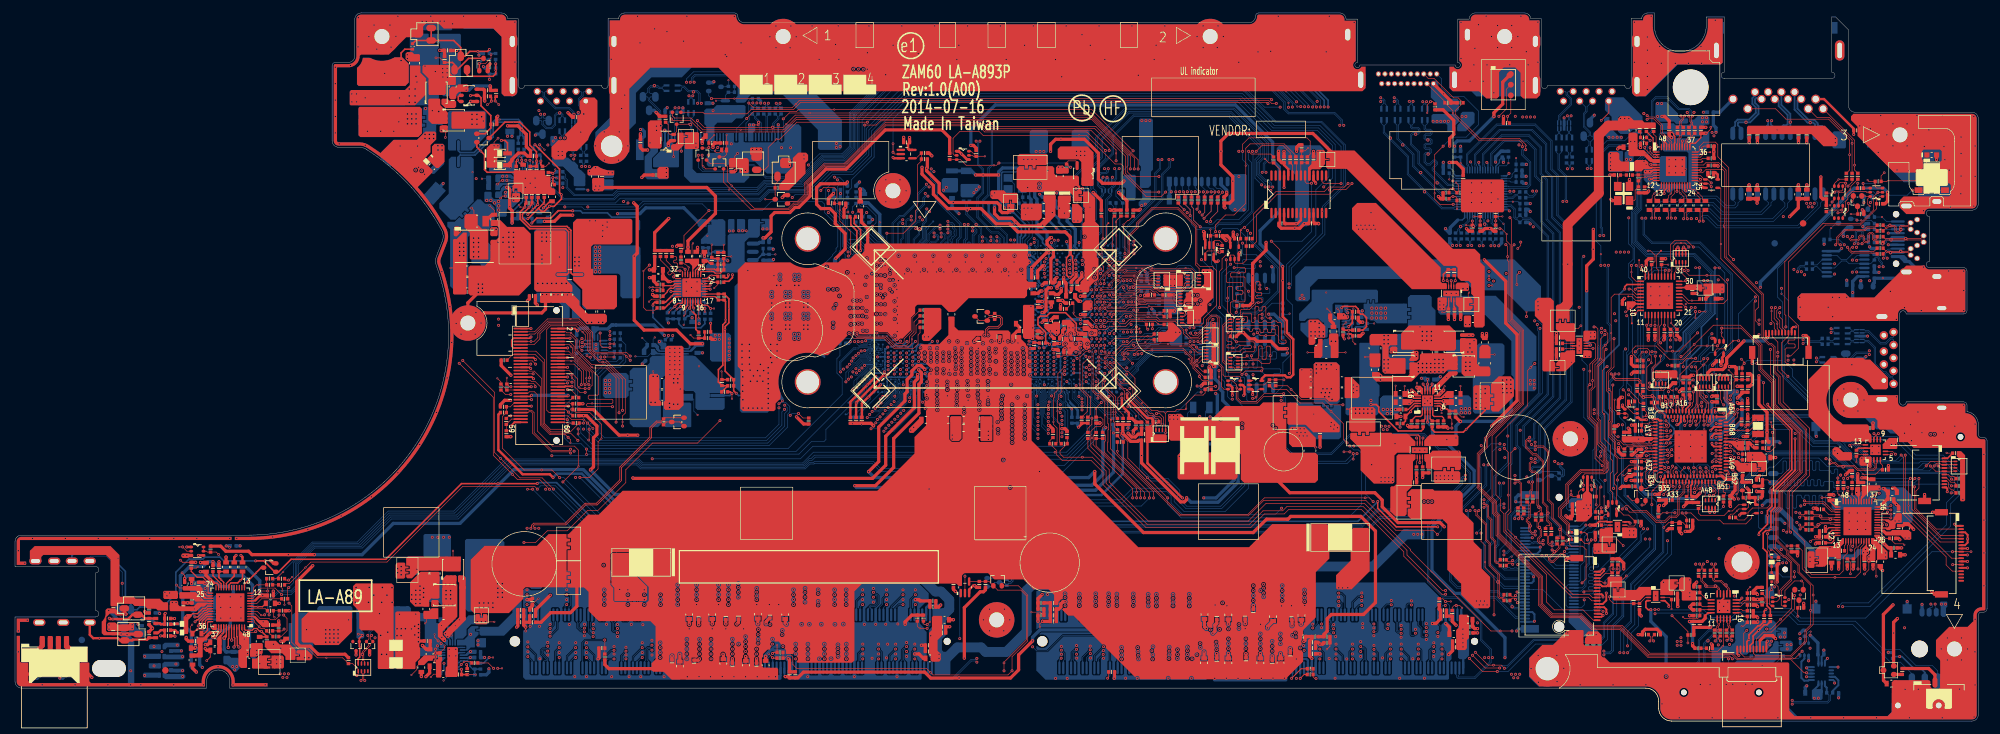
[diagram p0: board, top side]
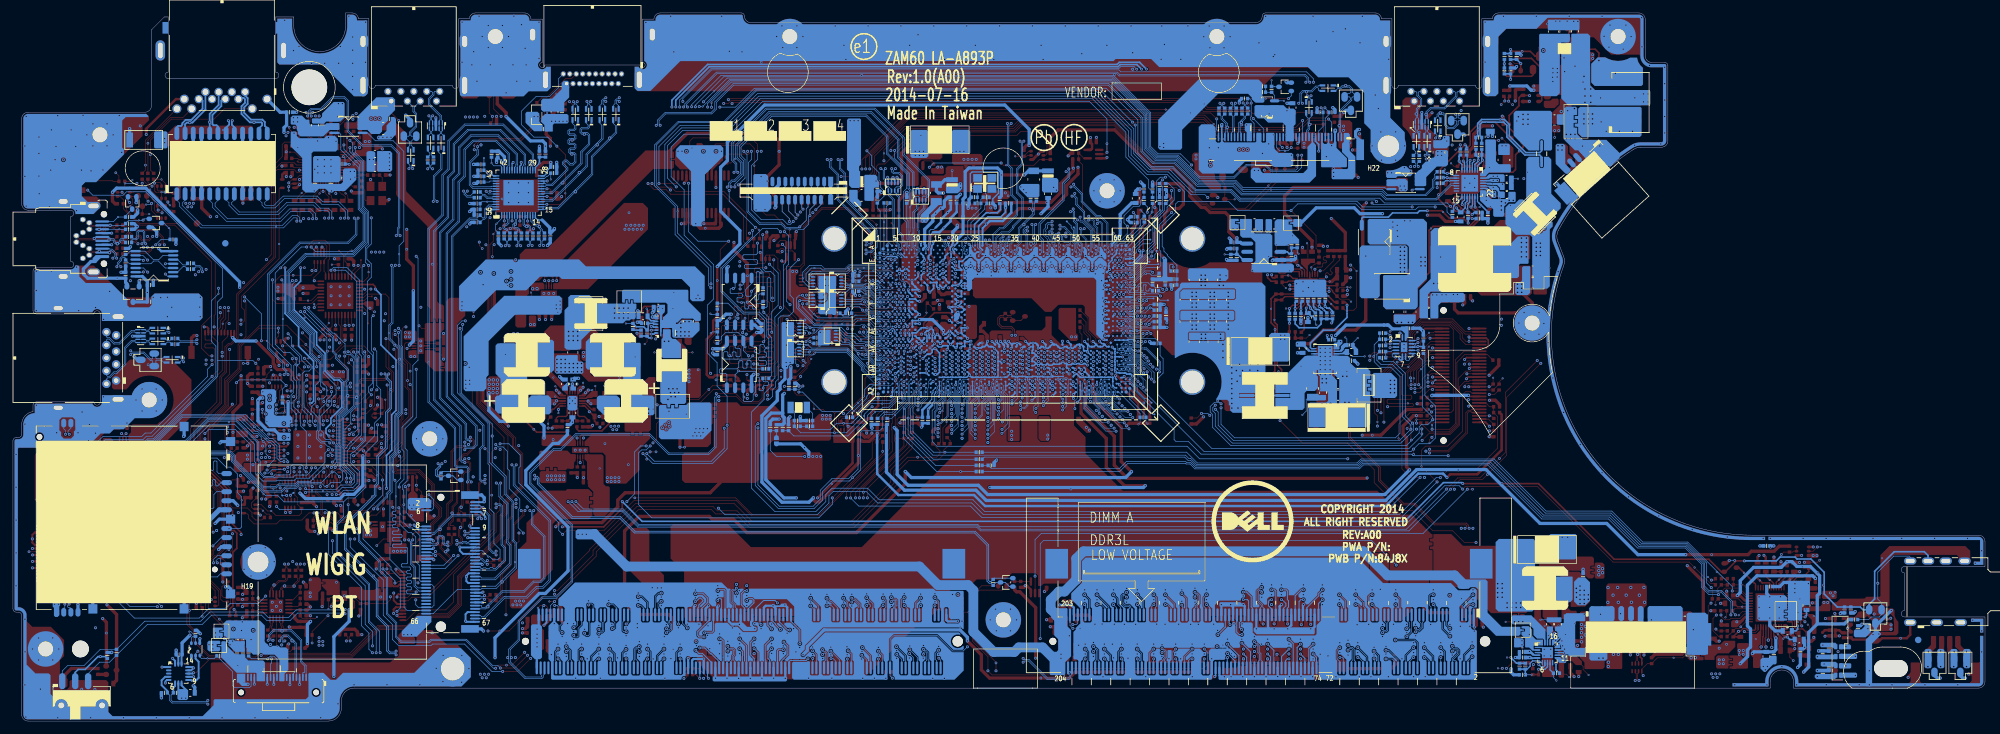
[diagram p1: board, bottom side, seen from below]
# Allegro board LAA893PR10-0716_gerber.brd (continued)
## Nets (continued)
CHARGER_SMBDAT: PT1.1(TP-1) PU700.11 RPE6.2 UE2.A47
CHG_BTS: PR712.1 PU700.25
CHG_BTS_C: PC712.1 PR712.2
CHG_LGATE: PQ705.6 PU700.23
CHG_SNUB: PC721.1 PR726.1
CHG_SW: PC712.2 PL701.2 PQ705.7 PR726.2 PU700.27
CHG_UGATE: PQ705.1 PU700.26
CLK_BIASREF: RC69.1 UC1.C26
CLK_PCI_LPDEBUG: CC13.2 JLPDE1.10 RC67.2
CLK_PCI_MEC: CC12.2 RC74.2 RE66.1 UE2.A29
CLK_PCIE_LAN: UC1.B42 UL1.44
CLK_PCIE_LAN#: UC1.C41 UL1.45
CLK_PCIE_MMI: UC1.C42 UR1.3
CLK_PCIE_MMI#: UC1.C43 UR1.2
CLK_PCIE_WIGIG: JNGFF1.63 UC1.B39
CLK_PCIE_WIGIG#: JNGFF1.65 UC1.A39
CLK_PCIE_WLAN: JNGFF1.39 UC1.C37
CLK_PCIE_WLAN#: JNGFF1.41 UC1.B38
CLK_TP_SIO: CZ31.1 JKBTP1.3 RZ19.2 UE2.A37
CLKRUN#: RPC15.3 UC1.V5 UE2.A32
CONTACTLESS_DET#: RPC6.5 UC1.U6
CORE_BOOT: PC504.2 PU501.7
CORE_BOOT_C: PC504.1 PR517.1
CORE_BOOT_R: PR517.2 PU501.6
CORE_SNUB: PC508.1 PR522.2
CORE_SW: PL500.4 PR522.1 PU501.4
CORE_SW_CSP: PL500.3 PR512.1
CPPE#: RC160.2 UC1.J1
CPU_DPB_AUX: CV512.2 RPC20.2 UC1.B5
CPU_DPB_AUX#: CV513.2 RPC20.1 UC1.C5
CPU_DPB_CTRLCLK: RPC2.2 UC1.B9 UV502.12
CPU_DPB_CTRLDAT: RPC2.1 UC1.C9 UV502.9
CPU_DPC_AUX: CV79.1 RPC20.3 UC1.A6
CPU_DPC_AUX#: CV80.1 RPC20.4 UC1.B6
CPU_DPC_AUX#_C: CV80.2 UV7.51
CPU_DPC_AUX_C: CV79.2 UV7.52
CPU_DPC_CTRLCLK: RPC2.3 UC1.D9 UV7.50
CPU_DPC_CTRLDAT: RPC2.4 UC1.D11 UV7.49
CPU_PWR_DEBUG#: JXDP1.45 RC197.2 RC198.1 UC1.H59
CPU_SEL: RC163.2 RC306.1 UC1.E4
CPU_XDP_PRDY#: JXDP1.5 UC1.J62
CPU_XDP_PREQ#: JXDP1.3 RC126.2 UC1.K62
CPU_XDP_TCLK: JXDP1.57 RC112.1 RC119.1 RC128.2 UC1.E60
CPU_XDP_TDI: RC125.2 UC1.F63 UC7.6
CPU_XDP_TDO: RC127.2 UC1.F62 UC7.3
CPU_XDP_TMS: RC124.2 UC1.E61 UC7.8
CPU_XDP_TRST#: RC109.1 RC129.2 UC1.E59 UC7.11
CPUSB#: RPC4.6 UC1.K3
CS_1.35V: PR201.2 PU200.13
CSN1: PC502.2 PC513.2 PL500.2 PR514.2 PR515.2 PU500.18
CSP1: PC502.1 PC513.1 PH501.1 PR512.2 PR514.1 PU500.17
CSSN_1: PR701.2 PR703.2 PR705.2
CSSP_1: PR701.3 PR703.1 PR704.2
DAT_TP_SIO: CZ30.1 JKBTP1.4 RZ18.2 UE2.B40
DC_TEST_A3_B3: UC1.A3 UC1.B3
DC_TEST_A4: RC192.1 UC1.A4
DC_TEST_A60: RC193.1 UC1.A60
DC_TEST_A61_B61: UC1.A61 UC1.B61
DC_TEST_A62: RC193.2 UC1.A62
DC_TEST_AV1: RC194.1 UC1.AV1
DC_TEST_AW1: RC194.2 UC1.AW1
DC_TEST_AW63: RC195.1 UC1.AW63
DC_TEST_AY2_AW2: UC1.AW2 UC1.AY2
DC_TEST_AY3_AW3: UC1.AW3 UC1.AY3
DC_TEST_AY60: RC195.2 UC1.AY60
DC_TEST_AY61_AW61: UC1.AW61 UC1.AY61
DC_TEST_AY62_AW62: UC1.AW62 UC1.AY62
DC_TEST_B62_B63: UC1.B62 UC1.B63
DC_TEST_C1_C2: UC1.C1 UC1.C2
DDI1_LANE_N0: CV508.2 UC1.C54
DDI1_LANE_N1: CV506.2 UC1.B58
DDI1_LANE_N2: CV504.2 UC1.B55
DDI1_LANE_N3: CV502.2 UC1.A57
DDI1_LANE_P0: CV507.2 UC1.C55
DDI1_LANE_P1: CV505.2 UC1.C58
DDI1_LANE_P2: CV503.2 UC1.A55
DDI1_LANE_P3: CV501.2 UC1.B57
DDI2_LANE_N0: CV72.1 UC1.C51
DDI2_LANE_N0_C: CV72.2 UV7.4
DDI2_LANE_N1: CV74.1 UC1.C53
DDI2_LANE_N1_C: CV74.2 UV7.7
DDI2_LANE_N2: CV76.1 UC1.C49
DDI2_LANE_N2_C: CV76.2 UV7.10
DDI2_LANE_N3: CV78.1 UC1.A53
DDI2_LANE_N3_C: CV78.2 UV7.13
DDI2_LANE_P0: CV71.1 UC1.C50
DDI2_LANE_P0_C: CV71.2 UV7.3
DDI2_LANE_P1: CV73.1 UC1.B54
DDI2_LANE_P1_C: CV73.2 UV7.6
DDI2_LANE_P2: CV75.1 UC1.B50
DDI2_LANE_P2_C: CV75.2 UV7.9
DDI2_LANE_P3: CV77.1 UC1.B53
DDI2_LANE_P3_C: CV77.2 UV7.12
DDR3_DRAMRST#: CD6.1 CD35.1 JDIMM1.30 JDIMM2.30 RD2.2 UC1.AV15
DDR_A_BS0: JDIMM1.109 UC1.AU35
DDR_A_BS1: JDIMM1.108 UC1.AV35
DDR_A_BS2: JDIMM1.79 UC1.AY41
DDR_A_CAS#: JDIMM1.115 UC1.AU34
DDR_A_D0: JDIMM1.129 UC1.AH63
DDR_A_D1: JDIMM1.131 UC1.AH62
DDR_A_D2: JDIMM1.141 UC1.AK63
DDR_A_D3: JDIMM1.140 UC1.AK62
DDR_A_D4: JDIMM1.132 UC1.AH61
DDR_A_D5: JDIMM1.130 UC1.AH60
DDR_A_D6: JDIMM1.143 UC1.AK61
DDR_A_D7: JDIMM1.142 UC1.AK60
DDR_A_D8: JDIMM1.7 UC1.AM63
DDR_A_D9: JDIMM1.4 UC1.AM62
DDR_A_D10: JDIMM1.17 UC1.AP63
DDR_A_D11: JDIMM1.18 UC1.AP62
DDR_A_D12: JDIMM1.6 UC1.AM61
DDR_A_D13: JDIMM1.5 UC1.AM60
DDR_A_D14: JDIMM1.15 UC1.AP61
DDR_A_D15: JDIMM1.16 UC1.AP60
DDR_A_D16: JDIMM1.159 UC1.AP58
DDR_A_D17: JDIMM1.157 UC1.AR58
DDR_A_D18: JDIMM1.146 UC1.AM57
DDR_A_D19: JDIMM1.148 UC1.AK57
DDR_A_D20: JDIMM1.149 UC1.AL58
DDR_A_D21: JDIMM1.147 UC1.AK58
DDR_A_D22: JDIMM1.158 UC1.AR57
DDR_A_D23: JDIMM1.160 UC1.AN57
DDR_A_D24: JDIMM1.24 UC1.AP55
DDR_A_D25: JDIMM1.22 UC1.AR55
DDR_A_D26: JDIMM1.36 UC1.AM54
DDR_A_D27: JDIMM1.34 UC1.AK54
DDR_A_D28: JDIMM1.23 UC1.AL55
DDR_A_D29: JDIMM1.21 UC1.AK55
DDR_A_D30: JDIMM1.33 UC1.AR54
DDR_A_D31: JDIMM1.35 UC1.AN54
DDR_A_D32: JDIMM1.166 UC1.AY58
DDR_A_D33: JDIMM1.165 UC1.AW58
DDR_A_D34: JDIMM1.175 UC1.AY56
DDR_A_D35: JDIMM1.174 UC1.AW56
DDR_A_D36: JDIMM1.163 UC1.AV58
DDR_A_D37: JDIMM1.164 UC1.AU58
DDR_A_D38: JDIMM1.177 UC1.AV56
DDR_A_D39: JDIMM1.176 UC1.AU56
DDR_A_D40: JDIMM1.42 UC1.AY54
DDR_A_D41: JDIMM1.41 UC1.AW54
DDR_A_D42: JDIMM1.50 UC1.AY52
DDR_A_D43: JDIMM1.51 UC1.AW52
DDR_A_D44: JDIMM1.39 UC1.AV54
DDR_A_D45: JDIMM1.40 UC1.AU54
DDR_A_D46: JDIMM1.52 UC1.AV52
DDR_A_D47: JDIMM1.53 UC1.AU52
DDR_A_D48: JDIMM1.69 UC1.AK40
DDR_A_D49: JDIMM1.67 UC1.AK42
DDR_A_D50: JDIMM1.59 UC1.AM43
DDR_A_D51: JDIMM1.57 UC1.AM45
DDR_A_D52: JDIMM1.56 UC1.AK45
DDR_A_D53: JDIMM1.58 UC1.AK43
DDR_A_D54: JDIMM1.68 UC1.AM40
DDR_A_D55: JDIMM1.70 UC1.AM42
DDR_A_D56: JDIMM1.192 UC1.AM46
DDR_A_D57: JDIMM1.194 UC1.AK46
DDR_A_D58: JDIMM1.183 UC1.AM49
DDR_A_D59: JDIMM1.182 UC1.AK49
DDR_A_D60: JDIMM1.191 UC1.AM48
DDR_A_D61: JDIMM1.193 UC1.AK48
DDR_A_D62: JDIMM1.181 UC1.AM51
DDR_A_D63: JDIMM1.180 UC1.AK51
DDR_A_DQS0: JDIMM1.137 UC1.AJ62
DDR_A_DQS1: JDIMM1.12 UC1.AN61
DDR_A_DQS2: JDIMM1.154 UC1.AN58
DDR_A_DQS3: JDIMM1.29 UC1.AN55
DDR_A_DQS4: JDIMM1.171 UC1.AW57
DDR_A_DQS5: JDIMM1.47 UC1.AW53
DDR_A_DQS6: JDIMM1.64 UC1.AL42
DDR_A_DQS7: JDIMM1.188 UC1.AL49
DDR_A_DQS#0: JDIMM1.135 UC1.AJ61
DDR_A_DQS#1: JDIMM1.10 UC1.AN62
DDR_A_DQS#2: JDIMM1.152 UC1.AM58
DDR_A_DQS#3: JDIMM1.27 UC1.AM55
DDR_A_DQS#4: JDIMM1.169 UC1.AV57
DDR_A_DQS#5: JDIMM1.45 UC1.AV53
DDR_A_DQS#6: JDIMM1.62 UC1.AL43
DDR_A_DQS#7: JDIMM1.186 UC1.AL48
DDR_A_MA0: JDIMM1.98 UC1.AU36
DDR_A_MA1: JDIMM1.97 UC1.AY37
DDR_A_MA2: JDIMM1.96 UC1.AR38
DDR_A_MA3: JDIMM1.95 UC1.AP36
DDR_A_MA4: JDIMM1.92 UC1.AU39
DDR_A_MA5: JDIMM1.91 UC1.AR36
DDR_A_MA6: JDIMM1.90 UC1.AV40
DDR_A_MA7: JDIMM1.86 UC1.AW39
DDR_A_MA8: JDIMM1.89 UC1.AY39
DDR_A_MA9: JDIMM1.85 UC1.AU40
DDR_A_MA10: JDIMM1.107 UC1.AP35
DDR_A_MA11: JDIMM1.84 UC1.AW41
DDR_A_MA12: JDIMM1.83 UC1.AU41
DDR_A_MA13: JDIMM1.119 UC1.AR35
DDR_A_MA14: JDIMM1.80 UC1.AV42
DDR_A_MA15: JDIMM1.78 UC1.AU42
DDR_A_RAS#: JDIMM1.110 UC1.AY34
DDR_A_WE#: JDIMM1.113 UC1.AW34
DDR_B_BS0: JDIMM2.109 UC1.AL35
DDR_B_BS1: JDIMM2.108 UC1.AM36
DDR_B_BS2: JDIMM2.79 UC1.AU49
DDR_B_CAS#: JDIMM2.115 UC1.AM33
DDR_B_D0: JDIMM2.132 UC1.AY31
DDR_B_D1: JDIMM2.131 UC1.AW31
DDR_B_D2: JDIMM2.140 UC1.AY29
DDR_B_D3: JDIMM2.141 UC1.AW29
DDR_B_D4: JDIMM2.129 UC1.AV31
DDR_B_D5: JDIMM2.130 UC1.AU31
DDR_B_D6: JDIMM2.142 UC1.AV29
DDR_B_D7: JDIMM2.143 UC1.AU29
DDR_B_D8: JDIMM2.5 UC1.AY27
DDR_B_D9: JDIMM2.6 UC1.AW27
DDR_B_D10: JDIMM2.15 UC1.AY25
DDR_B_D11: JDIMM2.17 UC1.AW25
DDR_B_D12: JDIMM2.4 UC1.AV27
DDR_B_D13: JDIMM2.16 UC1.AU27
DDR_B_D14: JDIMM2.7 UC1.AV25
DDR_B_D15: JDIMM2.18 UC1.AU25
DDR_B_D16: JDIMM2.146 UC1.AM29
DDR_B_D17: JDIMM2.148 UC1.AK29
DDR_B_D18: JDIMM2.160 UC1.AL28
DDR_B_D19: JDIMM2.158 UC1.AK28
DDR_B_D20: JDIMM2.149 UC1.AR29
DDR_B_D21: JDIMM2.147 UC1.AN29
DDR_B_D22: JDIMM2.157 UC1.AR28
DDR_B_D23: JDIMM2.159 UC1.AP28
DDR_B_D24: JDIMM2.24 UC1.AN26
DDR_B_D25: JDIMM2.22 UC1.AR26
DDR_B_D26: JDIMM2.33 UC1.AR25
DDR_B_D27: JDIMM2.35 UC1.AP25
DDR_B_D28: JDIMM2.21 UC1.AK26
DDR_B_D29: JDIMM2.23 UC1.AM26
DDR_B_D30: JDIMM2.34 UC1.AK25
DDR_B_D31: JDIMM2.36 UC1.AL25
DDR_B_D32: JDIMM2.166 UC1.AY23
DDR_B_D33: JDIMM2.165 UC1.AW23
DDR_B_D34: JDIMM2.174 UC1.AY21
DDR_B_D35: JDIMM2.175 UC1.AW21
DDR_B_D36: JDIMM2.163 UC1.AV23
DDR_B_D37: JDIMM2.164 UC1.AU23
DDR_B_D38: JDIMM2.176 UC1.AV21
DDR_B_D39: JDIMM2.177 UC1.AU21
DDR_B_D40: JDIMM2.39 UC1.AY19
DDR_B_D41: JDIMM2.41 UC1.AW19
DDR_B_D42: JDIMM2.53 UC1.AY17
DDR_B_D43: JDIMM2.52 UC1.AW17
DDR_B_D44: JDIMM2.42 UC1.AV19
DDR_B_D45: JDIMM2.40 UC1.AU19
DDR_B_D46: JDIMM2.51 UC1.AV17
DDR_B_D47: JDIMM2.50 UC1.AU17
DDR_B_D48: JDIMM2.191 UC1.AR21
DDR_B_D49: JDIMM2.183 UC1.AR22
DDR_B_D50: JDIMM2.194 UC1.AL21
DDR_B_D51: JDIMM2.180 UC1.AM22
DDR_B_D52: JDIMM2.181 UC1.AN22
DDR_B_D53: JDIMM2.193 UC1.AP21
DDR_B_D54: JDIMM2.192 UC1.AK21
DDR_B_D55: JDIMM2.182 UC1.AK22
DDR_B_D56: JDIMM2.57 UC1.AN20
DDR_B_D57: JDIMM2.59 UC1.AR20
DDR_B_D58: JDIMM2.69 UC1.AK18
DDR_B_D59: JDIMM2.67 UC1.AL18
DDR_B_D60: JDIMM2.58 UC1.AK20
DDR_B_D61: JDIMM2.56 UC1.AM20
DDR_B_D62: JDIMM2.70 UC1.AR18
DDR_B_D63: JDIMM2.68 UC1.AP18
DDR_B_DQS0: JDIMM2.137 UC1.AV30
DDR_B_DQS1: JDIMM2.12 UC1.AW26
DDR_B_DQS2: JDIMM2.154 UC1.AM28
DDR_B_DQS3: JDIMM2.29 UC1.AM25
DDR_B_DQS4: JDIMM2.171 UC1.AV22
DDR_B_DQS5: JDIMM2.47 UC1.AW18
DDR_B_DQS6: JDIMM2.188 UC1.AM21
DDR_B_DQS7: JDIMM2.64 UC1.AM18
DDR_B_DQS#0: JDIMM2.135 UC1.AW30
DDR_B_DQS#1: JDIMM2.10 UC1.AV26
DDR_B_DQS#2: JDIMM2.152 UC1.AN28
DDR_B_DQS#3: JDIMM2.27 UC1.AN25
DDR_B_DQS#4: JDIMM2.169 UC1.AW22
DDR_B_DQS#5: JDIMM2.45 UC1.AV18
DDR_B_DQS#6: JDIMM2.186 UC1.AN21
DDR_B_DQS#7: JDIMM2.62 UC1.AN18
DDR_B_MA0: JDIMM2.98 UC1.AP40
DDR_B_MA1: JDIMM2.97 UC1.AR40
DDR_B_MA2: JDIMM2.96 UC1.AP42
DDR_B_MA3: JDIMM2.95 UC1.AR42
DDR_B_MA4: JDIMM2.92 UC1.AR45
DDR_B_MA5: JDIMM2.91 UC1.AP45
DDR_B_MA6: JDIMM2.90 UC1.AW46
DDR_B_MA7: JDIMM2.86 UC1.AY46
DDR_B_MA8: JDIMM2.89 UC1.AY47
DDR_B_MA9: JDIMM2.85 UC1.AU46
DDR_B_MA10: JDIMM2.107 UC1.AK36
DDR_B_MA11: JDIMM2.84 UC1.AV47
DDR_B_MA12: JDIMM2.83 UC1.AU47
DDR_B_MA13: JDIMM2.119 UC1.AK33
DDR_B_MA14: JDIMM2.80 UC1.AR46
DDR_B_MA15: JDIMM2.78 UC1.AP46
DDR_B_RAS#: JDIMM2.110 UC1.AM35
DDR_B_WE#: JDIMM2.113 UC1.AK35
DDR_CKE0_DIMMA: JDIMM1.73 UC1.AU43
DDR_CKE1_DIMMA: JDIMM1.74 UC1.AW43
DDR_CKE2_DIMMB: JDIMM2.73 UC1.AY49
DDR_CKE3_DIMMB: JDIMM2.74 UC1.AU50
DDR_CS0_DIMMA#: JDIMM1.114 UC1.AP33
DDR_CS1_DIMMA#: JDIMM1.121 UC1.AR32
DDR_CS2_DIMMB#: JDIMM2.114 UC1.AM32
DDR_CS3_DIMMB#: JDIMM2.121 UC1.AK32
DDR_PG_CTRL: UC1.AV61 UD1.2
DDR_XDP_WAN_SMBCLK: JDIMM1.202 JDIMM2.202 JXDP1.53 QC1.1 RN4.2 UN1.4
DDR_XDP_WAN_SMBDAT: JDIMM1.200 JDIMM2.200 JXDP1.51 QC1.4 RN3.2 UN1.6
DEW1: RN20.2 RN21.2 UN2.16
DEW2: RN18.2 RN19.2 UN2.6
DGPU_PWROK: RPC18.8 UC1.P4
DH_1.35V: PQ200.4 PU200.17
DIMM_DET: RC302.2 RC303.1 UC1.U4
DISP_ON: DV2.1 JEDP1.22 RV2.1
DL_1.35V: PQ201.4 PU200.15
DMIC0: CA6.1 JEDP1.7 UA1.47
DMIC1: MIC1.5 UA1.4
DMIC_CLK0: CA5.1 CA54.1 JEDP1.9 RA14.2
DMIC_CLK1: CA30.1 MIC1.4 RA40.2
DMIC_CLK_L: RA14.1 RA40.1 UA1.2
DOCK_PWR_SW#: RPE5.3 UE2.A63
DPB_HPD: QV501.3 UC1.C8
DPB_MB_P14: JMDP1.6 RV503.2
DPC_HPD: RC142.2 UC1.A8 UV7.5
DSWODVREN: RC78.1 UC1.AW7
EC_32KHZ_MEC5085: UE2.B2 UZ11.2
EDP_BIA_PWM: DV1.3 UC1.B8
EDP_COMP: RC133.2 UC1.D20
EDP_CPU_AUX: CV2.1 UC1.B45
EDP_CPU_AUX#: CV1.1 UC1.A45
EDP_CPU_AUX#_C: CV1.2 JEDP1.33
EDP_CPU_AUX_C: CV2.2 JEDP1.34
EDP_CPU_HPD: JEDP1.26 RC141.2 UC1.D6
EDP_CPU_LANE_N0: CV4.1 UC1.C45
EDP_CPU_LANE_N0_C: CV4.2 JEDP1.36
EDP_CPU_LANE_N1: CV6.1 UC1.A47
EDP_CPU_LANE_N1_C: CV6.2 JEDP1.38
EDP_CPU_LANE_P0: CV3.1 UC1.B46
EDP_CPU_LANE_P0_C: CV3.2 JEDP1.35
EDP_CPU_LANE_P1: CV5.1 UC1.B47
EDP_CPU_LANE_P1_C: CV5.2 JEDP1.37
EN: PC119.1 PR113.2 PU100.6 PU100.20
EN_+V1.05SP: PR303.1 PU300.1 RZ41.2 RZ42.2
EN_INVPWR: QV2.2 RE55.2 UE2.A25
EN_LCDPWR: DV3.1 RV3.2 UV24.3
ENVDD_PCH: DV3.3 RC139.2 UC1.C6 UE2.A7
EXPRESS_DET#: T97.1(TP-1) UE3.40
EXPRESS_SMBCLK: RPE3.2 UE2.B4
EXPRESS_SMBDATA: RPE3.1 UE2.A3
F-IMAX: PR503.2 PR508.1 PU500.10
FAN1_PWM: JFAN1.2 RE48.2 UE2.A24
FAN1_TACH: JFAN1.3 RE51.2 UE2.B22
FB_+V1.05SP: PR307.2 PR309.2 PR310.1 PU300.4
FFS_INT2: QN1.2 RC158.2 UC1.G2 UN1.9
FFS_INT2_Q: JSATA1.19 QN1.3 RN1.2
FWP#: RE81.2 RE82.2 UE2.B65
GC6_EVENT#_Q: RPC16.8 UC1.R6
GFB: PR532.2 PU500.23
GPU_GC6_FB_EN: RPC3.8 UC1.L6
GPU_SMBCLK: RPE3.4 UE2.B49
GPU_SMBDAT: RPE3.3 UE2.B48
H_CATERR#: RC114.2 UC1.K61
H_CPU_SVIDALRT#: RC207.1 UC1.L62
H_CPUPWRGD: CC83.1 RC103.1 RC123.1 UC1.C61
H_PROCHOT#: CC20.1 PC514.1 PR534.2 PR717.1 RC116.2 RC121.1 UE2.A46
H_PROCHOT#_R: RC121.2 UC1.K63
H_THERMTRIP#: QE4.3 RC25.2 RC161.1
H_THERMTRIP#_R: RC161.2 UC1.D60
H_VCCST_PWRGD: CC24.1 RC102.1 RC202.1 UC1.B59 UC8.4
H_VCCST_PWRGD_XDP: JXDP1.39 RC102.2 RC103.2
H_VR_EN: PR536.2 RC201.2 UC1.F60
H_VR_READY: PR539.2 RC199.2 RC201.1 UC1.C59
HDD_A_EQ: RN12.1 RN13.2 UN2.17
HDD_A_EQ2: RN24.2 RN25.2 UN2.18
HDD_A_PRE: RN8.1 RN9.2 UN2.9
HDD_B_EQ: RN14.2 RN16.2 UN2.19
HDD_B_EQ2: RN22.2 RN23.2 UN2.13
HDD_B_PRE: RN10.1 RN11.2 UN2.8
HDD_DET#: JSATA1.13 RPC18.6 UC1.U1
HDD_DEVSLP: JSATA1.11 RN5.2 UC1.L2
HDD_FALL_INT: RPC9.5 UC1.N4 UN1.11
HDMI_CEC: JHDMI1.13 RV8.2
HDMI_CLK_AUX: JHDMI1.15 RV7.1 UV7.48
HDMI_DAT_AUX#: JHDMI1.16 RV9.1 UV7.47
HDMI_HPD: JHDMI1.19 UV7.17
HDMI_LANE_N0: LV12.1 UV7.18
HDMI_LANE_N1: LV10.1 UV7.21
HDMI_LANE_N2: LV6.1 UV7.24
HDMI_LANE_N3: LV3.1 UV7.15
HDMI_LANE_P0: LV12.4 UV7.19
HDMI_LANE_P1: LV10.4 UV7.22
HDMI_LANE_P2: LV6.4 UV7.25
HDMI_LANE_P3: LV3.4 UV7.16
HOST_ALERT1_R_N: RC179.2 UC1.AD6
HOST_DEBUG_TX: JDEG1.8 RE73.2 UE2.B44
I_ADP: PR716.1 UE2.A12
I_BATT: PR718.1 RE64.2
I_SYS: PR720.1 UE2.A57
ILIM_SEL: RI13.1 UI3.4
ILMT_1.05V: PR306.2 PR308.1 PU300.3
IMON: PC500.1 PR501.1 PU500.13
INT_SPK_L+: CA22.1 LA6.1 UA1.42
INT_SPK_L-: CA23.1 LA7.1 UA1.43
INT_SPK_R+: CA19.1 LA8.1 UA1.45
INT_SPK_R-: CA24.1 LA9.1 UA1.44
INT_SPKR_L+: DA6.2 JSPK1.1 LA6.2
INT_SPKR_L-: DA6.3 JSPK1.2 LA7.2
INT_SPKR_R+: DA7.2 JSPK1.3 LA8.2
INT_SPKR_R-: DA7.3 JSPK1.4 LA9.2
INTRUDER#: RC9.2 UC1.AU6
IO_LDOSEL: RR6.2 RR8.1 UR1.18
IRQ_SERIRQ: RPC15.2 UC1.T4 UE2.A28
JTAG_CLK: JDEG1.4 RPE7.3 UE2.B56
JTAG_RST#: CE30.1 JTAG1.1 RE63.2 RE65.1 UE2.B47
JTAG_TDI: JDEG1.2 RPE7.1 UE2.A51
JTAG_TDO: JDEG1.5 RPE7.4 UE2.B55
JTAG_TMS: JDEG1.3 RPE7.2 UE2.A53
KB_DET#: JKBTP1.16 RPC19.1 UC1.AT3
LAN_ACTLED_YEL#: QL1.6 RL14.1
LAN_ACTLED_YEL_R#: JLOM1.10 RL14.2
LAN_DISABLE#_R: RL5.2 RL7.2 RL9.1 UE3.1 UL1.3
LAN_TEST_EN: RL12.1 UL1.30
LAN_TX0+: RL21.1 UL1.13
LAN_TX0+L: RL21.2 TL1.12
LAN_TX0-: RL22.1 UL1.14
LAN_TX0-L: RL22.2 TL1.11
LAN_TX1+: RL23.1 UL1.17
LAN_TX1+L: RL23.2 TL1.8
LAN_TX1-: RL24.1 UL1.18
LAN_TX1-L: RL24.2 TL1.7
LAN_TX2+: RL25.1 UL1.20
LAN_TX2+L: RL25.2 TL1.6
LAN_TX2-: RL26.1 UL1.21
LAN_TX2-L: RL26.2 TL1.5
LAN_TX3+: RL27.1 UL1.23
LAN_TX3+L: RL27.2 TL1.2
LAN_TX3-: RL28.1 UL1.24
LAN_TX3-L: RL28.2 TL1.1
LAN_WAKE#: RC153.1 UC1.AN5 UE2.B27 UL1.2
LANCLK_REQ#: RL4.1 RPC6.6 UC1.AD1 UL1.48
LCD_CBL_DET#: JEDP1.40 RPC4.5 UC1.J3
LCD_TST: JEDP1.29 RE20.2 UE2.A38
LCD_VCC_TEST_EN: DV3.2 UE2.A39
LED_10_GRN#: QL2.6 RL19.1
LED_10_GRN_R#: JLOM1.11 RL19.2
LED_100_ORG#: QL1.3 RL20.1
LED_100_ORG_R#: JLOM1.13 RL20.2
LED_SATA_DIAG_OUT#: DZ4.1 UE3.15
LG_3V: PQ102.4 PU100.11
LG_5V: PQ103.4 PU100.15
LID_CL#: JLED1.7 RE26.1 UZ10.2
LID_CL_SIO#: CE8.1 RE25.2 RE26.2 UE2.A21
LOM_ACTLED_YEL#: QL1.1 UL1.26
LOM_SPD10LED_GRN#: QL2.1 RL30.2 UL1.25 UL2.2
LOM_SPD100LED_ORG#: QL1.4 RL29.2 UL1.27 UL2.1
LPC_LAD0: JLPDE1.3 UC1.AU14 UE2.A30
LPC_LAD1: JLPDE1.4 UC1.AW12 UE2.B32
LPC_LAD2: JLPDE1.5 UC1.AY12 UE2.A31
LPC_LAD3: JLPDE1.6 UC1.AW11 UE2.B33
LPC_LFRAME#: JLPDE1.7 UC1.AV12 UE2.B31
M_CLK_DDR0: JDIMM1.101 UC1.AV37
M_CLK_DDR1: JDIMM1.102 UC1.AY36
M_CLK_DDR2: JDIMM2.101 UC1.AN38
M_CLK_DDR3: JDIMM2.102 UC1.AL38
M_CLK_DDR#0: JDIMM1.103 UC1.AU37
M_CLK_DDR#1: JDIMM1.104 UC1.AW36
M_CLK_DDR#2: JDIMM2.103 UC1.AM38
M_CLK_DDR#3: JDIMM2.104 UC1.AK38
M_ODT0: JDIMM1.116 RD10.2
M_ODT1: JDIMM1.120 RD11.2
M_ODT2: JDIMM2.116 RD12.2
M_ODT3: JDIMM2.120 RD13.2
MASK_BASE_LEDS#: QZ7.5 UZ10.4
MASK_SATA_LED#: QZ3.5 UE3.23
MCARD_PCIE#_SATA: RE91.1 UE2.B8
MCARD_PCIE#_SATA_R: RE91.2 RPC6.7 UC1.AC1
MCP_TESTLOW1: RC240.1 UC1.C35
MCP_TESTLOW2: RC241.1 UC1.C34
MCP_TESTLOW3: RC242.1 UC1.AK8
MCP_TESTLOW4: RC243.1 UC1.AL8
MDP_AUX#_C: JMDP1.18 RV501.2 UV502.6 UV502.8
MDP_AUX_C: JMDP1.16 RV502.2 UV502.3 UV502.11
MDP_CA_DET: JMDP1.4 QV502.2 RV504.1 UV502.1 UV502.4
MDP_CA_DET#: QV502.1 RV507.2 UV502.10 UV502.13
MDP_HPD: JMDP1.2 QV501.1 RV505.2
MDP_LANE_N0_C: CV508.1 JMDP1.5
MDP_LANE_N1_C: CV506.1 JMDP1.11
MDP_LANE_N2_C: CV504.1 JMDP1.17
MDP_LANE_N3_C: CV502.1 JMDP1.12
MDP_LANE_P0_C: CV507.1 JMDP1.3
MDP_LANE_P1_C: CV505.1 JMDP1.9
MDP_LANE_P2_C: CV503.1 JMDP1.15
MDP_LANE_P3_C: CV501.1 JMDP1.10
ME_FWP: RC11.1 RC301.1 SW1.3
ME_FWP_EC: RC301.2 SW1.1 UE2.B46
ME_RESET#: RC80.1 RC95.2 UC4.2
ME_SUS_PWR_ACK: RC79.2 UC1.AV4 UE2.A8
MEC_XTAL1: CE28.1 UE2.A61 YE1.1
MEC_XTAL2: CE29.1 RE61.2 YE1.2
MEC_XTAL2_R: RE61.1 UE2.A62
MEDIACARD_IRQ#: RPC5.6 UC1.AB6 UR1.16
MEDIACARD_PWREN: RR15.2 UR1.14
MEDIACARD_RST#: RPC5.7 UC1.AG6
MEM_SMBCLK: QC1.6 RPC14.1 UC1.AP2
MEM_SMBDATA: QC1.3 RPC14.2 UC1.AH1
MIC1_L: CA43.1 UA1.19
MIC1_R: CA44.1 UA1.20
MMICLK_REQ#: RPC18.7 UC1.U2 UR1.17
MPCIE_RST#: RPC18.5 UC1.V1
MPHYP_PWR_EN: QZ10.2 RC155.1 RC171.1 UC1.Y2
MPHYP_PWR_EN#: QZ10.5 QZ10.6 RZ16.2
MSCLK: JDEG1.6 RE72.2 UE2.B43
MSDATA: JDEG1.7 RE75.2 RE86.2 UE2.A40
NB_LAN_TX0+: JLOM1.1 TL1.13
NB_LAN_TX0-: JLOM1.2 TL1.14
NB_LAN_TX1+: JLOM1.3 TL1.17
NB_LAN_TX1-: JLOM1.6 TL1.18
NB_LAN_TX2+: JLOM1.4 TL1.19
NB_LAN_TX2-: JLOM1.5 TL1.20
NB_LAN_TX3+: JLOM1.7 TL1.23
NB_LAN_TX3-: JLOM1.8 TL1.24
NB_PSID: PJPDC1.5 PL3.2
NFC_IRQ: RC175.1 UC1.AN3
O-USR: PR504.2 PR509.1 PU500.9
OCP-I: PR501.2 PR506.1 PR524.2 PU500.12
PANEL_BKEN_EC: DV2.2 UE3.5
PANEL_BKLEN: DV2.3 UC1.A9
PBAT_PRES#: PR2.2 PR728.1 PRP2.1 UE2.A49
PBAT_PRES#_C: PBATT1.6 PD2.2 PRP2.8
PBAT_SMBCLK: PRP2.3 RE43.2 UE2.A56
PBAT_SMBCLK_C: PBATT1.4 PD1.2 PRP2.6
PBAT_SMBDAT: PRP2.2 RE37.2 UE2.B59
PBAT_SMBDAT_C: PBATT1.5 PD1.3 PRP2.7
PBATT+_C: PBATT1.1 PBATT1.2 PBATT1.3 PC3.1 PL1.1 PL2.1
PCH_ALW_ON: RPE10.4 UE2.A34 UZ2.3
PCH_AZ_BITCLK: RC23.2 UC1.AW8
PCH_AZ_CODEC_BITCLK: CC5.1 RA17.1 RC23.1 UA1.6
PCH_AZ_CODEC_RST#: RC22.1 UA1.11
PCH_AZ_CODEC_SDIN0: RA9.1 UC1.AY10
PCH_AZ_CODEC_SDOUT: RC19.1 UA1.5
PCH_AZ_CODEC_SYNC: RC20.1 UA1.10
PCH_AZ_RST#: RC22.2 UC1.AU8
PCH_AZ_SDIN0_R: RA9.2 UA1.8
PCH_AZ_SDOUT: RC11.2 RC19.2 UC1.AU11
PCH_AZ_SYNC: RC20.2 UC1.AV11
PCH_BATLOW#: RPC1.8 UC1.AN4
PCH_CL_CLK1: JNGFF1.34 UC1.AF2
PCH_CL_DATA1: JNGFF1.32 UC1.AD2
PCH_CL_RST1#: JNGFF1.30 UC1.AF4
PCH_DPWROK: UC1.AV5 UE2.A36
PCH_GPIO4: RPC8.8 UC1.F2
PCH_GPIO5: RPC8.7 UC1.F3
PCH_GPIO6: RPC8.5 UC1.G4
PCH_GPIO7: RPC8.6 UC1.F1
PCH_GPIO9: RPC10.7 UC1.AM3
PCH_GPIO10: T27.1(TP-1) UC1.AM2
PCH_GPIO14: T21.1(TP-1) UC1.AH4
PCH_GPIO16: RPC6.8 UC1.Y1
PCH_GPIO19: RC66.2 UC1.Y5
PCH_GPIO23: RC68.2 UC1.T2
PCH_GPIO44: RPC19.4 UC1.AK4
PCH_GPIO46: RPC10.5 UC1.AG3
PCH_GPIO49: T22.1(TP-1) UC1.Y3
PCH_GPIO52: RPC3.6 UC1.L1
PCH_GPIO53: RC140.1 UC1.L4
PCH_GPIO57: RPC10.8 UC1.AP1
PCH_GPIO59: RC245.1 UC1.AT5
PCH_GPIO66: RC176.2 UC1.D3
PCH_GPIO68: RC164.2 UC1.C3
PCH_GPIO69: RPC16.6 UC1.E2
PCH_GPIO73: RPC7.8 UC1.AU4
PCH_GPIO76: RPC17.5 UC1.P1
PCH_GPIO80: RPC17.7 UC1.N2
PCH_GPIO85: RPC4.8 UC1.N6
PCH_GPIO87: RPC16.7 UC1.R7
PCH_INTVRMEN: RC1.2 UC1.AV7
PCH_JTAG_JTAGX: RC18.1 RC112.2 RC115.2 UC1.AE63
PCH_JTAG_TCK: JXDP1.55 RC21.1 RC119.2 UC1.AE62
PCH_JTAG_TDI: JXDP1.56 RC14.1 RC99.1 UC1.AD61
PCH_JTAG_TDO: RC15.1 RC98.1 RC118.2 UC1.AE61
PCH_JTAG_TMS: JXDP1.58 RC16.1 UC1.AD62 UC7.9
PCH_JTAG_TRST#: RC109.2 UC1.AU62
PCH_OPI_COMP: RC178.1 UC1.AW15
PCH_PCIE_RCOMP: RC149.2 UC1.A27
PCH_PCIE_WAKE#: RE274.2 RPC1.5 UC1.AJ5 UE2.A44
PCH_PLTRST#: RC88.2 RC89.2 UC1.AG7 UC5.1 UC5.2
PCH_PLTRST#_EC: JLPDE1.8 JNGFF1.44 JNGFF1.58 RC106.1 RC304.1 UC5.4 UE2.B30 UZ1.16
PCH_RSMRST#: RE88.1 UE2.A45 UZ6.1
PCH_RSMRST#_Q: RC91.2 UC1.AW6 UZ6.4
PCH_RTCRST#: CC4.2 CMOS1.2 JAPS1.9 RC8.2 UC1.AU7
PCH_RTCX1: RC4.2 RC7.1 UC1.AW5
PCH_RTCX1_R: CC1.2 RC4.1 YC1.1
PCH_RTCX2: CC2.2 RC7.2 UC1.AY5 YC1.2
PCH_SMB_ALERT#: RPC19.2 UC1.AN2
PCH_SPI_CLK: JSPI1.8 RC227.2 RZ26.1 UC1.AA3
PCH_SPI_CS0#: JSPI1.10 RC228.2 UC1.Y7
PCH_SPI_CS1#: JSPI1.2 RC224.2 UC1.Y4
PCH_SPI_CS2#: RZ17.1 UC1.AC2
PCH_SPI_CS2#_R: RZ17.2 UZ1.22
PCH_SPI_DIN: JSPI1.6 RC226.2 RZ30.1 UC1.AA4
PCH_SPI_DO: JSPI1.4 RC225.2 RZ29.1 UC1.AA2
PCH_SPI_DO2: JSPI1.12 RC229.2 UC1.Y6
PCH_SPI_DO3: JSPI1.14 RC230.2 UC1.AF1
PCI_CLK_LPC_0: RC74.1 UC1.AN15
PCI_CLK_LPC_1: RC67.1 UC1.AP15
PCIE_PRX_GLANTX_N3: CL2.2 UC1.G11
PCIE_PRX_GLANTX_N3_C: CL2.1 UL1.39
PCIE_PRX_GLANTX_P3: CL1.2 UC1.F11
PCIE_PRX_GLANTX_P3_C: CL1.1 UL1.38
PCIE_PRX_MMITX_N1: CR27.1 UC1.G17
PCIE_PRX_MMITX_N1_C: CR27.2 UR1.8
PCIE_PRX_MMITX_P1: CR26.1 UC1.F17
PCIE_PRX_MMITX_P1_C: CR26.2 UR1.7
PCIE_PRX_WIGIGTX_N5: JNGFF1.59 UC1.F10
PCIE_PRX_WIGIGTX_P5: JNGFF1.57 UC1.E10
PCIE_PRX_WLANTX_N4: JNGFF1.35 UC1.F13
PCIE_PRX_WLANTX_P4: JNGFF1.33 UC1.G13
PCIE_PTX_GLANRX_N3: CL6.1 UC1.C29
PCIE_PTX_GLANRX_N3_C: CL6.2 UL1.42
PCIE_PTX_GLANRX_P3: CL5.1 UC1.B30
PCIE_PTX_GLANRX_P3_C: CL5.2 UL1.41
PCIE_PTX_MMIRX_N1: CR25.1 UC1.C30
PCIE_PTX_MMIRX_N1_C: CR25.2 UR1.5
PCIE_PTX_MMIRX_P1: CR24.1 UC1.C31
PCIE_PTX_MMIRX_P1_C: CR24.2 UR1.6
PCIE_PTX_WIGIGRX_N5: CZ22.1 UC1.C23
PCIE_PTX_WIGIGRX_N5_C: CZ22.2 JNGFF1.53
PCIE_PTX_WIGIGRX_P5: CZ21.1 UC1.C22
PCIE_PTX_WIGIGRX_P5_C: CZ21.2 JNGFF1.51
PCIE_PTX_WLANRX_N4: CZ14.1 UC1.B29
PCIE_PTX_WLANRX_N4_C: CZ14.2 JNGFF1.29
PCIE_PTX_WLANRX_P4: CZ13.1 UC1.A29
PCIE_PTX_WLANRX_P4_C: CZ13.2 JNGFF1.27
PCIE_WAKE#: JNGFF1.47 JNGFF1.62 RE274.1 RE275.1
PCIE_WAKE#_R: RE35.2 RE275.2 UE3.18
PE_REXT: RR2.2 UR1.4
PECI_EC: RE60.2 UC1.N62
PECI_EC_R: RE60.1 UE2.A48
PGOOD_3V_5V: PR107.2 PR108.2 PU100.7
PLTRST_LAN#: RC89.1 UL1.36
PLTRST_MMI#: RC88.1 UR1.15
PM_APWROK: RC26.1 UE2.A9
PM_APWROK_L: RC26.2 RC27.2 UC6.2
PM_APWROK_R: UC1.AB5 UC6.4
PM_LANPHY_ENABLE: RC92.2 RL7.1 UC1.AM7
PM_TEST_RST: CC100.2 RC300.2 UC1.AC4
POA_WAKE#: RPE5.2 UE2.B68
POWER_SW#_MB: CE10.1 JAPS1.11 RE33.2 SW3.2 SW3.4
POWER_SW_IN#: CE12.1 RE31.2 RE33.1 UE2.B67
PROC_OPI_RCOMP: RC187.1 UC1.AY15
PROCHOT_GATE: RE83.2 UE3.26
PS8339B_DP_CFG0: RV51.2 RV52.1 UV7.44
PS8339B_DP_CFG1: RV54.2 RV61.1 UV7.29
PS8339B_IN_CA_DET: RV68.2 UV7.11
PS8339B_INPUT_EQ: RV58.2 RV65.1 UV7.8
PS8339B_MODE: RV57.2 RV63.1 UV7.53
PS8339B_MODE_SW: RV510.1 RV511.2 UV7.45
PS8339B_OUT_CA_DET: RV67.2 UV7.42
PS8339B_TMDS_DDCBUF: RV60.2 RV66.1 UV7.2
PS8339B_TMDS_PRE: RV56.2 RV64.1 UV7.20
PS8339B_TMDS_RT: RV55.2 RV62.1 UV7.23
PS_ID: PR8.1 PR9.2 UE2.B24
PS_USBP1_D+: LI7.1 UI3.10
PS_USBP1_D-: LI7.4 UI3.11
PWM1: PU500.6 PU501.8
PWR_SRC_ON: CV11.2 QV1.3 RV4.2 RV5.1
REGCTL_PNP10: LL1.1 UL1.7
REM_DIODE1_N: CE24.1 CE35.1 QE3.3 UE2.B13
REM_DIODE1_P: CE24.2 CE35.2 QE3.1 QE3.2 UE2.A13
REM_DIODE2_N: CE26.1 CE37.2 CE46.2 QE5.3 QE7.1 QE7.2 UE2.B14
REM_DIODE2_P: CE26.2 CE37.1 CE46.1 QE5.1 QE5.2 QE7.3 UE2.A14
REM_DIODE4_N: CE39.1 QE6.3 RE100.2
REM_DIODE4_N_R: CE27.1 RE100.1 UE2.A16
REM_DIODE4_P: CE39.2 QE6.1 QE6.2 RE101.2
REM_DIODE4_P_R: CE27.2 RE101.1 UE2.B17
RES_BIAS: RL13.1 UL1.12
RESET_OUT#: RE56.2 UC1.AY7 UC8.2 UE2.B39
RING2: LA10.1 RA5.1 UA1.28
RING2_R: CA4.1 CA13.1 DA3.2 JHP1.3 LA10.2
RSMRST#: RZ22.2 RZ51.2 UZ5.3 UZ6.2
RUN_ON: QE2.2 RE279.2 RE280.2 RPE10.1 RZ41.1 UZ8.5 UZ9.3 UZ9.5
RUN_ON#: QE2.5 QE2.6 RE68.2
RUN_ON_EC: RE279.1 UE2.B9
RUNPWROK: QE2.3 RE67.2 UC7.1 UC7.4 UC7.10 UC7.13 UE2.B26
S5_1.35V: PC215.1 PR207.2 PU200.8
SATA2_PCIE6_L1: RPC9.8 UC1.V6
SATA_ACT#: QZ3.4 UC1.U3
SATA_COMP: RC17.1 UC1.C12
SATA_LED: JLED1.3 QZ4.3
SATA_LED#: QZ3.6 QZ4.2
SATA_PRX_DTX_N1: CN25.1 UC1.J8
SATA_PRX_DTX_N1_C: CN25.2 UN2.4
SATA_PRX_DTX_N1_RP: CN18.2 UN2.12
SATA_PRX_DTX_N1_RP_C: CN18.1 JSATA1.5
SATA_PRX_DTX_P1: CN26.1 UC1.H8
SATA_PRX_DTX_P1_C: CN26.2 UN2.5
SATA_PRX_DTX_P1_RP: CN17.2 UN2.11
SATA_PRX_DTX_P1_RP_C: CN17.1 JSATA1.6
SATA_PTX_DRX_N1: CN30.1 UC1.A17
SATA_PTX_DRX_N1_C: CN30.2 UN2.2
SATA_PTX_DRX_N1_RP: CN20.2 UN2.14
SATA_PTX_DRX_N1_RP_C: CN20.1 JSATA1.3
SATA_PTX_DRX_P1: CN23.1 UC1.B17
SATA_PTX_DRX_P1_C: CN23.2 UN2.1
SATA_PTX_DRX_P1_RP: CN19.2 UN2.15
SATA_PTX_DRX_P1_RP_C: CN19.1 JSATA1.2
SD/MMCCD#: CR35.1 JSD1.18 RR11.1 UR1.21
SD/MMCCLK: CR23.1 JSD1.5 RR1.2
SD/MMCCLK_R: RR1.1 UR1.43
SD/MMCCMD: JSD1.2 UR1.45
SD/MMCDAT0: JSD1.7 UR1.30 UR1.38
SD/MMCDAT1: JSD1.8 UR1.29 UR1.37
SD/MMCDAT2: RR4.1 UR1.48
SD/MMCDAT2_R: JSD1.9 RR4.2
SD/MMCDAT3: RR3.1 UR1.47
SD/MMCDAT3_R: JSD1.1 RR3.2
SD_REXT: RR5.1 UR1.26
SD_UHS2_D0N: JSD1.12 UR1.34
SD_UHS2_D0P: JSD1.11 UR1.35
SD_UHS2_D1N: JSD1.15 UR1.33
SD_UHS2_D1P: JSD1.16 UR1.32
SDWP: JSD1.19 UR1.20
SIO_EXT_SCI#: RC156.1 UC1.N5 UE2.A33
SIO_EXT_SMI#: RPC5.5 UC1.AG5 UE2.A6
SIO_EXT_WAKE#: RPC7.6 UC1.AU2 UE2.B5
SIO_PWRBTN#: JXDP1.41 UC1.AL7 UE2.B58
SIO_RCIN#: RPC15.1 UC1.V4 UE2.A27
SIO_SLP_A#: JAPS1.6 UC1.AL5 UC6.1 UE2.B28
SIO_SLP_LAN#: UC1.AJ7 UE2.B37 UZ2.5
SIO_SLP_S0#: JAPS1.15 UC1.AF3
SIO_SLP_S3#: JAPS1.2 RE280.1 UC1.AT4 UE2.A35
SIO_SLP_S4#: JAPS1.5 RE282.1 T9.1(TP-1) UC1.AJ6 UE2.B36
SIO_SLP_S5#: JAPS1.4 T8.1(TP-1) UC1.AP5 UE2.A18
SIO_SLP_SUS#: UC1.AP4 UE2.B52
SIO_SLP_WLAN#: UC1.AM5 UE3.39
SKIP#: PR520.2 PU500.7
SKIP#1: PR520.1 PU501.1
SLATE_MODE: RPC10.6 UC1.AL4
SLEEVE: LA11.1 QA2.3 RA6.1 UA1.29
SLEEVE_R: CA1.1 CA12.1 DA1.3 JHP1.4 LA11.2
SLEWA: PR500.2 PR510.1 PU500.15
SM_RCOMP0: RC130.1 UC1.AU60
SM_RCOMP1: RC131.1 UC1.AV60
SM_RCOMP2: RC132.1 UC1.AU61
SMART_DET#: T32.1(TP-1) UE3.9
SMB_ADDR: RE87.2 UE3.35
SML0_SMBCLK: RC33.2 UC1.AN1 UL1.28
SML0_SMBDATA: RC34.2 UC1.AK1 UL1.31
SML1_SMBCLK: RPC14.3 UC1.AU3 UE2.B6
SML1_SMBDATA: RPC14.4 UC1.AH3 UE2.A5
SNB_1.05V: PC301.1 PR305.2
SNUB_1.35V: PC208.1 PR203.2
SNUB_3V: PC111.1 PR111.2
SNUB_5V: PC114.1 PR112.2
SPI_CLK32: RC61.2 RPC12.7 UC3.6
SPI_CLK64: RC62.2 RPC11.6 UC2.6
SPI_CLKTPM: RZ26.2 RZ35.2 UZ1.21
SPI_DIN32: RPC12.5 UC3.2
SPI_DIN64: RPC11.8 UC2.2
SPI_DINTPM: RZ30.2 UZ1.26
SPI_DO32: RPC12.6 UC3.5
SPI_DO64: RPC11.7 UC2.5
SPI_DOTPM: RZ29.2 UZ1.23
SPI_PCH_CLK: JSPI1.7 RC227.1 RPC11.3 RPC12.2
SPI_PCH_CS0#: JSPI1.9 RC35.1 RC228.1
SPI_PCH_CS0#_R: RC35.2 UC2.1
SPI_PCH_CS1#: JSPI1.1 RC50.1 RC224.1
SPI_PCH_CS1#_R: RC50.2 UC3.1
SPI_PCH_DIN: JSPI1.5 RC226.1 RPC11.1 RPC12.4
SPI_PCH_DO: JSPI1.3 RC225.1 RPC11.2 RPC12.3
SPI_PCH_DO2: JSPI1.11 RC29.2 RC38.1 RC55.1 RC229.1
SPI_PCH_DO2_32: RC55.2 UC3.3
SPI_PCH_DO2_64: RC38.2 UC2.3
SPI_PCH_DO3: JSPI1.13 RC31.2 RC230.1 RPC11.4 RPC12.1
SPI_PCH_DO3_32: RPC12.8 UC3.7
SPI_PCH_DO3_64: RPC11.5 UC2.7
SPKR: RA12.2 RC180.2 UC1.V2
SRTCRST#: CC3.2 RC10.2 UC1.AV6
SUS_ON: PR207.1 RE281.2 RE282.2 RPE10.2
SUS_ON_EC: RE281.1 UE2.B23
SUS_STAT#/LPCPD#: RC82.2 UC1.AG4
SUSACK#: RC81.2 UC1.AK2 UE2.A23
SUSCLK: RC136.2 RZ56.1
SUSCLK_R: RC136.1 UC1.AE6
SW1: PC110.2 PL102.1 PQ101.1 PQ101.2 PQ101.3 PQ103.5 PR112.1 PU100.18
SW2: PC109.1 PL101.2 PQ100.1 PQ100.2 PQ100.3 PQ102.5 PR111.1 PU100.8
SW_1.35V: PC204.2 PL200.2 PQ200.1 PQ200.2 PQ200.3 PQ201.5 PR203.1 PU200.16
SW_+V1.05SP: PL301.1 PR305.1 PR312.2 PU300.10
SW_MDP_AUX#_C: CV513.1 UV502.5
SW_MDP_AUX_C: CV512.1 UV502.2
SYS_LED_MASK#: QL1.2 QL1.5 QL2.2 QZ3.2 QZ7.2 RE21.2 UE3.14 UZ10.1
SYS_PWROK: CC22.1 JXDP1.47 RC120.1 UC1.AG2 UE2.B7
SYS_RESET#: JAPS1.13 RC77.2 UC1.AC3 UC4.4
TDI_IREF: RC186.2 UC1.B12
TDI_XDP_R: RC99.2 RC118.1 UC7.5
TDO_XDP: JXDP1.52 RC98.2 RC115.1 RC117.2 UC7.2
THERMATRIP2#: CE36.1 QE4.1 RE69.2 UE2.B34
THERMATRIP3#: RPE6.1 UE2.A2
THSEL_STRAP: RE78.1 UE2.B29
TMDS_CON_CLK: JHDMI1.10 LV3.3
TMDS_CON_CLK#: JHDMI1.12 LV3.2
TMDS_CON_N0: JHDMI1.9 LV12.2
TMDS_CON_N1: JHDMI1.6 LV10.2
TMDS_CON_N2: JHDMI1.3 LV6.2
TMDS_CON_P0: JHDMI1.7 LV12.3
TMDS_CON_P1: JHDMI1.4 LV10.3
TMDS_CON_P2: JHDMI1.1 LV6.3
TOUCH_PANEL_INTR#: JEDP1.5 RPC3.5 UC1.P3
TOUCH_SCREEN_PD#: T96.1(TP-1) UE3.36
TOUCHPAD_INTR#: RPC9.6 UC1.U7
TP_DC_TEST_B2: RC192.2 UC1.B2
TP_LAN_JTAG_TCK: RL2.2 UL1.35
TP_LAN_JTAG_TDI: T88.1(TP-1) UL1.32
TP_LAN_JTAG_TDO: T89.1(TP-1) UL1.34
TP_LAN_JTAG_TMS: RL1.2 UL1.33
TPM_PIRQ#: RC247.1 UC1.T3 UZ1.20
TRST#_XDP: JXDP1.54 UC7.12
UG_3V: PQ100.4 PU100.10
UG_5V: PQ101.4 PU100.16
USB3RN1: LI1.1 UC1.G20
USB3RN1_D-: DI1.1 DI1.9 JUSB1.5 LI1.2
USB3RN2: LI6.1 UC1.E18
USB3RN2_D-: DI4.1 DI4.9 JUSB3.5 LI6.2
USB3RN4: LI9.1 UC1.F15
USB3RN4_D-: DI6.1 DI6.9 JUSB2.5 LI9.2
USB3RP1: LI1.4 UC1.H20
USB3RP1_D+: DI1.2 DI1.8 JUSB1.6 LI1.3
USB3RP2: LI6.4 UC1.F18
USB3RP2_D+: DI4.2 DI4.8 JUSB3.6 LI6.3
USB3RP4: LI9.4 UC1.G15
USB3RP4_D+: DI6.2 DI6.8 JUSB2.6 LI9.3
USB3TN1: CI4.2 UC1.C33
USB3TN1_C: CI4.1 LI2.1
USB3TN1_D-: DI1.4 DI1.7 JUSB1.8 LI2.2
USB3TN2: CI16.2 UC1.B33
USB3TN2_C: CI16.1 LI5.1
USB3TN2_D-: DI4.4 DI4.7 JUSB3.8 LI5.2
USB3TN4: CI28.2 UC1.B31
USB3TN4_C: CI28.1 LI8.1
USB3TN4_D-: DI6.4 DI6.7 JUSB2.8 LI8.2
USB3TP1: CI5.2 UC1.B34
USB3TP1_C: CI5.1 LI2.4
USB3TP1_D+: DI1.5 DI1.6 JUSB1.9 LI2.3
USB3TP2: CI13.2 UC1.A33
USB3TP2_C: CI13.1 LI5.4
USB3TP2_D+: DI4.5 DI4.6 JUSB3.9 LI5.3
USB3TP4: CI27.2 UC1.A31
USB3TP4_C: CI27.1 LI8.4
USB3TP4_D+: DI6.5 DI6.6 JUSB2.9 LI8.3
USB_DB_DET#: T98.1(TP-1) UE3.7
USB_OC0#: RPC19.3 UC1.AL3 UI1.5
USB_OC1#: RPC7.7 UC1.AT1 UI3.13
USB_OC2#: RPC5.8 UC1.AH2 UI2.5
USB_OC3#: RPC7.5 UC1.AV3
USB_PWR_EN1#: RPE9.2 UE3.30 UI1.4
USB_PWR_EN2#: RPE9.1 UE3.31 UI2.4
USB_PWR_SHR_EN#: RPE9.4 UE2.B38 UI3.6
USB_PWR_SHR_VBUS_EN: RPE9.3 UE3.25 UI3.5
USBP0+: LI3.1 UC1.AM8
USBP0-: LI3.4 UC1.AN8
USBP0_D+: DI2.2 JUSB1.3 LI3.2
USBP0_D-: DI2.3 JUSB1.2 LI3.3
USBP1+: UC1.AT7 UI3.3
USBP1-: UC1.AR7 UI3.2
USBP1_R_D+: DI5.3 JUSB3.3 LI7.2
USBP1_R_D-: DI5.2 JUSB3.2 LI7.3
USBP2+: JNGFF1.3 UC1.AP8
USBP2-: JNGFF1.5 UC1.AR8
USBP3+: LI4.1 UC1.AT10
USBP3-: LI4.4 UC1.AR10
USBP3_D+: DI3.3 JUSB2.3 LI4.2
USBP3_D-: DI3.2 JUSB2.2 LI4.3
USBP4+: LV27.3 UC1.AL15
USBP4-: LV27.2 UC1.AM15
USBP4_D+: DV4.3 JEDP1.3 LV27.4
USBP4_D-: DV4.2 JEDP1.2 LV27.1
USBP5+: LZ1.1 UC1.AN13
USBP5-: LZ1.4 UC1.AM13
USBP5_D+: JEDP1.13 LZ1.2
USBP5_D-: JEDP1.12 LZ1.3
USBRBIAS: RC152.1 UC1.AJ10 UC1.AJ11
USH_DET#: RPC15.4 UC1.E3
USH_PWR_STATE#: RZ10.2 UE3.10
USH_SMBCLK: RZ8.2 UE2.A50
USH_SMBDAT: RZ9.2 UE2.B53
VCI_IN2#: RPE5.4 UE2.B63
VCT_LAN_R1: RL3.2 UL1.6
VFB: PR531.2 PU500.24
VGA_ID: RE84.1 UE3.19
VIDALERT_N: PR528.2 PU500.32 RC204.2 RC207.2
VIDSCLK: PR527.2 PU500.31 UC1.N63
VIDSOUT: PR529.2 PU500.1 RC208.2 UC1.L63
VR_HOT#: PR534.1 PU500.30
VREF: PC507.1 PH500.1 PR500.1 PR502.1 PR503.1 PR504.1 PR521.2 PU500.27
VSET_5085: CE38.1 RE77.1 UE2.A17
WIGIG_32KHZ: JNGFF1.42 RZ56.2 RZ57.2
WIGIG_32KHZ_R: RZ57.1 UZ11.4
WIGIG_AUX: CV149.1 RV514.2 UV7.55
WIGIG_AUX#: CV150.1 RV515.2 UV7.54
WIGIG_AUX#_C: CV150.2 JNGFF1.12
WIGIG_AUX_C: CV149.2 JNGFF1.14
WIGIG_HPD: JNGFF1.23 UV7.32
WIGIG_LANE_N0: CV156.1 UV7.39
WIGIG_LANE_N0_C: CV156.2 JNGFF1.24
WIGIG_LANE_N1: CV152.1 UV7.36
WIGIG_LANE_N1_C: CV152.2 JNGFF1.18
WIGIG_LANE_N2: CV147.1 UV7.33
WIGIG_LANE_N2_C: CV147.2 JNGFF1.17
WIGIG_LANE_N3: CV145.1 UV7.30
WIGIG_LANE_N3_C: CV145.2 JNGFF1.11
WIGIG_LANE_P0: CV157.1 UV7.40
WIGIG_LANE_P0_C: CV157.2 JNGFF1.26
WIGIG_LANE_P1: CV153.1 UV7.37
WIGIG_LANE_P1_C: CV153.2 JNGFF1.20
WIGIG_LANE_P2: CV148.1 UV7.34
WIGIG_LANE_P2_C: CV148.2 JNGFF1.19
WIGIG_LANE_P3: CV146.1 UV7.31
WIGIG_LANE_P3_C: CV146.2 JNGFF1.13
WIGIGCLK_REQ#: JNGFF1.60 RPC9.7 UC1.U5
WIRELESS_LED#: QZ2.3 QZ2.6 QZ7.1 RZ31.2 UE3.16
WLAN_DISBL#: UE3.13 UL2.4
WLAN_LED: JLED1.6 QZ9.3
WLAN_LED#: JNGFF1.6 QZ2.1 RZ14.1
WLAN_LED_Q#: QZ7.6 QZ9.2
WLAN_WIGIG60GHZ_DIS#: DZ1.1 RE8.2 UE3.17
WLAN_WIGIG60GHZ_DIS#_R: DZ1.2 JNGFF1.48
WLANCLK_REQ#: JNGFF1.45 RPC17.6 UC1.N1
XDP_DBRESET#: CC21.1 JXDP1.48 RC77.1 RC122.2 UC4.1
XDP_OBS0_R: JXDP1.21 UC1.J60
XDP_OBS1_R: JXDP1.23 UC1.H60
XDP_OBS2_R: T10.1(TP-1) UC1.H61
XDP_OBS3_R: T11.1(TP-1) UC1.H62
XDP_OBS4_R: T12.1(TP-1) UC1.K59
XDP_OBS5_R: T13.1(TP-1) UC1.H63
XDP_OBS6_R: T14.1(TP-1) UC1.K60
XDP_OBS7_R: T15.1(TP-1) UC1.J61
XDP_RST#_R: JXDP1.46 RC106.2
XTAL24_IN: CC8.2 RC63.2 UC1.A25 YC2.3
XTAL24_OUT: RC63.1 RC65.1 UC1.B25
XTAL24_OUT_R: CC11.2 RC65.2 YC2.1
XTALI: CL14.2 RL11.2 UL1.10 YL1.1
XTALO: RL10.2 RL11.1 UL1.9
XTALO_R: CL13.2 RL10.1 YL1.3
Z2805: RL18.1 TL1.22
Z2806: RL16.1 TL1.16
Z2807: RL17.1 TL1.21
Z2808: RL15.1 TL1.15
N15115: T16.1(TP-1) UC1.AD4
N19253: T28.1(TP-1) UC1.AV63
N19255: T29.1(TP-1) UC1.AU63
N19263: T30.1(TP-1) UC1.C63
N19267: T31.1(TP-1) UC1.C62
N19275: T33.1(TP-1) UC1.A51
N19277: T34.1(TP-1) UC1.B51
N19281: T35.1(TP-1) UC1.L60
N21871: T74.1(TP-1) UC1.P60
N21873: T75.1(TP-1) UC1.P61
N21875: T76.1(TP-1) UC1.N59
N21877: T77.1(TP-1) UC1.N61
N33048: CD36.2 RD21.1
N33050: CD54.2 RD25.1
N40459: QV2.1 RV5.2
N43975: QN1.5 QN1.6 RN2.2
N70745: RE64.1 UE2.B61
N70747: CE34.1 RE66.2
N70757: RE57.1 RE58.1 UE2.A59
N73962: CZ45.1 UZ9.12
N73964: CZ46.1 UZ9.10
N75571: DZ3.2 DZ4.2 QZ3.1 RZ24.2
N75595: DZ3.1 QZ3.3
N5261056: QD1.3 RD10.1 RD11.1 RD12.1 RD13.1
N10757881: CD21.2 RD7.1
N18279753: PD5.2 PD5.3 PL3.1 PQ2.1 PR7.1 PR10.2
N18279759: PQ2.3 PR7.2 PR9.1
N18279771: PQ3.2 PR10.1 PR12.2
N18279775: PQ2.2 PQ3.1 PR11.2
N18281287: PR101.1 PR104.1 PU100.2
N18281336: PR100.2 PR102.2 PU100.4
N18281357: PR114.1 PU100.19
N18281599: PR105.2 PU100.5
N18281901: PR106.2 PU100.1
N18284921: PR210.2 PU200.7
N18284982: PC209.2 PR204.1 PU200.12
N18285023: PR206.2 PU200.9
N18287240: PC309.1 PU300.5
N18287762: PC402.1 PR400.2 PR401.1 PU400.8
N18287796: PC403.2 PR402.2 PR403.1 PU400.2
N18289928: PR513.1 PU500.4
N18289956: PR516.1 PR539.1 PU500.3
N18289962: PC506.1 PR523.1 PR535.1 PU500.25
N18289987: PC506.2 PC512.2 PR521.1 PR523.2 PU500.26
N18290013: PC510.1 PR526.2 PU500.28
N18290066: PH501.2 PR515.1
N18290144: PC501.1 PH500.2 PR505.1 PU500.14
N18290240: PR511.2 PU500.16
N18290306: PC505.1 PR519.1 PU500.2
N18290543: PC512.1 PR535.2
N18290557: PR536.1 PU500.8
N18292461: PR731.2 PU700.4
N18292467: PC730.2 PC731.2 PQ708.3 PQ710.4 PR731.1 PR737.2
N18292492: PR730.2 PU700.3
N18292494: PQ708.1 PQ708.2
N18293474: PD704.1 PD705.1 PR708.1
N18293502: PC711.1 PQ711.1 PR710.1 PR711.1 PU700.6
N18293543: PR714.2 PU700.5
N18293549: PC719.2 PR718.2 PU700.8
N18293551: PC718.2 PR716.2 PU700.7
N18293561: PR720.2 PR788.2 PU700.9
N18293616: PR717.2 PU700.10
N18293640: PC702.2 PC703.1 PR705.1 PU700.1
N18293642: PR725.2 PR729.1 PU700.16
N18293644: PC701.2 PC702.1 PR704.1 PU700.2
N18293674: PC726.2 PC727.1 PR721.3 PU700.20
N18293684: PC727.2 PC728.1 PR721.2 PU700.19
N18293714: PR728.2 PU700.15
N18293785: PR722.1 PU700.18
N18293918: PC729.2 PR723.1 PU700.17
N18325201: CL16.1 TL1.3
N18325205: CL17.1 TL1.4
N18325209: CL20.1 TL1.9
N18325213: CL21.1 TL1.10
N18490882: RI14.2 UI3.16
N18609334: QV7.1 QV8.2 RV6.2
N18749305: JEDP1.21 LV1.1
N19516037: CZ9.1 RZ35.1
N19544058: CC10.2 RC62.1
N19544059: CC9.2 RC61.1
N19684722: RE24.1 UE3.38
N20106358: RV50.1 UV7.27
N20106372: CV60.1 UV7.1
N20173859: QZ4.1 RZ27.1
N20174013: QZ9.1 RZ33.1
N20249193: CA29.1 UA1.35
N20249194: CA29.2 UA1.36
N20249196: CA25.1 UA1.31
N20249200: CA27.1 RA12.1
N20249201: CA28.1 RA13.1
N20249202: QA2.5 QA2.6 RA21.2
N20249232: DA5.1 RA25.2
N20249233: DA4.1 RA24.2
N20249251: DA2.2 JHP1.5 RA1.2
N20360585: CA49.2 UA1.34
N20364102: CA35.2 UA1.25
N20364110: CA51.1 RA44.1 UA1.21
N20364112: CA52.1 UA1.39
N20364114: CA53.1 UA1.7
N20645594: PC304.2 PR309.1
N20818937: PR518.2 PR524.1 PR525.1
N20870052: PQ709.4 PR737.1
N20880528: CZ23.1 UZ2.10
N20923205: PR799.1 PU700.21
N20970248: JDIMM1.197 RD15.2
N20970250: JDIMM1.201 RD16.2
N21259653: JDIMM2.197 RD28.1
N21259657: JDIMM2.201 RD27.1
N21562439: CZ42.1 UZ2.12
N21786800: CN4.1 UN3.6
N21822883: RC2.2 SW1.2
N21866204: CA33.1 RA17.2
N22016638: CZ41.1 UZ8.12
N22016651: CZ64.1 UZ8.10
N22018128: CZ37.1 UZ3.6
N22050202: RA45.1 UA1.22
N23163402: QE4.2 RE70.2

Pads without a net: FD1 1; FD2 1; FD3 1; FD4 1; JAPS1 16 17 18; JDEG1 9; JDIMM1 77 122 125 198 205 206; JDIMM2 77 122 125 198 205 206; JEDP1 16 20 32; JHDMI1 14; JKBTP1 6 13; JLED1 9; JLOM1 14 15; JNGFF1 9 36 38 40 50 52 54 56; JSATA1 8 20; JSPI1 17; JXDP1 40 42; PBATT1 11 12; PD2 3; PRP2 4 5; PU200 10; PU400 7; PU500 5; PU700 13 14; QL2 3 4 5; RPC1 7; RPC17 8; RPE6 4 5; UA1 1 14 15 16 17 18 24; UC1 A5 A15 A21 A23 A35 A37 A41 A43 A49 AA23 AA59 AB8 AB21 AB23 AC20 AC58 AC59 AD5 AD7 AD8 AD10 AD23 AD59 AD60 AE59 AE60 AF20 AG58 AH13 AL1 AL2 AL11 AL32 AM10 AM11 AN10 AN11 AP7 AP11 AP13 AP32 AR13 AT2 AU10 AU12 AU15 AU44 AV2 AV10 AV44 AV50 AV62 AW10 AW14 AW49 AY8 AY14 AY42 AY43 B14 B15 B21 B22 B23 B35 B37 B41 B43 B49 C4 C15 C17 C21 C46 C47 D1 D15 D17 D58 D61 E1 E5 E6 E8 E13 E15 F5 F6 F8 F22 G1 G10 H5 H6 H10 H18 H22 J2 J4 J5 J6 J13 J20 J21 J58 K4 K10 K18 K21 L3 L11 L59 M20 M21 N23 N58 N60 P2 P20 R5 R20 R23 T23 T59 U10 U59 V21 V59 W23 Y20 Y22; UC8 1; UD1 1; UE2 A15 B15 B16 B41 B42 B62; UE3 4 11 20 21 22 24 27 29 37; UI3 9 15; UN1 2 3; UN2 7; UR1 19 39 40 44 46; UV7 46; UZ1 1 2 5 6 7 9 12 13 14 15 17 27 28; YC2 2 4

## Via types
v1: diameter 0.305, hole 0.152, TOP to BOTTOM, 421 vias
v2: diameter 0.457, hole 0.203, TOP to BOTTOM, 3839 vias
v3: diameter 0.508, hole 0.254, TOP to BOTTOM, 570 vias
v4: diameter 0.406, hole 0.203, TOP to BOTTOM, 249 vias

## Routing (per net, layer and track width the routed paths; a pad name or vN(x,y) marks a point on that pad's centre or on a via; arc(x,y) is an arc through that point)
0.675V_DDR_VTT_ON: length 105
  TOP w0.102: UD1.4 149.01,21.58 RD14.2 RD9.2 150.52,21.58 QD1.2 151.86,20.24 155.44,20.24 156.3,19.39 156.3,12.56 152.83,9.1 v4(152.83,8.99) v2(152.83,7.77) ; v2(73.96,8.15) 73.12,8.99 PR210.1
  IN2 w0.102: v2(152.83,7.77) 152.37,7.3 74.81,7.3 73.96,8.15 v2(73.96,8.15)
1.05V_M_PWRGD: length 22.8
  TOP w0.102: RC27.1 196.63,51.85 v4(197.2,51.28) 198.79,49.69 202.46,49.69 203.25,48.91 v2(205.2,48.91)
  TOP w0.254: PR313.1 205.23,59.31 v2(205.45,59.09)
  IN2 w0.102: v2(205.45,59.09) 205.74,58.8 205.74,49.44 v2(205.2,48.91)
1.05V_MODPHY_EN: length 22.9
  TOP w0.102: QZ6.3 164.13,86.44 163.94,86.63 162.76,86.63 162.51,86.37 CZ25.1 162.99,85.64 v2(163.13,85.64) ; RZ5.2 144.95,86.85 144.98,86.82 QZ10.3 146.11,86.82 146.99,85.94 v1(151.27,85.94) 151.69,85.94 v2(152.04,86.3)
  BOTTOM w0.102: v2(152.04,86.3) 162.47,86.3 v2(163.13,85.64)
1.05V_MP_PWROK: length 3.6
  TOP w0.102: PR313.2 205.23,61.21 v1(205.66,61.65)
  TOP w0.254: PR313.2 205.41,60.44 v2(206.09,60.44) 206.11,60.45 PR315.2
  BOTTOM w0.102: v2(206.09,60.44) 206.07,60.46 PU300.2
1.5VSP:
  vias: v1(106.99,75.04)
1.35V_B+: length 24.4
  TOP w0.102: PQ200.5 v1(67.69,26.34)
  IN1 w0.254: v2(62.1,23.47) 60.73,22.1 60.73,16.03 61.21,15.54 61.21,9.94 62.42,8.74 66.1,8.74 v2(66.29,8.93)
  BOTTOM w0.254: v2(66.29,8.93) 66.29,7.92 PR206.1
  BOTTOM w0.508: PC203.1 v2(62.1,23.47)
1.35V_FB: length 6.3
  BOTTOM w0.102: PR209.1 v1(70.05,7.16)
  BOTTOM w0.203: PC213.1 70.74,8.03 70.29,8.48 70.29,8.93 69.91,9.31 68.88,9.31 68.61,9.04 PU200.6
  BOTTOM w0.254: PR205.1 PC213.1 71.04,7.17 PR209.1
3.3V_CAM_EN#: length 166.1
  TOP w0.102: QZ1.2 115.82,85.25 116.39,85.83 116.39,88.7 v1(117.67,89.97) 118.18,89.97 120.81,92.61 v2(131.72,92.61) ; RC174.1 183.53,54.08 v2(182.65,54.95) 182.55,54.95 182.01,55.49 182.01,56.15 180.49,57.67 173.42,57.67 173.04,57.28 171.9,57.28 v2(171.39,56.77)
  IN1 w0.102: v2(196.89,67) 196.19,67 193.58,64.39 192.48,64.39 191.81,63.72 191.81,61.71 190.71,60.62 190.71,59.72 190.26,59.27 188.15,59.27 187.98,59.11 187.32,59.11 185.54,57.33 184.44,57.33 183.14,56.03 183.14,55.45 v2(182.65,54.95)
  BOTTOM w0.076: v2(171.39,56.77) 171.39,56.75 170.89,56.25 170.59,56.25 170.43,56.09 169.64,56.09 169.6,56.13 169.13,56.13 UC1.AM4
  BOTTOM w0.102: v2(131.72,92.61) 136.76,97.65 189.94,97.65 194.85,92.73 201.95,92.73 205.59,89.1 205.59,82.77 202.42,79.6 202.42,75.23 197.29,70.1 197.29,67.39 v2(196.89,67)
3.3V_HDD_EN: length 168.6
  TOP w0.102: UN3.3 251.98,19.12 RN7.1 RN6.2 247.01,18.17 246.43,18.76 v2(246.43,19.21) ; v2(242.16,21.36) 242.78,21.99 242.78,26.52 242.26,27.04 240.54,27.04 240.19,27.38 240.19,28.41 239.83,28.78 239.83,30.32 238.49,31.65 238.49,32.93 239.65,34.09 239.65,36.62 241.94,38.91 245.27,38.91 245.69,39.33 245.69,39.71 244.37,41.03 244.37,45.92 243.3,46.99 243.3,51.17 243.77,51.64 v4(243.77,52.65) 243.77,55.23 244.6,56.06 244.6,60.65 244.31,60.95 v2(244.02,60.95)
  IN1 w0.102: v2(170.47,68.15) 170.66,68.34 170.66,70.66 170.11,71.21 170.11,76.23 171.07,77.19 171.07,80.83 175.86,85.62 188.35,85.62 189.6,84.38 189.6,83.8 191.13,82.26 191.13,81.9 192.42,80.62 192.42,80.61 192.77,80.26 192.77,79.54 193.97,78.34 197.71,74.6 215.06,74.6 218.21,77.75 229.29,77.75 230.81,76.24 232.46,76.24 234.77,73.93 234.77,67.58 241.4,60.95 v2(244.02,60.95)
  IN2 w0.102: v2(242.16,21.36) 245.1,21.36 246.43,20.04 v2(246.43,19.21)
  BOTTOM w0.076: UC1.K2 170.13,67.81 v2(170.47,68.15)
3.3V_TP_EN: length 16
  TOP w0.076: 175.7,69.25 175.39,69.25 174.98,68.83 173.64,68.83 173.15,69.32 171.61,69.32 171.28,69.65 169.29,69.65 168.51,68.87 168.51,68.39 v1(168.32,68.2) 168.32,68.19 v2(168.32,67.65)
  TOP w0.102: RPC3.7 180.88,68.43 180.67,68.64 180.67,69.05 180.47,69.25 175.7,69.25
  BOTTOM w0.076: UC1.L5 168.15,67.48 v2(168.32,67.65)
3.3V_TS_EN: length 93.5
  TOP w0.076: v2(167.13,66.69) 167.49,67.06 169.29,67.06 169.54,67.31 169.54,67.82 170.25,68.53 170.91,68.53 171.08,68.7 172.83,68.7 173.36,68.17
  TOP w0.102: 173.36,68.17 173.4,68.12 176.26,68.12 176.46,67.92 RPC4.7 ; v2(170.15,86.64) v1(170.15,87.78) 170.15,88.32 166.81,91.66 150.1,91.66 149.18,92.57 134.49,92.57 128.08,86.17 124.98,86.17 122.04,83.23 122.04,81.51 120.86,80.33 119.67,80.33 QV7.2
  IN1 w0.102: v2(167.13,66.69) 167.38,66.95 167.38,70.8 166.99,71.2 166.99,74.87 168.25,76.13 168.25,76.67 168.53,76.95 168.53,79.3 169.19,79.96 169.19,84.94 169.42,85.17 169.42,85.91 v2(170.15,86.64)
  BOTTOM w0.076: v2(167.13,66.69) 166.85,66.41 UC1.N7
+0.9V_LAN: length 15
  TOP w0.127: v4(262.06,91.82) 262.06,91.54 261.42,90.9 v2(261.3,90.9)
  TOP w0.203: v2(252.59,83.8) 253.01,83.8 253.2,83.99 UL1.11 ; CL9.1 260.52,90.21 259.67,89.36 259,89.36 258.83,89.18 UL1.37 ; UL1.40 257.63,89.67 v2(257.67,89.71) ; CL8.1 255.78,91.05 256.08,91.05 256.32,90.8 256.32,90.61 256.5,90.44 256.5,89.41 256.43,89.33 UL1.43 ; UL1.16 255.63,82.08 v2(255.52,81.97) ; UL1.46 255.23,89.29 254.87,89.64 v2(254.83,89.64) UL1.47 ; v2(258.19,81.99) 258.03,82.15 UL1.22
  TOP w0.508: CL9.1 v2(261.3,90.9) ; CL8.1 255.63,90.57 255.99,90.21 v2(255.99,90.22)
  vias: v2(246.57,87.73) v2(246.57,87.1) v2(246.57,86.46) v2(246.54,85.88) v2(246.57,85.29) v2(251.99,85) v2(252.61,84.99)
+0.675V_DDR_VTT: length 174.3
  IN1 w1.524: 224.04,16.14 224.04,21.02 217.66,27.39
  BOTTOM w0.356: JDIMM2.204 223.8,9.9 ; JDIMM2.203 223.5,14.46 v2(223.75,14.22)
  BOTTOM w1.524: 80.62,21.18 81.96,22.53 92.34,22.53 96.06,26.25 139.3,26.25 140.43,25.12 140.43,21.84 142.25,20.03 143.1,20.03 144.37,18.76 144.37,17.3 143.76,16.69 ; 144,9.77 145.63,11.39 149.3,11.39 150,10.69 153.2,10.69 156.33,13.83 156.33,20.21 157.16,21.03 161.8,21.03 164.67,23.9 209.9,23.9 214.91,28.9 214.93,28.88
  vias: v2(142.8,10.33) v2(142.8,9.7) v2(216.14,28.88) v2(216.77,28.88) v2(217.41,28.88) v2(223.75,13.42) v2(223.76,12.8) v2(223.76,12.11) v2(223.76,11.48) v4(141.5,13.18)
+0.675V_P:
  vias: v2(70.41,13.41)
+1.2V_LDO: length 11.3
  TOP w0.127: v4(279.23,34.54) 279.93,34.54 CR21.2
  TOP w0.203: 288.76,33.76 288.11,33.11 UR1.36 ; CR13.2 280.79,29.51 UR1.10 ; CR21.2 280.38,34.05 281.32,33.11 UR1.1
  TOP w0.508: v2(288.71,35.95) 288.85,35.95 CR18.2 289.42,35.39 CR19.2 289.34,34.34 288.76,33.76 ; CR13.2 280.15,28.49 v2(280.53,28.11) ; v2(281.21,34.18) 280.46,34.18 CR21.2
  vias: v2(288.08,35.9) v2(290.55,30.94) v2(291.14,30.95)
+1.05V_M: length 10.5
  TOP w0.508: RC300.1 v2(161.57,64.4)
  BOTTOM w0.229: UC1.AG13 163.51,59.6 v2(163.78,59.88) ; UC1.AE9 UC1.AF9 165.75,59.04 UC1.AG8 166.4,58.8 v2(166.4,59.11) ; UC1.AG14 162.69,59.65 v2(162.51,59.83)
  BOTTOM w0.254: v2(162.51,59.83) 162.51,60.42 v2(162.9,60.81) 162.9,60.72 163.29,60.32 163.52,60.32 163.78,60.07 v2(163.78,59.88) ; v2(163.48,60.81) 164.37,60.81 165.16,60.03 UC1.AE9
  vias: v2(140.52,59.41) v2(141.16,59.41) v2(164.04,88.1) v2(164.04,87.46) v2(164.68,88.1) v2(164.68,87.46) v2(165.31,88.1) v2(165.31,87.46) v2(197.43,45.21) v2(198.02,45.21) v2(198.12,44.63) v2(198.47,44.09) v2(198.6,45.21) v2(198.73,44.63) v2(199.07,44.09) v2(199.21,45.21) v2(199.36,44.61) v2(199.67,44.09) v2(207.35,76.67) v2(207.63,76.06) v2(208,76.67) v2(208.28,76.05) v2(208.63,76.67) v2(208.91,76.05) v2(209.27,76.67) v2(209.55,76.05) v2(209.97,76.67) v2(210.18,76.05) v4(209.55,78.61)
+1.05V_MODPHY:
  vias: v4(156.49,82.5)
+1.05V_MODPHY_PCH: length 3.2
  BOTTOM w0.254: UC1.M9 164.85,66.69 v2(164.7,66.55) 164.7,66.57 UC1.L10 165.75,67.61 UC1.K9 165.81,67.7 v2(165.81,68.16)
  vias: v1(166.11,79.45)
+1.05V_MP: length 13.1
  IN1 w0.254: v2(206.11,59.24) 205.97,59.11 205.97,50.75 204.95,49.73 v3(203.53,49.73)
  BOTTOM w0.254: PC304.1 PR307.1 206.46,59.24 v2(206.11,59.24)
  vias: v1(204.2,54.36) v3(201.1,55.09) v3(201.1,54.46) v3(201.1,53.82) v3(201.86,55.09) v3(201.86,54.46) v3(201.86,50.78) v3(202.12,51.38) v3(202.4,50.15) v3(202.5,50.78) v3(202.63,55.09) v3(202.69,54.46) v3(202.75,51.38) v3(203.05,50.15) v3(203.15,50.78) v3(203.39,55.09) v3(203.4,51.38)
+1.5V_RUN: length 222.5
  TOP w0.254: 163.43,71.88 163.43,70.98 163.5,70.91 163.5,69 163.12,68.63 v2(162.99,68.63) 162.83,68.63 162.53,68.92 162.53,69.67 162.49,69.71 162.49,71.63 162.91,72.05 162.91,72.08 163.07,72.24 163.43,71.88
  TOP w0.508: v2(29.4,11.81) 29.77,11.81 30.15,12.19 RA3.1 ; 163.07,72.24 163.07,74.85 162.27,75.65 154.95,75.65 153.71,76.9 151.62,76.9 149.27,79.25 v4(147.66,79.25) 144.13,79.25 141.92,81.46 141.92,82.82 140.16,84.58 v2(140.16,85.64)
  IN1 w0.508: v2(140.16,85.64) 139.25,86.55 132.64,86.55 131,84.91 125.22,84.91 124.83,85.31 120.53,85.31 119.83,84.61 115.86,84.61 113.89,82.64 101.53,82.64 97.35,78.46 v2(93.1,78.46) 92.25,78.46 92.01,78.22 88.07,78.22 85.81,80.48 78.9,80.48 78.18,79.76 78.18,77.57 79.33,76.42 79.33,67.22 75.38,63.27 75.38,61.85 v2(74.72,61.19)
  IN2 w0.508: v2(29.4,11.81) 29.73,12.14 30.58,12.14 31.3,12.86 31.3,15.11 30.73,15.68 30.73,20.27 35.93,25.46 43.42,25.46 45.55,23.33 47.28,23.33 68.91,44.96 68.91,53.17 74.72,58.99 v2(74.72,61.19)
  BOTTOM w0.254: v2(162.99,68.63) 162.65,68.29 UC1.J15
  BOTTOM w0.508: 105.86,76.85 103.35,79.36 97.47,79.36 96.57,78.46 v2(93.1,78.46)
+1.05V_RUN: length 245.5
  TOP w0.254: JXDP1.44 85.36,50.2 v2(85.48,50.32) ; v2(79.82,50.37) 79.65,50.2 JXDP1.43
  TOP w0.279: UE2.B51 263.83,37.86
  TOP w0.508: RC197.1 125.69,80.81 v2(126.48,81.59) ; v2(248.04,35.97) 248.37,36.3 RE70.1 ; v2(265.69,34.33) 265.23,34.79 CE25.1 265.47,35.23 265.47,35.34 265.81,35.69 265.81,37.11 265.54,37.38 264.32,37.38 263.83,37.86 ; CC84.1 158.1,66.14 158.46,66.5 v2(158.7,66.5) ; CC60.1 162.43,67.68 CC59.1 162.05,68.05 v2(162.05,68.64) ; 194.56,37.74 197,35.31 210.14,35.31 211.27,34.18 211.27,33.14 213.73,30.68 220.23,30.68 v2(220.86,30.05) ; v2(130.58,82.27) 130.62,82.23 CC79.1 ; CC71.1 163.26,68.02 163.96,68.73 v2(163.96,69.35) ; v2(88.92,38.84) 89.39,39.31 89.39,43.8 89.93,44.34 89.93,45.62 88.32,47.23 v2(87.87,47.23) RC117.1 ; CC70.1 158.7,64.89 v2(158.73,64.86) ; v2(158.69,59.25) 158.14,59.25 CC58.1 ; CC72.1 160.68,58.37 v2(161.44,58.37)
  IN1 w0.508: v2(248.04,35.97) 248.04,35.55 247.36,34.86 241.32,34.86 239.29,32.83 232.41,32.83 230.67,31.1 223.23,31.1 222.18,30.05 v2(220.86,30.05) ; v2(87.87,47.23) 87.87,47.93 v2(85.48,50.32)
  IN1 w1.016: 132.31,81.86 132.31,83.73 133.56,84.99 138.41,84.99 139.41,84 142.16,84 143.15,83.01 ; 145.35,82.47 147.27,80.56 152.22,80.56
  IN2 w0.508: v2(265.69,34.33) 263.52,34.33 262.7,33.5 258.72,33.5 256.59,35.64 254.65,35.64 254.32,35.97 v2(248.04,35.97)
  BOTTOM w0.127: UC1.H15 162.4,68.94 v2(162.07,69.26)
  BOTTOM w0.229: UC1.J11 UC1.H11 164.22,69.09 164.22,69.1 v2(163.96,69.35)
  BOTTOM w0.254: UC1.AG16 161.79,58.72 v2(161.44,58.37) 161.09,58.72 UC1.AG17 ; UC1.P9 165.75,65.75 166.2,66.2 UC1.N8 166.37,66.39 v2(166.37,66.69) ; v2(158.73,64.86) 159.1,64.5 UC1.T21 ; v2(166.37,60.03) 166.2,59.85 UC1.AE8 ; UC1.J17 161.7,68.29 v2(162.05,68.64) ; v2(158.69,59.25) 158.68,59.24 158.24,59.24 UC1.AF22
  BOTTOM w0.33: UC1.R21 159.1,65.23 v2(158.73,64.86)
  BOTTOM w0.457: RC127.1 126.48,81.08 v2(126.48,81.59) 126.48,82.07 RC126.1 ; RC125.1 v2(127.56,81.58) RC124.1
  BOTTOM w0.508: RC196.2 131.24,81.97 130.93,82.27 v2(130.58,82.27) ; v2(79.82,50.37) 85.43,50.37 v2(85.48,50.32) ; v2(168.56,45.38) 168.11,44.92 168.11,38.14 166.43,36.46 155.56,36.46 154.13,35.03 92.73,35.03 v2(88.92,38.84)
  vias: v2(143.49,82.09) v2(143.93,82.52) v2(151.38,81.67) v2(155.89,86.85) v2(156.52,86.85) v2(157.16,86.85) v2(157.79,86.85) v2(158.33,83.07) v2(158.33,82.47) v2(174.14,92.85) v2(174.76,92.85) v2(175.37,92.85) v2(178.46,47.27) v2(178.48,46.68) v2(179.04,47.27) v2(179.06,46.68) v2(179.64,47.27) v2(179.66,46.68) v4(150.96,81.22)
+1.5V_RUN_AUDIO:
  vias: v1(31.98,13.41)
+1.05V_RUN_UZ8:
  vias: v1(200.7,47.46) v2(203.32,45.58) v2(203.4,46.16) v2(203.79,45.15) v2(203.9,45.78) v2(204.37,45.35) v2(211.16,45.6) v2(211.45,45.06) v2(211.76,45.6) v2(212.05,45.06) v2(212.34,45.57) v2(220.19,64.92) v2(220.19,64.34) v2(220.19,63.74) v2(220.79,64.35) v2(220.77,63.77) v2(234.17,52.69) v2(234.17,52.11) v2(234.77,52.69) v2(234.77,52.08) v2(234.77,51.47)
+1.05V_VCCST: length 113
  TOP w0.508: RC202.2 140.98,85.59 v2(140.88,85.49) 140.88,85.09 142.82,83.15 142.82,81.76 144.4,80.19 v4(144.99,80.19) 151.75,80.19 152.22,79.72 152.22,78.96 152.55,78.63 153.39,78.63 153.55,78.79 ; v2(128.63,83.35) 128.37,83.08 124.46,83.08 123.87,82.5 123.87,79.91 124.54,79.25 125.94,79.25 126.76,78.43 126.76,76.92 128.28,75.4 128.28,73 v2(126.85,71.56) ; PR527.1 PR528.1 PR529.1 PC511.1 98.85,75.54 v2(101.03,77.71)
  IN1 w0.508: v2(156.99,64.12) 155.8,65.32 155.8,68.37 156.28,68.84 156.28,69.82 155.67,70.42 155.67,71.12 155.06,71.73 155.06,75.84 153.65,77.25 v2(153.65,79.36) ; v2(140.88,85.49) 140.42,85.03 139.74,85.03 138.82,85.94 133.09,85.94 v2(130.5,83.35) v2(128.63,83.35) 128.37,83.08 126.07,83.08 124.46,84.7 120.9,84.7 120.15,83.95 116.23,83.95 114.13,81.85 105.17,81.85 v2(101.03,77.71)
  BOTTOM w0.254: v2(157.27,60.8) UC1.AC22 UC1.AE22 157.77,59.58 UC1.AE23 157.63,59.58 v2(157.24,59.18)
  BOTTOM w0.508: v2(128.63,83.35) RC25.1 ; v2(130.5,83.35) 129.97,82.82 RC199.1
+1.5V_VIN:
  vias: v1(107.49,69.62)
+1.8V_RUN_CARD: length 17.3
  TOP w0.102: CR34.1 287.59,24.71 287.59,22.44 v4(287.63,22.4)
  IN2 w0.762: 289.49,24.68 289.49,22.69 293.3,18.88 293.3,17.45 294.02,16.74 297.3,16.74 297.99,17.42
  vias: v2(289.06,26) v2(289.07,25.37) v2(297.7,18.08) v2(298.33,18.08)
+1.35V_MEM: length 95.8
  TOP w0.508: RD22.1 160.91,22.65 ; 99.76,8.1 91.78,8.1 91.15,8.74 RD2.1 ; RD4.1 81.3,15.29 82.78,16.76 85.84,16.76 86.83,17.75 86.83,21.17
  BOTTOM w0.178: UC1.AY40 146.78,50.08 147.26,49.6 v2(147.28,49.6) ; v2(150.62,55.03) 150.88,55.29 UC1.AN33
  BOTTOM w0.203: UC1.AR48 141.86,53.99 v2(141.54,53.66)
  BOTTOM w0.254: v2(144.08,50.29) 143.64,50.74 UC1.AY44 ; v2(150.37,50.22) 149.93,50.65 UC1.AY35 ; v2(144.39,54.31) 144.72,54.64 UC1.AP43 ; UC1.AY50 140.49,50.88 v2(140.88,50.49)
  BOTTOM w0.279: v2(151.47,58.75) 151.47,58.65 151.01,58.19 UC1.AJ33 ; v2(152.76,58.75) 152.76,58.64 152.31,58.19 UC1.AJ31 ; v2(154.99,58.47) 155.32,58.47 UC1.AH26 ; UC1.AJ37 148.6,57.89 v2(148.86,57.63)
  BOTTOM w0.356: JDIMM1.123 118,17.99 v2(118.02,18.01) ; JDIMM2.88 189,8.23 v2(189,6.6) ; JDIMM1.93 109,17.73 v2(108.72,18.01) ; JDIMM2.111 195.9,17.62 v2(195.72,17.8) ; 118.09,6.84 118.3,7.05 JDIMM1.124 ; v2(107.75,14.26) 107.75,14.26 107.2,14.82 JDIMM1.87 ; v2(114.7,6.86) 114.7,6.86 JDIMM1.112 ; JDIMM1.81 105.4,17.94 v2(105.33,18.01) ; JDIMM1.118 v2(116.5,6.86) ; JDIMM2.75 185.1,17.59 v2(185.46,17.95) ; JDIMM2.118 v2(198,9.6) 199.58,9.6 199.8,9.38 JDIMM2.124 ; v2(116.57,18.01) 116.2,17.64 JDIMM1.117 ; v2(112.9,6.86) 112.9,6.86 JDIMM1.106 ; JDIMM1.111 114.4,17.79 v2(114.62,18.01) ; v2(190.11,14.3) 190.66,14.85 190.66,15.34 190.5,15.5 JDIMM2.93 ; JDIMM2.117 197.7,17.39 v2(197.26,17.83) ; JDIMM2.100 192.6,6.61 v2(192.6,6.6) ; v2(190.8,6.6) 190.8,6.61 JDIMM2.94 ; JDIMM1.88 107.5,6.88 v2(107.48,6.86) ; JDIMM2.87 188.7,16.43 188.7,17.56 188.43,17.83 v2(187.28,17.83) 186.9,17.45 JDIMM2.81 ; JDIMM1.94 v2(109.3,6.88) ; v2(199.31,17.88) 199.5,17.69 JDIMM2.123 ; v2(194.4,6.63) 194.4,6.63 JDIMM2.106 ; v2(112.6,14.26) JDIMM1.105 ; v2(103.9,6.86) 103.9,6.86 JDIMM1.76 ; JDIMM1.82 105.7,6.88 v2(105.7,6.88) ; 193.39,14.96 193.65,14.96 194.1,15.41 JDIMM2.105 ; JDIMM1.75 103.6,14.57 103.91,14.26 v2(104.2,14.26) ; JDIMM1.100 111.1,6.86 v2(111.1,6.86) ; 110.5,14.2 110.8,14.5 JDIMM1.99 ; v2(187.2,6.63) 187.2,6.63 JDIMM2.82 ; v2(196.17,6.63) 196.2,6.65 JDIMM2.112 ; JDIMM2.99 192.3,15.14 v2(192.49,14.96) ; JDIMM2.76 185.4,6.61 v2(185.4,6.6)
  vias: v2(109.84,14.26) v2(117.53,6.86) v4(141.26,35.88)
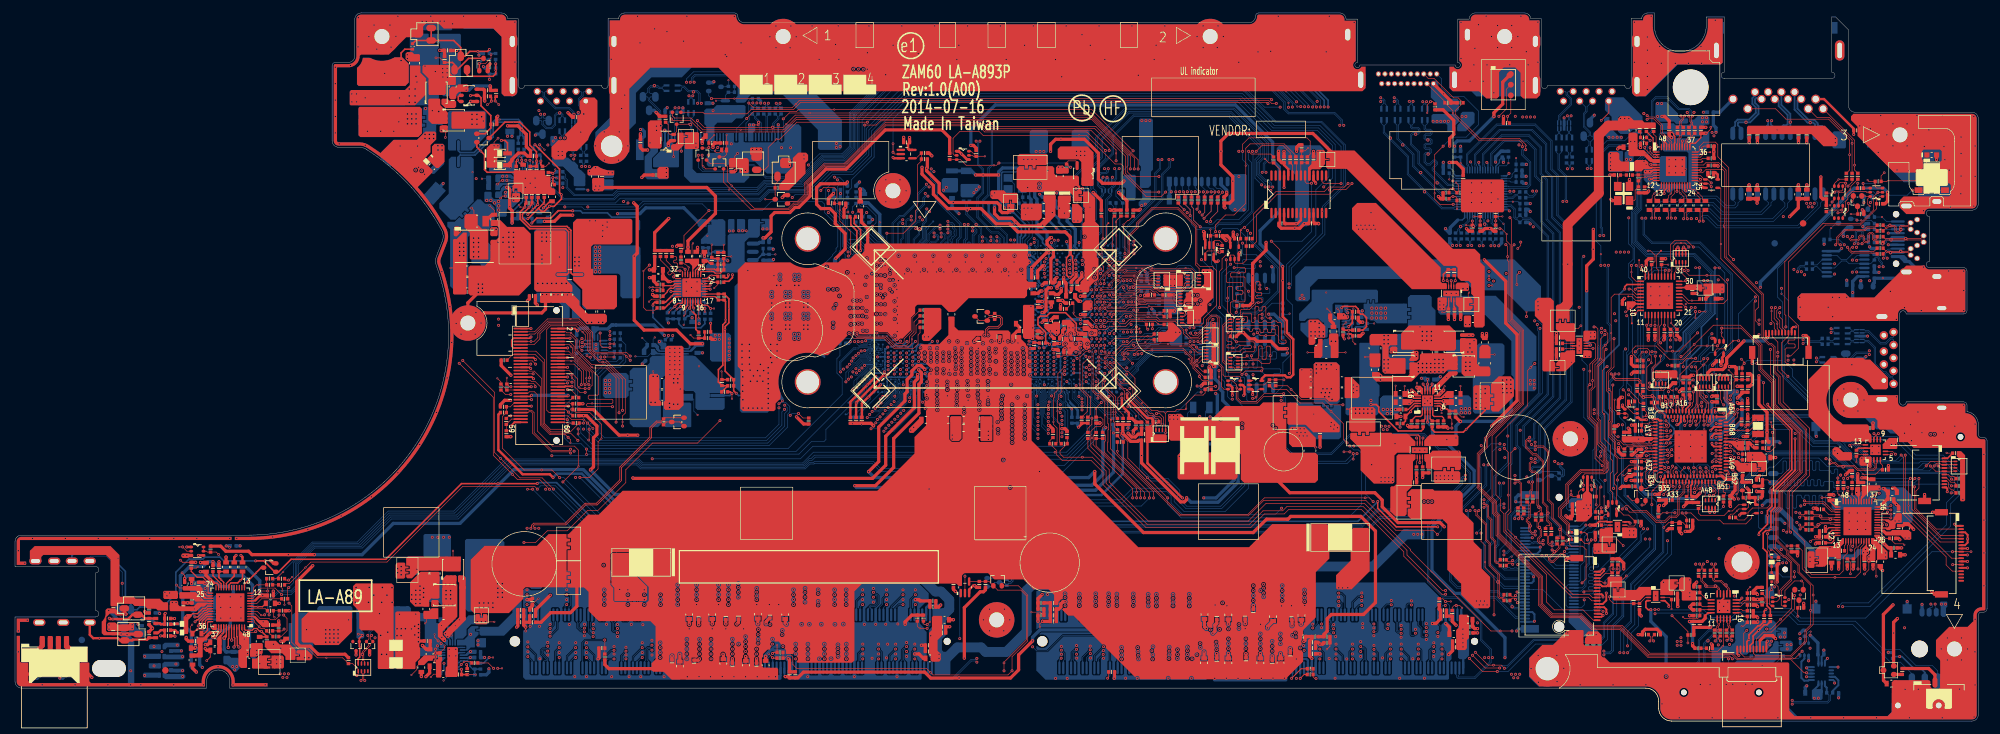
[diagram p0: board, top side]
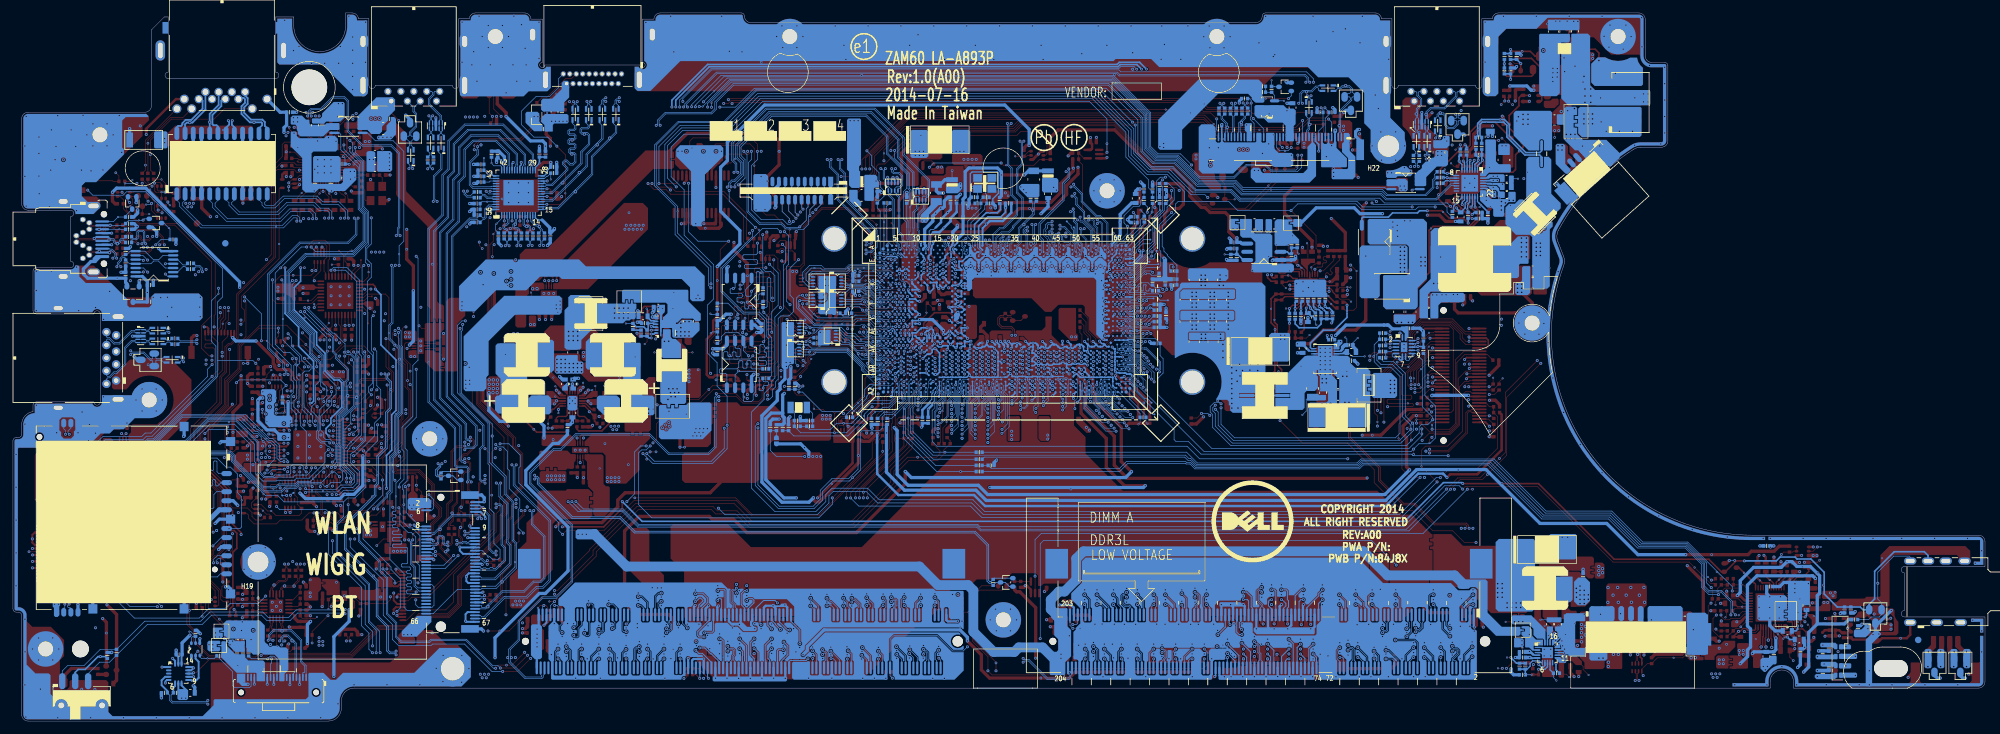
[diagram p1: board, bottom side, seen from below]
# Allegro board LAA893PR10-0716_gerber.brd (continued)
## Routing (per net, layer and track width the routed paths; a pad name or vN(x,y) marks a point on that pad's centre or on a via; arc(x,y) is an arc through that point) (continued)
+1.35V_MEN_P: length 22.8
  TOP w0.102: v1(73.86,9.83) v2(73.28,9.83)
  IN1 w0.508: v2(70.36,9.82) 71.24,9.82 72.81,11.38 72.81,14.35 73.85,15.39 v3(73.85,17.56)
  IN2 w0.254: v3(74.61,19.15) 74.61,15.39 73.28,14.06 v2(73.28,9.83)
  BOTTOM w0.254: PC213.2 PR205.2 72.4,8.95 v2(73.28,9.83)
  vias: v3(71.75,18.26) v3(71.75,17.56) v3(72.45,18.26) v3(72.45,17.56) v3(73.15,18.26) v3(73.15,17.56) v3(73.85,18.26) v3(74.61,21.25) v3(74.61,20.55) v3(74.61,19.85) v3(75.31,21.25) v3(75.31,20.55) v3(75.31,19.85) v3(75.31,19.15)
+3.3V_ALW: length 516.7
  TOP w0.254: v2(263.47,53.56) 263.47,53.4 263.27,53.2 RPE5.8 ; RPE9.6 257.68,73.11 v2(257.87,73.3) 258.18,73 RPE9.5 ; RPE3.7 260.85,53.23 v2(260.54,53.54) 260.35,53.35 RPE3.8 ; RPE6.8 262.73,32.37 v2(262.62,32.25) ; RPE6.7 262.23,32.57 v2(261.92,32.25) 261.73,32.44 RPE6.6 ; RPE9.8 256.68,73 v2(256.98,73.3) 257.18,73.11 RPE9.7 ; v2(205.03,63.93) 205.22,64.12 207.16,64.12 207.58,63.7 PR306.1 207.94,62.93 208.3,62.93 208.85,62.38 208.85,61.01 208.29,60.45 PR315.1
  TOP w0.305: 269.66,12.46 269.65,12.45 JLED1.8 ; v2(245.91,19.8) 245.91,18.66 245.35,18.1 JKBTP1.11
  TOP w0.381: UC8.5 138.18,88.32 138,88.51 138,89.23 CC35.1 ; v2(247.5,32.8) UZ11.5 ; CZ48.1 263.84,56.24 264.03,56.44 UZ10.5 ; UZ6.5 268.91,33.66 CZ34.1
  TOP w0.508: RC213.1 174.09,44.37 RC217.1 173.56,44.37 173.12,43.93 172.57,43.93 172.02,44.47 v2(172.02,44.51) ; CC35.1 v2(138.24,90.23) ; RE68.1 247.79,49.67 248.18,50.06 v2(248.41,50.06) ; RE36.1 RE79.1 259.01,53.47 v2(259.38,53.47) ; v2(249.78,56.36) 249.78,55.22 250.14,54.86 RE25.1 ; v2(272.31,21.51) 272.31,24.13 RZ24.1 ; RE8.1 254.89,59.05 v2(254.77,58.94) ; v2(249.74,37.21) 250.4,37.21 RE69.1 ; RE83.1 261.27,65.39 262.07,66.19 ; v2(257.29,58.94) 257.29,59.21 RE84.2 ; PR2.1 50.99,10.34 46.84,10.34 45.6,11.57 44.04,11.57 43.53,12.08 43.53,21.55 v2(46.01,24.03) ; RE35.1 253.97,33.2 v2(254.12,33.35) ; RE11.1 v2(252.41,58.9) ; v2(266.16,49.25) 266.31,49.11 RE81.1 ; v2(223.38,46.34) 223.3,46.34 PR107.1 ; CZ34.1 RZ22.1 267.98,35.69 v2(267.64,36.03) ; 269.66,12.46 270.42,13.22 271.59,13.22 v2(272.06,12.75) ; v2(289.37,81.77) 289.37,80.4 288.96,79.99 RZ31.1 ; CZ48.1 263.64,55.47 v2(263.64,54.99) ; v2(255.29,29.45) 255.62,29.77 RE63.1
  IN1 w0.508: v2(99.12,91.99) 99.56,92.43 103.16,92.43 104.44,93.71 108.94,93.71 111.47,96.24 132.23,96.24 v2(138.24,90.23) ; v2(245.91,19.8) 246.42,20.31 246.42,22.44 246.25,22.61 246.25,24.47 249.5,27.72 v2(249.5,28.76) ; v2(72.39,101.19) 71.88,100.69 71.88,97.7 73.07,96.51 74.62,96.51 75.35,95.78 76.15,95.78 80.32,91.6 81.09,91.6 82.26,90.44 82.26,89.17 v2(82.34,89.08) ; 222.32,66.93 219.86,66.93 219.42,66.48 206.03,66.48 205.03,65.48 v2(205.03,63.93) ; v2(301.01,34.28) 300.94,34.2 300.94,15.65 299.72,14.43 v2(292,14.43) ; v2(99.13,91.34) 99.51,90.96 99.51,81.58 97,79.07 92,79.07 91.76,78.83 88.32,78.83 86.06,81.09 78.56,81.09 77.53,80.06 77.53,77.28 78.72,76.09 78.72,67.51 74.71,63.5 v2(74.71,62.15) ; v2(272.06,12.75) 272.06,15.46 272.84,16.24 272.84,20.98 v2(272.31,21.51) 271.09,22.73 271.09,27.62 270.19,28.52 270.19,31.98 v2(269.92,32.24)
  IN1 w1.016: 225.64,66.16 229.54,62.27 229.54,54.04 229.91,53.67
  IN1 w2.032: 233.84,91.77 235.66,89.95 235.66,86.45 241.72,80.39 241.72,75.54 244.74,72.52 245.96,72.52 245.97,72.5
  IN2 w0.508: v2(74.71,62.15) 73.92,61.37 73.92,59.14 68.23,53.45 68.23,45.48 46.78,24.03 v2(46.01,24.03) ; v2(272.06,12.75) 272.06,13.19 273.25,14.39 291.96,14.39 v2(292,14.43) ; v2(245.91,19.8) 245.03,20.68 241.98,20.68 240.96,21.7 234.43,21.7 233.2,22.93 195.64,22.93 184.59,33.98 184.59,34.59 181.54,37.64 179.16,37.64 173.14,43.66 172.87,43.66 v2(172.02,44.51) ; v2(269.72,67.08) v2(263.8,67.08)
  BOTTOM w0.508: v2(72.39,101.19) 72.59,100.99 PR8.2 ; v3(231.2,50.77) 231.2,48.02 229.52,46.34 v2(223.38,46.34) 222.68,45.64 v2(222.68,43.77) ; v2(269.72,67.08) 269.72,67.91 284.22,82.41 288.73,82.41 v2(289.37,81.77)
  vias: v2(232.99,93.41) v2(233.59,93.41) v2(234.19,93.41) v2(234.82,93.41) v2(242.68,56.36) v2(243.26,56.36) v2(243.51,60.02) v2(243.49,59.41) v2(244.08,59.41) v2(247.44,72.52) v2(248.08,72.52) v2(248.71,72.52) v2(249.35,72.52) v2(249.51,29.42) v2(250.14,29.42) v2(250.12,28.78) v2(263.8,66.5) v2(268.51,41.13) v2(268.51,40.49) v3(223.76,66.86) v3(224.43,66.84) v3(229.88,52.73) v3(229.88,52.08) v3(229.88,51.41) v3(229.93,50.77) v3(230.52,52.76) v3(230.52,52.08) v3(230.52,51.41) v3(230.57,50.77) v3(231.15,52.76) v3(231.15,52.08) v3(231.15,51.41) v4(98.13,89.41) v4(221.27,43.54) v4(244.1,60.1)
+3.3V_ALW2: length 233.6
  TOP w0.203: PU100.3 v2(218.28,46.22)
  TOP w0.381: UC6.5 192.68,52.96 193.18,53.45 196.25,53.45 196.54,53.16 197.11,53.16 197.53,53.58 197.53,59.04 196.54,60.03 196.54,61.9 195.91,62.53 v4(195.91,68.12) v2(195.91,70.28)
  TOP w0.508: RZ16.1 148.54,88.59 148.12,89.01 v2(147.71,89.01) ; v2(269.49,53.4) 269.49,49 270.75,47.74 v2(270.75,44.65) 270.75,43.47 271.01,43.2 RE57.2 ; v2(227.06,71.32) 230.38,68.01 230.38,61.53 232.12,59.79 232.12,49.54 v2(228.19,45.62)
  IN1 w0.508: v2(227.06,71.32) 218.21,71.32 217.17,70.28 v2(195.91,70.28)
  IN2 w0.508: v2(218.28,46.22) 222.32,46.22 222.92,45.62 v2(228.19,45.62) 228.23,45.58 231.61,45.58 237.03,51 240.9,51 245.55,55.65 248.05,55.65 248.5,55.21 252.65,55.21 253.27,55.83 254.84,55.83 255.98,56.97 259.76,56.97 260.35,56.39 260.35,55.68 261.82,54.2 268.69,54.2 v2(269.49,53.4)
  BOTTOM w0.508: PR103.2 218.67,45.84 v2(218.28,46.22) 218.3,46.24 PC100.2 ; v2(147.71,89.01) 147.71,91.5 151.47,95.26 188.59,95.26 194.35,89.51 194.35,86.68 195.39,85.64 195.39,78.82 192.42,75.84 192.42,73.77 v2(195.91,70.28)
+3.3V_ALW_DEG: length 2.6
  TOP w0.102: v1(298.5,41.48) 298.55,41.43 RE71.2
  TOP w0.254: JDEG1.1 298.65,40.63 RE71.2
+3.3V_ALW_PCH: length 290
  TOP w0.305: JAPS1.1 300,30.19 v2(299.74,30.44)
  TOP w0.381: v2(83.14,37.67) 82.65,38.16 78.45,38.16 74.7,41.91 74.7,47.39 RC120.2
  TOP w0.508: RC79.1 171.19,45.83 v2(171.19,44.51) 171.21,44.5 171.21,44.45 172.4,43.26 173.5,43.26 173.66,43.42 RC216.1 v4(174.09,41.06) 174.09,39.93 180.12,33.9 180.71,33.9 181.05,34.24 v2(181.05,34.52) ; RC79.1 171.25,45.87 RC212.1 ; RC79.1 RC245.2
  IN1 w0.508: v2(289.48,10.63) 289.48,13.36 291.34,15.21 299.41,15.21 300.19,15.99 300.19,29.99 v2(299.74,30.44) 295.73,34.46 295.73,37.2 294.07,38.86 294.07,40.2 290.59,43.67 284.53,43.67 280.95,47.26 280.95,50.89 272.53,59.31 272.53,60.29 v2(271.35,61.47)
  IN2 w0.076: 167.32,64.03 167.32,63.61 ; 168.18,60.59 168.62,60.59 168.73,60.71 ; 168.03,64.02 168.03,63.6
  IN2 w0.508: v2(271.35,61.47) 270.18,62.64 251.69,62.64 249.87,64.45 246.71,64.45 246.33,64.83 v2(235.34,64.83)
  BOTTOM w0.229: v2(162.34,58.35) 162.66,58.03 UC1.AH14
  BOTTOM w0.254: v2(160.96,60.4) v2(160.96,59.81) 160.59,59.81 160.08,60.33 v2(160.02,60.33) 159.95,60.33 UC1.AE20 159.2,59.58 UC1.AE21 ; UC1.AC9 UC1.AA9 164.79,61.93 v2(164.64,62.08)
  BOTTOM w0.381: v2(171.19,44.51) 171.19,38.24 167.9,34.95 156.22,34.95 154.52,33.25 92.61,33.25 87.59,38.26 83.74,38.26 v2(83.14,37.67)
  BOTTOM w0.508: RC2.1 289.51,10.6 v2(289.48,10.63) ; v2(185.23,54.84) 185.44,54.62 185.44,52.91 186.2,52.15 186.2,51.32 186.64,50.89 186.64,49.58 189.01,47.21 189.01,36.94 185.91,33.84 181.72,33.84 v2(181.05,34.52) ; v2(160.96,60.4) 162.65,62.08 v2(164.64,62.08)
  vias: v2(179.38,60.11) v2(179.99,60.11) v2(184.64,55.45) v2(185.16,61.45) v2(185.15,60.86) v2(185.2,58.14) v2(185.27,55.45) v2(198.6,65.34) v2(198.89,65.85) v2(199.18,65.33) v2(235.37,64.21) v2(235.38,63.6)
+3.3V_ALW_PCH_UZ2:
  vias: v1(240.55,55.49)
+3.3V_ALW_UE2: length 64.7
  TOP w0.254: UE2.A11 257.69,48.56 v2(257.74,48.61) 257.99,48.86 257.99,50.26 CE13.1 ; CE16.1 251.95,41.71 UE2.A26 ; CE19.1 258.99,34.93 258.99,36.45 259.19,36.65 UE2.A41
  TOP w0.279: UE2.B3 261.94,46.48 v2(261.86,46.41)
  TOP w0.305: 254.7,37.38 254.94,37.62 UE2.B35
  TOP w0.381: 254.7,37.38 254.7,35.81 254.05,35.16 CE22.1
  TOP w0.508: v2(262.23,49.4) 262.28,49.35 CE17.1 ; CE16.1 251.24,41.01 v2(250.68,41.01) ; CE22.1 254.03,35.06 v2(253.41,35.06) ; v2(260.39,35.24) 259.83,34.68 259.24,34.68 CE19.1
  IN1 w0.508: v2(266.14,50.91) 266.51,50.91 266.91,50.51 266.91,46.52 266.38,45.99 266.38,43.46 266.18,43.25 v2(266.18,42.54) 266.89,42.54 267.66,41.77 v2(267.66,39.63)
  IN1 w0.762: v2(250.91,43.6) 251.34,43.17 251.34,41.4 250.95,41.01 v2(250.68,41.01)
  IN2 w0.508: v2(260.39,35.24) 260.78,35.24 263.15,37.62 265.97,37.62 267.66,39.3 v2(267.66,39.63) ; v2(257.74,48.61) 258.39,47.95 260.78,47.95 v2(262.23,49.4)
  BOTTOM w0.508: v2(260.39,35.24) 259.55,34.4 254.21,34.4 253.56,35.06 v2(253.41,35.06) 252.03,35.06 250.68,36.41 v2(250.68,41.01) ; v2(262.23,49.4) 262.23,46.77 v2(261.86,46.41)
  vias: v4(265.67,40.03)
+3.3V_ALW_UE3: length 14.9
  TOP w0.102: v2(249.58,63.84) 249.02,63.28 v4(248.88,63.28)
  IN1 w0.508: v2(249.58,63.84) 250.73,63.84 251.58,62.99 256.37,62.99 257.16,63.78 257.16,66.53 257.63,67 v2(259.92,67)
+3.3V_ALWP: length 10.5
  TOP w0.254: v3(227.19,48.36) 227.19,48.05 v4(224.26,45.12) 223.81,44.68 219.38,44.68 219,45.07 PR100.1
  vias: v3(225.79,50.59) v3(225.79,49.89) v3(225.79,49.19) v3(225.79,48.5) v3(226.45,49.17) v3(226.49,51.29) v3(226.49,50.59) v3(226.49,49.89) v3(226.49,48.5) v3(227.19,51.38) v3(227.19,50.67)
+3.3V_CAM: length 1.3
  TOP w0.102: v4(111.66,87.78) 111.22,87.35 111.22,86.64
  vias: v2(112.29,85.15) v2(112.89,85.15)
+3.3V_HDD: length 14.4
  TOP w0.254: v2(266.86,19.02) 266.58,18.74 UN2.20 ; 261.19,16.28 261.65,16.74 UN2.10
  TOP w0.508: v2(269.29,17.7) 269.05,17.94 RN12.2 ; RN8.2 258.8,16.31 v2(258.79,16.29) ; v2(269.26,19.58) 269.06,19.79 RN14.1 268.62,20.09 269.19,20.66 RN24.1 ; RN22.1 259.24,11.65 v2(259.24,11.98) ; v2(258.76,15.4) CN29.1 CN24.1 260.7,15.4 261.19,15.89 261.19,16.28 ; RN20.1 269.24,15.28 v2(269.3,15.34)
  BOTTOM w0.508: v2(259.24,11.98) 259.24,14.92 v2(258.76,15.4)
  vias: v2(258.81,19.82) v2(258.81,19.24) v4(258.8,21.83)
+3.3V_LAN: length 97.2
  TOP w0.381: JLOM1.12 279.56,96.18 284.15,91.59 CL19.1 v2(284.15,90.72) ; CL15.1 262.82,84.81 263.13,84.51 UL2.5
  TOP w0.508: RL2.1 262.52,88.86 v2(262.52,88.02) 262.52,87.07 RL1.1 ; CL15.1 262.51,84.8 v2(262.51,84.19) ; RL30.1 RL29.1 279.36,80.73 279.07,81.03 v2(279.07,84.14)
  TOP w1.524: 239.19,63.79 239.19,63.79 239.94,64.54 v4(239.94,70.65) 239.94,76.81 244.75,81.62 244.75,90.63 246.21,92.09 248.6,92.09
  IN1 w1.524: 249.86,92.14 250.42,91.58 257.69,91.58 259.57,89.7 261.41,89.7
  IN2 w0.381: v2(284.15,90.72) 284.15,85.47 282.81,84.14 v2(279.07,84.14) 263.87,84.14
  BOTTOM w0.508: JLOM1.9 263.45,94.14 CL18.1 262.46,92.16 262.86,91.76 v2(262.86,91.03)
  vias: v2(248.12,93.17) v2(248.75,93.17) v2(249.39,93.17) v2(262.25,91.02) v2(262.54,90.5)
+3.3V_LAN_OUT: length 3.2
  TOP w0.203: UL1.15 255.23,82.37 254.86,82 v2(254.86,81.58) ; UL1.19 v2(256.83,81.91) ; UL1.29 v2(260.49,85.19)
  vias: v1(252.07,87.71) v2(249.69,89.61) v2(250.3,89.61)
+3.3V_LAN_UZ2: length 1.4
  TOP w0.102: 240.73,60.69 241.55,60.69 v4(241.98,61.12)
+3.3V_M: length 78.2
  TOP w0.508: v2(186.99,79.37) 186.86,79.49 RC231.1 187.71,80.11 188.19,80.58 v4(188.19,83.49) 188.19,84.18 186.35,86.01 v2(186.35,88.11) 186.35,89.69 187.53,90.87 200.56,90.87 203.69,87.73
  IN1 w0.508: v2(166.44,62.9) 166.31,62.9 165.68,63.52 165.68,67.49 165.24,67.93 165.24,68.39 166.23,69.38 166.23,70.15 166.52,70.43 166.52,75.06 167.84,76.38 167.84,76.84 168.12,77.12 168.12,79.47 168.76,80.1 168.76,82.61 167.53,83.84 167.53,85.45 169.35,87.27 174.03,87.27 174.62,87.87 186.12,87.87 v2(186.35,88.11)
  BOTTOM w0.254: UC1.Y8 166.2,62.65 v2(166.44,62.9)
  BOTTOM w0.508: v2(186.99,79.37) 186.88,79.48 JSPI1.16
+3.3V_M_TPM: length 13.3
  TOP w0.381: CZ6.1 196.1,86 196.76,85.34 UZ1.24 ; UZ1.10 200.01,77.06 CZ5.1 ; CZ4.1 195.46,77.09 UZ1.3
  TOP w0.508: CZ6.1 195.77,86.34 195.26,86.84 v2(195.26,88.11) ; CZ4.1 195.33,76.56 195.68,76.21 v4(197.76,76.21) 198.54,76.21 v2(199.24,76.91) 199.24,76.91 199.86,76.91 CZ5.1
  vias: v2(201.36,88.1) v2(201.97,88.1)
+3.3V_M_UZ8: length 1
  TOP w0.102: v1(224.7,66.27) 224.57,66.14 224.57,65.32
+3.3V_MMI: length 6.8
  TOP w0.102: v2(286.48,24.82) 286.48,23.42 v4(285.8,22.73)
  TOP w0.203: UR1.11 281.04,29.11 v2(280.81,28.87) ; CR2.1 280.3,29.91 UR1.9
  TOP w0.508: CR2.1 v2(279.78,30.07) ; RR6.1 v2(283.16,23.52)
  vias: v2(280.48,26.83) v2(281.11,26.83) v2(281.68,27.09) v2(284.59,35.35) v2(286.5,25.4) v2(292.1,28.31) v2(292.69,28.31)
+3.3V_RTC_LDO: length 119.7
  TOP w0.508: v2(290.89,15.85) 290.31,15.26 v4(290.31,13.61) 290.31,8.55 PD3.3
  IN2 w0.508: v2(230.25,9.8) 232,11.56 238.67,11.56 242,8.23 265.63,8.23 270.38,12.98 270.97,12.98 273,15.01 290.05,15.01 v2(290.89,15.85)
  BOTTOM w0.508: v2(230.25,9.8) 230.25,12.89 223.4,19.74 222.46,19.74 218.97,23.22 218.97,30.02 225.49,36.53 225.49,38.74 221.29,42.94 220.43,42.94 219.06,44.31 PR103.1
+3.3V_RUN: length 289.9
  TOP w0.203: v2(107.43,66.78) 107.37,66.83 PU500.20 ; PU500.21 107.25,67.23 v2(107.43,67.41)
  TOP w0.254: RPE3.6 261.35,53.33 261.58,53.57 261.85,53.3 RPE3.5
  TOP w0.305: JLPDE1.1 270.56,59.54 v2(270.81,59.28) 271.06,59.53 JLPDE1.2
  TOP w0.381: UC5.5 187.81,73.97 187.75,74.03 187.75,74.6 ; UC4.5 185.23,71.3 185.52,71.01 185.79,71.01 v2(185.94,71.16) ; v2(189.88,50.37) 189.99,50.48 189.99,51.68 189.7,51.97 QC1.5 ; QC1.2 187.74,51.97 188.12,51.59 v2(188.12,50.38)
  TOP w0.508: MIC1.6 229.91,98.81 229.91,95.43 228.55,94.07 v2(228.55,93.48) ; v2(179.16,63.39) 179.11,63.44 RC180.1 RC66.1 ; v2(174.55,65.84) 175.12,65.84 RC156.2 ; RZ9.1 254.26,13.69 253.76,14.2 251.93,14.2 251.51,13.78 RZ8.1 v2(250.84,13.37) ; CD63.1 CD64.1 222.04,16.24 RD27.2 222.1,15.42 v2(222.69,14.82) ; RE51.1 247.58,45.62 v2(247.77,45.81) ; RV68.1 224.67,75.77 v2(224.3,76.14) ; v2(219.96,81.11) 220.3,80.76 RV56.1 220.69,80.76 RV55.1 ; RV58.1 226.77,75.77 227.16,76.16 v2(227.89,76.16) 228.1,76.16 228.5,75.77 RV60.1 ; RC164.1 173.73,79 v2(173.88,79.15) ; v2(249.5,48.78) 249.36,48.92 RE67.1 ; RV8.1 220.69,94.52 222.34,92.87 222.34,90.73 221.7,90.09 v2(221.7,88.91) ; CD31.1 CD32.1 142.73,17.63 v2(143.05,17.95) ; RC122.1 89.37,48.18 93.34,44.21 v4(94.68,44.21) v2(96.24,44.21) ; PR516.2 98.73,68.01 PR519.2 v2(98.03,68.56) ; CC64.1 160.56,66.15 160.75,65.96 CC66.1 161.22,65.96 161.67,66.41 v2(161.67,66.87) ; RE48.1 248.35,41.16 247.8,41.71 v2(247.8,42.29) ; 187.75,74.6 187.31,75.04 RC95.1 186.56,74.89 v2(187.14,74.31) ; 261.58,53.57 261.58,53.83 262.1,54.36 263.9,54.36 264.3,54.75 264.3,55.04 264.51,55.26 264.51,56.11 v2(267.18,58.78) ; v2(169.19,79.1) 169.28,79 RC176.1 169.9,79.01 RC163.1 ; CC96.2 96.64,88.66 97,88.3 v2(97.76,88.3) ; v2(183.3,51.82) 183.7,52.22 RC247.2 ; v2(221.64,86.38) 222.76,86.38 223.8,85.34 CV61.1
  IN1 w0.508: v2(96.24,44.21) 99.51,40.93 99.51,39.69 115.76,23.44 115.76,17.06 115.44,16.74 115.44,14.74 115.94,14.25 116.8,14.25 117.8,13.25 117.8,12.38 v2(118.67,11.52) ; v2(286.59,73.33) v2(286.59,68.1) ; v2(247.93,19.18) 249.97,17.13 249.97,16 250.84,15.14 v2(250.84,13.37) 249.82,12.36 247.11,12.36 246.82,12.06 242.49,12.06 241.82,12.74 241.82,14.31 239.2,16.93 231.3,16.93 229.56,15.19 v2(226.01,15.19)
  IN2 w0.508: v2(281.72,8.35) 281.72,11.05 280.93,11.84 277.98,11.84 v2(277.4,11.26) ; v2(222.69,14.82) 223.06,15.19 v2(226.01,15.19) ; v2(143.05,17.95) 143.05,15.47 140.43,12.85 137.59,12.85 137.34,12.6 119.74,12.6 v2(118.67,11.52)
  BOTTOM w0.203: 222.97,77.48 223.67,77.48 224.02,77.83 UV7.14 ; CV62.1 222.34,84.98 222.34,84.63 222.66,84.31 UV7.28 ; CV66.1 229.4,86.76 229.4,86.36 228.82,85.78 UV7.41
  BOTTOM w0.254: UC1.K14 UC1.K16 161.99,67.18 v2(161.67,66.87) ; RPC2.6 164.2,82.12 v2(163.95,82.37) 163.7,82.12 RPC2.5 ; v2(169.59,84.09) 169.48,83.97 RPC20.8 ; UV7.56 230.71,79.11 v2(230.92,78.89) ; UC1.T9 v2(166.27,64.79) 166.27,64.39 UC1.U8 ; RPC2.8 165.2,82.13 v2(164.96,82.37) 164.7,82.1 RPC2.7 ; v2(166.3,63.84) 166.3,63.46 UC1.V8 165.75,62.91 UC1.W9 ; JDIMM2.199 222.3,15.21 v2(222.69,14.82) ; v2(168.13,84.1) 167.98,83.94 RPC20.5 ; v2(102.97,88.12) 102.97,89.18 103.46,89.67 JEDP1.10
  BOTTOM w0.305: UN1.8 278.69,5.51 278.05,4.87 CN1.1 ; CN2.1 278.69,10.18 278.69,8.83 UN1.14 ; UN1.7 279.19,5.87 279.19,4.5 RN3.1 ; UN1.1 v2(281.72,8.35)
  BOTTOM w0.356: v2(143.05,17.95) 141.21,17.95 140.8,17.54 JDIMM1.199
  BOTTOM w0.381: UV502.14 284.75,68.76
  BOTTOM w0.457: v2(174.55,65.84) 174.98,66.28 RC68.1
  BOTTOM w0.508: v2(286.59,73.33) 286.85,73.08 RV501.1 ; v2(277.4,13.28) 278.61,12.08 CN2.1 ; RN2.1 276.32,14.03 v2(275.8,13.51) ; v2(270.81,59.28) 270.3,58.78 v2(267.18,58.78) ; PR400.1 117.06,73.07 v2(117.17,72.96) ; 222.97,77.48 221.79,76.3 221.79,75.56 CV69.1 221.66,75.48 221.07,76.07 v2(221.07,76.15) ; v2(228.55,93.48) 224.77,89.71 222.88,89.71 222.46,89.29 v2(222.46,88.9) 222.46,88.14 RV54.1 ; RV515.1 RV57.1 233.83,79.12 v2(234.16,78.79) ; CV62.1 v2(221.64,86.38) ; RV51.1 RV511.1 v2(233.53,84.24) ; CC85.2 144.79,79.55 v2(145.88,78.46) ; 284.75,68.76 283.98,68 CV514.1 v2(283.98,66.27) CV510.1 284.04,64.81 UV501.1 ; v2(230.01,86.4) 230.01,86.91 229.84,87.08 CV66.1 ; RC160.1 RC158.1 174.94,69.23 v2(174.64,69.53) ; 89.96,60.64 91.59,60.64 92.18,61.24 92.36,61.24 92.36,61.24 92.87,61.24 92.87,61.24 98.74,61.24 v2(100.34,59.64) ; RC302.1 183.72,52.23 v2(183.3,51.82) ; RN4.1 v2(281.81,3.59) ; RV507.1 v2(279.56,73.72)
  vias: v2(113.97,88.37) v2(114.6,88.37) v2(115.24,88.37) v2(115.57,76.11) v2(116.2,76.11) v2(121.92,87.52) v2(121.93,86.93) v2(178.6,68.33) v2(178.61,67.36) v2(179.18,68.33) v2(179.19,67.36) v2(182.38,62.01) v2(182.98,62.01) v2(183.66,69.53) v2(184.25,69.53) v2(219.64,37.92) v2(219.64,37.32) v2(220.25,37.92) v2(220.25,37.32) v2(220.89,37.92) v2(220.89,37.32) v2(221.54,37.92) v2(221.54,37.32) v2(222.13,37.92) v2(222.13,37.32) v2(224.19,61.32) v2(224.77,61.32) v2(272.82,13) v2(273.45,13.63) v2(273.45,13) v2(277.39,25.34) v2(277.39,24.68) v2(278.05,3.54) v2(278.69,3.54) v3(44.75,9.8) v3(45.41,9.79)
+3.3V_RUN_AUDIO: length 50.1
  TOP w0.508: RA4.1 27.43,8.18 v2(28.03,7.58) ; RA45.2 v2(30.59,24.65)
  IN1 w0.508: v2(41.07,11.26) 40.29,12.04 40.29,13.4 v2(38.35,15.35) 37.84,15.86 37.84,18.99 v2(38.27,19.43)
  BOTTOM w0.508: v2(28.03,7.58) 27.24,8.37 27.24,13.7 25.92,15.02 ; RA1.1 21.05,15.7 21.73,15.02 25.92,15.02 ; 25.92,15.02 25.92,19.39 25.55,19.76 25.55,22.47 27,23.91 29.08,23.91 29.82,24.65 v2(30.59,24.65) 31.48,23.76 35.77,23.76 37.82,21.72 37.82,19.88 v2(38.27,19.43)
  vias: v4(39.94,11.87)
+3.3V_RUN_CARD: length 17.2
  BOTTOM w0.762: JSD1.4 272.85,32.67 274.46,31.06 274.46,30.18 275.17,29.47 275.17,28.97 278.72,25.41 284.2,25.41 284.86,26.07
  vias: v2(285.67,26.03) v2(286.26,26.03) v4(285.96,26.52)
+3.3V_RUN_UN3:
  vias: v4(254.76,21.46)
+3.3V_RUN_UZ9:
  vias: v1(223.06,41.63)
+3.3V_SPI: length 46.2
  TOP w0.508: RC29.1 190.72,64.24 v2(191.26,64.79) v4(191.26,68.86) 191.26,70.75 193.33,72.82 v2(193.33,74.03) ; RC31.1 189.32,60.08 v2(189.8,60.08) 190.78,59.11 191.55,59.11 191.93,58.72 194.08,58.72 195.23,57.57 v2(196.61,57.57) ; v2(187.25,81.78) 187.25,81.41 186.87,81.03 RC231.2
  IN1 w0.508: v2(191.26,64.79) 190.56,64.09 190.56,61.94 189.8,61.18 v2(189.8,60.08) ; v2(187.25,81.78) 187.25,80.58 187.89,79.93 187.89,78.87 189.25,77.51 190.37,77.51 191.55,76.33 191.55,75.8 v2(193.33,74.03)
  BOTTOM w0.508: v2(196.61,57.57) CC7.1 194.99,57.57 194.42,58.14 UC3.8 ; v2(187.25,81.78) 187.25,82.08 186.38,82.94 JSPI1.15 ; UC2.8 190.11,61.25 189.63,60.78 189.32,60.78 CC6.1 189.04,60.26 189.21,60.08 v2(189.8,60.08)
+3.3V_TP: length 2.9
  TOP w0.102: v4(249.01,22.45) 248.5,21.95 248.21,21.95
  TOP w0.305: 246.21,21.1 245.95,20.84 245.27,20.84 245.01,21.1 JKBTP1.5
+3.3V_TSP:
  vias: v2(100.66,84.84) v2(100.66,84.2) v2(119.69,86.52) v2(119.69,85.93) v4(100.66,85.45)
+3.3V_WLAN: length 7
  IN1 w2.032: 243.9,17.45 243.9,24.42
  vias: v2(242.44,32.85) v2(242.82,33.4) v2(243.1,32.85) v2(243.16,13.36) v2(243.47,33.4) v2(243.75,13.36) v2(244.17,26.26) v2(244.33,13.36) v2(244.75,26.26) v2(245.34,26.26) v2(245.92,26.26) v4(243.18,31.8)
+3.3V_WLAN_UZ3: length 2.2
  TOP w0.102: 246.78,28.16 247.51,28.16 v4(248.52,27.14)
+3V5V_PWR_SRC: length 12.2
  TOP w0.203: v2(219,52.12) 219,51.92 218.68,51.61 PU100.12
  IN2 w0.508: v2(219,52.12) 220.54,52.12 221.35,52.92 221.35,57.04 219.53,58.85 v3(218.87,58.85)
  BOTTOM w0.508: v2(219,52.12) 219.44,51.67 PC117.1
  vias: v3(217.48,60.24) v3(217.47,59.54) v3(217.47,58.85) v3(218.17,59.54) v3(218.17,58.85) v3(218.18,60.24) v3(218.87,59.54) v3(218.88,60.24) v4(217.12,60.96)
+5V_ALW: length 268.3
  TOP w0.203: UZ9.4 217.09,43.99 216.84,44.24 215.22,44.24 215.21,44.25 ; UZ2.4 243.35,58.02 v2(243.48,58.15) ; UZ8.4 v2(221.94,68.1)
  TOP w0.254: v2(252.79,17.22) 252.38,17.22 252.03,17.58 252.03,18.47 252.18,18.62 UN3.4 ; v2(249.59,30.61) 249.4,30.8 UZ3.4
  TOP w0.305: v2(266.39,10.15) 266.15,10.39 JLED1.1
  TOP w0.508: PR526.1 v2(104,73.29) 104,74.26 108.24,78.5 108.24,81.18 106.91,82.51 90.89,82.51 ; RI13.2 v2(289.51,39.5) ; v2(79.18,64.97) 79.5,65.29 CC95.2 ; v2(243.9,76.03) v4(243.9,72.96) 243.9,71.42 242.87,70.4 v2(242.87,66.53) ; LED3.2 v2(296.95,86.79) ; RZ21.1 269.12,37.5 v2(269.58,37.96) ; v2(63.5,6.87) 64.07,7.44 PR202.1 ; RZ5.1 144.44,90.21 143.23,91.41 134.48,91.41 128.42,85.35 125.31,85.35 122.86,82.89 122.86,81.17 121.11,79.43 120.54,79.43 119.75,78.64 117.4,78.64 116.84,78.08 116.84,75.65 115.91,74.72 v2(115.6,74.72) ; RD9.1 149.97,20.3 149.65,19.98 149.15,19.98 146.7,17.54 v2(146.7,9.73) ; v3(65.64,103.71) 66.35,103.71 PC20.1 66.38,103.68 PR11.1 ; PR204.2 v2(62.79,6.88)
  IN1 w0.508: v2(243.9,76.03) 246.09,76.03 247.8,74.32 263.75,74.32 264.42,74.99 270.24,74.99 v2(273.26,78.02) ; v2(252.79,17.22) 251.7,17.22 250.9,18.02 250.9,27.11 v2(251.94,28.16) ; v2(269.58,37.96) 269.9,37.64 269.9,35.33 268.51,33.95 268.51,31.72 265,28.21 v2(263.34,28.21) ; v2(104,73.29) 104,73.35 105.36,74.72 v2(115.6,74.72) ; v3(65.64,103.71) 63.76,103.71 62.7,102.64 62.7,87.52 66.33,83.88 v2(71.27,83.88)
  IN2 w0.508: v2(249.59,30.61) 249.91,30.61 250.86,29.65 250.86,28.49 251.19,28.16 v2(251.94,28.16) 251.94,28.38 252.36,28.8 256.73,28.8 257.32,28.21 v2(263.34,28.21) ; v2(242.87,66.53) 242.35,66.01 227.01,66.01 224.29,68.73 222.34,68.73 221.94,68.34 v2(221.94,68.1)
  BOTTOM w0.508: PU400.6 114.86,73.83 115.05,74.02 PC400.1 v2(115.6,74.72) ; v2(243.48,58.15) 242.87,58.76 v2(242.87,66.53) ; v2(255.15,6.88) 255.15,13.06 252.79,15.42 v2(252.79,17.22)
  vias: v2(40.98,7.3) v2(41.39,6.74) v2(41.62,7.3) v2(42.02,6.74) v2(42.25,7.3) v2(89.58,82.15) v2(89.73,82.72) v2(90.22,82.15) v2(90.37,82.72) v2(211.11,37.63) v2(211.11,37.04) v2(211.71,37.63) v2(211.71,37.04) v2(212.3,37.63) v2(212.3,37.04) v2(212.9,37.64) v2(212.9,37.05) v2(231.25,7.24) v2(231.59,6.69) v2(231.89,7.24) v2(232.23,6.69) v2(232.52,7.24) v2(260.77,93.29) v2(260.77,92.65) v2(261.4,93.29) v2(261.4,92.65) v2(285.39,40.65) v2(285.8,40.22) v2(286.23,39.83) v2(286.66,39.43) v2(289.99,42.78) v2(290.62,42.78) v4(209.65,39.65) v4(213.27,42.9)
+5V_ALW2: length 2.6
  TOP w0.127: v2(218.28,52.12) 218.28,52.86 v4(218.29,52.86)
  TOP w0.203: PU100.13 v2(218.28,52.12)
  BOTTOM w0.508: v2(218.28,52.12) 218.28,51.53 PC118.1
+5V_ALW_UZ5: length 3.5
  TOP w0.102: v1(271.22,36.94) 270.86,37.3 RZ21.2
  TOP w0.508: UZ5.1 269.96,36.32 CZ35.1 RZ21.2
+5V_ALWP: length 27.4
  TOP w0.127: v3(206.52,48.24) v1(205.83,48.24)
  TOP w0.203: PU100.14 217.88,51.7 217.6,51.99 v2(217.6,52.12)
  TOP w0.254: v3(209.53,48.94) 210.37,48.94 210.75,48.55 210.75,47.85 213.75,44.86 217.31,44.86 217.6,45.15 PR101.2
  IN2 w0.508: v3(209.53,49.58) 210.12,49.58 210.49,49.21 210.49,47.99 211.57,46.91 213.43,46.91 213.85,46.49 215.59,46.49 217.04,47.94 217.04,50.08 217.97,51 217.97,51.51 217.6,51.88 v2(217.6,52.12)
  vias: v3(206.52,47.61) v3(207.16,48.24) v3(207.16,47.61) v3(207.79,48.24) v3(207.79,47.61) v3(208.43,48.24) v3(208.43,47.61) v3(209.06,48.24) v3(209.06,47.61) v3(209.7,48.24) v3(209.7,47.61)
+5V_HDD:
  vias: v1(270,8.6)
+5V_RUN: length 285.5
  TOP w0.305: v2(245.92,16.65) 245.92,17.26 245.58,17.6 JKBTP1.12
  TOP w0.508: v2(106.25,58.34) 104.37,58.34 102.24,60.46 97.2,60.46 95.69,61.98 v4(95.69,71.89) 96.15,72.35 96.15,79.59 v2(95.6,80.14)
  IN1 w2.032: 241.3,88.85 237.2,92.95 237.2,94 236.04,95.16 225.05,95.16
  IN1 w3.048: 274.77,80.06 272.09,80.06 270.24,78.21 267.27,78.21 265.81,79.67 252.58,79.67 ; 96.92,95.5 102.31,100.89 110.03,100.89 112.56,98.36 152.07,98.36 152.84,99.14 202.84,99.14 208.61,93.37 217.03,93.37 217.05,93.4
  IN2 w2.032: 76.39,85.95 67.8,85.95
  IN2 w2.286: 80.69,62.52 78.61,62.52 76.54,60.45 76.54,58.48 70.55,52.49 70.55,44.16 48.13,21.74 44.83,21.74 43.24,23.33 38.92,23.33 36.61,21.02 36.61,15.63
  BOTTOM w0.508: v2(285.71,80.16) 285.67,80.2 QV501.2
  vias: v2(40.42,9.47) v2(40.43,8.86) v2(41.07,9.46) v2(41.07,8.87) v2(223.62,93.48) v2(224.2,93.48) v2(225.85,18.57) v2(226.29,17.97) v2(226.46,18.57) v2(226.87,17.97) v2(227.07,18.55) v2(227.49,17.96) v2(256.87,12.31) v2(256.87,11.72) v2(257.44,12.89) v2(257.45,12.31) v2(257.45,11.72) v2(273.86,11.81) v2(273.86,11.16) v2(274.46,11.82) v2(276.87,80.06) v2(277.14,79.51) v2(277.45,80.06) v2(277.72,79.51) v2(278.04,80.06) v3(65.35,88.96) v3(65.36,88.3) v3(65.99,88.96) v3(66,88.3)
+5V_RUN_AUDIO: length 25.9
  TOP w0.127: v4(25.82,22.92) 26.2,22.54 26.2,22.07 v2(26.21,22.06)
  TOP w0.508: LA5.2 v2(26.21,22.06)
  BOTTOM w0.508: v2(37.82,8.87) 36.71,9.98 36.71,10.97 36.23,11.45 36.23,14.24 36.71,14.72 36.71,21.01 35.25,22.47 26.61,22.47 v2(26.21,22.06)
+5V_RUN_PVDD: length 5.7
  BOTTOM w0.508: v2(35.94,10.45) 35.68,10.71 CA46.1 32.65,10.71 CA47.1 32.32,11.04 v3(32.32,12.84)
  vias: v1(35.43,12.67)
+5V_RUN_UZ9:
  vias: v1(214.08,39.06)
+5V_USB_CHG_PWR:
  vias: v4(283.86,55.1)
+GND_CHASSIS:
  vias: v1(272.3,91.4) v2(281.3,90.07) v2(281.3,89.43)
+V1.05S_APLLOPI: length 45.3
  TOP w0.508: v2(158.73,63.18) 159,63.18 159.33,63.51 159.33,66.65 159.67,66.99 v2(160.16,66.99) ; v2(160.03,88.1) 160.03,89.19 160.8,89.97 v1(161.62,89.97) 165.28,89.97 167.42,87.82 167.42,83.79 168.06,83.16 171.02,83.16 v2(171.37,83.51)
  IN1 w0.508: v2(160.03,88.1) 159.13,87.2 159.13,77.38 159.48,77.02 159.48,73.77 160.35,72.91 160.35,72.19 159.93,71.77 159.93,71.26 159.73,71.06 159.73,67.42 v2(160.16,66.99)
+V1.05SP_B+:
  vias: v1(202.61,66.27)
+VCC_CORE: length 69.7
  TOP w0.508: 132.1,73.37 131.77,73.7 131.77,76.17 130.81,77.14 RC209.1 130.81,78.74 CC79.2
  BOTTOM w0.102: UC1.G25 156.07,69.43 v2(155.71,69.07)
  BOTTOM w0.127: UC1.F56 137.01,70.07 ; UC1.F56 136.39,70.69 ; UC1.F56 137.01,70.69 ; UC1.F56 136.39,70.07 ; UC1.G55 137.37,70.06 137.1,69.79 ; UC1.G55 137.54,69.9 137.54,69.6 ; UC1.G55 137.39,70.07 137.1,70.36 ; UC1.G55 137.48,70.15 137.48,70.49 ; 151.43,70.69 UC1.F32 ; UC1.F32 152.06,70.07 ; UC1.F32 151.43,70.07 ; UC1.F32 152.06,70.69 ; UC1.F52 139.52,70.07 ; UC1.F52 138.9,70.69 ; UC1.F52 139.52,70.69 ; UC1.F52 138.9,70.07 ; UC1.F48 142.03,70.07 ; UC1.F48 141.4,70.69 ; UC1.F48 142.03,70.69 ; UC1.F48 141.4,70.07 ; 148.93,70.07 UC1.F36 ; UC1.F36 149.55,70.69 ; UC1.F36 149.55,70.07 ; UC1.F36 148.93,70.69 ; UC1.G27 154.72,69.83 154.61,69.83 ; UC1.G27 155.06,70.18 155.06,70.5 ; UC1.G27 154.61,70.39 ; UC1.G27 155.04,69.96 155.04,69.61 v2(154.86,69.43) ; 157.08,69.83 157.23,69.83 UC1.G23 ; 148.85,69.79 148.58,70.06 UC1.G37 ; UC1.G49 140.91,70.17 140.91,70.55 ; UC1.G49 140.91,69.94 140.91,69.56 v2(141.03,69.45) ; UC1.G49 141.33,70.37 ; UC1.G49 141.25,69.83 141.53,69.83 ; 153.94,70.69 UC1.F28 ; UC1.F28 154.56,70.07 ; UC1.F28 154.56,70.69 ; UC1.F28 153.94,70.07 ; 153.84,70.34 UC1.G29 ; UC1.G29 153.44,69.94 153.44,69.56 v2(153.56,69.45) ; UC1.G29 153.79,69.83 153.97,69.83 ; UC1.G29 153.44,70.17 153.44,70.52 ; UC1.M23 157.17,66.89 157.16,66.9 ; UC1.M23 157.67,66.9 157.67,67.31 ; UC1.M23 157.96,66.89 158.18,67.11 UC1.L22 158.18,67.46 157.93,67.71 UC1.K23 ; 144.45,69.83 144.69,69.83 UC1.G43 ; UC1.G47 142.41,70.07 142.12,70.36 ; UC1.G47 142.5,69.97 142.5,69.54 v2(142.41,69.45) ; UC1.G47 142.53,70.18 142.53,70.5 ; UC1.G47 142.38,70.06 142.05,69.72 ; v2(152.44,69.45) UC1.G31 ; UC1.G31 152.53,70.15 152.53,70.5 ; UC1.G31 152.42,70.06 152.1,69.74 ; UC1.G31 152.44,70.06 152.17,70.32 ; UC1.J23 157.79,68.64 157.79,69.21 UC1.H23 ; UC1.J23 157.41,68.26 ; UC1.J23 157.35,68.84 ; 156.45,70.69 UC1.F24 ; UC1.F24 156.45,70.07 ; UC1.F24 157.07,70.69 ; UC1.F24 157.07,70.07 ; 135.83,70.42 135.83,70.24 UC1.G57 ; 144.64,70.33 UC1.G43 ; UC1.G43 145.04,69.93 145.04,69.57 v2(144.91,69.45) ; UC1.G43 145.02,70.16 145.02,70.53 ; 147.42,70.41 UC1.G39 ; UC1.G39 147.42,70.05 147.13,69.76 ; UC1.G39 147.02,70.06 ; UC1.G23 157.65,70.26 157.65,70.4 ; UC1.G23 157.71,69.8 157.71,69.37 UC1.H23 ; UC1.G23 157.15,70.36 ; UC1.G33 151.01,70.01 151.01,69.5 v2(151.06,69.45) ; UC1.G33 151.01,70.11 151.01,70.49 ; UC1.G33 151.37,70.37 ; UC1.G33 151.34,69.77 ; UC1.K23 157.18,67.71 157.16,67.69 ; UC1.K23 157.67,67.31 157.67,67.31 ; 149.64,69.77 UC1.G35 ; UC1.G35 149.59,70.39 ; UC1.G35 150.1,69.89 150.1,69.62 v2(149.93,69.45) ; UC1.G35 150.1,70.23 150.1,70.47 ; 140.02,70.49 140.02,70.18 UC1.G51 ; UC1.G25 156.25,70.23 156.4,70.23 ; UC1.G25 156.4,69.72 ; UC1.G25 155.98,70.14 155.98,70.47 ; UC1.G45 143.44,69.96 143.44,69.54 v2(143.53,69.45) ; UC1.G45 143.81,70.33 ; UC1.G45 143.41,70.18 143.41,70.52 ; UC1.G45 143.76,69.83 144,69.83 ; 146.42,70.07 UC1.F40 ; UC1.F40 146.42,70.69 ; UC1.F40 147.04,70.69 ; UC1.F40 147.04,70.07 ; UC1.G53 138.43,70.14 138.43,70.49 ; UC1.G53 138.81,70.35 ; UC1.G53 138.55,70.06 138.81,69.79 ; UC1.G53 v2(138.52,69.45) ; UC1.H23 157.66,69.33 157.41,69.58 ; UC1.H23 157.67,69.31 157.43,69.08 ; UC1.F44 144.53,70.07 ; UC1.F44 143.91,70.69 ; UC1.F44 143.91,70.07 ; UC1.F44 144.53,70.69 ; UC1.G51 139.9,70.05 139.64,69.79 ; UC1.G51 140.02,69.93 140.02,69.57 v2(139.9,69.45) ; UC1.G51 139.89,70.06 139.65,70.3 ; 136.01,70.05 UC1.G57 ; 136.01,70.05 136.27,69.79 ; 136.01,70.05 136.01,69.67 136.08,69.6 136.1,69.6 ; UC1.G57 136.03,70.06 136.27,70.3 ; 146.35,70.37 UC1.G41 ; UC1.G41 146.2,69.9 146.48,69.9 ; UC1.G41 146.04,70.05 145.93,69.94 145.93,69.56 v2(146.04,69.45) ; UC1.G41 145.93,70.17 145.93,70.45 146,70.52 ; 157.67,67.31 157.68,67.3 ; UC1.G37 148.55,70.06 148.85,70.36 ; UC1.G37 v2(148.55,69.45) ; UC1.G37 148.47,70.14 148.47,70.49
  BOTTOM w0.229: v2(134.46,70.45) 134.76,70.15 UC1.F59
  BOTTOM w0.254: UC1.M57 136.26,66.73 v2(136.27,66.74) ; v2(136.36,62.83) UC1.W57 ; v2(136.27,59.06) 136.14,58.93 UC1.AG57 ; v2(136.33,65.43) UC1.P57 ; v2(136.33,64.13) UC1.U57 ; UC1.AD57 v2(136.33,60.23) ; v2(136.36,61.53) UC1.AB57 ; v2(136.52,68.11) 136.45,68.03 UC1.K57
  vias: v2(136.27,69.22) v2(137.48,69.15) v2(139.34,70.98) v2(141.85,70.98) v2(144.36,70.98) v2(146.87,70.98) v2(147.42,69.45) v2(149.37,70.98) v2(151.88,70.98) v2(153.56,68.85) v2(154.39,70.98) v2(156.75,70.96) v3(112.34,58.24) v3(112.34,57.23) v3(112.34,56.21) v3(112.35,55.19) v3(112.39,54.2) v3(112.47,53.23) v3(112.46,51.92) v3(112.46,51) v3(112.48,49.68) v3(112.52,48.41) v3(113.34,48.39) v3(113.48,58.24) v3(113.48,57.23) v3(113.48,56.21) v3(113.5,55.19) v3(113.6,54.26) v3(113.66,52.55) v3(114.04,48.39) v3(114.11,53.37) v3(114.74,54.2) v3(114.68,52.55) v3(114.74,48.39) v3(115.12,53.37) v3(115.19,55.16) v3(115.44,48.39) v3(115.57,52.55) v3(115.69,54.2) v3(116.39,54.64) v3(116.39,53.82) v3(116.39,52.93) v3(116.39,52.17) v3(116.39,51.4) v3(116.39,50.64) v3(116.39,49.88) v3(116.39,49.12) v3(116.39,48.39) v3(116.77,58.24) v3(116.77,57.23) v3(116.77,56.21) v3(116.94,64.64) v3(116.94,64.01) v3(116.94,61.24) v3(116.94,60.6) v3(116.94,55.43) v3(117.7,67.37) v3(117.76,58.24) v3(117.76,57.23) v3(117.76,56.21) v3(118.34,67.37) v3(119.1,64.64) v3(119.1,64.01) v3(119.1,61.24) v3(119.1,60.6) v3(119.73,64.64) v3(119.73,64.01) v3(119.73,61.24) v3(119.73,60.6) v3(120.5,67.37) v3(121.13,67.37) v3(121.89,64.64) v3(121.89,64.01) v3(121.89,61.23) v3(121.89,60.59) v3(122.53,64.64) v3(122.53,64.01) v3(122.53,61.23) v3(122.53,60.59) v4(113.24,69.67)
+VCC_PWR_SRC: length 16.9
  TOP w0.102: v3(98.61,53.31) v1(98.61,54.08)
  TOP w0.254: v2(107.49,61.51) 107.5,61.5 PR518.1
  IN2 w0.254: v3(99.25,53.31) 99.4,53.47 99.4,57.8 100.64,59.04 105.02,59.04 v2(107.49,61.51)
  BOTTOM w0.254: v2(107.49,61.51) PR511.1
  vias: v3(98.28,49.28) v3(98.92,49.28)
+VCCIO_OUT: length 8.5
  BOTTOM w0.305: UC1.A59 134.88,73.74 134.1,74.52 134.1,74.71
  BOTTOM w0.508: 134.1,74.71 133.64,75.17 v1(133.64,77.13) 133.64,78.35 131.87,80.12 RC196.1
+VCCIOA_OUT: length 3.2
  TOP w0.508: v2(159.07,70.39) 158.82,70.39 158.02,69.6 RC133.1
  BOTTOM w0.203: v2(159.07,70.39) 159.17,70.39 159.61,70.83 UC1.E20
+VDDA_AVDD1: length 1.4
  TOP w0.102: LA5.1 25.41,20.58 v4(24.95,21.03)
+VDDA_PVDD:
  vias: v1(30.03,13.44)
GND: length 1587.9
  TOP w0.102: v4(113,75.82) v2(112.43,75.82)
  TOP w0.203: v2(103.74,67.93) 104.35,68.53 PU500.29 ; v2(105.39,66.47) 105.43,66.43 PU500.19 ; PU500.22 105.69,67.63 v2(105.39,67.93) ; UZ2.11 v2(241.73,58.02) ; UZ9.11 v2(217.09,39.98) ; UZ8.11 v2(221.94,66.13)
  TOP w0.254: UN2.3 264.04,19.01 v2(263.41,18.38) ; v2(287,42.46) 286.75,42.21 UI3.14 284.89,42.21 RI14.1 ; JXDP1.13 77.03,57.7 76.76,57.97 76.76,58.9 77.05,59.2 JXDP1.7 79.54,59.2 v2(79.74,59.4) ; JKBTP1.2 244.98,22.6 245.56,23.19 v2(245.56,23.49) 245.32,23.49 244.93,23.1 JKBTP1.1 ; JXDP1.8 v2(85.76,59.2) ; JKBTP1.15 245.17,16.1 v2(245.41,16.34) 245.27,16.48 245.17,16.48 245.06,16.6 JKBTP1.14 ; v2(255.56,17.73) 255.56,18.01 254.95,18.62 UN3.5 ; RPC9.1 181.98,64.57 v2(182.05,64.5) ; JXDP1.1 v2(79.74,60.7)
  TOP w0.279: JXDP1.19 80.12,56.2 v2(80.41,55.9) ; JXDP1.38 84.97,51.7 85.04,51.76 v2(86.07,51.76) ; JXDP1.31 79.87,53.2 v2(80.13,52.93) ; JXDP1.20 v2(85.37,56.2) ; v2(76.58,45.59) 77.18,46.2 JXDP1.59 ; UZ3.5 246.05,30.8 245.98,30.86 244.78,30.86 CZ37.2 ; JXDP1.32 v2(85.37,53.2) ; JXDP1.37 v2(79.78,51.7) ; JXDP1.49 v2(79.79,48.7) ; JXDP1.14 v2(85.38,57.7) ; JXDP1.25 79.51,54.7 v2(79.69,54.52) ; v2(85.38,54.7) JXDP1.26 ; v2(86.91,60.34) 86.55,60.7 JXDP1.2 ; JXDP1.50 v2(85.51,48.7)
  TOP w0.305: v2(262.24,42.95) 262.24,42.75 262.53,42.46 263.53,42.46 UE2.B60 ; JLED1.10 270.65,12.2 v2(270.81,12.36) ; JAPS1.10 v2(301.71,25.69) ; v2(298.6,35.47) 298.6,35.94 298.41,36.13 JDEG1.10 ; v2(253.11,46.69) 253.9,46.69 254.13,46.46 UE2.B18 ; UE2.B66 263.22,45.46 263.19,45.49 262.57,45.49 v2(262.05,44.97) ; JAPS1.12 v2(301.73,24.69) ; JLPDE1.9 274.56,60.72 274.79,60.95 v2(275.19,60.95) ; v2(245.4,19.19) 245.4,19.39 245.19,19.6 JKBTP1.8 ; UE2.B11 257.94,46.5 v2(258.03,46.4) ; JAPS1.8 v2(301.74,26.69) ; v2(262.28,39.22) 262.52,39.46 UE2.B54 ; JAPS1.14 v2(301.73,23.69)
  TOP w0.381: v2(252.1,46.6) 251.21,46.6 250.89,46.92 QE2.1 ; v2(246.05,33.06) 246.2,33.21 UZ11.3 ; UL2.3 260.94,82.45 v2(260.45,82.94) ; CZ5.2 200.66,77.1 UZ1.11 ; UD1.3 147.45,20.33 148.05,20.93 v2(148.32,20.93) ; v2(197.98,76.9) 198.16,76.9 198.71,77.46 UZ1.8 ; v2(135.68,87.16) 135.82,87.02 UC8.3 ; UC4.3 183.93,74.4 183.8,74.52 RC80.2 ; RC243.2 RC242.2 164.83,45.92 v2(164.35,45.44) ; v2(196.11,82.5) UZ1.25 ; UZ1.18 200.66,83.62 201.01,83.27 v2(201.01,83.16) ; CZ4.2 196.11,77.08 UZ1.4 ; v2(163.05,66.32) 163.26,66.52 CC71.2 ; v2(191.26,50.48) 191.26,51.18 191.11,51.33 UC6.3
  TOP w0.406: v2(266.52,31.85) 266.82,32.15 UZ6.3 ; v2(189.28,72.48) 189.11,72.31 UC5.3 ; QE2.4 248.42,48.58 v2(248.42,48.87) ; UZ10.3 262.73,59.03 262.56,59.21 v2(262.23,59.21)
  TOP w0.432: QZ10.4 147.15,86.82 v2(146.29,87.68) 145.85,88.12 QZ10.1
  TOP w0.457: v2(156.84,57.57) 156.9,57.62 CC65.2 ; CD35.2 169.92,6.69 169.86,6.62 v2(169.86,6.62) ; v2(163.15,59.88) 163.15,59.24 CC80.2 ; v2(52.7,10.21) PD2.1
  TOP w0.508: v2(257.83,33.15) 258.32,33.63 RE86.1 258.32,33.81 CE19.2 259.21,33.79 RE88.2 ; CZ7.2 v2(200.67,88.1) ; CR35.2 RR11.2 v2(275.46,25.55) ; v2(172.82,44.53) 172.82,44.91 CC73.2 ; CD12.2 119.02,15.16 v2(119.2,14.98) ; v2(70.42,95.83) 70.45,95.81 PQ708.6 ; v2(256.97,17.7) 256.93,17.74 256.93,18.77 CN4.2 CN3.1 ; CD39.2 185.72,15.15 185.43,14.86 185.43,13.9 v2(185.11,13.58) ; v2(197.34,14.73) 197.34,15.59 CD37.2 ; RC191.2 121.86,45.94 v2(120.76,47.04) ; v2(160.39,57.48) 161.07,57.48 RC152.2 ; v2(251.31,16.26) 251.04,16.52 RN7.2 ; v2(194.28,10.05) 194.29,10.03 CD42.2 ; PQ3.3 73.05,101.28 v2(73.39,101.62) ; v2(114.79,15.04) 114.79,15.04 CD13.2 ; v2(40.85,18.21) CA53.2 ; v2(114.6,9.61) 114.6,9.61 CD8.2 ; CD49.2 v2(195.56,10.41) ; CD44.2 185.72,10.4 v2(185.69,10.43) ; v2(198.05,88.11) 198.05,88.72 198.42,89.09 CZ9.2 ; CD15.2 104.19,14.98 v2(104.2,14.96) ; v2(76.63,53.48) 75.13,54.98 RC305.2 ; CE3.2 248.4,65.02 v2(248.74,65.37) ; v2(226.01,14.29) 225.59,14.29 CD60.2 225.23,14.65 CD62.2 ; v2(107.86,88.7) 107.86,89.11 RV2.2 RV1.2 ; CD6.2 90.23,9.76 v2(90.1,9.63) ; v2(158.72,67.38) 159.13,67.79 CC78.2 ; QV7.3 118.93,81.33 v2(118.56,80.96) ; v2(274.23,77.99) 275.57,79.34 CL17.2 CL16.2 ; v2(17.12,16.55) 16.89,16.78 DA1.1 ; v2(264.93,54.81) 265.77,54.81 265.97,54.61 CE10.2 266,54.57 CE12.2 ; CZ4.2 196.29,76.9 v2(197.98,76.9) ; v2(284.77,38.25) CR4.2 284.77,36.89 CR10.1 ; v2(107.75,15.03) 107.74,15.04 CD14.2 ; CD58.2 CD57.2 222.16,10.89 v2(221.55,10.28) ; v2(164.63,65.68) 164.67,65.71 CC40.2 ; PC507.2 v2(106.54,71.86) ; v2(40.75,15.48) CA54.2 40.74,14.85 CA11.2 ; CD28.2 140.38,9.7 139.7,10.38 v2(139.05,10.38) ; CR3.2 291.74,30.21 291.98,30.45 CR1.2 292.61,30.45 v2(293.41,29.65) ; CZ5.2 201.4,76.95 v2(201.46,76.9) ; CE18.2 266.93,37.95 UZ5.2 266.96,36.94 v2(268.37,36.94) ; RC91.1 167.61,46.08 v2(167.66,46.13) ; v2(11.87,6.76) 11.35,7.28 JSPK1.5 ; v2(101.53,10.08) 101.52,10.06 CD11.2 ; CD19.2 v2(102.74,10.33) ; v2(288.6,23.28) 288.24,23.65 CR34.2 ; CZ16.2 CZ15.2 240.66,31.7 CZ19.2 239.94,31.47 v2(239.67,31.74) ; RZ33.2 285.7,78.83 v2(285.48,79.04) ; CD32.2 CD31.2 139.87,18.59 139.69,18.77 v2(139.14,18.77) ; v2(112.9,10) 112.95,9.95 CD17.2 ; v2(41.08,12.36) 41.51,12.36 CA10.2 ; RC140.2 v2(179.12,65.89) ; CC21.2 v2(87.75,49.07) ; RE82.1 v2(267.75,49.87) ; RN11.1 259.23,18.08 v2(258.8,17.65) 259.26,17.2 RN9.1 ; PC706.2 81.98,63.69 81.4,63.12 72.54,63.12 70.97,61.55 H7.1 69.98,64.67 v3(71.6,66.29) ; RD21.2 202.07,11.9 v2(201.64,11.9) 201.37,12.17 RD20.2 CD55.2 ; v2(257.2,50.93) 257.64,51.37 CE13.2 ; RR8.2 284.1,23.57 v2(284.05,23.52) ; CI3.2 86.13,93.39 v2(85.45,94.06) ; v2(238.21,59.94) CZ50.2 CZ23.2 ; CE17.2 262.3,50.27 v2(262.2,50.16) ; CD29.2 v2(145.02,15.67) ; v2(215.19,45.73) 215.41,45.5 PR106.1 PR104.2 ; RE78.2 v2(249.78,40.11) ; CC27.2 148.72,59.18 v2(148.25,58.71) ; CD40.2 191.37,17.87 v2(191.36,17.88) ; v2(254.76,33.32) 255.18,33.74 RE56.1 254.09,34.18 CE22.2 ; v2(116.06,15.04) 116.06,15.36 CD2.2 ; v2(98.54,65.96) 98.54,65.96 98.79,65.7 PR513.2 ; CL15.2 261.6,84.39 v2(261.82,84.18) ; CC22.2 75.02,48.94 75.68,49.61 v2(76.58,49.61) ; v2(269.3,15.98) 269.11,16.17 RN21.1 RN13.1 ; CD22.2 CD23.2 119.68,9.45 v2(119.5,9.63) ; v2(248.6,23.53) 248.6,24.41 247.93,25.08 CZ30.2 CZ31.2 ; v2(77.52,14.53) 77.7,14.71 CD1.2 CD5.2 RD6.2 ; CR2.2 CR13.1 v2(278.24,28.49) ; CR7.1 v2(280.72,23.52) ; v2(249.79,45.77) CE38.2 RE77.2 ; UV24.2 101.33,89.76 100.96,89.39 v2(100.96,88.99) ; RN19.1 259.45,21.06 v2(259.88,21.49) ; v2(208.32,59.97) 207.91,59.56 PR303.2 ; CE21.2 v2(272.08,40.75) ; v2(160.03,61.96) 160.52,62.45 CC63.2 ; v2(152.15,58.71) 152.15,59.36 CC26.2 ; CL14.1 RL13.2 252.19,81.69 v2(252.46,81.96) ; YL1.2 v2(249.49,83.74) ; CE25.2 265.03,33.26 v2(265.1,33.2) ; v2(276.32,59.61) 276.77,59.61 277.16,59.22 JLPDE1.11 ; CC59.2 161.4,67.59 161.03,67.22 v2(161.03,66.9) ; CC13.1 162.56,44.93 162.28,45.21 v2(161.78,45.21) ; DA3.1 17.38,13.44 v2(17.31,13.37) ; CD33.2 CD34.2 RD24.2 161.3,17.32 161.63,17.65 161.63,18.14 161.94,18.45 v2(162.28,18.45) ; CC57.2 159.03,61.96 v2(158.73,61.66) ; CA50.2 39.91,19.4 v2(39.91,20.09) ; CE23.2 CE14.2 249.5,45.08 v2(249.3,45.29) ; PD1.1 v2(54.8,10.24) ; CC69.2 165.38,62.86 v2(164.64,62.86) ; v2(190.21,10.43) 190.23,10.41 CD43.2 ; RD7.2 79.74,18.77 v2(79.12,18.77) ; PC511.2 98.85,69.9 PC505.2 v2(98.03,69.77) ; v2(290.13,36) 290.48,36 290.81,35.67 CR18.1 ; v2(285.85,23.51) 285.81,23.54 CR31.2 ; CZ2.2 97.24,84.44 v2(96.86,84.06) ; CE30.2 RE65.2 259.26,29.74 258.85,29.34 v2(258.1,29.34) ; QA1.3 39.97,24.38 v2(39.52,24.83) ; v2(267.76,47.47) CE29.2 ; v2(197.06,11.2) 197.06,11.17 197.09,11.15 CD41.2 ; CC44.2 164.14,67.98 164.86,68.7 v2(164.86,69.32) ; CZ34.2 270.04,34.77 CZ35.2 269.19,35.48 v2(269.11,35.56) ; v2(148.32,20.93) 148.58,20.67 RD14.1 ; v2(62.95,11.7) 63.56,11.09 PC209.1 64.16,11.18 PC3.2 ; v2(226.76,59.92) 226.76,59.42 226.96,59.22 PC111.2 227.39,59.47 v2(227.39,59.92) ; CL21.2 CL20.2 v2(269.21,80.09) ; CD52.2 v2(183.75,10.69) ; CD61.2 221.66,14.51 v2(221.1,15.07) ; CC72.2 160.56,59.18 v2(160.04,59.69) ; CZ40.1 v2(223.4,62.09) ; CC66.2 v2(161.85,65.05) 162.27,64.63 CC100.1 ; v2(105.66,14.9) 105.65,14.91 CD7.2 ; JLPDE1.12 268.46,57 v2(268.46,55.31) ; v2(277.9,32.92) 278.38,32.92 RR2.1 ; CC49.2 161.45,59.36 v2(161.91,59.82) 161.91,60.41 CC61.2 ; v2(198.74,14.99) 198.8,15.05 CD45.2 ; CC12.1 160.4,45.15 159.83,45.72 v2(159.71,45.72) ; CC36.2 155.2,60.92 CC37.2 154.86,60.28 154.21,59.64 CC28.2 154.21,58.83 v2(154.12,58.74) ; PR709.2 74.44,93.38 v2(74.6,93.53) ; v2(99.07,94.12) 99.59,93.6 CV10.2 99.6,93.52 RV3.1 ; CZ44.2 CZ45.2 v2(217.53,37.65) ; CL7.2 247.92,88.73 v2(247.66,88.48) ; CD3.2 111.81,15.28 v2(111.54,15.01) ; RZ27.2 v2(276.41,18.21) ; YL1.4 246.82,80.48 v2(246.63,80.67) ; v2(166.61,81.74) 167.88,80.47 RC139.1 ; JSPK1.6 v2(2.52,7.28) ; CD47.2 187.5,15.02 v2(187.51,15) ; v2(238.21,55.97) CZ43.2 CZ42.2 ; CR9.1 286.39,37.38 286.15,37.62 v2(285.4,37.62) ; v2(145.35,20.03) 145.02,20.36 CD30.2 ; v2(110.86,9.61) 110.85,9.61 CD9.2 ; CC58.2 158.34,60.31 v2(158.7,59.96) ; RC306.2 171.83,80.44 v2(170.53,81.74) ; CE36.2 250.09,38.15 249.79,37.85 CE34.2 249.27,37.85 248.93,37.5 v2(248.93,37.22) ; CE8.2 250.1,53.97 v2(249.78,53.66) ; v2(257.55,28.97) 257.22,29.3 JTAG1.2 ; CE16.2 250.82,42.02 v2(250.58,41.78) 249.96,41.16 RE55.1 ; v2(158.09,15.44) RD25.2 ; CZ46.2 v2(216.58,37.64) 216.59,37.62 CZ47.2 ; RD15.1 RD16.1 138.59,16.38 137.55,15.34 v2(137.55,14.97) ; v2(287.13,46.09) 287.12,46.08 CI17.2 ; v2(109.85,15.03) 109.84,15.04 CD4.2 ; PR114.2 v3(213.34,48.18) ; CD26.2 CD27.2 v2(144.45,14.59) ; CD59.2 v2(226.02,13.63) ; v2(141.68,87.4) 141.25,87.83 CC24.2 ; v2(254.52,93.5) 254.94,93.5 255.63,92.8 CL8.2 ; v2(160.13,64.01) 160.14,64.02 CC64.2 ; CC50.2 162.09,57.44 v2(162.25,57.6) ; JAPS1.20 296.66,19.59 v2(296.21,20.04) ; PR525.2 107.69,59.03 v2(108.2,59.03) ; v2(111.36,85.18) 111.14,84.95 CZ1.2 ; RC175.2 RC174.2 184.85,54.23 184.54,54.53 v2(184.54,54.79) ; JKBTP1.17 239.97,25.2 239.97,25.2 v2(239.71,24.94) ; RD28.2 220.09,17.32 CD63.2 220.29,16.24 CD64.2 220.29,15.8 219.58,15.09 v2(219.04,15.09) ; PR102.1 PR105.1 221.23,45.5 v2(221.43,45.3) ; RC198.2 128.37,79.48 v2(128.29,79.4) 128.11,79.22 RC218.2 ; CC70.2 158.6,63.98 v2(158.73,64.1) ; v2(266.14,51.78) 266.15,51.76 CE11.2 ; v2(259.92,66.13) CE2.2 ; CZ6.2 v2(196.1,88.1) ; PC119.2 v2(214.17,47.1) ; v2(105.47,73.25) 105.47,72.77 PC510.2 ; RR5.2 291.06,28.26 v2(291.27,28.04) ; v2(244.22,28.02) 244.21,28.03 CZ36.2 ; v2(76.62,43.98) 76.61,43.97 RC128.1 ; v2(192.45,10.43) 192.45,10.43 CD50.2 ; v2(102.24,73.41) 102.39,73.56 PC514.2 ; CR19.1 290.33,33.93 v2(290.76,33.5) 291.08,33.18 CR22.1 ; v2(201.64,10.38) 201.62,10.4 CD56.2 ; CZ64.2 v2(221.5,62.1) ; CE1.2 v2(263.79,65.32) ; RE21.1 v2(253.43,58.9) ; RN23.1 262.3,11.76 v2(262.14,11.92) ; RC132.2 RC130.2 RC131.2 132.27,46.05 132.66,45.66 v2(132.68,45.66) ; v2(278.23,27.39) 278.39,27.55 CR17.1 ; CD18.2 109.46,10.28 v2(109.41,10.33) ; CC52.2 165.71,61.75 v2(166.48,60.97) ; v2(184.11,14.3) 183.82,14.59 CD48.2 ; CZ39.1 v2(201.67,42.35) ; v2(116.01,10.01) 116,10 CD16.2 ; v2(190.11,15.06) 190.1,15.06 CD38.2 ; v2(105.78,9.61) 105.58,9.42 CD10.2 ; CR23.2 283.53,38.73 v2(282.88,38.07) ; PR308.2 207.58,61.99 207.88,61.68 v2(208.26,61.68) ; CD51.2 v2(187.5,10.46) ; v2(262.33,55.03) 262.92,55.62 CZ48.2 ; v2(281.07,34.92) 280.98,35.01 CR21.1 ; CR8.1 v2(281.81,23.51) ; CL13.1 v2(246.47,84.44) ; RL12.2 263.08,85.91 v2(263.18,85.81) ; CC35.2 v2(137.32,90.26) ; RE87.1 v2(255.08,71.49) ; CE15.2 CE20.2 268.02,43.03 v2(268.5,42.55) 268.79,42.26 RE58.2 ; v2(252.08,70.47) 252.08,71.13 252.44,71.49 RE24.2 ; RC80.2 183.8,75.56 183.69,75.68 v2(183.69,75.69) ; v2(106.19,89.33) 106.19,89.94 CV9.2 ; CR14.1 v2(292.1,25.71) ; RC304.2 188.47,74.74 188.26,74.94 v2(188.26,75.62) ; CL9.2 v2(261.29,91.82) ; RN16.1 268.69,18.82 v2(269.28,18.82) 269.94,18.82 RN25.1 ; CZ41.2 v2(222.45,62.09) ; PC20.2 v2(68.25,103.69) ; RZ10.1 CN29.2 CN24.2 261.99,14.49 v2(262.05,14.55) ; v2(193.56,14.4) 193.56,14.61 CD46.2 ; CZ37.2 v2(243.37,30.3) ; CE40.2 258.84,50.36 v2(258.84,49.8) ; CR15.1 v2(291.55,26.78) ; RL9.2 v2(251.2,88.69) ; JAPS1.19 v2(296.33,32.29) ; v2(140.06,11.73) CD25.2 CD24.2 ; CR6.2 v2(287.13,23.53) ; CC96.1 v2(96.64,90.8) ; CA30.2 v2(230.02,93.51) ; JDEG1.11 v2(295.09,35.03) ; RZ38.1 251.29,30.25 v2(251.22,30.17) ; CA33.2 v2(42.36,17.06) ; CC60.2 163.83,65.48 164.39,64.92 v2(164.65,64.92) ; v2(267.05,44.03) CE28.2
  VCC w0.203: JUSB2.13 251.6,105.1 ; JUSB2.13 251.6,103.69 ; JUSB2.13 251.6,106.51 ; JUSB2.4 240.04,95.87 ; JUSB2.4 239.87,96.44 ; JUSB2.4 239.3,96.61 ; JUSB2.4 239.3,95.13 ; JUSB2.4 238.73,95.3 ; JUSB2.4 239.87,95.3 ; JUSB2.4 238.56,95.87 ; JUSB2.4 238.73,96.44 ; JUSB2.10 251.6,100.15 ; JUSB2.10 251.6,96.44 ; JUSB2.10 251.6,98.3 ; JUSB2.10 250.65,96.44 ; JUSB2.10 249.7,96.44 ; 262.01,103.7 JLOM1.16 ; JLOM1.16 262.93,101.95 ; JLOM1.16 262.01,105.45 ; JLOM1.16 262.93,105.45 ; JLOM1.16 262.01,101.95 ; JUSB1.13 93.5,106.51 ; JUSB1.13 93.5,105.1 ; JUSB1.13 93.5,103.69 ; 75.9,98.3 JUSB1.11 ; JUSB1.11 76.85,96.44 ; JUSB1.11 77.8,96.44 ; JUSB1.11 75.9,96.44 ; JUSB1.11 75.9,100.15 ; 68.81,62.72 H7.1 ; H7.1 68.81,60.38 ; H7.1 69.98,63.14 ; H7.1 71.15,60.38 ; H7.1 69.98,59.96 ; H7.1 68.39,61.55 ; H7.1 71.15,62.72 ; H7.1 71.57,61.55 ; 80.46,95.87 JUSB1.4 ; JUSB1.4 81.2,95.13 ; JUSB1.4 80.63,95.3 ; JUSB1.4 81.2,96.61 ; JUSB1.4 81.77,95.3 ; JUSB1.4 80.63,96.44 ; JUSB1.4 81.94,95.87 ; JUSB1.4 81.77,96.44 ; JUSB1.10 93.5,96.44 ; JUSB1.10 93.5,100.15 ; JUSB1.10 92.55,96.44 ; JUSB1.10 93.5,98.3 ; JUSB1.10 91.6,96.44 ; H1.1 57.87,107.02 ; H1.1 55.53,107.02 ; H1.1 58.29,105.85 ; H1.1 55.11,105.85 ; H1.1 56.7,107.44 ; H1.1 55.53,104.68 ; H1.1 56.7,104.26 ; H1.1 57.87,104.68 ; 84.13,96.8 JUSB1.7 ; JUSB1.7 84.7,96.63 ; JUSB1.7 85.27,96.8 ; H13.1 151.7,17.24 ; H13.1 152.87,16.82 ; H13.1 152.87,14.48 ; H13.1 150.53,16.82 ; H13.1 151.7,14.06 ; H13.1 150.11,15.65 ; H13.1 150.53,14.48 ; H13.1 153.29,15.65 ; 120.9,54.03 H16.1 ; H16.1 120.9,50.84 ; H16.1 124.68,52.43 ; H16.1 122.5,54.62 ; H16.1 124.09,54.03 ; H16.1 124.09,50.84 ; H16.1 120.31,52.43 ; H16.1 122.5,50.25 ; 75.9,106.51 JUSB1.12 ; JUSB1.12 75.9,103.69 ; JUSB1.12 75.9,105.1 ; JUSB2.7 243.37,96.8 ; JUSB2.7 242.23,96.8 ; JUSB2.7 242.8,96.63
  IN1 w0.508: v2(17.12,16.55) 15.05,16.55 v2(14.49,17.11)
  IN2 w0.508: v2(22.71,10.74) 22.71,11.98 21.71,12.97 21.71,13.37
  GND w0.203: JUSB2.10 251.6,96.44 ; JUSB2.10 251.6,100.15 ; JUSB2.10 249.7,96.44 ; JUSB2.10 250.65,96.44 ; JUSB2.10 250.65,100.15 ; JUSB2.10 251.6,98.3 ; H17.1 177.82,54.62 ; H17.1 176.23,54.03 ; H17.1 175.64,52.43 ; H17.1 179.42,54.03 ; H17.1 180.01,52.43 ; H17.1 177.82,50.25 ; H17.1 176.23,50.84 ; H17.1 179.42,50.84 ; 117.53,107.02 H2.1 ; H2.1 117.11,105.85 ; H2.1 118.7,107.44 ; H2.1 118.7,104.26 ; H2.1 119.87,107.02 ; H2.1 117.53,104.68 ; H2.1 120.29,105.85 ; H2.1 119.87,104.68 ; 262.01,103.7 JLOM1.16 ; JLOM1.16 262.01,101.95 ; JLOM1.16 262.01,105.45 ; JLOM1.16 262.93,101.95 ; JLOM1.16 262.93,105.45 ; H10.1 241.52,44.82 ; H10.1 241.52,42.48 ; H10.1 240.35,42.06 ; H10.1 239.18,42.48 ; H10.1 239.18,44.82 ; H10.1 238.76,43.65 ; H10.1 241.94,43.65 ; H10.1 240.35,45.24 ; 213.74,99.03 JHDMI1.8 ; JHDMI1.8 214.2,99.15 ; JHDMI1.8 214.2,97.99 ; JHDMI1.8 213.74,98.11 ; JHDMI1.8 214.66,98.11 ; JHDMI1.8 214.66,99.03 ; 293.95,70.97 JMDP1.19 ; JMDP1.19 293.95,72.13 ; JMDP1.19 294.58,70.97 ; JMDP1.19 294.58,72.13 ; JMDP1.19 294.58,71.55 ; JMDP1.19 293.31,70.97 ; JMDP1.24 298.07,68.03 ; JMDP1.24 296.99,69.47 ; JMDP1.24 298.07,69.47 ; JMDP1.24 295.91,68.03 ; JMDP1.24 298.07,68.75 ; JMDP1.24 295.91,68.75 ; JMDP1.24 295.91,69.47 ; JMDP1.24 296.99,68.03 ; 236.8,5.86 H12.1 ; H12.1 234.56,8.1 ; H12.1 236.8,10.34 ; H12.1 239.04,8.1 ; H12.1 235.17,9.73 ; H12.1 235.17,6.47 ; H12.1 238.43,6.47 ; H12.1 238.43,9.73 ; H22.1 94.28,88.9 ; H22.1 90.12,88.9 ; H22.1 93.72,87.38 ; H22.1 90.68,90.42 ; H22.1 93.72,90.42 ; H22.1 92.2,86.82 ; H22.1 90.68,87.38 ; H22.1 92.2,90.98 ; JUSB3.10 289.83,63.38 ; JUSB3.10 288.5,61.72 ; JUSB3.10 287.17,62.55 ; JUSB3.10 287.17,63.38 ; JUSB3.10 289.83,61.72 ; JUSB3.10 289.83,62.55 ; JUSB3.10 287.17,61.72 ; JUSB3.10 288.5,63.38 ; H1.1 56.7,107.44 ; H1.1 55.53,104.68 ; H1.1 57.87,107.02 ; H1.1 55.53,107.02 ; H1.1 56.7,104.26 ; H1.1 55.11,105.85 ; H1.1 58.29,105.85 ; H1.1 57.87,104.68 ; JUSB1.13 93.5,106.51 ; JUSB1.13 92.55,103.69 ; JUSB1.13 93.5,105.1 ; JUSB1.13 92.55,106.51 ; JUSB1.13 93.5,103.69 ; 296.57,48.45 297.75,48.45 ; 297.75,48.45 297.75,47.68 ; 297.75,48.45 296.57,47.68 ; 297.75,48.45 298.93,48.45 ; 297.75,48.45 298.93,47.68 ; JMDP1.1 293.95,78.13 ; JMDP1.1 293.31,78.13 ; JMDP1.1 293.95,76.97 ; JMDP1.1 294.58,76.97 ; JMDP1.1 294.58,78.13 ; JMDP1.1 294.58,77.55 ; 289.66,55.52 JUSB3.7 ; JUSB3.7 290.3,56.98 ; JUSB3.7 289.66,56.79 ; JUSB3.7 289.47,56.15 ; JUSB3.7 290.3,55.32 ; 287.17,49.75 JUSB3.11 ; JUSB3.11 289.83,49.75 ; JUSB3.11 287.17,50.58 ; JUSB3.11 287.17,48.92 ; JUSB3.11 289.83,48.92 ; JUSB3.11 288.5,48.92 ; JUSB3.11 288.5,50.58 ; JUSB3.11 289.83,50.58 ; H19.1 268.9,24.6 ; H19.1 268.36,23.11 ; H19.1 266.87,22.57 ; H19.1 265.38,23.11 ; H19.1 265.38,26.09 ; H19.1 264.84,24.6 ; H19.1 268.36,26.09 ; H19.1 266.87,26.63 ; 234,103.69 JUSB2.12 ; JUSB2.12 234.95,106.51 ; JUSB2.12 234,105.1 ; JUSB2.12 234,106.51 ; JUSB2.12 234.95,103.69 ; JMDP1.21 292.29,80.37 ; JMDP1.21 292.29,78.93 ; JMDP1.21 293.47,78.93 ; JMDP1.21 291.11,79.65 ; JMDP1.21 291.11,80.37 ; JMDP1.21 293.47,79.65 ; JMDP1.21 293.47,80.37 ; 299.7,9.56 H11.1 ; H11.1 300.87,12.32 ; H11.1 298.11,11.15 ; H11.1 298.53,12.32 ; H11.1 300.87,9.98 ; H11.1 299.7,12.74 ; H11.1 298.53,9.98 ; H11.1 301.29,11.15 ; H16.1 124.09,50.84 ; H16.1 120.31,52.43 ; H16.1 124.09,54.03 ; H16.1 122.5,50.25 ; H16.1 120.9,54.03 ; H16.1 120.9,50.84 ; H16.1 124.68,52.43 ; H16.1 122.5,54.62 ; H15.1 179.42,76.17 ; H15.1 176.23,72.98 ; H15.1 180.01,74.58 ; H15.1 176.23,76.17 ; H15.1 177.82,76.76 ; H15.1 179.42,72.98 ; H15.1 177.82,72.39 ; H15.1 175.64,74.58 ; JHDMI1.20 208.83,97.42 ; JHDMI1.20 207.07,99.17 ; JHDMI1.20 208.83,100.92 ; JHDMI1.20 208.83,99.17 ; JHDMI1.20 207.95,97.42 ; JHDMI1.20 207.07,97.42 ; 288.16,60.29 JUSB3.4 ; JUSB3.4 288.8,58.82 ; JUSB3.4 287.97,59.65 ; JUSB3.4 288.8,60.48 ; JUSB3.4 288.16,59.02 ; JUSB3.4 289.43,59.02 ; 215.24,100.53 JHDMI1.11 ; JHDMI1.11 216.16,99.61 ; JHDMI1.11 215.7,100.65 ; JHDMI1.11 216.16,100.53 ; JHDMI1.11 215.24,99.61 ; JHDMI1.11 215.7,99.49 ; 221.57,99.17 JHDMI1.21 ; JHDMI1.21 223.33,97.42 ; JHDMI1.21 222.45,97.42 ; JHDMI1.21 221.57,100.92 ; JHDMI1.21 223.33,99.17 ; JHDMI1.21 221.57,97.42 ; 282.11,49.65 H9.1 ; H9.1 282.53,48.48 ; H9.1 284.87,48.48 ; H9.1 284.87,50.82 ; H9.1 282.53,50.82 ; H9.1 285.29,49.65 ; H9.1 283.7,51.24 ; H9.1 283.7,48.06 ; JMDP1.22 298.07,81.07 ; JMDP1.22 296.99,79.63 ; JMDP1.22 298.07,80.35 ; JMDP1.22 295.91,80.35 ; JMDP1.22 295.91,81.07 ; JMDP1.22 295.91,79.63 ; JMDP1.22 298.07,79.63 ; JMDP1.22 296.99,81.07 ; 292.29,68.73 JMDP1.23 ; JMDP1.23 293.47,69.45 ; JMDP1.23 293.47,70.17 ; JMDP1.23 292.29,70.17 ; JMDP1.23 291.11,69.45 ; JMDP1.23 291.11,68.73 ; JMDP1.23 293.47,68.73 ; 234.95,96.44 JUSB2.11 ; JUSB2.11 234.95,100.15 ; JUSB2.11 234,100.15 ; JUSB2.11 234,98.3 ; JUSB2.11 235.9,96.44 ; JUSB2.11 234,96.44 ; SW1.4 298.28,2.42 ; SW1.4 296.52,1.66 ; SW1.4 296.28,2.42 ; SW1.4 296.52,3.18 ; SW1.4 298.04,1.66 ; SW1.4 297.28,3.42 ; SW1.4 297.28,1.41 ; SW1.4 298.04,3.18 ; 218.24,99.61 JHDMI1.17 ; JHDMI1.17 219.16,100.53 ; JHDMI1.17 218.24,100.53 ; JHDMI1.17 218.7,99.49 ; JHDMI1.17 219.16,99.61 ; JHDMI1.17 218.7,100.65 ; 80.46,95.87 JUSB1.4 ; JUSB1.4 81.94,95.87 ; JUSB1.4 81.2,95.13 ; JUSB1.4 81.77,95.3 ; JUSB1.4 81.77,96.44 ; JUSB1.4 80.63,95.3 ; JUSB1.4 81.2,96.61 ; JUSB1.4 80.63,96.44 ; 84.13,97.94 JUSB1.7 ; JUSB1.7 85.27,96.8 ; JUSB1.7 85.44,97.37 ; JUSB1.7 84.13,96.8 ; JUSB1.7 83.96,97.37 ; JUSB1.7 84.7,96.63 ; JUSB1.7 85.27,97.94 ; 68.81,60.38 H7.1 ; H7.1 71.15,60.38 ; H7.1 71.15,62.72 ; H7.1 71.57,61.55 ; H7.1 69.98,59.96 ; H7.1 68.81,62.72 ; H7.1 68.39,61.55 ; H7.1 69.98,63.14 ; 134.5,80.83 H21.1 ; H21.1 134.5,83.17 ; H21.1 135.67,80.41 ; H21.1 136.84,83.17 ; H21.1 135.67,83.59 ; H21.1 134.08,82 ; H21.1 137.26,82 ; H21.1 136.84,80.83 ; JUSB3.12 297.75,64.63 ; JUSB3.12 298.93,63.85 ; JUSB3.12 298.93,64.63 ; JUSB3.12 296.57,64.63 ; JUSB3.12 296.57,63.85 ; H13.1 153.29,15.65 ; H13.1 151.7,17.24 ; H13.1 151.7,14.06 ; H13.1 152.87,14.48 ; H13.1 152.87,16.82 ; H13.1 150.11,15.65 ; H13.1 150.53,14.48 ; H13.1 150.53,16.82 ; JUSB2.4 239.3,96.61 ; JUSB2.4 239.3,95.13 ; JUSB2.4 239.87,95.3 ; JUSB2.4 239.87,96.44 ; JUSB2.4 238.73,95.3 ; JUSB2.4 240.04,95.87 ; JUSB2.4 238.56,95.87 ; JUSB2.4 238.73,96.44 ; JUSB2.13 251.6,105.1 ; JUSB2.13 250.65,103.69 ; JUSB2.13 251.6,106.51 ; JUSB2.13 251.6,103.69 ; JUSB2.13 250.65,106.51 ; 120.9,72.98 H14.1 ; H14.1 124.09,72.98 ; H14.1 124.09,76.17 ; H14.1 122.5,72.39 ; H14.1 124.68,74.58 ; H14.1 120.9,76.17 ; H14.1 122.5,76.76 ; H14.1 120.31,74.58 ; 212.24,100.53 JHDMI1.5 ; JHDMI1.5 213.16,100.53 ; JHDMI1.5 212.24,99.61 ; JHDMI1.5 212.7,99.49 ; JHDMI1.5 212.7,100.65 ; JHDMI1.5 213.16,99.61 ; JUSB1.10 93.5,96.44 ; JUSB1.10 93.5,100.15 ; JUSB1.10 93.5,98.3 ; JUSB1.10 92.55,100.15 ; JUSB1.10 91.6,96.44 ; JUSB1.10 92.55,96.44 ; 290.98,1.41 SW1.5 ; SW1.5 290.22,1.66 ; SW1.5 290.98,3.42 ; SW1.5 290.22,3.18 ; SW1.5 289.98,2.42 ; SW1.5 291.98,2.42 ; SW1.5 291.74,1.66 ; SW1.5 291.74,3.18 ; 223.37,106.15 JHDMI1.23 ; JHDMI1.23 224.45,104.57 ; JHDMI1.23 225.53,106.15 ; JHDMI1.23 223.37,104.57 ; JHDMI1.23 223.37,107.73 ; JHDMI1.23 224.45,107.73 ; JHDMI1.23 225.53,107.73 ; JHDMI1.23 225.53,104.57 ; JMDP1.7 294.58,76.13 ; JMDP1.7 293.95,74.97 ; JMDP1.7 293.31,74.97 ; JMDP1.7 293.95,76.13 ; 76.85,96.44 JUSB1.11 ; JUSB1.11 75.9,96.44 ; JUSB1.11 75.9,98.3 ; JUSB1.11 75.9,100.15 ; JUSB1.11 77.8,96.44 ; JUSB1.11 76.85,100.15 ; 183.11,105.85 H3.1 ; H3.1 186.29,105.85 ; H3.1 185.87,104.68 ; H3.1 185.87,107.02 ; H3.1 183.53,104.68 ; H3.1 183.53,107.02 ; H3.1 184.7,104.26 ; H3.1 184.7,107.44 ; JUSB1.12 76.85,106.51 ; JUSB1.12 75.9,105.1 ; JUSB1.12 76.85,103.69 ; JUSB1.12 75.9,103.69 ; JUSB1.12 75.9,106.51 ; 204.87,107.73 JHDMI1.22 ; JHDMI1.22 204.87,104.57 ; JHDMI1.22 204.87,106.15 ; JHDMI1.22 205.95,104.57 ; JHDMI1.22 205.95,107.73 ; JHDMI1.22 207.03,104.57 ; JHDMI1.22 207.03,106.15 ; JHDMI1.22 207.03,107.73 ; 242.8,96.63 JUSB2.7 ; JUSB2.7 243.37,96.8 ; JUSB2.7 243.37,97.94 ; JUSB2.7 242.23,97.94 ; JUSB2.7 242.06,97.37 ; JUSB2.7 242.23,96.8 ; JUSB2.7 243.54,97.37 ; H6.1 292.47,91.82 ; H6.1 292.89,90.65 ; H6.1 291.3,92.24 ; H6.1 290.13,91.82 ; H6.1 290.13,89.48 ; H6.1 292.47,89.48 ; H6.1 291.3,89.06 ; H6.1 289.71,90.65 ; JHDMI1.2 211.66,99.03 ; JHDMI1.2 211.2,99.15 ; JHDMI1.2 211.66,98.11 ; JHDMI1.2 211.2,97.99 ; JHDMI1.2 210.74,98.11 ; JHDMI1.2 210.62,98.57 ; JHDMI1.2 210.74,99.03 ; H4.1 231.37,104.68 ; H4.1 229.03,104.68 ; H4.1 231.79,105.85 ; H4.1 231.37,107.02 ; H4.1 230.2,104.26 ; H4.1 229.03,107.02 ; H4.1 230.2,107.44 ; H4.1 228.61,105.85 ; JMDP1.13 293.95,74.13 ; JMDP1.13 293.31,74.13 ; JMDP1.13 293.95,72.97 ; JMDP1.13 294.58,72.97
  BOTTOM w0.102: v4(200.96,42.35) v2(201.67,42.35) ; v2(37.97,10.91) v4(37.97,10.26) ; v4(79.74,58.7) v2(79.74,59.4) ; v4(38.68,24.83) v2(39.52,24.83) ; v4(269.15,55.31) v2(268.46,55.31) ; 109.71,59.7 v4(109.71,60.55)
  BOTTOM w0.127: UC1.AY22 157.84,51.18 157.84,50.29 v2(157.88,50.26) ; 143.24,53.29 143.24,52.98 143.25,52.96 143.25,52.7 142.89,52.33 UC1.AV46 ; UC1.AV36 149.19,52.33 149.55,52.7 149.55,53.15 149.48,53.22 ; UC1.AV39 147.61,52.33 147.98,52.7 147.98,53.2 147.96,53.22 ; 146.45,53.22 146.4,53.18 146.4,52.7 146.04,52.33 UC1.AV41 ; UC1.AV43 144.46,52.33 144.83,52.7 144.83,53.17 144.78,53.21
  BOTTOM w0.152: v2(168.41,60.02) 168.48,60.08 168.48,60.46 168.68,60.67 168.97,60.67 169.31,60.33 UC1.AD3 ; v2(154.92,50.04) 154.92,50.1 155.11,50.29 UC1.AY26
  BOTTOM w0.178: UC1.AV59 UC1.AW59 ; UC1.AP52 139,54.44 139,54.19 UC1.AR52 ; v2(150.62,53.73) 150.35,53.46 UC1.AT35 ; UC1.P59 134.46,65.84 v2(134.46,65.95) ; v2(169.05,71.94) 169.17,71.82 169.67,71.82 170.06,71.43 UC1.D2 ; UC1.AV51 UC1.AW51 UC1.AY51 139.8,49.77 v2(140.27,49.3) ; v2(134.66,50.27) 134.7,50.3 UC1.AY59 ; UC1.AY57 136.02,50.3 v2(135.95,50.23) ; UC1.AV33 151.33,52.45 UC1.AW33 ; UC1.AT43 UC1.AT46 ; UC1.AU33 152.15,53.18 152.17,53.15 UC1.AU30 ; UC1.Y63 131.68,62.58 v2(131.56,62.46) ; UC1.AW33 151.09,51.85 UC1.AV34 ; UC1.AW33 UC1.AY33 ; v2(161.65,50.2) 161.6,50.25 UC1.AY16 161.56,51.24 UC1.AW16 UC1.AV16 ; v2(131.28,54.99) 131.41,55.12 UC1.AN63 ; UC1.AY30 152.68,50.36 v2(152.61,50.28) ; v2(160.18,50.28) 160.25,50.35 UC1.AY18 ; 148.21,53.22 147.96,53.22 ; v2(167.55,72.22) 167.43,72.22 166.93,71.72 UC1.D8 ; UC1.AJ63 132.48,57.54 131.86,57.54 131.63,57.31 131.33,57.31 v2(131.3,57.28) ; v2(138.26,50) 138.41,50.16 138.41,50.52 138.45,50.55 UC1.AY53 ; UC1.AD63 132.14,60.34 v2(131.64,60.34) ; v2(156.39,50.27) 156.47,50.35 UC1.AY24 UC1.AW24 UC1.AV24
  BOTTOM w0.203: UC1.B56 UC1.A56 ; UC1.V3 169.21,63.05 v2(169.21,62.92) ; UC1.U20 158.78,64.05 v2(158.73,64.1) ; UC1.AE5 168.15,59.75 v2(168.41,60.02) ; UC1.F58 135.41,70.77 134.88,71.29 UC1.D59 ; v2(68.12,11.09) 68.13,11.09 68.42,11.39 PU200.1 ; UC1.AV8 165.84,52.18 v2(165.53,52.48) ; UC1.K1 170.78,67.8 171.06,68.07 v2(171.31,68.07) ; UC1.T1 v2(171.32,64.79) ; UC1.F61 133.46,70.15 v2(133.16,70.45) ; v2(68.12,10.08) 68.63,10.59 PU200.3 ; UC1.AW59 134.46,51.53 UC1.AW60 ; UC1.AN49 140.88,55.29 140.77,55.18 140.4,55.18 140.29,55.29 UC1.AN51 139.95,55.29 139.82,55.16 139.44,55.16 139.31,55.29 UC1.AN52 ; v2(227.45,86.38) 227.62,86.22 UV7.38 ; v2(226.2,86.4) 226.2,86.01 226.42,85.8 UV7.35 ; CC8.1 153.32,80.75 152.46,81.61 152.46,84.73 152.64,84.91 156.52,84.91 156.8,84.63 156.8,81.16 CC11.1 ; UV7.26 222.19,83.51 v2(222.18,83.51) ; UC1.AN7 167.29,55.67 v2(167.48,55.67) ; v2(131.58,68.7) 131.7,68.57 UC1.J63 ; v2(169.09,56.93) 169.48,57.33 UC1.AK3 ; UV7.43 230.49,84.31 v2(230.87,84.68) ; UC1.AY6 167.41,50.44 167.34,50.37 v2(167.34,49.94) ; v2(169.78,65.91) 169.48,66.21 UC1.N3 ; UC1.B44 UC1.A44 ; UC1.U61 133.46,64.15 v2(133.16,64.45) ; UC1.AM1 171.19,55.8 v2(171.4,56) ; PU501.3 102.94,56.79 v2(102.73,57) ; v2(169.06,50.18) 168.86,50.38 UC1.AY4 168.81,50.93 UC1.AW4 ; v2(133.16,61.46) 133.16,61.35 133.46,61.05 UC1.AC61
  BOTTOM w0.229: UC1.L61 133.46,67.15 v2(133.17,67.44) ; UC1.AN42 145.94,55.29 v2(146.26,54.96) 146.59,55.29 UC1.AN40 ; UC1.AH53 138.66,57.1 v2(138.68,57.08) ; UC1.AR33 150.88,53.99 v2(150.62,53.73) 151.17,53.18 UC1.AU33 ; v2(145.28,57.66) 145.51,57.89 UC1.AJ41 ; v2(145.28,57.66) 144.75,57.66 UC1.AJ43 ; v2(145.28,57.66) 145.16,57.77 UC1.AH42 ; UC1.AP54 138.11,54.64 v2(137.78,54.31) ; UC1.AH57 136.38,57.89 UC1.AJ56 ; UC1.AH57 136.2,58.36 136.45,58.36 v2(136.84,58.75) ; UC1.AH57 135.73,57.89 UC1.AJ58 ; UC1.AH28 154.26,58.59 v2(154.12,58.74) ; v2(149.58,58.4) 149.58,58.02 UC1.AJ35 ; v2(149.58,58.4) 150.18,58.4 UC1.AH34 ; v2(149.58,58.4) 149.24,58.4 UC1.AH36 ; UC1.AH49 141.26,57.77 v2(141.37,57.66) ; UC1.AW35 150.29,51.88 v2(150.35,51.88) 150.35,51.89 150.64,52.18 UC1.AV34 ; UC1.AN40 146.98,55.62 UC1.AN39 ; UC1.AN40 146.98,54.96 UC1.AP39 ; UC1.AH24 156.86,57.59 v2(156.84,57.57) 157.17,57.24 ; 157.17,57.24 v2(156.84,56.92) 157.17,56.59 ; 157.17,57.24 UC1.AK23 ; UC1.AJ13 163.84,57.05 v2(163.96,57.05) ; 157.17,56.59 UC1.AL23 ; 157.17,56.59 v2(156.84,56.27) 157.17,55.94 UC1.AM23 ; UC1.V23 158.08,63.24 UC1.W22 ; 145.38,55.02 145.16,55.02 UC1.AN43 144.63,55.03 144.17,55.03 UC1.AN45 143.8,55.18 143.09,55.18 UC1.AN46 142.76,55.29 v2(142.49,55.56) 142.22,55.29 UC1.AN48 ; v2(164.64,62.86) 164.85,62.86 UC1.Y10 ; v2(156.91,53.47) 157.04,53.47 157.35,53.15 UC1.AU22 158.19,53.15 158.23,53.2 158.54,53.2 158.58,53.15 UC1.AU20 159.48,53.15 159.53,53.2 159.83,53.2 159.87,53.15 UC1.AU18 160.73,53.15 160.77,53.2 161.08,53.2 161.12,53.15 UC1.AU16 ; UC1.F42 145.48,69.8 v2(145.47,69.8) ; v2(138.68,57.08) 138.19,56.59 UC1.AL54 ; v2(138.68,57.08) 138.84,57.24 UC1.AK52 139.31,57.35 UC1.AJ52 ; UC1.AH34 150.39,58.22 v2(150.9,58.73) ; UC1.AH34 150.36,57.79 v2(150.51,57.63) ; UC1.AH38 147.53,58.45 v2(147.11,58.45) ; UC1.U22 158.23,64.1 v2(158.73,64.1) 158.18,64.65 UC1.R22 ; UC1.AT35 149.92,53.29 149.85,53.22 149.48,53.22 149.41,53.29 UC1.AT37 148.28,53.29 148.2,53.21 147.27,53.21 UC1.AT40 146.51,53.29 146.45,53.22 146.08,53.22 146.01,53.29 UC1.AT42 145.55,53.21 144.12,53.21 UC1.AT43 144.05,53.32 v2(144.39,53.66) 144.72,53.99 UC1.AR43 ; UC1.AL52 139.01,56.59 138.68,56.27 v2(138.75,56.27) 138.81,56.27 139.14,55.94 ; UC1.F30 153,69.8 v2(152.99,69.8) ; UC1.AL39 147.24,57.28 147.11,57.42 UC1.AJ39 ; UC1.AV39 147.49,52.18 v2(147.2,51.88) 146.84,51.53 UC1.AW40 ; UC1.AV46 142.83,52.18 v2(142.47,51.83) 142.18,51.53 UC1.AW47 ; 162.25,57.61 162.44,57.61 162.67,57.38 UC1.AJ14 162.69,57.04 163,56.73 UC1.AL13 ; 162.25,57.61 161.56,56.93 UC1.AL17 ; 162.25,57.61 v2(162.25,57.6) ; UC1.F50 140.46,69.8 v2(140.46,69.8) ; UC1.AN31 UC1.AM31 UC1.AL31 152.52,57.06 v2(153.03,57.57) 153.36,57.89 UC1.AJ29 ; UC1.AN31 152.19,55.62 151.96,55.39 UC1.AN32 ; UC1.AN31 UC1.AP31 UC1.AR31 152.52,53.31 UC1.AU30 153.06,53.15 153.1,53.2 153.41,53.2 153.45,53.15 UC1.AU28 154.35,53.15 154.39,53.2 154.7,53.2 154.74,53.15 UC1.AU26 155.59,53.15 155.64,53.2 155.94,53.2 155.99,53.15 UC1.AU24 ; UC1.J10 164.86,68.75 v2(164.86,69.32) ; UC1.AL20 159.92,56.59 v2(159.59,56.27) ; UC1.AU51 139.32,53.15 139.28,53.2 138.98,53.2 138.93,53.15 UC1.AU53 138.08,53.15 138.04,53.2 137.73,53.2 137.69,53.15 UC1.AU55 136.79,53.15 136.74,53.2 136.44,53.2 136.39,53.15 UC1.AU57 135.54,53.15 135.5,53.2 135.19,53.2 135.15,53.15 UC1.AU59 ; v2(135.91,64.9) 135.79,64.78 UC1.T58 ; v2(135.88,54.31) 136.2,54.64 UC1.AP57 ; UC1.F38 147.98,69.8 v2(147.98,69.8) ; UC1.AP26 155.26,54.64 v2(154.94,54.31) ; UC1.AV49 141.01,51.88 v2(140.9,51.88) 140.55,51.53 UC1.AW50 ; UC1.AN48 141.76,55.12 141.2,55.12 UC1.AN49 ; UC1.AN48 UC1.AP48 141.82,54.64 v2(141.49,54.31) ; v2(141.37,57.66) 140.91,57.66 140.68,57.89 UC1.AJ50 ; v2(141.37,57.66) 141.67,57.66 141.9,57.89 UC1.AJ47 142.26,57.89 v2(142.49,57.66) 142.98,57.66 UC1.AJ45 ; v2(166.48,60.97) 166.48,61.09 UC1.AB7 ; UC1.AG1 171.16,58.79 v2(171.31,58.65) ; v2(138.7,55.64) 138.84,55.64 139.14,55.94 ; v2(166.95,63.84) 166.85,63.73 UC1.V7 ; v2(159.59,54.31) 159.92,54.64 UC1.AP20 ; v2(147.11,58.45) UC1.AJ39 ; v2(147.11,58.45) 146.69,58.45 UC1.AH40 ; UC1.AJ39 147.47,57.89 147.76,57.6 v2(147.76,57.57) ; v2(163.15,59.88) 163.15,59.28 UC1.AF14 ; UC1.AR39 v2(147.76,54.31) 148.08,54.64 UC1.AP38 ; v2(137.27,52) 137.24,52.03 UC1.AV55 ; v2(134.34,54) 134.47,54.13 134.47,54.6 134.43,54.64 UC1.AN60 134.43,55.49 134.48,55.54 134.48,55.92 134.43,55.97 UC1.AL60 ; 139.14,55.94 UC1.AM52 ; v2(149.66,54.96) 149.99,55.29 UC1.AN35 ; UC1.L15 162.47,66.9 v2(163.05,66.32) 163.42,66.69 UC1.L13 163.86,67.81 UC1.K12 ; UC1.AL57 136.2,56.59 v2(135.88,56.27) ; v2(138.71,55.04) 138.8,55.04 139.05,55.29 UC1.AN52 ; UC1.AP22 158.01,54.64 v2(157.69,54.31) ; UC1.AB20 159.95,61.96 v2(160.03,61.96) ; UC1.D5 168.22,71.78 168.23,71.78 168.28,71.82 168.93,71.82 v2(169.05,71.94) ; UC1.AL60 134.43,56.79 134.47,56.83 134.47,57.14 134.43,57.18 UC1.AJ60 ; UC1.AL60 UC1.AL61 133.31,56.34 v2(133.27,56.3) ; UC1.AP29 153.36,54.64 v2(153.03,54.31) ; UC1.AL51 139.96,56.59 v2(139.63,56.27) ; v2(135.96,63.48) UC1.V58 ; UC1.F46 142.97,69.8 v2(142.96,69.8) ; UC1.AW44 143.71,51.53 v2(144.06,51.87) 144.2,51.87 144.46,52.13 UC1.AV43 ; UC1.AL45 143.9,56.59 143.64,56.32 v2(143.44,56.32) 143.25,56.32 UC1.AL46 ; v2(158.73,61.66) 158.68,61.61 UC1.AB22 ; UC1.P22 158.19,65.66 v2(158.69,65.66) ; v2(148.71,56.42) 148.88,56.59 UC1.AL36 ; UC1.A18 v2(160.18,73.98) ; UC1.F34 150.49,69.8 v2(150.49,69.8) ; UC1.AV20 159.03,52.03 v2(159.07,52) ; v2(155.5,69.8) 155.51,69.8 UC1.F26 ; v2(157.69,56.27) 158.01,56.59 UC1.AL22 ; UC1.F54 137.95,69.8 v2(137.95,69.8) ; v2(154.94,56.27) 155.26,56.59 UC1.AL26 ; UC1.W20 159.6,63.48 v2(160.13,64.01) 160.09,64.05 UC1.U20 ; v2(153.03,56.27) 153.36,56.59 UC1.AL29 ; UC1.AW42 145.29,51.53 v2(145.63,51.87) 145.94,52.18 UC1.AV41 ; UC1.AH32 151.55,58.1 v2(151.55,57.57) ; UC1.AN23 157.17,55.29 v2(156.84,54.96) 157.17,54.64 UC1.AP23 ; v2(131.45,58.81) 131.63,58.99 132.39,58.99 UC1.AG63 UC1.AG62 UC1.AG61 UC1.AG60 ; v2(148.78,51.83) 148.47,51.53 UC1.AW37 ; UC1.AH17 161.25,57.85 161.7,57.85 UC1.AH16 ; v2(164.41,50.18) UC1.AY11 ; UC1.AV28 153.9,52.03 v2(153.93,52) ; v2(148.71,55.12) 148.88,55.29 UC1.AN36 ; UC1.AL33 150.88,56.59 v2(150.62,56.33) ; UC1.AA58 v2(135.96,62.18) ; UC1.H13 v2(163.02,69.33) ; v2(160.04,59.69) 160.51,59.22 UC1.AF18 ; UC1.AE58 v2(135.96,59.58)
  BOTTOM w0.254: UC1.AF17 161.47,59.39 v2(161.91,59.82) 162.29,59.44 UC1.AF15 ; RPC6.2 179.42,64.88 179.12,65.19 v2(179.12,65.89) ; UC1.G8 166.6,69.91 v2(166.8,69.91) 166.9,69.91 UC1.G6 167.45,69.59 v2(167.76,69.9) 168.07,69.59 UC1.G5 ; v2(140.65,53.71) 140.65,53.57 140.87,53.34 UC1.AT49 ; v2(140.65,53.71) 140.92,53.99 UC1.AR49 ; v2(140.65,53.71) 140.39,53.71 139.83,53.15 UC1.AU51 ; v2(168.4,53.77) 168.25,53.77 UC1.AR5 ; v2(134.88,57.83) 134.6,57.55 UC1.AJ60 ; v2(167.01,67.63) 167.01,67.33 UC1.L7 ; UC1.AU24 156.6,53.15 v2(156.91,53.47) 156.91,53.66 157.24,53.99 UC1.AR23 ; UC1.AU59 UC1.AV59 ; UC1.AV14 162.87,52.18 v2(162.54,52.5) ; UC1.P22 UC1.M22 ; UC1.C20 159.27,72.57 159.42,72.72 v2(159.42,73.01) 159.07,73.01 UC1.B20 ; v2(164.44,73.99) 164.44,73.53 UC1.A11 ; UC1.AL10 165.16,56.73 v2(165.49,56.4) ; v2(165.57,54.67) 165.57,54.67 165.57,54.67 165.58,54.67 165.58,54.66 165.25,54.66 UC1.AP10 ; UC1.L18 161.02,66.9 v2(161.03,66.9) 161.06,66.9 UC1.L17 ; v2(169.15,53.95) 169.15,54 UC1.AP3 ; v2(164.64,62.86) 165.14,63.36 UC1.V10 165.31,63.39 UC1.U9 ; JEDP1.15 105.96,89.56 v2(106.19,89.33) ; v2(148.25,58.71) UC1.AH38 ; UC1.AH40 146.32,58.08 v2(146.32,57.67) 146.04,57.67 UC1.AJ41 ; UC1.AJ43 144.18,58.22 UC1.AH44 ; UC7.7 90.03,55.94 90.17,55.8 90.37,55.8 90.52,55.95 v2(90.52,56.3) ; UC1.C25 155.74,72.53 UC1.B26 ; v2(156.7,58.75) 156.91,58.75 156.99,58.66 157.56,58.66 UC1.AG23 UC1.AJ23 158.04,57.95 v2(158.29,57.7) ; UC1.AA1 171.18,61.79 v2(171.3,61.91) ; UC1.F20 159.59,70.24 159.15,69.8 v2(159.07,69.8) 159.01,69.74 UC1.G22 158.18,69.83 158.55,70.2 UC1.D21 158.04,71.08 UC1.D23 ; v2(144.35,58.71) UC1.AH44 ; UC1.AH44 143.53,58.22 UC1.AJ45 ; UC1.AT13 163.56,53.84 163.62,53.84 ; RPC20.7 168.98,83.86 v2(168.75,84.08) 168.59,83.92 168.59,83.73 168.48,83.62 RPC20.6 ; v2(171.38,52.72) 171.25,52.85 UC1.AU1 ; v2(164.63,65.68) 164.77,65.68 UC1.N10 ; UC1.AL17 UC1.AM17 UC1.AN17 UC1.AP17 UC1.AR17 161.56,53.96 161.93,53.59 v2(162.19,53.59) 162.43,53.59 UC1.AR15 ; UC1.AF12 163.91,59.12 UC1.AG11 ; UC1.F46 UC1.D46 ; v2(145.39,55.02) 145.38,55.02 145.45,55.09 145.64,55.09 UC1.AN42 ; v2(151.95,71.97) 151.75,72.18 UC1.B32 151.55,72.73 151.55,72.94 151.75,73.13 UC1.A32 ; UC1.H17 161.19,69.26 v2(161.02,69.26) 160.89,69.26 UC1.G18 ; UC1.AL40 146.98,56.92 UC1.AL39 ; UC1.AL40 147.24,56 UC1.AN39 ; UC1.AL40 146.26,56.2 146.26,56.2 v2(146.24,56.21) ; UC1.F54 UC1.D54 ; UC1.AH17 UC1.AH19 160.25,57.62 v2(160.39,57.48) ; UC1.D59 134.88,71.63 134.22,72.29 134.22,72.74 UC1.B60 ; UC1.AJ29 153.94,57.89 UC1.AH28 154.59,57.89 UC1.AJ27 155.11,57.7 155.64,57.7 v2(155.75,57.58) 155.9,57.58 UC1.AJ25 ; v2(154.45,71.97) 154.69,72.21 UC1.C27 ; UC1.E11 164.01,71.25 v2(163.89,71.25) 163.89,71.56 UC1.D12 164.05,71.93 UC1.C11 ; UC1.AR52 139.02,53.99 138.45,53.42 UC1.AU53 ; v2(163.62,53.84) 163.62,53.84 ; 163.62,53.84 164.53,53.84 UC1.AR11 ; UC1.U22 157.77,63.64 UC1.V23 ; JSATA1.12 264.44,5.68 v2(264.44,5.68) ; UC1.F38 UC1.D38 ; UC1.AL13 163.47,56.73 v2(164.13,56.07) ; v2(158.69,65.66) 159.1,66.06 UC1.N21 ; UC1.F30 UC1.D30 ; UC1.AH51 139.63,58.22 UC1.AJ52 ; UC1.AH51 139.88,58.14 v2(139.88,57.71) ; UC1.AH51 140.28,58.22 UC1.AJ50 ; UC1.B4 168.39,72.86 v2(168.36,72.9) ; JSATA1.4 v2(260.44,5.66) ; UC1.AH22 158.2,58.39 UC1.AG21 158.83,57.89 v2(159.01,57.71) 159.12,57.71 UC1.AH20 ; JSATA1.18 v2(267.44,5.7) ; UC1.AH55 137.68,57.89 UC1.AJ54 138.33,57.89 UC1.AH53 v2(139.14,58.71) ; UC1.AH55 v2(137.84,58.71) ; UC1.AH55 137.03,57.89 UC1.AJ56 ; v2(163.93,58.36) 164.29,58.72 UC1.AG11 ; JSATA1.14 265.44,5.7 v2(265.45,5.69) ; UC1.AE10 164.98,59.22 UC1.AF11 164.72,59.12 UC1.AG11 ; v2(131.63,65.58) UC1.P63 UC1.P62 ; UC1.J59 134.99,68.77 134.99,68.96 v2(135.21,69.19) ; v2(164.64,61.45) 164.64,61.45 UC1.AB10 ; v2(134.47,62.93) 134.47,62.89 134.76,62.61 UC1.Y59 ; v2(164.65,64.92) 164.97,64.92 UC1.R10 UC1.R8 ; UC1.G3 169.48,69.27 v2(169.83,68.92) ; UC1.AH49 v2(141.75,58.71) ; v2(281.19,5.88) 281.19,6.15 280.99,6.35 UN1.5 ; v2(162.51,74.14) 162.51,73.75 UC1.A14 162.75,73.15 162.87,73.04 162.87,72.33 UC1.C14 163.26,71.9 UC1.D14 163.26,71.5 v2(162.99,71.23) ; UC1.F50 UC1.D50 ; UC1.A28 UC1.B28 ; v2(131.63,71.53) UC1.D63 132.21,71.47 UC1.D62 ; UC1.C18 160.68,71.9 UC1.D18 160.68,71.6 v2(161.02,71.27) 161.14,71.27 UC1.E17 ; JSATA1.7 261.94,5.63 v2(261.95,5.63) ; UC1.F58 135.41,69.96 v2(135.27,69.83) 135.7,69.41 UC1.H57 ; UC1.B24 UC1.A24 156.76,73.5 v2(156.99,73.74) ; UC1.F34 UC1.D34 ; v2(131.72,53.35) 132.03,53.66 UC1.AT63 132.64,53.66 132.79,53.82 UC1.AT62 133.73,53.82 UC1.AT61 134.22,53.87 v2(134.34,54) ; UC1.AD21 158.7,59.99 v2(158.7,59.96) ; UC1.F42 UC1.D42 ; v2(145.65,58.71) UC1.AH42 ; UC1.F26 UC1.D26 ; v2(142.56,58.74) UC1.AH46 ; UC1.AH30 v2(153.45,58.71) ; UC1.AH32 v2(152.15,58.71)
  BOTTOM w0.279: UC1.L58 v2(135.93,67.38) ; UC1.J22 158.18,67.92 v2(158.72,67.38) 158.72,67.38 159.53,67.38 UC1.L20
  BOTTOM w0.305: JNGFF1.7 232.5,32.35 231.76,31.61 v2(231.76,31.3) ; UN1.16 279.69,9.31 v2(280.08,9.7) ; v2(232.18,18.31) 232.22,18.35 233.34,18.35 JNGFF1.55 ; UN1.12 277.21,7.85 v2(276.83,8.22) 276.96,8.35 UN1.13 ; v2(239.71,24.94) 239.87,25.1 JNGFF1.28 ; JNGFF1.15 v2(234.48,28.35) ; JNGFF1.43 233.6,21.35 233.6,21.35 234.39,21.35 234.68,21.64 v2(234.68,22.31) 234.68,22.48 234.31,22.85 JNGFF1.37 ; UN1.15 279.19,8.83 279.19,9.94 CN2.2 ; JNGFF1.49 233.34,19.85 232.22,19.85 v2(232.11,19.95) ; JNGFF1.61 233.58,16.85 234.48,16.85 234.81,16.52 v2(234.81,15.44) 234.72,15.35 233.59,15.35 JNGFF1.67 ; JNGFF1.22 239.91,26.6 v2(239.74,26.77) ; v2(231.92,33.92) 231.99,33.85 JNGFF1.1 ; v2(242.76,30.3) 242.06,29.6 240.9,29.6 JNGFF1.10 ; UN1.10 v2(276.84,6.85) ; JNGFF1.21 233.6,26.85 233.6,26.85 235.63,26.85 v2(235.7,26.91) 235.7,26.35 235.2,25.85 233.34,25.85 JNGFF1.25 ; JNGFF1.31 232.39,24.35 v2(232.23,24.19) ; v2(239.79,27.86) 240.02,28.1 240.23,28.1 240.23,28.1 JNGFF1.16
  BOTTOM w0.356: JMDP1.14 v2(289.48,73.65) ; JMDP1.8 v2(289.48,75.45)
  BOTTOM w0.381: v2(282.28,73.1) 281.84,72.66 UV502.7 ; v2(164.35,45.44) 164.21,45.58 RC178.2 RC187.2
  BOTTOM w0.406: v2(275.85,12.75) 275.88,12.72 QN1.4 ; DI6.3 v2(239.39,93.28) ; DI4.3 v2(286.28,59.52) ; DI1.3 v2(87.03,94.12)
  BOTTOM w0.432: QN1.1 v2(277.18,9.32)
  BOTTOM w0.457: CC83.2 132.09,77.09 v2(132.53,77.53) 132.08,77.99 RC123.2 ; RE20.1 115.24,95.88 v2(115.24,95.57)
  BOTTOM w0.508: UV501.2 v2(285.24,68.08) ; v2(229.28,73.49) 229.73,73.94 CV60.2 ; v2(100.78,94.86) 100.46,94.53 CA6.2 ; v2(271.9,20.75) 271.45,20.75 271.12,20.43 JSD1.20 ; v2(208.2,63.44) 208.07,63.31 PC309.2 ; RC186.1 158.78,81.02 v2(158.34,81.46) ; PR209.2 72.84,7.16 73.24,7.56 v2(73.24,8.09) ; v2(278.38,44.03) 278.3,44.11 JSD1.24 ; v2(71.69,102.98) 71.94,103.24 PR12.1 ; v2(273.5,30.57) 272.85,31.22 JSD1.21 ; RV505.1 286.09,77.94 285.48,78.55 v2(285.48,79.04) ; CC17.2 87.32,60.75 v2(86.91,60.34) 86.79,60.22 RC129.1 ; v2(80.41,90.61) 80.56,90.76 DI2.1 ; v2(103.21,94.82) CA5.2 ; CC20.2 125.68,67.33 v2(125.68,66.78) ; CC1.1 CC2.1 v2(183.08,47.1) ; v2(72.56,9.82) PC214.2 PC212.2 ; JFAN1.6 v2(66.16,83.13) ; JSD1.17 v2(294.7,18.05) ; v2(270.01,33.36) 270.72,34.07 JSD1.3 ; v2(108,98.87) 107.85,98.72 QV2.3 ; v2(76.79,90.42) 76.79,90.86 PC709.2 76.11,90.86 v2(76.11,90.42) ; RV504.2 286.01,76.92 v2(285.56,76.47) 285.99,76.03 RV503.1 ; v2(117.21,71.37) 117.08,71.25 PC402.2 115.63,71.25 PR401.2 ; CL18.2 v2(260.92,94.14) ; PR310.2 207.75,61.68 v2(208.26,61.68) ; RV510.2 233.09,83.15 v2(233.51,83.15) ; v2(190.26,53.62) 190.61,53.26 UC3.4 ; v2(14.49,17.11) 16.46,15.13 DA2.1 16.94,14.01 v2(16.39,13.46) ; v2(175.68,63.73) 176.07,63.34 RC171.2 ; v2(34.78,27.09) RA37.2 ; v2(129.1,58.68) 128.82,58.4 RC21.2 ; v2(184.68,47.04) 184.9,46.82 CC3.1 ; JNGFF1.68 232.33,34.95 231.92,34.54 v2(231.92,33.92) ; UC2.4 194.42,70.05 v2(194.22,70.26) ; v2(166.61,81.74) 166.62,81.72 RC142.1 ; v2(181.76,40.91) 181.76,41.6 v4(182.43,42.28) 183.02,42.86 CMOS1.1 ; v2(6.92,6.64) 7.36,6.64 7.81,7.09 DA7.1 ; JSPI1.21 178.38,82.13 v2(178.67,81.84) 178.38,81.55 JSPI1.22 ; RC190.2 RC189.2 v2(126.86,64.43) ; RA36.2 28.53,8.71 v2(28.95,8.29) ; CN2.2 v2(279.52,10.97) ; RC141.1 CC68.2 170.74,81.95 v2(170.53,81.74) ; v2(116.79,74.68) 116.52,74.41 PC400.2 ; v2(282.54,74.96) 282.54,75.71 283.19,76.36 QV502.3 ; PC503.1 97.44,55.73 96.93,55.22 v2(96.93,55.22) ; CC11.1 157.01,80.65 CC82.2 157.01,79.88 157.13,79.76 v2(157.13,79.3) ; v2(96.67,91.48) 96.92,91.48 97.25,91.15 97.25,90.44 96.56,89.74 JEDP1.41 ; CL22.1 v2(286.72,91.59) ; v2(22.35,16.64) 22.26,16.73 RA2.2 ; v2(189.8,62.08) 189.14,61.42 CC6.2 ; RA35.2 33.73,19.69 v2(33.26,19.22) ; PC118.2 217.98,53 v2(217.34,53) ; CC7.2 196.36,56.65 v2(196.62,56.91) ; JSD1.6 272.52,26.97 v2(272.96,26.54) ; v2(107.86,95.53) CV12.2 ; JSD1.22 272.55,43.22 v2(272.75,43.02) ; JNGFF1.69 232.35,14.25 v2(232.04,13.93) ; v2(205.95,63.13) 205.72,63.35 PC310.2 ; DI5.1 285.51,55.86 v2(286.03,56.37) ; CC4.1 187.72,46.32 187.34,46.7 v2(186.34,46.7) ; v2(276.88,5.45) 276.65,5.22 CN1.2 ; CA49.1 32.42,13.94 33.26,14.78 v2(33.26,15.92) ; RV52.2 233.55,86.09 v2(233.55,86.08) ; PC509.2 v2(106.24,56.94) ; v2(152.95,79.36) 152.95,79.68 153.32,80.05 CC8.1 ; JSD1.25 v2(292.4,18.5) ; v2(126.43,60.88) RC183.2 RC184.2 RC188.2 ; RC303.2 184.85,52.74 184.54,53.05 v2(184.54,54.79) ; v2(220.27,53.26) 219.82,52.81 PC117.2 ; RV61.2 v2(223.39,88.89) ; JSATA1.21 269.49,5.93 269.25,5.69 v2(268.44,5.69) ; RV67.1 CV66.2 229.66,88.12 228.8,87.26 v2(228.8,86.44) ; v2(106.54,71.86) 106.54,71.55 106.74,71.34 PR403.2 107.22,71.29 PU400.1 110.04,71.29 v2(110.14,71.18) ; v2(288.05,69.39) CV509.2 RV502.1 ; CC9.1 CC10.1 195.53,61.95 194.56,62.92 v2(193.74,62.92) ; RV514.1 233.92,77.11 v2(234.16,76.88) ; v2(220.72,86.4) CV62.2 RV50.2 ; v2(99.07,94.12) 98.75,94.44 DV4.1 ; JSD1.23 v2(278.3,18.53) ; RC185.2 v2(126.55,63.86) ; DA6.1 3.81,7.02 3.43,6.64 v2(3.05,6.64) ; CV510.2 v2(283.07,65.53) ; v2(244.05,93.69) 243.38,93.01 DI3.1 ; v2(105.71,61.45) PC501.2 ; PC500.2 v2(104.63,62.4) ; CV69.2 221.71,73.98 v2(222.15,73.55) ; RV63.2 v2(234.16,80.02) ; v2(152.73,40.37) 153.13,39.96 CC5.2 ; CV514.2 v2(283.07,68.17)
  vias: v2(0.52,10.69) v2(4.2,5.61) v2(9.28,5.61) v2(14.36,5.61) v2(17.87,5.6) v2(17.88,7.77) v2(19.44,5.61) v2(24.52,5.61) v2(25.71,10.85) v2(25.89,7.79) v2(29.11,5.6) v2(31.38,8.42) v2(31.61,19.22) v2(31.8,17.57) v2(31.8,15.92) v2(33.26,17.57) v2(33.63,8.43) v2(33.69,5.59) v2(33.93,7.92) v2(34.26,8.43) v2(34.27,28.24) v2(34.91,19.22) v2(34.91,17.57) v2(34.91,15.92) v2(37.35,10.91) v2(37.36,10.32) v2(38.67,5.61) v2(39.81,28.47) v2(45.25,29.63) v2(49.5,101.1) v2(49.5,98.56) v2(49.5,96.02) v2(49.5,93.48) v2(49.5,90.94) v2(50.11,89.24) v2(50.4,31.72) v2(51.84,101.38) v2(53.06,108.76) v2(53.01,104.25) v2(54.14,89.04) v2(54.68,105.84) v2(55.08,34.67) v2(55.48,107.62) v2(55.64,12.88) v2(55.9,103.9) v2(57.95,107.62) v2(58.11,104.2) v2(58.86,105.88) v2(59.17,108.99) v2(59.17,38.4) v2(59.52,88.92) v2(60.63,103.03) v2(60.63,102.45) v2(61.2,87.12) v2(62.37,85.62) v2(62.54,42.77) v2(62.91,108.19) v2(63.29,84.56) v2(63.55,108.19) v2(64.25,108.99) v2(64.56,108.23) v2(64.49,28.42) v2(64.97,11.12) v2(65.12,47.73) v2(65.34,28.42) v2(65.28,11.63) v2(65.69,108.23) v2(65.96,69.49) v2(66.23,28.42) v2(66.33,108.23) v2(66.79,53.06) v2(67.12,28.42) v2(67.1,11.09) v2(67.1,10.08) v2(67.21,64.08) v2(67.49,58.55) v2(68.17,61.48) v2(68.92,63.18) v2(68.93,59.83) v2(69.33,108.99) v2(71.11,59.83) v2(71.23,63.17) v2(71.55,12.43) v2(71.55,11.79) v2(72.02,61.54) v2(74.41,108.99) v2(77.07,81.1) v2(77.07,80.52) v2(77.25,108.08) v2(77.25,101.9) v2(77.68,81.1) v2(79.13,29.81) v2(79.12,20.3) v2(79.25,12.24) v2(79.25,10.72) v2(79.6,14.65) v2(80.96,94.41) v2(80.93,29.81) v2(81.06,14.66) v2(81.1,9.63) v2(81.52,65.96) v2(82,35.85) v2(82.15,65.96) v2(82.32,12.16) v2(82.32,10.21) v2(82.69,14.93) v2(82.69,13.72) v2(83.17,89.69) v2(83.27,65.93) v2(83.51,90.21) v2(83.91,65.93) v2(84.1,12.11) v2(84.1,10.59) v2(84.72,65.9) v2(85.25,20.3) v2(85.25,18.77) v2(85.35,65.9) v2(85.66,14.93) v2(86.34,86.92) v2(86.39,41.74) v2(86.5,6.87) v2(86.62,37.67) v2(86.64,12.11) v2(86.64,10.59) v2(87.86,45.15) v2(88,14.97) v2(87.99,13.18) v2(88.3,12.11) v2(88.3,10.59) v2(88.3,6.87) v2(88.76,85.73) v2(88.77,85.01) v2(89.37,14.96) v2(89.36,13.67) v2(89.68,88.95) v2(89.72,85.57) v2(89.77,58.22) v2(89.78,57.58) v2(91.07,91.11) v2(91.06,20.3) v2(91.06,18.77) v2(91.08,86.74) v2(91.4,14.97) v2(91.7,84.78) v2(92.14,102.34) v2(92.2,6.86) v2(92.3,84.78) v2(92.57,11.53) v2(92.57,10.36) v2(93.1,14.93) v2(93.1,13.08) v2(93.26,86.74) v2(93.38,91.1) v2(94.22,96.8) v2(94.41,11.4) v2(94.41,10.23) v2(94.71,88.95) v2(94.7,20.3) v2(94.7,18.77) v2(94.9,6.86) v2(95.24,14.95) v2(96.21,108.99) v2(96.58,104.88) v2(96.7,6.86) v2(96.93,12.11) v2(96.93,10.59) v2(97.02,14.9) v2(97.24,20.3) v2(97.24,18.77) v2(98.43,12.5) v2(98.43,10.21) v2(99.76,18.77) v2(99.7,12.11) v2(99.7,10.59) v2(100.3,6.86) v2(100.39,91.36) v2(101.2,57.64) v2(101.2,57) v2(101.2,56.37) v2(101.2,55.73) v2(101.2,55.1) v2(101.2,54.34) v2(101.2,53.58) v2(101.96,57.64) v2(101.96,57) v2(101.96,56.37) v2(101.96,55.73) v2(101.96,55.1) v2(101.96,54.34) v2(101.96,53.58) v2(102.4,21.06) v2(102.4,19.53) v2(102.4,18.01) v2(102.73,57.64) v2(102.73,56.37) v2(102.73,55.73) v2(102.73,55.1) v2(102.73,54.34) v2(102.73,53.58) v2(103.31,105.13) v2(103.74,66.47) v2(103.83,108.99) v2(103.83,12.66) v2(103.83,11.14) v2(103.83,9.61) v2(104.55,67.03) v2(105.33,21.06) v2(105.33,19.53) v2(105.78,12.66) v2(105.78,11.14) v2(107.17,87.5) v2(107.56,11.9) v2(107.56,10.38) v2(108.2,59.66) v2(108.72,21.06) v2(108.72,19.53) v2(108.84,59.66) v2(108.84,59.03) v2(110.25,21.06) v2(110.25,19.53) v2(110.25,18.01) v2(110.36,59.09) v2(110.36,58.46) v2(110.36,57.82) v2(110.36,57.19) v2(110.36,56.55) v2(110.36,55.92) v2(110.4,75.79) v2(110.69,89.26) v2(110.86,12.66) v2(110.86,11.14) v2(110.98,75.79) v2(111.16,108.98) v2(111.85,75.82) v2(111.77,21.26) v2(111.77,19.15) v2(111.81,11.9) v2(112.2,104.88) v2(112.9,13.04) v2(112.9,10.76) v2(114.62,20.52) v2(114.62,19.36) v2(114.6,11.14) v2(114.86,12.66) v2(116.65,105.82) v2(117.06,12.66) v2(117.59,107.48) v2(117.59,104.12) v2(117.95,92.21) v2(118.46,88.66) v2(118.58,14.02) v2(119.78,104.12) v2(119.85,88.65) v2(119.89,107.47) v2(120.3,20.3) v2(120.3,18.77) v2(120.64,11.9) v2(120.64,10.38) v2(120.72,105.82) v2(121.56,14.96) v2(122.09,20.55) v2(122.08,18.39) v2(122.53,11.9) v2(122.53,10.38) v2(122.5,6.86) v2(122.75,14.96) v2(123.18,107.49) v2(124.11,20.3) v2(124.11,18.52) v2(124.27,102.32) v2(124.3,9.63) v2(124.6,14.97) v2(125.07,11.9) v2(125.07,10.38) v2(126.1,9.65) v2(126.65,20.3) v2(126.65,18.77) v2(126.7,14.96) v2(126.81,104.62) v2(127.21,107.49) v2(127.17,11.8) v2(127.2,10) v2(127.31,102.32) v2(128,14.99) v2(128.44,20.3) v2(128.44,18.77) v2(128.47,11.9) v2(128.47,10.38) v2(128.59,54.75) v2(129.25,53.21) v2(129.52,56.16) v2(129.7,6.86) v2(130.03,53.84) v2(130.48,52.09) v2(130.98,20.3) v2(130.98,18.77) v2(131.01,11.9) v2(131.01,10.38) v2(131.25,14.96) v2(131.71,100.8) v2(131.96,107.49) v2(132.08,47.42) v2(132.44,9.71) v2(132.64,20.51) v2(132.65,18.39) v2(133,14.96) v2(133.35,48.75) v2(133.45,11.9) v2(133.45,10.38) v2(133.64,82) v2(133.68,47.04) v2(134.55,14.98) v2(134.58,83.7) v2(134.58,80.3) v2(134.66,9.78) v2(134.68,20.3) v2(134.68,18.77) v2(134.84,11.89) v2(134.93,48.48) v2(135.04,45.75) v2(135.7,104.5) v2(136.09,11.9) v2(136.09,10.38) v2(136.3,6.86) v2(136.42,47.13) v2(136.43,15.01) v2(136.55,71.97) v2(136.76,83.7) v2(136.76,80.3) v2(137.04,107.49) v2(137.22,20.3) v2(137.22,18.77) v2(137.7,82) v2(137.78,12.15) v2(137.78,10) v2(138.41,44.98) v2(138.87,45.41) v2(139.02,71.97) v2(139.05,11.9) v2(139.14,20.3) v2(141.92,71.97) v2(142.12,107.49) v2(142.52,49.22) v2(144.4,71.97) v2(144.84,44.22) v2(144.84,43.61) v2(145.55,102.3) v2(145.53,49.97) v2(145.86,104.5) v2(146.93,71.97) v2(147.2,107.49) v2(148.18,81.71) v2(148.56,82.17) v2(149.01,82.6) v2(149.03,49.35) v2(149.44,71.97) v2(149.66,15.65) v2(150.42,44.81) v2(150.42,44.18) v2(150.42,43.54) v2(150.59,17.31) v2(150.6,13.95) v2(152.28,107.49) v2(152.43,48.51) v2(152.47,46.74) v2(152.78,13.95) v2(152.9,17.3) v2(153.17,102.3) v2(153.72,15.65) v2(154.09,46.93) v2(154.09,44.37) v2(154.09,43.07) v2(155.93,79.3) v2(156.02,104.5) v2(156.05,47.62) v2(156.05,45.67) v2(156.52,79.31) v2(156.75,72.06) v2(157.36,107.49) v2(157.79,88.09) v2(158.07,47.62) v2(158.08,45.7) v2(158.08,43.72) v2(158.4,88.09) v2(158.99,88.09) v2(159.56,19.57) v2(159.68,47.54) v2(160.79,102.3) v2(160.8,6.6) v2(161.25,85.66) v2(161.7,11.55) v2(161.7,10.33) v2(161.83,85.65) v2(161.78,47.14) v2(162.28,19.69) v2(162.44,107.49) v2(162.6,6.6) v2(163.66,77.33) v2(163.61,54.44) v2(164.05,11.68) v2(164.07,9.73) v2(164.25,77.33) v2(164.48,19.63) v2(164.47,18.45) v2(166.16,11.6) v2(166.18,104.5) v2(166.2,9.75) v2(167.01,19.69) v2(166.99,18.52) v2(167.52,107.49) v2(168.19,10.89) v2(168.2,9.71) v2(168.41,102.3) v2(169.01,19.68) v2(169.01,17.86) v2(170.28,19.64) v2(170.28,18.45) v2(171.01,11.4) v2(171.01,10.21) v2(171.63,6.63) v2(172.51,60.18) v2(172.6,107.49) v2(172.82,19.67) v2(172.87,18.5) v2(173.42,6.62) v2(173.54,10.77) v2(173.62,9.6) v2(174.11,79.72) v2(174.67,79.94) v2(175.12,19.61) v2(175.13,17.8) v2(175.86,11.5) v2(175.84,10.26) v2(176.03,102.3) v2(176.34,104.5) v2(176.39,19.61) v2(176.39,18.4) v2(177.68,107.49) v2(178.2,6.63) v2(178.37,11.43) v2(178.35,10.23) v2(178.96,19.58) v2(178.97,18.41) v2(179.62,9.67) v2(179.93,40.91) v2(179.98,81.85) v2(180.54,40.91) v2(181.16,81.84) v2(181.14,78.61) v2(181.15,40.91) v2(181.18,11.45) v2(181.18,10.28) v2(181.47,19.61) v2(181.47,18.4) v2(181.8,6.63) v2(182.37,81.84) v2(182.67,105.85) v2(183.07,78.71) v2(183.17,11.38) v2(183.6,107.5) v2(183.61,104.15) v2(183.64,81.83) v2(184.85,81.83) v2(185.69,11.62) v2(185.79,104.15) v2(185.91,107.5) v2(186.01,81.83) v2(186.73,105.85) v2(187.51,11.95) v2(188.53,79.1) v2(189.12,88.1) v2(189.14,84.21) v2(189.14,14.3) v2(189.91,79.05) v2(190.26,55.22) v2(190.21,11.95) v2(190.92,75.44) v2(191.22,88.1) v2(191.36,20.93) v2(191.36,19.41) v2(191.44,59.83) v2(192.08,103.48) v2(192.38,66.83) v2(192.45,13.48) v2(192.45,11.95) v2(192.5,20.17) v2(192.72,62.31) v2(192.94,21.14) v2(192.95,19.2) v2(194.28,12.34) v2(195.22,108.99) v2(195.55,13.48) v2(195.55,11.95) v2(195.67,49.59) v2(195.83,20.94) v2(195.83,19.41) v2(197.42,13.26) v2(198.01,6.61) v2(199.12,11.66) v2(199.28,20.27) v2(199.28,19.05) v2(200.26,54.25) v2(200.26,53.66) v2(200.26,53.07) v2(200.28,52.48) v2(200.54,14.99) v2(201.91,14.42) v2(202.63,103.48) v2(203.11,108.99) v2(203.07,9.66) v2(203.78,14.91) v2(204,6.63) v2(204.09,13.06) v2(204.14,11.9) v2(204.14,10.38) v2(204.56,20.6) v2(204.55,19.18) v2(204.56,17.85) v2(205.14,20.59) v2(205.8,9.61) v2(205.95,20.62) v2(206.68,11.9) v2(206.68,10.38) v2(206.82,51.97) v2(206.82,51.37) v2(206.84,50.79) v2(206.94,108.03) v2(207.38,51.71) v2(207.38,51.12) v2(207.95,12.28) v2(207.95,10) v2(208.12,19.81) v2(208.12,18.64) v2(208.26,15.06) v2(208.26,14.45) v2(209.99,14.4) v2(209.99,13.21) v2(210,11.7) v2(210,10.38) v2(211.33,9.77) v2(212.2,14.96) v2(212.54,11.9) v2(212.54,10.38) v2(212.68,18.64) v2(213.98,6.62) v2(214.21,14.78) v2(214.2,12.96) v2(214.22,11.9) v2(214.22,10.38) v2(215.8,18.59) v2(216,9.63) v2(216.33,41.89) v2(216.42,14.2) v2(216.86,11.9) v2(216.86,10.38) v2(217.09,41.89) v2(217.87,49.94) v2(217.87,49.09) v2(217.85,41.89) v2(217.8,6.63) v2(218.1,15.06) v2(218.1,13.84) v2(218.1,12.63) v2(218.28,49.51) v2(218.7,49.94) v2(218.72,49.09) v2(219.15,92.75) v2(219.25,12.1) v2(219.25,10) v2(219.75,92.73) v2(219.87,13.08) v2(220.33,92.73) v2(220.52,11.9) v2(220.52,10.38) v2(220.91,92.75) v2(221.18,66.13) v2(221.5,92.75) v2(222.71,66.13) v2(223.45,108.05) v2(223.45,102.46) v2(224.85,98.93) v2(225.09,83.23) v2(225.09,81.71) v2(225.09,80.18) v2(225.28,33.11) v2(225.45,101.47) v2(225.6,104.03) v2(226.16,107.68) v2(226.62,83.23) v2(226.62,81.71) v2(226.62,80.18) v2(226.88,98.93) v2(227.01,34.22) v2(227.11,9.81) v2(227.33,109) v2(227.48,101.47) v2(228.17,105.85) v2(228.14,83.23) v2(228.14,81.71) v2(228.14,80.18) v2(229.11,107.55) v2(229.11,104.15) v2(230.99,101.47) v2(231.29,107.55) v2(231.29,104.15) v2(231.8,37.97) v2(232.23,105.85) v2(232.42,89.09) v2(232.71,108.99) v2(233.04,98.93) v2(233.55,103.5) v2(233.63,37.76) v2(233.83,101.47) v2(234.35,42.77) v2(234.3,40.6) v2(234.29,8.11) v2(234.91,43.12) v2(235.34,108.08) v2(235.34,101.88) v2(235.38,10.15) v2(235.42,6.01) v2(237.54,26.46) v2(237.94,40.15) v2(238.32,43.65) v2(238.27,10.15) v2(238.3,6.11) v2(239.26,45.35) v2(239.26,41.95) v2(239.34,8.15) v2(239.95,13.64) v2(241.44,45.35) v2(241.44,41.95) v2(241.73,58.78) v2(241.73,57.26) v2(241.87,5.61) v2(242.38,43.65) v2(246.31,90.27) v2(246.95,90.27) v2(246.95,5.61) v2(247.58,90.27) v2(247.63,30.05) v2(247.85,53.68) v2(248.22,90.27) v2(249.04,86.85) v2(249.64,86.84) v2(250.25,108.08) v2(250.26,101.88) v2(251.71,93.95) v2(252.03,5.61) v2(252.26,105.78) v2(252.26,103.75) v2(252.26,101.71) v2(252.26,99.68) v2(252.26,97.65) v2(252.84,108.99) v2(252.79,67.16) v2(252.79,65.76) v2(252.79,64.36) v2(253.54,19.37) v2(253.69,54) v2(253.83,95.49) v2(253.83,93.5) v2(254.16,104.32) v2(254.12,77.76) v2(254.19,67.16) v2(254.19,65.76) v2(254.19,64.36) v2(254.29,54) v2(254.42,101.71) v2(254.47,95.49) v2(254.52,2.67) v2(255.37,54.01) v2(255.61,86.81) v2(255.61,85.79) v2(255.61,84.77) v2(255.58,67.16) v2(255.58,65.76) v2(255.58,64.36) v2(256.58,101.71) v2(256.63,86.81) v2(256.63,85.79) v2(256.63,84.77) v2(256.59,77.78) v2(257.16,44.24) v2(257.16,42.46) v2(257.16,40.69) v2(257.19,0.51) v2(257.64,86.81) v2(257.64,85.79) v2(257.64,84.77) v2(258.42,94.12) v2(258.61,101.71) v2(258.94,44.24) v2(258.94,42.46) v2(258.94,40.69) v2(259.04,77.69) v2(259.46,94.12) v2(259.73,24.27) v2(259.85,77.7) v2(260.54,104.32) v2(260.64,101.71) v2(260.71,44.24) v2(260.71,42.46) v2(260.71,40.69) v2(261.4,103.68) v2(261.52,24.66) v2(262.27,0.51) v2(262.75,108.37) v2(263.22,11.77) v2(263.41,17.11) v2(264.04,17.74) v2(264.38,24.65) v2(264.68,18.38) v2(264.68,17.11) v2(264.96,11.85) v2(265.53,22.58) v2(265.77,26.81) v2(267.35,0.51) v2(267.96,22.44) v2(268.08,26.8) v2(269.03,23.46) v2(271.19,11.79) v2(271.45,12.36) v2(272.43,0.51) v2(273.28,29.47) v2(275.21,32.28) v2(275.36,30.72) v2(275.79,65.53) v2(275.8,62.53) v2(275.97,33.27) v2(276.55,69.01) v2(277.51,0.51) v2(279.87,40.56) v2(280.87,65.53) v2(280.88,62.53) v2(281.23,41.8) v2(281.67,49.65) v2(281.65,41.38) v2(282.13,38.04) v2(282.61,51.35) v2(282.61,47.95) v2(282.59,0.51) v2(283.23,36.14) v2(283.45,32.18) v2(283.45,30.91) v2(283.45,29.64) v2(284.57,73.27) v2(284.72,32.18) v2(284.72,30.91) v2(284.72,29.64) v2(284.79,51.35) v2(284.79,47.95) v2(285.07,92.04) v2(285.43,73.81) v2(285.73,49.65) v2(285.99,32.18) v2(285.99,30.91) v2(285.99,29.64) v2(287,41.47) v2(287.67,0.51) v2(287.93,87.93) v2(288.02,42.46) v2(288.02,41.47) v2(288.08,35.23) v2(288.33,93.64) v2(289.27,90.65) v2(289.37,32.32) v2(290.21,92.35) v2(290.21,88.95) v2(290.74,62.12) v2(290.75,50.14) v2(290.84,85.22) v2(291.98,63.93) v2(292,44.51) v2(292.08,4.9) v2(292.39,92.35) v2(292.39,88.95) v2(292.75,0.51) v2(292.92,45.83) v2(293.07,43.36) v2(293.33,90.65) v2(293.91,93.66) v2(294.07,47.79) v2(294.16,85.19) v2(294.13,4.93) v2(294.59,63.47) v2(294.69,44.59) v2(294.93,78.92) v2(294.93,70.21) v2(295.04,88.85) v2(295.76,91.41) v2(297.67,11.15) v2(297.83,93.62) v2(297.83,0.51) v2(297.95,4.49) v2(298,44.59) v2(298.09,88.85) v2(298.24,86.82) v2(298.61,12.85) v2(298.61,9.45) v2(298.8,91.41) v2(298.82,69.6) v2(299.1,79.5) v2(300.5,4.94) v2(300.73,90.31) v2(300.73,87.77) v2(300.73,84.28) v2(300.7,81.55) v2(300.79,12.85) v2(300.79,9.45) v2(301.14,69.57) v2(301.15,66.57) v2(301.15,63.47) v2(301.13,48.84) v2(301.73,11.15) v2(302.7,93.5) v2(302.7,79.63) v2(302.75,0.62) v2(302.91,88.92) v2(302.91,84.23) v2(302.91,45.92) v2(302.91,15.75) v2(302.88,10.71) v2(302.91,5.59) v2(304.26,41.24) v2(304.26,36.16) v2(304.26,31.08) v2(304.26,26) v2(304.26,20.92) v3(48.02,14.11) v3(48.02,13.47) v3(48.02,12.84) v3(48.02,12.2) v3(48.65,14.11) v3(48.65,13.47) v3(48.65,12.84) v3(48.65,12.2) v3(49.29,14.11) v3(49.29,13.47) v3(49.29,12.84) v3(49.29,12.2) v3(49.92,14.11) v3(49.92,13.47) v3(49.92,12.84) v3(49.92,12.2) v3(61.3,19.52) v3(61.3,18.83) v3(61.94,20.22) v3(61.94,19.51) v3(61.94,18.81) v3(61.94,18.17) v3(62.58,20.87) v3(62.58,20.22) v3(62.58,19.51) v3(62.58,18.81) v3(62.58,18.17) v3(63.15,20.52) v3(63.14,19.86) v3(63.13,19.15) v3(63.36,90.72) v3(63.36,90.08) v3(63.45,94.72) v3(64.03,90.72) v3(64.03,90.08) v3(64.69,90.72) v3(64.69,90.08) v3(71.6,67.56) v3(71.6,66.93) v3(72.24,67.56) v3(72.24,66.93) v3(72.24,66.29) v3(72.9,80.52) v3(73.53,80.52) v3(74.1,80.12) v3(74.65,74.04) v3(74.72,80.34) v3(74.75,79.67) v3(74.74,79.03) v3(75.42,74.79) v3(75.41,74.04) v3(76.31,75.58) v3(76.31,74.82) v3(76.31,74.05) v3(76.35,73.29) v3(76.35,72.53) v3(76.36,71.78) v3(77.04,75.58) v3(77.04,74.82) v3(77.04,74.05) v3(77.04,73.29) v3(77.04,72.53) v3(77.04,71.77) v3(88.47,61.65) v3(89.1,61.65) v3(90.18,61.65) v3(90.82,61.65) v3(101.14,49.13) v3(101.15,48.49) v3(101.79,52.93) v3(101.79,52.3) v3(101.79,49) v3(102.42,52.93) v3(102.42,52.3) v3(102.42,49) v3(116.94,66.29) v3(116.94,65.66) v3(116.94,62.93) v3(116.94,62.29) v3(118.13,59.82) v3(118.13,59.18) v3(118.21,68.97) v3(118.21,68.34) v3(119.1,66.29) v3(119.1,65.66) v3(119.1,62.93) v3(119.1,62.29) v3(119.73,66.29) v3(119.73,65.66) v3(119.73,62.93) v3(119.73,62.29) v3(120.46,59.82) v3(120.46,59.18) v3(120.5,68.95) v3(120.5,68.31) v3(121.13,68.95) v3(121.13,68.31) v3(121.09,59.82) v3(121.09,59.18) v3(121.89,66.29) v3(121.89,65.66) v3(121.89,62.93) v3(121.89,62.29) v3(122.53,66.29) v3(122.53,65.66) v3(122.53,62.93) v3(122.53,62.29) v3(200.26,61.77) v3(200.28,60.19) v3(200.28,59.56) v3(200.9,61.77) v3(200.91,60.19) v3(200.91,59.56) v3(201.53,61.52) v3(201.53,60.84) v3(201.55,60.19) v3(201.55,59.56) v3(202.18,60.19) v3(202.18,59.56) v3(211.01,53.38) v3(211.01,52.74) v3(211.44,48.18) v3(212.07,48.18) v3(212.07,47.54) v3(212.71,48.18) v3(212.71,47.54) v3(216.88,55.28) v3(216.88,54.65) v3(216.88,54.01) v3(217.51,55.28) v3(217.51,54.65) v3(217.51,54.01) v3(218.15,55.28) v3(218.15,54.65) v3(218.15,54.01) v3(218.78,55.28) v3(218.78,54.65) v3(218.78,54.01) v3(219.42,55.92) v3(219.42,55.28) v3(219.42,54.65) v3(219.42,54.01) v3(220.05,55.92) v3(220.05,55.28) v3(220.05,54.65) v3(220.05,54.01) v3(220.69,55.92) v3(220.69,55.28) v3(220.69,54.65) v3(220.69,54.01) v3(223.5,48.31) v3(223.5,47.67) v3(224.14,48.31) v3(224.14,47.67) v3(224.77,48.31) v3(224.77,47.67) v4(45.06,14.13) v4(51.55,15.65) v4(62.2,88.91) v4(67.61,107.81) v4(93.44,20.36) v4(93.75,94.72) v4(98.84,107.04) v4(100.75,106.62) v4(102.8,51.35) v4(106.39,67.63) v4(109.75,103.05) v4(109.98,102.76) v4(117.28,68.87) v4(131.72,103.34) v4(134.54,99.95) v4(139.57,103.2) v4(161.74,99.63) v4(164.88,106.13) v4(173.59,99.86) v4(189.11,101.87) v4(194.04,103.57) v4(198.87,54.32) v4(228.53,97.15) v4(229.17,80.73) v4(258.11,85.33) v4(275.89,64.01) v4(280.2,63.98) v4(281.91,65.48) v4(289.81,66.45) v4(292.68,85.08) v4(298.92,85.19) v4(299.77,45.59)
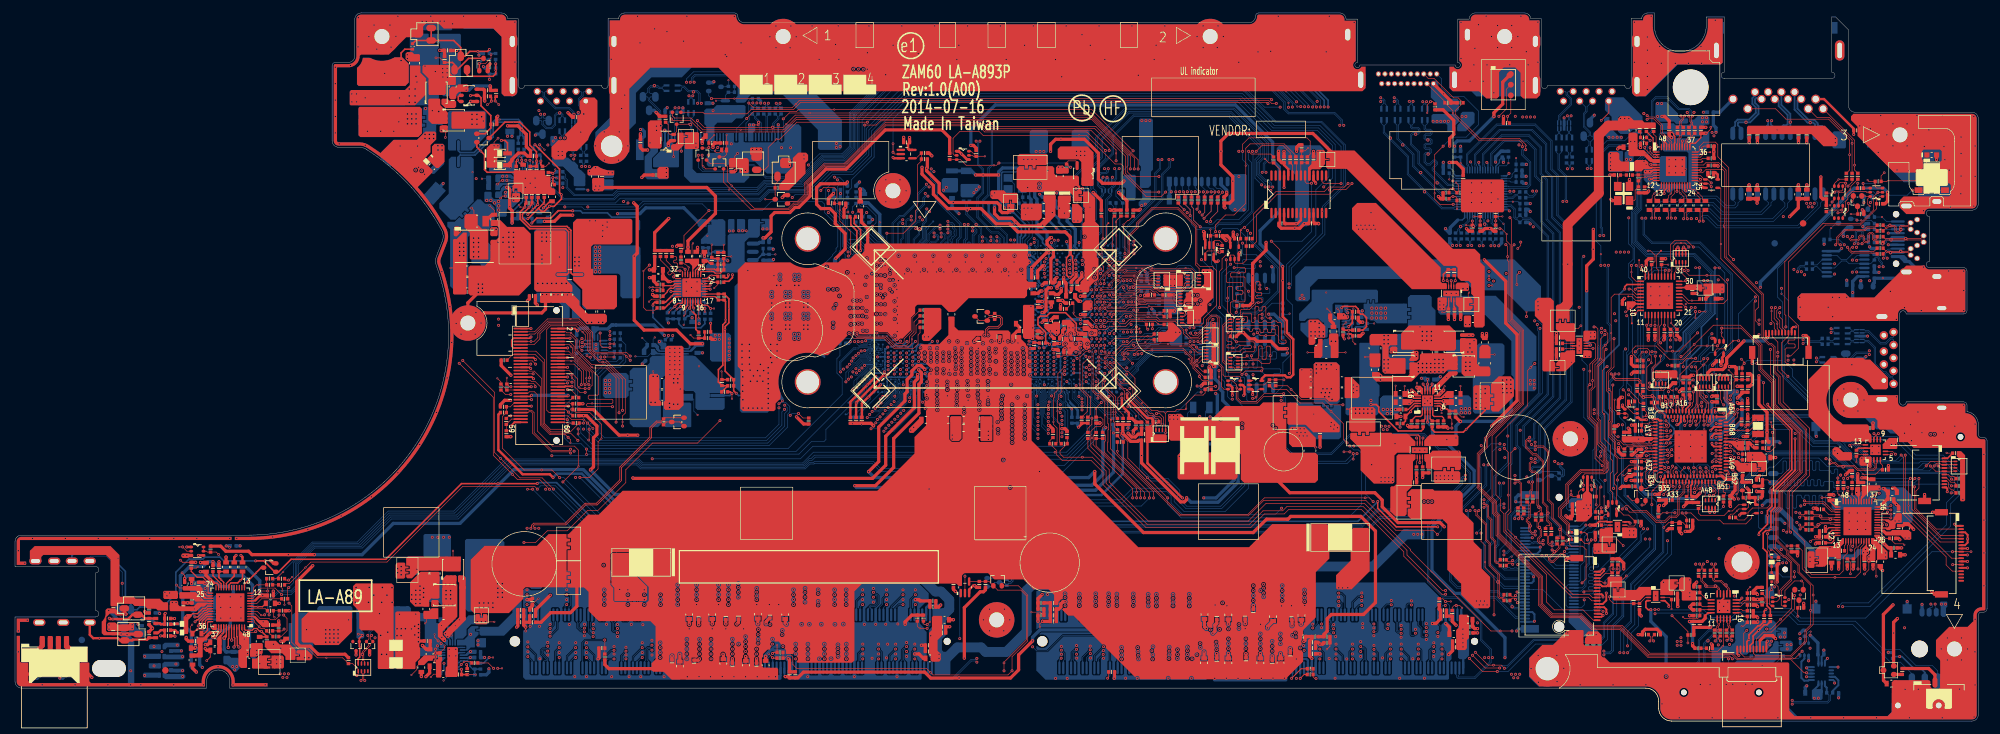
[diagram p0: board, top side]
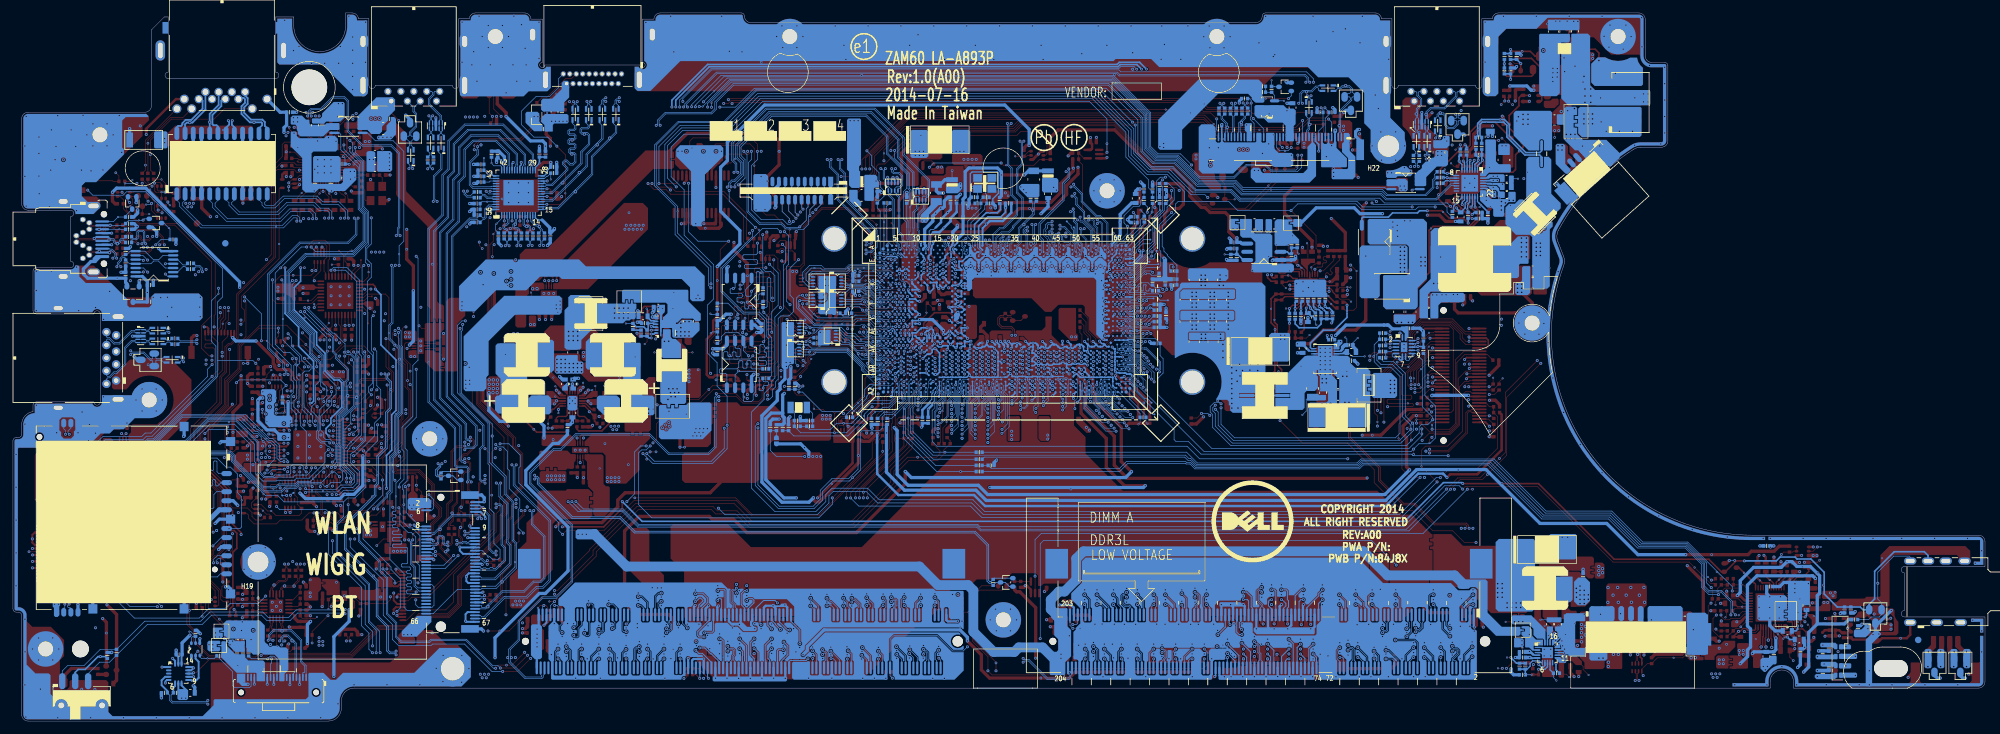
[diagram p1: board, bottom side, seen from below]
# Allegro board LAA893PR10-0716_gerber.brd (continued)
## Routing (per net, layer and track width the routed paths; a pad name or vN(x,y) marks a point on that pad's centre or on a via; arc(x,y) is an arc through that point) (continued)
GNDA: length 29.8
  TOP w0.102: v2(32.64,27.09) 32.94,27.09 v4(33.16,26.87)
  TOP w0.127: v4(29.63,9.35) 30.17,9.89 CA16.2 ; v4(25.55,24.88) 25.87,24.56 CA35.1
  TOP w0.203: UA1.26 29.67,19.37 29.38,19.66 v2(29.38,19.86)
  TOP w0.381: QA2.4 v2(28.33,25.62) ; v2(26.53,26.92) QA2.1
  TOP w0.508: CA51.2 32.61,25.35 v2(32.61,25.35) ; v2(29.4,11.2) 29.66,10.93 30.16,10.93 CA16.2 ; v2(26.45,12.94) 26.45,12.7 26.79,12.36 CA17.2 ; CA26.2 28.7,24.49 v2(28.66,24.54) ; RA44.2 v2(31.52,24.64) ; CA3.2 20.71,13.82 v2(21.24,14.35) 20.72,14.87 CA2.2 ; v2(29.36,21.25) 29.15,21.46 CA8.2 ; CA35.1 v2(27.91,24.56) ; CA1.2 20.27,16.73 v2(20.06,16.93) ; v2(27.29,21.25) CA9.2 ; CA18.2 27.75,11.28 v2(27.87,11.4)
  GND w0.203: 6.32,15.25 JHP1.7 ; JHP1.7 8.58,15.25 ; JHP1.7 8.58,14.53 ; JHP1.7 6.32,14.53 ; JHP1.7 7.45,14.53
  BOTTOM w0.508: RA36.1 28.12,11.16 v2(27.87,11.4) 27.87,11.95 28,12.08 CA52.2 ; v2(19.01,14.97) 19.24,14.74 CA4.2 ; v2(32.64,27.09) RA37.1 ; CA1.2 20.27,16.73 v2(20.06,16.93) ; 30.03,21.44 31.09,21.44 31.72,20.8 RA35.1
  vias: v2(0.52,26.34) v2(0.52,13.94) v2(1.51,24.41) v2(1.89,15.6) v2(2.7,28.24) v2(7.78,28.24) v2(12.86,28.24) v2(17.31,28.24) v2(20.83,28.24) v2(24.55,28.24) v2(28.1,28.24) v2(29.38,20.49) v2(30.54,14.52) v2(33.18,28.24)
GNDA_CHG: length 9.8
  TOP w0.254: PQ711.3 71.37,88.74 v4(71.99,88.13) 72.55,87.57 72.55,85.27 72.96,84.86 77.45,84.86 PC703.2
  vias: v2(78.86,83.92) v2(78.86,82.52) v2(79.61,83.17) v2(80.37,83.95) v2(80.39,82.52)
VCCSENSE: length 35.3
  TOP w0.254: PR531.1 109.74,68.54 110.06,68.54 110.23,68.72 v2(110.23,69.01) ; RC209.2 129.68,77.74 129.68,76.94 130.67,75.95 v2(130.67,72.74)
  IN1 w0.254: v2(130.67,72.74) 130.67,72.87 129.87,73.66 126.04,73.66 123.8,71.43 121.19,71.43 118.67,73.95 113.99,73.95 110.28,70.24 110.28,69.06 v2(110.23,69.01)
  BOTTOM w0.203: v2(130.67,72.74) 130.55,72.63 130.55,72.02 131.71,70.86 UC1.E63
VDD_1.35V: length 1.4
  TOP w0.102: v1(64.25,6.81) 64.69,7.25 PC211.1
  vias: v2(64.96,9.28)
VSSSENSE: length 35.8
  TOP w0.254: RC218.1 129.17,77.82 129.17,76.72 130.1,75.79 v2(130.1,72.74) ; PR532.1 109.68,68.01 110.31,68.01 110.87,68.57 v2(110.87,69.01)
  IN1 w0.254: v2(110.87,69.01) 110.8,69.08 110.8,70.04 114.2,73.44 118.46,73.44 120.98,70.92 124.01,70.92 126.25,73.15 129.68,73.15 v2(130.1,72.74)
  BOTTOM w0.203: UC1.E62 132.44,70.46 131.68,70.46 130.23,71.91 130.23,72.6 v2(130.1,72.74)
+AUX_LDO: length 5.3
  TOP w0.102: v4(277.47,27.77) 277.72,28.03 279.3,28.03 CR17.2
  TOP w0.203: CR17.2 280.73,27.55 281.06,27.88 281.06,28.46 281.31,28.71 UR1.12
+BL_PWR_SRC:
  vias: v2(107.87,94.39)
+COINCELL: length 6.7
  TOP w0.508: PR1.1 295.72,8.13 296.7,7.14 JRTC1.1
+DC_IN: length 26
  TOP w0.508: PD705.2 76.77,86.62 76.77,86.82 77.78,87.83 78.72,87.83 79.2,87.36 PR710.2 79.66,88.18 79.02,88.82 79.02,90.73 v4(78.32,91.43) 77.71,92.04 v2(76.11,92.04)
  IN1 w0.508: v2(66.82,99.55) 70.23,99.55 71.19,98.59 71.19,95.39 74.55,92.04 v2(76.11,92.04)
  vias: v2(66.09,100.89) v2(66.09,100.27) v2(66.11,99.59) v2(66.77,100.93) v2(66.77,100.25) v2(66.79,98.89) v4(63.36,101.27) v4(64.96,100.43)
+DC_IN_SS: length 10.7
  TOP w0.508: v2(72.59,95.88) 72.55,95.92 PR730.1 PC730.1 72.38,97.71 PQ708.4
  IN2 w0.508: v3(65.48,94.26) 68.03,94.26 68.68,94.91 71.61,94.91 v2(72.59,95.88)
  vias: v4(64.49,94.39)
+DCIN:
  vias: v1(76.57,85.61)
+DCIN_JACK:
  vias: v2(52.04,96.98) v2(52.05,95.74) v2(52.77,96.98) v2(52.78,95.74) v3(60.92,97.74) v3(60.92,96.66) v3(60.92,95.67) v3(61.82,97.74) v3(61.82,96.66) v3(61.82,95.67) v3(61.96,99.69) v4(54.11,96.38) v4(59.41,96.35) v4(62.12,98.81)
+DCPRRTC: length 1.6
  TOP w0.076: CC52.1 164.67,60.83 v1(164.4,60.57)
  BOTTOM w0.229: UC1.AE7 166.85,59.95 v2(166.92,60.03)
+DIMM1_VREF_DQ: length 7.2
  TOP w0.127: v2(78.91,14.52) v4(78.91,13.92)
  TOP w0.508: CD1.1 78.61,14.83 v2(78.91,14.52) ; CD1.1 RD4.2 RD5.1 ; CD1.1 CD5.1 RD6.1
  BOTTOM w0.356: v2(78.91,14.52) 79,14.61 JDIMM1.1
+DIMM2_VREF_DQ: length 8.8
  TOP w0.102: v1(158.37,14.54) 158.37,15.04 v2(158.77,15.44)
  TOP w0.508: v2(158.77,15.44) 158.8,15.41 CD33.1 CD34.1 RD24.1 RD22.2 RD23.1
  BOTTOM w0.356: v2(158.77,15.44) 158.8,15.42 160.3,15.42 160.5,15.62 JDIMM2.1
+EDP_VDD: length 1.1
  TOP w0.102: 101.78,88.33 v4(101.78,87.27)
+LCDVDD: length 0.7
  TOP w0.127: v2(114.11,92.18) v4(114.86,92.18)
  vias: v2(105.23,89.34) v2(105.23,88.73) v2(113.5,92.18)
+MIC1_VREF_OUT: length 3.9
  TOP w0.203: 27.01,16.18 27.43,16.6 28.18,16.6 29,17.42 29.42,17.42 29.77,17.77 UA1.30
  vias: v1(26.46,16.23)
+PBATT: length 68.8
  TOP w0.254: PD704.2 76.1,89.39 75.71,89.79 v2(75.16,89.79)
  TOP w0.508: v2(81.82,77.27) 83.35,77.27 84.31,78.23 v2(86.18,78.23)
  IN1 w7.62: 53.81,25.17 53.81,25.29 61.54,33.02 61.77,33.02 72.2,43.45 72.2,47.52
  IN2 w0.254: v3(89.71,73.28) 89.71,73.89 92.2,76.38 92.2,77.25 91.22,78.23 v2(86.18,78.23) 85.53,78.88 85.53,84.25 81.42,88.37 80.32,88.37 78.9,89.79 v2(75.16,89.79)
  BOTTOM w0.508: PR723.2 v2(81.82,77.27)
  vias: v3(52.6,18.36) v3(52.7,20.66) v3(53.41,19.47) v3(54.63,18.36) v3(54.73,20.66) v3(55.45,19.47) v3(56.5,13.25) v3(56.66,18.36) v3(56.66,10.32) v3(56.77,20.66) v3(57.42,10.32) v3(57.48,19.47) v3(57.6,13.74) v3(58.25,20.64) v3(58.2,9.1) v3(58.22,8.44) v3(58.28,18.35) v3(89.71,72.64) v3(89.71,72.01) v3(89.71,71.37) v3(89.71,70.74) v3(89.71,70.1) v3(89.71,69.47) v3(90.35,73.28) v3(90.35,72.64) v3(90.35,72.01) v3(90.35,71.37) v3(90.35,70.74) v3(90.35,70.1) v3(90.35,69.47) v4(56.32,16.61)
+PCH_ASATA3PLL: length 10.4
  BOTTOM w0.381: 163.85,74.07 163.85,73.69 UC1.A12 163.67,73.44 164.09,73.02 UC1.B11
  BOTTOM w0.508: RC17.2 160.22,81.02 160.82,80.42 160.82,79.56 161.07,79.31 v2(161.39,79.31) v4(162.16,78.54) 162.6,78.1 162.6,77.29 163.85,76.03 163.85,74.07
+PCH_AUSB3PLL: length 23.1
  TOP w0.508: v2(151.37,79.36) 151.37,78.46 152.08,77.75 154.09,77.75 v4(154.68,77.16) 155.28,76.56 158.19,76.56
  BOTTOM w0.254: UC1.B18 159.91,73.23 159.64,73.5 159.64,73.66 159.5,73.81 159.5,74.37 ; v2(151.37,79.36) 151.37,78.68 152.09,77.96 154.08,77.96 155.52,76.52 155.52,75.06 155.34,74.89 155.34,73.26 UC1.B27
  BOTTOM w0.508: v2(158.81,76.67) 158.81,76.33 159.5,75.64 159.5,74.37 ; v2(151.37,79.36) 151.37,80.04 RC149.1
+PCH_RTC_VCCSUS3_3: length 14
  TOP w0.076: v1(173.25,47.19) 173.21,47.15 173.21,46.24
  TOP w0.381: RC212.2 172.12,47.68 171.05,48.75 v2(171.05,49.95)
  TOP w0.508: RC212.2 172.63,46.79 173.2,46.21 CC73.1 ; CC73.1 173.21,46.24 ; CC73.1 RC213.2
  IN1 w0.508: 166.15,52.93 166.15,51.99 166.96,51.18 168.85,51.18 170.09,49.95 v2(171.05,49.95)
  BOTTOM w0.254: v2(164.68,57.7) 164.65,57.7 UC1.AH11
+PCH_VCC1P05: length 25
  TOP w0.508: v2(161.02,68.61) 160.72,68.31 160.72,67.92 160.59,67.79 CC78.1 160.08,68 160.08,71.45 160.46,71.83 160.46,72.77 159.48,73.75 159.48,74.23 160,74.75 v2(160.17,74.75)
  IN1 w0.508: v2(160.17,74.75) 160.17,77.32 159.78,77.71 159.78,81.22 160.22,81.66 v2(160.94,81.66)
  BOTTOM w0.102: v4(159.61,85.11) 159.62,85.1 LC4.2
  BOTTOM w0.229: v2(161.02,68.61) 160.78,68.61 160.56,68.39 UC1.J18 160.56,68.17 160.2,67.81 UC1.K19
  BOTTOM w0.508: LC4.2 160.71,83.71 161.44,82.98 CC77.1 162.04,81.95 161.74,81.66 v2(160.94,81.66)
+PCH_VCCACLKPLL: length 29.8
  TOP w0.508: v2(152,84.44) v4(149.62,84.44) v2(148.45,84.44)
  BOTTOM w0.254: 158.79,74.54 158.79,73.98 UC1.A20
  BOTTOM w0.508: v2(148.45,84.44) 147.81,85.08 CC81.1 LC5.2 ; 158.79,74.54 157.92,75.4 157.92,78.07 157.92,78.07 157.92,80.06 CC82.1 157.92,80.71 157.59,81.04 157.59,84.96 157.03,85.52 152.6,85.52 152,84.92 v2(152,84.44) 152,81.21 RC69.2
+PCH_VCCDSW: length 15
  TOP w0.254: v2(164.34,59.83) 164.34,60.02 164.01,60.35 164.01,61.48 162.34,63.14 159.94,63.14 159.42,62.62 158.44,62.62 v1(158.09,62.27) 158.09,61.28 159.27,60.1 RC211.2 159.65,58.46 v2(159.85,58.25)
  BOTTOM w0.254: UC1.AG19 160.25,58.66 v2(159.85,58.25) 159.44,58.66 UC1.AG20
+PCH_VCCDSW3_3: length 178.3
  TOP w0.305: JAPS1.3 301.35,29.19 301.75,28.79 v2(301.75,28.17) 301.75,27.6 301.34,27.19 JAPS1.7
  TOP w0.381: v2(180.42,34.51) 180.37,34.51 v1(178.19,36.69) 175,39.88 RC216.2 ; v2(175.69,45.59) 175.85,45.76 RC92.1 175.85,46.61 175.61,46.85 174.99,46.85 171.85,49.99 v2(171.85,50.6)
  IN2 w0.076: 168.83,55.63 168.83,55.1 ; 169.45,57.14 169.45,56.59
  IN2 w0.381: 169.2,54.71 169.65,54.26 169.65,52.08 170.6,51.13 171.32,51.13 v2(171.85,50.6) ; v2(180.42,34.51) 180.42,34.12 191.03,23.51 192.24,23.51 193.97,21.78 216.37,21.78 221.17,16.98 227,16.98 228.89,15.09 233.55,15.09 234.79,16.33 239.34,16.33 242.91,12.75 248.95,12.75 249.84,11.85 249.84,10.13 251.2,8.78 262.51,8.78 264.44,10.71 267.12,10.71 269.94,13.52 270.75,13.52 272.84,15.62 289.02,15.62 289.8,16.4 291.89,16.4 292.99,15.3 299.06,15.3 300.54,16.79 300.54,26.96 v2(301.75,28.17)
  BOTTOM w0.254: v2(165.61,57.67) 165.49,57.67 UC1.AH10
+PCH_VCCDSW_R: length 2
  TOP w0.076: v1(156.55,58.24) 157.19,58.24 CC65.1
  TOP w0.254: RC211.1 157.99,58.46 157.91,58.53 CC65.1
+PWR_SRC: length 1.5
  TOP w0.508: CC95.1 80.41,64.64 v2(80.71,64.35)
  vias: v2(126.92,89.32) v2(126.92,88.7) v2(127.51,88.85) v3(59.1,23.57) v3(59.1,22.94) v3(59.67,23.89) v3(59.67,23.25) v3(59.67,22.62) v3(80.78,67.67) v3(81.43,75.47) v3(81.43,74.84) v3(81.43,74.2) v3(81.43,72.07) v3(81.43,71.43) v3(81.43,70.8) v3(81.54,67.67) v3(82.13,75.47) v3(82.13,74.84) v3(82.13,74.2) v3(82.24,67.67) v3(82.76,75.47) v3(82.76,74.84) v3(82.76,74.2) v3(82.94,67.67) v3(83.64,67.67) v3(84.49,67.67) v3(85.19,67.67) v3(91.25,52.68) v3(91.25,52.04) v3(91.25,51.41) v3(91.25,50.77) v3(91.88,52.68) v3(91.88,52.04) v3(91.88,51.41) v3(91.88,50.77) v3(209.69,63.85) v3(209.69,63.09) v3(209.69,62.33) v3(210.38,63.85) v3(210.38,63.09) v3(210.38,62.33) v3(211.08,63.85) v3(211.08,63.09) v3(211.08,62.33) v3(211.78,63.85) v3(211.78,63.09) v3(211.78,62.33) v4(84.12,71.75)
+PWR_SRC_AC:
  vias: v1(70.7,84.87)
+RSVD_VCC3P3_1: length 4
  TOP w0.203: UL1.1 253.35,87.99 253.15,88.19 v1(253.15,90.13) RL6.2
+RTC_CELL: length 414.1
  TOP w0.076: 162.2,57.99 162.56,57.99 162.57,57.97
  TOP w0.254: v2(264.52,53.51) 264.49,53.54 264.14,53.54 263.77,53.16 RPE5.7 ; v2(264.52,53.51) 264.77,53.27 RPE5.5 ; v2(264.52,53.51) 264.27,53.25 RPE5.6
  TOP w0.508: RE31.1 268.11,53.7 268.5,53.32 v2(268.5,52.2) 268.07,51.76 RE32.1 ; v2(46.25,25.73) v4(42.24,25.73) 36.62,25.73 36.09,26.26 32.57,26.26 31.79,27.05 RA21.1 ; PC1.1 288.74,6.29 PD3.1 288.73,7.87 288.73,16.48 v2(290.22,17.97)
  IN1 w0.508: v2(185.56,50.67) 184.95,50.06 181.16,50.06 179.8,48.7 174.72,48.7 173.53,49.9 172.12,49.9 171.46,49.24 169.2,49.24 167.94,50.5 166.61,50.5 165,52.11 165,52.29 164.02,53.28 163.36,53.28 162.98,53.66 162.98,57.65 v2(163.03,57.71) ; v2(171.98,45.3) 170.5,45.3 v2(169.76,44.55) ; v2(268.5,52.2) 269.39,52.2 275.7,45.88 275.7,41.66 271.99,37.95 271.99,29.16 272.32,28.83 272.32,23.06 v2(275.88,19.51)
  IN2 w0.508: v2(290.22,17.97) 288.68,19.51 v2(275.88,19.51) 275.88,18.77 275,17.89 270.34,17.89 269.54,17.09 268.48,17.09 267.56,16.18 260.59,16.18 259.76,17 258.54,17 257.15,18.4 254.86,18.4 254.51,18.76 251.48,18.76 251.27,18.55 244.71,18.55 243.9,19.35 242.19,19.35 240.45,21.09 234.17,21.09 232.95,22.32 195.21,22.32 183.69,33.84 v2(183.69,34.51) 183.69,34.63 182.19,36.13 179.64,36.13 172.95,42.82 171.71,42.82 169.99,44.55 v2(169.76,44.55) ; v2(264.52,53.51) 267.18,53.51 v2(268.5,52.2)
  BOTTOM w0.254: v2(164.71,58.37) 164.79,58.37 UC1.AG10
  BOTTOM w0.508: RC1.1 169.76,45.78 v2(169.76,44.55) 169.76,38.48 166.98,35.7 155.93,35.7 154.34,34.11 92.61,34.11 87.83,38.89 77.09,38.89 68.77,30.56 58.46,30.56 53.63,25.73 v2(46.25,25.73) ; 185.8,47.62 185.8,50.43 v2(185.56,50.67) ; 185.8,47.62 185.8,47.17 185.57,46.94 185.57,46.07 RC10.1 RC8.1 ; 185.8,47.62 187.58,47.62 188.4,46.8 188.4,37.31 185.6,34.51 v2(183.69,34.51) ; v2(171.98,45.3) 172.07,45.38 RC9.1 RC78.2
+RTC_CELL_VBAT: length 12.1
  TOP w0.305: UE2.B64 262.63,44.46 262.19,44.02 v2(262.19,43.83)
  TOP w0.508: RE32.2 CE11.1 266.9,50.7 v2(266.16,49.96)
  BOTTOM w0.508: 263.59,44.26 264.35,45.02 265.49,45.02 266.89,46.42 v4(266.89,49.54) 266.89,49.64 266.57,49.96 v2(266.16,49.96)
+SD_IO_LDO: length 3.4
  TOP w0.508: CR14.2 CR15.2 289.49,26.78 v1(288.92,27.35) 288.16,28.1
+SDC_IN:
  vias: v3(70.62,93.81) v3(70.62,93.05) v3(70.62,92.29) v3(71.38,93.81) v3(71.38,93.05) v3(71.38,92.29) v3(72.11,93.45) v4(72.36,92.79)
+SM_VREF_CA: length 131.1
  TOP w0.508: v2(166.86,38.59) 166.86,36.68 174.39,29.15 191.34,29.15 193.41,31.22 196.71,31.22 197.14,31.65 207.98,31.65 210.23,29.39 210.23,18.33 208.39,16.48 203.43,16.48 202.78,15.84 202.78,13.91 202.28,13.41 CD36.1 RD19.2 ; v2(140.58,54.35) 140.58,54.4 140.01,54.97 139.43,54.97 138.59,54.13 138.59,53.53 137.86,52.79 137.86,50.9 137.53,50.57 137.53,49.5 133.47,45.45 133.47,40.13 v2(131.9,38.56)
  BOTTOM w0.279: UC1.AP49 140.88,54.64 v2(140.58,54.35)
  BOTTOM w0.508: v2(131.9,38.56) 132.81,37.65 165.91,37.65 v2(166.86,38.59)
+SM_VREF_CA_DIMM: length 101
  TOP w0.508: v2(157.25,12.39) 155.09,10.24 155.09,7.91 153.83,6.65 v4(145.9,6.65) 141.5,6.65 140.59,7.57 121.85,7.57 120.99,6.7 CD22.1 CD23.1 119.5,6.88 119.03,6.88 v2(119.03,6.88) ; v2(199.17,12.29) 199.34,12.46 199.34,12.94 199.46,13.06 RD18.2 RD19.1 200.44,12.77 200.06,12.39 RD20.1 CD55.1 CD56.1 200.06,10.04 v2(200.4,9.7)
  IN2 w0.508: v2(199.17,12.29) 196.86,12.29 196.61,12.55 196.61,13.77 196.07,14.3 195.23,14.3 194.47,13.54 193.38,13.54 192.75,14.17 191.02,14.17 190.31,13.46 187.08,13.46 186.57,12.95 185.38,12.95 184.52,12.09 184.52,10.39 184.21,10.08 182.83,10.08 v2(182.65,10.26)
  BOTTOM w0.254: JDIMM1.126 118.9,7.01 v2(119.03,6.88)
  BOTTOM w0.356: JDIMM2.126 200.4,9.7 v2(200.4,9.7)
  BOTTOM w0.508: v2(182.65,10.26) 181.99,10.92 181.99,11.52 179.41,14.1 158.39,14.1 157.25,12.95 v2(157.25,12.39)
+SM_VREF_DQ0: length 84.3
  TOP w0.508: v2(139.47,53.58) 139.47,52.91 138.97,52.41 138.97,48.46 134.55,44.04 134.55,39.57 132.51,37.53 95.55,37.53 v2(95.49,37.59) ; v2(82.71,19.45) CD21.1 RD5.2
  IN1 w0.508: v2(82.71,19.45) 95.49,32.23 v2(95.49,37.59)
  BOTTOM w0.254: UC1.AR51 139.7,53.66 139.55,53.66 v2(139.47,53.58)
+SM_VREF_DQ1: length 70
  TOP w0.508: CD54.1 RD23.2 158.09,18.93 v2(158.72,19.57) ; v2(129.78,36.4) 132.95,36.4 135.79,39.23 135.79,43.7 139.68,47.6 139.68,52.07 140.07,52.45 140.07,53.88 v2(139.63,54.31)
  IN2 w0.508: v2(158.72,19.57) 153.78,24.51 v2(153.78,36.12)
  BOTTOM w0.254: UC1.AP51 139.96,54.64 v2(139.63,54.31)
  BOTTOM w0.508: v2(153.78,36.12) 130.06,36.12 v2(129.78,36.4)
+USB_LEFT_PWR:
  vias: v2(83.94,88.06) v2(83.96,87.47) v2(84.55,88.06) v2(84.57,87.47) v4(87.42,91.07)
+USB_RIGHT_PWR: length 3.5
  TOP w0.127: v4(245.13,92.89) 246.3,94.05 JUSB2.1
+V_DDR_REF:
  vias: v2(70.39,10.76)
+VCHGR:
  vias: v2(88.83,77.36) v2(89.68,77.36) v2(90.83,76.66) v2(90.83,75.82) v2(91.51,77.16) v2(91.5,76.38) v3(86.52,71.72) v3(86.52,71.03) v3(86.52,70.4) v3(87.16,71.03) v3(87.16,70.4) v3(87.17,71.73) v4(90.78,74.95)
+VDISPLAY_VCC: length 11.2
  BOTTOM w0.508: 292.03,71.07 292.69,71.07 293.86,69.9 293.86,69.14 293.2,68.48 v1(288.64,68.48) CV509.1 287.33,67.82 287.14,67.62 UV501.3
+VHDMI_VCC: length 5.1
  TOP w0.508: JHDMI1.18 v1(220.77,97) 221.88,95.89 RV9.2 RV7.2
+VLDOIN_1.35V: length 1.4
  TOP w0.102: v3(72.7,15.34) v1(74.08,15.34)
  vias: v3(71.43,15.34) v3(72.07,15.34)
+VR_CAP: length 13
  TOP w0.102: v1(256.24,51.13) 255.98,51.13 v2(255.53,51.57)
  TOP w0.305: UE2.B12 257.44,46.26 256.99,45.82 v2(256.8,45.82)
  TOP w0.508: v2(255.53,51.57) 256.22,52.26 CE31.1
  IN2 w0.381: v2(255.53,51.57) 255.84,51.88 257.12,51.88 258.14,50.86 258.14,49.5 257.85,49.21 257.54,49.21 256.99,48.67 256.99,47.18 257.38,46.8 257.38,46.18 257.02,45.82 v2(256.8,45.82)
+VREFOUT: length 11.8
  TOP w0.203: UA1.23 31.46,21.08 31.2,21.34 30.71,21.34
  TOP w0.508: RA5.2 27.33,18.27 v2(26.68,18.27) 26.03,18.27 RA6.2 ; v2(28.64,23.1) CA26.1 29.51,22.53 v1(30.16,21.88) 30.71,21.34
  IN1 w0.508: v2(28.64,23.1) 28.14,23.1 26.58,21.54 26.58,18.38 v2(26.68,18.27)
+Z4012: length 1.3
  TOP w0.508: PD3.2 291.64,7.21 291.64,7.21
-DCIN_JACK:
  vias: v2(54.47,91.2) v2(56.5,91.2) v2(58.53,91.2) v3(60.65,93.88) v3(60.65,93.12) v3(60.65,92.35) v3(61.31,93.88) v3(61.31,93.12) v3(61.31,92.35) v3(61.97,93.88) v3(61.97,93.12) v3(61.97,92.35) v4(59.31,92.66)
A_ON: length 62.8
  TOP w0.102: v2(254.28,56.44) 254.28,55.63 253.18,54.53 253.18,52.97 253.4,52.76 254.34,52.76 254.56,52.53 RPE10.3 ; v2(261.57,56.04) 261.57,55.73 v4(260.89,55.05) 260.04,54.2 260.04,51.4 260.32,51.12 260.32,50.23 261.34,49.21 261.34,48.46 261.19,48.31 UE2.A4 ; RZ42.1 222.58,68.72 v2(222.58,68.1) 222.34,67.87 UZ8.3
  IN2 w0.102: v2(261.57,56.04) 260.21,57.4 255.24,57.4 v2(254.28,56.44) 253.86,56.86 253.31,56.86 253.12,56.67 250.16,56.67 250.06,56.77 249.08,56.77 248.87,56.55 244.43,56.55 243.74,55.85 239.65,55.85 230.32,65.18 227.15,65.18 224.22,68.1 v2(222.58,68.1)
AC_DIS: length 254.2
  TOP w0.102: v2(262.7,70.08) v4(263.38,70.08)
  TOP w0.254: v2(258.83,49.17) 258.83,48.86 258.19,48.22 UE2.A10 ; v2(70.38,96.71) 70.43,96.76 PQ708.5 71.64,96.76 72.02,96.38 72.02,95.14 73.53,93.62 PR709.1 73.53,91.72 72.63,90.82 PQ711.2
  IN1 w0.254: v2(202.92,94.96) 202.92,92.98 205.34,90.55 224.73,90.55 225.39,89.89 229.3,89.89 233,86.18 233,85.77 233.38,85.39 233.77,85.39 236.83,82.34 236.83,79.96 239.66,77.13 239.66,71.77 241.78,69.65 253.76,69.65 254.8,70.69 262.09,70.69 v2(262.7,70.08)
  IN2 w0.254: v2(129.59,100.81) 107.45,100.81 106.44,101.83 101.73,101.83 94.44,94.54 89.77,94.54 88.46,93.23 82.94,93.23 82.29,92.57 78.29,92.57 74.15,96.71 v2(70.38,96.71)
  BOTTOM w0.254: v2(262.7,70.08) 262.7,63.03 260.6,60.93 260.6,57.96 258.29,55.65 258.29,54.55 258.28,54.54 258.28,49.47 258.59,49.17 v2(258.83,49.17) ; v2(202.92,94.96) 202.92,96.01 197.39,101.54 134.12,101.54 133.79,101.87 130.64,101.87 v2(129.59,100.81)
AC_PRESENT: length 126.6
  TOP w0.102: v2(176.4,47.55) 176.91,47.55 177.47,46.99 177.47,45.87 177.31,45.72 RPC1.6 ; UE2.A54 264.77,41.21 264.79,41.19 265.29,41.19 v2(265.72,40.75) ; v4(205.37,41.63) v2(206.29,41.63)
  IN1 w0.102: v2(183.3,50.88) 184.96,50.88 185.18,51.09 189.96,51.09 190.43,51.56 196.78,51.56 202.14,46.19 202.14,45.81 206.29,41.67 v2(206.29,41.63)
  IN2 w0.076: v2(165.74,58.34) 165.92,58.52 168.57,58.52 169.07,58.03 169.39,58.03 170.16,57.25 170.16,52.01 170.62,51.55 171.64,51.55 172.4,50.79 172.4,50.53 173.36,49.58
  IN2 w0.102: 173.36,49.58 175.38,47.55 v2(176.4,47.55) ; v2(206.29,41.63) 206.46,41.63 206.95,42.12 214.69,42.12 215.69,43.13 218.5,43.13 219.01,42.62 225.74,42.62 226.13,43.01 227.72,43.01 229.52,41.22 230.42,41.22 231.34,40.3 231.93,40.3 235.4,36.83 240.83,36.83 241.85,37.84 243.57,37.84 244.65,38.92 254.47,38.92 255.36,38.02 263.2,38.02 265.72,40.54 v2(265.72,40.75)
  BOTTOM w0.076: UC1.AJ8 165.74,58.1 v2(165.74,58.34)
  BOTTOM w0.102: v2(183.3,50.88) 182.73,50.88 179.72,47.87 176.72,47.87 v2(176.4,47.55)
ACAV_IN: length 260
  TOP w0.102: RE278.2 251.13,49.12 250.91,49.34 250.91,49.68 249.37,51.22 v2(249.36,51.22) ; v2(265.74,47.49) 265.74,47.3 264.65,46.21 UE2.A64
  TOP w0.254: 80.9,79.29 79.31,77.7 v2(79.25,77.7) ; 80.9,79.29 81.34,78.84 81.82,78.84 v2(82.59,79.6) 83.32,79.6 84.44,80.72 v4(84.44,81.41) 84.15,81.7 84.15,85.33 80.37,89.12 v2(80.35,89.12) ; 80.9,79.29 81.79,80.17 PR715.1
  IN1 w0.102: v2(195.51,94.93) 195.89,94.93 203.76,87.07 227.62,87.07 228.07,86.62 228.07,86.01 231.14,82.94 231.47,82.94 232.94,81.47 232.94,80.67 234.04,79.56 234.3,79.56 237.59,76.28 237.59,70.72 241.12,67.2 244.56,67.2 v2(249.07,62.69) 250.14,61.62 256.55,61.62 261.78,56.39 262.23,56.39 262.79,55.84 262.79,54.82 263.88,53.72 263.88,53.12 264.3,52.7 265.27,52.7 265.53,52.44 265.53,47.7 v2(265.74,47.49)
  BOTTOM w0.102: v2(249.07,62.69) 249.36,62.39 249.36,57.3 249.01,56.95 249.01,51.57 v2(249.36,51.22) ; v2(82.59,79.6) 83.09,80.11 92.78,80.11 93.52,80.85 115.08,80.85 116.44,82.21 121.94,82.21 125.46,85.72 128.8,85.72 130.91,87.83 130.91,92.96 135.8,97.85 190.17,97.85 193.09,94.93 v2(195.51,94.93)
  BOTTOM w0.254: PR714.1 80.12,88.89 v2(80.35,89.12) ; v2(79.25,77.7) PR713.2
ACAV_IN_NB: length 7.7
  TOP w0.102: UE2.B20 254.83,45.46 254.95,45.34 255.43,45.34 255.66,45.57 255.66,45.9 v2(255.13,46.43) ; RE278.1 252.09,47.76 v2(252.09,47.22) 251.95,47.08 v1(251.58,47.08)
  IN1 w0.102: v2(255.13,46.43) 254.43,46.43 253.64,47.22 v2(252.09,47.22)
ALW_PWRGD_3V_5V: length 85.5
  TOP w0.102: v2(270.22,52.32) 270.22,49 274.27,44.94 274.27,39.08 271.21,36.02 271.21,33.39 270.76,32.94 268.5,32.94 267.8,32.24 267.8,31.64 267.26,31.1 266.27,31.1 RZ51.1 ; PR108.1 222.04,46.64 v1(222.04,45.99) v2(222.04,45.31)
  IN2 w0.102: v2(262.53,51.9) 259.99,51.9 259.65,52.25 258.75,52.25 257.77,53.23 253.32,53.23 253.16,53.39 251.24,53.39 251.06,53.21 246.29,53.21 242.97,49.9 237.55,49.9 233.62,45.97 232.87,45.97 231.87,44.97 222.38,44.97 v2(222.04,45.31)
  BOTTOM w0.102: RE283.2 263.1,51.33 v2(262.53,51.9) 263.38,52.76 269.78,52.76 v2(270.22,52.32)
ALW_PWRGD_3V_5V_EC: length 4.4
  TOP w0.102: UE2.A1 263.11,47.91 263.4,47.62 v2(264.07,47.62)
  BOTTOM w0.102: v2(264.07,47.62) 262.9,47.62 v1(262.79,47.74) 262.79,48.87 RE283.1
ALWON: length 68.4
  TOP w0.102: PR113.1 214.04,45.56 v2(214.04,45.45) ; v2(265.21,44.39) 265.03,44.21 UE2.A60
  IN1 w0.102: v2(265.1,52.3) 264.61,51.82 264.61,48.46 265.1,47.98 265.1,47.63 265.29,47.44 265.29,44.47 v2(265.21,44.39)
  IN2 w0.102: v2(214.04,45.45) 214.27,45.22 219.31,45.22 219.89,45.8 222.15,45.8 222.77,45.17 231.78,45.17 232.77,46.17 233.54,46.17 237.47,50.1 240.57,50.1 245.69,55.22 247.28,55.22 247.7,54.8 252.83,54.8 253.39,55.36 255.04,55.36 255.14,55.46 259.62,55.46 261.93,53.15 264.25,53.15 v2(265.1,52.3)
  BOTTOM w0.102: v4(264.56,44.25) 264.7,44.39 v2(265.21,44.39)
AUD_HP_NB_SENSE: length 302.2
  TOP w0.254: v2(219.85,30.03) 213.45,30.03 210.59,32.9 v2(210.59,33.95) ; UE3.2 249.09,67.51 248.75,67.17 v2(248.75,66.8) ; v2(80.71,36.74) 80.68,36.72 v4(74.64,36.72) 69,36.72 57.3,25.02 42.67,25.02 40.73,23.08 QA1.2 40.12,23.08 38.44,24.76 v2(37.18,24.76)
  IN1 w0.254: v2(247.03,35.98) 246.71,35.66 236.8,35.66 234.66,33.51 232.19,33.51 230.41,31.74 222.81,31.74 221.75,30.68 220.43,30.68 219.85,30.1 v2(219.85,30.03)
  BOTTOM w0.254: v2(37.18,24.76) 32.26,24.76 31.66,25.36 29.35,25.36 29.04,25.06 26.9,25.06 24.85,23.01 24.85,19.66 22.83,17.64 RA2.1 CA41.1 19.28,17.64 18.85,17.22 DA2.3 17.9,18.03 17.05,18.89 17.05,23.16 14.02,26.19 9.38,26.19 8.8,25.61 JHP1.6 ; v2(248.75,66.8) 247.88,65.93 247.88,58.17 245.55,55.84 245.55,48.03 246.21,47.37 246.21,41.89 247.03,41.07 v2(247.03,35.98) ; v2(80.71,36.74) 80.83,36.87 83.69,36.87 89.67,30.89 207.52,30.89 v2(210.59,33.95)
AUD_HP_OUT_L: length 25.2
  TOP w0.381: LA2.1 22.1,13.63 22.53,14.06 RA24.1 RA7.2 v2(22.5,13.17) ; CA43.2 35.15,25.37 v2(34.91,25.61)
  IN2 w0.381: v2(34.91,25.61) 34.91,25.6 29.97,20.66 29.97,14.91 29.17,14.11 23.44,14.11 v2(22.5,13.17)
AUD_HP_OUT_L1: length 12.6
  TOP w0.381: LA2.2 CA3.1 20.42,12.6 18.22,12.6 18.1,12.48 DA3.3 16.25,12.48 15.91,12.81 v4(13.04,12.81) 12.09,12.81 11.55,13.35 JHP1.1
AUD_HP_OUT_R: length 21.6
  TOP w0.381: v2(34.16,25.63) 33.88,25.35 CA44.2 ; v2(23.21,16.65) 23.12,16.56 RA8.2 RA25.1 22.55,14.97 22.4,15.12 LA3.1
  IN1 w0.381: v2(34.16,25.63) 30.39,21.86 30.39,18.34 28.7,16.65 27.29,16.65 26.65,16.01 26.05,16.01 25.41,16.65 v2(23.21,16.65)
AUD_HP_OUT_R1: length 27.3
  TOP w0.381: LA3.2 21.75,15.87 CA2.1 20.1,15.87 19.52,16.46 DA1.2 18.16,16.46 17.47,15.77 v4(15.12,15.77) 14.69,15.77 v2(14.56,15.9)
  IN2 w0.381: JHP1.2 6.05,25.55 6.58,26.07 13.26,26.07 15.3,24.03 15.3,16.64 v2(14.56,15.9)
AUD_NB_MUTE#: length 324.7
  TOP w0.102: v2(250.39,66.78) 250.62,67.01 UE3.3 ; QA2.2 26.56,26.27 v2(25.91,26.92) v1(25.4,26.92)
  TOP w0.203: v2(38.08,13.87) 38.06,13.89 37.79,13.89 37.37,14.31 36.92,14.31 36.65,14.05 35.6,14.05 35.46,14.18 UA1.48
  TOP w0.254: v2(38.08,13.87) 38.91,13.04 RA18.2 37.81,13.01 CA31.1
  IN1 w0.102: v2(25.91,26.92) 26.44,26.39 35.2,26.39 36.29,25.3 36.29,15.58 38.01,13.87 v2(38.08,13.87) ; v2(201.23,95.82) 198.71,95.82 198.28,95.39 198.28,94.03 203.79,88.52 219.12,88.52 219.72,87.92 229.06,87.92 231.73,85.25 231.73,83.89 235.58,80.04 235.58,79.43 238.4,76.61 238.4,71.06 241.44,68.02 249.18,68.02 250.39,66.81 v2(250.39,66.78)
  IN2 w0.102: v2(38.08,13.87) 38.08,14.48 41.06,17.45 42.17,17.45 44.19,19.47 48.65,19.47 72.43,43.24 72.43,51.78 79.1,58.46 83.52,58.46 88.1,63.04 90.91,63.04 91.8,63.93 91.8,74.96 99.12,82.28 99.12,89.05 99.92,89.85 99.92,94.93 v2(103.77,98.78)
  BOTTOM w0.102: v2(103.77,98.78) 103.77,99.31 104.85,100.39 133.55,100.39 133.86,100.7 196.78,100.7 201.23,96.24 v2(201.23,95.82)
AUD_OUT_L: length 7.9
  TOP w0.203: UA1.33 29.87,16.57 29.78,16.48 29.53,16.48 28.5,15.44 28.5,14.9 v2(28.32,14.72)
  TOP w0.381: v2(24.72,13.12) 24.67,13.17 RA7.1
  IN1 w0.381: v2(24.72,13.12) 24.74,13.12 26.15,14.53 28.13,14.53 v2(28.32,14.72)
AUD_OUT_R: length 7
  TOP w0.203: UA1.32 29.83,16.97 29.64,16.78 29.4,16.78 28.27,15.65 28.12,15.65 v2(27.82,15.35)
  TOP w0.381: RA8.1 24.65,15.86 v2(24.66,15.85)
  IN1 w0.381: v2(27.82,15.35) 25.16,15.35 v2(24.66,15.85)
AUD_PC_BEEP: length 4.5
  TOP w0.102: CA27.2 CA28.2 v1(37.63,21.06) 37.32,21.06 36.83,20.57 36.83,19.9 36.7,19.77 36.63,19.77 36.63,19.77 UA1.12
AUD_SENSE_A: length 4.6
  TOP w0.203: 35.7,21.38 35.66,21.38 35.46,21.18 UA1.13
  TOP w0.254: 35.7,21.38 v1(37.25,22.93) 38.05,23.73 QA1.1
AUX_EN_WOWL: length 45
  TOP w0.102: UZ3.3 249.15,30.3 249.3,30.15 250.2,30.15 250.38,30.33 RZ38.2 249.37,31.85 248.6,31.85 247.95,32.5 247.95,32.97 247.5,33.42 UZ11.1 247.5,36.34 247.15,36.69 247.15,37.98 247.58,38.41 247.58,40.66 247.16,41.08 247.16,42.92 247.15,42.94 247.15,43.07 246.25,43.97 246.25,46.41 246.4,46.56 246.4,50.61 245.95,51.07 245.95,53.94 246.66,54.65 v1(246.66,59.98) 246.66,65.49 247.18,66.01 250.02,66.01 250.53,65.51 UE3.6
B-RAMP: length 5.1
  TOP w0.102: v2(103.55,63.86) 103.55,62.86 v1(103.38,62.69)
  TOP w0.203: PU500.11 103.95,64.26 v2(103.55,63.86)
  BOTTOM w0.254: PR507.1 103.74,64.05 v2(103.55,63.86) 103.33,63.64 102.96,63.64 102.6,63.28 PR502.2
BAT1_LED#: length 46
  TOP w0.254: v2(269.49,28.84) 269.49,29.13 270.81,30.45 v4(270.81,31.76) 270.81,32.52 271.51,33.22 271.51,35.79 274.57,38.85 274.57,45.11 270.85,48.83 v2(270.85,49) ; RZ28.1 270.3,16.99 v2(270.58,17.27) ; v2(265.1,48.58) 265.1,47.89 264.27,47.06 UE2.B1
  IN1 w0.254: v2(270.58,17.27) 270.24,17.61 270.24,27.41 269.49,28.15 v2(269.49,28.84)
  IN2 w0.254: v2(270.85,49) 266.68,49 266.46,48.77 265.29,48.77 v2(265.1,48.58)
BAT2_LED#: length 41.6
  TOP w0.254: RZ25.1 271.26,17.31 270.75,17.81 270.75,26.11 270.15,26.71 270.15,29.06 270.56,29.46 271.07,29.46 v4(271.36,29.76) 271.36,32.45 271.99,33.08 271.99,35.69 275.08,38.77 v2(275.08,43.65) ; v2(265.1,41.71) 265.09,41.71 UE2.A55
  IN2 w0.254: v2(275.08,43.65) 272.49,43.65 270.74,41.9 265.29,41.9 v2(265.1,41.71)
BATDRV#: length 19.5
  TOP w0.254: v2(86.19,78.91) 86.18,78.92 83.94,78.92 v1(83.74,78.71) 82.81,77.79 80.65,77.79 v2(79.87,77.01)
  BOTTOM w0.254: PR722.2 v2(79.87,77.01) ; PQ701.4 96.3,77.74 96.11,77.93 92.2,77.93 91.55,78.57 87.7,78.57 87.37,78.91 v2(86.19,78.91)
BATT_WHITE#: length 5.8
  TOP w0.254: JLED1.5 268.15,11.7 268.59,12.14 268.59,13.17 v4(269.43,14.01) 269.43,14.02 269.64,14.24 269.66,14.24 270.3,14.88 270.74,14.88 RZ25.2
BATT_YELLOW#: length 5.5
  TOP w0.254: JLED1.4 267.65,12.31 v4(267.95,12.61) 267.95,13.33 269.36,14.74 269.65,14.74 RZ28.2
BBS_BIT: length 11.6
  TOP w0.102: v2(167.75,69.21) 168.21,69.67 168.21,70.33 167.98,70.56 167.98,73.2 168.64,73.86 168.64,76.67 T109.1
  BOTTOM w0.076: v2(167.75,69.21) 167.75,68.36 167.38,68 166.63,68 166.2,67.56 UC1.L8
BC_CLK_ECE1099: length 50.1
  TOP w0.102: UE2.A43 260.19,36.59 259.94,36.34 259.94,35.73 v2(259.55,35.33) ; v2(255.61,69.72) 255.44,69.54 UE3.33
  BOTTOM w0.102: v2(259.55,35.33) 259.45,35.43 254.57,35.43 253.91,36.09 252.24,36.09 251.57,36.76 251.57,38.32 253.1,39.84 253.1,41.8 252.69,42.2 252.69,42.4 250.89,44.21 250.89,56.44 251.2,56.76 251.2,68.2 253.13,70.13 255.2,70.13 v2(255.61,69.72)
BC_CLK_ECE1117: length 62
  TOP w0.102: v2(242.44,19.96) 242.58,20.1 JKBTP1.7 ; v2(252.15,44.29) 252.58,44.71 UE2.A20 ; v4(245.02,41.67) v2(245.02,40.98)
  IN2 w0.102: v2(252.15,44.29) 252.09,44.35 252.09,44.35 251.95,44.49 250.7,44.49 250.1,43.89 249.13,43.89 248.33,44.69 247.38,44.69 247.25,44.56 247.25,44.07 247.13,43.94 246.53,43.94 246.4,43.81 246.4,43.6 246.53,43.47 247.19,43.47 247.32,43.34 247.32,43.07 247.19,42.94 246.5,42.94 246.37,42.81 246.37,42.58 246.5,42.46 247.14,42.46 247.27,42.33 247.27,42.1 247.14,41.97 245.62,41.97 245.49,41.85 245.49,41.58 245.62,41.45 247.05,41.45 247.18,41.33 247.18,41.1 247.05,40.98 v2(245.02,40.98)
  BOTTOM w0.102: v2(242.44,19.96) 242.44,19.8 242.57,19.67 243.77,19.67 243.9,19.8 243.9,20.15 243.77,20.28 243.28,20.28 243.15,20.41 243.15,20.64 243.28,20.76 243.77,20.76 243.9,20.89 243.9,21.11 243.77,21.23 243.3,21.23 243.18,21.36 243.18,21.64 243.3,21.77 243.8,21.77 243.9,21.87 243.9,22.18 243.8,22.28 243.3,22.28 243.18,22.4 243.18,22.66 243.3,22.79 243.77,22.79 243.9,22.91 243.9,23.17 243.77,23.29 243.47,23.29 243.34,23.42 243.34,23.7 243.47,23.82 244.6,23.82 244.73,23.95 244.73,24.21 244.6,24.33 243.88,24.33 243.75,24.46 243.75,26.73 243.88,26.86 245.96,26.86 246.09,26.99 246.09,27.25 245.98,27.35 244.79,27.35 244.66,27.48 244.66,27.73 244.79,27.86 245.98,27.86 246.09,27.96 246.09,28.27 245.98,28.37 244.75,28.37 244.62,28.49 244.62,28.75 244.75,28.88 245.98,28.88 246.09,28.98 246.09,29.28 245.98,29.38 245.31,29.38 245.18,29.51 245.18,29.76 245.31,29.89 245.98,29.89 246.09,29.99 246.09,30.31 245.98,30.41 245.67,30.41 245.56,30.51 245.56,30.81 245.67,30.92 245.98,30.92 246.09,31.02 246.09,31.32 245.98,31.42 245.67,31.42 245.56,31.53 245.56,31.83 245.67,31.93 245.98,31.93 246.09,32.03 246.09,32.34 245.98,32.44 245.67,32.44 245.56,32.54 245.56,36.81 244.83,37.55 244.83,40.79 v2(245.02,40.98)
BC_DAT_ECE1099: length 57
  TOP w0.102: UE3.32 255.94,69.39 256.04,69.49 256.04,71.22 255.84,71.42 255.84,73.66 256.52,74.35 258.32,74.35 v2(259.36,73.3) ; v2(259.42,39.18) 259.68,39.18 259.94,38.92 UE2.B45 ; v2(260.98,56.04) 260.55,55.61 259.33,55.61 v1(258.42,54.7) 257.29,53.57 257.29,52.8 RE36.2
  BOTTOM w0.102: v2(259.42,39.18) 259.42,44.78 260.32,45.68 260.32,47.59 261.34,48.6 261.34,49.48 260.94,49.88 260.94,52.55 261.35,52.96 261.35,54.98 260.98,55.35 v2(260.98,56.04) 261.93,57 262.95,57 264.22,58.27 264.22,69.28 260.2,73.3 v2(259.36,73.3)
BC_DAT_ECE1117: length 77
  TOP w0.102: v2(231.8,42.12) 231.16,41.48 231.16,32.37 230.69,31.9 230.69,29.63 v4(231.89,28.43) 240.76,19.56 243.32,19.56 243.77,19.1 244.37,19.1 244.37,19.1 JKBTP1.9 ; v2(264.07,48.88) 263.69,49.27 263.69,49.55 263.59,49.66 263.59,51.02 263.27,51.33 RPE5.1 ; UE2.B21 254.72,44.96 254.79,44.89 v2(255.25,44.89)
  IN2 w0.102: v2(231.8,42.12) 232.17,42.12 236.02,38.27 240.18,38.27 241.2,39.29 242.23,39.29 245.92,42.98 245.92,44.08 247.02,45.19 248.63,45.19 249.39,44.42 249.92,44.42 250.48,44.98 252.05,44.98 252.65,45.58 253.62,45.58 254.31,44.89 v2(255.25,44.89) 255.66,44.47 256.08,44.47 256.74,43.81 259.32,43.81 260.31,44.81 261.27,44.81 262.34,45.87 262.34,46.09 263.55,47.29 263.55,48.36 v2(264.07,48.88)
BC_INT#_ECE1099: length 47.1
  TOP w0.102: UE2.A42 259.69,36.66 259.54,36.51 v2(259.54,35.94) ; UE3.34 254.94,69.63 v2(255.03,69.72)
  BOTTOM w0.102: v2(255.03,69.72) 253.35,69.72 251.61,67.98 251.61,56.59 251.29,56.28 251.29,44.39 v1(252.55,43.13) 253.11,42.57 253.11,42.4 253.5,42.01 253.5,39.68 251.98,38.15 251.98,36.93 252.41,36.5 254.11,36.5 254.77,35.84 259.42,35.84 259.52,35.94 v2(259.54,35.94)
BC_INT#_ECE1117: length 61.7
  TOP w0.102: v2(230.15,42.18) 230.76,41.57 v4(230.76,34.94) 230.76,32.54 230.29,32.07 230.29,29.46 240.59,19.15 243.12,19.15 243.67,18.6 244.31,18.6 JKBTP1.10 ; v2(252.78,45.12) 252.87,45.21 UE2.A19
  IN2 w0.102: v2(252.78,45.12) 253.3,44.6 253.3,43.69 252.75,43.14 249.89,43.14 247.18,40.42 244.18,40.42 242.56,38.81 241.45,38.81 240.43,37.79 235.8,37.79 232.33,41.26 231.74,41.26 230.82,42.18 v2(230.15,42.18)
BEEP: length 230.7
  TOP w0.102: UE2.B19 254.99,45.96 v2(255.2,45.74) ; v2(80.72,35.86) 80.32,36.26 69.15,36.26 57.48,24.59 45.72,24.59 v1(44.88,23.75) 42.42,21.28 41.87,21.28 RA13.2
  IN1 w0.102: v2(217.75,33.95) 218.15,34.34 221.92,34.34 223.97,36.39 234.71,36.39 236.93,38.61 240.18,38.61 241.11,39.53 242.24,39.53 247.67,44.97 248.17,44.97 249.39,46.19 253.24,46.19 253.68,45.74 v2(255.2,45.74)
  BOTTOM w0.102: v2(80.72,35.86) 81.24,36.38 83.51,36.38 89.85,30.05 155.29,30.05 155.64,30.39 208.02,30.39 210.43,32.8 216.6,32.8 v2(217.75,33.95)
BIA_PWM: length 4.3
  TOP w0.102: v1(109.98,90.65) RV1.1 109.98,88.99 109.96,88.97 LV1.2 109.96,87.62 109.57,87.23 DV1.1
BIA_PWM_EC: length 221.5
  TOP w0.102: v2(106.18,87.5) 106.18,85.95 v1(106.37,85.76) 106.75,85.38 DV1.2 ; UE2.B25 255.16,42.96 v2(255.2,43.01)
  IN1 w0.102: v2(199.28,94.99) 199.28,93.65 203.58,89.36 224.67,89.36 225.27,88.76 228.8,88.76 232.17,85.39 232.17,84.74 233.35,83.55 234.09,83.55 235.99,81.65 235.99,79.6 238.81,76.78 238.81,71.23 241.52,68.52 260.59,68.52 v2(260.98,68.12)
  BOTTOM w0.102: v2(199.28,94.99) 199.28,95.25 194.9,99.63 134.75,99.63 129.13,94.01 129.13,88.77 127.86,87.5 124.69,87.5 121.35,84.16 116.08,84.16 114.18,86.07 111.14,86.07 110.28,85.2 106.49,85.2 106.18,85.51 v2(106.18,87.5) ; v2(260.98,68.12) 261.6,67.5 261.6,63.5 258.12,60.02 258.12,57.93 256.79,56.6 256.79,53.84 254.81,51.85 254.81,50.56 255.5,49.87 255.5,48.87 257.22,47.15 257.22,45.02 256.73,44.53 256.73,43.87 256.37,43.51 255.7,43.51 v2(255.2,43.01)
BOARD_ID: length 11.2
  TOP w0.102: UE2.B10 258.44,46.11 258.09,45.76 258.07,45.76 v2(258.04,45.72) ; v2(259.34,52.76) 259.2,52.76 258.75,52.3 RE79.2 CE40.1
  BOTTOM w0.102: v2(258.04,45.72) 258.44,46.13 258.44,47.22 v1(258.69,47.47) 259.78,48.55 259.78,52.32 v2(259.34,52.76)
BOOT_1.35V:
  vias: v1(67.47,13.25)
BOOT_1.35V_C: length 1.5
  BOTTOM w0.102: PR200.1 v1(68.7,15.66)
BQ24770_REGN: length 8.5
  TOP w0.508: v2(75.99,82.53) 76.1,82.53 76.44,82.19 v1(76.44,79.56) 76.44,79.3 76.82,78.92 v2(76.82,77.01)
  BOTTOM w0.508: PR725.1 PR713.1 PR799.2 v2(76.82,77.01)
BREATH_LED#: length 63.9
  TOP w0.102: UE2.B57 262.9,40.96 v2(262.86,41) ; QZ7.4 286.24,82.42 286.23,82.4 RZ34.1 285.62,83.12 v2(285.59,83.14)
  IN1 w0.102: v2(274,55.8) 273.17,56.63 273.17,58.03 270.62,60.58 270.62,61.34 270.58,61.38 270.58,66.09 281.48,76.99 281.65,76.99 285.59,80.94 v2(285.59,83.14)
  IN2 w0.102: v2(274,55.8) 273.57,55.37 273.57,54.57 274.42,53.72 274.42,45.17 273.63,44.39 272.59,44.39 271.18,42.98 264.84,42.98 v2(262.86,41)
  BOTTOM w0.102: v1(287.45,83.14) v2(285.59,83.14)
BREATH_LED#_Q: length 3.3
  TOP w0.102: v1(286.29,83.64) 286.48,83.45 RZ32.1 287.46,82.66 287.71,82.42 QZ7.3
BREATH_WHITE_LED#: length 96.4
  TOP w0.102: RZ34.2 284.71,83.09 v2(284.77,83.16) ; JLED1.2 266.65,10.51 267.26,9.91 274.46,9.91 276.82,12.27 276.82,13.88 277.87,14.93 v4(277.87,19.49) 277.87,20.92 275.73,23.06 275.73,24.14 274,25.86 274,26.36 272.44,27.92 272.44,32.13 273.09,32.78 273.09,35.35 276.17,38.44 276.17,44.83 272.06,48.95 272.06,52.84 271.27,53.63 v2(271.27,57.47)
  IN1 w0.102: v2(271.27,57.47) 271.27,59.49 270.38,60.38 270.38,66.2 281.44,77.27 281.59,77.27 284.71,80.38 284.71,83.09 v2(284.77,83.16)
BREATH_WHITE_LED_SNIFF#: length 11.6
  TOP w0.102: LED3.1 295.45,85.25 293.74,83.54 289.35,83.54 289.27,83.45 RZ32.2 288.38,84.3 v4(288.86,84.78)
BST_3V:
  vias: v1(220.93,50.18)
BST_3V_C: length 1.2
  TOP w0.102: PR110.1 v1(223.38,51.8)
BST_5V: length 1.2
  TOP w0.102: PR109.1 v1(214.75,51.8)
BST_5V_C: length 1.3
  TOP w0.102: PR109.2 v1(213.36,51.85)
BST_+V1.05SP: length 1.3
  TOP w0.102: PC302.1 204.64,63.49 v1(204.34,63.79)
  vias: v2(205.32,62.76) v2(205.92,62.5)
BST_+V1.05SP_C: length 3.2
  TOP w0.102: PC302.2 203.25,63.28 v1(202.75,63.78)
  TOP w0.508: PR312.1 203.74,61.44 203.25,61.94 PC302.2
BT_LED#: length 12.6
  TOP w0.102: v4(244.34,33.45) RZ15.1 244.34,36.04 v2(244.12,36.26) 244.12,36.71 243.65,37.18 QZ2.4
  BOTTOM w0.102: v2(244.12,36.26) 243.98,36.12 243.98,32.24 241.83,30.1 JNGFF1.8
BT_RADIO_DIS#: length 47.5
  TOP w0.102: v2(245.69,60.39) 246.14,59.94 246.14,58.5 v4(245.76,58.11) 245.39,57.75 245.39,55.81 244.47,54.9 244.47,46.71 244.78,46.41 244.78,43.03 245.67,42.14 245.67,40.31 246.1,39.88 246.1,39.15 245.43,38.49 242.12,38.49 240.05,36.42 240.05,33.79 238.98,32.72 238.98,31.78 240.26,30.5 240.26,29.52 DZ2.1 ; UE3.12 252.44,61.49 v2(252.16,61.21) 252.16,60.82 RE11.2
  IN2 w0.102: v2(252.16,61.21) 252.15,61.21 251.33,60.39 v2(245.69,60.39)
BT_RADIO_DIS#_R: length 11.1
  TOP w0.102: v2(242.98,28.02) 242.98,28.81 v1(242.91,28.88) 242.6,29.19 DZ2.2
  BOTTOM w0.102: v2(242.98,28.02) 243.11,27.89 243.11,24.38 242.57,23.84 242.57,20.99 242.18,20.6 JNGFF1.46
CAM_MIC_CBL_DET#: length 123.3
  TOP w0.102: RPC16.5 182.99,69.98 182.41,70.56 182.41,76.45 179.69,79.17 175.76,79.17 173.57,76.98 173.57,76.27 172.23,74.94 172.23,71.82 171.52,71.1 169.8,71.1 169.11,70.4 v2(169.07,70.4) ; v2(105.46,92.86) 106.56,91.76 118.64,91.76 v1(119.19,92.31) 120.58,93.7 166.36,93.7 172.97,87.09 v2(172.97,85.38)
  IN1 w0.102: v2(169.07,70.4) 168.88,70.4 168.09,71.2 168.09,71.75 168.11,71.77 168.11,72.56 167.77,72.9 167.77,74.74 168.86,75.83 168.86,76.41 169.81,77.37 169.81,82.41 170.41,83.01 170.41,84.05 172.17,85.81 172.54,85.81 v2(172.97,85.38)
  BOTTOM w0.076: UC1.F4 168.83,70.17 v2(169.07,70.4)
  BOTTOM w0.102: JEDP1.14 v2(105.46,92.86)
CFG0: length 95.9
  TOP w0.102: JXDP1.9 80.21,58.7 80.78,59.27 80.78,59.93 82.47,61.62 87.08,61.62 88.73,59.97 88.73,57.35 90.19,55.89 91.25,55.89 94.31,52.83 94.31,47.63 93.89,47.21 v1(93.89,46.25) v2(93.89,45.62)
  IN2 w0.102: v2(131.05,60.35) 131.05,60.06 130.35,59.36 129.17,59.36 126.15,56.34 120.57,56.34 118.46,54.23 118.46,48.18 117.5,47.22 108.02,47.22 107.51,46.72 96.91,46.72 96.72,46.53 96.72,45.81 96.59,45.68 96.33,45.68 96.2,45.81 96.2,46.52 96.07,46.65 95.73,46.65 95.6,46.52 95.6,44.78 95.48,44.65 95.22,44.65 95.1,44.78 95.1,46.16 94.97,46.29 94.63,46.29 94.5,46.16 94.5,44.23 94.37,44.11 93.99,44.11 93.86,44.23 93.86,44.89 93.74,45.02 93.32,45.02 93.19,44.89 93.19,44.23 93.06,44.11 92.67,44.11 92.54,44.23 92.54,45.49 92.67,45.62 v2(93.89,45.62)
  BOTTOM w0.076: UC1.AC60 133.74,60.68 133.41,60.68 133.34,60.75 133.33,60.75 133.29,60.79 132.51,60.79 132.47,60.75 132.47,60.75 132.36,60.64 132.34,60.64 132.34,60.64 131.9,60.64 131.8,60.74 131.44,60.74 v2(131.05,60.35)
  BOTTOM w0.102: RC183.1 128.48,60.79 130.31,60.79 130.75,60.35 v2(131.05,60.35)
CFG1: length 97.8
  TOP w0.102: JXDP1.11 80.21,58.2 81.11,59.11 81.11,59.88 82.62,61.39 86.95,61.39 88.5,59.84 88.5,57.28 90.27,55.51 v4(90.84,55.51) 91.25,55.51 93.87,52.88 93.87,48.05 v2(93.88,48.05)
  IN2 w0.102: v2(93.88,48.05) 95.07,49.24 95.07,51.06 98.36,54.35 98.36,58.83 99.37,59.85 99.37,63.07 100.06,63.76 100.06,72.54 101.35,73.84 102.72,73.84 102.84,73.96 107.39,73.96 109.58,71.78 119.32,71.78 120,71.1 125.19,71.1 127.9,68.39 127.9,63.25 129.16,61.98 v2(129.16,61.34)
  BOTTOM w0.076: 129.42,61.08 129.53,60.97 130.38,60.97 130.54,60.81 131.06,60.81 131.17,60.92 131.9,60.92 132.01,60.8 132.29,60.8 132.57,61.08 UC1.AC62
  BOTTOM w0.102: 129.42,61.08 129.16,61.34 v2(129.16,61.34) 128.74,61.77 RC184.1
CFG2: length 76.9
  TOP w0.102: v2(85.44,45.12) 82.72,45.12 81.81,46.03 81.81,55.88 80.49,57.2 JXDP1.15
  IN2 w0.102: v2(130.34,61.47) 129.8,60.94 128.71,60.94 125.36,57.58 120.2,57.58 117.24,54.62 117.24,48.21 116.87,47.83 107.76,47.83 107.26,47.33 94.66,47.33 94.03,46.71 92.39,46.71 89.86,44.18 86.38,44.18 v2(85.44,45.12)
  BOTTOM w0.076: UC1.AC63 130.73,61.08 v2(130.34,61.47)
  BOTTOM w0.102: v2(85.44,45.12) v1(85.44,45.8)
CFG3: length 98.6
  TOP w0.102: v2(87.86,46.08) 87.86,46.08 RC113.2 85.82,44.72 82.83,44.72 81.61,45.94 81.61,55.46 80.37,56.7 JXDP1.17 76.93,56.7 RC305.1
  IN2 w0.102: v2(87.86,46.08) 89.79,48.01 92.97,48.01 94.66,49.69 94.66,51.23 97.95,54.52 97.95,59 98.97,60.02 98.97,63.24 99.65,63.93 99.65,72.71 101.31,74.37 107.56,74.37 109.74,72.19 119.49,72.19 120.17,71.5 125.36,71.5 128.37,68.49 128.37,63.51 128.84,63.04 129.35,63.04 v2(129.78,62.61)
  BOTTOM w0.076: v2(129.78,62.61) 130.35,62.04 131.02,62.04 131.36,61.7 132.03,61.7 UC1.AA63
  BOTTOM w0.102: v2(87.86,46.08) v1(87.86,46.62)
CFG3_R: length 2.4
  TOP w0.102: JXDP1.60 85.08,46.2 85.2,46.08 RC113.1
CFG4: length 81.9
  TOP w0.102: v2(86.98,43.4) 85.87,44.51 82.75,44.51 81.4,45.86 81.4,52.95 80.24,54.11 79.46,54.11 79.38,54.2 JXDP1.27 ; RC191.1 122.66,46.86 121.78,46.86 v2(121.08,47.56)
  IN2 w0.102: v2(86.98,43.4) 94.76,43.4 97.88,46.52 107.6,46.52 108.1,47.02 119.54,47.02 v2(119.8,47.28) 119.8,49 118.79,50 118.79,54 120.86,56.07 126.21,56.07 128.34,58.2 132.2,58.2 133.81,59.81 v2(133.81,61.46)
  BOTTOM w0.076: v2(133.81,61.46) 134.11,61.76 UC1.AA60
  BOTTOM w0.102: v2(119.8,47.28) 120.09,47.56 v2(121.08,47.56)
CFG5: length 97.1
  TOP w0.102: JXDP1.29 80.07,53.7 v2(80.07,53.7)
  IN2 w0.102: v2(130.96,62.65) 131.22,62.92 131.59,62.92 132.28,63.6 132.28,67.3 131.19,68.39 131.19,69.74 129.55,71.37 129.55,72.2 129.17,72.58 129.17,73.36 127.44,75.09 127.44,76.88 126.3,78.03 126.3,78.9 125.25,79.95 107.14,79.95 103.8,76.61 100.38,76.61 96.71,72.93 96.71,60.92 95.07,59.28 95.07,57.01 94.66,56.61 94.66,53.82 92.83,51.99 92.83,50.48 92.61,50.25 90.48,50.25 89.52,51.21 89.52,52.09 88.99,52.62 87.51,52.62 85.68,50.79 82.98,50.79 v2(80.07,53.7)
  BOTTOM w0.076: v2(130.96,62.65) 130.96,62.57 131.46,62.07 131.74,62.07 131.95,62.27 132.26,62.27 132.27,62.29 132.28,62.29 132.45,62.46 132.45,62.46 132.57,62.58 UC1.Y62
CFG6: length 75.5
  TOP w0.102: JXDP1.33 79.61,52.7 79.82,52.49 80.4,52.49 81.2,51.69 81.2,45.77 82.67,44.31 85.03,44.31 v2(85.47,43.87) 85.47,43.87 85.84,43.51 v1(85.84,43.03)
  IN2 w0.102: v2(133.12,62.95) 133.12,62.7 131.35,60.93 130.32,60.93 129.93,60.53 128.91,60.53 125.56,57.17 120.37,57.17 117.65,54.45 117.65,48.04 117.04,47.43 107.93,47.43 107.43,46.93 94.82,46.93 94.2,46.3 93.53,46.3 93.05,45.82 92.11,45.82 90.16,43.87 v2(85.47,43.87)
  BOTTOM w0.076: v2(133.12,62.95) 133.15,62.95 133.46,62.64 UC1.Y61
CFG7: length 93.1
  TOP w0.102: JXDP1.35 80.13,52.2 80.39,51.94 v2(80.39,51.7)
  IN2 w0.102: v2(130.36,62.64) 129.7,63.3 128.89,63.3 128.6,63.59 128.6,68.55 125.62,71.53 125.62,76.12 123.82,77.91 109.16,77.91 105.82,74.57 101.23,74.57 99.45,72.8 99.45,64.01 98.77,63.33 98.77,60.1 97.75,59.09 97.75,54.61 94.46,51.32 94.46,49.78 92.89,48.21 83.88,48.21 v2(80.39,51.7)
  BOTTOM w0.076: UC1.Y60 133.81,62.25 133.33,62.25 133.3,62.29 132.51,62.29 132.34,62.11 132.02,62.11 131.81,61.9 131.4,61.9 131.01,62.28 130.72,62.28 v2(130.36,62.64)
CFG8: length 102.5
  TOP w0.102: JXDP1.10 85.67,58.7 86.4,57.97 86.4,57.01 90.18,53.22 90.18,50.52 90.05,50.39 88.73,50.39 88.58,50.24 88.58,49.91 88.73,49.76 92.26,49.76 92.39,49.63 92.39,49.25 92.26,49.12 v1(89.18,49.12) 88.47,49.12 88.33,48.97 88.33,48.76 88.47,48.62 v2(92.33,48.62)
  IN2 w0.102: v2(92.33,48.62) 92.99,48.62 94.26,49.89 94.26,51.4 97.55,54.69 97.55,59.17 98.56,60.19 98.56,63.41 99.25,64.1 99.25,72.88 101.14,74.78 105.74,74.78 109.08,78.12 123.91,78.12 125.82,76.21 125.82,71.62 128.88,68.56 128.88,64.01 v2(129.01,63.88)
  BOTTOM w0.076: 129.42,63.48 129.42,63.46 129.77,63.11 131.09,63.11 131.33,62.87 132.35,62.87 UC1.V62
  BOTTOM w0.102: RC190.1 128.73,63.88 v2(129.01,63.88) 129.42,63.48
CFG9: length 94.2
  TOP w0.102: v2(88.69,51.42) 89.19,51.92 89.19,53.89 86.17,56.91 86.17,57.68 v1(85.95,57.9) 85.65,58.2 JXDP1.12
  IN2 w0.102: v2(129.62,63.87) 130.26,64.52 130.85,64.52 131.05,64.72 131.05,65.35 130.02,66.38 130.02,69.46 127.8,71.68 127.8,73.51 126.63,74.67 126.63,76.55 124.25,78.93 108.73,78.93 105.39,75.59 100.81,75.59 98.44,73.22 98.44,67.64 97.72,66.93 97.72,60.5 96.1,58.88 96.1,54.4 93.44,51.74 93.44,50.23 92.86,49.64 90.22,49.64 88.69,51.18 v2(88.69,51.42)
  BOTTOM w0.076: 129.42,64.07 129.47,64.01 ; UC1.V61 133.2,63.62 132.68,63.62 132.45,63.38 132.45,63.21 132.29,63.05 132.28,63.05 132.27,63.05 131.39,63.05 131.09,63.35 130.14,63.35 v2(129.62,63.87)
  BOTTOM w0.081: 129.47,64.01 v2(129.62,63.87)
  BOTTOM w0.102: RC189.1 129.05,64.43 129.42,64.07
CFG10: length 93.6
  TOP w0.102: v2(88.78,53.07) 88.78,53.97 85.56,57.2 JXDP1.16
  IN2 w0.102: v2(88.78,53.07) 88.97,53.26 92.53,53.26 94.46,55.2 94.46,56.69 94.87,57.1 94.87,59.37 96.5,61.01 96.5,73.01 100.3,76.81 103.71,76.81 107.05,80.15 125.34,80.15 126.5,78.98 126.5,78.11 127.65,76.97 127.65,75.17 129.37,73.45 129.37,72.67 129.74,72.3 129.74,71.57 131.99,69.32 131.99,68.34 132.49,67.83 132.49,64.07 132.88,63.69 133.77,63.69 134.03,63.42 134.03,63.14 133.83,62.94 v2(133.72,62.94) 133.36,63.31 132.92,63.31 131.69,62.08 130.41,62.08 v2(129.71,61.39)
  BOTTOM w0.076: UC1.V60 134.11,63.36 133.72,62.98 v2(133.72,62.94)
  BOTTOM w0.081: 129.47,61.63 v2(129.71,61.39)
  BOTTOM w0.102: RC188.1 128.44,62.66 129.47,61.63 ; v2(88.78,53.07) 88.71,53 v1(88.71,52.54)
CFG11: length 90.7
  TOP w0.102: JXDP1.18 85.74,56.7 88.28,54.16 v1(88.28,53) 88.28,52.41 v2(88.68,52.01)
  IN2 w0.102: v2(88.68,52.01) 88.91,52.01 89.11,51.8 89.11,51.04 90.31,49.85 92.78,49.85 93.24,50.31 93.24,51.82 95.9,54.48 95.9,58.96 97.52,60.58 97.52,72.59 100.72,75.79 105.31,75.79 108.65,79.13 124.33,79.13 126.83,76.63 126.83,74.76 128,73.59 128,71.81 128.49,71.32 130.22,69.59 130.22,66.47 131.25,65.44 131.25,64.53 130.99,64.26 130.6,64.26 v2(130.22,63.88)
  BOTTOM w0.076: v2(130.22,63.88) 130.59,63.51 131.12,63.51 131.42,63.81 131.78,63.81 131.97,63.62 132.35,63.62 132.51,63.79 133.3,63.79 133.37,63.71 133.78,63.71 UC1.U60
CFG12: length 83.6
  TOP w0.102: v2(88.1,51.42) 87.36,51.42 v1(87.21,51.57) 86.93,51.85 86.93,52.91 85.64,54.2 JXDP1.28
  IN2 w0.102: v2(88.1,51.42) 88.1,51.41 90.08,49.44 92.95,49.44 93.65,50.14 93.65,51.65 96.32,54.33 96.32,58.81 97.93,60.41 97.93,66.85 98.64,67.56 98.64,73.13 100.89,75.39 105.48,75.39 108.82,78.73 124.16,78.73 126.43,76.46 126.43,74.59 127.59,73.42 127.59,71.6 129.82,69.38 129.82,65.89 130.67,65.04 v2(130.67,65.02)
  BOTTOM w0.076: UC1.T63 132.07,64.75 130.95,64.75 v2(130.67,65.02)
CFG13: length 84.4
  TOP w0.102: v2(88.11,50.84) 87.3,50.84 86.51,51.62 86.51,52.6 v1(86.09,53.02) 86.09,53.2 85.59,53.7 JXDP1.30
  IN2 w0.102: v2(88.11,50.84) 89.71,49.24 93.03,49.24 93.85,50.06 93.85,51.57 96.52,54.24 96.52,58.72 98.13,60.33 98.13,66.76 98.84,67.47 98.84,73.05 100.97,75.18 105.57,75.18 108.91,78.52 124.08,78.52 126.23,76.38 126.23,74.51 127.39,73.34 127.39,71.51 129.59,69.31 129.59,65.54 v2(130.11,65.02)
  BOTTOM w0.076: v2(130.11,65.02) 130.62,64.52 132.5,64.52 UC1.T62
CFG14: length 85
  TOP w0.102: JXDP1.34 85.59,52.7 85.89,52.4 v2(86.08,52.4)
  IN2 w0.102: v2(86.08,52.4) 87.16,53.48 92.45,53.48 94.26,55.28 94.26,56.78 94.66,57.18 94.66,59.47 96.3,61.1 96.3,73.1 100.22,77.01 103.61,77.01 106.95,80.35 125.42,80.35 126.71,79.07 126.71,78.2 127.85,77.05 127.85,75.26 129.58,73.53 129.58,72.75 129.92,72.41 129.92,71.74 132.24,69.41 132.24,68.72 132.93,68.03 133.92,68.03 134.34,67.62 134.34,66.61 134.86,66.09 134.86,65.51 v2(133.8,64.45)
  BOTTOM w0.076: v2(133.8,64.45) 133.8,64.52 UC1.T61
  BOTTOM w0.102: v2(86.08,52.4) 86.08,53.52 v1(86.07,53.53)
CFG15: length 85.2
  TOP w0.102: v2(85.38,52.29) 85.29,52.2 JXDP1.36
  IN2 w0.102: v2(134.43,64.45) 135.06,65.08 135.06,66.22 134.6,66.67 134.6,67.74 134,68.35 132.98,68.35 132.48,68.85 132.48,69.58 131.07,70.99 131.07,72.85 130.82,73.1 130.29,73.1 128.05,75.34 128.05,77.14 126.92,78.27 126.92,79.14 125.51,80.56 106.85,80.56 103.51,77.22 100.13,77.22 96.1,73.18 96.1,61.19 94.46,59.55 94.46,57.27 94.05,56.86 94.05,55.37 92.41,53.72 86.51,53.72 85.38,52.59 v2(85.38,52.29)
  BOTTOM w0.076: UC1.T60 134.43,64.54 v2(134.43,64.45)
  BOTTOM w0.102: v2(85.38,52.29) v1(84.92,52.74)
CFG16: length 69.8
  TOP w0.102: v2(92.89,46.23) 92.89,53.07 91.36,54.6 89.28,54.6 v1(89.1,54.77) 86.62,57.25 86.62,58.91 85.84,59.7 JXDP1.6
  IN2 w0.102: v2(130.88,61.46) 130.54,61.11 130.25,61.11 129.87,60.73 128.8,60.73 125.44,57.38 120.29,57.38 117.45,54.54 117.45,48.12 116.95,47.63 107.85,47.63 107.35,47.13 94.74,47.13 94.11,46.5 93.16,46.5 v2(92.89,46.23)
  BOTTOM w0.076: UC1.AA62 132.75,61.77 132.35,61.37 130.97,61.37 v2(130.88,61.46)
CFG17: length 89.3
  TOP w0.102: JXDP1.4 85.11,60.2 85.27,60.04 v1(85.92,60.04) 86.85,59.11 86.85,57.38 89.13,55.1 91.24,55.1 93.34,53 v2(93.34,47.67)
  IN2 w0.102: v2(129.16,62.6) 128.97,62.6 128.14,63.43 128.14,68.43 125.27,71.3 120.09,71.3 119.4,71.98 109.66,71.98 107.48,74.17 101.4,74.17 99.86,72.63 99.86,63.84 99.17,63.16 99.17,59.93 98.16,58.92 98.16,54.44 94.87,51.15 94.87,49.61 93.34,48.09 v2(93.34,47.67)
  BOTTOM w0.076: UC1.AA61 133.18,61.87 132.93,62.12 132.68,62.12 132.51,61.95 132.51,61.78 132.28,61.54 131.3,61.54 131,61.84 129.87,61.84 129.42,62.29
  BOTTOM w0.102: 129.42,62.29 129.16,62.55 v2(129.16,62.6)
CFG18: length 86.5
  TOP w0.102: JXDP1.24 86.38,55.2 v1(87.17,54.41) 87.51,54.06 v2(87.51,52.02)
  IN2 w0.102: v2(87.51,52.02) 87.51,50.55 89.02,49.03 93.11,49.03 94.05,49.97 94.05,51.49 97.34,54.78 97.34,59.26 98.36,60.27 98.36,63.5 99.04,64.18 99.04,72.97 101.06,74.98 105.65,74.98 108.99,78.32 123.99,78.32 126.02,76.29 126.02,71.7 127.75,69.98 128.61,69.98 129.26,69.33 129.26,65.32 v2(129.55,65.02)
  BOTTOM w0.076: v2(129.55,65.02) 130.29,64.29 131.95,64.29 UC1.U63
CFG19: length 89
  TOP w0.102: JXDP1.22 v1(85.95,55.7) 86.4,55.7 87.86,54.24 87.86,52.25 v2(88.1,52.01)
  IN2 w0.102: v2(88.1,52.01) 88.5,52.41 88.91,52.41 89.32,52 89.32,51.13 90.39,50.05 92.69,50.05 93.04,50.4 93.04,51.91 95.7,54.57 95.7,59.05 97.32,60.67 97.32,72.68 100.64,76 105.22,76 108.56,79.34 124.42,79.34 127.04,76.71 127.04,74.84 128.2,73.68 128.2,71.9 128.58,71.53 130.45,69.65 130.45,67.49 132.01,65.93 132.01,64.54 131.36,63.88 v2(130.93,63.88)
  BOTTOM w0.076: UC1.U62 132.57,64.08 132.28,63.79 132.03,63.79 131.79,64.03 131.08,64.03 v2(130.93,63.88)
CFG_RCOMP: length 7.3
  IN1 w0.381: v2(131.58,63.41) 131.44,63.27 129.05,63.27 127.76,61.98 126.83,61.98 v2(126.43,61.57)
  BOTTOM w0.178: UC1.V63 131.66,63.33 131.58,63.41 v2(131.58,63.41)
  BOTTOM w0.381: v2(126.43,61.57) 126.43,62.13 RC185.1
CHAGER_SRC: length 0.6
  TOP w0.102: v1(67.29,70.07) 67.93,70.07
  vias: v3(68.71,73.9) v3(68.71,73.27) v3(68.71,72.63) v3(68.71,72) v3(69.34,73.9) v3(69.34,73.27) v3(69.34,72.63) v3(69.34,72)
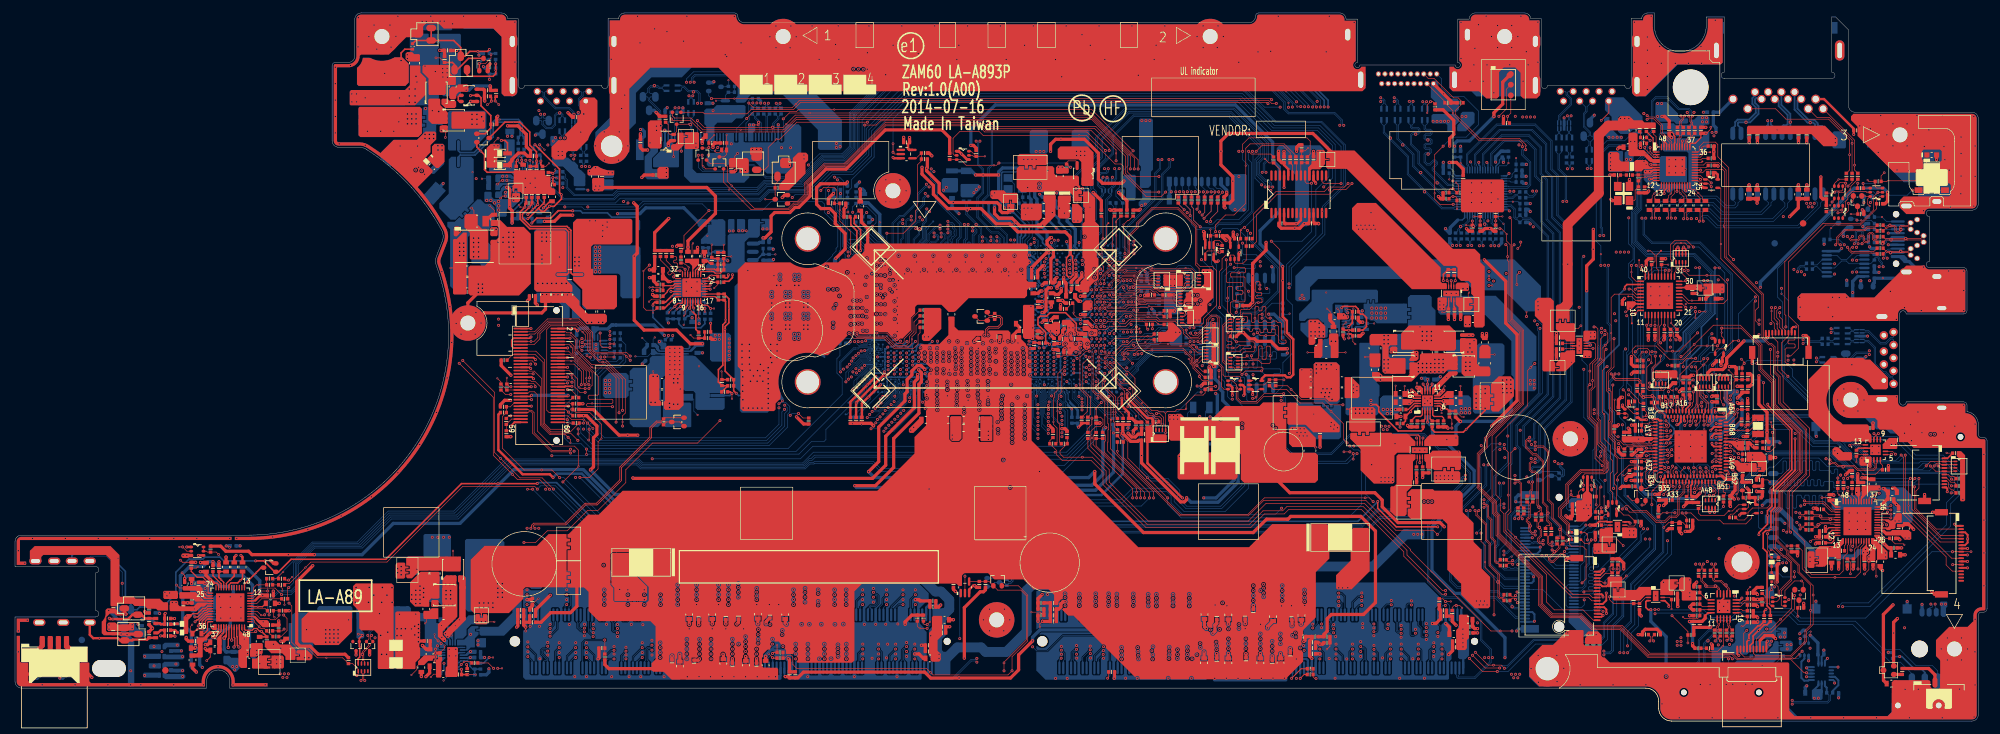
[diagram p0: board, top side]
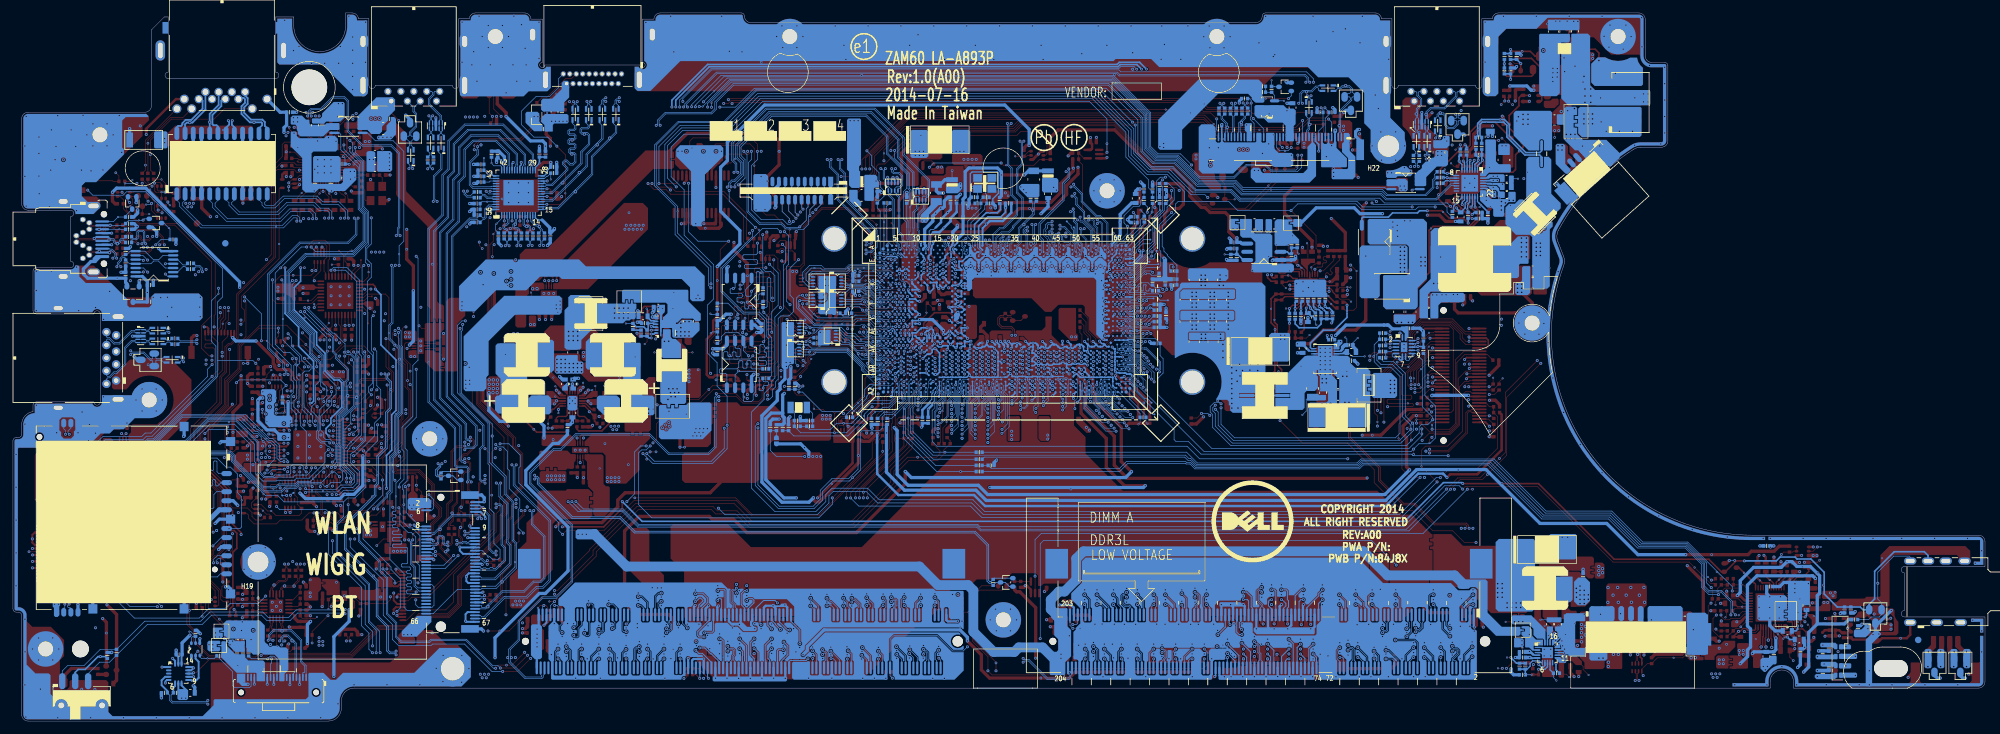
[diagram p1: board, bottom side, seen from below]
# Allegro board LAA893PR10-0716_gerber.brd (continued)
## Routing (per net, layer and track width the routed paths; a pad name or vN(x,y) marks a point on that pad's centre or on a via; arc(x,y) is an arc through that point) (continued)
CHARGER_SMBCLK: length 252.1
  TOP w0.102: RPE6.3 261.73,34.49 261.86,34.62 v2(261.86,34.91) ; v2(262.3,38.56) 262.44,38.43 UE2.B50
  IN1 w0.102: v2(261.86,34.91) 261.81,34.96 261.81,35.22 261.79,35.23 261.79,37.6 262.3,38.1 v2(262.3,38.56) 262.51,38.36 262.81,38.36 263.34,38.89 263.34,43.6 263.99,44.25 263.99,46.77 263.34,47.42 263.34,52.48 v2(262.24,53.58)
  IN2 w0.102: v2(204.72,92.13) 204.92,91.92 204.92,91.69 205.2,91.41 233.18,91.41 234.7,89.89 237.87,89.89 240.48,87.27 242.41,87.27 244.26,85.42 244.26,81.96 247.95,78.27 251.41,78.27 251.58,78.1 251.58,77.94 v2(251.41,77.77)
  BOTTOM w0.102: v2(251.41,77.77) 251.59,77.59 251.59,75.17 252.92,73.84 260.37,73.84 265.16,69.04 265.16,57.72 262.82,55.38 262.82,54.63 262.42,54.22 262.42,53.76 v2(262.24,53.58) ; v2(204.72,92.13) 204.9,92.3 204.9,92.86 203.86,93.89 196.75,93.89 196.06,94.58 196.06,95.65 193.37,98.34 135.51,98.34 130.43,93.26 130.43,88.03 128.6,86.21 125.26,86.21 121.74,82.69 116.23,82.69 114.91,81.37 93.36,81.37 92.58,80.59 84.73,80.59 82.48,82.84 82.12,82.84 82.03,82.76 PU700.12 ; PT2.1 261.47,35.29 v2(261.86,34.91)
CHARGER_SMBDAT: length 253.9
  TOP w0.102: RPE6.2 262.23,34.67 v2(262.45,34.89) 262.84,35.28 262.84,35.83 262.19,36.48 UE2.A47
  IN1 w0.102: v2(262.45,34.89) 262.02,35.33 262.02,37.5 262.65,38.13 262.9,38.13 263.57,38.8 263.57,43.5 264.22,44.15 264.22,46.87 263.57,47.52 263.57,52.83 v2(262.84,53.57)
  IN2 w0.102: v2(205.33,92.11) 205.15,91.93 205.15,91.79 205.3,91.64 233.27,91.64 234.8,90.12 237.96,90.12 240.58,87.5 242.5,87.5 244.49,85.52 244.49,82.05 248.05,78.5 251.51,78.5 251.81,78.19 251.81,77.95 v2(252,77.77)
  BOTTOM w0.102: v2(262.84,53.57) 262.65,53.76 262.65,54.13 263.05,54.53 263.05,55.29 265.39,57.63 265.39,69.14 260.46,74.07 253.02,74.07 251.82,75.27 251.82,77.59 v2(252,77.77) ; v2(262.45,34.89) 262.46,34.9 PT1.1 ; v2(205.33,92.11) 205.13,92.32 205.13,92.95 203.96,94.12 196.85,94.12 196.29,94.68 196.29,95.74 193.47,98.56 135.41,98.56 130.2,93.35 130.2,88.13 128.51,86.44 125.16,86.44 121.65,82.92 116.13,82.92 114.81,81.59 93.26,81.59 92.49,80.82 84.82,80.82 82.57,83.07 82.12,83.07 82.03,83.16 PU700.11
CHG_BTS:
  vias: v1(76.12,83.06)
CHG_BTS_C: length 1
  BOTTOM w0.102: PC712.1 v1(72.16,83.87)
CHG_LGATE: length 4.8
  TOP w0.102: v2(75.79,81.19) 75.35,81.19 v4(75.04,80.87)
  IN2 w1.016: 74.78,76.78 75.71,77.72 75.71,80.29
  vias: v2(75.8,81.77) v3(73.71,76.03) v3(74.34,76.03)
CHG_SNUB: length 3.5
  TOP w0.102: v1(73.33,79.73) 74.06,78.99 PC721.1
  TOP w0.508: PR726.1 73.72,78.29 PC721.1
CHG_SW: length 11
  TOP w0.102: 70.91,78.19 70.91,78.97 v4(70.56,79.32)
  IN1 w1.016: 74.47,83.97 71.28,80.79 71.28,75.62
  vias: v2(75.36,84.25) v2(75.99,84.25) v3(70.87,74.68) v3(70.87,73.99) v3(70.87,73.31) v3(70.87,72.55) v3(70.87,71.78) v3(71.63,74.68) v3(71.63,73.99) v3(71.63,73.31) v3(71.63,72.55) v3(71.63,71.78)
CHG_UGATE: length 10.1
  TOP w0.102: v4(74.56,83.03) 75.14,83.61 v2(75.36,83.61)
  IN2 w1.016: 74.51,83.36 73.87,83.36 71.79,81.29 71.79,80.1 68.73,77.04
  vias: v2(75.99,83.61) v3(68.15,76.16) v3(68.67,75.79)
CLK_BIASREF: length 11.4
  BOTTOM w0.102: UC1.C26 155.51,72.09 155.15,72.45 155.15,72.65 155.68,73.18 155.68,74.64
  BOTTOM w0.254: RC69.1 152.14,79.93 152.14,79.08 152.63,78.59 v1(153.78,78.59) 154.36,78.59 156.15,76.8 156.15,75.11 155.68,74.64
CLK_PCI_LPDEBUG: length 214.8
  TOP w0.102: v2(273.97,55.12) 273.54,55.55 273.54,57.49 273.75,57.7 274.94,57.7 275.09,57.85 275.09,58.18 274.94,58.33 274.13,58.33 273.97,58.48 273.97,58.76 274.13,58.91 274.94,58.91 275.06,59.03 JLPDE1.10 ; CC13.2 162.6,43.8 RC67.2 161.49,41.78 161.49,41.34 162.02,40.8 v4(164.95,40.8) 166.48,40.8 168.61,38.67 168.61,36.76 174.93,30.44 190.79,30.44 192.86,32.51 195.9,32.51 196.55,33.17 208.34,33.17 215.1,26.4 215.1,25.68 220.59,20.19 v2(221.07,20.19)
  IN2 w0.102: v2(221.07,20.19) 221.56,20.19 223.01,21.64 232.66,21.64 233.89,20.41 240.16,20.41 243.11,17.45 251.96,17.45 252.16,17.65 254.06,17.65 255,16.71 256.41,16.71 258.14,14.99 259.88,14.99 259.98,15.09 267.83,15.09 268.11,14.81 269.63,14.81 271.56,16.74 281.48,16.74 v2(282.43,17.69)
  BOTTOM w0.102: v2(273.97,55.12) 274.66,54.43 274.66,53.3 283.43,44.53 284.32,44.53 284.82,44.03 290.81,44.03 293.72,41.12 297.97,41.12 300.76,38.33 300.76,35.22 299.13,33.59 299.13,30.17 286.65,17.69 v2(282.43,17.69)
CLK_PCI_MEC: length 134.8
  TOP w0.102: v2(221.07,19.61) 220.49,19.61 214.62,25.49 214.62,26.17 208.09,32.69 196.79,32.69 196.14,32.03 193.06,32.03 190.99,29.96 174.73,29.96 168.13,36.56 168.13,38.47 166.31,40.3 161.83,40.3 160.98,41.15 160.98,41.82 RC74.2 159.92,43.36 CC12.2 ; UE2.A29 252.99,40.21 251.86,39.09 RE66.1 250.85,39.59 249.44,39.59 247.63,37.78 v2(247.63,37.27)
  IN2 w0.102: v2(221.07,19.61) 221.66,19.61 223.21,21.16 232.46,21.16 233.69,19.93 239.96,19.93 242.91,16.97 v2(245.4,16.97)
  BOTTOM w0.102: v2(247.63,37.27) 247.63,34.94 250.66,31.91 250.66,28.16 246.33,23.82 246.33,23.44 244.89,22.01 244.89,17.48 v2(245.4,16.97)
CLK_PCIE_LAN: length 137.9
  TOP w0.102: v2(252.22,93.63) 252.44,93.41 253.32,93.41 254.59,92.14 254.59,90.98 256.03,89.55 UL1.44
  IN2 w0.086: v2(252.22,93.63) 252.02,93.43 251.26,93.43 250.83,93.87 247.65,93.87 244.67,90.89 235.17,90.89 233.73,92.33 207.48,92.33 207.03,92.77 177.28,92.77 176.76,92.26 151.65,92.26 150.95,91.56 148.17,91.56 141.99,85.38 v2(141.59,85.38)
  BOTTOM w0.102: UC1.B42 145.48,72.61 145.48,72.61 145.48,74.41 145.93,74.87 145.93,76.88 142.31,80.5 142.31,83.07 141.42,83.96 141.42,85.01 141.59,85.17 v2(141.59,85.38)
CLK_PCIE_LAN#: length 137.4
  TOP w0.102: UL1.45 255.63,89.19 255.76,89.33 255.76,89.44 254.33,90.87 254.33,92.03 253.21,93.14 252.31,93.14 v2(252.22,93.05)
  IN2 w0.086: v2(142,84.97) 142,85.1 148.26,91.35 151.04,91.35 151.74,92.05 176.85,92.05 177.36,92.56 206.95,92.56 207.39,92.12 233.64,92.12 235.08,90.68 244.75,90.68 247.73,93.66 250.74,93.66 251.18,93.22 252.04,93.22 v2(252.22,93.05)
  BOTTOM w0.102: v2(142,84.97) 141.76,84.97 141.69,84.9 141.69,84.07 142.58,83.18 142.58,80.61 146.2,76.99 146.2,74.76 145.74,74.3 145.74,72.72 145.79,72.67 145.79,72.45 UC1.C41
CLK_PCIE_MMI: length 185.1
  TOP w0.102: UR1.3 281.24,32.31 281.18,32.36 280.72,32.36 279.44,33.64 276.69,33.64 v2(276.53,33.48)
  IN2 w0.086: v2(144.16,77.27) 143.88,76.99 143.78,76.99 143.68,77.1 143.68,77.4 144.07,77.79 146.48,77.79 147.23,78.54 157.27,78.54 157.83,79.1 160.59,79.1 161.23,79.74 168.3,79.74 168.73,80.17 173.03,80.17 173.88,81.02 175.28,81.02 175.91,80.39 184.25,80.39 191.45,73.19 191.45,69.86 193.83,67.48 193.83,65.3 194.13,65 194.13,64.05 195.04,63.14 195.04,46.61 195.9,45.75 195.9,45.12 200.34,40.68 216.06,40.68 216.44,41.05 227.17,41.05 230.52,37.7 230.52,36.53 232.07,34.98 232.53,34.98 233.09,34.42 235.98,34.42 237.35,33.05 241.08,33.05 241.82,33.8 249.92,33.8 251.36,32.35 253.12,32.35 253.91,31.57 263.65,31.57 263.96,31.88 265.86,31.88 267.83,33.84 276.16,33.84 v2(276.53,33.48)
  BOTTOM w0.076: UC1.C42 145.48,71.89 145.13,72.41 144.98,72.5 144.87,72.5 144.67,72.7 arc(144.62,72.8) 144.63,72.91 arc(144.67,73.02) 144.69,73.14 arc(144.67,73.31) 144.6,73.46 arc(144.56,73.58) 144.61,73.69 144.85,73.92 144.85,74.46 145.44,75.04 145.44,75.99 145.16,76.27 145.16,76.3
  BOTTOM w0.102: v2(144.16,77.27) 144.32,77.11 144.8,77.11 145.16,76.76 145.16,76.3
CLK_PCIE_MMI#: length 185.1
  TOP w0.102: v2(276.53,34.06) 276.63,33.96 276.74,33.96 276.79,33.91 279.55,33.91 280.83,32.63 281.23,32.63 281.31,32.71 UR1.2
  IN2 w0.086: v2(144.16,76.69) 144.07,76.78 143.7,76.78 143.47,77.01 143.47,77.48 143.98,78 146.39,78 147.14,78.74 157.19,78.74 157.75,79.3 160.5,79.3 161.15,79.95 168.21,79.95 168.64,80.38 172.94,80.38 173.79,81.23 175.36,81.23 176,80.59 184.34,80.59 191.66,73.28 191.66,69.95 194.04,67.57 194.04,65.38 194.34,65.08 194.34,64.13 195.25,63.23 195.25,46.7 196.11,45.83 196.11,45.21 200.43,40.89 215.97,40.89 216.35,41.26 227.25,41.26 230.73,37.79 230.73,36.61 232.15,35.19 232.61,35.19 233.18,34.63 236.07,34.63 237.43,33.26 240.99,33.26 241.74,34.01 250,34.01 251.45,32.56 253.21,32.56 254,31.77 263.56,31.77 263.87,32.09 265.78,32.09 267.74,34.05 276.52,34.05 v2(276.53,34.06)
  BOTTOM w0.076: 144.89,76.3 144.89,76.29 144.9,76.28 144.9,76.2 144.92,76.18 144.92,76.17 145.2,75.89 145.2,75.75 145.09,75.65 145.09,75.4 145.2,75.3 145.2,75.14 145.01,74.95 144.84,74.95 144.71,74.82 144.71,74.66 144.49,74.43 144.49,74.28 144.68,74.09 144.68,73.99 144.5,73.8 arc(144.4,73.59) 144.47,73.36 arc(144.51,73.26) 144.53,73.15 arc(144.51,73.06) 144.48,72.98 arc(144.45,72.77) 144.55,72.58 144.68,72.46 144.68,72.21 144.74,72.15 144.86,72.15 UC1.C43
  BOTTOM w0.102: 144.89,76.3 144.89,76.65 144.69,76.85 144.32,76.85 v2(144.16,76.69)
CLK_PCIE_WIGIG: length 151.9
  IN2 w0.086: v2(146.7,76.8) 146.81,76.9 146.81,77.42 147.38,78 157.41,78 158.04,78.62 162.19,78.62 162.84,79.27 168.5,79.27 168.94,79.7 173.22,79.7 174.07,80.55 175.08,80.55 175.8,79.83 183.04,79.83 190.84,72.03 190.84,69.81 192.99,67.66 192.99,66.61 193.23,66.37 193.23,65.19 193.67,64.75 193.67,63.85 194.57,62.95 194.57,62.05 194.57,62.05 194.57,46.42 195.44,45.55 195.44,44.93 200.15,40.21 216.25,40.21 216.63,40.59 226.97,40.59 227.47,40.09 227.47,39.81 v2(227.65,39.63)
  BOTTOM w0.102: UC1.B39 147.42,72.93 146.89,73.46 146.89,73.47 146.62,73.74 146.62,74.38 146.87,74.63 146.87,76.62 v2(146.7,76.8) ; v2(227.65,39.63) 227.44,39.42 227.44,36.44 221.92,30.92 221.92,21.81 222.91,20.81 223.89,20.81 225.41,19.29 228.83,19.29 232,16.12 232.3,16.12 232.53,16.35 JNGFF1.63
CLK_PCIE_WIGIG#: length 152.1
  IN2 w0.086: v2(147.29,76.8) 147.26,76.8 147.02,77.04 147.02,77.33 147.47,77.79 157.5,77.79 158.12,78.41 162.28,78.41 162.93,79.06 168.59,79.06 169.02,79.49 173.31,79.49 174.16,80.34 175,80.34 175.72,79.62 182.95,79.62 190.63,71.94 190.63,69.72 192.78,67.57 192.78,66.52 193.02,66.28 193.02,65.1 193.46,64.67 193.46,63.77 194.36,62.86 194.36,62.14 194.36,62.14 194.36,46.33 195.23,45.47 195.23,44.84 200.06,40 216.34,40 216.72,40.38 226.89,40.38 227.26,40.01 227.26,39.72 227.16,39.63 v2(226.97,39.63)
  BOTTOM w0.102: v2(226.97,39.63) 227.18,39.42 227.18,36.55 221.65,31.03 221.65,21.69 222.8,20.55 223.78,20.55 225.3,19.02 228.72,19.02 231.89,15.85 233.26,15.85 JNGFF1.65 ; UC1.A39 147.48,73.51 147.61,73.63 147.61,73.97 147.5,74.08 147.34,74.08 147.23,73.97 147.23,73.83 147.14,73.74 147,73.74 146.89,73.85 146.89,74.27 147.14,74.52 147.14,76.65 v2(147.29,76.8)
CLK_PCIE_WLAN: length 137.4
  IN2 w0.086: v2(230.05,36.81) 229.86,37 229.86,37.32 228.75,38.43 226.86,38.43 226.03,39.26 200.14,39.26 193.89,45.51 193.89,61.31 193.33,61.87 193.33,63.19 192.99,63.53 192.99,64.47 192.55,64.91 192.55,66.08 191.96,66.67 191.96,67.66 190.01,69.62 190.01,70.44 183.06,77.38 181.67,77.38 180.46,78.59 163.15,78.59 162.5,77.94 158.32,77.94 157.68,77.31 150.4,77.31 149.46,76.37 v2(147.97,76.37)
  BOTTOM w0.102: JNGFF1.39 232.55,22.35 232.31,22.12 230.29,22.12 228.04,24.37 228.04,27.12 228.5,27.58 228.5,33.54 229.65,34.7 229.65,36.5 229.96,36.81 v2(230.05,36.81) ; v2(147.97,76.37) 148.05,76.29 148.35,76.29 148.64,76 148.64,75.51 148.19,75.07 148.19,72.79 148.55,72.43 UC1.C37
CLK_PCIE_WLAN#: length 137.1
  IN2 w0.086: v2(229.38,36.81) 229.58,36.81 229.65,36.88 229.65,37.23 228.66,38.22 226.77,38.22 225.94,39.05 200.06,39.05 193.69,45.42 193.69,61.23 193.13,61.78 193.13,63.1 192.78,63.45 192.78,64.39 192.35,64.82 192.35,65.99 191.75,66.58 191.75,67.57 189.8,69.53 189.8,70.35 182.98,77.17 181.59,77.17 180.37,78.39 163.24,78.39 162.59,77.74 158.4,77.74 157.77,77.1 150.48,77.1 149.54,76.16 148.26,76.16 148.09,76 148.09,75.91 v2(147.97,75.79)
  BOTTOM w0.102: UC1.B38 147.8,72.53 147.72,72.61 147.72,72.91 147.92,73.11 147.92,75.18 148.37,75.62 148.37,75.89 148.24,76.02 148.14,76.02 147.97,75.85 v2(147.97,75.79) ; v2(229.38,36.81) 229.38,34.81 228.23,33.65 228.23,27.69 227.77,27.23 227.77,24.26 230.18,21.85 232.76,21.85 JNGFF1.41
CLK_TP_SIO: length 24
  TOP w0.102: JKBTP1.3 245.02,22.1 245.72,22.8 246.69,22.8 RZ19.2 246.49,23.24 246.49,23.85 CZ31.1 246.96,24.01 v2(246.96,23.53) ; v1(256.82,35.56) 257.25,35.99 v2(257.25,36.26) 257.19,36.32 UE2.A37
  IN1 w0.102: v2(257.25,36.26) 257.5,36 257.5,34.24 252.23,28.97 251.74,28.97 247.15,24.38 247.15,23.72 v2(246.96,23.53)
CLKRUN#: length 158
  TOP w0.076: 172.95,62.46 172.4,63.01 171.4,63.01 170.53,62.14 168.93,62.14 168.68,62.39 168.33,62.39 v2(167.8,62.92)
  TOP w0.102: RPC15.3 179.47,62.08 179.42,62.03 176.88,62.03 176.45,62.46 v1(175.16,62.46) 172.95,62.46 ; UE2.A32 253.17,38.4 v2(253.17,37.55)
  IN1 w0.102: v2(252.45,55.87) 252.42,55.84 248.91,55.84 248.54,56.21 244.64,56.21 244.19,55.77 239.89,55.77 233.97,61.68 233.97,62.73 233.54,63.16 233.54,72.63 231.38,74.79 217.48,74.79 215.71,73.02 197.05,73.02 191.17,78.9 191.17,79.62 189.56,81.24 189.56,81.6 187.12,84.04 179.98,84.04 179.3,83.36 176.24,83.36 172.88,80 172.88,75.95 172.21,75.28 172.21,71.38 173.03,70.56 173.03,69.55 173.62,68.97 173.62,67.25 171.59,65.21 171.18,65.21 169.33,63.36 168.24,63.36 v2(167.8,62.92)
  BOTTOM w0.076: v2(167.8,62.92) 168.15,63.27 UC1.V5
  BOTTOM w0.102: v2(252.45,55.87) 252.11,55.52 252.11,48.77 253.86,47.01 253.86,42.62 254.13,42.35 254.13,39.15 253.17,38.19 v2(253.17,37.55)
CONTACTLESS_DET#: length 74.4
  TOP w0.102: v4(232.09,67.49) 232.09,68.99 v2(232.5,69.39)
  IN1 w0.102: v2(232.5,69.39) 228.84,73.05 217.46,73.05 216.86,72.44 216.42,72.01 193.85,72.01 193.57,72.29 191.44,72.29 185.41,66.26 182.52,66.26 v2(182.13,65.86)
  IN2 w0.102: v2(167.79,64.81) 168.29,65.32 169.92,65.32 170.1,65.49 173.55,65.49 173.85,65.19 175.38,65.19 175.68,65.49 177.3,65.49 177.95,64.83 181.1,64.83 v2(182.13,65.86)
  BOTTOM w0.076: UC1.U6 167.5,64.52 v2(167.79,64.81)
  BOTTOM w0.102: v2(182.13,65.86) 182.11,65.88 RPC6.5
CORE_BOOT: length 1.3
  BOTTOM w0.102: v1(98.87,59.32) 98.61,59.07 PC504.2
CORE_BOOT_C: length 1.4
  BOTTOM w0.102: PC504.1 97.7,58.47 v1(96.94,59.23)
CORE_BOOT_R: length 3
  BOTTOM w0.102: PR517.2 98.46,57.07 97.79,56.4 v1(95.87,56.4)
CORE_SNUB: length 3.7
  BOTTOM w0.102: v1(105.48,47.35) 104.9,47.93 104.9,49.71 104.52,50.08 PR522.2
CORE_SW:
  vias: v1(105.7,54.85)
CORE_SW_CSP: length 3.9
  TOP w0.102: v2(110.79,50.66) 110.79,49.86 v1(110.8,49.85)
  TOP w0.254: PR512.1 110.55,50.9 v2(110.79,50.66)
  BOTTOM w0.254: PL500.3 110.47,50.34 v2(110.79,50.66)
CPPE#: length 3.7
  BOTTOM w0.076: 173.62,68.43 173.17,68.87 v1(172.93,68.87) 171.12,68.87 UC1.J1
  BOTTOM w0.102: RC160.2 173.62,68.43
CPU_DPB_AUX: length 130.3
  IN2 w0.086: v2(169.92,85.43) 170.06,85.57 170.06,85.9 170.27,86.1 218.14,86.1 219.13,85.11 229.57,85.11 230.84,83.84 234.54,83.84 238.62,79.76 239.56,79.76 245.26,74.06 255.44,74.06 256.59,72.91 273.35,72.91 276.05,70.2 276.05,69.48 v2(276.05,69.48)
  BOTTOM w0.076: UC1.B5 167.65,72.86 167.63,72.84 167.51,72.84 167.46,72.9 167.46,73.07 167.55,73.17 167.68,73.17 167.73,73.22 167.73,73.69 168.58,74.54 168.58,74.99 168.55,75.02 168.55,75.04
  BOTTOM w0.102: v2(276.05,69.48) 275.68,69.85 275.68,69.96 275.95,70.22 276.51,70.22 CV512.2 ; v2(169.92,85.43) 170.04,85.32 170.04,83.93 169.83,83.73 169.83,82.87 169.64,82.68 169.48,82.68 168.98,82.18 RPC20.2 168.98,81.7 169.05,81.64 169.17,81.64 169.26,81.55 169.26,81.37 168.55,80.66 168.55,75.04
CPU_DPB_AUX#: length 130.5
  IN2 w0.086: v2(275.47,69.48) 275.47,69.48 275.88,69.89 275.88,70.13 273.28,72.73 256.51,72.73 255.36,73.88 245.19,73.88 239.49,79.58 238.55,79.58 234.47,83.67 230.77,83.67 229.5,84.94 219.05,84.94 218.06,85.93 170.34,85.93 170.24,85.82 170.24,85.7 170.34,85.6 170.34,85.47 170.42,85.39 170.6,85.39 v2(170.64,85.43)
  BOTTOM w0.076: 168.77,74.98 168.77,74.96 168.74,74.94 168.74,74.47 167.9,73.62 167.9,73.06 167.94,73.01 167.94,72.38 UC1.C5
  BOTTOM w0.102: 168.77,74.98 168.77,80.57 169.48,81.28 RPC20.1 169.48,82.37 169.57,82.46 169.73,82.46 170.05,82.78 170.05,83.64 170.25,83.84 170.25,85.17 170.52,85.43 v2(170.64,85.43) ; CV513.2 276.51,70.44 275.86,70.44 275.47,70.05 v2(275.47,69.48)
CPU_DPB_CTRLCLK: length 157.7
  IN2 w0.102: v2(194.36,82.57) 194.36,82.71 194.55,82.91 197.7,82.91 198.47,83.68 213.45,83.68 220.45,76.68 230.86,76.68 231.67,77.49 240.05,77.49 244.59,72.95 254.86,72.95 256.02,71.78 271.52,71.78 275.38,67.92 280.97,67.92 283.29,70.24 283.73,70.24 283.93,70.03 v2(283.93,69.42)
  BOTTOM w0.076: UC1.B9 165.1,72.86 165.62,73.39 165.62,74.61 165.83,74.81 165.83,75.09 165.5,75.42 165.5,76.21 165.46,76.24 165.46,76.3
  BOTTOM w0.102: v2(283.93,69.42) 284.58,70.06 UV502.12 ; 165.46,76.3 165.46,78.59 164.89,79.17 164.89,79.99 164.7,80.19 RPC2.2 164.7,81 164.83,81.13 165.33,81.13 165.5,81.31 165.5,84.89 167.83,87.21 167.83,89.99 172.08,94.25 187.94,94.25 193.06,89.13 193.06,87.07 192.3,86.31 192.3,84.64 193.27,83.67 193.69,83.67 194.16,83.2 194.16,82.78 v2(194.36,82.57)
CPU_DPB_CTRLDAT: length 157.6
  IN2 w0.102: v2(283.94,71.28) 283.94,70.68 283.73,70.47 283.2,70.47 280.88,68.15 275.47,68.15 271.61,72.01 256.12,72.01 254.95,73.18 244.69,73.18 240.14,77.72 231.58,77.72 230.76,76.91 220.55,76.91 213.55,83.91 198.38,83.91 197.6,83.13 194.31,83.13 v2(193.77,82.6)
  BOTTOM w0.076: UC1.C9 165.43,72.96 165.79,73.32 165.79,74.54 165.99,74.74 165.99,75.16 165.66,75.49 165.66,76.21 165.69,76.24 165.69,76.3
  BOTTOM w0.102: UV502.9 284.67,72.01 v2(283.94,71.28) ; 165.69,76.3 165.69,78.69 165.12,79.26 165.12,79.93 165.2,80 RPC2.1 165.2,80.81 165.3,80.91 165.42,80.91 165.73,81.22 165.73,84.79 168.06,87.12 168.06,89.9 172.18,94.02 187.85,94.02 192.83,89.03 192.83,87.17 192.07,86.4 192.07,84.54 193.18,83.44 193.59,83.44 193.93,83.1 193.93,82.75 v2(193.77,82.6)
CPU_DPC_AUX: length 86.1
  IN2 w0.086: v2(168.95,85.42) 168.82,85.42 168.77,85.37 168.77,85.24 168.69,85.16 168.69,85.07 168.95,84.81 191.28,84.81 191.93,85.46 217.83,85.46 218.87,84.41 229.34,84.41 231.01,82.74 234.53,82.74 234.91,82.36 234.91,82.16 v2(235.11,81.95)
  BOTTOM w0.076: UC1.A6 166.93,73.51 166.87,73.57 166.87,73.9 166.93,73.97 167.3,73.97 167.39,74.06 167.39,74.12 167.27,74.24 167.27,74.31 167.36,74.39 167.36,74.81 167.38,74.83 167.38,74.85
  BOTTOM w0.102: 167.38,74.85 167.38,75.01 167.92,75.55 167.92,80.99 168.19,81.27 168.19,81.57 168.28,81.65 168.4,81.65 168.48,81.73 RPC20.3 168.48,82.34 168.22,82.6 167.78,82.6 167.46,82.92 167.46,84.21 167.88,84.63 168.68,84.63 168.95,84.9 v2(168.95,85.42) ; v2(235.11,81.95) 235.04,81.88 235.04,81.46 234.59,81.01 233.54,81.01 CV79.1
CPU_DPC_AUX#: length 85.9
  IN2 w0.086: v2(234.53,81.95) 234.6,81.95 234.73,82.08 234.73,82.29 234.46,82.56 230.94,82.56 229.26,84.24 218.8,84.24 217.75,85.29 192,85.29 191.35,84.63 168.87,84.63 168.51,84.99 168.51,85.28 v2(168.37,85.42)
  BOTTOM w0.076: UC1.B6 166.7,72.9 166.7,73.97 167.19,74.46 167.19,74.86 167.17,74.88 167.17,74.9
  BOTTOM w0.102: v2(168.37,85.42) 168.37,85.42 168.73,85.06 168.73,84.99 168.59,84.85 167.79,84.85 167.24,84.3 167.24,82.83 167.69,82.38 167.89,82.38 167.98,82.3 RPC20.4 167.98,81.35 167.7,81.08 167.7,75.64 167.17,75.1 167.17,74.9 ; CV80.1 234.05,81.23 234.5,81.23 234.82,81.55 234.82,81.66 v2(234.53,81.95)
CPU_DPC_AUX#_C: length 2.8
  BOTTOM w0.102: UV7.51 230.56,81.11 230.64,81.03 231.4,81.03 231.82,81.44 232.17,81.44 CV80.2
CPU_DPC_AUX_C: length 2.8
  BOTTOM w0.102: CV79.2 232.25,81.23 231.91,81.23 231.49,80.81 230.68,80.81 230.58,80.71 UV7.52
CPU_DPC_CTRLCLK: length 103.1
  IN2 w0.102: v2(231.62,81.93) 231.43,81.74 231.43,80.54 230.81,79.92 229.23,78.35 220.11,78.35 213.88,84.58 197.42,84.58 196.9,84.06 193.24,84.06 192.95,84.35 192.95,84.64 v2(192.74,84.85)
  BOTTOM w0.076: 164.99,76.3 164.99,75.9 164.82,75.73 164.82,74.57 165.04,74.35 165.04,73.25 164.75,72.96 164.75,72.73 165.1,72.38 165.1,72.22 165.59,71.72 UC1.D9
  BOTTOM w0.102: 164.99,76.3 164.99,78.37 164.04,79.32 164.04,79.97 164.2,80.12 RPC2.3 164.2,81.07 164.09,81.17 163.6,81.17 163.34,81.44 163.34,83.62 167.24,87.52 167.24,90.16 171.63,94.55 188.29,94.55 193.46,89.38 193.46,86.81 192.89,86.24 192.89,85 v2(192.74,84.85) ; UV7.50 231.2,81.51 v2(231.62,81.93)
CPU_DPC_CTRLDAT: length 101.9
  IN2 w0.102: v2(193.32,84.85) 193.18,84.71 193.18,84.44 193.34,84.29 196.8,84.29 197.32,84.81 213.97,84.81 220.21,78.57 229.14,78.57 231.2,80.64 231.2,81.74 v2(231.01,81.93)
  BOTTOM w0.076: 164.76,76.3 164.76,75.92 164.66,75.82 164.66,74.49 164.87,74.28 164.87,73.32 164.58,73.03 164.58,72.66 164.93,72.31 164.93,72.15 165.2,71.88 165.2,71.76 165.11,71.67 164.99,71.67 UC1.D11
  BOTTOM w0.102: UV7.49 230.99,81.91 v2(231.01,81.93) ; 164.76,76.3 164.76,78.28 163.81,79.22 163.81,80.06 163.7,80.17 RPC2.4 163.7,80.85 163.6,80.94 163.51,80.94 163.11,81.34 163.11,83.71 167.01,87.62 167.01,90.26 171.53,94.78 188.38,94.78 193.69,89.48 193.69,86.72 193.13,86.16 193.13,85.04 v2(193.32,84.85)
CPU_PWR_DEBUG#: length 97.4
  TOP w0.102: v2(124.52,82.06) 124.96,82.5 126.6,82.5 127,82.1 127,80.94 126.6,80.54 RC197.2 RC198.1 v1(127.45,78.98) 127.45,77.34 129.14,75.65 129.14,72.17 128.88,71.91 v2(128.76,71.91) ; JXDP1.45 v2(79.82,49.7)
  IN2 w0.102: v2(79.82,49.7) 78.83,50.69 78.83,55.09 80.34,56.6 86.8,56.6 87.95,55.46 91.41,55.46 92.17,56.22 92.17,57.41 92.54,57.78 92.54,59.93 94.47,61.86 94.47,73.86 100.23,79.62 103.48,79.62 107.06,83.2 123.38,83.2 v2(124.52,82.06)
  BOTTOM w0.076: UC1.H59 134.46,69.65 133.41,69.65 133.28,69.78 132.49,69.78 132.34,69.63 131.63,69.63 129.5,71.75 129.42,71.75
  BOTTOM w0.102: v2(128.76,71.91) 128.92,71.75 129.42,71.75
CPU_SEL: length 10.4
  TOP w0.102: v2(168.45,71.35) 168.45,71.3 168.81,70.94 169.2,70.94 170.16,71.91 v1(170.16,75.11) 170.16,77.35 RC163.2 RC306.1
  BOTTOM w0.076: UC1.E4 168.45,71.2 v2(168.45,71.35)
CPU_XDP_PRDY#: length 86.9
  TOP w0.102: JXDP1.5 79.33,59.7 79.48,59.84 80.32,59.84 82.33,61.85 87.17,61.85 88.99,60.04 88.99,57.43 89.65,56.77 94.09,56.77 v4(94.46,56.4) v2(95.07,55.79)
  IN2 w0.102: v2(125.69,78.64) 124.79,79.54 108.48,79.54 105.14,76.2 100.55,76.2 97.11,72.76 97.11,60.75 95.48,59.11 95.48,56.2 v2(95.07,55.79)
  BOTTOM w0.076: 129.42,70.15 129.63,70.15 131.5,68.28 132.51,68.28 UC1.J62
  BOTTOM w0.102: v2(125.69,78.64) 127.56,76.77 127.56,72.85 127.37,72.66 127.37,70.41 127.62,70.15 129.42,70.15
CPU_XDP_PREQ#: length 99.4
  TOP w0.102: JXDP1.3 80.3,60.2 82.28,62.18 v1(85.84,62.18) 87.17,62.18 89.21,60.13 89.21,57.51 89.7,57.02 94.49,57.02 v2(95.07,56.44)
  IN2 w0.102: v2(131.39,67.45) 130.81,68.03 130.81,69.67 129.19,71.28 129.19,72.08 v2(128.74,72.54) 128.74,73.51 127.24,75 127.24,76.8 126.1,77.94 126.1,78.82 125.17,79.74 107.25,79.74 103.91,76.4 100.47,76.4 96.91,72.84 96.91,60.84 95.27,59.2 95.27,56.64 v2(95.07,56.44)
  BOTTOM w0.076: UC1.K62 132.81,67.65 132.51,67.35 131.49,67.35 v2(131.39,67.45)
  BOTTOM w0.102: v2(128.74,72.54) 127.86,73.42 127.86,77.36 126.4,78.82 126.4,79.46 125.3,80.56 125.3,82.27 126.14,83.12 RC126.2
CPU_XDP_TCLK: length 103.1
  TOP w0.102: v2(76.58,44.88) 76.57,44.89 RC128.2 RC119.1 76.74,46.7 JXDP1.57 ; v2(91.93,59.62) v4(91.93,60.27)
  IN2 w0.102: v2(133.77,71.28) 133.77,71.67 129.5,75.94 129.5,77.74 128.73,78.5 128.73,79.54 126.95,81.33 126.95,82.45 125.5,83.9 106.34,83.9 102.47,80.03 100.08,80.03 94.07,74.02 94.07,62.06 91.93,59.92 v2(91.93,59.62) 91.32,59.02 91.32,57.23 91.76,56.79 91.76,56.39 91.24,55.86 88.12,55.86 86.97,57.01 80.14,57.01 78.32,55.19 78.32,50.61 76.12,48.41 76.12,45.34 v2(76.58,44.88)
  BOTTOM w0.076: UC1.E60 134.11,70.95 v2(133.77,71.28)
  BOTTOM w0.102: v2(91.93,59.62) 92.3,59.99 RC112.1
CPU_XDP_TDI: length 75.8
  TOP w0.102: v4(92.57,56.3) v2(91.1,56.3)
  IN2 w0.102: v2(91.1,56.3) 91.12,56.32 91.12,59.4 93.86,62.14 93.86,74.11 99.99,80.24 102.37,80.24 106.23,84.1 126.07,84.1 126.47,83.69 v2(127.09,83.69)
  BOTTOM w0.076: 129.63,72.26 129.63,72.19 131.74,70.07 UC1.F63
  BOTTOM w0.102: v2(127.09,83.69) 127.56,83.22 RC125.2 127.08,82.64 127.08,79.02 128.34,77.75 128.34,73.96 129.63,72.68 129.63,72.26 ; UC7.6 91.46,56.83 91.6,56.69 91.6,56.45 91.45,56.3 v2(91.1,56.3)
CPU_XDP_TDO: length 70
  TOP w0.102: v2(91.93,58.33) v4(92.57,58.33)
  IN2 w0.102: v2(125.7,82.04) 124.34,83.4 106.15,83.4 102.56,79.82 100.15,79.82 94.27,73.94 94.27,61.95 92.34,60.02 92.34,58.74 v2(91.93,58.33)
  BOTTOM w0.076: UC1.F62 132.55,70.07 132.27,69.79 131.74,69.79 129.42,72.12
  BOTTOM w0.102: v2(125.7,82.04) 125.7,80.94 126.6,80.04 RC127.2 126.83,79.81 126.83,78.92 128.09,77.67 128.09,73.78 129.18,72.68 129.18,72.35 129.42,72.12 ; UC7.3 v2(91.93,58.33)
CPU_XDP_TMS: length 78
  TOP w0.102: v2(88.91,56.27) 88.64,56.27 v4(88.39,56.51)
  IN2 w0.102: v2(88.91,56.27) 88.91,58.11 89.7,58.9 90.34,58.9 93.66,62.22 93.66,74.19 99.91,80.44 102.25,80.44 106.11,84.3 126.44,84.3 v2(126.64,84.1)
  BOTTOM w0.076: 131.65,71.97 131.85,71.97 131.95,71.87 132.41,71.87 132.5,71.78 132.93,71.78 133.18,71.53 133.18,71.13 UC1.E61
  BOTTOM w0.102: v2(126.64,84.1) 127.43,84.1 128.03,83.5 128.03,80.51 RC124.2 127.56,78.94 128.58,77.92 128.58,74.19 128.98,73.8 130.19,73.8 131.1,72.88 131.1,72.52 131.65,71.97 ; UC7.8 89.53,55.88 89.43,55.78 89.04,55.78 88.91,55.91 v2(88.91,56.27)
CPU_XDP_TRST#: length 78
  TOP w0.102: v2(87.63,57.92) 87.78,57.92 v4(88.12,58.26)
  IN2 w0.102: v2(134.42,71.28) 129.71,76 129.71,77.82 128.94,78.59 128.94,79.62 127.15,81.41 127.15,82.42 127.49,82.77 127.49,83.93 126.92,84.51 106,84.51 102.16,80.66 99.84,80.66 93.46,74.28 93.46,62.31 90.25,59.11 89.52,59.11 88.34,57.92 v2(87.63,57.92)
  BOTTOM w0.076: UC1.E59 134.76,70.95 v2(134.42,71.28)
  BOTTOM w0.203: UC7.11 87.72,57.83 v2(87.63,57.92) 86.93,57.92 RC109.1
  BOTTOM w0.254: RC109.1 RC129.2
CPUSB#: length 9.2
  TOP w0.076: v2(169.09,67.42) 169.09,67.67 170.25,68.83 v1(170.62,68.83) 170.74,68.95 172.9,68.95 173.42,68.43
  TOP w0.102: RPC4.6 175.71,68.42 175.63,68.35 173.49,68.35 173.42,68.43
  BOTTOM w0.076: UC1.K3 v2(169.09,67.42)
CS_1.35V: length 3.3
  TOP w0.102: v1(66.38,11.67) 66.38,11.25 PR201.2
  TOP w0.508: v2(64.97,10.52) 65.64,10.52 PR201.2
  BOTTOM w0.203: PU200.13 65.04,10.59 v2(64.97,10.52)
CSN1: length 22.3
  TOP w0.203: PU500.18 PC502.2
  TOP w0.254: PC502.2 PC513.2 110.32,65.3 v1(110.32,63.77) 110.32,61.59 109.74,61.01 109.74,54.11 PR515.2 PR514.2 111.06,51.08 v2(111.45,50.69)
  BOTTOM w0.254: PL500.2 111.8,50.34 v2(111.45,50.69)
CSP1: length 19.5
  TOP w0.203: PC502.1 108.18,65.63 PU500.17
  TOP w0.254: PC502.1 PC513.1 109.8,64.9 v1(109.8,62.04) 109.8,61.7 109.38,61.28 109.38,55.03 108.7,54.34 108.7,52.43 PH501.1 109.28,51.84 PR514.1 109.22,50.91 PR512.2
CSSN_1: length 16.8
  BOTTOM w0.254: PR701.2 68.51,87.22 68.82,87.53 71.09,87.53 73.89,90.32 73.89,92.11 74.39,92.62 v1(77.06,92.62) 77.7,92.62 78.04,92.27 78.04,90.51 PR703.2 77.77,89.34 PR705.2
CSSP_1: length 17.5
  BOTTOM w0.254: PR701.3 68.51,88.19 68.79,87.91 70.95,87.91 73.51,90.46 73.51,92.26 74.26,93.02 v1(74.91,93.02) 77.79,93.02 78.39,92.42 78.39,90.54 PR703.1 78.69,89.37 PR704.2
DAT_TP_SIO: length 28.4
  TOP w0.102: RZ18.2 248.01,23.24 248.01,23.86 247.71,24.16 CZ30.1 247.57,24.04 v2(247.57,23.53) ; JKBTP1.4 245.2,21.6 245.45,21.35 245.72,21.35 v2(245.72,21.35) ; UE2.B40 257.44,38.62 v2(257.99,39.17)
  IN1 w0.102: v2(247.57,23.53) 247.38,23.72 247.38,24.29 251.83,28.74 252.32,28.74 257.73,34.15 257.73,35.98 257.85,36.1 257.85,38.02 257.99,38.17 v2(257.99,39.17)
  BOTTOM w0.102: v2(245.72,21.35) 245.72,21.68 247.57,23.53 v2(247.57,23.53)
DC_TEST_A3_B3: length 0.7
  BOTTOM w0.076: UC1.A3 169.53,73.39 UC1.B3
DC_TEST_A4: length 7.2
  BOTTOM w0.102: UC1.A4 169.8,74.41 v1(169.8,78.94) 169.8,79.54 RC192.1
DC_TEST_A60: length 7.9
  BOTTOM w0.102: v1(130.49,79.01) 129.92,78.43 RC193.1 130.52,77.48 130.52,76.66 130.6,76.57 130.6,76.21 132.9,73.91 133.65,73.91 UC1.A60
DC_TEST_A61_B61: length 0.7
  BOTTOM w0.076: UC1.B61 133.4,72.92 UC1.A61
DC_TEST_A62: length 4.8
  BOTTOM w0.102: UC1.A62 130.36,75.89 130.36,76.44 129.92,76.89 RC193.2
DC_TEST_AV1: length 8.2
  BOTTOM w0.102: UC1.AV1 170.89,52.08 172.32,52.08 173.12,51.28 173.12,50.22 v1(174.18,49.16) 175.92,47.42 RC194.1
DC_TEST_AW1: length 6.7
  BOTTOM w0.102: UC1.AW1 171.58,51.47 172.79,50.25 172.79,49.94 v1(174.77,47.96) 175,47.73 RC194.2
DC_TEST_AW63: length 6.6
  BOTTOM w0.076: v1(129.42,45.97) 129.65,46.21 RC195.1
  BOTTOM w0.102: RC195.1 129.65,47.27 132.16,49.77 UC1.AW63
DC_TEST_AY2_AW2: length 0.7
  BOTTOM w0.076: UC1.AW2 170.12,51 UC1.AY2
DC_TEST_AY3_AW3: length 0.7
  BOTTOM w0.076: UC1.AW3 169.52,51.49 UC1.AY3
DC_TEST_AY60: length 6.6
  BOTTOM w0.076: v1(130.82,45.88) 130.57,46.14 RC195.2
  BOTTOM w0.102: RC195.2 130.57,47.57 133.87,50.88 UC1.AY60
DC_TEST_AY61_AW61: length 0.7
  BOTTOM w0.076: UC1.AY61 133.37,51.45 UC1.AW61
DC_TEST_AY62_AW62: length 0.7
  BOTTOM w0.076: UC1.AY62 132.72,51.44 UC1.AW62
DC_TEST_B62_B63: length 0.7
  BOTTOM w0.102: UC1.B62 132.29,72.78 UC1.B63
DC_TEST_C1_C2: length 0.7
  BOTTOM w0.076: UC1.C2 170.66,72.25 UC1.C1
DDI1_LANE_N0: length 175.5
  TOP w0.102: v2(282.08,73.65) 281.9,73.65 281.72,73.82 281.72,74.73 282.81,75.82 285.89,75.82 286.27,76.21 287.49,76.21 287.77,75.93 CV508.2
  IN2 w0.086: v2(282.08,73.65) 281.85,73.42 281.85,73.25 281.59,72.99 278.7,72.99 278.51,73.18 278.51,73.7 278.43,73.79 278.11,73.79 278.02,73.7 278.02,73.18 277.83,72.99 274.45,72.99 273.61,73.84 256.45,73.84 255.77,74.52 247.04,74.52 241.04,80.52 241.04,81.06 239.44,82.66 239.02,82.66 235.2,86.48 232.15,86.48 231.01,87.62 219.56,87.62 218.98,88.19 203.36,88.19 202.75,88.81 156.85,88.81 156.77,88.72 156.77,88.03 156.58,87.85 156.11,87.85 155.92,88.03 155.92,88.72 155.84,88.81 155.52,88.81 155.43,88.72 155.43,88.03 155.24,87.85 154.78,87.85 154.59,88.03 154.59,88.72 154.5,88.81 153.52,88.81 152.78,88.08 151.28,88.08 149.03,85.82 146.65,85.82 139.33,78.5 139.33,78.03 138.99,77.69 138.72,77.69 v2(138.5,77.48)
  BOTTOM w0.076: v2(138.5,77.48) 138.5,77.48 137.94,77.48 137.77,77.3 137.77,76.67 137.28,76.19 137.28,74.65 137.02,74.38 137.02,73.7 arc(137.04,73.55) 137.11,73.42 arc(137.15,73.35) 137.17,73.27 arc(137.16,73.1) 137.11,72.93 arc(137.09,72.82) 137.13,72.72 arc(137.14,72.7) 137.16,72.68 137.34,72.5 137.5,72.5 137.61,72.42 137.95,71.93 UC1.C54
DDI1_LANE_N1: length 175.1
  TOP w0.102: CV506.2 287.72,74.02 287.47,74.26 287.28,74.26 287.06,74.48 287.06,75.22 286.93,75.35 286.68,75.35 286.55,75.22 286.55,74.22 286.3,73.96 285.86,73.96 285.61,74.22 285.61,74.83 285.51,74.93 285.2,74.93 285.1,74.83 285.1,74.48 284.87,74.26 283.7,74.26 283.44,74.52 283.44,74.66 v2(283.15,74.94)
  IN2 w0.086: v2(141.26,82.6) 141.26,83.17 141.42,83.32 142.34,83.32 146.12,87.11 148.45,87.11 150.71,89.36 151.95,89.36 152.7,90.11 203.28,90.11 203.91,89.48 231.19,89.48 232.9,87.76 235.34,87.76 235.73,87.76 239.55,83.95 239.98,83.95 242.33,81.6 242.33,81.05 247.57,75.81 256.45,75.81 256.91,75.36 283.44,75.36 283.55,75.24 283.55,74.87 283.45,74.76 283.31,74.76 283.15,74.92 v2(283.15,74.94)
  BOTTOM w0.076: UC1.B58 135.45,72.45 135.53,72.37 135.67,72.37 135.72,72.42 135.72,72.99 135.61,73.1 135.61,73.27 135.72,73.38 135.72,76.94 136.78,77.99 137.36,77.99 137.42,78.05
  BOTTOM w0.102: v2(141.26,82.6) 140.8,82.6 139.67,81.47 139.67,80.3 137.42,78.05
DDI1_LANE_N2: length 173.1
  TOP w0.102: v2(283.17,73.27) 283.36,73.08 283.36,72.8 283.79,72.37 287.63,72.37 CV504.2
  IN2 w0.086: v2(283.17,73.27) 283.17,73.26 283.29,73.14 283.46,73.14 283.58,73.26 283.58,73.43 283.63,73.47 283.63,73.55 283.03,74.14 281.96,74.14 281.63,74.48 256.87,74.48 256.19,75.17 247.31,75.17 241.68,80.79 241.68,81.33 239.71,83.3 239.28,83.3 235.46,87.12 232.41,87.12 231.28,88.26 230.36,88.26 230.17,88.45 230.17,88.71 230.05,88.84 229.81,88.84 229.68,88.71 229.68,88.45 229.49,88.26 229.03,88.26 228.84,88.45 228.84,88.71 228.71,88.84 228.47,88.84 228.34,88.71 228.34,88.45 228.16,88.26 227.69,88.26 227.5,88.45 227.5,88.71 227.37,88.84 227.14,88.84 227.01,88.71 227.01,88.45 226.82,88.26 226.35,88.26 226.17,88.45 226.17,88.71 226.04,88.84 225.8,88.84 225.67,88.71 225.67,88.45 225.48,88.26 225.02,88.26 224.83,88.45 224.83,88.71 224.7,88.84 224.46,88.84 224.34,88.71 224.34,88.45 224.15,88.26 219.86,88.26 219.63,88.49 219.63,88.73 219.53,88.84 203.64,88.84 203.02,89.46 153.03,89.46 152.29,88.72 150.99,88.72 148.73,86.46 146.39,86.46 141.96,82.04 141.72,82.04 141.08,81.41 v2(141.08,81.17)
  BOTTOM w0.076: 139.34,77.75 139.34,77.74 139.33,77.72 139.33,77.54 137.87,76.08 137.87,73.21 137.71,73.05 137.63,73.05 137.44,72.86 UC1.B55
  BOTTOM w0.102: v2(141.08,81.17) 140.89,81.17 140.51,80.8 140.51,79.84 139.34,78.68 139.34,77.75
DDI1_LANE_N3: length 173.4
  IN2 w0.076: v2(137.18,77.52) 137.75,77.52 ; 137.85,77.62 137.85,78.09
  IN2 w0.086: 137.85,78.09 137.85,78.32 139.66,80.13 139.66,82.75 141.32,84.4 142.2,84.4 146.22,88.43 148.58,88.43 150.34,90.18 151.5,90.18 152.25,90.93 203.63,90.93 204.26,90.3 232.6,90.3 234.27,88.63 236.02,88.63 239.89,84.76 240.36,84.76 243.14,81.98 243.14,81.39 247.91,76.63 256.79,76.63 256.95,76.47 257.25,76.17 283.77,76.17 284.64,75.31 284.64,73.99 v2(284.83,73.81) ; 137.75,77.52 137.85,77.62
  BOTTOM w0.076: v2(137.18,77.52) 136.92,77.25 136.66,77.25 136.33,76.93 136.33,73.55 136.16,73.38 136.1,73.38 136.01,73.47 UC1.A57
  BOTTOM w0.102: CV502.2 286.42,74.36 286.34,74.43 285.62,74.43 285.39,74.66 285.39,75.55 285.26,75.68 284.72,75.68 284.59,75.55 284.59,74.04 v2(284.83,73.81)
DDI1_LANE_P0: length 175.4
  TOP w0.102: v2(281.35,73.65) 281.51,73.8 281.51,74.82 282.72,76.03 285.8,76.03 286.18,76.42 287.51,76.42 CV507.2
  IN2 w0.076: 138.7,77.86 138.92,77.86
  IN2 w0.086: v2(138.5,78.06) 138.7,77.86 ; v2(281.35,73.65) 281.4,73.7 281.57,73.7 281.67,73.6 281.67,73.32 281.52,73.16 278.78,73.16 278.69,73.25 278.69,73.78 278.5,73.96 278.04,73.96 277.85,73.78 277.85,73.25 277.76,73.16 274.53,73.16 273.68,74.01 256.52,74.01 255.84,74.7 247.11,74.7 241.22,80.59 241.22,81.14 239.52,82.84 239.09,82.84 235.27,86.65 232.22,86.65 231.08,87.79 219.63,87.79 219.05,88.37 203.44,88.37 202.82,88.99 156.78,88.99 156.59,88.8 156.59,88.11 156.51,88.02 156.19,88.02 156.1,88.11 156.1,88.8 155.91,88.99 155.45,88.99 155.26,88.8 155.26,88.11 155.17,88.02 154.85,88.02 154.76,88.11 154.76,88.8 154.57,88.99 153.44,88.99 152.71,88.25 151.21,88.25 148.95,86 146.58,86 139.15,78.57 139.15,78.1 138.92,77.86
  BOTTOM w0.076: UC1.C55 136.99,72.61 136.99,72.62 arc(136.93,72.81) 136.96,73 arc(137,73.13) 137.01,73.26 arc(137,73.29) 136.99,73.31 arc(136.88,73.49) 136.85,73.7 136.85,74.49 137.09,74.73 137.09,76.27 137.44,76.61 137.58,76.75 137.58,77.38 137.89,77.7 138.14,77.7 v2(138.5,78.06)
DDI1_LANE_P1: length 175.1
  TOP w0.102: v2(283.95,74.94) 283.9,74.94 283.65,74.7 283.65,74.61 283.79,74.47 284.78,74.47 284.88,74.57 284.88,74.92 285.11,75.15 285.6,75.15 285.82,74.92 285.82,74.31 285.95,74.18 286.21,74.18 286.33,74.31 286.33,75.31 286.59,75.56 287.02,75.56 287.27,75.31 287.27,74.57 287.37,74.47 287.68,74.47 287.77,74.56 CV505.2
  IN2 w0.086: v2(140.85,83.01) 140.86,83.01 141.35,83.5 142.26,83.5 146.05,87.28 148.38,87.28 150.63,89.54 151.88,89.54 152.62,90.28 203.35,90.28 203.98,89.65 231.26,89.65 232.97,87.94 235.27,87.94 235.8,87.94 239.62,84.12 240.05,84.12 242.5,81.67 242.5,81.13 247.64,75.98 256.53,75.98 256.98,75.53 283.51,75.53 283.73,75.31 283.73,75.17 v2(283.95,74.94)
  BOTTOM w0.076: 136.61,78.09 135.53,77.02 135.53,73.46 135.42,73.34 135.42,72.9 135.16,72.64 135.16,72.16 UC1.C58
  BOTTOM w0.102: v2(140.85,83.01) 140.85,82.95 140.71,82.81 140.1,82.21 139.46,81.56 139.46,80.39 137.25,78.18 136.7,78.18 136.61,78.09
DDI1_LANE_P2: length 173.2
  TOP w0.102: CV503.2 287.23,72.59 283.88,72.59 283.58,72.89 283.58,73.05 283.79,73.27 v2(283.98,73.27)
  IN2 w0.086: v2(140.67,81.59) 141.01,81.59 141.64,82.22 141.89,82.22 146.31,86.64 148.66,86.64 150.91,88.89 152.22,88.89 152.96,89.63 203.09,89.63 203.71,89.01 219.6,89.01 219.81,88.81 219.81,88.57 219.94,88.43 224.08,88.43 224.16,88.52 224.16,88.78 224.39,89.01 224.78,89.01 225,88.78 225,88.52 225.09,88.43 225.41,88.43 225.5,88.52 225.5,88.78 225.73,89.01 226.11,89.01 226.34,88.78 226.34,88.52 226.43,88.43 226.75,88.43 226.83,88.52 226.83,88.78 227.06,89.01 227.45,89.01 227.68,88.78 227.68,88.52 227.76,88.43 228.08,88.43 228.17,88.52 228.17,88.78 228.4,89.01 228.78,89.01 229.01,88.78 229.01,88.52 229.1,88.43 229.42,88.43 229.51,88.52 229.51,88.78 229.74,89.01 230.12,89.01 230.35,88.78 230.35,88.52 230.44,88.43 231.35,88.43 232.49,87.3 235.54,87.3 239.36,83.48 239.78,83.48 241.86,81.4 241.86,80.86 247.38,75.34 256.26,75.34 256.95,74.66 281.7,74.66 282.03,74.32 283.11,74.32 283.8,73.62 283.8,73.45 v2(283.98,73.27)
  BOTTOM w0.076: 139.13,77.75 139.13,77.74 139.14,77.72 139.14,77.62 137.68,76.16 137.68,73.29 137.63,73.24 137.41,73.24 137.34,73.32 137.34,73.46 UC1.A55
  BOTTOM w0.102: v2(140.67,81.59) 140.67,81.26 140.29,80.89 140.29,79.93 139.63,79.27 139.13,78.76 139.13,77.75
DDI1_LANE_P3: length 173.4
  IN2 w0.076: 138.02,78.09 138.02,77.55 137.82,77.34
  IN2 w0.086: 137.82,77.34 137.59,77.34 v2(137.18,76.93) ; 138.02,78.09 138.02,78.24 139.84,80.06 139.84,82.68 141.39,84.23 142.27,84.23 146.3,88.25 148.66,88.25 150.41,90 151.57,90 152.32,90.75 203.56,90.75 204.19,90.12 232.53,90.12 234.2,88.45 235.95,88.45 239.82,84.59 240.29,84.59 242.97,81.91 242.97,81.32 247.84,76.45 256.72,76.45 256.77,76.4 257.17,76 283.7,76 284.47,75.23 284.47,74.03 v2(284.24,73.81)
  BOTTOM w0.076: v2(137.18,76.93) 137.05,77.06 136.74,77.06 136.52,76.85 136.52,73.47 136.01,72.96 UC1.B57
  BOTTOM w0.102: CV501.2 286.42,74.9 286.17,74.65 285.71,74.65 285.61,74.75 285.61,75.64 285.35,75.89 284.63,75.89 284.38,75.64 284.38,74.13 284.38,74.13 284.38,73.94 v2(284.24,73.81)
DDI2_LANE_N0: length 105.7
  IN2 w0.086: v2(141.31,78.77) 141.31,78.77 141.31,79.36 142.01,80.06 142.28,80.06 147.21,84.99 157.37,84.99 158.88,83.49 170.34,83.49 170.76,83.91 171.72,83.91 172,83.63 190.3,83.63 192.54,81.4 212.58,81.4 219.31,74.66 227.89,74.66 228.48,74.06 228.48,73.9 228.09,73.5 v2(228.08,73.5)
  BOTTOM w0.076: 140.46,74.64 139.92,74.1 139.92,74.02 139.67,73.77 arc(139.62,73.69) 139.59,73.6 arc(139.6,73.46) 139.64,73.34 arc(139.67,73.28) 139.68,73.21 arc(139.68,73.11) 139.65,73.01 arc(139.61,72.85) 139.67,72.7 arc(139.69,72.67) 139.71,72.65 139.84,72.53 140.07,72.53 140.35,72.25 140.35,72.16 140.22,72.03 139.89,72.03 139.84,72.08 139.84,72.15 UC1.C51
  BOTTOM w0.102: 140.46,74.64 140.46,76.85 140.89,77.28 140.89,78.69 140.99,78.79 141.3,78.79 141.31,78.78 v2(141.31,78.77) ; CV72.1 228.29,74.21 228.29,73.72 v2(228.08,73.5)
DDI2_LANE_N0_C: length 3.7
  BOTTOM w0.102: UV7.4 228.02,77.69 228.09,77.61 228.09,76.97 228.42,76.64 228.7,76.64 228.81,76.53 228.81,76.33 228.69,76.2 228.48,76.2 228.29,76.01 228.29,75.81 CV72.2
DDI2_LANE_N1: length 105.6
  IN2 w0.086: v2(140.24,77.51) 140.24,77.85 140.36,77.98 141.44,77.98 144.55,81.09 157.37,81.09 158.16,81.88 159.23,81.88 160.13,82.78 171.97,82.78 172.18,82.98 189.91,82.98 192.17,80.72 203.25,80.72 203.33,80.64 203.33,79.96 203.52,79.77 204.09,79.77 204.28,79.96 204.28,80.64 204.36,80.72 204.79,80.72 204.87,80.64 204.87,79.96 205.06,79.77 205.63,79.77 205.82,79.96 205.82,80.64 205.9,80.72 206.32,80.72 206.41,80.64 206.41,79.96 206.6,79.77 207.17,79.77 207.36,79.96 207.36,80.39 207.48,80.52 207.82,80.52 207.95,80.39 207.95,79.96 208.14,79.77 213.24,79.77 218.99,74.02 226.53,74.02 226.61,73.94 226.61,73.81 v2(226.3,73.5)
  BOTTOM w0.076: v2(140.24,77.51) 140.13,77.51 139.77,77.15 139.53,77.15 138.76,76.38 138.22,75.84 138.22,73.86 138.23,73.85 138.23,72.65 138.52,72.36 UC1.C53
  BOTTOM w0.102: v2(226.3,73.5) 226.57,73.77 226.57,74.16 CV74.1
DDI2_LANE_N1_C: length 3.7
  BOTTOM w0.102: UV7.7 226.82,77.68 226.91,77.59 226.91,77.04 v3(227.11,76.83) 227.29,76.66 227.29,76.44 227.16,76.31 226.72,76.31 226.5,76.1 226.5,75.8 CV74.2
DDI2_LANE_N2: length 105.9
  IN2 w0.086: v2(142.95,76.09) 142.12,76.09 141.87,76.34 141.87,76.82 144.09,79.04 144.77,79.04 144.96,79.23 144.96,79.73 145.19,79.96 145.79,79.96 145.98,79.77 145.98,79.13 146.11,79.01 146.35,79.01 146.47,79.13 146.47,79.77 146.66,79.96 147.13,79.96 147.32,79.77 147.32,79.51 147.44,79.39 147.68,79.39 147.81,79.51 147.81,79.77 148,79.96 148.46,79.96 148.65,79.77 148.65,79.5 148.74,79.41 149.06,79.41 149.15,79.5 149.15,79.77 149.33,79.96 149.8,79.96 149.99,79.77 149.99,79.5 150.08,79.41 150.4,79.41 150.48,79.5 150.48,79.77 150.67,79.96 154.43,79.96 154.66,79.73 154.66,79.53 154.79,79.4 155.13,79.4 155.25,79.53 155.25,79.74 155.47,79.96 160.2,79.96 160.83,80.59 167.44,80.59 167.56,80.72 167.56,81.39 167.79,81.62 168.2,81.62 168.43,81.39 168.43,81.15 168.56,81.02 168.79,81.02 168.92,81.15 168.92,81.4 169.15,81.63 169.54,81.63 169.76,81.4 169.76,81.11 169.85,81.02 171.11,81.02 171.21,81.12 171.21,81.43 171.44,81.66 171.94,81.66 172.17,81.43 172.17,81.15 172.3,81.03 172.68,81.03 172.81,81.15 172.81,81.62 173.06,81.87 175.63,81.87 176.24,81.26 189.66,81.26 192.3,78.62 212.79,78.62 219.04,72.38 224.04,72.38 224.52,72.85 v2(224.52,73.53)
  BOTTOM w0.076: v2(142.95,76.09) 142.92,76.12 142.92,76.14 142.79,76.26 142.3,76.26 142.11,76.07 142.11,76.05 142.03,75.97 142.01,75.97 141.27,75.23 141.27,74.32 140.71,73.76 140.71,72.68 141.03,72.36 UC1.C49
  BOTTOM w0.102: v2(224.52,73.53) 224.75,73.76 224.75,74.2 CV76.1
DDI2_LANE_N2_C: length 3.7
  BOTTOM w0.102: UV7.10 225.62,77.66 225.71,77.57 225.71,76.8 225.61,76.71 225.04,76.71 224.75,76.42 224.75,75.83 CV76.2
DDI2_LANE_N3: length 105.6
  IN2 w0.086: v2(222.76,73.54) 222.82,73.54 222.97,73.39 222.97,73.21 222.83,73.08 219.25,73.08 213.06,79.27 202.7,79.27 202.6,79.37 202.6,79.75 202.37,79.98 201.83,79.98 201.61,79.75 201.61,79.41 201.52,79.32 201.2,79.32 201.11,79.41 201.11,79.73 200.88,79.96 200.5,79.96 200.27,79.73 200.27,79.41 200.18,79.32 199.86,79.32 199.78,79.41 199.78,80.04 199.59,80.23 199.12,80.23 198.93,80.04 198.93,79.41 198.85,79.32 198.53,79.32 198.44,79.41 198.44,80.04 198.25,80.23 197.79,80.23 197.6,80.04 197.6,79.41 197.51,79.32 197.19,79.32 197.1,79.41 197.1,80.04 196.92,80.23 196.45,80.23 196.26,80.04 196.26,79.41 196.17,79.32 195.85,79.32 195.77,79.41 195.77,80.04 195.58,80.23 195.11,80.23 194.92,80.04 194.92,79.41 194.84,79.32 194.52,79.32 194.43,79.41 194.43,80.04 194.24,80.23 193.78,80.23 193.59,80.04 193.59,79.41 193.5,79.32 193.18,79.32 193.1,79.41 193.1,80.04 192.91,80.23 191.89,80.23 189.6,82.51 172.39,82.51 172.18,82.31 165.86,82.31 164.78,81.23 160.41,81.23 159.77,80.6 144.73,80.6 141.08,76.95 139.7,76.95 139.38,76.63 139.38,76.33 v2(139.2,76.15)
  BOTTOM w0.076: v2(139.2,76.15) 139.27,76.15 139.59,75.82 139.59,75.29 138.79,74.49 138.79,73.51 138.63,73.35 138.53,73.35 138.49,73.39 138.49,73.48 UC1.A53
  BOTTOM w0.102: CV78.1 223,74.17 223,73.78 v2(222.76,73.54)
DDI2_LANE_N3_C: length 3.7
  BOTTOM w0.102: CV78.2 222.96,75.81 222.96,76.05 v3(223.39,76.48) 223.69,76.78 223.92,76.78 224.51,77.37 224.51,77.62 224.42,77.71 UV7.13
DDI2_LANE_P0: length 105.8
  IN2 w0.086: v2(140.9,79.19) 140.9,79.19 141.94,80.24 142.2,80.24 147.14,85.17 157.45,85.17 158.95,83.66 170.27,83.66 170.69,84.08 171.79,84.08 172.07,83.81 190.38,83.81 192.61,81.57 212.65,81.57 219.39,74.84 227.96,74.84 228.66,74.14 v2(228.66,73.5)
  BOTTOM w0.076: UC1.C50 139.8,71.88 139.58,72.1 139.58,72.37 139.59,72.38 139.59,72.54 139.53,72.6 arc(139.45,72.84) 139.5,73.09 arc(139.52,73.14) 139.52,73.19 arc(139.51,73.23) 139.5,73.26 arc(139.44,73.43) 139.43,73.61 arc(139.47,73.76) 139.55,73.88 139.75,74.08 139.75,74.2 140.22,74.66 140.22,74.74 140.24,74.76
  BOTTOM w0.102: CV71.1 228.51,74.23 228.51,73.64 228.52,73.64 v2(228.66,73.5) ; 140.24,74.76 140.24,76.94 140.68,77.37 140.68,78.78 140.89,78.99 140.89,79.02 140.89,79.02 140.9,79.03 v2(140.9,79.19)
DDI2_LANE_P0_C: length 3.7
  BOTTOM w0.102: CV71.2 228.51,75.8 228.51,75.92 228.57,75.98 228.78,75.98 229.03,76.24 229.03,76.62 228.79,76.86 228.51,76.86 228.31,77.06 228.31,77.54 228.42,77.65 UV7.3
DDI2_LANE_P1: length 105.7
  IN2 w0.086: v2(226.88,73.5) 226.78,73.6 226.78,74.02 226.6,74.2 219.06,74.2 213.32,79.94 208.21,79.94 208.13,80.03 208.13,80.46 207.9,80.69 207.41,80.69 207.18,80.46 207.18,80.03 207.09,79.94 206.67,79.94 206.59,80.03 206.59,80.71 206.4,80.9 205.83,80.9 205.64,80.71 205.64,80.03 205.56,79.94 205.13,79.94 205.05,80.03 205.05,80.71 204.86,80.9 204.29,80.9 204.1,80.71 204.1,80.03 204.02,79.94 203.59,79.94 203.51,80.03 203.51,80.71 203.32,80.9 192.24,80.9 189.99,83.16 172.11,83.16 171.9,82.95 160.06,82.95 159.16,82.05 158.09,82.05 157.3,81.26 144.48,81.26 141.36,78.15 140.29,78.15 140.06,77.92 v2(139.83,77.92)
  BOTTOM w0.076: UC1.B54 138.04,72.62 138.04,73.77 138.03,73.78 138.03,75.92 138.5,76.38 139.45,77.34 139.69,77.34 139.83,77.48 v2(139.83,77.92)
  BOTTOM w0.102: CV73.1 226.78,74.28 226.78,73.6 v2(226.88,73.5)
DDI2_LANE_P1_C: length 3.7
  BOTTOM w0.102: CV73.2 226.72,75.81 226.72,76.01 226.81,76.1 227.25,76.1 227.51,76.35 227.51,76.77 227.12,77.15 227.12,77.58 227.22,77.67 UV7.6
DDI2_LANE_P2: length 105.9
  IN2 w0.086: v2(225.1,73.53) 225.09,73.53 224.69,73.13 224.69,72.78 224.12,72.2 218.97,72.2 212.72,78.45 192.23,78.45 189.59,81.09 176.16,81.09 175.56,81.7 173.13,81.7 172.98,81.55 172.98,81.08 172.75,80.85 172.23,80.85 172,81.08 172,81.36 171.87,81.48 171.51,81.48 171.38,81.36 171.38,81.05 171.18,80.85 169.78,80.85 169.59,81.03 169.59,81.33 169.46,81.46 169.22,81.46 169.1,81.33 169.1,81.07 168.87,80.85 168.48,80.85 168.25,81.07 168.25,81.32 168.13,81.44 167.87,81.44 167.74,81.32 167.74,80.64 167.51,80.41 160.9,80.41 160.27,79.78 155.54,79.78 155.43,79.67 155.43,79.45 155.2,79.22 154.71,79.22 154.48,79.45 154.48,79.66 154.36,79.78 150.74,79.78 150.66,79.69 150.66,79.42 150.47,79.23 150,79.23 149.81,79.42 149.81,79.69 149.73,79.78 149.41,79.78 149.32,79.69 149.32,79.42 149.13,79.23 148.67,79.23 148.48,79.42 148.48,79.69 148.39,79.78 148.07,79.78 147.99,79.69 147.99,79.44 147.76,79.21 147.37,79.21 147.14,79.44 147.14,79.69 147.06,79.78 146.74,79.78 146.65,79.69 146.65,79.06 146.42,78.83 146.04,78.83 145.81,79.06 145.81,79.69 145.72,79.78 145.26,79.78 145.13,79.65 145.13,79.16 144.84,78.87 144.16,78.87 142.05,76.75 142.05,76.42 142.2,76.27 142.6,76.27 142.95,76.62 v2(142.95,76.68)
  BOTTOM w0.076: 142.03,76.3 141.89,76.16 141.89,76.14 141.86,76.11 141.86,76.09 141.08,75.31 141.08,74.4 140.52,73.84 140.52,73.06 140.41,72.95 140.41,72.78 140.52,72.67 140.52,72.59 UC1.B50
  BOTTOM w0.102: CV75.1 224.97,74.24 224.97,73.67 v2(225.1,73.53) ; v2(142.95,76.68) 142.75,76.48 142.21,76.48 142.03,76.3
DDI2_LANE_P2_C: length 3.7
  BOTTOM w0.102: UV7.9 226.02,77.66 225.92,77.57 225.92,76.71 225.69,76.48 v3(225.37,76.48) 225.12,76.48 224.97,76.33 224.97,75.79 CV75.2
DDI2_LANE_P3: length 105.7
  IN2 w0.086: v2(223.35,73.54) 223.15,73.34 223.15,73.14 222.9,72.9 219.18,72.9 212.99,79.09 202.63,79.09 202.43,79.3 202.43,79.68 202.3,79.81 201.91,79.81 201.78,79.68 201.78,79.33 201.59,79.15 201.13,79.15 200.94,79.33 200.94,79.65 200.81,79.78 200.57,79.78 200.44,79.65 200.44,79.33 200.26,79.15 199.79,79.15 199.6,79.33 199.6,79.96 199.51,80.05 199.19,80.05 199.11,79.96 199.11,79.33 198.92,79.15 198.45,79.15 198.27,79.33 198.27,79.96 198.18,80.05 197.86,80.05 197.77,79.96 197.77,79.33 197.58,79.15 197.12,79.15 196.93,79.33 196.93,79.96 196.84,80.05 196.52,80.05 196.44,79.96 196.44,79.33 196.25,79.15 195.78,79.15 195.59,79.33 195.59,79.96 195.51,80.05 195.19,80.05 195.1,79.96 195.1,79.33 194.91,79.15 194.45,79.15 194.26,79.33 194.26,79.96 194.17,80.05 193.85,80.05 193.76,79.96 193.76,79.33 193.58,79.15 193.11,79.15 192.92,79.33 192.92,79.96 192.83,80.05 191.81,80.05 189.53,82.34 172.46,82.34 172.26,82.14 165.93,82.14 164.85,81.06 160.48,81.06 159.85,80.42 144.8,80.42 141.15,76.77 139.78,76.77 139.56,76.55 139.56,76.37 v2(139.78,76.15)
  BOTTOM w0.076: UC1.B53 138.52,72.9 138.74,73.13 138.74,73.2 138.98,73.43 138.98,74.41 139.78,75.21 v2(139.78,76.15)
  BOTTOM w0.102: v2(223.35,73.54) 223.21,73.67 223.21,74.27 CV77.1
DDI2_LANE_P3_C: length 3.7
  BOTTOM w0.102: UV7.12 224.82,77.71 224.72,77.62 224.72,77.28 224.01,76.57 223.8,76.57 223.36,76.12 223.34,76.12 223.17,75.96 223.17,75.8 CV77.2
DDR3_DRAMRST#: length 220.5
  TOP w0.102: v2(168.84,6.63) 169.01,6.79 CD35.1 ; v2(91.13,12.53) 91.15,12.52 CD6.1 RD2.2
  IN1 w0.102: v2(91.13,12.53) 90.65,13.02 90.65,19.27 90.07,19.85 90.07,23.51 90.68,24.12 v2(90.98,24.12) 91.09,24.23 91.09,24.59 96.92,30.42 96.92,39.01 v2(98.47,40.56)
  IN2 w0.102: v2(146,12.75) 147.27,11.48 v2(157.25,11.48)
  BOTTOM w0.076: 162.7,48.02 162.35,48.37 162.35,49.13 162.1,49.38 162.1,50.4 161.85,50.65 161.85,50.97 161.97,51.1 161.97,51.29 161.85,51.42 161.85,51.73 162.13,52.01 UC1.AV15
  BOTTOM w0.102: 162.7,48.02 162.7,43.25 161.94,42.49 123.3,42.49 121.37,40.56 v2(98.47,40.56) ; v2(146,12.75) 146,27.41 145.49,27.91 94.78,27.91 v2(90.98,24.12) ; v2(168.84,6.63) 169.2,6.99 JDIMM2.30 169.2,12.64 168.58,13.26 161.95,13.26 159.52,10.83 157.9,10.83 v2(157.25,11.48) ; v2(91.13,12.53) 88.14,12.53 87.7,12.1 87.7,8.23 JDIMM1.30
DDR_A_BS0: length 74.9
  IN2 w0.076: v2(150.37,49.02) 150.59,48.81 150.59,45.94 149.1,44.45 149.1,42.1
  IN2 w0.152: v2(114.62,18.77) 114.62,18.82 114.75,18.94 115.24,18.94 115.36,18.82 115.36,17.2 115.49,17.07 115.99,17.07 116.11,17.2 116.11,18.64 116.24,18.77 116.37,18.77 116.49,18.9 116.49,19.93 116.62,20.05 117.05,20.05 117.18,19.93 117.18,18.87 117.31,18.74 117.46,18.74 117.59,18.61 117.59,17.2 117.71,17.07 118.32,17.07 118.45,17.2 118.45,18.5 118.58,18.63 119.34,18.63 119.47,18.5 119.47,17.39 119.78,17.07 132.88,17.07 133.54,17.73 133.54,20.37 149.1,35.93 149.1,42.1
  BOTTOM w0.076: v2(150.37,49.02) 149.48,49.92 149.48,52.05 149.48,52.06 149.48,52.3 149.48,52.31 149.48,52.32 149.88,52.73 UC1.AU35
  BOTTOM w0.152: JDIMM1.109 113.8,18.59 113.98,18.77 v2(114.62,18.77)
DDR_A_BS1: length 76.6
  IN2 w0.076: v2(150.37,49.58) 150.81,49.14 150.81,45.76 149.5,44.45 149.5,42.1
  IN2 w0.152: 149.5,42.1 149.5,35.76 133.95,20.21 133.95,16.97 133.65,16.66 117.38,16.66 117.18,16.86 117.18,17.46 117.05,17.58 116.65,17.58 116.52,17.46 116.52,16.79 116.39,16.66 115.87,16.66 115.72,16.51 115.72,15.3 115.59,15.17 115.29,15.17 115.16,15.3 115.16,16.83 115.04,16.95 114.48,16.95 114.36,16.83 114.36,12.18 114.48,12.05 v2(114.83,12.05)
  BOTTOM w0.076: v2(150.37,49.58) 149.64,50.31 149.64,51.88 UC1.AV35
  BOTTOM w0.152: JDIMM1.108 113.5,10.72 v2(114.83,12.05)
DDR_A_BS2: length 72.4
  IN2 w0.076: 139.76,42.1 139.76,42.57 144.59,47.4 144.59,48.46 144.87,48.74 144.87,49.17 144.76,49.28 144.76,49.76 v2(145.53,50.53)
  IN2 w0.152: v2(102.4,20.3) 103.13,20.3 103.26,20.42 103.26,22 104.94,23.68 104.94,23.9 104.64,24.2 104.64,24.41 104.82,24.59 105.04,24.59 105.34,24.29 105.55,24.29 105.73,24.47 105.73,24.69 105.43,24.99 105.43,25.2 105.61,25.38 105.83,25.38 106.13,25.08 106.34,25.08 106.52,25.26 106.52,25.48 106.22,25.78 106.22,25.99 106.4,26.17 106.62,26.17 106.92,25.88 107.13,25.88 107.31,26.06 107.31,26.27 107.01,26.57 107.01,26.79 107.19,26.97 107.41,26.97 107.71,26.67 107.92,26.67 108.1,26.85 108.1,27.06 107.8,27.36 107.8,27.58 107.98,27.76 108.2,27.76 108.5,27.46 108.71,27.46 108.89,27.64 108.89,27.85 108.59,28.15 108.59,28.37 108.77,28.55 108.99,28.55 109.29,28.25 111.73,28.25 111.86,28.37 111.86,29.65 111.99,29.78 129.67,29.78 139.76,39.87 139.76,42.1
  BOTTOM w0.076: UC1.AY41 145.88,50.88 v2(145.53,50.53)
  BOTTOM w0.152: v2(102.4,20.3) 102.96,19.74 102.96,19.37 104.8,17.53 JDIMM1.79
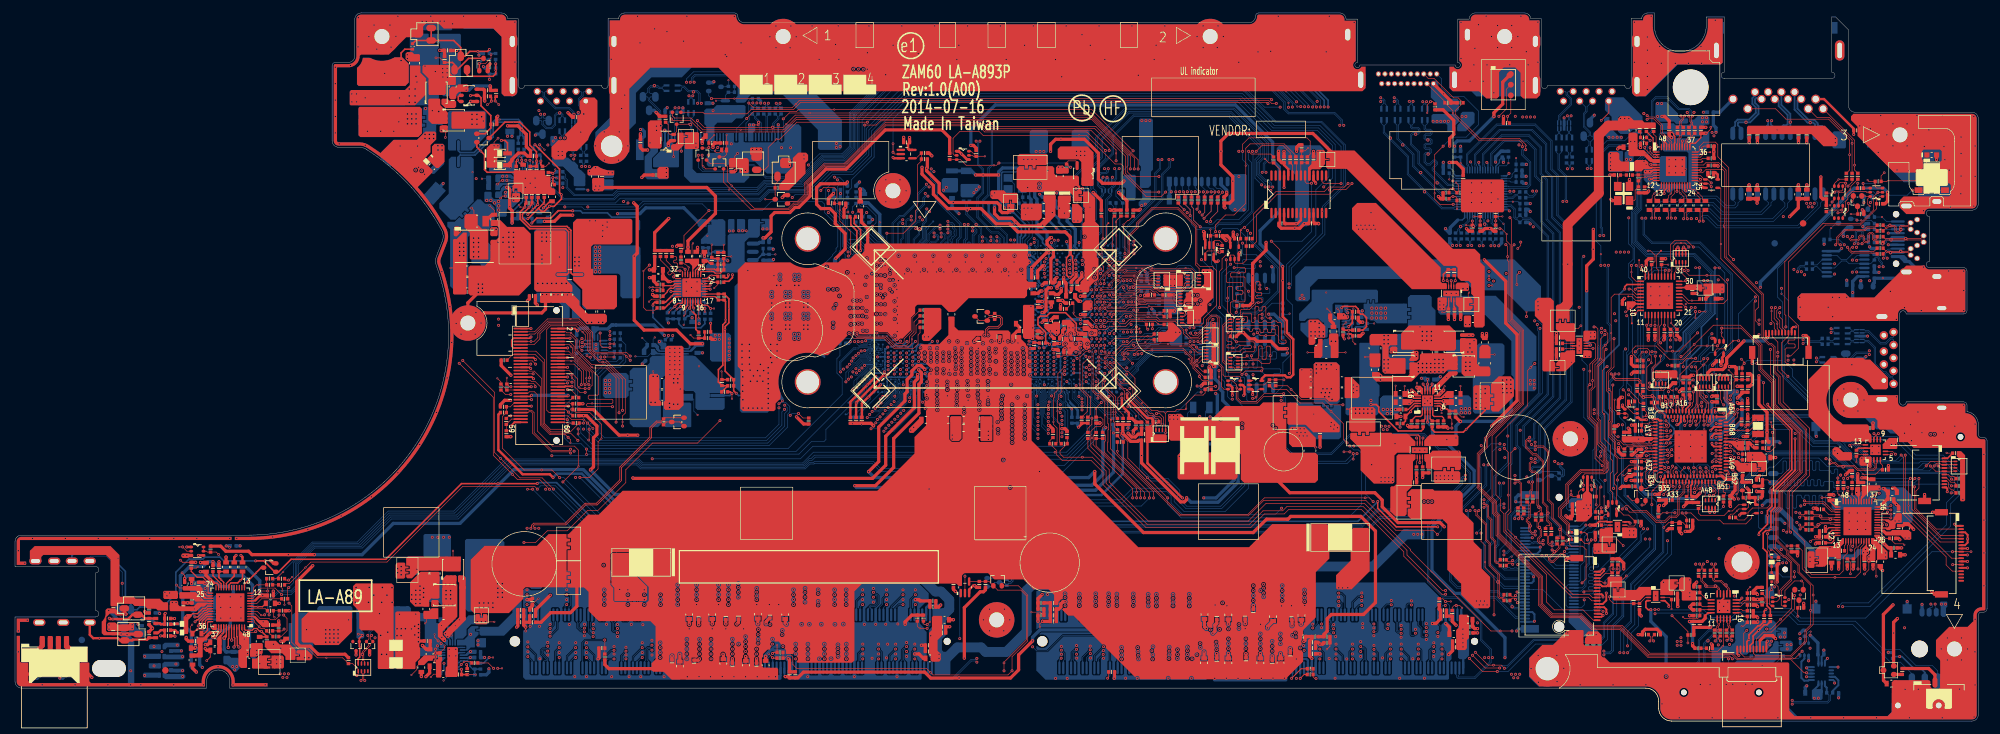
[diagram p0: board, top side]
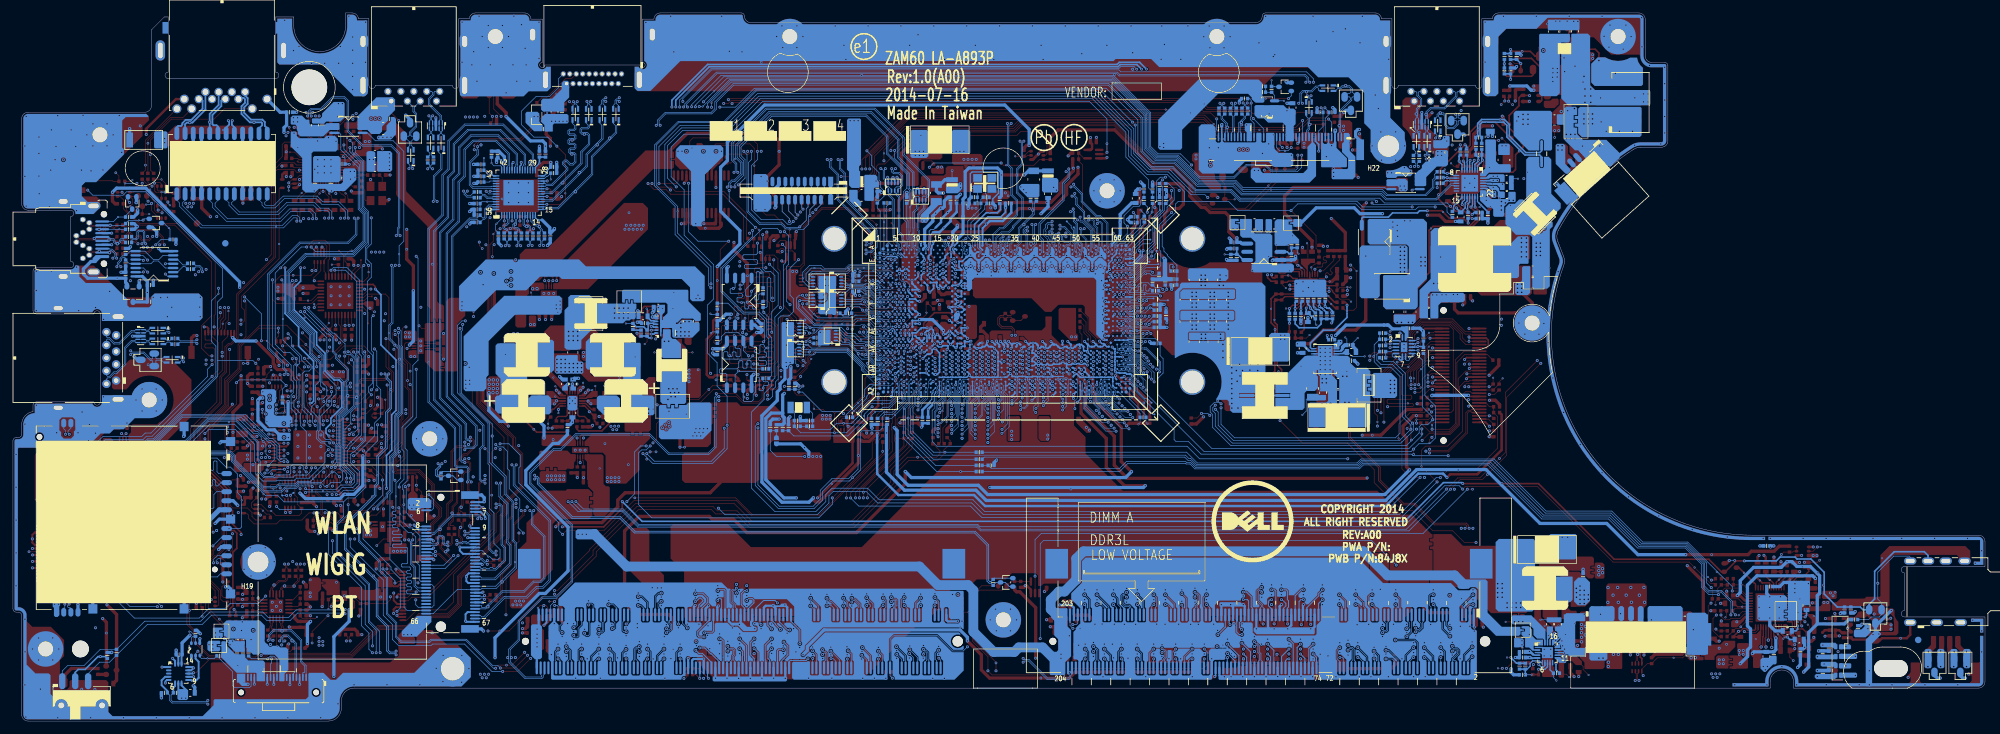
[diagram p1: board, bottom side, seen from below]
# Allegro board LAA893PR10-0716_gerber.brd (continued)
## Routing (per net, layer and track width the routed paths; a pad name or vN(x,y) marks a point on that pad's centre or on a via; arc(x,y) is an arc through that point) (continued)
DDR_A_CAS#: length 75.8
  IN2 w0.076: v2(150.36,52.53) 151.5,51.4 151.5,43.05 150.72,42.28 150.72,42.1
  IN2 w0.152: v2(114.84,13.39) 115.21,13.39 115.36,13.23 115.36,12.97 115.49,12.85 115.99,12.85 118.56,15.42 119.93,15.42 120.08,15.26 120.08,15.09 120.23,14.93 120.49,14.93 120.64,15.09 120.64,15.26 120.79,15.42 123.2,15.42 123.35,15.26 123.35,15.09 123.5,14.93 123.76,14.93 123.91,15.09 123.91,15.26 124.06,15.42 125.09,15.42 125.24,15.26 125.24,15.09 125.4,14.93 125.65,14.93 125.8,15.09 125.8,15.26 125.96,15.42 128.47,15.42 128.62,15.26 128.62,15.09 128.77,14.93 129.03,14.93 129.18,15.09 129.18,15.26 129.33,15.42 129.59,15.42 129.74,15.26 129.74,15.09 129.89,14.93 130.15,14.93 130.3,15.09 130.3,15.26 130.45,15.42 135.34,15.42 136.39,16.47 137.63,16.47 138.71,17.54 138.71,20.98 138.86,21.13 139.15,21.13 139.3,21.28 139.3,21.53 139.15,21.69 138.86,21.69 138.71,21.84 138.71,22.09 138.86,22.25 139.15,22.25 139.3,22.4 139.3,22.65 139.15,22.8 138.86,22.8 138.71,22.96 138.71,23.24 150.72,35.25 150.72,42.1
  BOTTOM w0.076: UC1.AU34 150.66,52.83 v2(150.36,52.53)
  BOTTOM w0.152: JDIMM1.115 115.6,15.37 115.63,15.34 115.63,13.77 115.25,13.39 v2(114.84,13.39)
DDR_A_D0: length 58.8
  IN1 w0.102: v2(120.3,18.01) 119.54,18.77 119.54,20.89 119.67,21.02 120.08,21.02 120.2,21.15 120.2,21.42 120.09,21.54 119.36,21.54 119.26,21.64 119.26,21.94 119.36,22.04 120.09,22.04 120.19,22.15 120.19,22.45 120.09,22.55 119.36,22.55 119.26,22.65 119.26,22.96 119.36,23.06 120.09,23.06 120.19,23.16 120.19,23.47 120.09,23.57 119.36,23.57 119.26,23.67 119.26,23.97 119.36,24.08 120.09,24.08 120.19,24.18 120.19,24.48 120.09,24.58 119.36,24.58 119.26,24.69 119.26,24.99 119.36,25.09 120.09,25.09 120.19,25.19 120.19,25.5 120.09,25.6 119.36,25.6 119.26,25.7 119.26,26.01 119.36,26.11 120.09,26.11 120.19,26.21 120.19,26.52 120.08,26.63 119.67,26.63 119.54,26.76 119.54,45.06 126.02,51.54 126.02,54.71 129.75,58.44 v2(129.75,58.68)
  BOTTOM w0.076: UC1.AH63 131.81,58.23 131.68,58.1 130.32,58.1 v2(129.75,58.68)
  BOTTOM w0.102: v2(120.3,18.01) 119.8,17.51 119.8,16.53 119.8,16.53 JDIMM1.129
DDR_A_D1: length 58.6
  IN1 w0.102: v2(120.3,19.53) 120,19.53 119.86,19.67 119.86,20.58 119.99,20.7 120.39,20.7 120.52,20.83 120.52,26.85 120.42,26.95 119.96,26.95 119.86,27.05 119.86,27.36 119.96,27.46 120.42,27.46 120.52,27.56 120.52,27.87 120.42,27.97 119.96,27.97 119.86,28.07 119.86,28.37 119.96,28.47 120.42,28.47 120.52,28.58 120.52,28.88 120.42,28.98 119.96,28.98 119.86,29.08 119.86,29.39 119.96,29.49 120.42,29.49 120.52,29.59 120.52,29.9 120.42,30 119.96,30 119.86,30.1 119.86,30.41 119.96,30.51 120.42,30.51 120.52,30.61 120.52,30.91 120.42,31.01 119.96,31.01 119.86,31.12 119.86,31.42 119.96,31.52 120.42,31.52 120.52,31.62 120.52,31.93 120.42,32.03 119.96,32.03 119.86,32.13 119.86,32.44 119.96,32.54 120.42,32.54 120.52,32.64 120.52,32.95 120.42,33.05 119.96,33.05 119.86,33.15 119.86,33.45 119.96,33.55 120.33,33.55 120.46,33.68 120.46,33.95 120.33,34.07 119.95,34.07 119.86,34.16 119.86,44.93 126.38,51.44 126.38,54.58 130.3,58.51 v2(130.3,58.68)
  BOTTOM w0.076: v2(130.3,58.68) 130.72,58.26 131.62,58.26 131.88,58.52 132.23,58.52 132.4,58.43 132.6,58.23 UC1.AH62
  BOTTOM w0.102: JDIMM1.131 120.4,17.44 120.74,17.78 120.74,19.1 v2(120.3,19.53)
DDR_A_D2: length 57.1
  IN1 w0.102: v2(124.11,19.71) 124.05,19.71 123.92,19.58 123.92,19.07 124.05,18.95 124.39,18.95 124.52,19.07 124.52,20.68 123.66,21.54 123.66,22.33 123.56,22.44 123.17,22.44 123.07,22.54 123.07,22.84 123.17,22.94 123.56,22.94 123.66,23.05 123.66,23.35 123.56,23.45 123.17,23.45 123.07,23.55 123.07,23.86 123.17,23.96 123.56,23.96 123.66,24.06 123.66,24.37 123.56,24.47 123.17,24.47 123.07,24.57 123.07,24.87 123.17,24.98 123.56,24.98 123.66,25.08 123.66,25.38 123.56,25.48 123.17,25.48 123.07,25.59 123.07,25.89 123.17,25.99 123.56,25.99 123.66,26.09 123.66,26.4 123.56,26.5 123.17,26.5 123.07,26.6 123.07,26.91 123.17,27.01 123.56,27.01 123.66,27.11 123.66,27.41 123.56,27.52 123.17,27.52 123.07,27.62 123.07,27.92 123.17,28.02 123.54,28.02 123.66,28.15 123.66,28.35 123.54,28.48 123.2,28.48 123.07,28.61 123.07,44.47 128.97,50.37 128.97,51.67 132.25,54.96 132.25,55.92 131.66,56.51 v2(129.94,56.51)
  BOTTOM w0.076: UC1.AK63 132.03,56.75 131.76,56.75 131.52,56.51 129.94,56.51 v2(129.94,56.51)
  BOTTOM w0.102: JDIMM1.141 123.4,19 v2(124.11,19.71)
DDR_A_D3: length 58.4
  IN1 w0.102: v2(129.27,55.67) 131.1,55.67 131.64,55.14 131.64,54.69 128.65,51.71 128.65,50.51 122.76,44.61 122.76,22 123.57,21.18 123.57,19.37 123.16,18.96 123.16,10.24 v2(122.53,9.61)
  BOTTOM w0.076: v2(129.27,55.67) 129.6,55.67 130.27,56.34 131.58,56.34 131.83,56.59 132.28,56.59 132.57,56.88 UC1.AK62
  BOTTOM w0.102: v2(122.53,9.61) 122.84,9.61 123.1,9.36 JDIMM1.140
DDR_A_D4: length 59.2
  IN1 w0.102: v2(120.64,9.61) 120.33,9.61 120.08,9.87 120.08,12.18 120.2,12.31 120.71,12.31 120.84,12.43 120.84,34.02 120.18,34.68 120.18,44.79 126.71,51.32 126.71,54.41 130.88,58.58 v2(130.88,58.68)
  BOTTOM w0.076: v2(130.88,58.68) 131.12,58.44 131.58,58.44 131.82,58.69 132.27,58.69 132.3,58.67 132.31,58.66 132.41,58.61 132.6,58.61 132.61,58.61 133.07,58.61 UC1.AH61
  BOTTOM w0.102: JDIMM1.132 120.7,9.56 v2(120.64,9.61)
DDR_A_D5: length 60
  IN1 w0.102: v2(130.76,57.23) 130.75,57.23 130.07,57.23 127.06,54.23 127.06,51.18 120.5,44.61 120.5,34.81 121.16,34.15 121.16,21.05 121.26,20.95 121.37,20.95 121.47,20.85 121.47,20.54 121.37,20.44 121.26,20.44 121.16,20.34 121.16,20.03 121.26,19.93 121.37,19.93 121.47,19.83 121.47,19.53 121.37,19.42 121.26,19.42 121.16,19.32 121.16,11.3 120.99,11.14 v2(120.64,11.14)
  BOTTOM w0.076: UC1.AH60 134.11,57.46 133.9,57.26 133.66,57.26 133.64,57.28 133.27,57.28 133.25,57.26 133.06,57.26 133.05,57.27 132.91,57.33 132.7,57.33 132.65,57.31 132.65,57.31 132.55,57.26 132.42,57.26 132.31,57.31 132.31,57.31 132.26,57.33 131.97,57.33 131.71,57.08 131.62,57.08 131.38,56.84 131.15,56.84 v2(130.76,57.23)
  BOTTOM w0.102: v2(120.64,11.14) 120.1,10.6 JDIMM1.130
DDR_A_D6: length 58.9
  IN1 w0.102: v2(124.11,17.93) 123.6,17.93 123.48,17.81 123.48,14.41 123.6,14.29 123.98,14.29 124.11,14.41 124.11,15.27 124.22,15.38 124.71,15.38 124.84,15.51 124.84,20.81 123.98,21.67 123.98,28.49 123.39,29.08 123.39,44.34 129.22,50.17 129.22,51.43 131.59,53.8 131.59,54.03 132.52,54.96 132.52,55.92 131.66,56.77 130.45,56.77 v2(130.35,56.87)
  BOTTOM w0.076: v2(130.35,56.87) 130.55,56.67 131.45,56.67 131.69,56.92 131.78,56.92 132.03,57.17 132.22,57.17 132.33,57.12 132.38,57.1 132.58,57.1 132.64,57.12 132.72,57.16 132.74,57.17 132.87,57.17 132.92,57.15 132.98,57.12 133.11,56.98 UC1.AK61
  BOTTOM w0.102: v2(124.11,17.93) 124,17.82 JDIMM1.143
DDR_A_D7: length 58.7
  IN1 w0.102: v2(122.53,11.14) 122.09,11.57 122.09,14.88 122.84,15.63 122.84,17.3 122.74,17.4 122.34,17.4 122.23,17.51 122.23,17.81 122.34,17.91 122.74,17.91 122.84,18.01 122.84,19.09 123.26,19.5 123.26,21.01 122.44,21.83 122.44,44.77 128.34,50.66 128.34,51.72 129.63,53.01 129.63,53.44 129.47,53.59 129.27,53.59 129.12,53.75 129.12,55 v2(128.95,55.16)
  BOTTOM w0.076: UC1.AK60 133.87,56.98 133.58,56.69 133.03,56.69 132.93,56.59 132.51,56.59 132.35,56.42 131.9,56.42 131.65,56.18 130.6,56.18 129.86,55.43 129.6,55.43 129.33,55.16 v2(128.95,55.16)
  BOTTOM w0.102: v2(122.53,11.14) 123.7,9.97 JDIMM1.142
DDR_A_D8: length 83.3
  IN2 w0.102: v2(129.95,54.48) 129.93,54.5 129.07,54.5 127.38,52.81 127.38,52.22 121.06,45.9 102.38,45.9 98.36,41.88 97.78,41.88 81.12,25.22 79.96,25.22 79.86,25.12 79.86,24.82 79.96,24.71 81.12,24.71 81.22,24.61 81.22,24.31 81.12,24.21 79.55,24.21 79.42,24.08 79.42,23.82 79.55,23.7 81.12,23.7 81.22,23.6 81.22,23.29 81.12,23.19 80.15,23.19 80.02,23.06 80.02,22.81 80.15,22.68 81.12,22.68 81.22,22.58 81.22,22.21 81.09,22.08 79.68,22.08 79.55,21.96 79.55,19.96 v2(79.12,19.53)
  BOTTOM w0.076: v2(129.95,54.48) 130.13,54.67 130.13,54.95 130.85,55.67 131.88,55.67 131.88,55.67 132.03,55.67 UC1.AM63
  BOTTOM w0.102: JDIMM1.7 80.8,16.43 80.8,17.85 v2(79.12,19.53)
DDR_A_D9: length 84.5
  IN2 w0.102: v2(79.25,9.96) 79.37,9.83 80.54,9.83 80.6,9.89 80.6,10.2 80.5,10.3 80.24,10.3 80.11,10.43 80.11,10.68 80.24,10.81 80.5,10.81 80.6,10.91 80.6,20.02 82.17,21.59 82.17,24.93 98.21,40.96 98.73,40.96 102.76,44.99 121.48,44.99 128.81,52.32 v2(128.81,52.87)
  BOTTOM w0.076: UC1.AM62 132.57,55.8 132.28,56.09 132.03,56.09 131.78,55.83 130.79,55.83 129.97,55.01 129.87,55.01 128.81,53.95 v2(128.81,52.87)
  BOTTOM w0.102: v2(79.25,9.96) 79.9,9.3 JDIMM1.4
DDR_A_D10: length 82.9
  IN2 w0.102: v2(130.1,51.61) 130.1,51.13 129.47,50.49 129.23,50.49 122.19,43.46 103.48,43.46 84.21,24.19 84.21,21.44 83.44,20.67 83.44,13.46 83.27,13.3 83.27,10.31 83.14,10.18 82.96,10.18 82.83,10.31 82.83,12.99 v2(82.69,13.13)
  BOTTOM w0.076: v2(130.1,51.61) 130.1,52.81 131.74,54.45 UC1.AP63
  BOTTOM w0.102: JDIMM1.17 83.8,16.43 83.8,14.25 v2(82.69,13.13)
DDR_A_D11: length 84
  IN2 w0.102: v2(84.1,9.83) 83.59,10.34 83.59,12.65 83.7,12.76 84.54,12.76 84.67,12.64 84.67,11.61 84.8,11.48 85.25,11.48 85.38,11.61 85.38,13.44 85.25,13.56 83.97,13.56 83.75,13.78 83.75,20.54 84.53,21.31 84.53,24.05 103.63,43.15 122.36,43.15 129.4,50.19 129.95,50.19 130.89,51.13 v2(130.89,52.5)
  BOTTOM w0.076: UC1.AP62 132.57,54.45 132.28,54.15 131.68,54.15 130.89,53.36 v2(130.89,52.5)
  BOTTOM w0.102: JDIMM1.18 84.1,9.83 v2(84.1,9.83)
DDR_A_D12: length 84.5
  IN2 w0.102: v2(128.4,52.46) 128.4,52.45 128.4,52.36 121.33,45.29 102.63,45.29 98.61,41.27 98.07,41.27 81.86,25.06 81.86,21.72 80.27,20.14 80.27,11.81 79.94,11.48 v2(79.25,11.48)
  BOTTOM w0.076: UC1.AM61 133.33,55.69 132.93,56.09 132.51,56.09 132.35,56.26 131.97,56.26 131.71,56 130.69,56 129.92,55.23 129.73,55.23 128.53,54.03
  BOTTOM w0.102: 128.53,54.03 128.4,53.9 v2(128.4,52.46) ; JDIMM1.6 80.5,10.23 v2(79.25,11.48)
DDR_A_D13: length 85.2
  IN2 w0.102: v2(129.48,54) 129.31,54 127.95,52.63 127.95,52.36 121.19,45.6 102.51,45.6 98.48,41.57 97.92,41.57 81.54,25.19 81.54,21.85 79.88,20.19 79.88,15.18 79.75,15.06 79.52,15.06 79.4,15.18 79.4,15.88 79.3,15.98 78.85,15.98 78.75,16.09 78.75,16.39 78.85,16.49 79.3,16.49 79.4,16.59 79.4,16.9 79.3,17 78.85,17 78.75,17.1 78.75,17.41 78.85,17.51 79.3,17.51 79.4,17.61 79.4,17.88 79.27,18.01 v2(79.12,18.01)
  BOTTOM w0.076: UC1.AM60 134.11,55.03 133.9,54.83 133.06,54.83 133.05,54.84 132.96,54.88 132.91,54.9 132.71,54.9 132.65,54.88 132.55,54.83 132.41,54.83 132.25,54.9 131.69,54.9 130.19,53.4 129.84,53.4 129.48,53.76 v2(129.48,54)
  BOTTOM w0.102: JDIMM1.5 80.2,17.49 79.68,18.01 v2(79.12,18.01)
DDR_A_D14: length 83.9
  IN2 w0.102: v2(82.69,14.33) 82.38,14.33 82.28,14.43 82.28,15.33 82.38,15.43 82.99,15.43 83.09,15.54 83.09,15.83 82.97,15.95 82.37,15.95 82.24,16.08 82.24,16.34 82.37,16.46 82.97,16.46 83.09,16.59 83.09,16.84 82.97,16.97 82.37,16.97 82.24,17.1 82.24,17.35 82.37,17.48 82.97,17.48 83.09,17.61 83.09,17.86 82.97,17.99 82.37,17.99 82.24,18.11 82.24,18.37 82.37,18.49 82.97,18.49 83.09,18.62 83.09,18.89 82.99,18.99 82.38,18.99 82.28,19.09 82.28,19.73 82.41,19.86 82.94,19.86 83.07,19.99 83.07,20.75 83.89,21.58 83.89,22.31 83.79,22.41 83.5,22.41 83.4,22.51 83.4,22.82 83.5,22.92 83.79,22.92 83.89,23.02 83.89,23.33 83.79,23.43 83.5,23.43 83.4,23.53 83.4,23.83 83.5,23.94 83.79,23.94 83.89,24.04 83.89,24.37 103.29,43.76 122.05,43.76 128.55,50.27 128.56,50.27 129.04,50.75 129.04,50.77 129.45,51.18 v2(129.64,51.18)
  BOTTOM w0.076: UC1.AP61 133.22,54.45 132.98,54.69 132.87,54.74 132.74,54.74 132.72,54.73 132.64,54.69 132.58,54.67 132.37,54.67 132.33,54.69 132.22,54.74 131.8,54.74 129.64,52.58 v2(129.64,51.18)
  BOTTOM w0.102: v2(82.69,14.33) 83.2,14.84 JDIMM1.15
DDR_A_D15: length 84.9
  IN2 w0.102: v2(84.1,11.35) 84.48,11.35 84.69,11.14 84.69,10.21 84.95,9.96 85.47,9.96 85.7,10.18 85.7,13.73 85.54,13.88 84.44,13.88 84.07,14.25 84.07,20.41 84.85,21.18 84.85,23.91 103.78,42.85 122.59,42.85 129.47,49.73 129.86,49.73 131.32,51.19 v2(131.32,52.86)
  BOTTOM w0.076: v2(131.32,52.86) 131.32,53.56 131.75,53.99 132.34,53.99 132.37,54.02 132.38,54.02 132.51,54.15 132.93,54.15 132.94,54.16 133.32,54.16 133.33,54.15 133.58,54.15 133.64,54.22 133.88,54.22 UC1.AP60
  BOTTOM w0.102: v2(84.1,11.35) 83.5,10.76 83.5,8.23 JDIMM1.16
DDR_A_D16: length 54.9
  IN1 w0.102: v2(134.93,54.31) 135.3,53.94 135.3,52.46 134,51.16 133.41,51.16 130.12,47.87 130.12,46.53 127,43.4 127,27.47 127.5,26.97 128.47,26.97 128.69,26.75 128.69,21.3 129.18,20.81 129.18,16.75 128.98,16.55 128.98,12.93 128.85,12.8 128.57,12.8 128.45,12.93 128.45,18.01 v2(128.44,18.01)
  BOTTOM w0.076: v2(134.93,54.31) 135.25,54.64 UC1.AP58
  BOTTOM w0.102: v2(128.44,18.01) 128.8,17.65 128.8,16.43 JDIMM1.159
DDR_A_D17: length 54.3
  IN1 w0.102: v2(128.44,19.53) 128.71,19.53 128.86,19.69 128.86,20.66 128.24,21.28 128.24,22.53 128.14,22.64 127.22,22.64 127.09,22.76 127.09,23.02 127.22,23.14 128.14,23.14 128.24,23.25 128.24,23.55 128.14,23.65 126.79,23.65 126.67,23.78 126.67,24.03 126.79,24.16 128.14,24.16 128.24,24.26 128.24,24.57 128.14,24.67 126.79,24.67 126.67,24.8 126.67,25.05 126.79,25.18 128.14,25.18 128.24,25.28 128.24,25.58 128.14,25.68 126.79,25.68 126.67,25.81 126.67,26.07 126.79,26.19 128.14,26.19 128.24,26.29 128.24,26.53 128.12,26.66 127.06,26.66 126.68,27.04 126.68,43.54 129.85,46.71 129.85,47.89 133.4,51.43 133.87,51.43 134.93,52.49 v2(134.93,53.66)
  BOTTOM w0.076: v2(134.93,53.66) 135.25,53.99 UC1.AR58
  BOTTOM w0.102: v2(128.44,19.53) 128.01,19.1 128.01,17.79 128.2,17.6 JDIMM1.157
DDR_A_D18: length 57.1
  IN1 w0.102: v2(135.85,55.69) 135.3,56.25 135.3,57.06 135.08,57.28 134.78,57.28 134.24,56.74 134.24,56.02 132.29,54.08 132.29,52.73 130.01,50.45 130.01,49.76 128.38,48.13 128.38,47.95 124.22,43.79 124.22,29.42 124.81,28.83 124.81,22.02 125.66,21.17 125.66,10.21 v2(125.07,9.61)
  BOTTOM w0.076: v2(135.85,55.69) 136.03,55.69 UC1.AM57
  BOTTOM w0.102: v2(125.07,9.61) 124.9,9.44 JDIMM1.146
DDR_A_D19: length 58.1
  IN1 w0.102: v2(135.83,56.92) 135.28,57.46 134.61,57.46 133.99,56.83 133.99,56.08 132.09,54.18 132.09,52.93 129.7,50.55 129.7,49.94 128.04,48.27 128.04,48.12 123.9,43.98 123.9,29.29 124.49,28.7 124.49,21.89 125.35,21.03 125.35,12.43 125.22,12.31 124.36,12.31 124.23,12.18 124.23,11.64 124.36,11.51 124.94,11.51 125.07,11.39 v2(125.07,11.14)
  BOTTOM w0.076: UC1.AK57 136.15,57.24 v2(135.83,56.92)
  BOTTOM w0.102: JDIMM1.148 125.5,10.71 v2(125.07,11.14)
DDR_A_D20: length 56.7
  IN1 w0.102: v2(134.94,56.27) 134.94,56.16 132.66,53.89 132.66,52.32 130.57,50.23 130.57,49.75 129.11,48.28 129.11,47.71 125.44,44.05 125.44,43.56 125.34,43.45 124.98,43.45 124.85,43.33 124.85,43.07 124.98,42.95 125.34,42.95 125.44,42.84 125.44,42.54 125.34,42.44 124.98,42.44 124.85,42.31 124.85,42.06 124.98,41.93 125.34,41.93 125.44,41.83 125.44,41.52 125.34,41.42 124.98,41.42 124.85,41.3 124.85,41.04 124.98,40.91 125.34,40.91 125.44,40.81 125.44,22.29 127.18,20.55 127.18,16.78 127.08,16.68 126.54,16.68 126.44,16.58 126.44,16.28 126.54,16.17 127.08,16.17 127.18,16.07 127.18,15.76 127.06,15.63 126.11,15.63 125.98,15.76 125.98,18.26 126.08,18.36 126.51,18.36 126.65,18.22 v2(126.65,18.01)
  BOTTOM w0.076: UC1.AL58 135.26,56.59 v2(134.94,56.27)
  BOTTOM w0.102: v2(126.65,18.01) 126.32,18.01 125.8,17.49 125.8,16.43 JDIMM1.149
DDR_A_D21: length 57.5
  IN1 w0.102: v2(126.65,19.53) 125.98,20.21 125.98,21.3 125.13,22.15 125.13,29.35 125.02,29.45 124.64,29.45 124.53,29.55 124.53,29.86 124.64,29.96 125.02,29.96 125.13,30.06 125.13,30.36 125.02,30.47 124.64,30.47 124.53,30.57 124.53,30.87 124.64,30.97 125.02,30.97 125.13,31.08 125.13,31.38 125.02,31.48 124.64,31.48 124.53,31.58 124.53,31.89 124.64,31.99 125.02,31.99 125.13,32.09 125.13,32.42 125.02,32.52 124.64,32.52 124.53,32.62 124.53,32.93 124.64,33.03 125.02,33.03 125.13,33.13 125.13,33.43 125.02,33.54 124.64,33.54 124.53,33.64 124.53,33.94 124.64,34.04 125.02,34.04 125.13,34.15 125.13,34.45 125.02,34.55 124.64,34.55 124.53,34.65 124.53,34.96 124.64,35.06 125.02,35.06 125.13,35.16 125.13,35.47 125.02,35.57 124.64,35.57 124.53,35.67 124.53,35.97 124.64,36.08 125.02,36.08 125.13,36.18 125.13,36.48 125.02,36.58 124.64,36.58 124.53,36.69 124.53,36.99 124.64,37.09 125.02,37.09 125.13,37.19 125.13,37.5 125.02,37.6 124.64,37.6 124.53,37.7 124.53,38.01 124.64,38.11 125.02,38.11 125.13,38.21 125.13,38.51 125.02,38.62 124.64,38.62 124.53,38.72 124.53,39.02 124.64,39.12 125.02,39.12 125.13,39.23 125.13,39.53 125.02,39.63 124.64,39.63 124.53,39.73 124.53,40.04 124.64,40.14 125.02,40.14 125.13,40.24 125.13,40.47 125,40.6 124.66,40.6 124.53,40.72 124.53,43.62 128.78,47.87 128.78,48.25 130.31,49.78 130.31,50.37 132.48,52.53 132.48,53.98 134.5,56 134.5,56.49 v2(134.93,56.92)
  BOTTOM w0.076: UC1.AK58 135.25,57.24 v2(134.93,56.92)
  BOTTOM w0.102: JDIMM1.147 125.2,16.43 125.2,18.08 v2(126.65,19.53)
DDR_A_D22: length 54.7
  IN1 w0.102: v2(128.47,9.61) 129.42,9.61 129.77,9.96 129.77,12.71 129.85,12.8 130.59,12.8 130.72,12.93 130.72,13.18 130.59,13.31 129.85,13.31 129.77,13.4 129.77,13.54 129.61,13.69 129.61,16.29 130.03,16.71 130.03,20.86 129.33,21.56 129.33,27.48 129.2,27.61 127.76,27.61 127.63,27.74 127.63,43.14 130.68,46.19 130.68,47.79 133.61,50.72 134.35,50.72 135.88,52.25 v2(135.88,53.66)
  BOTTOM w0.076: UC1.AR57 136.2,53.99 v2(135.88,53.66)
  BOTTOM w0.102: v2(128.47,9.61) 128.5,9.58 JDIMM1.158
DDR_A_D23: length 56.3
  IN1 w0.102: v2(135.88,54.96) 135.5,54.59 135.5,52.21 134.25,50.95 133.54,50.95 130.43,47.84 130.43,46.38 127.31,43.27 127.31,27.6 127.63,27.29 128.79,27.29 129.01,27.07 129.01,21.43 129.61,20.83 129.61,16.74 129.3,16.42 129.3,10.05 129.18,9.93 129,9.93 128.87,10.06 128.87,11.01 128.75,11.14 v2(128.47,11.14)
  BOTTOM w0.076: v2(135.88,54.96) 136.2,55.29 UC1.AN57
  BOTTOM w0.102: JDIMM1.160 129.1,10.5 v2(128.47,11.14)
DDR_A_D24: length 80.8
  IN2 w0.102: v2(86.64,9.83) 86.23,10.23 86.23,12.96 86.48,13.21 86.48,19.17 86.08,19.57 86.08,23.49 104.29,41.71 123.35,41.71 133.27,51.63 133.27,52.04 133.79,52.55 135.6,52.55 136.45,53.41 136.45,53.98 v2(136.83,54.36)
  BOTTOM w0.076: UC1.AP55 137.11,54.64 v2(136.83,54.36)
  BOTTOM w0.102: v2(86.64,9.83) 86.43,9.83 85.9,9.3 JDIMM1.24
DDR_A_D25: length 79.9
  IN2 w0.102: v2(86.64,11.35) 87.16,11.87 87.16,13.46 86.8,13.82 86.8,19.31 86.4,19.71 86.4,23.35 104.43,41.39 123.54,41.39 133.79,51.64 135.09,51.64 136.83,53.38 136.83,53.66 136.82,53.67 v2(136.82,53.66)
  BOTTOM w0.076: UC1.AR55 137.16,53.99 136.83,53.66 v2(136.82,53.66)
  BOTTOM w0.102: v2(86.64,11.35) 85.3,10.01 JDIMM1.22
DDR_A_D26: length 83.3
  IN2 w0.102: v2(88.3,11.35) 88.3,11.35 90.12,13.17 90.12,19.03 88.85,20.3 88.85,23.13 105.25,39.53 124.45,39.53 129.74,44.82 129.74,44.86 131.04,46.15 131.79,46.15 135.39,49.75 135.39,50.22 135.83,50.65 136.76,50.65 138.37,52.27 138.37,54.57 138.16,54.79 138.16,55.89 v2(137.78,56.27)
  BOTTOM w0.076: UC1.AM54 138.11,55.94 v2(137.78,56.27)
  BOTTOM w0.102: v2(88.3,11.35) 89.5,10.15 JDIMM1.36
DDR_A_D27: length 83.9
  IN2 w0.102: v2(88.3,9.83) 90.43,11.96 90.43,19.16 89.16,20.43 89.16,22.99 105.39,39.21 124.59,39.21 130.66,45.27 131.19,45.27 134.08,48.17 134.11,48.17 134.33,48.39 134.34,48.39 134.57,48.62 134.57,48.63 134.78,48.84 134.8,48.84 135.02,49.07 135.02,49.08 135.24,49.3 135.25,49.3 135.48,49.53 135.48,49.55 135.7,49.77 135.72,49.77 135.74,49.79 136.72,49.79 138.62,51.69 138.62,54.6 138.34,54.89 138.34,56.36 v2(137.78,56.92)
  BOTTOM w0.076: UC1.AK54 138.11,57.24 v2(137.78,56.92)
  BOTTOM w0.102: JDIMM1.34 88.9,9.23 v2(88.3,9.83)
DDR_A_D28: length 82.6
  IN2 w0.102: v2(85.25,19.53) 85.25,19.35 85.66,18.94 85.66,15.96 85.79,15.84 86.03,15.84 86.16,15.96 86.16,19.04 85.74,19.47 85.74,23.61 104.15,42.02 123.14,42.02 132.88,51.76 132.88,52.37 133.44,52.93 135.67,52.93 136.26,53.52 136.26,55.69 v2(136.83,56.27)
  BOTTOM w0.076: v2(136.83,56.27) 137.16,56.59 UC1.AL55
  BOTTOM w0.102: v2(85.25,19.53) 85.66,19.53 85.83,19.36 85.83,17.88 85.6,17.65 JDIMM1.23
DDR_A_D29: length 83.4
  IN2 w0.102: v2(136.82,56.92) 136.3,57.43 134.86,57.43 134.2,56.77 134.2,56.08 132.24,54.12 132.24,51.63 122.93,42.33 104.01,42.33 85.35,23.68 85.35,20.97 84.58,20.2 84.58,14.52 84.71,14.39 84.99,14.39 85.11,14.52 85.11,17.88 85.24,18.01 v2(85.25,18.01)
  BOTTOM w0.076: v2(136.82,56.92) 137.14,57.24 UC1.AK55
  BOTTOM w0.102: JDIMM1.21 85,17.76 v2(85.25,18.01)
DDR_A_D30: length 81.2
  IN2 w0.102: v2(137.78,53.66) 137.78,53.27 135.44,50.93 134.27,50.93 133.23,49.89 133.23,49.39 129.93,46.09 129.93,46 124.1,40.16 104.97,40.16 88.5,23.7 88.49,23.7 88.21,23.42 88.21,16.76 88.31,16.66 89.35,16.66 89.48,16.53 89.48,16.28 89.35,16.15 88.28,16.15 88.15,16.02 88.15,15.77 88.28,15.64 88.97,15.64 89.1,15.52 89.1,15.26 88.97,15.14 88.64,15.14 88.5,15 88.5,13.89 v2(89.34,13.06)
  BOTTOM w0.076: UC1.AR54 138.11,53.99 v2(137.78,53.66)
  BOTTOM w0.102: v2(89.34,13.06) 88.6,13.8 JDIMM1.33
DDR_A_D31: length 82.6
  IN2 w0.102: v2(89.37,14.27) 89.8,14.71 89.8,16.94 89.7,17.04 88.63,17.04 88.53,17.14 88.53,17.45 88.63,17.55 89.7,17.55 89.8,17.65 89.8,17.96 89.7,18.06 88.63,18.06 88.53,18.16 88.53,18.47 88.63,18.57 89.7,18.57 89.8,18.67 89.8,18.9 89.67,19.02 88.66,19.02 88.53,19.15 88.53,23.27 105.11,39.85 124.24,39.85 129.33,44.94 129.56,44.94 131.15,46.53 131.84,46.53 135.09,49.78 135.09,50.27 135.68,50.86 136.64,50.86 138.17,52.38 138.17,54.45 137.78,54.84 v2(137.78,54.96)
  BOTTOM w0.076: UC1.AN54 138.11,55.29 v2(137.78,54.96)
  BOTTOM w0.102: JDIMM1.35 89.2,15.45 88.96,15.21 88.96,14.55 89.24,14.27 v2(89.37,14.27)
DDR_A_D32: length 49
  IN1 w0.102: v2(133.82,49.18) 133.17,49.18 131.23,47.25 131.23,45.15 131,44.91 131,44.75 129.51,43.26 129.51,37.15 128.78,36.42 128.78,30.99 130.47,29.3 130.47,22.1 131.73,20.83 131.73,12.43 131.61,12.31 130.72,12.31 130.6,12.19 130.6,11.58 130.5,11.48 130.4,11.48 130.27,11.35 130.27,11 130.4,10.87 130.5,10.87 130.6,10.77 130.6,9.79 130.78,9.61 v2(131.01,9.61)
  BOTTOM w0.076: v2(133.82,49.18) 134.31,49.18 135.23,50.1 135.23,50.76 UC1.AY58
  BOTTOM w0.102: JDIMM1.166 130.9,9.51 v2(131.01,9.61)
DDR_A_D33: length 49.7
  IN1 w0.102: v2(130.98,18.01) 130.98,16.94 130.12,16.08 130.12,13.98 130.25,13.86 130.71,13.86 130.83,13.98 130.83,15.26 130.96,15.39 131.28,15.39 131.4,15.52 131.4,20.71 130.15,21.96 130.15,29.16 128.46,30.86 128.46,36.59 129.19,37.32 129.19,43.53 129.87,44.21 129.88,44.21 131.05,45.38 131.05,47.42 133.44,49.81 v2(133.72,49.81)
  BOTTOM w0.076: v2(133.72,49.81) 134.71,49.81 135.05,50.16 135.05,51.24 UC1.AW58
  BOTTOM w0.102: JDIMM1.165 130.6,16.43 130.6,17.63 v2(130.98,18.01)
DDR_A_D34: length 49.1
  IN1 w0.102: v2(134.68,19.53) 135.1,19.95 135.1,20.7 132.65,23.15 132.65,35.41 132.55,35.51 131.81,35.51 131.71,35.61 131.71,35.92 131.81,36.02 132.55,36.02 132.65,36.12 132.65,36.42 132.55,36.52 131.81,36.52 131.71,36.63 131.71,36.93 131.81,37.03 132.55,37.03 132.65,37.13 132.65,37.44 132.55,37.54 131.81,37.54 131.71,37.64 131.71,37.95 131.81,38.05 132.55,38.05 132.65,38.15 132.65,38.87 132.55,38.97 131.81,38.97 131.68,39.1 131.68,39.35 131.81,39.48 132.55,39.48 132.65,39.58 132.65,39.89 132.55,39.99 131.81,39.99 131.68,40.11 131.68,40.37 131.81,40.5 132.55,40.5 132.65,40.6 132.65,40.9 132.55,41 131.81,41 131.68,41.13 131.68,41.38 131.81,41.51 132.55,41.51 132.65,41.61 132.65,41.92 132.55,42.02 132.07,42.02 131.94,42.15 131.94,42.4 132.07,42.53 132.55,42.53 132.65,42.63 132.65,43.11 132.78,43.24 132.78,44.48 134.97,46.67 134.97,47.92 135.39,48.34 v2(135.39,48.94)
  BOTTOM w0.076: UC1.AY56 136.7,50.7 136.64,50.65 136.64,49.77 136.31,49.43 136.31,49.3 135.98,48.97 135.42,48.97 v2(135.39,48.94)
  BOTTOM w0.102: v2(134.68,19.53) 134.09,18.94 134.09,18.11 133.6,17.62 133.6,16.43 JDIMM1.175
DDR_A_D35: length 50.9
  IN1 w0.102: v2(133.45,9.61) 133.46,9.6 134.13,9.6 134.26,9.73 134.26,13.55 134.38,13.68 135.07,13.68 135.2,13.8 135.2,14.12 135.07,14.25 133.66,14.25 133.54,14.38 133.54,18.13 134.26,18.85 134.26,21.09 132.33,23.02 132.33,34.54 131.37,35.5 131.37,42.28 132.55,43.46 132.55,44.56 134.5,46.51 134.5,47.99 v2(134.47,48.02)
  BOTTOM w0.076: UC1.AW56 136.7,51.29 136.99,51 136.99,50.76 136.81,50.58 136.81,49.7 136.47,49.37 136.47,49.23 136.05,48.81 135.78,48.81 134.99,48.02 v2(134.47,48.02)
  BOTTOM w0.102: JDIMM1.174 133.3,9.47 v2(133.45,9.61)
DDR_A_D36: length 50.7
  IN1 w0.102: v2(134.11,50.2) 133.52,50.2 130.87,47.55 130.87,45.66 128.82,43.61 128.82,42.93 128.72,42.83 128.24,42.83 128.14,42.73 128.14,42.42 128.24,42.32 128.72,42.32 128.82,42.22 128.82,41.91 128.72,41.81 128.27,41.81 128.14,41.68 128.14,41.43 128.27,41.3 128.72,41.3 128.82,41.2 128.82,40.9 128.72,40.8 128.24,40.8 128.14,40.69 128.14,40.39 128.24,40.29 128.72,40.29 128.82,40.19 128.82,39.88 128.72,39.78 128.24,39.78 128.14,39.68 128.14,39.37 128.24,39.27 128.72,39.27 128.82,39.17 128.82,38.87 128.72,38.76 128.24,38.76 128.14,38.66 128.14,38.36 128.24,38.26 128.74,38.26 128.87,38.13 128.87,37.73 128.76,37.62 128.29,37.62 128.14,37.46 128.14,30.33 128.24,30.23 128.43,30.23 128.53,30.13 128.53,29.83 128.43,29.72 128.24,29.72 128.14,29.62 128.14,29.29 128.27,29.16 129.71,29.16 129.84,29.03 129.84,28.73 129.73,28.63 128.5,28.63 128.37,28.5 128.37,28.24 128.5,28.12 129.73,28.12 129.84,28.02 129.84,21.8 130.55,21.08 130.55,19.96 v2(130.98,19.53)
  BOTTOM w0.076: UC1.AV58 135.12,51.95 135.12,51.85 135.08,51.8 135.08,51.73 134.9,51.56 134.84,51.56 134.36,51.09 134.36,50.45 v2(134.11,50.2)
  BOTTOM w0.102: v2(130.98,19.53) 130,18.55 JDIMM1.163
DDR_A_D37: length 51.4
  IN1 w0.102: v2(131.71,46.94) 131.42,46.65 131.42,44.72 129.82,43.13 129.82,37.02 129.09,36.29 129.09,31.12 130.79,29.43 130.79,22.23 132.06,20.95 132.06,12.24 131.01,11.18 v2(131.01,11.14)
  BOTTOM w0.076: v2(131.71,46.94) 132.89,46.94 135.79,49.84 136.12,49.84 136.31,50.04 136.31,50.62 136.24,50.69 136.24,50.98 136.26,51.03 136.27,51.03 136.32,51.14 136.32,51.27 136.26,51.38 136.26,51.38 136.24,51.43 136.24,51.63 136.26,51.68 136.31,51.77 136.31,51.79 136.31,52.04 136.3,52.06 136.3,52.3 136.31,52.32 136.31,52.67 136.15,52.83 136.11,52.83 136.11,52.83 UC1.AU58
  BOTTOM w0.102: v2(131.01,11.14) 130.3,10.43 JDIMM1.164
DDR_A_D38: length 51.1
  IN1 w0.102: v2(134.68,18.01) 133.98,18.01 133.86,17.88 133.86,17.46 133.96,17.36 134.74,17.36 134.85,17.26 134.85,16.95 134.74,16.85 133.96,16.85 133.86,16.75 133.86,16.44 133.96,16.34 134.74,16.34 134.85,16.24 134.85,15.93 134.74,15.83 133.96,15.83 133.86,15.73 133.86,14.7 133.98,14.57 135.07,14.57 135.2,14.7 135.2,15.52 135.52,15.84 135.52,20.73 132.96,23.28 132.96,44.32 135.21,46.57 135.21,47.83 135.85,48.46 v2(135.85,49.4)
  BOTTOM w0.076: UC1.AV56 136.59,51.84 136.45,51.7 136.43,51.65 136.41,51.59 136.41,51.46 136.41,51.44 136.42,51.44 136.46,51.36 136.48,51.31 136.48,51.07 136.46,51.05 136.41,50.94 136.41,50.76 136.47,50.69 136.47,49.96 136.18,49.67 136.12,49.67 v2(135.85,49.4)
  BOTTOM w0.102: v2(134.68,18.01) 134.2,17.53 JDIMM1.177
DDR_A_D39: length 52.3
  IN1 w0.102: v2(133.45,11.14) 132.57,11.14 132.38,11.33 132.38,14.92 133.22,15.76 133.22,17.18 133.12,17.28 132.48,17.28 132.38,17.39 132.38,17.69 132.48,17.79 133.12,17.79 133.22,17.89 133.22,18.26 133.89,18.94 133.89,21.01 132.01,22.89 132.01,34.41 131.05,35.37 131.05,42.41 132.29,43.65 132.29,44.58 134.12,46.4 v2(134.12,47.5)
  BOTTOM w0.076: v2(134.12,47.5) 134.7,47.5 135.77,48.56 136.04,48.56 136.64,49.16 136.64,49.3 136.98,49.64 136.98,50.51 137.15,50.69 137.15,51.48 136.88,51.76 136.88,52.05 136.88,52.06 136.88,52.3 136.72,52.46 136.72,52.7 UC1.AU56
  BOTTOM w0.102: v2(133.45,11.14) 133.9,10.69 JDIMM1.176
DDR_A_D40: length 75
  IN2 w0.102: v2(132.28,45.2) 132.08,45 132,45 125.07,38.07 105.94,38.07 92.12,24.25 92.12,12.27 91.85,11.99 91.85,10.32 v2(92.57,9.6)
  BOTTOM w0.076: UC1.AY54 137.65,50.75 137.65,50.48 137.47,50.3 137.47,49.43 137.14,49.09 137.14,48.96 133.37,45.2 v2(132.28,45.2)
  BOTTOM w0.102: JDIMM1.42 91.3,9.3 91.6,9.6 v2(92.57,9.6)
DDR_A_D41: length 76.1
  IN2 w0.102: v2(133.01,46.12) 132.61,46.12 131.25,44.76 131.25,44.7 124.93,38.39 105.75,38.39 91.81,24.44 91.81,13.61 91.68,13.49 91.07,13.49 90.94,13.61 90.94,17.89 v2(91.06,18.01)
  BOTTOM w0.076: UC1.AW54 137.78,51.29 137.48,51 137.48,50.55 137.31,50.37 137.31,49.5 136.97,49.16 136.97,49.03 136.08,48.14 135.81,48.14 133.79,46.12 v2(133.01,46.12)
  BOTTOM w0.102: v2(91.06,18.01) 91,17.95 91,16.43 JDIMM1.41
DDR_A_D42: length 76.1
  IN2 w0.102: v2(135.5,46.21) 134.97,46.21 133.53,44.77 133.53,43.88 133.36,43.71 133.35,43.71 125.8,36.16 106.66,36.16 94,23.5 94,22.03 94.3,21.73 94.3,17.84 94.84,17.3 94.84,15.14 94.83,15.13 94.83,14.78 94.84,14.77 94.84,11.94 94.71,11.81 93.7,11.81 93.57,11.68 93.57,10.91 93.7,10.79 94.38,10.79 v2(94.41,10.82)
  BOTTOM w0.076: UC1.AY52 139,50.75 139,50.27 138.98,50.25 138.98,48.66 136.53,46.21 v2(135.5,46.21)
  BOTTOM w0.102: JDIMM1.50 93.7,10.11 v2(94.41,10.82)
DDR_A_D43: length 76.5
  IN2 w0.102: v2(134.58,45.29) 134.6,45.29 134.66,45.24 134.66,43.9 126.28,35.53 107.61,35.53 107.27,35.19 107.12,35.19 106.93,35.38 106.78,35.38 106.57,35.17 106.57,35.03 106.77,34.83 106.77,34.69 106.55,34.47 106.41,34.47 106.21,34.67 106.07,34.67 105.85,34.45 105.85,34.31 106.05,34.11 106.05,33.97 105.83,33.75 105.69,33.75 105.49,33.95 105.35,33.95 105.13,33.73 105.13,33.59 105.33,33.39 105.33,33.25 105.11,33.03 104.97,33.03 104.77,33.23 104.63,33.23 104.41,33.01 104.41,32.87 104.61,32.67 104.61,32.53 104.39,32.31 104.25,32.31 104.05,32.51 103.91,32.51 103.69,32.29 103.69,32.15 103.89,31.95 103.89,31.81 103.68,31.6 103.54,31.6 103.34,31.8 103.2,31.8 102.98,31.58 102.98,31.44 103.18,31.24 103.18,31.1 102.96,30.88 102.82,30.88 102.62,31.08 102.48,31.08 102.26,30.86 102.26,30.72 102.46,30.52 102.46,30.38 95.62,23.54 95.62,15.48 95.49,15.36 95.29,15.36 95.16,15.48 95.16,17.79 94.94,18.01 v2(94.7,18.01)
  BOTTOM w0.076: UC1.AW52 139.34,51.31 139.34,51.1 139.37,51.05 139.38,51.02 139.42,50.93 139.42,50.46 139.15,50.18 139.15,48.41 136.02,45.29 v2(134.58,45.29)
  BOTTOM w0.102: JDIMM1.51 94,17.31 v2(94.7,18.01)
DDR_A_D44: length 76.6
  IN2 w0.102: v2(91.06,19.53) 90.78,19.53 90.65,19.66 90.65,20.58 90.78,20.7 91.29,20.7 91.42,20.83 91.42,21.07 91.29,21.2 89.8,21.2 89.67,21.33 89.67,21.58 89.8,21.71 91.36,21.71 91.49,21.84 91.49,22.05 91.36,22.18 89.8,22.18 89.67,22.31 89.67,22.56 89.8,22.69 91.31,22.69 91.44,22.81 91.44,23.04 91.31,23.17 90.57,23.17 90.45,23.3 90.45,23.55 90.57,23.68 91.29,23.68 91.42,23.8 91.42,24.52 105.6,38.7 124.8,38.7 131.08,44.98 131.15,44.98 132.81,46.64 v2(133.28,46.64)
  BOTTOM w0.076: UC1.AV54 137.88,52.05 137.32,51.48 137.32,50.62 137.14,50.44 137.14,49.57 136.8,49.23 136.8,49.09 136.03,48.32 135.76,48.32 134.08,46.64 v2(133.28,46.64)
  BOTTOM w0.102: v2(91.06,19.53) 90.4,18.88 90.4,16.43 JDIMM1.39
DDR_A_D45: length 77.9
  IN2 w0.102: v2(92.57,10.95) 92.4,11.11 92.4,11.11 92.16,11.35 92.16,11.7 92.44,11.98 92.44,24.12 106.03,37.71 125.15,37.71 132.06,44.61 132.21,44.61 137.01,49.41 v2(138.23,49.41)
  BOTTOM w0.076: v2(138.23,49.41) 138.65,49.83 138.65,50.45 138.67,50.47 138.67,50.98 138.69,51.03 138.7,51.03 138.75,51.14 138.75,51.27 138.7,51.37 138.7,51.37 138.67,51.43 138.67,51.63 138.69,51.68 138.74,51.77 138.74,51.79 138.74,52.63 138.54,52.83 UC1.AU54
  BOTTOM w0.102: v2(92.57,10.95) 92.13,10.95 90.7,9.51 JDIMM1.40
DDR_A_D46: length 76.7
  IN2 w0.102: v2(135.96,46.67) 135.15,46.67 133.21,44.73 133.21,44.02 125.67,36.48 106.53,36.48 93.69,23.63 93.69,21.9 93.98,21.6 93.98,17.71 94.52,17.17 94.52,15.27 94.51,15.26 94.51,14.64 94.52,14.64 94.52,13.08 93.25,11.81 93.25,9.99 93.62,9.62 v2(94.41,9.62)
  BOTTOM w0.076: UC1.AV52 139.02,51.84 138.89,51.7 138.86,51.65 138.84,51.59 138.84,51.46 138.84,51.44 138.85,51.44 138.89,51.36 138.91,51.31 138.91,51.1 138.89,51.05 138.84,50.94 138.84,50.34 138.82,50.32 138.82,48.85 136.63,46.67 v2(135.96,46.67)
  BOTTOM w0.102: JDIMM1.52 94.3,9.51 v2(94.41,9.62)
DDR_A_D47: length 77.9
  IN2 w0.102: v2(134.27,44.82) 134.26,44.82 133.93,44.49 133.93,43.71 126.07,35.85 106.8,35.85 101.98,31.03 101.71,30.76 101.71,30.63 101.91,30.42 101.91,30.28 101.75,30.12 101.61,30.12 101.41,30.32 101.27,30.32 101.05,30.1 101.05,29.96 101.25,29.76 101.25,29.62 101.03,29.4 100.89,29.4 100.69,29.6 100.55,29.6 100.33,29.38 100.33,29.24 100.53,29.04 100.53,28.9 100.31,28.68 100.17,28.68 99.97,28.88 99.83,28.88 99.61,28.66 99.61,28.52 99.81,28.32 99.81,28.18 99.59,27.96 99.45,27.96 99.25,28.16 99.11,28.16 98.89,27.94 98.89,27.8 99.09,27.6 99.09,27.46 98.88,27.25 98.73,27.25 98.54,27.44 98.39,27.44 98.18,27.23 98.18,27.08 98.37,26.89 98.37,26.74 98.16,26.53 98.01,26.53 97.82,26.72 97.67,26.72 97.46,26.51 97.46,26.36 97.65,26.17 97.65,26.02 97.44,25.81 97.29,25.81 97.1,26 96.95,26 96.74,25.79 96.74,25.65 96.94,25.45 96.94,25.31 96.72,25.09 96.58,25.09 96.38,25.29 96.24,25.29 96.02,25.07 96.02,24.93 96.22,24.73 96.22,24.59 96,24.37 95.86,24.37 95.66,24.57 95.52,24.57 95.3,24.35 95.3,24.21 95.5,24.01 95.5,23.87 95.06,23.43 94.58,23.43 94.48,23.32 94.48,23.02 94.58,22.92 95.06,22.92 95.16,22.82 95.16,22.51 95.06,22.41 94.58,22.41 94.48,22.31 94.48,22 94.58,21.9 95.06,21.9 95.16,21.8 95.16,19.28 95.03,19.16 94.83,19.16 94.7,19.28 v2(94.7,19.53)
  BOTTOM w0.076: UC1.AU52 139.4,52.36 139.51,51.56 139.51,51.13 139.53,51.08 139.56,51.03 139.56,51.03 139.56,51.03 139.59,50.97 139.59,50.39 139.31,50.11 139.31,50.11 139.31,48.29 135.85,44.83 134.28,44.83 v2(134.27,44.82)
  BOTTOM w0.102: JDIMM1.53 94.6,17.3 95.31,18.01 95.31,19.26 95.04,19.53 v2(94.7,19.53)
DDR_A_D48: length 85.3
  IN2 w0.102: v2(99.76,18.01) 99.76,15.57 101.06,14.27 101.06,13.37 101.19,13.25 101.97,13.25 102.1,13.37 102.1,14.98 100.7,16.38 100.7,23.45 101.5,24.24 103.65,26.4 104.07,26.82 104.48,27.23 105.05,27.23 109.3,31.48 128.81,31.48 138.01,40.68 138.01,42.11 143.69,47.8 143.69,52.6 143.98,52.88 146.36,52.88 146.85,53.36 146.85,56.44 146.33,56.96 v2(146.27,56.96)
  BOTTOM w0.076: UC1.AK40 146.55,57.24 v2(146.27,56.96)
  BOTTOM w0.102: JDIMM1.69 99.4,17.65 v2(99.76,18.01)
DDR_A_D49: length 84.9
  IN2 w0.102: v2(145.35,56.97) 145.73,56.59 146.42,56.59 146.64,56.36 146.64,53.47 146.26,53.09 143.88,53.09 143.51,52.72 143.51,50.41 143.33,50.23 143.33,47.8 137.56,42.04 137.56,40.82 128.55,31.8 128.32,31.8 128.22,31.9 128.22,32.07 128.12,32.18 127.81,32.18 127.71,32.07 127.71,31.9 127.61,31.8 127.3,31.8 127.2,31.9 127.2,32.07 127.1,32.18 126.79,32.18 126.69,32.07 126.69,31.9 126.59,31.8 126.29,31.8 126.18,31.9 126.18,32.07 126.08,32.18 125.78,32.18 125.68,32.07 125.68,31.9 125.58,31.8 125.3,31.8 125.2,31.9 125.2,32.07 125.1,32.18 124.8,32.18 124.69,32.07 124.69,31.9 124.59,31.8 124.29,31.8 124.19,31.9 124.19,32.07 124.08,32.18 123.78,32.18 123.68,32.07 123.68,31.9 123.58,31.8 108.6,31.8 108.43,31.64 108.43,31.49 108.58,31.35 108.58,31.21 108.36,30.99 108.22,30.99 108.07,31.13 107.93,31.13 107.71,30.92 107.71,30.78 107.86,30.63 107.86,30.49 107.64,30.27 107.5,30.27 107.35,30.42 107.21,30.42 107,30.2 107,30.06 107.14,29.91 107.14,29.77 106.92,29.55 106.78,29.55 106.64,29.7 106.49,29.7 106.28,29.48 106.28,29.34 106.42,29.19 106.42,29.05 106.21,28.83 106.06,28.83 105.92,28.98 105.77,28.98 105.56,28.76 105.56,28.62 105.7,28.47 105.7,28.33 105.49,28.12 105.34,28.12 105.2,28.26 105.05,28.26 100.96,24.15 100.58,23.78 100.38,23.58 100.38,22.89 100.28,22.79 99.78,22.79 99.68,22.69 99.68,22.39 99.78,22.28 100.28,22.28 100.38,22.18 100.38,21.88 100.28,21.78 99.78,21.78 99.68,21.67 99.68,21.37 99.78,21.27 100.28,21.27 100.38,21.17 100.38,20.86 100.28,20.76 99.78,20.76 99.68,20.66 99.68,20.35 99.78,20.25 100.28,20.25 100.38,20.15 100.38,19.3 100.25,19.18 99.89,19.18 99.76,19.3 v2(99.76,19.53)
  BOTTOM w0.076: UC1.AK42 145.62,57.24 v2(145.35,56.97)
  BOTTOM w0.102: JDIMM1.67 98.8,16.43 98.8,18.58 v2(99.76,19.53)
DDR_A_D50: length 83
  IN2 w0.102: v2(144.34,55.72) 144.01,55.72 143.58,55.29 143.11,55.29 142.73,54.91 142.4,54.91 141.93,54.44 141.93,53.47 141.37,52.92 140.75,52.92 139.99,52.16 139.99,50.99 139.77,50.78 139.77,47.87 135.94,44.03 135.94,42.66 135.62,42.34 135.62,41.57 128.11,34.07 121.67,34.07 121.61,34.01 121.61,33.79 121.48,33.66 121.25,33.66 121.15,33.76 121.15,33.97 121.05,34.07 120.74,34.07 120.64,33.97 120.64,33.76 120.54,33.66 120.24,33.66 120.13,33.76 120.13,33.97 120.03,34.07 119.73,34.07 119.63,33.97 119.63,33.76 119.53,33.66 119.22,33.66 119.12,33.76 119.12,33.97 119.02,34.07 118.71,34.07 118.61,33.97 118.61,33.76 118.51,33.66 118.2,33.66 118.1,33.76 118.1,33.97 118,34.07 117.7,34.07 117.59,33.97 117.59,33.76 117.49,33.66 117.19,33.66 117.09,33.76 117.09,33.97 116.99,34.07 116.68,34.07 116.58,33.97 116.58,33.76 116.48,33.66 116.17,33.66 116.07,33.76 116.07,33.97 115.97,34.07 115.66,34.07 115.56,33.97 115.56,33.76 115.46,33.66 115.16,33.66 115.05,33.76 115.05,33.97 114.95,34.07 114.65,34.07 114.55,33.97 114.55,33.76 114.45,33.66 114.14,33.66 114.04,33.76 114.04,33.97 113.94,34.07 113.63,34.07 113.53,33.97 113.53,33.76 113.43,33.66 113.12,33.66 113.02,33.76 113.02,33.97 112.92,34.07 112.62,34.07 112.51,33.97 112.51,33.76 112.41,33.66 112.11,33.66 112.01,33.76 112.01,33.97 111.91,34.07 111.6,34.07 111.5,33.97 111.5,33.76 111.4,33.66 111.09,33.66 110.99,33.76 110.99,33.97 110.89,34.07 110.58,34.07 110.48,33.97 110.48,33.76 110.38,33.66 110.08,33.66 109.97,33.76 109.97,33.97 109.87,34.07 109.57,34.07 109.47,33.97 109.47,33.76 109.37,33.66 109.06,33.66 108.96,33.76 108.96,33.97 108.86,34.07 108.55,34.07 108.45,33.97 108.45,33.76 108.35,33.66 107.81,33.66 97.76,23.61 97.76,16.88 97.63,16.75 97.37,16.75 97.24,16.88 v2(97.24,18.01)
  BOTTOM w0.076: UC1.AM43 144.59,55.94 144.41,55.75 144.37,55.75 v2(144.34,55.72)
  BOTTOM w0.102: v2(97.24,18.01) 96.87,18.01 96.4,17.54 96.4,16.43 JDIMM1.59
DDR_A_D51: length 82.2
  IN2 w0.102: v2(143.44,55.67) 143.18,55.67 142.62,55.11 142.17,55.11 141.74,54.69 141.34,54.69 141.04,54.39 141.04,53.5 139.55,52.01 139.55,50.96 139.52,50.94 139.52,48.04 135.49,44.02 135.49,43.04 134.68,42.22 134.68,42.08 135.1,41.65 135.1,41.51 134.89,41.29 134.74,41.29 134.32,41.72 134.18,41.72 133.96,41.5 133.96,41.36 134.38,40.93 134.38,40.79 134.17,40.58 134.02,40.58 133.6,41 133.46,41 133.24,40.78 133.24,40.64 133.66,40.22 133.66,40.07 133.45,39.86 133.3,39.86 132.88,40.28 132.74,40.28 132.52,40.06 132.52,39.92 132.94,39.5 132.94,39.35 132.73,39.14 132.59,39.14 132.16,39.56 132.02,39.56 131.19,38.73 131.19,38.59 131.58,38.2 131.58,38.06 131.36,37.84 131.22,37.84 130.83,38.23 130.69,38.23 130.47,38.01 130.47,37.87 130.86,37.48 130.86,37.34 130.64,37.12 130.5,37.12 130.11,37.51 129.97,37.51 128.85,36.4 128.85,36.25 129.23,35.88 129.23,35.73 129.01,35.52 128.87,35.52 128.49,35.89 128.35,35.89 128.14,35.68 128.14,35.53 128.51,35.16 128.51,35.01 128.29,34.8 128.15,34.8 127.78,35.17 127.63,35.17 126.84,34.39 108.08,34.39 96.77,23.07 96.77,19.71 96.94,19.53 v2(97.24,19.53)
  BOTTOM w0.076: v2(143.44,55.67) 143.71,55.94 UC1.AM45
  BOTTOM w0.102: v2(97.24,19.53) 96.07,18.36 96.07,17.75 95.8,17.48 JDIMM1.57
DDR_A_D52: length 82.5
  IN2 w0.102: v2(143.45,56.97) 143.17,57.26 142.36,57.26 142.1,57 142.1,55.66 141.49,55.04 140.64,55.04 140.04,54.44 140.04,53.41 139.29,52.67 139.29,51.12 139.25,51.08 139.25,48.25 135.21,44.21 135.21,43.2 126.71,34.7 107.95,34.7 96.44,23.19 96.44,11.37 96.58,11.23 96.8,11.23 v2(96.93,11.35)
  BOTTOM w0.076: UC1.AK45 143.72,57.24 v2(143.45,56.97)
  BOTTOM w0.102: v2(96.93,11.35) 95.5,9.93 JDIMM1.56
DDR_A_D53: length 84.5
  IN2 w0.102: v2(96.93,9.83) 96.12,10.63 96.12,23.33 107.82,35.02 126.54,35.02 134.92,43.41 134.92,44.34 138.62,48.03 138.62,50.86 139.1,51.34 139.1,54.38 140.12,55.4 140.12,57 141.16,58.04 143.26,58.04 v2(144.34,56.96)
  BOTTOM w0.076: v2(144.34,56.96) 144.62,57.24 UC1.AK43
  BOTTOM w0.102: JDIMM1.58 96.1,9.12 96.81,9.83 v2(96.93,9.83)
DDR_A_D54: length 84.5
  IN2 w0.102: v2(99.7,9.83) 101,9.83 101.13,9.96 101.13,10.35 101.25,10.48 101.97,10.48 102.1,10.61 102.1,12.8 101.97,12.93 101.06,12.93 100.75,13.24 100.75,14.14 99.35,15.54 99.35,23.01 108.46,32.12 122.68,32.12 123.06,32.49 128.78,32.49 137.16,40.87 137.16,42.16 137.42,42.43 137.54,42.43 143.11,48.01 143.11,50.34 143.25,50.48 143.25,52.74 143.8,53.29 145.43,53.29 145.83,53.7 145.83,55.44 145.98,55.59 v2(146.26,55.59)
  BOTTOM w0.076: UC1.AM40 146.61,55.94 v2(146.26,55.59)
  BOTTOM w0.102: JDIMM1.68 99.1,9.62 99.3,9.83 v2(99.7,9.83)
DDR_A_D55: length 84.3
  IN2 w0.102: v2(145.35,55.71) 145.35,55.6 144.45,54.7 144.25,54.7 144.02,54.47 144.02,53.79 142.86,52.63 142.86,52.43 142.63,52.2 142.33,52.2 142.06,51.93 142.06,48.04 136.84,42.82 136.84,41.01 128.64,32.81 122.92,32.81 122.55,32.44 108.32,32.44 99,23.12 99,15.43 100.43,14.01 100.43,12.85 100.67,12.61 101.65,12.61 101.78,12.48 101.78,10.93 101.65,10.8 100.19,10.8 100.06,10.93 100.06,11.23 99.93,11.35 v2(99.7,11.35)
  BOTTOM w0.076: v2(145.35,55.71) 145.58,55.94 UC1.AM42
  BOTTOM w0.102: v2(99.7,11.35) 100.13,10.92 100.13,9.65 99.7,9.21 JDIMM1.70
DDR_A_D56: length 60.8
  IN1 w0.102: v2(139.05,11.14) 139.48,10.71 141.27,10.71 141.37,10.8 141.37,11.19 141.27,11.29 140.69,11.29 140.59,11.39 140.59,11.69 140.69,11.8 141.27,11.8 141.37,11.9 141.37,12.19 141.24,12.32 140.62,12.32 140.5,12.44 140.5,12.7 140.62,12.82 141.24,12.82 141.37,12.95 141.37,13.22 141.24,13.35 140.46,13.35 140.33,13.47 140.33,13.73 140.46,13.85 141.24,13.85 141.37,13.98 141.37,20.77 136.93,25.21 136.93,42.84 139.89,45.8 139.89,52.83 140.4,53.34 140.85,53.34 141.08,53.57 141.08,54.42 141.34,54.69 141.51,54.69 142.11,55.28 142.11,55.84 v2(142.49,56.21)
  BOTTOM w0.076: UC1.AM46 142.76,55.94 v2(142.49,56.21)
  BOTTOM w0.102: JDIMM1.192 138.7,9.29 138.62,9.37 138.62,10.71 v2(139.05,11.14)
DDR_A_D57: length 60.6
  IN1 w0.102: v2(142.49,56.86) 142.86,56.49 142.86,55.41 141.91,54.45 141.91,53.51 141.55,53.15 140.54,53.15 140.14,52.76 140.14,50 140.7,49.44 140.7,49 140.17,48.46 140.17,45.64 137.25,42.72 137.25,25.34 141.69,20.9 141.69,20.16 141.79,20.06 142.29,20.06 142.39,19.96 142.39,19.65 142.29,19.55 141.79,19.55 141.69,19.45 141.69,19.15 141.79,19.04 142.29,19.04 142.39,18.94 142.39,18.64 142.29,18.54 141.79,18.54 141.69,18.43 141.69,18.13 141.79,18.03 142.29,18.03 142.39,17.93 142.39,17.62 142.29,17.52 141.79,17.52 141.69,17.42 141.69,10.25 141.06,9.61 v2(139.05,9.61)
  BOTTOM w0.076: v2(142.49,56.86) 142.87,57.24 UC1.AK46
  BOTTOM w0.102: JDIMM1.194 139.3,9.36 v2(139.05,9.61)
DDR_A_D58: length 57.8
  IN1 w0.102: v2(137.22,18.01) 137.77,18.01 137.87,18.11 137.87,21.64 135.07,24.44 135.07,30.23 134.97,30.33 134.53,30.33 134.43,30.43 134.43,30.74 134.53,30.84 134.97,30.84 135.07,30.94 135.07,31.25 134.97,31.35 134.53,31.35 134.43,31.45 134.43,31.75 134.53,31.86 134.97,31.86 135.07,31.96 135.07,32.26 134.97,32.36 134.53,32.36 134.43,32.46 134.43,32.77 134.53,32.87 134.97,32.87 135.07,32.97 135.07,33.28 134.97,33.38 134.53,33.38 134.43,33.48 134.43,33.79 134.53,33.89 134.97,33.89 135.07,33.99 135.07,34.29 134.97,34.4 134.53,34.4 134.43,34.5 134.43,34.8 134.53,34.9 134.97,34.9 135.07,35 135.07,35.26 134.97,35.36 134.53,35.36 134.43,35.46 134.43,35.77 134.53,35.87 134.97,35.87 135.07,35.97 135.07,36.27 134.97,36.37 134.53,36.37 134.43,36.48 134.43,36.78 134.53,36.88 134.97,36.88 135.07,36.98 135.07,37.29 134.97,37.39 134.53,37.39 134.43,37.49 134.43,37.8 134.53,37.9 134.97,37.9 135.07,38 135.07,38.31 134.97,38.41 134.53,38.41 134.43,38.51 134.43,38.81 134.53,38.91 134.97,38.91 135.07,39.02 135.07,39.32 134.97,39.42 134.53,39.42 134.43,39.52 134.43,39.83 134.53,39.93 134.97,39.93 135.07,40.03 135.07,40.34 134.97,40.44 134.53,40.44 134.43,40.54 134.43,40.85 134.53,40.95 134.97,40.95 135.07,41.05 135.07,41.35 134.97,41.45 134.53,41.45 134.43,41.56 134.43,41.86 134.53,41.96 134.97,41.96 135.07,42.06 135.07,43.82 138.55,47.3 138.55,48.38 138.72,48.55 138.72,52.07 138.6,52.18 138.6,54.42 139.42,55.23 139.77,55.23 140.18,55.64 v2(140.58,55.64)
  BOTTOM w0.076: UC1.AM49 140.88,55.94 v2(140.58,55.64)
  BOTTOM w0.102: v2(137.22,18.01) 136.57,18.01 136,17.44 JDIMM1.183
DDR_A_D59: length 57.4
  IN1 w0.102: v2(136.09,9.61) 135.36,10.34 135.36,12.2 135.71,12.55 135.71,15.31 136.03,15.63 136.03,20.94 133.47,23.49 133.47,43.42 137.73,47.68 137.73,48.3 136.91,49.12 136.91,52.74 137.2,53.02 137.2,57.1 137.77,57.67 139.34,57.67 139.72,57.29 140.24,57.29 v2(140.58,56.94)
  BOTTOM w0.076: UC1.AK49 140.88,57.24 v2(140.58,56.94)
  BOTTOM w0.102: v2(136.09,9.61) 135.7,9.23 JDIMM1.182
DDR_A_D60: length 59.5
  IN1 w0.102: v2(139.14,19.53) 139.42,19.53 139.54,19.41 139.54,15.77 139.67,15.64 140.61,15.64 140.74,15.77 140.74,16.01 140.63,16.11 140.12,16.11 140.01,16.21 140.01,16.52 140.12,16.62 140.63,16.62 140.74,16.72 140.74,17.02 140.63,17.12 140.12,17.12 140.01,17.23 140.01,17.53 140.12,17.63 140.61,17.63 140.74,17.76 140.74,18.01 140.61,18.14 140.12,18.14 140.01,18.24 140.01,18.55 140.12,18.65 140.63,18.65 140.74,18.75 140.74,19.06 140.63,19.16 140.12,19.16 139.99,19.28 139.99,19.54 140.12,19.66 140.63,19.66 140.74,19.77 140.74,20.05 140.61,20.17 139.71,20.17 139.58,20.3 139.58,20.55 139.71,20.68 139.9,20.68 140.03,20.81 140.03,21.06 139.9,21.19 139.71,21.19 139.58,21.32 139.58,21.66 136.29,24.95 136.29,43.78 139.41,46.89 139.41,52.97 140,53.57 140,54.54 140.36,54.89 140.99,54.89 141.54,55.44 v2(141.54,55.62)
  BOTTOM w0.076: UC1.AM48 141.86,55.94 v2(141.54,55.62)
  BOTTOM w0.102: v2(139.14,19.53) 138.4,18.8 JDIMM1.191
DDR_A_D61: length 58.8
  IN1 w0.102: v2(141.54,56.92) 141.91,56.55 141.91,55.37 141.45,54.91 141.3,54.91 141.09,54.71 140.43,54.71 140.19,54.47 140.19,53.41 139.66,52.88 139.66,46.76 136.61,43.71 136.61,25.08 141.05,20.63 141.05,15.45 140.93,15.33 140.22,15.33 139.9,15.01 139.9,12.38 139.77,12.25 139.26,12.25 139.13,12.38 139.13,18 v2(139.14,18.01)
  BOTTOM w0.076: UC1.AK48 141.86,57.24 v2(141.54,56.92)
  BOTTOM w0.102: JDIMM1.193 139,17.87 v2(139.14,18.01)
DDR_A_D62: length 57.2
  IN1 w0.102: v2(139.63,55.62) 139.36,55.62 139.15,55.83 139.15,56.46 138.99,56.63 138.52,56.63 138.24,56.35 138.24,52.13 137.87,51.77 137.87,48.86 138.25,48.48 138.25,47.41 134.15,43.31 134.15,42.81 134.11,42.77 134.11,29.92 134.21,29.82 134.65,29.82 134.75,29.72 134.75,29.42 134.65,29.31 134.21,29.31 134.11,29.21 134.11,28.91 134.21,28.81 134.65,28.81 134.75,28.71 134.75,28.4 134.65,28.3 134.21,28.3 134.11,28.2 134.11,27.89 134.21,27.79 134.65,27.79 134.75,27.69 134.75,27.38 134.65,27.28 134.21,27.28 134.11,27.18 134.11,26.88 134.21,26.77 134.65,26.77 134.75,26.67 134.75,26.37 134.65,26.27 134.21,26.27 134.11,26.17 134.11,25.86 134.21,25.76 134.65,25.76 134.75,25.66 134.75,25.35 134.65,25.25 134.21,25.25 134.11,25.15 134.11,23.98 134.38,23.71 134.52,23.71 134.87,24.05 135.01,24.05 135.22,23.83 135.22,23.69 134.88,23.35 134.88,23.2 135.1,22.99 135.24,22.99 135.58,23.33 135.73,23.33 135.94,23.11 135.94,22.97 135.6,22.63 135.6,22.49 135.82,22.27 135.96,22.27 136.3,22.61 136.45,22.61 136.66,22.4 136.66,22.25 136.32,21.91 136.32,21.77 136.76,21.32 137.42,21.32 137.55,21.2 137.55,20.94 137.42,20.81 136.76,20.81 136.66,20.71 136.66,19.74 136.86,19.53 v2(137.22,19.53)
  BOTTOM w0.076: v2(139.63,55.62) 139.96,55.94 UC1.AM51
  BOTTOM w0.102: v2(137.22,19.53) 135.4,17.71 JDIMM1.181
DDR_A_D63: length 55.9
  IN1 w0.102: v2(139.63,56.92) 139.1,57.45 137.81,57.45 137.41,57.05 137.41,52.88 137.69,52.6 137.69,48.71 138.01,48.39 138.01,47.6 133.79,43.38 133.79,23.83 136.34,21.27 136.34,15.5 136.03,15.18 136.03,12.42 135.68,12.07 135.68,11.54 v2(136.09,11.14)
  BOTTOM w0.076: UC1.AK51 139.72,56.92 v2(139.63,56.92)
  BOTTOM w0.102: v2(136.09,11.14) 135.1,10.15 JDIMM1.180
DDR_A_DQS0: length 58.6
  IN1 w0.102: v2(128.02,54.42) 128.02,54.12 128.34,53.8 128.34,53.26 127.81,52.73 127.81,50.89 121.93,45.01 121.93,44.33 121.71,44.11 121.34,44.11 121.21,43.98 121.21,43.73 121.34,43.6 121.71,43.6 121.93,43.38 121.93,42.9 121.71,42.67 121.33,42.67 121.22,42.57 121.22,42.27 121.33,42.17 121.71,42.17 121.93,41.94 121.93,41.47 121.71,41.24 121.33,41.24 121.22,41.14 121.22,40.84 121.33,40.73 121.71,40.73 121.93,40.51 121.93,40.03 121.71,39.81 121.33,39.81 121.22,39.71 121.22,39.4 121.33,39.3 121.71,39.3 121.93,39.08 121.93,38.6 121.71,38.38 121.33,38.38 121.22,38.28 121.22,37.97 121.33,37.87 121.71,37.87 121.93,37.65 121.93,37.03 121.71,36.8 121.31,36.8 121.21,36.7 121.21,36.4 121.31,36.3 121.71,36.3 121.93,36.07 121.93,35.6 121.71,35.37 121.45,35.37 121.33,35.25 121.33,34.99 121.45,34.86 121.71,34.86 121.93,34.64 121.93,21.6 122.75,20.78 122.75,19.72 122.54,19.51 122.15,19.51 122.03,19.39 122.03,19.2 v2(122.08,19.15)
  BOTTOM w0.076: 129.88,57.51 129.9,57.51 129.9,57.52 130.3,57.52 130.54,57.76 132.24,57.76 132.29,57.78 arc(132.31,57.8) 132.33,57.81 arc(132.39,57.84) 132.46,57.87 arc(132.51,57.87) 132.55,57.85 arc(132.64,57.8) 132.74,57.76 arc(132.87,57.75) 133,57.81 arc(133.03,57.83) 133.07,57.84 133.28,57.81 arc(133.35,57.78) 133.37,57.71 133.37,57.63 arc(133.35,57.58) 133.3,57.55 UC1.AJ62
  BOTTOM w0.102: JDIMM1.137 122.2,16.43 122.2,17.38 121.96,17.62 121.96,17.89 121.61,18.25 121.61,19.38 121.75,19.52 121.96,19.52 122.08,19.4 v2(122.08,19.15) ; v2(128.02,54.42) 127.98,54.38 127.74,54.38 127.62,54.5 127.62,55.46 129.67,57.51 129.88,57.51
DDR_A_DQS1: length 84.1
  IN2 w0.102: v2(130.47,54.21) 130.61,54.21 130.82,54 130.82,53.61 121.69,44.48 102.97,44.48 82.68,24.19 82.68,21.38 81.53,20.22 81.53,11.25 81.76,11.02 82.13,11.02 82.32,10.83 v2(82.32,10.82)
  BOTTOM w0.076: v2(130.47,54.21) 130.47,54.46 130.34,54.58 130.34,54.83 131.02,55.51 132.13,55.51 132.14,55.5 arc(132.2,55.51) 132.25,55.53 arc(132.46,55.58) 132.68,55.54 arc(132.76,55.51) 132.84,55.5 133.15,55.5 133.53,55.12 UC1.AN61
  BOTTOM w0.102: v2(82.32,10.82) 82.14,11 81.64,11 81.48,10.84 81.48,10.46 82.3,9.64 JDIMM1.12
DDR_A_DQS2: length 55.6
  IN1 w0.102: v2(134.93,54.96) 134.93,55.07 134.76,55.23 134.64,55.23 133.91,54.5 133.91,52.8 131.36,50.25 131.36,49.83 129.66,48.12 129.66,47.25 126.16,43.75 126.16,22.6 127.9,20.86 127.9,15.46 127.54,15.1 127.54,14.14 127.32,13.92 126.79,13.92 126.66,13.79 126.66,13.53 126.79,13.41 127.32,13.41 127.54,13.18 127.54,12.3 127.94,11.9 127.94,11.01 127.71,10.79 127.29,10.79 127.17,10.66 v2(127.17,10.58)
  BOTTOM w0.076: v2(134.93,54.96) 134.93,55.06 135.16,55.29 UC1.AN58
  BOTTOM w0.102: JDIMM1.154 127.3,9.12 127.01,9.41 127.01,9.58 126.72,9.87 126.72,10.74 126.81,10.82 127.04,10.82 127.17,10.69 v2(127.17,10.58)
DDR_A_DQS3: length 81.3
  IN2 w0.102: v2(137.78,55.62) 137.67,55.73 137.52,55.73 137.39,55.6 137.39,55.52 137.42,55.49 137.42,55.13 137.41,55.12 137.41,54.81 137.42,54.8 137.42,54.48 137.41,54.47 137.41,54.16 137.42,54.15 137.42,53.82 137.41,53.81 137.41,53.52 137.42,53.5 137.42,53.25 135.29,51.12 134.05,51.12 132.79,49.86 132.79,49.6 123.87,40.67 104.76,40.67 88.31,24.23 88.3,24.23 87.7,23.63 87.7,23.46 87.48,23.24 87.29,23.24 87.17,23.11 87.17,22.86 87.29,22.73 87.48,22.73 87.7,22.51 87.7,22.03 87.48,21.81 87.21,21.81 87.11,21.71 87.11,21.4 87.21,21.3 87.48,21.3 87.7,21.08 87.7,20.6 87.48,20.37 87.25,20.37 87.12,20.25 87.12,19.99 87.25,19.87 87.48,19.87 87.7,19.64 87.7,16.27 87.51,16.08 87.51,14.3 87.68,14.14 87.76,14.14 v2(88,14.38)
  BOTTOM w0.076: v2(137.78,55.62) 137.67,55.73 137.54,55.73 137.22,55.41 UC1.AN55
  BOTTOM w0.102: v2(88,14.38) 87.74,14.12 87.51,14.12 87.13,14.5 87.13,15.14 87.4,15.41 87.4,16.43 JDIMM1.29
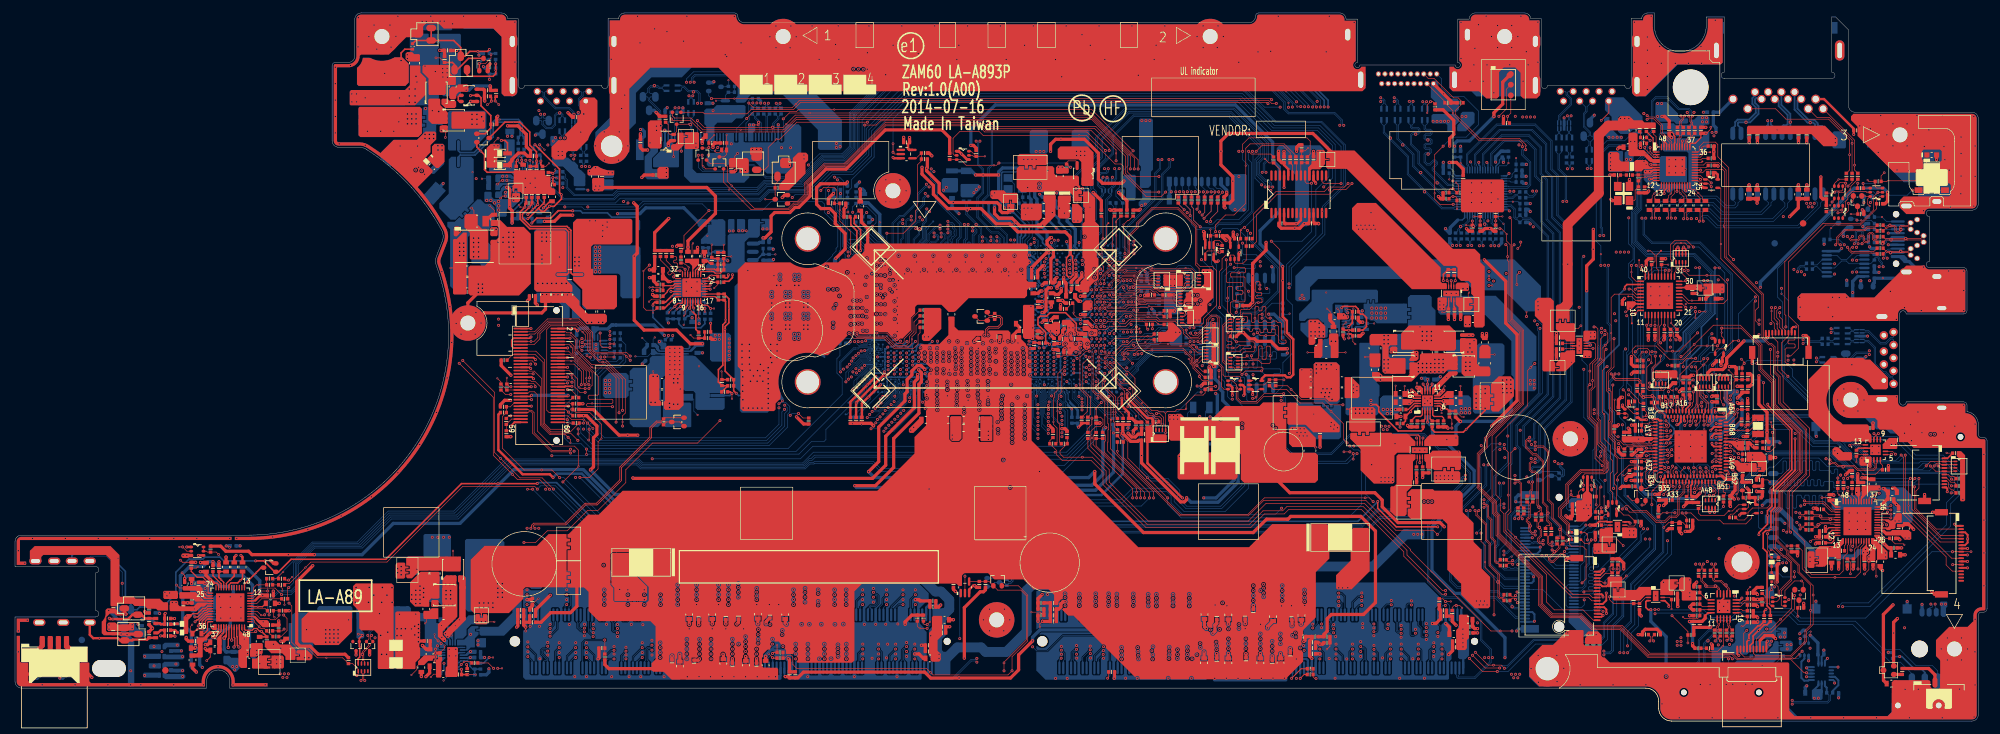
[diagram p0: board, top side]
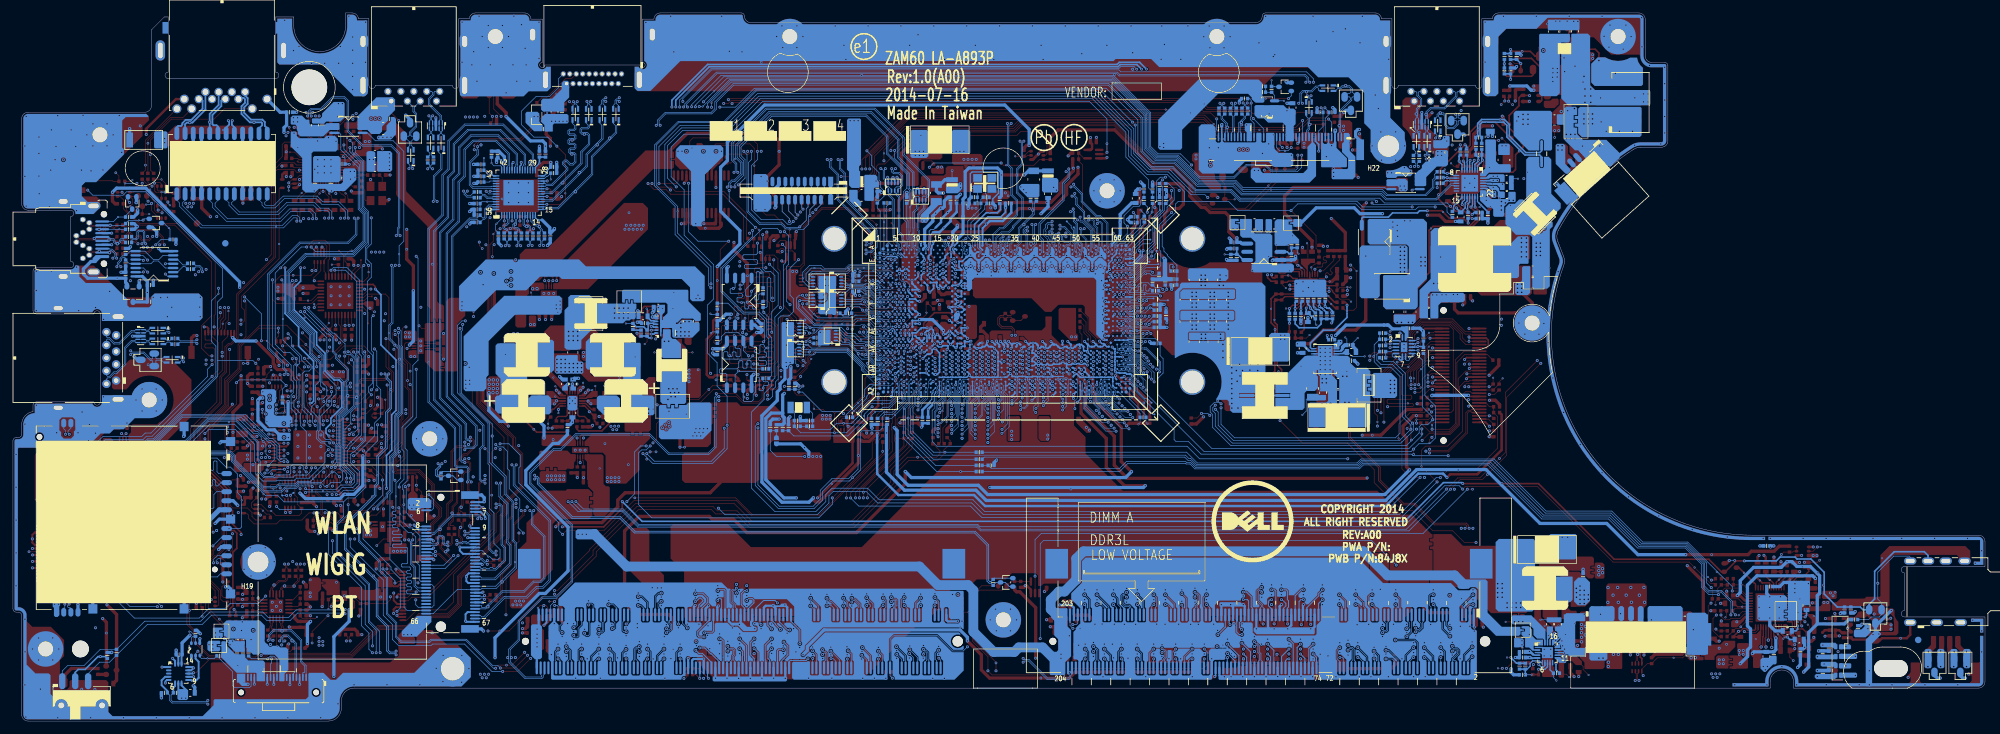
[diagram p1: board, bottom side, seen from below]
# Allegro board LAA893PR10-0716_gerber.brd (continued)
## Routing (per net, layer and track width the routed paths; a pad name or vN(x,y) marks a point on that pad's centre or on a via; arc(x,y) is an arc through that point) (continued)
DDR_A_DQS4: length 50.1
  IN1 w0.102: v2(132.46,47.88) 132.63,47.88 132.81,47.7 132.81,47.27 131.69,46.15 131.69,44.19 130.33,42.83 130.33,34.6 130.58,34.35 131.05,34.35 131.3,34.11 131.3,33.88 131.19,33.78 129.82,33.78 129.6,33.56 129.6,33.08 129.82,32.86 131.19,32.86 131.3,32.76 131.3,32.45 131.19,32.35 129.82,32.35 129.6,32.13 129.6,31.65 129.82,31.42 131.19,31.42 131.3,31.32 131.3,30.97 131.19,30.87 130.99,30.87 130.74,30.62 130.74,30.19 130.99,29.95 131.19,29.95 131.3,29.84 131.3,22.5 133.14,20.65 133.14,19.71 133.01,19.58 132.86,19.58 132.65,19.78 v2(132.65,19.91)
  BOTTOM w0.076: v2(132.46,47.88) 132.52,47.94 132.75,47.94 132.88,47.81 133.48,47.81 134.74,49.06 135.58,49.91 135.58,50.41 135.8,50.63 135.8,51 135.79,51.02 arc(135.78,51.04) 135.76,51.06 arc(135.73,51.12) 135.71,51.19 arc(135.71,51.24) 135.73,51.28 arc(135.78,51.37) 135.82,51.47 arc(135.83,51.6) 135.76,51.73 arc(135.74,51.76) 135.74,51.8 135.77,52.01 arc(135.8,52.08) 135.87,52.1 135.95,52.1 arc(136,52.08) 136.02,52.03 UC1.AW57
  BOTTOM w0.102: v2(132.65,19.91) 132.69,19.91 132.98,19.63 133.1,19.63 133.11,19.62 133.18,19.62 133.41,19.39 133.41,18.2 132.95,17.74 132.31,17.74 132.2,17.63 132.2,17.44 132.4,17.24 JDIMM1.171
DDR_A_DQS5: length 76.6
  IN2 w0.102: v2(93.1,14.33) 93.1,14.17 93.2,14.07 93.28,14.07 93.38,13.97 93.67,13.97 93.74,14.04 93.74,15.32 93.63,15.42 93.2,15.42 92.95,15.67 92.95,16.09 93.2,16.34 93.66,16.34 93.79,16.47 93.79,16.83 93.66,16.95 93.23,16.95 92.97,17.21 92.97,17.66 93.2,17.89 93.2,18.23 92.97,18.47 92.97,19.07 93.1,19.2 93.11,19.2 93.24,19.32 93.24,19.65 92.99,19.9 92.99,20.49 93.25,20.76 93.25,21.08 93.13,21.21 93.1,21.21 92.97,21.33 92.97,23.93 106.24,37.2 125.37,37.2 132.37,44.2 132.37,44.49 136.13,48.25 136.74,48.25 137.08,47.91 137.19,47.91 v2(137.34,48.05)
  BOTTOM w0.076: UC1.AW53 138.39,51.92 138.32,51.92 138.23,51.83 138.23,51.66 arc(138.23,51.53) 138.2,51.4 arc(138.18,51.33) 138.15,51.27 arc(138.13,51.18) 138.17,51.1 arc(138.24,50.93) 138.22,50.75 138.14,50.54 138.14,50.43 137.85,50.14 137.85,49.15 136.94,48.24 136.94,48 137.03,47.91 137.2,47.91 v2(137.34,48.05)
  BOTTOM w0.102: v2(93.1,14.33) 93.1,14.15 93.02,14.07 92.93,14.07 92.86,13.99 92.62,13.99 92.49,14.12 92.49,15.13 92.8,15.44 92.8,16.43 JDIMM1.47
DDR_A_DQS6: length 83.9
  IN2 w0.076: 145.18,56.32 144.93,56.06 144.93,55.47 144.5,55.04 144.13,55.04 143.93,54.84 143.44,54.84 143.36,54.75 143.34,54.75 143.14,54.55 143.14,54.53 143.11,54.51 143.11,53.59 142.58,53.06 142.43,53.06 141.69,52.32 141.69,49.87 140.22,48.4 140.22,47.48 140.23,47.47 140.23,47.32 136.33,43.42 136.33,42.1
  IN2 w0.102: v2(98.43,10.97) 98.71,11.25 98.97,11.25 99.21,11.5 99.21,12.58 98.47,13.32 98.47,13.47 98.25,13.69 97.62,13.69 97.5,13.82 97.5,14.07 97.62,14.2 98.25,14.2 98.47,14.42 98.47,23.31 108.1,32.94 121.78,32.94 122.15,33.32 128.38,33.32 136.33,41.27 136.33,42.1 ; v2(145.35,56.32) 145.18,56.32
  BOTTOM w0.076: v2(145.35,56.32) 145.62,56.59 UC1.AL42
  BOTTOM w0.102: JDIMM1.64 97.9,9.25 97.68,9.47 97.68,11.03 97.85,11.21 98.19,11.21 v2(98.43,10.97)
DDR_A_DQS7: length 58
  IN1 w0.102: v2(137.78,10.76) 137.78,10.77 137.54,11.02 136.99,11.02 136.75,11.26 136.75,12.61 136.99,12.86 138.28,12.86 138.4,12.98 138.4,13.32 138.28,13.44 137.4,13.44 137.15,13.69 137.15,14.12 137.4,14.37 138.28,14.37 138.38,14.47 138.38,21.85 135.58,24.65 135.58,43.84 138.9,47.16 138.9,54.43 139.35,54.88 139.74,54.88 140.15,55.28 140.82,55.28 140.98,55.43 140.98,56.01 140.7,56.29 v2(140.58,56.29)
  BOTTOM w0.076: UC1.AL49 140.88,56.59 v2(140.58,56.29)
  BOTTOM w0.102: v2(137.78,10.76) 137.5,11.03 137.42,11.03 137.28,10.9 137.28,9.49 137.5,9.27 JDIMM1.188
DDR_A_DQS#0: length 58.6
  IN1 w0.102: v2(127.57,54) 127.85,54 128.14,53.71 128.14,53.35 127.6,52.82 127.6,50.98 121.72,45.09 121.72,44.42 121.62,44.32 121.25,44.32 121,44.07 121,43.64 121.25,43.39 121.62,43.39 121.72,43.29 121.72,42.98 121.62,42.88 121.24,42.88 121.02,42.66 121.02,42.18 121.24,41.96 121.62,41.96 121.72,41.86 121.72,41.55 121.62,41.45 121.24,41.45 121.02,41.23 121.02,40.75 121.24,40.53 121.62,40.53 121.72,40.42 121.72,40.12 121.62,40.02 121.24,40.02 121.02,39.79 121.02,39.32 121.24,39.09 121.62,39.09 121.72,38.99 121.72,38.69 121.62,38.58 121.24,38.58 121.02,38.36 121.02,37.88 121.24,37.66 121.62,37.66 121.72,37.56 121.72,37.11 121.62,37.01 121.23,37.01 121,36.79 121,36.31 121.23,36.09 121.62,36.09 121.72,35.99 121.72,35.68 121.62,35.58 121.37,35.58 121.12,35.33 121.12,34.9 121.37,34.66 121.62,34.66 121.72,34.55 121.72,21.52 122.54,20.7 122.54,19.8 122.45,19.71 122.28,19.71 v2(122.08,19.91)
  BOTTOM w0.076: UC1.AJ61 133.61,57.55 arc(133.56,57.58) 133.54,57.63 133.54,57.71 arc(133.47,57.88) 133.3,57.97 133.09,58 arc(132.98,57.99) 132.89,57.93 arc(132.84,57.91) 132.79,57.92 arc(132.72,57.95) 132.64,57.99 arc(132.54,58.03) 132.42,58.03 arc(132.33,58) 132.24,57.95 132.21,57.94 132.21,57.94 132.2,57.94 130.46,57.94 130.23,57.7 129.9,57.7 129.9,57.71 129.88,57.71
  BOTTOM w0.102: v2(122.08,19.91) 121.89,19.73 121.66,19.73 121.41,19.47 121.41,18.16 121.76,17.81 121.76,17.6 121.6,17.44 JDIMM1.135 ; 129.88,57.71 129.59,57.71 127.42,55.54 127.42,54.41 127.56,54.27 127.56,54.22 127.57,54.21 v2(127.57,54)
DDR_A_DQS#1: length 84
  IN2 w0.102: v2(130.88,54.6) 130.88,54.23 131.02,54.09 131.02,53.52 121.77,44.27 103.06,44.27 82.89,24.11 82.89,21.29 81.73,20.14 81.73,11.34 81.84,11.23 82.18,11.23 82.32,11.37 v2(82.32,11.58)
  BOTTOM w0.076: v2(130.88,54.6) 130.56,54.6 130.51,54.65 130.51,54.76 131.09,55.34 132.12,55.34 arc(132.23,55.34) 132.33,55.38 arc(132.47,55.42) 132.61,55.39 arc(132.72,55.35) 132.84,55.33 133.06,55.33 133.13,55.27 UC1.AN62
  BOTTOM w0.102: v2(82.32,11.58) 82.32,11.37 82.15,11.2 81.55,11.2 81.28,10.93 81.28,10.38 82.1,9.56 82.1,9.39 82.03,9.32 81.77,9.32 81.7,9.25 JDIMM1.10
DDR_A_DQS#2: length 55.6
  IN1 w0.102: v2(134.93,55.62) 134.73,55.42 134.56,55.42 133.72,54.58 133.72,52.88 131.17,50.33 131.17,49.91 129.45,48.18 129.45,47.33 125.95,43.84 125.95,22.51 127.69,20.77 127.69,15.55 127.33,15.19 127.33,14.23 127.23,14.12 126.7,14.12 126.45,13.87 126.45,13.45 126.7,13.2 127.23,13.2 127.33,13.1 127.33,12.21 127.73,11.82 127.73,11.1 127.63,10.99 127.39,10.99 v2(127.17,11.21)
  BOTTOM w0.076: UC1.AM58 135.25,55.94 v2(134.93,55.62)
  BOTTOM w0.102: v2(127.17,11.21) 126.98,11.02 126.72,11.02 126.52,10.82 126.52,9.79 126.81,9.5 126.81,9.35 126.7,9.25 JDIMM1.152
DDR_A_DQS#3: length 81.4
  IN2 w0.102: v2(136.83,55.62) 136.99,55.62 137.17,55.44 137.17,55.43 137.21,55.4 137.21,55.22 137.2,55.21 137.2,54.72 137.21,54.71 137.21,54.57 137.2,54.56 137.2,54.08 137.21,54.06 137.21,53.91 137.2,53.9 137.2,53.43 137.21,53.42 137.21,53.34 135.2,51.33 133.96,51.33 132.57,49.95 132.57,49.67 123.78,40.88 104.67,40.88 88.23,24.43 88.21,24.43 87.5,23.72 87.5,23.55 87.39,23.45 87.21,23.45 86.96,23.2 86.96,22.77 87.21,22.52 87.39,22.52 87.5,22.42 87.5,22.12 87.39,22.01 87.13,22.01 86.9,21.79 86.9,21.31 87.13,21.09 87.39,21.09 87.5,20.99 87.5,20.68 87.39,20.58 87.16,20.58 86.91,20.33 86.91,19.91 87.16,19.66 87.39,19.66 87.5,19.56 87.5,16.36 87.3,16.17 87.3,14.22 87.59,13.93 87.86,13.93 v2(88,13.79)
  BOTTOM w0.076: v2(136.83,55.62) 137.02,55.62 137.22,55.81 UC1.AM55
  BOTTOM w0.102: v2(88,13.79) 87.87,13.92 87.43,13.92 86.93,14.42 86.93,15.29 86.8,15.42 86.8,16.43 JDIMM1.27
DDR_A_DQS#4: length 50.1
  IN1 w0.102: v2(132.65,19.15) 132.87,19.37 133.09,19.37 133.35,19.62 133.35,20.74 131.5,22.58 131.5,29.93 131.28,30.15 131.07,30.15 130.95,30.28 130.95,30.53 131.07,30.66 131.28,30.66 131.5,30.89 131.5,31.41 131.28,31.63 129.91,31.63 129.81,31.73 129.81,32.04 129.91,32.14 131.28,32.14 131.5,32.36 131.5,32.84 131.28,33.07 129.91,33.07 129.81,33.17 129.81,33.47 129.91,33.57 131.28,33.57 131.5,33.8 131.5,34.2 131.14,34.56 130.67,34.56 130.54,34.69 130.54,42.75 131.9,44.11 131.9,46.06 133.02,47.18 133.02,47.79 132.8,48.01 132.8,48.22 v2(132.92,48.34)
  BOTTOM w0.076: v2(132.92,48.34) 132.87,48.29 132.87,48.06 132.95,47.98 133.42,47.98 134.62,49.18 135.42,49.98 135.42,50.48 135.63,50.7 135.63,50.94 135.62,50.97 arc(135.58,51.06) 135.55,51.15 arc(135.55,51.27) 135.59,51.37 arc(135.63,51.45) 135.66,51.52 arc(135.66,51.57) 135.64,51.62 arc(135.59,51.71) 135.58,51.82 135.6,52.03 arc(135.69,52.2) 135.87,52.27 135.95,52.27 arc(136,52.29) 136.02,52.34 arc(136.02,52.42) UC1.AV57
  BOTTOM w0.102: JDIMM1.169 131.8,17.31 132,17.5 132,17.71 132.22,17.94 132.86,17.94 133.2,18.28 133.2,19.31 133.09,19.42 132.92,19.42 v2(132.65,19.15)
DDR_A_DQS#5: length 76.6
  IN2 w0.102: v2(136.88,47.59) 136.88,47.6 136.88,47.81 136.65,48.04 136.22,48.04 132.58,44.4 132.58,44.11 125.46,36.99 106.32,36.99 93.18,23.84 93.18,21.42 93.18,21.41 93.21,21.41 93.46,21.17 93.46,20.67 93.2,20.41 93.2,19.98 93.45,19.73 93.45,19.24 93.2,18.99 93.18,18.99 93.18,18.98 93.18,18.55 93.41,18.32 93.41,17.8 93.18,17.57 93.18,17.3 93.31,17.16 93.75,17.16 94,16.91 94,16.38 93.75,16.14 93.28,16.14 93.16,16.01 93.16,15.75 93.28,15.63 93.72,15.63 93.94,15.4 93.94,13.89 93.82,13.76 93.36,13.76 93.26,13.66 v2(93.1,13.66)
  BOTTOM w0.076: v2(136.88,47.59) 136.88,47.83 136.77,47.93 136.77,48.31 137.68,49.22 137.68,50.21 137.97,50.5 137.97,50.57 138.06,50.81 arc(138.07,50.91) 138.03,51 arc(137.97,51.17) 138.01,51.35 arc(138.03,51.39) 138.04,51.44 arc(138.06,51.55) 138.07,51.66 138.07,51.81 138.07,51.81 138.07,51.9 138.45,52.28 UC1.AV53
  BOTTOM w0.102: v2(93.1,13.66) 92.97,13.79 92.53,13.79 92.29,14.04 92.29,15.33 92.2,15.41 92.2,16.43 JDIMM1.45
DDR_A_DQS#6: length 83.9
  IN2 w0.076: 144.72,56.14 144.75,56.11 144.75,55.55 144.42,55.22 144.05,55.22 143.85,55.02 143.37,55.02 143.28,54.93 143.27,54.93 142.96,54.62 142.96,54.61 142.93,54.58 142.93,53.67 142.5,53.24 142.35,53.24 141.51,52.4 141.51,49.95 140.04,48.48 140.04,47.41 140.05,47.4 136.14,43.49 136.14,42.12 136.12,42.1
  IN2 w0.102: 136.12,42.1 136.12,41.36 128.29,33.53 122.07,33.53 121.69,33.15 108.02,33.15 98.26,23.4 98.26,14.51 98.16,14.41 97.54,14.41 97.29,14.16 97.29,13.73 97.54,13.48 98.16,13.48 98.26,13.38 98.26,13.24 99.01,12.5 99.01,11.58 98.88,11.46 98.7,11.46 v2(98.43,11.73) ; v2(144.39,56.39) 144.47,56.39 144.72,56.14
  BOTTOM w0.076: UC1.AL43 144.59,56.59 v2(144.39,56.39)
  BOTTOM w0.102: v2(98.43,11.73) 98.11,11.42 97.77,11.42 97.47,11.12 97.47,9.42 97.3,9.25 JDIMM1.62
DDR_A_DQS#7: length 58
  IN1 w0.102: v2(141.54,56.27) 141.17,55.9 141.17,55.36 140.9,55.09 140.22,55.09 139.82,54.69 139.43,54.69 139.11,54.37 139.11,47.1 139.12,47.09 135.79,43.75 135.79,24.74 138.58,21.94 138.58,14.38 138.36,14.16 137.49,14.16 137.36,14.03 137.36,13.78 137.49,13.65 138.36,13.65 138.61,13.4 138.61,12.9 138.36,12.65 137.08,12.65 136.95,12.52 136.95,11.35 137.08,11.22 137.67,11.22 137.78,11.34 v2(137.78,11.52)
  BOTTOM w0.076: v2(141.54,56.27) 141.86,56.59 UC1.AL48
  BOTTOM w0.102: JDIMM1.186 136.9,9.25 137.08,9.42 137.08,10.98 137.33,11.24 137.5,11.24 v2(137.78,11.52)
DDR_A_MA0: length 72.8
  IN2 w0.076: v2(148.78,52.62) 148.64,52.62 148.19,52.17 148.19,46.63 146.34,44.78 146.34,43.01 145.67,42.34 145.67,42.1
  IN2 w0.152: v2(110.86,10.38) 111.29,10.81 111.29,13.44 110.89,13.84 110.89,16.76 109.82,17.83 109.82,21.24 111.95,23.37 130.16,23.37 145.67,38.88 145.67,42.1
  BOTTOM w0.076: v2(148.78,52.62) 149,52.83 UC1.AU36
  BOTTOM w0.152: v2(110.86,10.38) 110.42,9.94 110.42,9.4 110.5,9.32 JDIMM1.98
DDR_A_MA1: length 73.1
  IN2 w0.076: v2(148.78,49.95) 148.55,49.72 148.55,46.31 147.06,44.82 147.06,42.8 146.48,42.21 146.48,42.1
  IN2 w0.152: v2(110.25,18.77) 111.12,19.65 111.12,21.36 112.32,22.56 132.16,22.56 136.7,27.1 136.7,27.31 136.08,27.93 136.08,28.15 136.26,28.33 136.48,28.33 137.1,27.71 137.31,27.71 137.49,27.89 137.49,28.1 136.87,28.72 136.87,28.94 137.05,29.12 137.27,29.12 137.89,28.5 138.1,28.5 138.28,28.68 138.28,28.89 137.66,29.51 137.66,29.73 137.84,29.91 138.06,29.91 138.68,29.29 138.89,29.29 139.07,29.47 139.07,29.68 138.45,30.3 138.45,30.52 138.63,30.7 138.85,30.7 139.47,30.08 139.68,30.08 139.86,30.26 139.86,30.47 139.24,31.09 139.24,31.31 139.42,31.49 139.64,31.49 140.22,30.9 140.4,30.9 140.67,31.18 140.67,31.36 140.14,31.89 140.14,32.21 140.8,32.87 140.8,32.87 146.48,38.54 146.48,42.1
  BOTTOM w0.076: UC1.AY37 148.36,50.37 v2(148.78,49.95)
  BOTTOM w0.152: JDIMM1.97 110.2,17.3 110.73,17.83 110.73,18.52 110.47,18.77 v2(110.25,18.77)
DDR_A_MA2: length 75.9
  IN2 w0.076: 144.1,42.1 144.1,42.4 144.68,42.98 145.02,42.98 145.63,43.59 145.63,44.98 147.48,46.84 147.48,48.74 146.92,49.3 146.92,50.42 147.63,51.13 147.63,53.54 v2(147.76,53.66)
  IN2 w0.152: 144.1,42.1 144.1,39.04 131.19,26.12 122.91,26.12 121.38,24.59 111.02,24.59 107.58,21.15 107.58,18.54 110.43,15.69 110.43,12.36 110.86,11.93 v2(110.86,11.9)
  BOTTOM w0.076: UC1.AR38 148.08,53.99 v2(147.76,53.66)
  BOTTOM w0.152: JDIMM1.96 109.9,10.94 v2(110.86,11.9)
DDR_A_MA3: length 75.8
  IN2 w0.076: v2(148.71,54.47) 149.11,54.07 149.11,53.44 149.24,53.31 149.24,52.5 148.96,52.22 148.65,52.22 148.4,51.97 148.4,46.51 146.56,44.67 146.56,42.79 146.07,42.3 146.07,42.1
  IN2 w0.152: v2(110.25,20.3) 110.68,20.73 110.68,21.53 112.12,22.96 132,22.96 132.83,23.8 132.83,24.01 132.21,24.63 132.21,24.85 132.39,25.03 132.6,25.03 133.22,24.41 133.44,24.41 133.62,24.59 133.62,24.8 133,25.42 133,25.64 133.18,25.82 133.39,25.82 134.01,25.2 134.23,25.2 134.41,25.38 134.41,25.59 133.79,26.21 133.79,26.43 133.97,26.61 134.19,26.61 134.8,25.99 135.02,25.99 135.2,26.17 135.2,26.38 134.58,27 134.58,27.22 134.76,27.4 134.98,27.4 135.59,26.78 135.81,26.78 136.11,27.08 136.11,27.33 135.52,27.92 135.52,28.16 146.07,38.71 146.07,42.1
  BOTTOM w0.076: v2(148.71,54.47) 148.88,54.64 UC1.AP36
  BOTTOM w0.152: v2(110.25,20.3) 109.8,20.3 109.6,20.09 JDIMM1.95
DDR_A_MA4: length 74
  IN2 w0.076: v2(147.2,52.58) 146.49,51.88 146.49,49.1 147.15,48.44 147.15,47.09 142.68,42.62 142.68,42.1
  IN2 w0.152: 142.68,42.1 142.68,38.76 130.85,26.94 122.58,26.94 121.04,25.4 110.68,25.4 106.77,21.49 106.77,18.21 107.13,17.85 107.13,11.53 107.51,11.14 v2(107.56,11.14)
  BOTTOM w0.076: UC1.AU39 147.45,52.83 v2(147.2,52.58)
  BOTTOM w0.152: JDIMM1.92 108.7,10 v2(107.56,11.14)
DDR_A_MA5: length 74.5
  IN2 w0.076: 145.26,42.1 145.26,42.29 146.16,43.19 146.16,44.91 147.99,46.74 147.99,53.1 v2(148.71,53.82)
  IN2 w0.152: v2(108.72,18.77) 109.36,19.4 109.36,21.35 111.78,23.78 126.61,23.78 126.76,23.93 126.76,25.16 126.92,25.31 127.17,25.31 127.32,25.16 127.32,23.93 127.47,23.78 127.73,23.78 127.88,23.93 127.88,25.16 128.03,25.31 128.29,25.31 128.44,25.16 128.44,23.93 128.59,23.78 128.85,23.78 129,23.93 129,25.16 129.15,25.31 129.4,25.31 129.56,25.16 129.56,23.93 129.71,23.78 129.99,23.78 130.12,23.9 130.12,25.05 130.24,25.18 131.39,25.18 145.26,39.05 145.26,42.1
  BOTTOM w0.076: UC1.AR36 149.03,53.82 v2(148.71,53.82)
  BOTTOM w0.152: v2(108.72,18.77) 108.61,18.77 108.04,18.2 108.04,17.8 108.4,17.44 JDIMM1.91
DDR_A_MA6: length 75.4
  IN2 w0.076: 142.27,42.1 142.27,42.69 146.69,47.11 v2(146.69,47.71)
  IN2 w0.152: 142.27,42.1 142.27,38.93 130.68,27.34 122.41,27.34 120.88,25.81 110.51,25.81 106.31,21.6 106.31,17.93 106.43,17.8 106.59,17.8 106.72,17.68 106.72,17.41 106.59,17.28 106.13,17.28 105.98,17.13 105.98,16.88 106.13,16.73 106.59,16.73 106.72,16.6 106.72,16.29 106.59,16.17 106.13,16.17 105.98,16.01 105.98,15.76 106.13,15.61 106.59,15.61 106.72,15.48 106.72,10.45 v2(107.56,9.61)
  BOTTOM w0.076: v2(146.69,47.71) 147.01,48.04 147.01,48.62 146.49,49.14 146.49,51.88 UC1.AV40
  BOTTOM w0.152: v2(107.56,9.61) 107.82,9.61 108.1,9.33 JDIMM1.90
DDR_A_MA7: length 74.5
  IN2 w0.076: v2(147.2,51.23) 146.72,50.76 146.72,49.22 147.33,48.62 147.33,46.98 145.37,45.03 145.37,43.65 144.92,43.19 144.4,43.19 143.7,42.49 143.7,42.1
  IN2 w0.152: 143.7,42.1 143.7,39.21 131.02,26.53 122.75,26.53 121.21,25 110.85,25 107.17,21.32 107.17,18.38 109.41,16.14 109.41,13.3 108.77,12.66 v2(107.56,12.66)
  BOTTOM w0.076: UC1.AW39 147.49,51.53 v2(147.2,51.23)
  BOTTOM w0.152: JDIMM1.86 106.9,12 v2(107.56,12.66)
DDR_A_MA8: length 73.3
  IN2 w0.076: v2(147.31,50.27) 147.43,50.39 147.59,50.39 147.76,50.22 147.76,46.81 145.9,44.94 145.9,43.41 144.85,42.37 144.85,42.1
  IN2 w0.152: 144.85,42.1 144.85,39.22 131.35,25.72 126.56,25.72 126.36,25.51 126.36,24.35 126.19,24.18 125.88,24.18 125.72,24.34 125.72,25.56 125.57,25.72 125.32,25.72 125.17,25.56 125.17,24.34 125.01,24.18 124.76,24.18 124.61,24.34 124.61,25.56 124.45,25.72 124.2,25.72 124.05,25.56 124.05,24.34 123.9,24.18 123.64,24.18 123.49,24.34 123.49,25.56 123.34,25.72 123.08,25.72 122.93,25.56 122.93,24.34 122.78,24.18 111.19,24.18 107.99,20.98 107.99,20.19 108.23,19.95 108.38,19.95 v2(108.72,20.3)
  BOTTOM w0.076: v2(147.31,50.27) 147.31,50.58 UC1.AY39
  BOTTOM w0.152: JDIMM1.89 107.8,17.47 107.63,17.64 107.63,18.62 107.8,18.79 107.8,20.11 107.99,20.3 v2(108.72,20.3)
DDR_A_MA9: length 74.6
  IN2 w0.076: v2(146.66,48.34) 146.66,48.23 146.3,47.86 146.3,47.13 141.83,42.65 141.83,42.3 141.82,42.3 141.82,42.1
  IN2 w0.152: 141.82,42.1 141.82,39.05 130.51,27.75 120.98,27.75 120.8,27.57 120.8,26.34 120.67,26.21 120.34,26.21 120.22,26.34 120.22,27.6 120.06,27.75 119.81,27.75 119.66,27.6 119.66,26.34 119.53,26.21 119.23,26.21 119.1,26.34 119.1,27.6 118.95,27.75 118.69,27.75 118.54,27.6 118.54,26.37 118.39,26.21 118.13,26.21 117.98,26.37 117.98,27.6 117.83,27.75 117.57,27.75 117.42,27.6 117.42,26.37 117.27,26.21 110.35,26.21 105.9,21.77 105.9,20.51 105.69,20.3 v2(105.33,20.3)
  BOTTOM w0.076: v2(146.66,48.34) 146.33,48.68 146.33,52.05 146.33,52.06 146.33,52.14 146.74,52.54 UC1.AU40
  BOTTOM w0.152: JDIMM1.85 106.6,19.37 105.67,20.3 v2(105.33,20.3)
DDR_A_MA10: length 75.5
  IN2 w0.076: v2(149.66,54.31) 149.29,53.94 149.29,53.51 149.47,53.33 149.47,51.2 149.97,50.7 149.97,48.89 150.38,48.49 150.38,46.02 148.69,44.34 148.69,42.1
  IN2 w0.152: v2(114.62,19.94) 114.65,19.94 115.17,20.46 117.43,20.46 117.59,20.31 117.59,19.19 117.74,19.04 117.99,19.04 118.15,19.19 118.15,20.31 118.3,20.46 118.55,20.46 118.7,20.31 118.7,19.19 118.86,19.04 119.11,19.04 119.26,19.19 119.26,20.31 119.42,20.46 119.69,20.46 119.87,20.28 119.87,17.83 120.2,17.5 132.56,17.5 133.13,18.07 133.13,20.54 148.69,36.09 148.69,42.1
  BOTTOM w0.076: v2(149.66,54.31) 149.99,54.64 UC1.AP35
  BOTTOM w0.152: v2(114.62,19.94) 114.11,19.94 113.39,19.23 113.39,17.65 113.2,17.46 JDIMM1.107
DDR_A_MA11: length 74.3
  IN2 w0.076: v2(145.63,51.22) 146.09,50.77 146.09,48.36 145.62,47.89 145.62,47.17 141,42.55 141,42.28 141.01,42.27 141.01,42.1
  IN2 w0.152: 141.01,42.1 141.01,39.39 130.18,28.56 113.21,28.56 113.08,28.43 113.08,27.15 112.95,27.03 110.01,27.03 104.48,21.5 104.48,19.04 104.73,18.79 104.73,17.81 105.04,17.51 105.04,11.69 105.17,11.57 105.65,11.57 105.78,11.69 v2(105.78,11.9)
  BOTTOM w0.076: UC1.AW41 145.94,51.53 v2(145.63,51.22)
  BOTTOM w0.152: JDIMM1.84 106.3,11.38 v2(105.78,11.9)
DDR_A_MA12: length 74.6
  IN2 w0.076: 141.41,42.1 141.41,42.22 141.4,42.23 141.4,42.64 145.98,47.22 145.98,47.9 146.29,48.21 146.29,51.77 v2(145.6,52.46)
  IN2 w0.152: 141.41,42.1 141.41,39.22 130.34,28.16 117.14,28.16 117.02,28.03 117.02,26.75 116.89,26.62 116.46,26.62 116.3,26.77 116.3,28 116.15,28.16 115.9,28.16 115.75,28 115.75,26.77 115.59,26.62 115.31,26.62 115.16,26.77 115.16,28 115.01,28.16 114.75,28.16 114.6,28 114.6,26.77 114.45,26.62 114.2,26.62 114.04,26.77 114.04,28 113.89,28.16 113.64,28.16 113.48,28 113.48,26.77 113.33,26.62 110.18,26.62 104.89,21.34 104.89,19.2 v2(105.33,18.77)
  BOTTOM w0.076: UC1.AU41 145.96,52.83 v2(145.6,52.46)
  BOTTOM w0.152: JDIMM1.83 106,18.5 105.72,18.77 v2(105.33,18.77)
DDR_A_MA13: length 74.2
  IN2 w0.076: v2(149.66,53.66) 149.74,53.58 149.74,51.23 150.35,50.62 150.58,50.62 151.04,50.16 151.04,43.59 149.91,42.46 149.91,42.1
  IN2 w0.152: 149.91,42.1 149.91,35.59 136.54,22.22 136.54,21.05 136.41,20.92 135.24,20.92 135.12,20.8 135.12,20.49 135.24,20.36 136.67,20.36 136.8,20.24 136.8,19.93 136.67,19.81 135.27,19.81 135.12,19.65 135.12,19.4 135.27,19.25 136.67,19.25 136.79,19.12 136.79,18.81 136.67,18.69 135.27,18.69 135.12,18.54 135.12,17.56 133.79,16.23 117.63,16.23 117.48,16.08 117.48,15.82 117.33,15.67 117.07,15.67 116.92,15.82 116.92,16.08 116.77,16.23 116.25,16.23 116.13,16.1 116.13,15.55 116.25,15.42 116.55,15.42 116.67,15.3 v2(116.67,14.91)
  BOTTOM w0.076: v2(149.66,53.66) 149.99,53.99 UC1.AR35
  BOTTOM w0.152: v2(116.67,14.91) 116.8,15.04 JDIMM1.119
DDR_A_MA14: length 74.6
  IN2 w0.076: 140.6,42.1 140.6,42.6 145.32,47.32 145.32,47.95 145.88,48.51 145.88,49.06 v2(145.52,49.42)
  IN2 w0.152: v2(105.78,10.38) 104.66,11.49 104.63,11.49 104.63,17.34 104.07,17.9 104.07,21.67 109.84,27.43 112.54,27.43 112.67,27.56 112.67,28.84 112.8,28.97 130.01,28.97 140.6,39.56 140.6,42.1
  BOTTOM w0.076: UC1.AV42 144.91,51.88 144.91,49.86 145.36,49.42 v2(145.52,49.42)
  BOTTOM w0.152: v2(105.78,10.38) 105.1,9.7 JDIMM1.80
DDR_A_MA15: length 75.8
  IN2 w0.076: 140.19,42.1 140.19,42.59 144.84,47.24 144.84,48.09 v2(145.52,48.77)
  IN2 w0.152: v2(103.83,11.9) 103.52,11.9 103.39,12.03 103.39,15.26 103.52,15.39 104.1,15.39 104.23,15.51 104.23,17.1 104.1,17.22 103.82,17.22 103.67,17.37 103.67,21.84 109.67,27.84 112.14,27.84 112.27,27.97 112.27,29.25 112.39,29.37 129.84,29.37 140.19,39.73 140.19,42.1
  BOTTOM w0.076: UC1.AU42 145.16,52.64 144.84,52.32 144.84,52.14 144.75,52.05 144.75,49.53 145.52,48.76 v2(145.52,48.77)
  BOTTOM w0.152: JDIMM1.78 104.5,11.23 v2(103.83,11.9)
DDR_A_RAS#: length 73.7
  IN2 w0.076: v2(151.93,44.49) 151.93,43.04 151.13,42.23 151.13,42.1
  IN2 w0.152: v2(114.6,10.38) 114.82,10.38 114.95,10.5 114.95,10.88 115.08,11.01 116.27,11.01 116.4,11.14 116.4,11.58 116.25,11.73 115.54,11.73 115.39,11.88 115.39,12.14 115.54,12.29 116.25,12.29 116.4,12.44 116.4,12.61 117.18,13.4 117.4,13.4 117.51,13.28 117.69,13.28 117.91,13.5 117.91,13.68 117.79,13.79 117.79,14.01 118.31,14.53 131.68,14.53 131.84,14.68 131.84,14.88 131.96,15.01 132.27,15.01 132.39,14.88 132.39,14.68 132.55,14.53 133.36,14.53 133.51,14.68 133.51,14.88 133.64,15.01 133.94,15.01 134.07,14.88 134.07,14.68 134.22,14.53 135.11,14.53 136.64,16.06 137.8,16.06 139.71,17.97 139.71,23.67 151.13,35.08 151.13,42.1
  BOTTOM w0.076: v2(151.93,44.49) 151.81,44.49 150.76,45.54 UC1.AY34
  BOTTOM w0.152: JDIMM1.110 114.1,9.87 v2(114.6,10.38)
DDR_A_WE#: length 75.7
  IN2 w0.076: 150.31,42.1 150.31,42.38 151.27,43.33 151.27,50.31 v2(150.35,51.22)
  IN2 w0.152: 150.31,42.1 150.31,35.42 137.7,22.81 137.7,22.53 137.86,22.38 138.15,22.38 138.3,22.22 138.3,21.97 138.15,21.82 137.07,21.82 136.95,21.69 136.95,21.39 137.07,21.26 138.15,21.26 138.3,21.11 138.3,20.85 138.15,20.7 137.86,20.7 137.7,20.55 137.7,20.29 137.86,20.14 138.15,20.14 138.3,19.99 138.3,19.74 138.15,19.58 137.86,19.58 137.7,19.43 137.7,19.18 137.86,19.02 138.15,19.02 138.3,18.87 138.3,18.62 138.15,18.47 137.86,18.47 137.7,18.31 137.7,17.11 137.58,16.99 136.54,16.99 136.41,17.11 136.41,18.15 136.28,18.28 135.65,18.28 135.52,18.15 135.52,17.39 135.23,17.1 135.23,16.88 135.56,16.56 135.56,16.34 135.38,16.16 135.16,16.16 134.84,16.49 134.62,16.49 133.96,15.82 118.36,15.82 116.33,13.79 115.22,13.79 v2(114.87,14.15)
  BOTTOM w0.076: v2(150.35,51.22) 150.66,51.53 UC1.AW34
  BOTTOM w0.152: v2(114.87,14.15) 115.22,14.5 115.22,15.22 115,15.44 JDIMM1.113
DDR_B_BS0: length 101.3
  IN1 w0.076: v2(149.66,56.27) 149.27,56.66 149.27,57.76 149.02,58.01 148.71,58.01 148.13,57.43 148.13,53.55 147.66,53.08 147.66,47.12 147.66,47.12 147.66,43.12 146.96,42.42 146.96,42.1
  IN1 w0.152: v2(195.83,18.65) 195.83,18.43 195.7,18.3 194.74,18.3 194.61,18.17 194.61,17.65 194.76,17.49 195.42,17.49 195.54,17.37 195.54,17.06 195.42,16.94 194.76,16.94 194.61,16.78 194.61,16.17 194.74,16.04 194.83,16.04 194.96,15.91 194.96,15.44 194.83,15.31 194.38,15.31 193.85,15.85 193.85,16.73 193.7,16.88 192.82,16.88 192.69,17 192.69,17.31 192.82,17.44 193.7,17.44 193.85,17.59 193.85,17.84 193.7,18 193.04,18 192.91,18.12 192.91,18.43 193.04,18.55 194.43,18.55 194.99,19.11 194.99,21.24 192.37,23.85 165.5,23.85 165.35,24.01 165.35,24.5 165.2,24.65 164.94,24.65 164.79,24.5 164.79,24.01 164.64,23.85 164.34,23.85 164.21,23.98 164.21,24.53 164.08,24.65 159.11,24.65 146.96,36.8 146.96,42.1
  BOTTOM w0.076: v2(149.66,56.27) 149.99,56.59 UC1.AL35
  BOTTOM w0.152: v2(195.83,18.65) 195.83,18.8 195.7,18.92 195.36,18.92 195.23,18.8 195.23,17.51 195.3,17.45 JDIMM2.109
DDR_B_BS1: length 100
  IN1 w0.076: 147.77,42.1 147.77,42.19 147.97,42.39 147.97,42.53 148.28,42.84 148.28,46.81 149.4,47.93 149.4,50.46 149.13,50.72 149.13,50.93 149.4,51.19 149.4,51.59 149.18,51.8 149.18,52.12 149.4,52.34 149.4,52.61 149.1,52.91 149.1,55.64 148.97,55.77 v2(148.71,55.77)
  IN1 w0.152: 147.77,42.1 147.77,37.14 154.54,30.37 155.39,30.37 160.3,25.47 179.51,25.47 179.64,25.34 179.64,24.79 179.76,24.67 192.71,24.67 196.31,21.06 196.31,17.79 195.98,17.46 195.98,14.92 195.83,14.77 194.93,14.77 194.81,14.64 194.81,14.32 194.91,14.21 195.87,14.21 196,14.08 196,10.11 195.87,9.98 195.03,9.98 194.9,10.11 194.9,10.77 195.06,10.93 195.3,10.93 195.43,11.05 195.43,11.36 195.3,11.49 195.03,11.49 194.9,11.61 194.9,12.94 195.03,13.07 195.42,13.07 195.55,12.94 v2(195.55,12.72)
  BOTTOM w0.081: UC1.AM36 148.88,55.94 v2(148.71,55.77)
  BOTTOM w0.152: JDIMM2.108 195,9.88 195,9.88 195,12.42 195.3,12.72 v2(195.55,12.72)
DDR_B_BS2: length 96.2
  IN1 w0.076: 139.76,42.1 139.76,43.07 141.71,45.02 141.71,51.65 v2(140.91,52.45)
  IN1 w0.152: v2(184.73,14.09) 184.22,13.58 161.88,13.58 159.17,16.29 157.36,16.29 145.51,28.15 145.29,28.15 144.31,27.16 144.09,27.16 143.91,27.34 143.91,27.56 144.9,28.54 144.9,28.76 144.72,28.94 144.5,28.94 143.52,27.95 143.3,27.95 143.12,28.13 143.12,28.35 144.11,29.33 144.11,29.55 143.85,29.8 143.64,29.8 142.67,28.84 142.46,28.84 142.28,29.02 142.28,29.23 143.24,30.2 143.24,30.42 143.06,30.6 142.85,30.6 141.88,29.63 141.66,29.63 141.48,29.81 141.48,30.03 142.45,30.99 142.45,31.21 142.27,31.39 142.06,31.39 141.09,30.42 140.87,30.42 140.69,30.6 140.69,30.82 141.66,31.78 141.66,32 141.48,32.18 141.26,32.18 140.3,31.21 140.08,31.21 139.9,31.39 139.9,31.61 140.87,32.57 140.87,32.79 140.69,32.97 140.47,32.97 140.16,32.65 139.98,32.65 139.76,32.86 139.76,33.04 140.08,33.36 140.08,33.58 139.76,33.9 139.76,42.1
  BOTTOM w0.076: UC1.AU49 141.22,52.83 140.91,52.52 v2(140.91,52.45)
  BOTTOM w0.152: JDIMM2.79 186.3,15.35 185.04,14.09 v2(184.73,14.09)
DDR_B_CAS#: length 101.9
  IN1 w0.076: v2(150.62,55.68) 150.62,55.64 150.26,55.28 150.26,53.2 150.78,52.68 150.78,47.88 149.36,46.46 149.36,42.72 148.99,42.35 148.99,42.1
  IN1 w0.152: 148.99,42.1 148.99,37.64 155.04,31.59 155.9,31.59 160.81,26.69 180.73,26.69 180.86,26.56 180.86,26.01 180.98,25.88 193.22,25.88 198.31,20.79 198.31,17.54 198.46,17.39 199.56,17.39 199.69,17.26 199.69,16.96 199.56,16.83 198.46,16.83 198.31,16.68 198.31,16.42 198.46,16.27 199.5,16.27 199.63,16.14 199.63,15.84 199.5,15.71 198.46,15.71 198.31,15.56 198.31,14.63 198.43,14.5 199.3,14.5 199.43,14.38 199.43,14.07 199.3,13.95 198.43,13.95 198.31,13.82 198.31,13.5 198.43,13.37 199.3,13.37 199.43,13.25 199.43,12.85 199.3,12.72 198.68,12.72 198.55,12.6 198.55,11.92 198.46,11.84 198.31,11.84 198.18,11.71 198.18,11.37 198.05,11.24 197.69,11.24 197.56,11.37 197.56,11.78 197.8,12.02 197.8,12.88 197.93,13 v2(197.95,13)
  BOTTOM w0.076: UC1.AM33 150.88,55.94 v2(150.62,55.68)
  BOTTOM w0.152: v2(197.95,13) 198.71,13 198.92,13.21 198.92,13.84 197.1,15.66 JDIMM2.115
DDR_B_D0: length 84.1
  IN1 w0.102: v2(201.64,11.14) 202.94,12.44 202.94,15.33 201.79,16.48 201.79,21.19 193.55,29.43 161.94,29.43 151.99,39.39 151.99,43.59 152.54,44.15 152.54,46.15 152.11,46.58 152.11,46.99 v2(152.46,47.35)
  BOTTOM w0.076: v2(152.46,47.35) 151.62,48.19 151.62,50.36 152.01,50.75 UC1.AY31
  BOTTOM w0.102: v2(201.64,11.14) 202.2,10.58 JDIMM2.132
DDR_B_D1: length 85.3
  IN1 w0.102: v2(151.85,46.24) 152.29,45.8 152.29,44.31 151.67,43.68 151.67,39.25 161.81,29.11 193.42,29.11 201.47,21.06 201.47,15.8 201.62,15.65 202.17,15.65 202.52,15.3 202.52,12.45 202.4,12.33 201.63,12.33 201.5,12.45 201.5,14.88 201.63,15.01 v2(201.9,15.01)
  BOTTOM w0.076: v2(151.85,46.24) 151.34,46.75 151.34,50.32 151.72,50.69 151.72,50.82 151.73,50.84 151.73,50.96 151.81,51.11 151.81,51.13 152.01,51.33 UC1.AW31
  BOTTOM w0.102: JDIMM2.131 201.9,15.01 v2(201.9,15.01)
DDR_B_D2: length 84.4
  IN1 w0.102: v2(204.14,9.61) 204.71,9.61 204.93,9.84 204.93,12.13 205.5,12.7 205.5,16.13 204.58,17.04 204.07,17.04 203.81,17.3 203.81,21.8 194.32,31.29 162.78,31.29 154.24,39.83 154.24,42.69 154.45,42.9 154.45,44.66 v2(154.09,45.02)
  BOTTOM w0.076: v2(154.09,45.02) 153.24,45.87 153.24,49.75 153.36,49.87 UC1.AY29
  BOTTOM w0.102: v2(204.14,9.61) 204.6,9.16 JDIMM2.140
DDR_B_D3: length 85.5
  IN1 w0.102: v2(204.56,18.52) 204.56,18.43 206.45,16.53 206.45,14.62 206.32,14.49 205.94,14.49 205.81,14.62 205.81,16.26 204.71,17.36 204.32,17.36 204.14,17.54 204.14,21.92 194.45,31.61 162.91,31.61 154.54,39.97 154.54,42.52 154.63,42.61 154.63,45.13 v2(154.09,45.67)
  BOTTOM w0.076: v2(154.09,45.67) 153.41,46.35 153.41,49.66 153.52,49.78 153.52,50.63 153.65,50.76 153.65,51 153.36,51.29 UC1.AW29
  BOTTOM w0.102: JDIMM2.141 204.9,17.46 205.06,17.63 205.06,18.16 204.71,18.52 v2(204.56,18.52)
DDR_B_D4: length 85.2
  IN1 w0.102: v2(200.54,14.4) 200.72,14.22 200.72,12.62 200.85,12.5 201.07,12.5 201.2,12.62 201.2,14.45 201.17,14.48 201.17,15.77 200.98,15.95 200.98,16.33 201.15,16.5 201.15,16.84 200.98,17.01 200.98,17.35 201.15,17.52 201.15,17.86 200.98,18.03 200.98,18.36 201.15,18.53 201.15,18.87 200.98,19.04 200.98,19.38 201.15,19.55 201.15,19.89 200.98,20.06 200.98,20.4 201.15,20.57 201.15,20.93 193.29,28.79 161.7,28.79 157.53,32.96 157.52,32.96 151.35,39.12 151.35,44.58 151.88,45.1 v2(151.91,45.1)
  BOTTOM w0.076: v2(151.91,45.1) 151.06,45.95 151.06,50.43 151.48,50.85 151.55,50.99 151.57,51.03 151.57,51.03 151.63,51.13 151.63,51.8 UC1.AV31
  BOTTOM w0.102: JDIMM2.129 201.3,15.16 v2(200.54,14.4)
DDR_B_D5: length 86.6
  IN1 w0.102: v2(152.42,47.92) 152.83,47.51 152.83,44 152.3,43.48 152.3,39.52 162.08,29.75 193.68,29.75 202.17,21.26 202.17,16.55 203.26,15.46 203.26,11.21 201.67,9.61 v2(201.64,9.61)
  BOTTOM w0.076: v2(152.42,47.92) 152.63,47.92 152.9,48.19 152.9,49.93 153.01,50.03 153.01,50.44 152.9,50.54 152.9,50.98 152.93,51.03 152.93,51.03 152.93,51.03 152.98,51.14 152.98,51.27 152.9,51.43 152.9,51.63 152.93,51.68 152.93,51.68 152.97,51.77 152.98,51.79 152.98,51.98 152.96,51.99 152.96,52.37 152.98,52.38 152.98,52.63 152.77,52.83 UC1.AU31
  BOTTOM w0.102: v2(201.64,9.61) 201.6,9.57 JDIMM2.130
DDR_B_D6: length 85.8
  IN1 w0.102: v2(154.09,43.72) 153.73,43.36 153.73,42.74 153.93,42.53 153.93,39.68 162.65,30.97 194.19,30.97 203.49,21.67 203.49,16.96 203.73,16.73 204.45,16.73 205.18,16 205.18,12.86 204.58,12.27 204.58,11.58 v2(204.14,11.14)
  BOTTOM w0.076: v2(154.09,43.72) 153.07,44.74 153.07,49.82 153.17,49.92 153.17,50.51 153.07,50.61 153.07,50.94 153.12,51.05 153.14,51.1 153.14,51.31 153.12,51.36 153.12,51.36 153.08,51.44 153.07,51.45 153.07,51.46 153.07,51.59 153.09,51.65 153.12,51.7 153.25,51.84 UC1.AV29
  BOTTOM w0.102: JDIMM2.142 205.2,10.08 v2(204.14,11.14)
DDR_B_D7: length 86.2
  IN1 w0.102: v2(204.56,19.79) 205.05,19.79 205.18,19.66 205.18,18.25 206.02,17.41 206.32,17.41 206.45,17.54 206.45,18.08 206.35,18.18 205.92,18.18 205.81,18.28 205.81,18.58 205.92,18.69 206.35,18.69 206.45,18.79 206.45,19.09 206.35,19.19 205.92,19.19 205.81,19.3 205.81,19.6 205.92,19.7 206.35,19.7 206.45,19.8 206.45,20.09 206.32,20.22 205.64,20.22 205.55,20.31 205.55,20.94 194.57,31.92 163.04,31.92 154.85,40.11 154.85,45.56 v2(154.09,46.32)
  BOTTOM w0.076: UC1.AU29 153.25,52.62 153.55,52.33 153.55,51.76 153.65,51.65 153.65,51.23 153.82,51.07 153.82,50.69 153.69,50.56 153.69,49.5 153.63,49.44 153.63,46.78 v2(154.09,46.32)
  BOTTOM w0.102: JDIMM2.143 205.5,19.27 204.99,19.79 v2(204.56,19.79)
DDR_B_D8: length 50.3
  IN2 w0.102: v2(162.28,19.11) 161.78,18.62 161.78,13.72 161.66,13.59 161.3,13.59 161.17,13.72 161.17,21.11 155.24,27.04 155.24,37.34 154.14,38.44 154.14,42.44 153.59,43 153.59,47.12 v2(154.09,47.62)
  BOTTOM w0.076: UC1.AY27 154.31,50.75 154.31,50.48 154.2,50.37 154.2,49.64 154.7,49.14 154.7,48.23 v2(154.09,47.62)
  BOTTOM w0.102: JDIMM2.5 161.7,18.53 v2(162.28,19.11)
DDR_B_D9: length 51
  IN2 w0.102: v2(161.7,10.97) 161.01,10.97 160.7,11.28 160.7,11.62 160.8,11.73 161.3,11.73 161.42,11.85 161.42,12.11 161.3,12.23 160.8,12.23 160.7,12.34 160.7,12.56 160.8,12.67 161.5,12.67 161.63,12.79 161.63,13.05 161.5,13.17 160.8,13.17 160.7,13.28 160.7,21.13 154.92,26.9 154.92,37.23 153.84,38.31 153.84,42.34 153.32,42.86 153.32,47.5 v2(154.09,48.27)
  BOTTOM w0.076: UC1.AW27 154.44,51.29 154.15,51 154.15,50.55 154.03,50.44 154.03,49.55 154.48,49.1 154.48,48.66 v2(154.09,48.27)
  BOTTOM w0.102: v2(161.7,10.97) 162.16,10.5 162.16,9.5 162,9.34 JDIMM2.6
DDR_B_D10: length 50.5
  IN2 w0.102: v2(164.47,17.86) 164.82,17.86 164.95,17.74 164.95,12.84 164.82,12.71 164.07,12.71 163.94,12.84 163.94,20.54 156.86,27.62 156.86,37.89 155.72,39.02 155.72,42.05 155.35,42.43 155.35,44.32 v2(156.05,45.02)
  BOTTOM w0.076: UC1.AY25 155.69,50.78 155.69,49.98 155.69,49.82 155.96,49.55 155.98,49.55 156.44,49.08 156.44,45.41 v2(156.05,45.02)
  BOTTOM w0.102: JDIMM2.15 164.7,17.64 v2(164.47,17.86)
DDR_B_D11: length 51
  IN2 w0.102: v2(156.05,44.37) 155.66,43.98 155.66,42.49 156.07,42.09 156.07,39.13 157.17,38.02 157.17,37.33 157.28,37.23 157.76,37.23 157.86,37.13 157.86,36.82 157.76,36.72 157.28,36.72 157.17,36.62 157.17,36.32 157.28,36.21 157.76,36.21 157.86,36.11 157.86,35.81 157.76,35.71 157.28,35.71 157.17,35.6 157.17,35.3 157.28,35.2 157.76,35.2 157.86,35.1 157.86,34.79 157.76,34.69 157.28,34.69 157.17,34.59 157.17,34.28 157.28,34.18 157.76,34.18 157.86,34.08 157.86,33.78 157.76,33.67 157.28,33.67 157.17,33.57 157.17,33.27 157.28,33.17 157.76,33.17 157.86,33.06 157.86,32.76 157.76,32.66 157.28,32.66 157.17,32.56 157.17,32.28 157.28,32.18 157.8,32.18 157.91,32.08 157.91,31.78 157.8,31.68 157.28,31.68 157.17,31.57 157.17,31.27 157.28,31.17 157.8,31.17 157.91,31.07 157.91,30.76 157.8,30.66 157.28,30.66 157.17,30.56 157.17,30.25 157.28,30.15 157.8,30.15 157.91,30.05 157.91,29.74 157.8,29.64 157.28,29.64 157.17,29.54 157.17,29.12 157.28,29.02 157.8,29.02 157.91,28.91 157.91,28.61 157.8,28.51 157.28,28.51 157.17,28.41 157.17,27.76 164.91,20.03 164.91,19.44 v2(164.5,19.03)
  BOTTOM w0.076: UC1.AW25 156.01,51.31 156.01,51.1 156.05,51.01 156.05,51.01 156.08,50.94 156.08,50.76 155.86,50.53 155.86,50.02 156.66,49.22 156.66,44.98 v2(156.05,44.37)
  BOTTOM w0.102: JDIMM2.17 165.3,18.23 v2(164.5,19.03)
DDR_B_D12: length 51.7
  IN2 w0.102: v2(154.09,48.92) 153.12,47.95 153.12,42.56 153.53,42.15 153.53,38.19 154.62,37.1 154.62,26.76 160.36,21.02 160.36,19.07 160.26,18.97 159.32,18.97 159.22,18.86 159.22,18.56 159.32,18.46 160.26,18.46 160.36,18.36 160.36,17.97 160.26,17.86 159.7,17.86 159.6,17.76 159.6,17.46 159.7,17.36 160.26,17.36 160.36,17.26 160.36,11.04 v2(161.67,9.72)
  BOTTOM w0.076: UC1.AV27 154.55,52.05 154.15,51.65 154.15,51.24 153.98,51.08 153.98,50.62 153.85,50.49 153.85,49.15 v2(154.09,48.92)
  BOTTOM w0.102: v2(161.67,9.72) 161.4,9.45 JDIMM2.4
DDR_B_D13: length 52.7
  IN2 w0.102: v2(166.16,11.02) 165.62,11.56 165.62,12.11 165.72,12.21 166.02,12.21 166.13,12.32 166.13,12.62 166.02,12.72 165.72,12.72 165.62,12.82 165.62,13.13 165.72,13.23 166.02,13.23 166.13,13.33 166.13,13.64 166.02,13.74 165.72,13.74 165.62,13.84 165.62,14.15 165.72,14.25 166.02,14.25 166.13,14.35 166.13,14.65 166.02,14.75 165.72,14.75 165.62,14.86 165.62,20.21 158.54,27.29 158.54,37.74 156.75,39.53 156.75,42.36 156.46,42.65 156.46,47.86 v2(156.05,48.27)
  BOTTOM w0.076: v2(156.05,48.27) 155.33,48.98 155.33,50.98 155.41,51.14 155.41,51.27 155.36,51.37 155.36,51.37 155.33,51.43 155.33,51.63 155.36,51.68 155.36,51.68 155.4,51.77 155.41,51.79 155.41,52.63 155.2,52.83 UC1.AU27
  BOTTOM w0.102: v2(166.16,11.02) 165,9.86 JDIMM2.16
DDR_B_D14: length 51.6
  IN2 w0.102: v2(156.05,48.92) 154.46,47.34 154.46,42.65 154.45,42.64 154.45,38.57 155.61,37.41 155.61,27.12 162.71,20.02 162.71,12.53 162.58,12.41 162.23,12.41 162.1,12.53 162.1,17.66 v2(162.28,17.84)
  BOTTOM w0.076: UC1.AV25 155.79,51.94 155.55,51.7 155.5,51.59 155.5,51.46 155.51,51.44 155.51,51.44 155.55,51.36 155.57,51.31 155.57,51.1 155.5,50.94 155.5,49.47 v2(156.05,48.92)
  BOTTOM w0.102: JDIMM2.7 162.3,16.43 162.3,17.81 v2(162.28,17.84)
DDR_B_D15: length 52.8
  IN2 w0.102: v2(166.18,10.43) 165.44,10.43 165.26,10.62 165.26,10.67 165.16,10.77 164.86,10.77 164.75,10.87 164.75,11.18 164.86,11.28 165.16,11.28 165.26,11.38 165.26,11.68 165.16,11.79 164.86,11.79 164.75,11.89 164.75,12.19 164.86,12.29 165.16,12.29 165.26,12.39 165.26,20.12 158.22,27.16 158.22,27.49 158.12,27.59 157.79,27.59 157.64,27.74 157.64,27.95 157.79,28.1 158.12,28.1 158.22,28.2 158.22,37.61 156.37,39.46 156.37,42.27 156.05,42.59 v2(156.05,43.72)
  BOTTOM w0.076: v2(156.05,43.72) 156.85,44.52 156.85,49.26 156.02,50.09 156.02,50.46 156.25,50.69 156.25,50.98 156.22,51.03 156.22,51.03 156.17,51.14 156.17,51.7 156.08,51.79 156.08,52.54 UC1.AU25
  BOTTOM w0.102: v2(166.18,10.43) 165.6,9.85 JDIMM2.18
DDR_B_D16: length 92.4
  IN1 w0.102: v2(153.03,55.62) 152.44,55.02 152.44,51.49 155.27,48.65 155.27,42.98 155.86,42.39 155.86,40.27 163.38,32.75 194.89,32.75 205.68,21.96 206.15,21.96 207.3,20.81 207.3,12.94 207.5,12.75 207.5,12.43 207.38,12.3 207.26,12.3 207.13,12.17 207.13,11.72 207.26,11.59 207.32,11.59 207.44,11.46 207.44,10.57 207.32,10.44 207.17,10.44 207.04,10.57 207.04,11.1 206.94,11.2 206.74,11.2 v2(206.68,11.14)
  BOTTOM w0.076: UC1.AM29 153.36,55.94 v2(153.03,55.62)
  BOTTOM w0.102: JDIMM2.146 206.4,9.22 206.25,9.37 206.25,10.71 v2(206.68,11.14)
DDR_B_D17: length 94
  IN1 w0.102: v2(206.68,9.61) 206.34,9.61 206.17,9.79 206.17,10.22 206.07,10.32 205.57,10.32 205.44,10.45 205.44,10.71 205.57,10.83 206.07,10.83 206.17,10.93 206.17,11.33 206.07,11.43 205.89,11.43 205.76,11.56 205.76,11.81 205.89,11.94 206.07,11.94 206.17,12.04 206.17,12.19 206.3,12.32 206.83,12.32 206.96,12.45 206.96,20.7 206.02,21.64 205.57,21.64 194.78,32.43 163.25,32.43 155.43,40.25 155.43,42.44 155.08,42.8 155.08,48.46 152.18,51.36 152.18,56.07 v2(153.03,56.92)
  BOTTOM w0.076: v2(153.03,56.92) 153.36,57.24 UC1.AK29
  BOTTOM w0.102: JDIMM2.148 207,9.3 v2(206.68,9.61)
DDR_B_D18: length 92.9
  IN1 w0.102: v2(153.98,56.27) 154.56,55.69 154.56,53.49 157.31,50.74 157.31,43.4 158.46,42.25 158.46,41.71 164.6,35.56 186.17,35.56 186.48,35.24 197.05,35.24 211.43,20.87 211.43,16.73 210.8,16.11 210.8,10.92 210.65,10.77 210.17,10.77 210,10.94 v2(210,11.09)
  BOTTOM w0.076: UC1.AL28 154.31,56.59 v2(153.98,56.27)
  BOTTOM w0.102: v2(210,11.09) 210.6,10.49 JDIMM2.160
DDR_B_D19: length 93.9
  IN1 w0.102: v2(210,9.61) 211.16,10.77 211.16,16.02 211.74,16.6 211.74,21 197.18,35.56 186.62,35.56 186.3,35.88 164.77,35.88 158.79,41.86 158.79,42.21 157.5,43.5 157.5,50.94 155.33,53.11 155.33,57 155.04,57.29 154.31,57.29 v2(153.93,56.92)
  BOTTOM w0.076: UC1.AK28 154.26,57.24 v2(153.93,56.92)
  BOTTOM w0.102: v2(210,9.61) 210,9.61 JDIMM2.158
DDR_B_D20: length 90.6
  IN1 w0.102: v2(208.12,17.88) 208.06,17.83 208.06,17.31 208.19,17.19 208.71,17.19 209.01,17.49 209.01,18.7 208.91,18.8 208.63,18.8 208.52,18.9 208.52,19.21 208.63,19.31 208.91,19.31 209.01,19.41 209.01,19.71 208.91,19.82 208.63,19.82 208.52,19.92 208.52,20.22 208.63,20.32 208.91,20.32 209.01,20.43 209.01,20.65 208.33,21.33 208.18,21.33 208,21.15 207.86,21.15 207.64,21.37 207.64,21.51 207.83,21.69 207.83,21.84 207.61,22.05 207.47,22.05 207.28,21.87 207.14,21.87 206.92,22.09 206.92,22.23 207.11,22.41 207.11,22.56 206.89,22.77 206.75,22.77 206.55,22.58 206.38,22.58 206.19,22.76 206.19,22.94 206.39,23.13 206.39,23.28 206.17,23.49 206.03,23.49 205.74,23.2 205.56,23.2 205.38,23.38 205.38,23.56 205.67,23.85 205.67,23.99 205.45,24.21 205.31,24.21 205.02,23.92 204.84,23.92 204.66,24.1 204.66,24.28 204.95,24.57 204.95,24.71 204.73,24.93 204.59,24.93 204.3,24.64 204.12,24.64 203.94,24.82 203.94,25 204.21,25.27 204.21,25.45 204.03,25.63 203.85,25.63 203.58,25.36 203.4,25.36 203.22,25.54 203.22,25.72 203.51,26.01 203.51,26.15 196.28,33.38 163.73,33.38 156.58,40.54 156.58,42.37 155.66,43.29 155.66,49.38 155.28,49.76 155.28,50.44 154.76,50.96 154.23,50.96 153.03,52.16 v2(153.03,53.66)
  BOTTOM w0.076: v2(153.03,53.66) 153.36,53.99 UC1.AR29
  BOTTOM w0.102: JDIMM2.149 207.3,16.43 207.3,17.47 207.71,17.88 v2(208.12,17.88)
DDR_B_D21: length 92
  IN1 w0.102: v2(208.12,19.23) 207.76,19.23 207.63,19.36 207.63,20.09 207.76,20.22 208.06,20.22 208.19,20.34 208.19,20.55 208.06,20.67 207.77,20.67 207.66,20.79 207.66,20.9 206.28,22.28 206.04,22.28 202.65,25.66 202.65,25.81 202.96,26.11 202.96,26.26 202.74,26.47 202.6,26.47 202.29,26.17 202.15,26.17 201.93,26.38 201.93,26.53 202.24,26.83 202.24,26.98 202.02,27.19 201.88,27.19 201.57,26.89 201.43,26.89 201.21,27.1 201.21,27.25 201.52,27.55 201.52,27.7 201.3,27.91 201.16,27.91 200.85,27.6 200.71,27.6 200.5,27.81 200.5,27.95 200.8,28.25 200.8,28.39 200.59,28.61 200.44,28.61 200.14,28.31 200,28.31 199.78,28.53 199.78,28.67 200.08,28.97 200.08,29.11 199.87,29.33 199.72,29.33 199.43,29.03 199.28,29.03 199.07,29.25 199.07,29.39 199.36,29.69 199.36,29.83 199.15,30.05 199,30.05 198.71,29.75 198.56,29.75 198.35,29.96 198.35,30.11 198.64,30.41 198.64,30.55 198.43,30.76 198.29,30.76 197.99,30.47 197.84,30.47 197.63,30.68 197.63,30.83 197.93,31.12 197.93,31.27 197.71,31.48 197.57,31.48 197.27,31.19 197.13,31.19 196.91,31.4 196.91,31.55 197.21,31.84 197.21,31.99 196.99,32.2 196.85,32.2 196.55,31.91 196.17,31.91 195.01,33.07 163.51,33.07 156.19,40.39 156.19,42.44 155.46,43.18 155.46,48.84 152.66,51.65 152.66,54.59 v2(153.03,54.96)
  BOTTOM w0.076: UC1.AN29 153.36,55.29 v2(153.03,54.96)
  BOTTOM w0.102: JDIMM2.147 206.7,18.38 207.55,19.23 v2(208.12,19.23)
DDR_B_D22: length 90.5
  IN1 w0.102: v2(153.98,53.66) 153.98,53.41 156.88,50.52 156.88,43.15 157.81,42.23 157.81,41.39 164.06,35.14 164.06,35.13 164.59,34.61 164.82,34.61 164.92,34.71 164.92,34.82 165.02,34.92 165.33,34.92 165.43,34.82 165.43,34.71 165.53,34.61 165.83,34.61 165.94,34.71 165.94,34.82 166.04,34.92 166.34,34.92 166.44,34.82 166.44,34.71 166.55,34.61 166.85,34.61 166.95,34.71 166.95,34.82 167.05,34.92 167.36,34.92 167.46,34.82 167.46,34.71 167.56,34.61 167.87,34.61 167.97,34.71 167.97,34.82 168.07,34.92 168.37,34.92 168.48,34.82 168.48,34.71 168.58,34.61 168.88,34.61 168.98,34.71 168.98,34.82 169.09,34.92 169.39,34.92 169.49,34.82 169.49,34.71 169.59,34.61 169.9,34.61 170,34.71 170,34.82 170.1,34.92 170.41,34.92 170.51,34.82 170.51,34.71 170.61,34.61 170.91,34.61 171.02,34.71 171.02,34.82 171.12,34.92 171.42,34.92 171.52,34.82 171.52,34.71 171.63,34.61 172.08,34.61 172.4,34.92 185.9,34.92 186.22,34.61 196.79,34.61 210.23,21.16 210.23,20.73 210.33,20.63 210.67,20.63 210.79,20.5 210.79,20.25 210.67,20.12 210.33,20.12 210.23,20.02 210.23,19.71 210.33,19.61 210.67,19.61 210.79,19.49 210.79,19.23 210.67,19.1 210.33,19.1 210.23,19 210.23,18.7 210.33,18.6 210.67,18.6 210.79,18.47 210.79,18.22 210.67,18.09 210.33,18.09 210.23,17.99 210.23,17.68 210.33,17.58 210.67,17.58 210.79,17.45 210.79,16.99 210.67,16.87 210.12,16.87 209.99,16.74 209.99,16.26 209.89,16.16 209.53,16.16 209.41,16.03 209.41,15.78 209.53,15.65 209.89,15.65 209.99,15.55 v2(209.99,15.01)
  BOTTOM w0.076: v2(153.98,53.66) 154.31,53.99 UC1.AR28
  BOTTOM w0.102: JDIMM2.157 209.7,16.43 209.7,15.2 209.89,15.01 v2(209.99,15.01)
DDR_B_D23: length 91.3
  IN1 w0.102: v2(209.98,13.82) 209.74,13.82 209.59,13.66 209.59,12.27 209.69,12.17 210.35,12.17 210.47,12.29 210.47,16.23 211.11,16.86 211.11,20.73 196.92,34.93 186.35,34.93 186.04,35.24 164.44,35.24 158.11,41.57 158.11,42.25 157.11,43.26 157.11,50.62 154.35,53.38 154.35,53.95 v2(153.98,54.31)
  BOTTOM w0.076: v2(153.98,54.31) 154.31,54.64 UC1.AP28
  BOTTOM w0.102: JDIMM2.159 210.3,16.43 210.3,15.51 210.5,15.32 210.5,13.94 210.37,13.82 v2(209.98,13.82)
DDR_B_D24: length 54.5
  IN2 w0.102: v2(154.94,54.96) 154.57,54.6 154.57,51.56 157.13,49 157.13,43.07 157.87,42.33 157.87,40.03 159.82,38.07 159.82,29.04 167.42,21.44 167.42,11.49 167.3,11.37 167.08,11.37 166.95,11.24 166.95,10.43 167.08,10.31 v2(168.17,10.31)
  BOTTOM w0.076: v2(154.94,54.96) 155.26,55.29 UC1.AN26
  BOTTOM w0.102: JDIMM2.24 167.4,9.54 v2(168.17,10.31)
DDR_B_D25: length 53.2
  IN2 w0.102: v2(154.94,53.66) 154.94,52.25 156.76,50.42 156.76,49.82 157.32,49.27 157.32,43.4 158.17,42.55 158.17,40.52 160.16,38.53 160.16,29.16 167.77,21.55 167.77,18.14 167.87,18.04 168.37,18.04 168.47,17.94 168.47,17.63 168.37,17.53 167.87,17.53 167.77,17.43 167.77,11.95 v2(168.22,11.5)
  BOTTOM w0.076: v2(154.94,53.66) 155.26,53.99 UC1.AR26
  BOTTOM w0.102: v2(168.22,11.5) 166.8,10.09 JDIMM2.22
DDR_B_D26: length 52.8
  IN2 w0.102: v2(170.25,19.03) 169.87,19.41 169.87,20.23 169.77,20.33 169.49,20.33 169.39,20.43 169.39,20.74 169.49,20.84 169.77,20.84 169.87,20.94 169.87,21.18 166.78,24.28 166.78,24.42 167.59,25.23 167.59,25.41 167.41,25.59 167.23,25.59 166.42,24.78 166.27,24.78 166.06,24.99 166.06,25.17 166.87,25.98 166.87,26.12 166.66,26.34 166.52,26.34 165.71,25.53 165.53,25.53 165.35,25.71 165.35,25.88 166.16,26.69 166.16,26.84 165.94,27.05 165.8,27.05 164.99,26.24 164.81,26.24 164.63,26.42 164.63,26.6 165.44,27.41 165.44,27.56 161.38,31.61 161.38,39.04 159.58,40.84 159.58,42.21 158.45,43.34 158.45,50.21 155.89,52.78 v2(155.89,53.66)
  BOTTOM w0.076: UC1.AR25 156.21,53.99 v2(155.89,53.66)
  BOTTOM w0.102: v2(170.25,19.03) 169.84,18.63 169.84,17.63 170.1,17.37 JDIMM2.33
DDR_B_D27: length 53.3
  IN2 w0.102: v2(155.89,54.31) 156.29,53.91 156.29,52.95 158.73,50.51 158.73,43.46 159.9,42.3 159.9,40.98 161.7,39.17 161.7,31.74 167.9,25.54 167.9,23.6 170.7,20.8 170.7,17.33 170.6,17.23 169.97,17.23 169.87,17.13 169.87,16.82 169.97,16.72 170.6,16.72 170.7,16.62 170.7,15.4 170.57,15.28 169.52,15.28 169.39,15.4 169.39,17.74 169.52,17.86 v2(170.28,17.86)
  BOTTOM w0.076: UC1.AP25 156.21,54.64 v2(155.89,54.31)
  BOTTOM w0.102: JDIMM2.35 170.7,17.44 v2(170.28,17.86)
DDR_B_D28: length 56.2
  IN2 w0.102: v2(154.89,56.92) 154.35,57.45 153.83,57.45 153.5,57.12 153.5,51.66 154.29,50.88 154.6,50.88 156.7,48.78 156.7,42.79 157.26,42.23 157.26,39.74 159.05,37.95 159.05,28.92 159.5,28.47 159.5,28.18 159.05,27.74 159.05,27.5 159.21,27.34 159.35,27.34 159.92,27.91 160.06,27.91 160.28,27.69 160.28,27.55 159.71,26.98 159.71,26.84 159.93,26.62 160.07,26.62 160.64,27.19 160.78,27.19 161,26.97 161,26.83 160.43,26.26 160.43,26.12 160.65,25.9 160.79,25.9 161.36,26.47 161.5,26.47 161.72,26.25 161.72,26.11 161.15,25.54 161.15,25.4 166.25,20.3 166.25,17.36 166.38,17.23 166.89,17.23 167.01,17.36 v2(167.01,17.86)
  BOTTOM w0.076: v2(154.89,56.92) 155.21,57.24 UC1.AK26
  BOTTOM w0.102: v2(167.01,17.86) 166.5,17.35 166.5,16.43 JDIMM2.21
DDR_B_D29: length 54.8
  IN2 w0.102: v2(167.01,19.11) 166.83,19.11 166.58,19.35 166.58,20.42 165.32,21.68 165.32,21.82 165.87,22.37 165.87,22.55 165.69,22.73 165.51,22.73 164.96,22.18 164.82,22.18 164.6,22.4 164.6,22.54 165.17,23.11 165.17,23.25 164.95,23.47 164.81,23.47 164.25,22.9 164.1,22.9 163.89,23.11 163.89,23.26 164.45,23.82 164.45,23.97 164.24,24.18 164.09,24.18 163.53,23.62 163.38,23.62 163.17,23.83 163.17,23.98 163.73,24.54 163.73,24.69 163.52,24.9 163.37,24.9 162.81,24.34 162.66,24.34 162.45,24.55 162.45,24.7 163.01,25.26 163.01,25.41 162.8,25.62 162.65,25.62 162.11,25.07 161.93,25.07 161.72,25.28 161.72,25.46 162.18,25.91 162.18,26.24 159.42,29.01 159.42,38.03 157.56,39.89 157.56,42.32 156.91,42.97 156.91,48.91 154.37,51.46 154.37,55.04 v2(154.94,55.62)
  BOTTOM w0.076: v2(154.94,55.62) 155.26,55.94 UC1.AM26
  BOTTOM w0.102: v2(167.01,19.11) 167.08,19.11 167.44,18.75 167.44,17.63 167.1,17.28 JDIMM2.23
DDR_B_D30: length 56.2
  IN2 w0.102: v2(171.01,10.82) 171.18,10.98 171.46,11.26 171.46,20.94 168.54,23.86 168.54,25.82 162.34,32.02 162.34,39.43 160.53,41.24 160.53,42.56 159.29,43.8 159.29,50.86 157.29,52.87 157.29,55.2 156.42,56.07 156.42,56.33 v2(155.84,56.92)
  BOTTOM w0.076: UC1.AK25 156.16,57.24 v2(155.84,56.92)
  BOTTOM w0.102: JDIMM2.34 170.4,8.23 170.4,10.21 171,10.82 v2(171.01,10.82)
DDR_B_D31: length 55.8
  IN2 w0.102: v2(171.01,9.6) 170.56,9.6 170.43,9.72 170.43,11.67 170.56,11.8 170.92,11.8 171.04,11.92 171.04,20.9 168.22,23.73 168.22,25.68 162.02,31.88 162.02,39.3 160.21,41.11 160.21,42.46 159.01,43.66 159.01,50.65 156.52,53.14 156.52,53.98 156.35,54.15 156.35,55.81 v2(155.89,56.27)
  BOTTOM w0.076: v2(155.89,56.27) 156.21,56.59 UC1.AL25
  BOTTOM w0.102: v2(171.01,9.6) 171,9.59 JDIMM2.36
DDR_B_D32: length 86.5
  IN1 w0.102: v2(212.54,9.61) 212.09,9.61 211.97,9.73 211.97,13.21 212.1,13.33 213.26,13.33 213.38,13.46 213.38,14.53 213.47,14.62 213.47,20.89 197.34,37.02 165.49,37.02 158.66,43.85 158.66,45.74 v2(158.08,46.32)
  BOTTOM w0.076: UC1.AY23 157.14,50.62 157.15,50.61 157.15,49.89 157.44,49.61 157.44,46.96 v2(158.08,46.32)
  BOTTOM w0.102: v2(212.54,9.61) 212.4,9.47 JDIMM2.166
DDR_B_D33: length 87.7
  IN1 w0.102: v2(212.13,14.3) 212.09,14.34 211.77,14.34 211.68,14.25 211.68,13.79 211.82,13.65 212.78,13.65 213.07,13.93 213.07,14.66 213.12,14.71 213.12,19.85 213.02,19.95 212.67,19.95 212.57,20.05 212.57,20.36 212.67,20.46 213.02,20.46 213.12,20.56 213.12,20.79 213,20.91 212.76,20.91 212.64,21.04 212.64,21.27 197.52,36.39 197.28,36.39 197.18,36.49 197.18,36.58 197.05,36.7 196.8,36.7 196.67,36.58 196.67,36.49 196.57,36.39 196.27,36.39 196.16,36.49 196.16,36.58 196.04,36.7 195.78,36.7 195.66,36.58 195.66,36.49 195.56,36.39 195.25,36.39 195.15,36.49 195.15,36.58 195.02,36.7 194.77,36.7 194.64,36.58 194.64,36.49 194.54,36.39 194.23,36.39 194.13,36.49 194.13,36.58 194.01,36.7 193.75,36.7 193.62,36.58 193.62,36.49 193.52,36.39 193.22,36.39 193.12,36.49 193.12,36.58 192.99,36.7 192.74,36.7 192.61,36.58 192.61,36.49 192.51,36.39 192.28,36.39 192.18,36.49 192.18,36.6 192.08,36.7 165.35,36.7 158.45,43.61 158.45,44.7 v2(158.08,45.07)
  BOTTOM w0.076: UC1.AW23 157.14,51.33 156.94,51.13 156.94,51.12 156.85,50.94 156.85,50.68 156.99,50.54 156.99,49.83 157.27,49.54 157.27,45.88 v2(158.08,45.07)
  BOTTOM w0.102: JDIMM2.165 212.1,16.43 212.1,15.6 211.72,15.21 211.72,14.43 211.85,14.3 v2(212.13,14.3)
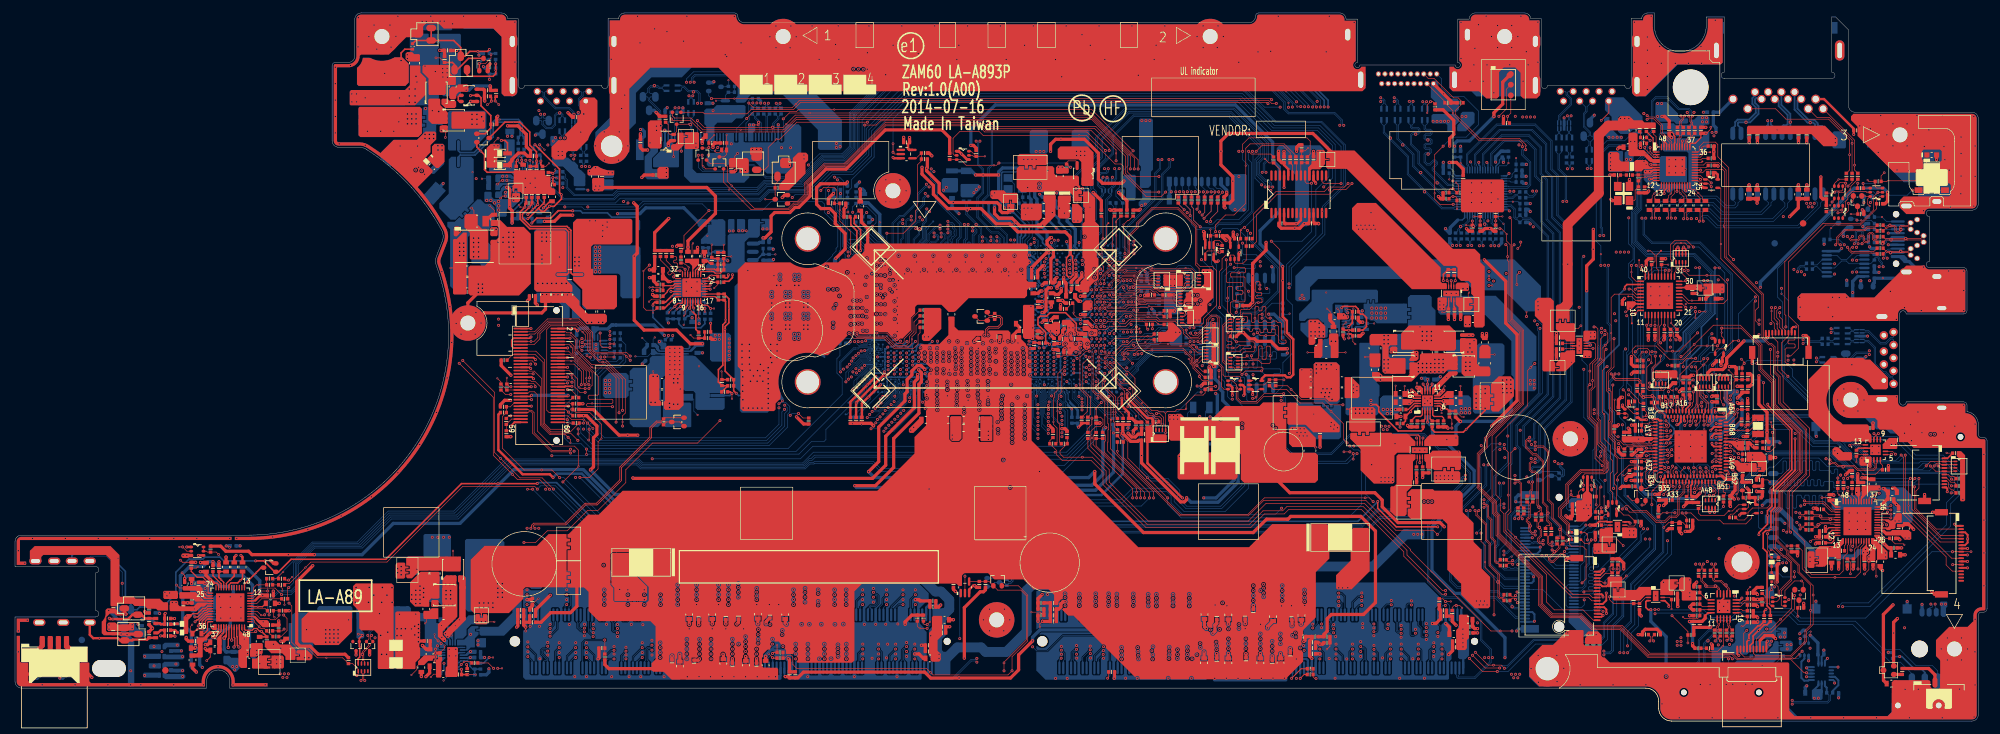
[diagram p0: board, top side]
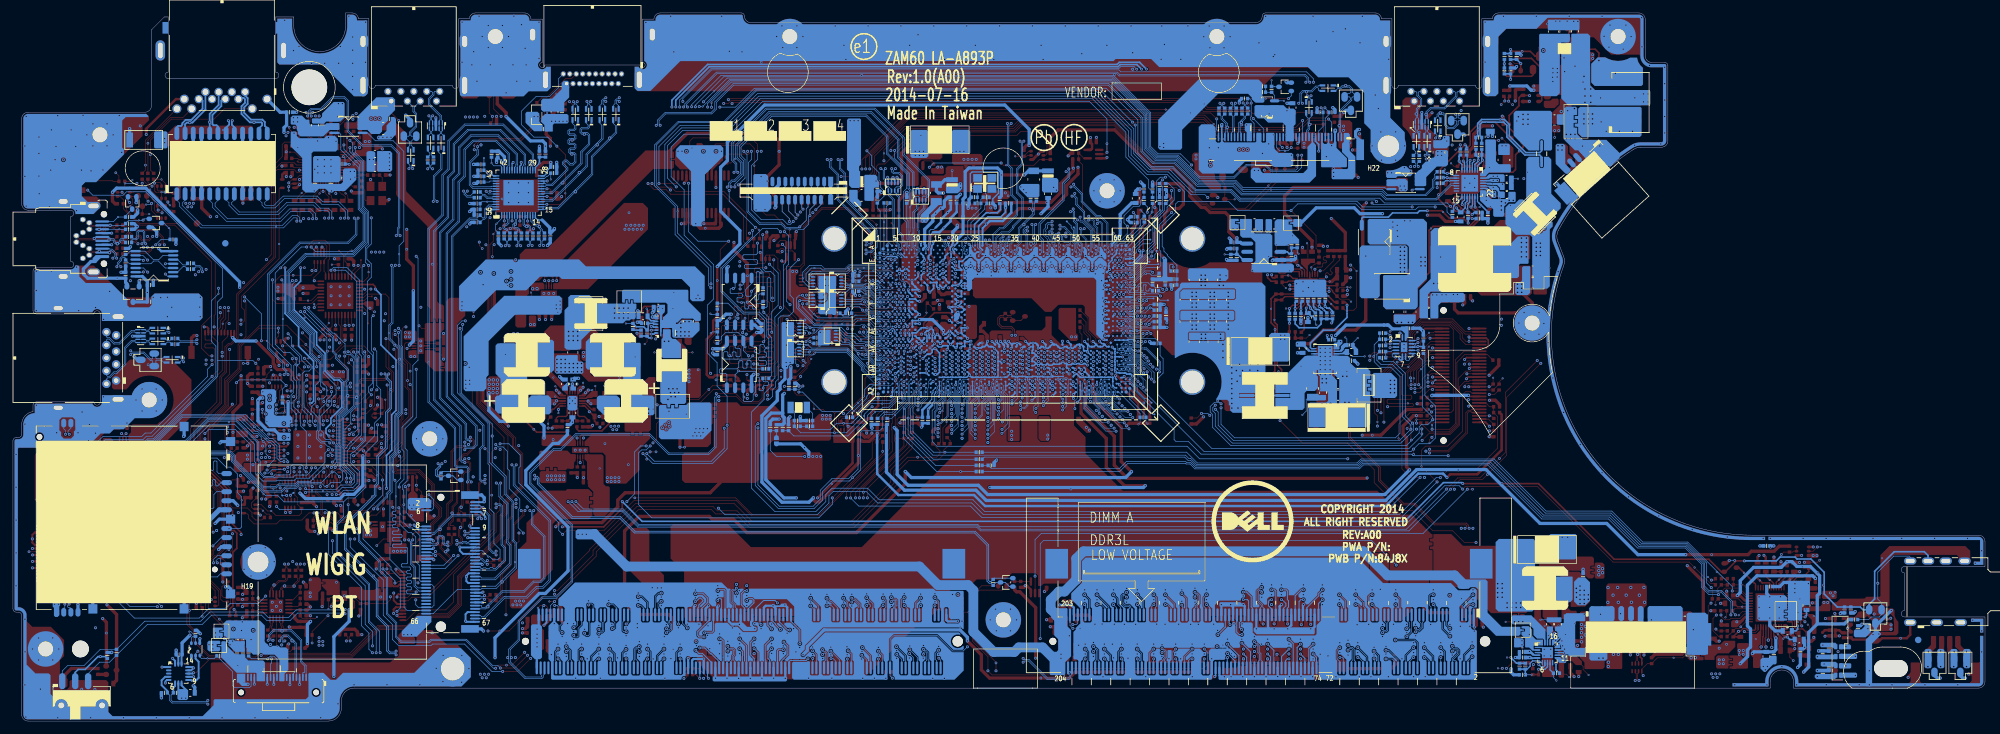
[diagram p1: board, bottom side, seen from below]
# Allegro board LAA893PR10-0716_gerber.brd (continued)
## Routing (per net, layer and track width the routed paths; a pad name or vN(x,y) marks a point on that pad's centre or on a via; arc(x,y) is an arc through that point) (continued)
DDR_B_D34: length 86.5
  IN1 w0.102: v2(159.68,45.05) 159.68,45.05 160.08,44.65 160.08,44.33 161.3,43.1 162.62,43.1 166.03,39.69 166.66,39.69 169.79,39.69 170.5,38.97 198.19,38.97 215.39,21.78 215.39,17.2 215.68,16.9 215.68,13.61 214.94,12.88 214.94,10.45 214.22,9.72 v2(214.22,9.61)
  BOTTOM w0.076: v2(159.68,45.05) 158.78,45.95 158.78,49.25 158.62,49.4 158.62,50.75 UC1.AY21
  BOTTOM w0.102: v2(214.22,9.61) 214.45,9.61 214.8,9.26 JDIMM2.174
DDR_B_D35: length 87.3
  IN1 w0.102: v2(159.68,46.33) 160.69,45.32 160.69,44.21 161.53,43.37 162.8,43.37 166.16,40 166.26,40 170.38,40 170.51,39.88 170.51,39.42 170.64,39.29 170.86,39.29 170.97,39.39 170.97,39.9 171.07,40 171.37,40 171.47,39.9 171.47,39.39 171.57,39.29 171.88,39.29 171.98,39.39 171.98,39.9 172.08,40 172.39,40 172.49,39.9 172.49,39.39 172.59,39.29 172.9,39.29 173,39.39 173,39.9 173.1,40 173.4,40 173.51,39.9 173.51,39.39 173.61,39.29 173.91,39.29 174.01,39.39 174.01,39.9 174.11,40 174.42,40 174.52,39.9 174.52,39.39 174.62,39.29 174.93,39.29 175.03,39.39 175.03,39.9 175.13,40 175.44,40 175.54,39.9 175.54,39.39 175.64,39.29 175.94,39.29 176.05,39.39 176.05,39.9 176.15,40 176.45,40 176.55,39.9 176.55,39.39 176.65,39.29 198.33,39.29 216.21,21.41 216.21,19.87 216.1,19.77 215.81,19.77 215.71,19.67 215.71,19.36 215.81,19.26 216.1,19.26 216.21,19.16 216.21,18.37 v2(215.8,17.96)
  BOTTOM w0.076: UC1.AW21 158.49,51.29 158.79,51 158.79,49.47 158.94,49.31 158.94,47.07 v2(159.68,46.33)
  BOTTOM w0.102: JDIMM2.175 215.1,16.43 215.1,17.94 215.28,18.11 215.64,18.11 v2(215.8,17.96)
DDR_B_D36: length 87.8
  IN1 w0.102: v2(212.68,17.98) 212.81,17.86 212.81,15.5 212.68,15.37 211.8,15.37 211.67,15.5 211.67,15.79 211.8,15.91 212.13,15.91 212.25,16.04 212.25,21.21 197.39,36.07 191.83,36.07 191.73,36.17 191.73,36.28 191.63,36.38 191.32,36.38 191.22,36.28 191.22,36.17 191.12,36.07 190.82,36.07 190.71,36.17 190.71,36.28 190.61,36.38 190.31,36.38 190.21,36.28 190.21,36.17 190.1,36.07 189.8,36.07 189.7,36.17 189.7,36.28 189.59,36.38 189.29,36.38 189.19,36.28 189.19,36.17 189.09,36.07 188.78,36.07 188.68,36.17 188.68,36.28 188.58,36.38 188.27,36.38 188.17,36.28 188.17,36.17 188.07,36.07 187.77,36.07 187.66,36.17 187.66,36.28 187.56,36.38 187.26,36.38 187.16,36.28 187.16,36.19 187.03,36.07 186.86,36.07 186.74,36.19 186.74,36.32 186.67,36.38 165.22,36.38 158.36,43.25 158.02,43.25 157.7,43.56 157.7,43.99 v2(158.08,44.37)
  BOTTOM w0.076: UC1.AV23 156.76,51.8 156.76,51.13 156.71,51.03 156.7,51.03 156.68,50.99 156.68,50.61 156.82,50.47 156.82,49.76 157.11,49.47 157.11,45.34 v2(158.08,44.37)
  BOTTOM w0.102: JDIMM2.163 211.5,17.51 211.97,17.98 v2(212.68,17.98)
DDR_B_D37: length 88.5
  IN1 w0.102: v2(212.54,11.14) 213.7,12.3 213.7,14.4 213.8,14.5 213.8,21.01 197.47,37.34 165.62,37.34 158.86,44.09 158.86,46.18 v2(158.08,46.97)
  BOTTOM w0.076: v2(158.08,46.97) 158.45,47.34 158.45,49.11 158.27,49.28 158.27,50.45 158.06,50.66 158.06,50.67 158.05,50.68 158.05,51 158.06,51.03 158.06,51.03 158.06,51.03 158.11,51.14 158.11,51.27 158.06,51.37 158.06,51.37 158.04,51.43 158.04,51.63 158.06,51.68 158.06,51.68 158.1,51.77 158.11,51.79 158.11,51.98 158.07,52.01 158.07,52.28 158.18,52.38 158.18,52.6 157.95,52.83 UC1.AU23
  BOTTOM w0.102: v2(212.54,11.14) 211.8,10.4 JDIMM2.164
DDR_B_D38: length 87.7
  IN1 w0.102: v2(214.22,11.14) 214.62,11.54 214.62,13.01 215.35,13.73 215.35,16.78 215.07,17.06 215.07,21.64 198.06,38.65 170.37,38.65 169.66,39.37 165.9,39.37 162.41,42.86 161.29,42.86 159.68,44.47 v2(159.68,44.49)
  BOTTOM w0.076: UC1.AV21 158.31,51.76 158.25,51.7 158.2,51.59 158.2,51.46 158.21,51.44 158.21,51.44 158.25,51.36 158.28,51.31 158.28,51.1 158.24,51.03 158.24,51.02 158.21,50.97 158.21,50.75 158.45,50.51 158.45,49.34 158.61,49.18 158.61,45.56 v2(159.68,44.49)
  BOTTOM w0.102: v2(214.22,11.14) 215.4,9.96 215.4,8.23 JDIMM2.176
DDR_B_D39: length 88.1
  IN1 w0.102: v2(159.68,46.98) 161.14,45.52 161.14,44.08 161.63,43.59 163.03,43.59 166.3,40.32 176.58,40.32 177.3,39.61 198.44,39.61 216.52,21.52 216.52,18.11 216.01,17.6 216.01,16.34 216.11,16.24 216.3,16.24 216.41,16.14 216.41,15.83 216.3,15.73 216.11,15.73 216.01,15.63 216.01,15.32 216.11,15.22 216.3,15.22 216.41,15.12 216.41,14.81 216.3,14.71 216.11,14.71 216.01,14.61 216.01,13.99 v2(216.42,13.59)
  BOTTOM w0.076: v2(159.68,46.98) 159.11,47.55 159.11,49.38 158.95,49.54 158.95,51.07 158.79,51.23 158.79,51.65 158.68,51.75 158.68,52.53 UC1.AU21
  BOTTOM w0.102: JDIMM2.177 215.7,13.33 215.83,13.21 216.14,13.21 216.42,13.49 v2(216.42,13.59)
DDR_B_D40: length 50.3
  IN2 w0.102: v2(159.8,49.33) 160.53,48.61 160.53,43.57 162.01,42.09 162.01,41.72 163.6,40.13 163.6,32.39 168.46,27.52 170.32,25.67 170.32,25.3 169.68,24.66 169.68,24.48 169.9,24.26 170.08,24.26 170.81,24.99 170.99,24.99 171.17,24.81 171.17,24.63 170.35,23.81 170.35,23.67 170.56,23.45 170.71,23.45 171.53,24.27 171.71,24.27 171.89,24.09 171.89,23.91 171.07,23.09 171.07,22.95 171.28,22.73 171.43,22.73 172.25,23.56 172.43,23.56 172.61,23.38 172.61,23.2 171.78,22.37 171.78,22.23 172,22.01 172.14,22.01 172.57,22.44 172.75,22.44 172.93,22.26 172.93,22.08 172.5,21.65 172.5,21.51 173.36,20.65 173.36,19.41 173.03,19.08 v2(172.82,19.08)
  BOTTOM w0.076: UC1.AY19 159.45,50.75 159.45,49.85 159.8,49.5 v2(159.8,49.33)
  BOTTOM w0.102: JDIMM2.39 171.9,16.53 171.9,16.53 171.9,17.5 171.84,17.56 171.84,18.11 v2(172.82,19.08)
DDR_B_D41: length 51.3
  IN2 w0.102: v2(172.82,17.86) 173.48,17.86 173.61,17.74 173.61,14.1 173.48,13.97 172.43,13.97 172.3,14.1 172.3,21.27 169.36,24.2 169.36,26.17 163.19,32.35 163.19,40.06 161.66,41.59 161.66,42.06 160.34,43.38 160.34,48.13 v2(159.69,48.79)
  BOTTOM w0.076: v2(159.69,48.79) 159.44,49.04 159.44,49.52 159.28,49.68 159.28,51.4 159.41,51.53 UC1.AW19
  BOTTOM w0.102: v2(172.82,17.86) 172.57,18.11 172.4,18.11 172.22,17.93 172.22,17.75 172.5,17.47 172.5,16.43 JDIMM2.41
DDR_B_D42: length 49.8
  IN2 w0.102: v2(176.39,17.81) 176.39,17.07 176.52,16.94 177.12,16.94 177.25,17.07 177.25,20.98 177.12,21.11 176.39,21.11 176.26,21.23 176.26,21.52 176.36,21.63 177.23,21.63 177.35,21.75 177.35,22.01 177.23,22.13 176.36,22.13 176.26,22.23 176.26,22.54 176.36,22.64 177.23,22.64 177.35,22.77 177.35,23.02 177.23,23.15 176.36,23.15 175.88,23.63 175.88,23.77 176.26,24.15 176.26,24.29 176.05,24.51 175.91,24.51 175.53,24.13 175.38,24.13 175.22,24.29 175.22,24.46 175.52,24.76 175.52,25.04 166.44,34.12 166.44,41.42 163.87,43.99 163.46,43.99 162.36,45.1 162.36,48.1 v2(161.53,48.92)
  BOTTOM w0.076: UC1.AY17 160.92,50.56 160.91,50.54 160.91,49.73 161.53,49.1 v2(161.53,48.92)
  BOTTOM w0.102: JDIMM2.53 176.1,17.52 v2(176.39,17.81)
DDR_B_D43: length 50.6
  IN2 w0.102: v2(175.81,9.6) 176.31,10.1 176.31,11.8 175.97,12.14 175.97,20.03 175.63,20.37 175.63,22.99 170.9,27.71 170.9,28.76 165.71,33.94 165.71,41.21 163.85,43.08 163.56,43.08 162.06,44.58 v2(161.79,44.58)
  BOTTOM w0.076: UC1.AW17 160.92,51.28 161.16,51.05 161.16,51.05 161.17,51.01 161.18,51.01 161.22,50.94 161.22,50.76 161.09,50.63 161.09,49.92 161.93,49.08 161.93,48.04 162.18,47.78 162.18,44.97 161.79,44.58 v2(161.79,44.58)
  BOTTOM w0.102: JDIMM2.52 175.8,9.59 v2(175.81,9.6)
DDR_B_D44: length 51.1
  IN2 w0.102: v2(173.57,10.18) 172.58,10.18 171.98,10.78 171.98,21.14 169.05,24.07 169.05,26.03 162.84,32.23 162.84,39.92 161.25,41.52 161.25,42.1 160.09,43.26 160.09,47.8 v2(159.72,48.17)
  BOTTOM w0.076: v2(159.72,48.17) 159.67,48.17 159.27,48.57 159.27,49.45 159.12,49.61 159.12,51.48 159.68,52.05 UC1.AV19
  BOTTOM w0.102: JDIMM2.42 172.8,9.42 v2(173.57,10.18)
DDR_B_D45: length 52.2
  IN2 w0.102: v2(173.49,11.37) 173.92,11.81 173.92,22.51 163.96,32.47 163.96,40.22 162.44,41.74 162.44,42.04 160.84,43.64 160.84,47.01 v2(161.53,47.7)
  BOTTOM w0.076: UC1.AU19 160.34,52.83 160.54,52.63 160.54,51.79 160.53,51.77 160.49,51.68 160.49,51.68 160.47,51.63 160.47,51.43 160.49,51.38 160.49,51.38 160.54,51.27 160.54,51.14 160.47,50.98 160.47,50.64 160.58,50.53 160.58,49.55 160.97,49.15 160.97,48.26 v2(161.53,47.7)
  BOTTOM w0.102: v2(173.49,11.37) 172.2,10.09 JDIMM2.40
DDR_B_D46: length 50.3
  IN2 w0.102: v2(161.53,48.28) 162.17,47.64 162.17,44.87 163.51,43.54 163.86,43.54 166.05,41.34 166.05,34.06 171.5,28.61 171.5,28.36 171.22,28.08 171.22,27.85 171.38,27.68 171.52,27.68 171.9,28.06 172.05,28.06 172.26,27.85 172.26,27.7 171.88,27.32 171.88,27.18 172.1,26.96 172.24,26.96 172.62,27.34 172.77,27.34 172.98,27.13 172.98,26.98 172.6,26.6 172.6,26.46 172.82,26.25 172.96,26.25 173.34,26.63 173.48,26.63 173.7,26.41 173.7,26.27 173.32,25.89 173.32,25.74 173.54,25.53 173.68,25.53 174.06,25.91 174.2,25.91 174.42,25.69 174.42,25.55 174.04,25.17 174.04,25.02 174.26,24.81 174.4,24.81 174.78,25.19 174.92,25.19 175.14,24.97 175.14,24.83 174.76,24.45 174.76,24.3 175.94,23.12 175.94,20.5 176.19,20.26 176.63,20.26 176.93,19.95 176.93,19.2 176.73,19 v2(176.39,19)
  BOTTOM w0.076: v2(161.53,48.28) 161.14,48.68 161.14,49.22 160.74,49.62 160.74,50.6 160.63,50.71 160.63,50.94 160.68,51.05 160.71,51.1 160.71,51.31 160.68,51.36 160.68,51.36 160.64,51.44 160.64,51.45 160.63,51.46 160.63,51.59 160.68,51.7 160.92,51.94 UC1.AV17
  BOTTOM w0.102: JDIMM2.51 175.5,17.5 175.75,17.75 175.75,18.35 v2(176.39,19)
DDR_B_D47: length 52
  IN2 w0.102: v2(175.68,10.87) 175.4,11.15 175.4,17.07 175.64,17.31 175.64,19.9 175.31,20.23 175.31,22.86 170.58,27.58 170.58,28.63 165.29,33.92 165.29,41.08 163.68,42.7 163.43,42.7 162.16,43.97 v2(161.78,43.97)
  BOTTOM w0.076: v2(161.78,43.97) 162.34,44.53 162.34,47.85 162.09,48.11 162.09,49.15 161.26,49.99 161.26,50.56 161.38,50.69 161.38,50.92 161.39,50.94 161.39,50.96 161.38,50.98 161.38,50.98 161.36,51.03 161.35,51.03 161.35,51.03 161.33,51.08 161.3,51.14 161.3,51.15 161.22,51.23 161.22,52.51 160.92,52.8 UC1.AU17
  BOTTOM w0.102: v2(175.68,10.87) 175.2,10.38 JDIMM2.50
DDR_B_D48: length 93.1
  IN1 w0.102: v2(219.88,13.69) 219.88,13.59 220,13.47 220.24,13.47 220.37,13.59 220.37,14.02 220.24,14.15 220.24,15.3 220.63,15.68 220.63,21.23 199.37,42.49 190.94,42.49 190.84,42.6 190.84,42.91 190.74,43.01 190.43,43.01 190.33,42.91 190.33,42.6 190.23,42.49 189.93,42.49 189.82,42.6 189.82,42.91 189.72,43.01 189.42,43.01 189.32,42.91 189.32,42.6 189.21,42.49 188.91,42.49 188.81,42.6 188.81,42.91 188.71,43.01 188.4,43.01 188.3,42.91 188.3,42.6 188.2,42.49 187.89,42.49 187.79,42.6 187.79,42.91 187.69,43.01 187.39,43.01 187.28,42.91 187.28,42.6 187.18,42.49 186.88,42.49 186.78,42.6 186.78,42.91 186.67,43.01 186.37,43.01 186.27,42.91 186.27,42.6 186.17,42.49 185.93,42.49 185.8,42.63 185.8,42.95 185.74,43.01 168.25,43.01 163.66,47.6 163.66,49.43 163.08,50.01 163.08,50.35 161.82,51.61 160.69,51.61 159.48,52.82 159.23,52.82 158.64,53.41 v2(158.64,53.66)
  BOTTOM w0.076: UC1.AR21 158.96,53.99 v2(158.64,53.66)
  BOTTOM w0.102: v2(219.88,13.69) 220.23,14.04 220.23,14.76 219.9,15.08 JDIMM2.191
DDR_B_D49: length 94.2
  IN1 w0.102: v2(157.69,53.66) 157.69,52.74 159.51,50.91 161.47,50.91 162.07,50.3 162.07,49.87 162.85,49.1 162.85,46.34 167.41,41.78 183.07,41.78 183.58,41.27 198.86,41.27 219.3,20.83 219.3,19.21 219.17,19.08 218.11,19.08 217.98,18.96 217.98,18.73 218.08,18.63 219.27,18.63 219.4,18.5 219.4,18.24 219.27,18.12 218.08,18.12 217.98,18.02 217.98,17.71 218.08,17.61 219.27,17.61 219.4,17.48 219.4,17.23 219.27,17.1 218.08,17.1 217.98,17 217.98,16.7 218.08,16.59 218.22,16.59 218.35,16.47 218.35,16.21 218.22,16.09 218.08,16.09 217.98,15.98 217.98,15.6 218.11,15.47 218.38,15.47 218.51,15.34 218.51,14.87 v2(218.09,14.45)
  BOTTOM w0.076: UC1.AR22 158.01,53.99 v2(157.69,53.66)
  BOTTOM w0.102: JDIMM2.183 217.5,14.84 217.89,14.45 v2(218.09,14.45)
DDR_B_D50: length 96.1
  IN1 w0.102: v2(220.52,11.14) 221.96,12.58 221.96,20.77 199.58,43.14 195.69,43.14 195.59,43.24 195.59,43.54 195.49,43.64 195.18,43.64 195.08,43.54 195.08,43.24 194.98,43.14 194.67,43.14 194.57,43.24 194.57,43.54 194.47,43.64 194.17,43.64 194.07,43.54 194.07,43.24 193.96,43.14 193.65,43.14 193.52,43.27 193.52,43.51 193.39,43.64 168.38,43.64 164.17,47.85 164.17,49.58 163.61,50.14 163.61,50.45 161.98,52.08 160.98,52.08 159.83,53.24 159.49,53.24 159.22,53.51 159.22,55.69 v2(158.64,56.27)
  BOTTOM w0.076: UC1.AL21 158.96,56.59 v2(158.64,56.27)
  BOTTOM w0.102: v2(220.52,11.14) 220.95,10.71 220.95,9.37 220.8,9.22 JDIMM2.194
DDR_B_D51: length 96.6
  IN1 w0.102: v2(216.86,9.61) 217.73,9.61 217.86,9.74 217.86,10.06 217.76,10.17 217.42,10.17 217.32,10.27 217.32,10.57 217.42,10.67 217.76,10.67 217.86,10.78 217.86,11.08 217.76,11.18 217.42,11.18 217.32,11.28 217.32,11.59 217.42,11.69 217.76,11.69 217.86,11.79 217.86,12.29 217.73,12.42 217.36,12.42 217.23,12.55 217.23,15.76 217.35,15.88 217.35,21.88 198.8,40.43 178.07,40.43 177.35,41.15 167.05,41.15 162.39,45.8 162.39,48.92 161.78,49.53 160.45,49.53 160.03,49.95 159.53,49.95 156.47,53.02 156.47,55.12 156.72,55.37 157.44,55.37 v2(157.69,55.62)
  BOTTOM w0.076: v2(157.69,55.62) 158.01,55.94 UC1.AM22
  BOTTOM w0.102: v2(216.86,9.61) 216.6,9.35 JDIMM2.180
DDR_B_D52: length 95.4
  IN1 w0.102: v2(218.09,13.26) 217.59,13.77 217.59,15.67 217.67,15.75 217.67,19.3 217.77,19.4 218.64,19.4 218.77,19.53 218.77,19.78 218.64,19.91 217.77,19.91 217.67,20.01 217.67,20.31 217.77,20.42 218.75,20.42 218.88,20.54 218.88,20.8 218.75,20.92 217.77,20.92 217.67,21.03 217.67,22.01 198.73,40.95 183.45,40.95 182.94,41.46 167.18,41.46 162.62,46.02 162.62,49 161.83,49.78 161.38,49.78 160.52,50.64 159.35,50.64 157.31,52.68 157.31,54.8 157.49,54.98 v2(157.66,54.98)
  BOTTOM w0.076: v2(157.66,54.98) 157.97,55.29 UC1.AN22
  BOTTOM w0.102: JDIMM2.181 216.9,14.86 217.41,14.35 217.41,13.13 217.54,13 217.94,13 218.09,13.15 v2(218.09,13.26)
DDR_B_D53: length 93.6
  IN1 w0.102: v2(221.03,17.88) 221.03,15.58 220.56,15.1 220.56,14.41 220.8,14.17 221.28,14.17 221.52,14.41 221.52,18.65 221.53,18.66 221.53,20.76 199.48,42.81 193.31,42.81 193.21,42.91 193.21,43.22 193.1,43.32 192.8,43.32 192.7,43.22 192.7,42.91 192.6,42.81 192.29,42.81 192.19,42.91 192.19,43.22 192.09,43.32 191.78,43.32 191.68,43.22 191.68,42.91 191.58,42.81 191.28,42.81 191.16,42.94 191.16,43.2 191.03,43.32 168.37,43.32 163.92,47.78 163.92,49.5 163.36,50.06 163.36,50.44 161.96,51.84 160.84,51.84 159.65,53.03 159.42,53.03 159.01,53.44 159.01,53.94 v2(158.64,54.31)
  BOTTOM w0.076: v2(158.64,54.31) 158.96,54.64 UC1.AP21
  BOTTOM w0.102: JDIMM2.193 220.5,17.73 220.65,17.88 v2(221.03,17.88)
DDR_B_D54: length 96.3
  IN1 w0.102: v2(158.61,56.92) 158.99,57.29 159.75,57.29 159.97,57.07 159.97,53.52 161.18,52.31 162.2,52.31 163.89,50.62 163.89,50.19 164.45,49.63 164.45,47.85 167,45.3 167.14,45.3 168.48,43.96 195.62,43.96 196.12,43.46 199.7,43.46 222.29,20.87 222.29,12.48 221.03,11.22 221.03,10.13 v2(220.52,9.61)
  BOTTOM w0.076: UC1.AK21 158.94,57.24 v2(158.61,56.92)
  BOTTOM w0.102: v2(220.52,9.61) 220.2,9.3 JDIMM2.192
DDR_B_D55: length 97.3
  IN1 w0.102: v2(216.86,11.14) 216.86,10.89 216.73,10.76 216.08,10.76 215.95,10.89 215.95,12.41 216.08,12.53 216.79,12.53 216.91,12.66 216.91,17.37 217.03,17.49 217.03,21.75 198.67,40.11 177.51,40.11 176.79,40.83 166.92,40.83 162.16,45.58 162.16,48.81 161.68,49.29 160.38,49.29 159.97,49.71 159.28,49.71 156.26,52.73 156.26,55.33 156.63,55.7 156.93,55.7 157.31,56.08 157.31,56.54 v2(157.69,56.92)
  BOTTOM w0.076: v2(157.69,56.92) 158.01,57.24 UC1.AK22
  BOTTOM w0.102: JDIMM2.182 217.2,9.28 217.29,9.37 217.29,10.97 217.13,11.14 v2(216.86,11.14)
DDR_B_D56: length 59.3
  IN2 w0.102: v2(178.96,19) 178.53,19.42 178.53,20.39 178.64,20.49 178.94,20.49 179.04,20.59 179.04,20.9 178.94,21 178.64,21 178.53,21.1 178.53,21.41 178.64,21.51 178.94,21.51 179.04,21.61 179.04,21.92 178.94,22.02 178.64,22.02 178.53,22.12 178.53,22.42 178.64,22.52 178.94,22.52 179.04,22.63 179.04,22.93 178.94,23.03 178.64,23.03 178.53,23.13 178.53,23.64 167.9,34.28 167.9,35.27 168,35.37 168.62,35.37 168.74,35.5 168.74,35.76 168.62,35.88 168,35.88 167.9,35.98 167.9,36.29 168,36.39 168.62,36.39 168.74,36.52 168.74,36.77 168.62,36.9 168,36.9 167.9,37 167.9,37.3 168,37.41 168.62,37.41 168.74,37.53 168.74,37.79 168.62,37.91 168,37.91 167.9,38.02 167.9,38.32 168,38.42 168.62,38.42 168.74,38.55 168.74,38.8 168.62,38.93 168,38.93 167.9,39.03 167.9,39.34 168,39.44 168.62,39.44 168.74,39.57 168.74,39.82 168.62,39.95 168,39.95 167.9,40.05 167.9,40.35 168,40.45 168.51,40.45 168.64,40.58 168.64,40.84 168.51,40.96 168,40.96 167.9,41.06 167.9,41.58 164.44,45.03 164.02,45.03 162.99,46.06 162.99,48.75 161.96,49.78 161.56,49.78 161.25,50.09 161.25,50.85 159.22,52.88 159.22,54.59 v2(159.59,54.96)
  BOTTOM w0.076: v2(159.59,54.96) 159.92,55.29 UC1.AN20
  BOTTOM w0.102: JDIMM2.57 177.3,17.49 178.34,18.53 178.49,18.53 v2(178.96,19)
DDR_B_D57: length 57.8
  IN2 w0.102: v2(178.96,17.81) 178.83,17.81 178.7,17.69 178.7,16.71 178.57,16.58 178.38,16.58 178.25,16.45 178.25,14.05 178.38,13.92 179.26,13.92 179.38,14.05 179.38,14.58 179.28,14.68 178.94,14.68 178.84,14.78 178.84,15.09 178.94,15.19 179.28,15.19 179.38,15.29 179.38,15.59 179.28,15.7 178.94,15.7 178.84,15.8 178.84,16.1 178.94,16.2 179.28,16.2 179.38,16.31 179.38,23.24 169.06,33.57 169.06,40.87 164.95,44.98 164.95,45.48 163.24,47.18 163.24,48.86 162.14,49.96 162.14,50.38 159.59,52.93 v2(159.59,53.66)
  BOTTOM w0.076: v2(159.59,53.66) 159.92,53.99 UC1.AR20
  BOTTOM w0.102: v2(178.96,17.81) 178.94,17.83 178.25,17.83 177.9,17.48 177.9,16.43 JDIMM2.59
DDR_B_D58: length 60.5
  IN2 w0.102: v2(181.47,17.8) 181.99,17.8 182.35,18.16 182.35,23.42 172.06,33.71 172.06,35.9 172.16,36 172.59,36 172.72,36.13 172.72,36.38 172.59,36.51 172.16,36.51 172.06,36.61 172.06,36.92 172.16,37.02 172.84,37.02 172.95,37.12 172.95,37.43 172.84,37.53 172.16,37.53 172.06,37.63 172.06,37.93 172.16,38.04 172.84,38.04 172.95,38.14 172.95,38.44 172.84,38.54 172.16,38.54 172.06,38.65 172.06,38.95 172.16,39.05 172.84,39.05 172.95,39.15 172.95,39.46 172.84,39.56 172.16,39.56 172.06,39.66 172.06,39.97 172.16,40.07 172.84,40.07 172.95,40.17 172.95,40.47 172.84,40.58 172.16,40.58 172.06,40.68 172.06,40.98 172.16,41.08 172.84,41.08 172.95,41.19 172.95,41.49 172.84,41.59 171.56,41.59 166.84,46.32 166.84,47.09 165.41,48.51 165.41,49.79 164.66,50.55 163.94,50.55 161.38,53.11 161.38,54.36 161.15,54.58 161.15,55.93 160.97,56.11 160.97,56.49 v2(160.54,56.92)
  BOTTOM w0.076: v2(160.54,56.92) 160.87,57.24 UC1.AK18
  BOTTOM w0.102: JDIMM2.69 180.9,17.23 v2(181.47,17.8)
DDR_B_D59: length 59.3
  IN2 w0.102: v2(181.47,19) 181.91,19 182.04,19.13 182.04,19.96 181.91,20.09 181.48,20.09 181.35,20.22 181.35,20.47 181.48,20.6 181.78,20.6 181.88,20.7 181.88,21 181.78,21.1 181.49,21.1 181.37,21.23 181.37,21.49 181.49,21.61 181.78,21.61 181.88,21.71 181.88,22.01 181.76,22.14 181.47,22.14 181.35,22.26 181.35,22.54 181.47,22.67 181.79,22.67 181.91,22.8 181.91,23.1 181.79,23.23 181.47,23.23 181.35,23.35 181.35,23.98 170.97,34.35 170.97,35.05 171.07,35.15 171.52,35.15 171.63,35.25 171.63,35.56 171.52,35.66 171.07,35.66 170.97,35.76 170.97,36.06 171.07,36.17 171.52,36.17 171.63,36.27 171.63,36.57 171.52,36.67 171.07,36.67 170.97,36.78 170.97,37.08 171.07,37.18 171.52,37.18 171.63,37.28 171.63,37.59 171.52,37.69 171.07,37.69 170.97,37.79 170.97,38.13 171.07,38.23 171.51,38.23 171.62,38.33 171.62,38.64 171.51,38.74 171.07,38.74 170.97,38.84 170.97,39.15 171.07,39.25 171.51,39.25 171.62,39.35 171.62,39.65 171.51,39.75 171.07,39.75 170.97,39.86 170.97,40.12 171.1,40.25 171.49,40.25 171.61,40.37 171.61,40.64 171.49,40.77 171.1,40.77 170.97,40.89 170.97,41.75 167.23,45.49 167.01,45.49 164.53,47.97 164.53,49.55 163.81,50.27 163.81,50.37 161.17,53.02 161.17,54.28 160.94,54.5 160.94,55.87 v2(160.54,56.27)
  BOTTOM w0.076: v2(160.54,56.27) 160.87,56.59 UC1.AL18
  BOTTOM w0.102: v2(181.47,19) 180.3,17.83 JDIMM2.67
DDR_B_D60: length 60.7
  IN2 w0.102: v2(159.59,56.92) 159.18,57.33 158.39,57.33 158.23,57.17 158.23,52.33 158.97,51.59 159.6,51.59 160.63,50.56 160.63,50.2 161.54,49.28 161.68,49.28 162.54,48.42 162.54,45.93 164.09,44.37 164.2,44.37 167.27,41.31 167.27,34.01 177.86,23.42 177.86,16.96 177.57,16.67 177.57,10.4 v2(178.33,9.65)
  BOTTOM w0.076: UC1.AK20 159.92,57.24 v2(159.59,56.92)
  BOTTOM w0.102: JDIMM2.58 177.6,9.28 177.97,9.65 v2(178.33,9.65)
DDR_B_D61: length 60.2
  IN2 w0.102: v2(159.59,55.62) 159.01,55.04 159.01,52.76 160.97,50.8 160.97,50.11 161.58,49.5 161.94,49.5 162.76,48.68 162.76,46.03 164.06,44.73 164.3,44.73 167.58,41.44 167.58,34.14 178.19,23.54 178.19,16.84 177.94,16.59 177.94,13.7 178.04,13.6 178.65,13.6 178.78,13.47 178.78,13.22 178.65,13.09 178.04,13.09 177.94,12.99 177.94,12.69 178.04,12.58 178.61,12.58 178.74,12.46 178.74,12.2 178.61,12.08 178.04,12.08 177.94,11.98 177.94,10.97 178.09,10.82 v2(178.35,10.82)
  BOTTOM w0.076: UC1.AM20 159.92,55.94 v2(159.59,55.62)
  BOTTOM w0.102: JDIMM2.56 177,9.47 v2(178.35,10.82)
DDR_B_D62: length 56
  IN2 w0.102: v2(181.15,9.67) 180.86,9.67 180.73,9.8 180.73,9.99 180.6,10.12 180.36,10.12 180.24,10.25 180.24,10.46 180.36,10.59 180.53,10.59 180.65,10.72 180.65,10.98 180.55,11.08 180.36,11.08 180.24,11.21 180.24,11.46 180.36,11.59 180.55,11.59 180.65,11.69 180.65,23.76 170.33,34.08 170.33,41.52 167.1,44.75 166.8,44.75 164.07,47.48 164.07,49.12 163.18,50.01 163.18,50.46 160.54,53.1 v2(160.54,53.66)
  BOTTOM w0.076: v2(160.54,53.66) 160.87,53.99 UC1.AR18
  BOTTOM w0.102: JDIMM2.70 181.2,9.63 v2(181.15,9.67)
DDR_B_D63: length 57.6
  IN2 w0.102: v2(160.54,54.31) 160.94,53.92 160.94,52.99 163.51,50.41 163.51,50.13 164.28,49.35 164.28,47.61 166.76,45.14 167.15,45.14 170.65,41.64 170.65,34.22 181.03,23.84 181.03,12.06 181.16,11.94 182.13,11.94 182.26,11.81 182.26,11.18 182.13,11.05 181.31,11.05 181.18,10.92 v2(181.18,10.87)
  BOTTOM w0.076: v2(160.54,54.31) 160.87,54.64 UC1.AP18
  BOTTOM w0.102: JDIMM2.68 180.6,10.29 v2(181.18,10.87)
DDR_B_DQS0: length 84.9
  IN1 w0.102: v2(152.46,49.06) 152.46,49.19 152.64,49.36 153.1,49.36 153.48,48.97 153.48,44.04 152.94,43.49 152.94,42.1 153.22,41.82 153.22,39.38 162.35,30.25 193.89,30.25 202.74,21.41 202.74,16.7 203.43,16.01 204.15,16.01 204.46,15.7 204.46,14.21 204.29,14.04 204.02,14.04 203.77,14.28 v2(203.77,14.28)
  BOTTOM w0.076: v2(152.46,49.06) 152.46,49.27 152.38,49.36 152.32,49.36 152.22,49.46 152.08,49.46 151.9,49.65 151.9,50.33 152.29,50.72 152.29,50.96 arc(152.24,51.08) 152.22,51.2 arc(152.24,51.34) 152.3,51.47 arc(152.33,51.53) 152.3,51.6 arc(152.23,51.76) 152.24,51.94 152.26,52.05 arc(152.36,52.2) 152.53,52.26 152.61,52.26 arc(152.66,52.28) 152.68,52.34 UC1.AV30
  BOTTOM w0.102: v2(203.77,14.28) 203.58,14.1 203.36,14.1 203.15,14.31 203.15,14.86 203.5,15.21 203.5,15.48 203.7,15.68 JDIMM2.137
DDR_B_DQS1: length 51.2
  IN2 w0.102: v2(164.05,10.33) 164.11,10.4 164.11,10.53 163.95,10.68 163.88,10.68 163.85,10.71 163.43,10.71 163.23,10.92 163.23,20.22 156.11,27.33 156.11,37.62 155.01,38.72 155.01,41.73 154.96,41.79 154.96,46.17 155.46,46.68 155.87,46.68 156.05,46.86 v2(156.05,46.97)
  BOTTOM w0.076: UC1.AW26 155.01,51.85 154.92,51.76 154.92,51.62 arc(154.9,51.48) 154.85,51.33 arc(154.82,51.22) 154.84,51.11 154.9,50.93 154.9,50.54 154.54,50.19 154.54,49.9 155.1,49.34 155.1,47.33 155.75,46.69 155.91,46.69 156.05,46.83 v2(156.05,46.97)
  BOTTOM w0.102: JDIMM2.12 163.8,9.12 163.54,9.38 163.54,10.52 163.71,10.69 163.93,10.69 164.05,10.57 v2(164.05,10.33)
DDR_B_DQS2: length 92.3
  IN1 w0.102: v2(153.98,55.62) 153.98,55.61 153.76,55.39 153.57,55.39 153.39,55.21 153.39,53.05 155.8,50.64 155.8,49.89 156.42,49.27 156.42,42.86 157.09,42.19 157.09,41.09 164.29,33.89 196.49,33.89 209.52,20.87 209.52,17.28 208.69,16.45 208.69,11.38 208.57,11.25 208.23,11.25 207.96,11.52 v2(207.95,11.52)
  BOTTOM w0.076: UC1.AM28 154.31,55.94 v2(153.98,55.62)
  BOTTOM w0.102: v2(207.95,11.52) 208.1,11.37 208.46,11.37 208.69,11.14 208.69,9.48 208.8,9.37 JDIMM2.154
DDR_B_DQS3: length 54.6
  IN2 w0.102: v2(169.01,18.47) 169.01,18.48 168.85,18.64 168.58,18.64 168.32,18.9 168.32,20.41 168.55,20.63 168.57,20.63 168.67,20.74 168.67,21.04 168.57,21.14 168.55,21.14 168.32,21.37 168.32,21.71 163.66,26.38 163.66,26.7 164.38,27.42 164.38,27.6 164.2,27.78 164.02,27.78 163.3,27.06 162.98,27.06 162.64,27.4 162.64,27.71 163.38,28.45 163.38,28.6 163.17,28.81 163.02,28.81 162.28,28.07 161.97,28.07 161.63,28.41 161.63,28.73 162.37,29.47 162.37,29.61 162.15,29.83 162.01,29.83 161.41,29.23 161.06,29.23 160.67,29.62 160.67,29.98 161.17,30.48 161.17,30.77 160.67,31.28 160.67,38.74 158.72,40.69 158.72,42.27 157.51,43.49 157.51,49.83 157.29,50.04 157.29,50.62 155.31,52.61 155.31,55.17 155.54,55.39 155.77,55.39 155.89,55.51 v2(155.89,55.62)
  BOTTOM w0.076: v2(155.89,55.62) 156.21,55.94 UC1.AM25
  BOTTOM w0.102: JDIMM2.29 168.9,16.43 168.9,17.26 168.69,17.47 168.69,17.61 168.34,17.96 168.34,18.59 168.42,18.67 168.8,18.67 v2(169.01,18.47)
DDR_B_DQS4: length 87.3
  IN1 w0.102: v2(158.08,48.27) 158.24,48.43 158.83,48.43 159.1,48.16 159.1,44.26 161.14,42.22 161.92,42.22 166.21,37.94 167.6,37.94 167.82,38.16 167.82,38.4 167.95,38.53 168.2,38.53 168.33,38.4 168.33,38.16 168.55,37.94 169.03,37.94 169.25,38.16 169.25,38.25 169.38,38.38 169.63,38.38 169.76,38.25 169.76,38.16 169.98,37.94 197.77,37.94 214.36,21.35 214.36,16.64 214.64,16.36 214.64,14.03 214.53,13.92 214.42,13.92 214.38,13.97 214.33,13.97 214.21,14.09 v2(214.21,14.2)
  BOTTOM w0.076: UC1.AV22 157.82,52.34 arc(157.79,52.28) 157.74,52.26 157.66,52.26 arc(157.5,52.2) 157.42,52.05 arc(157.41,52.02) 157.4,51.99 arc(157.37,51.86) 157.38,51.74 157.42,51.6 arc(157.43,51.5) 157.4,51.41 arc(157.36,51.18) 157.42,50.97 157.42,50.62 157.31,50.51 157.31,50.03 157.66,49.69 157.66,48.83 158.08,48.42 v2(158.08,48.27)
  BOTTOM w0.102: v2(214.21,14.2) 214.21,14.12 214.01,13.92 213.78,13.92 213.65,14.05 213.65,15.22 213.9,15.47 JDIMM2.171
DDR_B_DQS5: length 50.8
  IN2 w0.102: v2(175.11,18.4) 175.11,18.43 174.96,18.59 174.72,18.59 174.46,18.86 174.46,18.88 174.43,18.9 174.43,22.72 169.57,27.58 169.57,27.89 169.87,28.18 169.87,28.33 169.65,28.54 169.51,28.54 169.22,28.25 168.9,28.25 168.56,28.59 168.56,28.91 168.85,29.2 168.85,29.34 168.64,29.56 168.49,29.56 168.2,29.27 167.89,29.27 167.55,29.61 167.55,29.92 167.84,30.21 167.84,30.36 167.62,30.57 167.48,30.57 167.19,30.28 166.87,30.28 166.53,30.62 166.53,30.94 166.82,31.23 166.82,31.37 166.61,31.59 166.46,31.59 166.17,31.29 165.86,31.29 165.52,31.63 165.52,31.95 165.81,32.24 165.81,32.39 165.59,32.6 165.45,32.6 165.16,32.31 164.84,32.31 164.53,32.62 164.53,37.46 164.54,37.46 164.54,40.59 161.99,43.14 161.61,43.14 161.03,43.72 161.03,45.83 161.37,46.17 161.58,46.17 161.63,46.21 161.68,46.21 161.79,46.32 v2(161.79,46.5)
  BOTTOM w0.076: v2(161.79,46.5) 161.79,46.27 161.71,46.19 161.64,46.19 161.61,46.17 161.4,46.17 160.37,47.19 160.37,49.53 159.79,50.11 159.79,50.42 160.03,50.65 160.03,50.79 arc(160.03,50.96) 159.96,51.11 arc(159.92,51.19) 159.95,51.28 arc(160.03,51.46) 160.03,51.65 arc(160.04,51.74) 160.08,51.81 arc(160.16,51.85) UC1.AW18
  BOTTOM w0.102: v2(175.11,18.4) 175.11,18.44 174.89,18.67 174.67,18.67 174.03,18.03 174.03,17.68 174.3,17.4 JDIMM2.47
DDR_B_DQS6: length 94.6
  IN1 w0.102: v2(158.62,55.69) 158.62,55.48 158.53,55.4 158.24,55.4 158.05,55.2 158.05,53.4 159.04,52.41 159.21,52.41 160.44,51.19 161.62,51.19 162.49,50.32 162.49,49.91 163.13,49.28 163.13,47.18 168.02,42.29 183.29,42.29 183.81,41.78 199.07,41.78 219.91,20.94 219.91,15.98 219.46,15.53 219.46,14.44 218.88,13.85 218.88,12.71 218.37,12.2 218.37,11.27 218.64,10.99 219.01,10.99 v2(219.25,10.76)
  BOTTOM w0.076: UC1.AM21 158.87,55.94 v2(158.62,55.69)
  BOTTOM w0.102: JDIMM2.188 219,9.27 218.79,9.48 218.79,10.82 218.9,10.94 219.07,10.94 v2(219.25,10.76)
DDR_B_DQS7: length 58.4
  IN2 w0.102: v2(160.54,55.62) 160.54,55.45 160.45,55.36 160.19,55.36 159.97,55.14 159.97,52.94 162.52,50.39 162.52,49.97 163.55,48.94 163.55,47.24 169.62,41.17 169.62,33.74 179.93,23.43 179.93,12.43 178.87,11.38 178.87,10.77 179.17,10.47 179.46,10.47 v2(179.65,10.28)
  BOTTOM w0.076: v2(160.54,55.62) 160.87,55.94 UC1.AM18
  BOTTOM w0.102: v2(179.65,10.28) 179.41,10.52 179.22,10.52 179.14,10.43 179.14,9.44 179.4,9.17 JDIMM2.64
DDR_B_DQS#0: length 85
  IN1 w0.102: v2(152.46,49.71) 152.6,49.57 153.18,49.57 153.69,49.06 153.69,43.95 153.15,43.41 153.15,42.19 153.43,41.91 153.43,39.47 162.43,30.46 193.98,30.46 202.94,21.5 202.94,16.79 203.51,16.22 204.24,16.22 204.67,15.79 204.67,14.12 204.38,13.83 203.95,13.83 v2(203.77,13.65)
  BOTTOM w0.076: UC1.AW30 152.68,52.02 arc(152.66,52.07) 152.61,52.1 152.53,52.1 arc(152.46,52.07) 152.42,52.01 152.4,51.9 arc(152.4,51.8) 152.44,51.7 arc(152.49,51.53) 152.44,51.37 arc(152.4,51.29) 152.38,51.2 arc(152.39,51.12) 152.43,51.05 152.45,51.01 152.45,50.65 152.07,50.26 152.07,49.71 152.15,49.63 152.38,49.63 v2(152.46,49.71)
  BOTTOM w0.102: v2(203.77,13.65) 203.77,13.69 203.57,13.89 203.28,13.89 202.94,14.23 202.94,14.94 203.3,15.3 203.3,15.49 203.1,15.69 JDIMM2.135
DDR_B_DQS#1: length 51.1
  IN2 w0.102: v2(164.05,11.1) 163.87,10.92 163.52,10.92 163.43,11.01 163.43,20.31 156.32,27.42 156.32,37.71 155.22,38.81 155.22,41.82 155.16,41.87 155.16,46.09 155.55,46.47 155.9,46.47 v2(156.05,46.32)
  BOTTOM w0.076: UC1.AV26 155.11,52.34 155.04,52.26 155.04,52.18 154.75,51.89 154.75,51.62 arc(154.74,51.51) 154.7,51.4 arc(154.65,51.23) 154.68,51.05 154.73,50.91 154.73,50.61 154.37,50.25 154.37,49.83 154.94,49.27 154.94,47.25 155.67,46.51 155.94,46.51 156.05,46.41 v2(156.05,46.32)
  BOTTOM w0.102: JDIMM2.10 163.2,9.37 163.33,9.5 163.33,10.6 163.63,10.9 163.91,10.9 164.05,11.03 v2(164.05,11.1)
DDR_B_DQS#2: length 92.3
  IN1 w0.102: v2(153.98,54.96) 153.76,55.18 153.66,55.18 153.6,55.13 153.6,53.13 156,50.73 156,49.97 156.63,49.35 156.63,42.95 157.3,42.28 157.3,41.18 164.38,34.1 196.58,34.1 209.73,20.95 209.73,17.19 208.9,16.37 208.9,11.29 208.65,11.04 208.24,11.04 v2(207.95,10.76)
  BOTTOM w0.076: v2(153.98,54.96) 154.31,55.29 UC1.AN28
  BOTTOM w0.102: JDIMM2.152 208.2,9.26 208.49,9.55 208.49,11.05 208.38,11.17 208.17,11.17 207.95,10.95 v2(207.95,10.76)
DDR_B_DQS#3: length 54.5
  IN2 w0.102: v2(169.01,19.1) 169.01,18.99 168.87,18.85 168.67,18.85 168.53,18.99 168.53,20.32 168.63,20.43 168.66,20.43 168.88,20.65 168.88,21.13 168.66,21.35 168.63,21.35 168.53,21.45 168.53,21.8 163.86,26.47 163.86,26.61 164.59,27.33 164.59,27.69 164.29,27.99 163.93,27.99 163.21,27.27 163.07,27.27 162.85,27.48 162.85,27.63 163.59,28.37 163.59,28.68 163.25,29.02 162.94,29.02 162.2,28.28 162.05,28.28 161.84,28.5 161.84,28.64 162.58,29.38 162.58,29.7 162.24,30.04 161.92,30.04 161.33,29.44 161.15,29.44 160.88,29.71 160.88,29.89 161.38,30.39 161.38,30.86 160.88,31.36 160.88,38.83 158.93,40.78 158.93,42.36 157.71,43.57 157.71,49.91 157.5,50.12 157.5,50.71 155.52,52.69 155.52,55.08 155.62,55.18 155.79,55.18 155.89,55.08 v2(155.89,54.96)
  BOTTOM w0.076: UC1.AN25 156.06,55.29 155.89,55.12 v2(155.89,54.96)
  BOTTOM w0.102: JDIMM2.27 168.3,16.43 168.3,17.28 168.49,17.47 168.49,17.52 168.14,17.87 168.14,18.67 168.34,18.87 168.9,18.87 169.01,18.98 v2(169.01,19.1)
DDR_B_DQS#4: length 87.4
  IN1 w0.102: v2(158.08,48.92) 158.08,48.79 158.23,48.64 158.91,48.64 159.31,48.25 159.31,44.35 161.22,42.43 162.01,42.43 166.3,38.15 167.51,38.15 167.61,38.25 167.61,38.49 167.86,38.73 168.29,38.73 168.54,38.49 168.54,38.25 168.64,38.15 168.94,38.15 169.04,38.25 169.04,38.34 169.29,38.59 169.72,38.59 169.97,38.34 169.97,38.25 170.07,38.15 197.85,38.15 214.56,21.43 214.56,16.73 214.84,16.45 214.84,13.94 214.61,13.72 214.36,13.72 v2(214.21,13.56)
  BOTTOM w0.076: UC1.AW22 157.82,52.02 arc(157.79,52.07) 157.74,52.1 157.66,52.1 arc(157.61,52.08) 157.58,52.02 arc(157.57,51.97) 157.55,51.92 arc(157.53,51.85) 157.54,51.78 157.58,51.64 arc(157.59,51.49) 157.55,51.33 arc(157.52,51.19) 157.56,51.05 157.59,51.01 157.59,50.55 157.48,50.44 157.48,50.1 157.83,49.76 157.83,48.96 157.88,48.9 158.06,48.9 v2(158.08,48.92)
  BOTTOM w0.102: v2(214.21,13.56) 214.06,13.72 213.69,13.72 213.45,13.96 213.45,15.32 213.3,15.46 213.3,16.43 JDIMM2.169
DDR_B_DQS#5: length 50.7
  IN2 w0.102: v2(161.79,45.85) 161.67,45.96 161.45,45.96 161.23,45.74 161.23,43.81 161.7,43.34 162.08,43.34 164.75,40.68 164.75,37.38 164.74,37.37 164.74,32.7 164.93,32.52 165.07,32.52 165.36,32.81 165.68,32.81 166.02,32.47 166.02,32.16 165.73,31.86 165.73,31.72 165.94,31.5 166.09,31.5 166.38,31.79 166.69,31.79 167.03,31.46 167.03,31.14 166.74,30.85 166.74,30.71 166.96,30.49 167.1,30.49 167.39,30.78 167.71,30.78 168.05,30.44 168.05,30.13 167.75,29.83 167.75,29.69 167.97,29.47 168.11,29.47 168.41,29.77 168.72,29.77 169.06,29.43 169.06,29.11 168.77,28.82 168.77,28.68 168.99,28.46 169.13,28.46 169.42,28.75 169.74,28.75 170.08,28.41 170.08,28.1 169.78,27.81 169.78,27.66 174.64,22.81 174.64,18.99 174.82,18.81 174.92,18.81 v2(175.11,19.01)
  BOTTOM w0.076: UC1.AV18 159.97,51.93 arc(159.88,51.79) 159.87,51.62 arc(159.87,51.49) 159.82,51.38 arc(159.76,51.19) 159.83,51 arc(159.87,50.92) 159.87,50.83 159.87,50.81 159.87,50.72 159.86,50.72 159.85,50.72 159.62,50.49 159.62,50.04 160.2,49.46 160.2,47.12 161.32,45.99 161.64,45.99 v2(161.79,45.85)
  BOTTOM w0.102: v2(175.11,19.01) 174.98,18.87 174.58,18.87 173.82,18.11 173.82,17.62 173.7,17.5 JDIMM2.45
DDR_B_DQS#6: length 94.6
  IN1 w0.102: v2(219.25,11.52) 219.25,11.43 219.01,11.2 218.73,11.2 218.58,11.35 218.58,12.12 219.09,12.62 219.09,13.77 219.67,14.35 219.67,15.44 220.12,15.89 220.12,21.02 199.16,41.99 183.89,41.99 183.38,42.5 168.1,42.5 163.33,47.27 163.33,49.36 162.7,50 162.7,50.4 161.71,51.4 160.52,51.4 159.3,52.62 159.12,52.62 158.26,53.48 158.26,55.12 158.33,55.19 158.51,55.19 158.64,55.06 v2(158.64,54.93)
  BOTTOM w0.076: v2(158.64,54.93) 159,55.29 UC1.AN21
  BOTTOM w0.102: v2(219.25,11.52) 219.25,11.28 219.11,11.14 218.82,11.14 218.59,10.91 218.59,9.5 218.4,9.31 JDIMM2.186
DDR_B_DQS#7: length 58.3
  IN2 w0.102: v2(160.54,54.96) 160.54,55.04 160.44,55.15 160.27,55.15 160.18,55.06 160.18,53.03 162.73,50.48 162.73,50.06 163.76,49.03 163.76,47.33 169.83,41.26 169.83,33.83 180.13,23.52 180.13,12.34 179.08,11.29 179.08,10.86 179.26,10.68 179.51,10.68 179.65,10.81 v2(179.65,11.04)
  BOTTOM w0.076: UC1.AN18 160.87,55.29 v2(160.54,54.96)
  BOTTOM w0.102: JDIMM2.62 178.8,9.25 178.94,9.38 178.94,10.51 179.14,10.72 179.54,10.72 179.65,10.83 v2(179.65,11.04)
DDR_B_MA0: length 84.9
  IN1 w0.076: 143.82,42.1 143.82,43.06 144.22,43.45 144.22,46.37 144.69,46.84 144.69,53.38 144.85,53.54 144.85,53.73 145.18,54.05 146,54.05 v2(146.26,54.31)
  IN1 w0.152: 143.82,42.1 143.82,35.58 158.47,20.94 181.98,20.94 182.99,19.93 186.95,19.93 191.86,15.02 191.86,14.98 192.92,13.91 192.92,11.76 192.45,11.28 v2(192.45,11.19)
  BOTTOM w0.076: v2(146.26,54.31) 146.59,54.64 UC1.AP40
  BOTTOM w0.152: v2(192.45,11.19) 192,10.75 192,9.96 192,9.96 JDIMM2.98
DDR_B_MA1: length 84.6
  IN1 w0.076: v2(146.26,53.66) 146.03,53.89 145.77,53.89 145.64,53.77 145.64,53.45 145.51,53.32 145.3,53.32 145.17,53.2 145.17,46.57 145.22,46.52 145.22,43.42 144.64,42.84 144.64,42.1
  IN1 w0.152: 144.64,42.1 144.64,35.92 158.8,21.75 183.05,21.75 183.2,21.6 183.2,20.87 183.33,20.74 183.63,20.74 183.76,20.87 183.76,21.6 183.91,21.75 184.17,21.75 184.32,21.6 184.32,20.87 184.44,20.74 184.75,20.74 184.88,20.87 184.88,21.6 185.03,21.75 185.28,21.75 185.44,21.6 185.44,20.87 185.56,20.74 185.87,20.74 185.99,20.87 185.99,21.6 186.15,21.75 186.4,21.75 186.55,21.6 186.55,20.87 186.68,20.74 186.98,20.74 187.11,20.87 187.11,21.6 187.26,21.75 190.15,21.75 190.54,21.37 190.54,20.75 191.12,20.17 v2(191.36,20.17)
  BOTTOM w0.076: UC1.AR40 146.59,53.99 v2(146.26,53.66)
  BOTTOM w0.152: v2(191.36,20.17) 191.7,20.17 192.2,19.67 192.2,18 191.7,17.5 JDIMM2.97
DDR_B_MA2: length 87.7
  IN1 w0.076: 143.42,42.1 143.42,43 143.98,43.56 143.98,46.52 144.43,46.98 144.43,53.02 143.89,53.56 143.89,54.47 144.22,54.8 145.02,54.8 v2(145.36,54.46)
  IN1 w0.152: v2(192.45,12.72) 192.02,13.15 192.02,14.24 191.58,14.68 191.36,14.68 190.96,14.28 190.74,14.28 190.56,14.46 190.56,14.67 190.97,15.08 190.97,15.34 189.99,16.32 189.98,16.32 186.78,19.52 182.41,19.52 182.31,19.62 182.31,20.03 181.81,20.53 158.3,20.53 143.42,35.41 143.42,42.1
  BOTTOM w0.076: UC1.AP42 145.55,54.64 v2(145.36,54.46)
  BOTTOM w0.152: v2(192.45,12.72) 191.4,11.67 191.4,10.01 191.4,10.01 JDIMM2.96
DDR_B_MA3: length 86.5
  IN1 w0.076: 144.23,42.1 144.23,43.1 144.49,43.35 144.49,46.24 144.96,46.71 144.96,53.34 v2(145.29,53.67)
  IN1 w0.152: 144.23,42.1 144.23,35.75 158.63,21.35 182.14,21.35 183.16,20.33 187.72,20.33 187.87,20.49 187.87,21.2 188.02,21.35 188.28,21.35 188.43,21.2 188.43,19.02 188.56,18.9 188.86,18.9 188.99,19.02 188.99,21.2 189.14,21.35 189.39,21.35 189.55,21.2 189.55,20.18 189.67,20.05 190.66,20.05 190.79,19.92 190.79,19.44 190.66,19.32 189.76,19.32 189.63,19.19 189.63,18.77 189.76,18.64 v2(191.36,18.64)
  BOTTOM w0.076: v2(145.29,53.67) 145.52,53.67 UC1.AR42
  BOTTOM w0.152: v2(191.36,18.64) 191.03,18.97 190.52,18.97 190.24,18.69 190.24,18.27 191.1,17.42 JDIMM2.95
DDR_B_MA4: length 91.7
  IN1 w0.076: v2(143.47,53.77) 143.38,53.68 143.38,50.32 144.07,49.64 144.07,47.05 143.72,46.71 143.72,43.66 143.01,42.95 143.01,42.1
  IN1 w0.152: 143.01,42.1 143.01,35.24 158.13,20.12 162.58,20.12 162.71,20 162.71,18.01 162.83,17.88 163.91,17.88 164.04,18.01 164.04,20 164.17,20.12 173.17,20.12 173.3,20 173.3,17.9 173.43,17.77 174.5,17.77 174.62,17.9 174.62,20 174.75,20.12 181.57,20.12 181.9,19.79 181.9,19.45 182.24,19.11 186.61,19.11 189.61,16.12 189.61,14.03 190.21,13.43 v2(190.21,12.72)
  BOTTOM w0.076: v2(143.47,53.77) 143.69,53.99 UC1.AR45
  BOTTOM w0.152: JDIMM2.92 190.2,9.69 190.74,10.23 190.74,12.19 v2(190.21,12.72)
DDR_B_MA5: length 92.2
  IN1 w0.076: v2(143.49,54.4) 143.12,54.03 143.12,50.28 143.44,49.96 143.44,43.84 142.61,43 142.61,42.1
  IN1 w0.152: 142.61,42.1 142.61,35.08 158.54,19.14 159.74,19.14 160.32,19.72 161.68,19.72 161.77,19.63 161.77,17.74 162.14,17.37 164.8,17.37 164.93,17.49 164.93,19.59 165.06,19.72 166.43,19.72 166.55,19.59 166.55,17.49 166.68,17.37 167.32,17.37 167.44,17.49 167.44,19.52 167.57,19.65 168.45,19.65 168.57,19.52 168.57,17.49 168.7,17.37 170.58,17.37 170.71,17.49 170.71,19.59 170.83,19.72 172.26,19.72 172.38,19.59 172.38,17.49 172.51,17.37 181.64,17.37 182.99,18.71 186.18,18.71 v2(186.61,18.27)
  BOTTOM w0.076: v2(143.49,54.4) 143.73,54.64 UC1.AP45
  BOTTOM w0.152: JDIMM2.91 189.9,17.5 188.76,18.64 186.98,18.64 v2(186.61,18.27)
DDR_B_MA6: length 95.4
  IN1 w0.076: 141.79,42.1 141.79,42.95 142.96,44.12 142.96,47.26 143.04,47.33 143.04,49.77 142.66,50.16 142.33,50.16 142.12,50.36 142.12,50.82 v2(142.47,51.17)
  IN1 w0.152: 141.79,42.1 141.79,34.74 158.21,18.33 160.03,18.33 161.8,16.55 185.17,16.55 185.52,16.2 187.5,16.2 188.35,15.35 188.35,14.48 189.78,13.05 189.78,10.13 189.91,10 190.64,10 190.76,9.87 190.76,9.69 190.89,9.56 191.92,9.56 192.05,9.69 192.05,10.11 191.92,10.24 191.36,10.24 191.21,10.39 191.21,10.64 191.36,10.8 191.86,10.8 192.02,10.95 192.02,11.2 191.86,11.36 191.36,11.36 191.21,11.51 191.21,11.76 191.36,11.91 191.86,11.91 192.02,12.07 192.02,12.57 191.89,12.7 191.74,12.7 191.61,12.83 191.61,13.74 191.48,13.87 190.77,13.87 190.64,13.74 190.64,11.32 190.52,11.19 v2(190.21,11.19)
  BOTTOM w0.076: v2(142.47,51.17) 142.83,51.53 UC1.AW46
  BOTTOM w0.152: v2(190.21,11.19) 189.6,10.58 189.6,8.23 JDIMM2.90
DDR_B_MA7: length 94.3
  IN1 w0.076: 141.39,42.1 141.39,42.93 142.71,44.25 142.71,47.55 142.88,47.72 142.88,49.68 142.79,49.78 v2(142.51,49.78)
  IN1 w0.152: 141.39,42.1 141.39,34.57 158.04,17.92 159.86,17.92 161.63,16.15 185,16.15 185.35,15.8 187.33,15.8 187.94,15.18 187.94,14.31 189.37,12.88 189.37,11.66 189.25,11.54 188.66,11.54 188.5,11.38 188.5,11.13 188.66,10.98 189.25,10.98 189.37,10.85 189.37,10.55 189.25,10.42 188.66,10.42 188.5,10.27 188.5,9.79 188.63,9.66 189.68,9.66 189.8,9.54 189.8,9.23 189.68,9.11 187.06,9.11 186.93,9.23 186.93,9.6 187.06,9.73 187.82,9.73 187.94,9.85 187.94,12.37 187.6,12.72 v2(187.51,12.72)
  BOTTOM w0.076: v2(142.51,49.78) 142.89,50.15 UC1.AY46
  BOTTOM w0.152: JDIMM2.86 188.4,9.4 188.5,9.5 188.5,11.73 v2(187.51,12.72)
DDR_B_MA8: length 93.2
  IN1 w0.076: v2(142.48,50.53) 142.56,50.53 143.2,49.89 143.2,47.13 143.22,47.12 143.22,43.99 142.2,42.98 142.2,42.1
  IN1 w0.152: v2(189.14,14.93) 188.89,14.93 188.76,15.06 188.76,15.73 188.97,15.94 188.97,16.16 188.79,16.34 188.58,16.34 188.36,16.13 188.15,16.13 187.95,16.33 187.95,16.61 187.8,16.76 187.8,17.28 187.67,17.41 187.37,17.41 187.24,17.28 187.24,16.76 187.09,16.61 186.83,16.61 186.68,16.76 186.68,17.72 186.55,17.85 186.25,17.85 186.12,17.72 186.12,16.76 185.97,16.61 185.69,16.61 185.34,16.96 184.84,16.96 184.69,17.11 184.69,18.17 184.56,18.3 184.26,18.3 184.13,18.17 184.13,17.11 183.98,16.96 183.72,16.96 183.57,17.11 183.57,18.16 183.44,18.29 183.14,18.29 183.01,18.16 183.01,17.11 182.86,16.96 172.1,16.96 171.98,17.09 171.98,19.18 171.85,19.31 171.24,19.31 171.11,19.18 171.11,17.33 170.75,16.96 166.32,16.96 166.15,17.13 166.15,19.18 166.02,19.31 165.46,19.31 165.34,19.18 165.34,17.33 164.97,16.96 161.97,16.96 161.36,17.57 161.36,19.21 161.25,19.31 160.49,19.31 160.37,19.2 160.37,18.91 160.2,18.73 158.37,18.73 142.2,34.91 142.2,42.1
  BOTTOM w0.076: v2(142.48,50.53) 142.13,50.88 UC1.AY47
  BOTTOM w0.152: JDIMM2.89 189.3,15.1 v2(189.14,14.93)
DDR_B_MA9: length 96.2
  IN1 w0.076: 140.98,42.1 140.98,42.99 142.45,44.46 142.45,48.02 v2(142.53,48.1)
  IN1 w0.152: v2(187.51,14.24) 187.51,14.16 188.97,12.71 188.97,12.19 188.86,12.08 188.5,12.08 188.35,12.23 188.35,12.54 187.61,13.28 187.15,13.28 186.99,13.45 186.99,15.18 186.78,15.39 185.18,15.39 184.83,15.74 179.64,15.74 179.49,15.59 179.49,15.36 179.34,15.21 179.08,15.21 178.93,15.36 178.93,15.59 178.78,15.74 178.52,15.74 178.37,15.59 178.37,15.36 178.22,15.21 177.97,15.21 177.81,15.36 177.81,15.59 177.66,15.74 177.41,15.74 177.25,15.59 177.25,15.36 177.1,15.21 176.85,15.21 176.7,15.36 176.7,15.59 176.54,15.74 176.29,15.74 176.14,15.59 176.14,15.36 175.98,15.21 175.73,15.21 175.58,15.36 175.58,15.59 175.43,15.74 175.17,15.74 175.02,15.59 175.02,15.36 174.87,15.21 174.61,15.21 174.46,15.36 174.46,15.59 174.31,15.74 174.05,15.74 173.9,15.59 173.9,15.36 173.75,15.21 173.5,15.21 173.34,15.36 173.34,15.59 173.19,15.74 172.94,15.74 172.78,15.59 172.78,15.36 172.63,15.21 172.38,15.21 172.23,15.36 172.23,15.59 172.07,15.74 171.69,15.74 171.54,15.59 171.54,15.34 171.41,15.21 171.11,15.21 170.98,15.34 170.98,15.59 170.83,15.74 170.57,15.74 170.42,15.59 170.42,15.34 170.29,15.21 169.99,15.21 169.86,15.34 169.86,15.59 169.71,15.74 169.46,15.74 169.3,15.59 169.3,15.34 169.18,15.21 168.87,15.21 168.74,15.34 168.74,15.59 168.59,15.74 168.34,15.74 168.19,15.59 168.19,15.34 168.06,15.21 167.75,15.21 167.63,15.34 167.63,15.59 167.47,15.74 167.22,15.74 167.07,15.59 167.07,15.34 166.94,15.21 166.64,15.21 166.51,15.34 166.51,15.59 166.36,15.74 166.1,15.74 165.95,15.59 165.95,15.34 165.82,15.21 165.52,15.21 165.39,15.34 165.39,15.59 165.24,15.74 164.99,15.74 164.83,15.59 164.83,15.34 164.71,15.21 164.4,15.21 164.27,15.34 164.27,15.59 164.12,15.74 163.87,15.74 163.72,15.59 163.72,15.34 163.59,15.21 163.28,15.21 163.16,15.34 163.16,15.59 163,15.74 162.75,15.74 162.6,15.59 162.6,15.34 162.47,15.21 162.17,15.21 162.04,15.34 162.04,15.59 161.89,15.74 161.46,15.74 159.69,17.51 157.87,17.51 140.98,34.4 140.98,42.1
  BOTTOM w0.076: v2(142.53,48.1) 141.92,48.72 141.92,50.19 141.59,50.51 141.59,52.01 141.67,52.09 141.67,52.9 141.89,53.12 142.15,53.12 142.28,52.99 142.3,52.99 142.31,52.98 142.79,52.98 UC1.AU46
  BOTTOM w0.152: JDIMM2.85 188.1,14.83 v2(187.51,14.24)
DDR_B_MA10: length 99.8
  IN1 w0.076: 147.37,42.1 147.37,42.25 148.09,42.98 148.09,47.12 148.31,47.34 148.31,56.86 148.51,57.07 v2(148.69,57.07)
  IN1 w0.152: v2(195.83,20.18) 195.39,20.61 195.39,21.41 192.54,24.26 179.38,24.26 179.23,24.41 179.23,24.91 179.08,25.06 178.82,25.06 178.67,24.91 178.67,24.41 178.52,24.26 178.27,24.26 178.11,24.41 178.11,24.91 177.96,25.06 177.71,25.06 177.55,24.91 177.55,24.41 177.4,24.26 177.15,24.26 177,24.41 177,24.91 176.84,25.06 176.59,25.06 176.44,24.91 176.44,24.41 176.28,24.26 176.03,24.26 175.88,24.41 175.88,24.91 175.73,25.06 175.47,25.06 175.32,24.91 175.32,24.41 175.17,24.26 174.91,24.26 174.76,24.41 174.76,24.91 174.61,25.06 174.35,25.06 174.2,24.91 174.2,24.41 174.05,24.26 173.79,24.26 173.64,24.41 173.64,24.91 173.49,25.06 173.24,25.06 173.08,24.91 173.08,24.41 172.93,24.26 172.68,24.26 172.52,24.41 172.52,24.91 172.37,25.06 172.12,25.06 171.97,24.91 171.97,24.41 171.81,24.26 171.53,24.26 171.41,24.39 171.41,24.91 171.25,25.06 171,25.06 170.85,24.91 170.85,24.39 170.72,24.26 170.42,24.26 170.29,24.39 170.29,24.91 170.14,25.06 169.88,25.06 169.73,24.91 169.73,24.39 169.6,24.26 169.3,24.26 169.17,24.39 169.17,24.91 169.02,25.06 168.77,25.06 168.61,24.91 168.61,24.39 168.49,24.26 168.18,24.26 168.05,24.39 168.05,24.91 167.9,25.06 167.65,25.06 167.5,24.91 167.5,24.39 167.37,24.26 167.06,24.26 166.94,24.39 166.94,24.91 166.78,25.06 166.53,25.06 166.38,24.91 166.38,24.39 166.25,24.26 165.95,24.26 165.82,24.39 165.82,24.91 165.67,25.06 159.28,25.06 157.71,26.63 157.71,26.84 157.82,26.95 157.82,27.13 157.6,27.34 157.42,27.34 157.32,27.24 157.1,27.24 156.88,27.45 156.88,27.67 156.99,27.78 156.99,27.99 156.81,28.17 156.59,28.17 156.49,28.07 156.27,28.07 156.09,28.25 156.09,28.46 156.2,28.57 156.2,28.78 156.02,28.96 155.8,28.96 155.7,28.86 155.48,28.86 155.3,29.04 155.3,29.25 155.41,29.36 155.41,29.57 155.23,29.75 155.01,29.75 154.91,29.65 154.69,29.65 147.37,36.97 147.37,42.1
  BOTTOM w0.081: v2(148.69,57.07) 148.86,57.24 UC1.AK36
  BOTTOM w0.152: v2(195.83,20.18) 195.63,20.37 194.85,20.37 194.7,20.22 194.7,16.43 JDIMM2.107
DDR_B_MA11: length 95.5
  IN1 w0.076: 140.57,42.1 140.57,43 142.17,44.6 142.17,48.61 142.28,48.72 142.48,48.72 v2(142.53,48.66)
  IN1 w0.152: 140.57,42.1 140.57,34.23 157.7,17.11 159.52,17.11 161.14,15.49 161.14,15.49 161.56,15.07 161.56,15.05 161.81,14.8 179.89,14.8 180.04,14.96 180.04,15.21 180.17,15.33 180.48,15.33 180.6,15.21 180.6,14.96 180.76,14.8 181.01,14.8 181.16,14.96 181.16,15.15 181.31,15.3 181.57,15.3 181.72,15.15 181.72,14.96 181.87,14.8 182.13,14.8 182.28,14.96 182.28,15.15 182.43,15.3 182.69,15.3 182.84,15.15 182.84,14.96 182.99,14.8 183.27,14.8 183.4,14.93 183.4,15.22 183.51,15.33 184.67,15.33 185.02,14.98 185.43,14.57 185.86,14.57 186,14.71 186,14.86 186.13,14.98 186.45,14.98 186.58,14.86 186.58,12.9 186.73,12.74 186.97,12.74 187.09,12.62 187.09,12.31 186.97,12.18 186.73,12.18 186.58,12.03 186.58,10.93 186.45,10.81 186.26,10.81 186.13,10.68 186.13,10.02 185.86,9.75 183.04,9.75 182.91,9.63 182.91,9.23 183.04,9.11 186.4,9.11 186.52,9.23 186.52,9.77 186.96,10.21 186.96,10.54 187.51,11.09 v2(187.51,11.19)
  BOTTOM w0.076: v2(142.53,48.66) 142.08,49.11 142.08,50.37 141.76,50.7 141.76,51.87 UC1.AV47
  BOTTOM w0.152: v2(187.51,11.19) 188.08,10.63 188.08,9.68 187.8,9.41 JDIMM2.84
DDR_B_MA12: length 91.4
  IN1 w0.076: v2(142.49,52.63) 142.78,52.63 142.91,52.75 142.91,53.16 142.78,53.29 142.46,53.29 141.8,52.63 141.38,52.63 141.27,52.52 141.27,52.36 141.38,52.25 141.89,52.25 141.95,52.2 141.95,49.83 142.02,49.75 142.09,49.75 142.16,49.67 142.16,49.34 142.09,49.27 142.02,49.27 141.95,49.19 141.95,44.81 140.17,43.03 140.17,42.1
  IN1 w0.152: v2(186.15,14.16) 186.17,14.14 186.17,13.39 185.98,13.19 185.74,13.19 185.54,13.39 185.54,14.04 185.41,14.16 185.26,14.16 184.5,14.93 183.97,14.93 183.44,14.4 183.21,14.4 183.05,14.24 183.05,14.12 182.93,13.99 182.62,13.99 182.49,14.12 182.49,14.27 182.37,14.4 182.01,14.4 181.89,14.27 181.89,14.12 181.76,13.99 181.45,13.99 181.33,14.12 181.33,14.24 181.18,14.4 180.92,14.4 180.77,14.24 180.77,14.14 180.62,13.99 180.36,13.99 180.21,14.14 180.21,14.24 180.06,14.4 179.8,14.4 179.65,14.24 179.65,14.14 179.5,13.99 179.24,13.99 179.09,14.14 179.09,14.24 178.94,14.4 178.69,14.4 178.53,14.24 178.53,14.14 178.38,13.99 178.13,13.99 177.97,14.14 177.97,14.24 177.82,14.4 177.54,14.4 177.39,14.24 177.39,14.14 177.24,13.99 176.98,13.99 176.83,14.14 176.83,14.24 176.68,14.4 176.43,14.4 176.27,14.24 176.27,14.14 176.12,13.99 175.87,13.99 175.71,14.14 175.71,14.24 175.56,14.4 175.31,14.4 175.16,14.24 175.16,14.14 175,13.99 174.75,13.99 174.6,14.14 174.6,14.24 174.44,14.4 174.19,14.4 174.04,14.24 174.04,14.14 173.89,13.99 173.63,13.99 173.48,14.14 173.48,14.24 173.33,14.4 173.07,14.4 172.92,14.24 172.92,14.14 172.77,13.99 172.51,13.99 172.36,14.14 172.36,14.24 172.21,14.4 171.95,14.4 171.8,14.24 171.8,14.14 171.65,13.99 171.4,13.99 171.24,14.14 171.24,14.24 171.09,14.4 170.84,14.4 170.68,14.24 170.68,14.14 170.53,13.99 170.28,13.99 170.13,14.14 170.13,14.24 169.97,14.4 169.72,14.4 169.57,14.24 169.57,14.14 169.41,13.99 169.16,13.99 169.01,14.14 169.01,14.24 168.86,14.4 168.6,14.4 168.45,14.24 168.45,14.14 168.3,13.99 168.04,13.99 167.89,14.14 167.89,14.24 167.74,14.4 167.48,14.4 167.33,14.24 167.33,14.14 167.18,13.99 166.93,13.99 166.77,14.14 166.77,14.24 166.62,14.4 166.37,14.4 166.21,14.24 166.21,14.14 166.06,13.99 165.81,13.99 165.66,14.14 165.66,14.24 165.5,14.4 165.25,14.4 165.1,14.24 165.1,14.14 164.94,13.99 164.69,13.99 164.54,14.14 164.54,14.24 164.39,14.4 164.13,14.4 163.98,14.24 163.98,14.14 163.83,13.99 163.57,13.99 163.42,14.14 163.42,14.24 163.27,14.4 163.01,14.4 162.86,14.24 162.86,14.14 162.71,13.99 162.46,13.99 162.3,14.14 162.3,14.24 162.15,14.4 161.64,14.4 161.15,14.89 161.15,14.9 159.35,16.7 157.53,16.7 140.17,34.06 140.17,42.1
  BOTTOM w0.076: v2(142.49,52.63) 142.44,52.63 142.23,52.83 UC1.AU47
  BOTTOM w0.152: v2(186.15,14.16) 186.91,14.92 186.91,15.01 187.5,15.61 JDIMM2.83
DDR_B_MA13: length 100.4
  IN1 w0.076: v2(150.59,56.98) 150.64,56.98 150.86,57.2 150.86,57.66 150.96,57.76 151.07,57.76 151.17,57.67 151.17,57.02 150.99,56.84 150.99,53.29 151.11,53.16 151.11,47.75 149.67,46.3 149.67,42.62 149.62,42.58 149.62,42.1
  IN1 w0.152: 149.62,42.1 149.62,42.08 149.63,42.08 149.63,38.44 149.88,38.18 149.88,37.97 149.65,37.74 149.65,37.56 149.87,37.34 150.05,37.34 150.28,37.57 150.49,37.57 150.67,37.39 150.67,37.18 150.44,36.95 150.44,36.77 150.66,36.55 150.84,36.55 151.07,36.78 151.29,36.78 151.47,36.6 151.47,36.39 151.23,36.16 151.23,35.98 155.21,32 156.07,32 160.98,27.09 181.14,27.09 181.26,26.96 181.26,26.42 181.39,26.29 181.69,26.29 181.84,26.44 181.84,26.94 182,27.09 182.25,27.09 182.4,26.94 182.4,26.44 182.56,26.29 182.81,26.29 182.96,26.44 182.96,26.94 183.11,27.09 183.37,27.09 183.52,26.94 183.52,26.44 183.67,26.29 183.93,26.29 184.08,26.44 184.08,26.94 184.23,27.09 184.49,27.09 184.64,26.94 184.64,26.44 184.79,26.29 185.04,26.29 185.2,26.44 185.2,26.94 185.35,27.09 185.6,27.09 185.76,26.94 185.76,26.44 185.91,26.29 186.16,26.29 186.31,26.44 186.31,26.94 186.47,27.09 186.72,27.09 186.87,26.94 186.87,26.44 187.03,26.29 187.28,26.29 187.43,26.44 187.43,26.94 187.58,27.09 187.84,27.09 187.99,26.94 187.99,26.44 188.14,26.29 188.4,26.29 188.55,26.44 188.55,26.94 188.7,27.09 188.96,27.09 189.11,26.94 189.11,26.44 189.26,26.29 189.51,26.29 189.67,26.44 189.67,26.94 189.82,27.09 190.07,27.09 190.23,26.94 190.23,26.44 190.38,26.29 190.63,26.29 190.78,26.44 190.78,26.94 190.94,27.09 191.19,27.09 191.34,26.94 191.34,26.44 191.5,26.29 191.88,26.29 192.03,26.44 192.03,26.96 192.16,27.09 192.46,27.09 192.59,26.96 192.59,26.47 192.72,26.34 193.34,26.34 198.71,20.96 198.71,19.68 198.92,19.48 199.08,19.48 v2(199.28,19.69)
  BOTTOM w0.076: v2(150.59,56.98) 150.85,57.24 UC1.AK33
  BOTTOM w0.152: v2(199.28,19.69) 198.08,19.69 197.44,19.05 197.44,18.29 198.3,17.43 JDIMM2.119
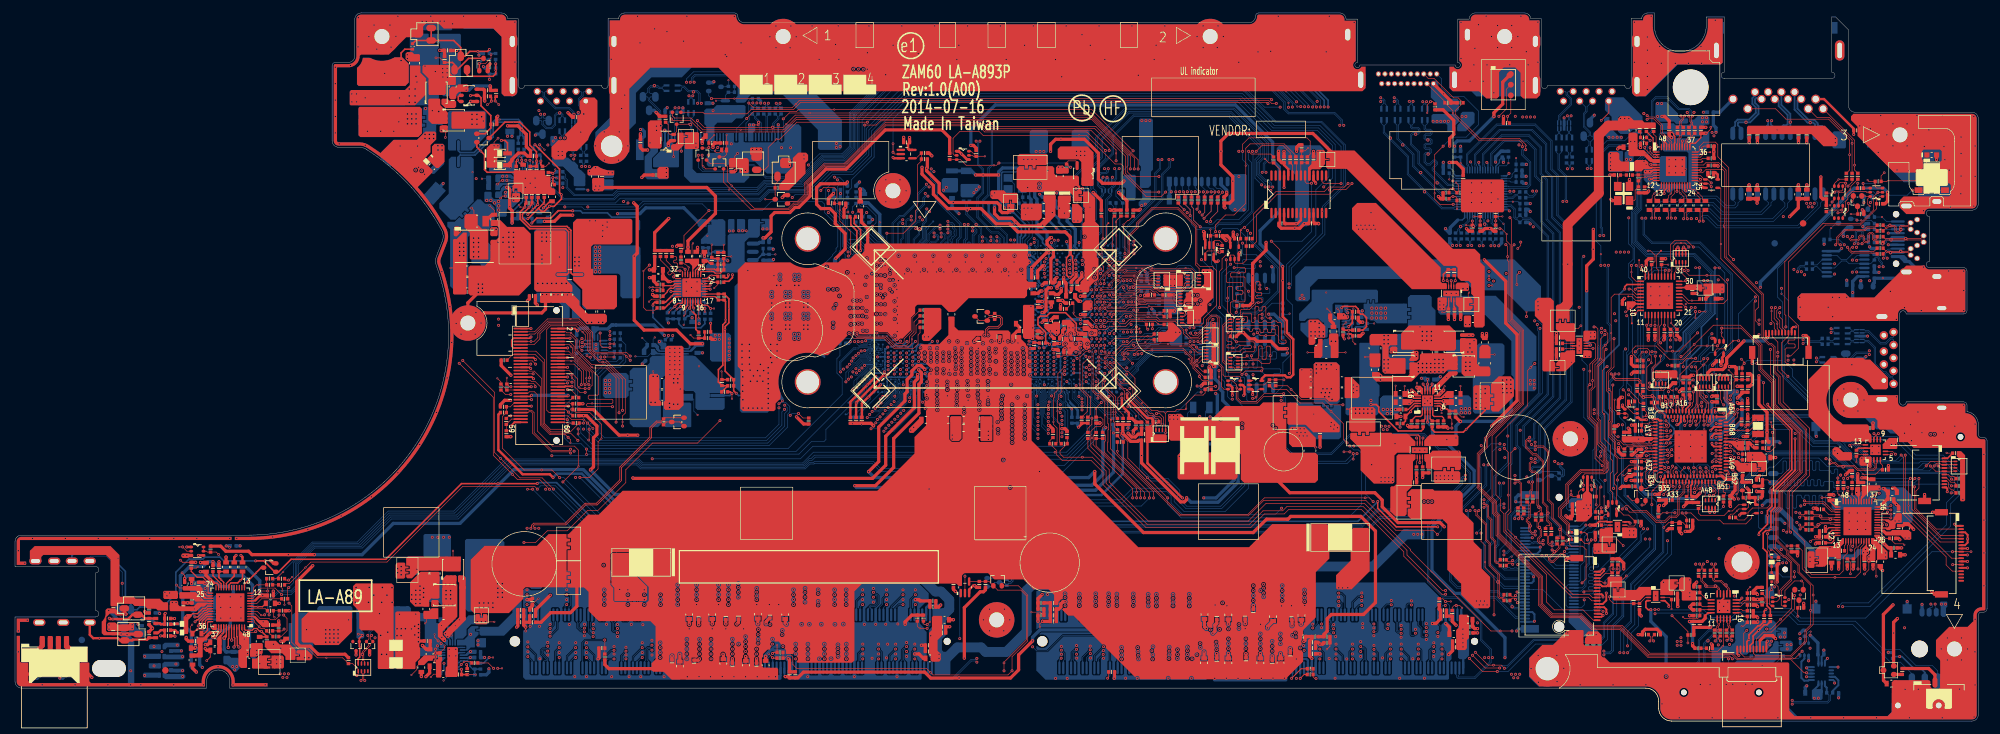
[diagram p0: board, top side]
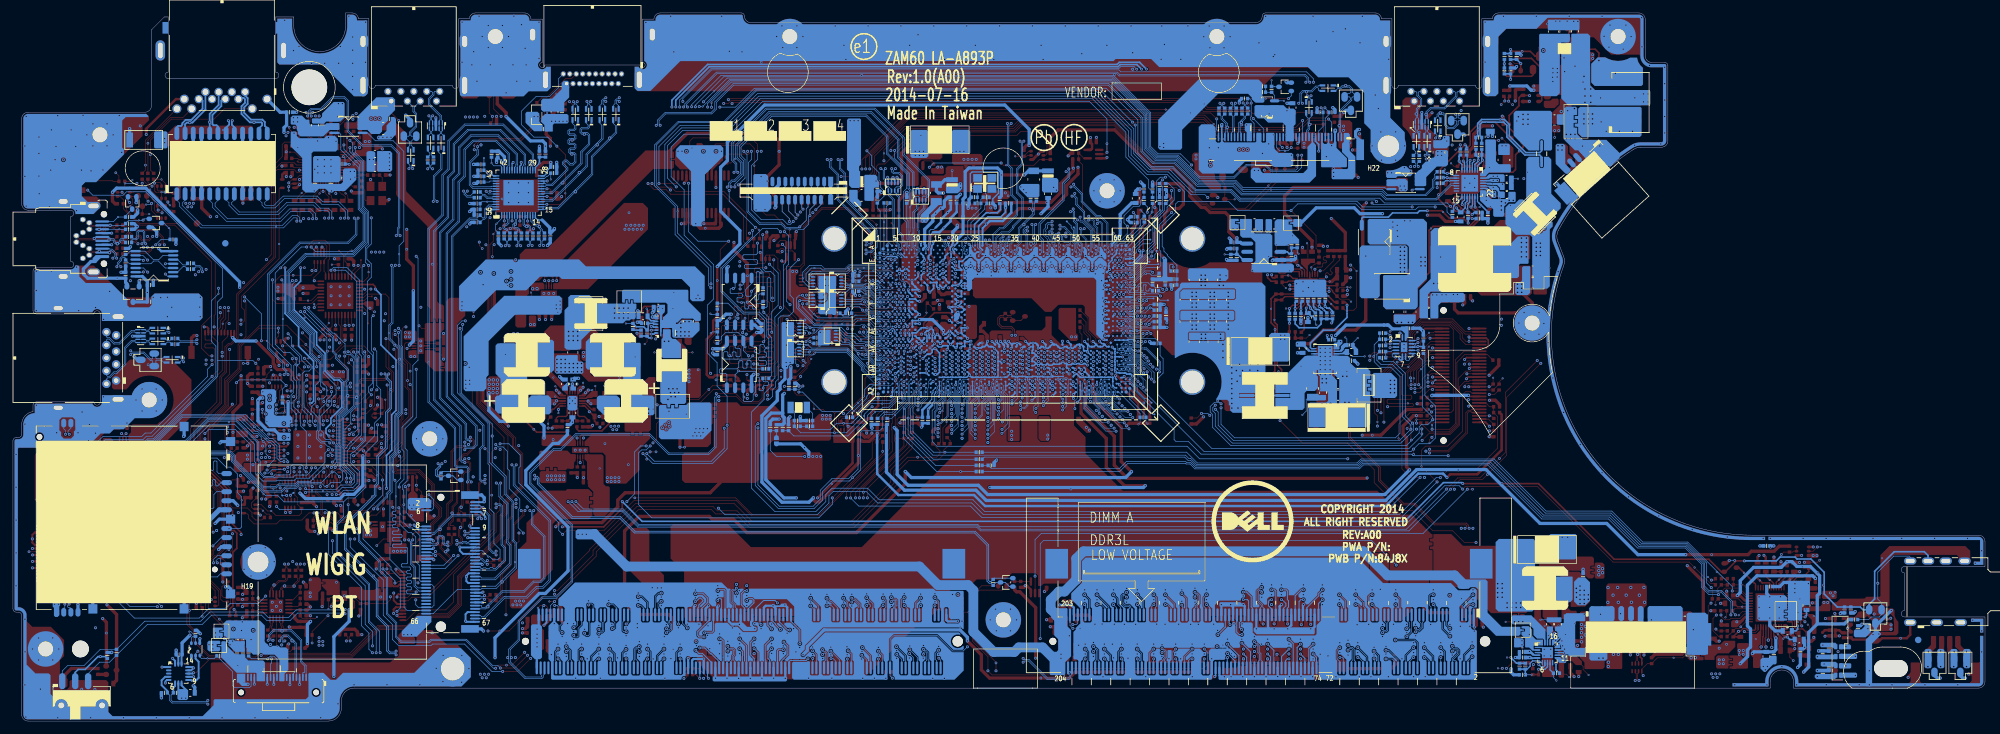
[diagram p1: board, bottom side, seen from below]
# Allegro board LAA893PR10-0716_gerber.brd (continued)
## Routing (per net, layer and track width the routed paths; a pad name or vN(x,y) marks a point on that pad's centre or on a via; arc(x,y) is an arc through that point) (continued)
DDR_B_MA14: length 97.8
  IN1 w0.076: v2(142.45,53.8) 142.45,53.51 141.76,52.81 140.75,52.81 140.53,52.58 140.53,51.71 141.51,50.72 141.51,45.35 139.35,43.19 139.35,42.1
  IN1 w0.152: 139.35,42.1 139.35,31.27 143.95,26.67 144.41,26.67 145.32,27.58 145.5,27.58 145.84,27.24 145.84,27.06 144.79,26.01 144.79,25.83 145.01,25.61 145.19,25.61 146.22,26.65 146.43,26.65 146.61,26.47 146.61,26.25 145.58,25.22 145.58,25.04 145.8,24.82 145.98,24.82 147.01,25.86 147.23,25.86 147.41,25.68 147.41,25.46 146.37,24.43 146.37,24.25 146.59,24.03 146.77,24.03 147.8,25.07 148.02,25.07 148.2,24.89 148.2,24.67 147.54,24.01 147.54,23.83 147.75,23.62 147.93,23.62 148.59,24.28 148.81,24.28 149.7,23.38 157.21,15.87 158.95,15.87 161.65,13.18 184.95,13.18 185.33,12.8 185.63,12.8 186.12,12.31 186.12,11.45 185.72,11.04 v2(185.69,11.04)
  BOTTOM w0.076: UC1.AR46 142.79,53.8 v2(142.45,53.8)
  BOTTOM w0.152: JDIMM2.80 186.6,10.86 186.42,11.04 v2(185.69,11.04)
DDR_B_MA15: length 98
  IN1 w0.076: 138.95,42.1 138.95,43.22 141.31,45.58 141.31,50.68 140.35,51.63 140.35,52.65 140.68,52.98 141.64,52.98 142.1,53.43 142.1,54.08 v2(142.47,54.45)
  IN1 w0.152: 138.95,42.1 138.95,31.1 146.46,23.58 147.21,23.58 147.76,23.04 148.18,23.04 148.74,23.59 148.91,23.59 149.2,23.31 149.2,23.13 148.52,22.45 148.52,22.27 148.74,22.05 148.92,22.05 149.58,22.71 149.79,22.71 149.97,22.53 149.97,22.32 149.31,21.66 149.31,21.48 149.53,21.26 149.71,21.26 150.37,21.92 150.58,21.92 150.76,21.74 150.76,21.53 150.1,20.87 150.1,20.69 150.32,20.47 150.5,20.47 151.16,21.13 151.37,21.13 157.98,14.53 159.72,14.53 161.48,12.77 184.33,12.77 184.46,12.64 184.46,12.31 184.3,12.16 183.97,12.16 183.82,12.01 183.82,11.75 183.97,11.6 184.3,11.6 184.46,11.45 184.46,10.29 184.58,10.16 184.89,10.16 185.01,10.29 185.01,12.25 185.14,12.38 185.48,12.38 185.61,12.25 v2(185.61,12.22)
  BOTTOM w0.076: UC1.AP46 142.79,54.45 v2(142.47,54.45)
  BOTTOM w0.152: JDIMM2.78 186,9.26 185,10.26 185,11.61 v2(185.61,12.22)
DDR_B_RAS#: length 100.2
  IN1 w0.076: v2(149.66,55.62) 149.66,55.57 149.27,55.18 149.27,53.2 149.77,52.7 149.77,47.8 148.68,46.71 148.68,42.85 148.18,42.35 148.18,42.1
  IN1 w0.152: 148.18,42.1 148.18,37.31 154.71,30.78 155.56,30.78 160.47,25.87 179.92,25.87 180.04,25.75 180.04,25.2 180.17,25.07 192.88,25.07 194.39,23.56 196.75,21.2 196.75,17.65 196.41,17.31 196.41,12.75 196.56,12.6 197.24,12.6 197.39,12.44 197.39,12.19 197.24,12.04 196.56,12.04 196.41,11.88 196.41,10.75 196.56,10.6 197.03,10.6 197.15,10.47 197.15,10.17 197.03,10.04 196.56,10.04 196.41,9.89 196.41,9.29 196.58,9.12 198.93,9.12 199.06,9.25 199.06,10.1 198.93,10.22 198.7,10.22 198.61,10.31 v2(198.61,11.3)
  BOTTOM w0.076: v2(149.66,55.62) 149.99,55.94 UC1.AM35
  BOTTOM w0.152: JDIMM2.110 195.6,9.18 196.81,10.39 196.91,10.39 197.83,11.3 v2(198.61,11.3)
DDR_B_WE#: length 100
  IN1 w0.076: v2(149.64,56.92) 149.55,56.92 149.42,57.04 149.42,57.93 149.55,58.05 150.04,58.05 150.17,57.93 150.17,55.69 150.05,55.58 150.05,53.53 149.97,53.45 149.97,48.62 150.05,48.55 150.43,48.55 150.51,48.47 150.51,48.14 150.43,48.07 150.05,48.07 149.97,47.99 149.97,47.5 149.03,46.56 149.03,42.82 148.59,42.38 148.59,42.1
  IN1 w0.152: 148.59,42.1 148.59,37.47 154.88,31.19 155.73,31.19 160.64,26.28 180.32,26.28 180.45,26.15 180.45,25.61 180.58,25.48 193.05,25.48 197.18,21.35 197.18,20.8 197.33,20.65 197.77,20.65 197.9,20.52 197.9,20.22 197.77,20.09 197.28,20.09 197.15,19.96 197.15,19.66 197.28,19.53 197.77,19.53 197.9,19.4 197.9,19.1 197.77,18.97 197.33,18.97 197.18,18.82 197.18,18.39 197.3,18.26 197.77,18.26 197.9,18.13 197.9,17.42 197.77,17.3 196.97,17.3 196.84,17.17 196.84,16.89 197,16.74 197.75,16.74 197.9,16.59 197.9,16.33 197.75,16.18 197,16.18 196.84,16.03 196.84,15.53 196.97,15.4 197.71,15.4 197.84,15.28 197.84,14.43 197.71,14.3 196.97,14.3 196.84,14.17 196.84,13.82 196.97,13.69 197.83,13.69 v2(197.88,13.64)
  BOTTOM w0.076: UC1.AK35 149.97,57.24 v2(149.64,56.92)
  BOTTOM w0.152: JDIMM2.113 196.5,13.92 196.68,13.74 197.77,13.74 v2(197.88,13.64)
DDR_CKE0_DIMMA: length 76.3
  IN2 w0.076: v2(144.08,52.46) 144.72,52.46 144.92,52.27 144.92,50.27 144.31,49.66 144.31,47.59 139.05,42.33 139.05,42.1
  IN2 w0.152: 139.05,42.1 139.05,40.14 129.35,30.44 111.33,30.44 111.2,30.31 111.2,29.03 111.07,28.91 110.71,28.91 110.58,29.03 110.58,30.29 110.43,30.44 110.18,30.44 110.03,30.29 110.03,29.36 109.87,29.21 108.5,29.21 106.47,27.18 105.29,25.99 105.17,25.99 105.05,26.11 104.84,26.11 104.66,25.93 104.66,25.72 104.78,25.6 104.78,25.42 104.56,25.2 104.38,25.2 104.26,25.32 104.05,25.32 103.49,24.77 103.49,24.55 104,24.04 104,23.86 103.78,23.65 103.6,23.65 103.1,24.16 102.88,24.16 102.57,23.85 102.57,23.67 103.17,23.06 103.17,22.85 102.99,22.67 102.78,22.67 102.18,23.27 102,23.27 101.78,23.06 101.78,22.88 102.38,22.27 102.38,22.06 101.74,21.42 101.74,18.61 101.83,18.53 102.16,18.53 v2(102.4,18.77)
  BOTTOM w0.076: v2(144.08,52.46) 144.44,52.83 UC1.AU43
  BOTTOM w0.152: v2(102.4,18.77) 103,18.17 JDIMM1.73
DDR_CKE1_DIMMA: length 74.6
  IN2 w0.076: 138.64,42.1 138.64,42.44 143.89,47.69 143.89,49.54 144.43,50.08 144.43,50.89 v2(144.07,51.24)
  IN2 w0.152: 138.64,42.1 138.64,40.36 129.13,30.85 109.57,30.85 105.31,26.59 104.75,26.59 101.33,23.18 101.33,16.65 102.73,15.25 102.73,11.47 103.82,10.38 v2(103.83,10.38)
  BOTTOM w0.076: UC1.AW43 144.35,51.53 v2(144.07,51.24)
  BOTTOM w0.152: v2(103.83,10.38) 103.3,9.85 JDIMM1.74
DDR_CKE2_DIMMB: length 80.7
  IN1 w0.076: 138.29,42.1 138.29,42.93 141.04,45.67 141.04,49.74 v2(140.88,49.89)
  IN1 w0.152: 138.29,42.1 138.29,30.83 146.19,22.92 146.94,22.92 150.14,19.72 151.74,19.72 157.6,13.87 159.45,13.87 161.21,12.11 181.83,12.11 181.98,11.96 181.98,11.28 182.13,11.12 182.39,11.12 182.54,11.28 182.54,11.96 182.69,12.11 183.02,12.11 v2(183.14,11.99)
  BOTTOM w0.076: UC1.AY49 141.31,50.32 v2(140.88,49.89)
  BOTTOM w0.152: JDIMM2.73 184.5,15.41 183.14,14.06 v2(183.14,11.99)
DDR_CKE3_DIMMB: length 82
  IN1 w0.076: v2(140.65,48.31) 140.65,45.7 137.88,42.93 137.88,42.1
  IN1 w0.152: v2(181.9,9.63) 181.38,9.11 161.5,9.11 160.53,10.08 160.53,12.22 159.28,13.46 157.43,13.46 151.57,19.32 149.22,19.32 137.88,30.66 137.88,42.1
  BOTTOM w0.076: v2(140.65,48.31) 140.65,49.53 140.19,49.99 140.19,52.64 UC1.AU50
  BOTTOM w0.152: v2(181.9,9.63) 182.15,9.37 184.62,9.37 184.8,9.19 JDIMM2.74
DDR_CS0_DIMMA#: length 76.8
  IN2 w0.076: v2(150.62,54.38) 151.4,54.38 152.97,52.81 152.97,49.8 152.95,49.78 152.95,42.64 152.41,42.1
  IN2 w0.152: 152.41,42.1 152.19,41.88 152.19,33.49 146.73,28.03 146.36,28.03 146.12,28.27 145.91,28.27 145.71,28.07 145.71,27.86 145.91,27.65 145.91,27.44 145.74,27.26 145.52,27.26 145.32,27.46 145.1,27.46 144.92,27.28 144.92,27.07 145.12,26.86 145.12,26.65 144.94,26.47 144.73,26.47 144.53,26.67 144.31,26.67 140.85,23.21 140.85,17.57 136.72,13.44 119.3,13.44 117.77,11.9 v2(117.06,11.9)
  BOTTOM w0.076: v2(150.62,54.38) 150.88,54.64 UC1.AP33
  BOTTOM w0.152: JDIMM1.114 115.3,10.14 v2(117.06,11.9)
DDR_CS1_DIMMA#: length 77.3
  IN2 w0.076: 151.83,42.1 152.42,42.7 152.42,46.19 151.9,46.71 151.9,53.36 v2(151.57,53.69)
  IN2 w0.152: 151.83,42.1 151.79,42.06 151.79,34.72 151.31,34.24 151.31,34.02 151.62,33.71 151.62,33.49 151.44,33.31 151.23,33.31 150.91,33.63 150.7,33.63 150.52,33.45 150.52,33.23 150.83,32.92 150.83,32.7 150.65,32.52 150.44,32.52 150.12,32.84 149.9,32.84 149.73,32.66 149.73,32.44 150.04,32.13 150.04,31.91 149.86,31.73 149.65,31.73 149.33,32.05 149.11,32.05 148.93,31.87 148.93,31.65 149.25,31.34 149.25,31.12 149.07,30.94 148.86,30.94 148.54,31.26 148.32,31.26 148.14,31.08 148.14,30.86 148.46,30.55 148.46,30.33 148.28,30.15 148.07,30.15 147.75,30.47 147.53,30.47 147.35,30.29 147.35,30.07 147.67,29.76 147.67,29.54 147.49,29.36 147.27,29.36 146.96,29.68 146.74,29.68 146.56,29.5 146.56,29.28 146.88,28.97 146.88,28.75 146.7,28.57 146.48,28.57 146.17,28.89 145.95,28.89 140.45,23.38 140.45,17.74 138.1,15.4 137.37,15.4 136.94,14.97 136.94,14.57 136.24,13.87 119.06,13.87 v2(118.55,13.36)
  BOTTOM w0.076: v2(151.57,53.69) 151.66,53.69 UC1.AR32
  BOTTOM w0.152: v2(118.55,13.36) 117.4,14.51 117.4,16.43 JDIMM1.121
DDR_CS2_DIMMB#: length 89.6
  IN1 w0.076: 150.72,42.1 150.72,42.96 150.89,43.13 150.89,45.77 151.67,46.55 151.67,53.11 151.92,53.35 151.92,55.28 151.58,55.62 v2(151.58,55.63)
  IN1 w0.152: v2(199.22,10.95) 200.09,11.81 200.09,15.26 200.35,15.53 200.35,20.84 193.02,28.16 161.42,28.16 153.89,35.69 153.6,35.69 153.35,35.94 153.35,36.23 150.72,38.86 150.72,42.1
  BOTTOM w0.076: v2(151.58,55.63) 151.9,55.94 UC1.AM32
  BOTTOM w0.152: JDIMM2.114 196.8,9.07 198.19,10.46 198.74,10.46 v2(199.22,10.95)
DDR_CS3_DIMMB#: length 88.1
  IN1 w0.076: 150.29,42.1 150.29,42.32 150,42.61 150,45.1 151.39,46.49 151.39,53.29 151.18,53.5 151.18,56.8 151.38,57.01 v2(151.51,57.01)
  IN1 w0.152: v2(199.31,18.47) 199.51,18.26 199.81,18.26 199.94,18.4 199.94,20.67 192.86,27.75 161.25,27.75 156.11,32.89 155.93,32.89 155.7,32.66 155.49,32.66 155.31,32.84 155.31,33.06 155.54,33.29 155.54,33.47 155.32,33.68 155.14,33.68 154.91,33.45 154.7,33.45 154.52,33.63 154.52,33.85 154.75,34.08 154.75,34.26 154.53,34.47 154.35,34.47 154.12,34.24 153.9,34.24 153.73,34.42 153.73,34.64 153.96,34.87 153.96,35.05 153.74,35.26 153.56,35.26 153.33,35.03 153.11,35.03 152.93,35.21 152.93,35.43 153.02,35.52 153.02,35.7 152.81,35.91 152.63,35.91 152.54,35.82 152.32,35.82 152.14,36.01 152.14,36.23 152.35,36.44 152.35,36.66 150.29,38.72 150.29,42.1
  BOTTOM w0.076: UC1.AK32 151.75,57.24 v2(151.51,57.01)
  BOTTOM w0.152: JDIMM2.121 198.9,17.5 198.77,17.64 198.77,17.93 198.13,18.57 198.13,18.67 198.47,19.01 198.65,19.01 199.2,18.47 v2(199.31,18.47)
DDR_PG_CTRL: length 142.2
  TOP w0.102: v2(79.99,35.85) v4(79.19,35.85) ; v2(146.8,22.4) UD1.2
  IN1 w0.102: v2(79.99,35.85) 80.01,35.86 80.01,38.09 v2(82.95,41.03)
  BOTTOM w0.081: 131.32,51.8 132.02,52.5 132.29,52.5 132.32,52.54 133.4,52.54 UC1.AV61
  BOTTOM w0.102: v2(146.8,22.4) 146.8,28.05 145.82,29.03 86.81,29.03 v2(79.99,35.85) ; 131.32,51.8 131.32,51.09 125.31,45.08 125.31,43.52 125.02,43.23 123.1,43.23 121.14,41.27 88.64,41.27 88.4,41.03 v2(82.95,41.03)
DDR_XDP_WAN_SMBCLK: length 371.1
  TOP w0.102: JXDP1.53 79.27,47.7 79.41,47.83 79.75,47.83 79.99,47.59 79.99,44.51 82.88,41.63 85.67,41.63 v2(85.85,41.45) ; QC1.1 188.16,52.62 188.76,52.02 188.76,49.83 189.42,49.17 191.95,49.17 192.95,50.18 v2(195.67,50.18)
  IN1 w0.102: v2(274.63,2.62) 274.81,2.79 275.23,2.79 275.54,3.11 275.54,4.02 272.49,7.06 256.38,7.06 255.6,7.84 242.45,7.84 238.48,11.8 229.16,11.8 227.91,10.55 227.91,10.01 v2(227.72,9.82)
  IN2 w0.102: v2(85.85,41.45) 85.66,41.63 85.11,41.63 81.58,38.1 81.58,27.64 78.79,24.85 78.79,20.59 78.22,20.01 78.22,14.47 78.62,14.06 78.62,9.74 79.33,9.03 147.26,9.03 147.75,9.52 148.47,9.52 v2(148.64,9.69) 148.82,9.51 150.63,9.51 151.04,9.93 157.17,9.93 158.13,8.97 227.57,8.97 227.87,9.28 227.87,9.66 v2(227.72,9.82)
  BOTTOM w0.102: RN4.2 280.55,4.01 280.55,3.18 280.16,2.79 274.81,2.79 v2(274.63,2.62) ; JDIMM1.202 141.7,7.34 141.52,7.16 141.52,6.79 141.65,6.66 144.86,6.66 147.72,9.51 148.46,9.51 v2(148.64,9.69) ; JDIMM2.202 223.2,7.21 223.03,7.04 223.03,6.88 223.1,6.81 225.53,6.81 227.9,9.18 227.9,9.64 v2(227.72,9.82) 227.91,10.01 227.91,11.03 226.45,12.49 226.45,15.43 222.9,18.97 220.8,18.97 218.26,21.52 218.26,30.33 224.71,36.78 224.71,38.33 221.16,41.88 220.04,41.88 217.7,44.22 206.45,44.22 203.45,41.22 197.22,41.22 196.09,42.35 196.09,49.98 195.89,50.18 v2(195.67,50.18)
  BOTTOM w0.305: UN1.4 281.22,6.85 281.77,6.3 281.77,5.55 280.9,4.67 RN4.2
DDR_XDP_WAN_SMBDAT: length 368.3
  TOP w0.102: QC1.4 189.11,51.32 188.99,51.19 188.99,49.93 189.51,49.4 191.82,49.4 193.04,50.62 v2(196.05,50.62) ; v2(85.85,42.03) 85.67,41.85 82.98,41.85 80.22,44.61 80.22,47.69 79.85,48.06 79.44,48.06 79.31,48.2 JXDP1.51
  IN1 w0.102: v2(274.63,3.2) 274.81,3.02 275.13,3.02 275.31,3.2 275.31,3.92 272.4,6.83 256.28,6.83 255.51,7.61 242.35,7.61 238.39,11.57 229.26,11.57 228.14,10.45 228.14,9.98 v2(228.3,9.82)
  IN2 w0.102: v2(228.3,9.82) 228.1,9.61 228.1,9.18 227.66,8.74 158.03,8.74 157.07,9.7 151.14,9.7 150.72,9.28 148.82,9.28 v2(148.64,9.11) 148.45,9.29 147.85,9.29 147.36,8.8 79.23,8.8 78.39,9.64 78.39,13.96 77.99,14.37 77.99,20.11 78.56,20.68 78.56,24.93 78.63,25 78.63,25.01 81.35,27.74 81.35,38.2 85.02,41.86 85.68,41.86 v2(85.85,42.03)
  BOTTOM w0.102: JDIMM2.200 222.6,7.29 222.8,7.09 222.8,6.79 223,6.58 225.63,6.58 228.13,9.08 228.13,9.64 v2(228.3,9.82) 228.14,9.98 228.14,11.12 226.68,12.58 226.68,15.52 223,19.2 220.9,19.2 218.49,21.61 218.49,30.24 224.94,36.69 224.94,38.42 221.25,42.11 220.13,42.11 217.79,44.45 206.35,44.45 203.36,41.45 197.31,41.45 196.31,42.45 196.31,50.08 196.05,50.34 v2(196.05,50.62) ; v2(274.63,3.2) 274.81,3.02 280.06,3.02 280.32,3.28 280.32,4.01 RN3.2 ; JDIMM1.200 141.1,7.21 141.29,7.03 141.29,6.7 141.55,6.43 144.96,6.43 147.81,9.28 148.46,9.28 v2(148.64,9.11)
  BOTTOM w0.305: RN3.2 279.97,5.16 279.69,5.43 279.69,5.87 UN1.6
DEW1: length 4
  TOP w0.102: UN2.16 266.64,16.74 267.22,16.17 RN21.2 RN20.2 267.08,14.66 v1(266.82,14.66)
DEW2: length 3.1
  TOP w0.102: RN19.2 RN18.2 261.48,18.74 UN2.6
DGPU_PWROK: length 9.3
  BOTTOM w0.076: 172.99,66.35 172.28,66.35 171.28,65.35 171.02,65.35 171,65.33 170.99,65.33 170.9,65.24 170.48,65.24 170.32,65.08 169.64,65.08 169.59,65.13 169.2,65.13 UC1.P4
  BOTTOM w0.102: 172.99,66.35 173.56,66.92 175.39,66.92 176.43,65.88 RPC18.8
DH_1.35V: length 7.5
  TOP w1.016: 67.24,13.94 v1(68.04,14.74) 69.15,15.85 69.15,20.68
  vias: v2(66.51,13.51) v2(66.87,13.05)
DIMM_DET: length 36.8
  IN1 w0.076: v2(169.19,64.36) 167.65,64.36 167.32,64.03 167.32,63.7 166.81,63.19 166.81,62.52 166.71,62.42 166.71,61.68 166.98,61.42 167.28,61.42 167.43,61.27 167.43,60.56 167.28,60.41 167.28,59.84 166.81,59.37 166.81,58.7 166.65,58.53 166.33,58.53 166.14,58.34 166.14,57.89 166.65,57.38 166.65,57.07 167.12,56.6 167.12,53.73 167.98,52.87 167.98,52.43 168.3,52.11 171.97,52.11 172.29,52.43
  IN1 w0.102: 172.29,52.43 173.99,54.13 174.93,54.13 176.51,55.7 179.11,55.7 181.54,53.26 181.54,52.95 v2(182.67,51.82)
  BOTTOM w0.076: v2(169.19,64.36) 168.83,64.01 UC1.U4
  BOTTOM w0.102: v2(182.67,51.82) 183.17,51.32 RC302.2 RC303.1
DISP_ON: length 7.6
  TOP w0.102: DV2.1 107.13,88.6 v2(107.21,88.68) 107.22,88.7 RV2.1 107.22,89.77 v1(108.05,90.6)
  BOTTOM w0.102: JEDP1.22 109.46,88.65 109,88.19 107.71,88.19 v2(107.21,88.68)
DL_1.35V: length 1.2
  TOP w0.102: v2(65.39,12.39) 64.84,12.94 v1(64.84,13.4)
  vias: v2(64.6,17.88) v2(65.21,17.88) v2(65.85,11.99)
DMIC0: length 125.5
  TOP w0.102: UA1.47 35.06,14.09 35.44,13.7 37.06,13.7 v2(37.2,13.84)
  IN2 w0.102: v2(37.2,13.84) 37.6,13.44 38.52,13.44 38.73,13.65 38.73,14.25 39.44,14.96 42.16,14.96 45.29,18.1 49,18.1 73.4,42.5 73.4,51.2 77.27,55.06 79.8,57.6 84.05,57.6 84.84,58.38 85.79,58.38 88.09,60.68 90.71,60.68 92.67,62.63 92.67,74.6 101.85,83.79 101.85,93.82 102.2,94.17 102.2,94.63 v2(102,94.83)
  BOTTOM w0.102: v2(102,94.83) 101.37,94.2 CA6.1 101.37,93.78 101.96,93.19 JEDP1.7
DMIC1: length 258.1
  TOP w0.102: v2(40.8,16.41) 40.8,16.24 40.23,15.67 39.47,15.67 39.25,15.89 37.84,15.89 37.16,16.57 UA1.4 ; v2(229.31,93.51) 230.45,94.65 230.45,97.71 MIC1.5
  IN2 w0.102: v2(104.95,98.78) 104.76,98.59 104.76,98.22 101.51,94.97 101.51,94.34 101.03,93.85 101.03,89.83 100.1,88.91 100.1,82.43 92.39,74.72 92.39,63.44 91.24,62.29 88.22,62.29 83.8,57.87 79.44,57.87 73.01,51.45 73.01,42.75 48.87,18.6 44.85,18.6 41.93,15.68 41.3,15.68 41.07,15.91 41.07,16.14 v2(40.8,16.41) ; v2(229.31,93.51) 228.48,94.34 219.14,94.34 218.25,93.44 208.1,93.44 207.55,93.99 201.03,93.99 200.7,94.33 200.7,94.78 v2(200.52,94.96)
  BOTTOM w0.102: v2(104.95,98.78) 104.77,98.96 104.77,99.41 105.12,99.76 133.8,99.76 134.16,100.11 195.94,100.11 200.7,95.36 200.7,95.14 v2(200.52,94.96)
DMIC_CLK0: length 125.7
  TOP w0.102: RA14.2 40.37,13.95 40.38,13.94 CA54.1 41.29,13.94 v2(41.58,14.22)
  IN2 w0.102: v2(41.58,14.22) 41.41,14.22 40.64,13.45 39.16,13.45 38.96,13.64 38.96,14.16 39.53,14.73 42.25,14.73 45.39,17.87 49.1,17.87 73.63,42.4 73.63,51.1 79.89,57.37 84.15,57.37 84.94,58.15 85.89,58.15 88.19,60.45 90.81,60.45 92.9,62.54 92.9,74.51 102.08,83.69 102.08,93.73 102.43,94.08 102.43,94.67 v2(102.59,94.83)
  BOTTOM w0.102: JEDP1.9 102.96,91.26 102.3,91.92 CA5.1 102.3,94.54 v2(102.59,94.83)
DMIC_CLK1: length 256.3
  TOP w0.102: MIC1.4 231.15,94.01 v2(230.65,93.51) 230.65,92.75 CA30.1 ; v2(41.51,16.4) 42.03,15.87 42.03,13.98 41.12,13.06 40.77,13.06 RA40.2
  IN2 w0.102: v2(201.11,94.96) 200.92,94.77 200.92,94.42 201.13,94.22 207.64,94.22 208.19,93.67 218.16,93.67 219.05,94.56 229.6,94.56 v2(230.65,93.51) ; v2(41.51,16.4) 41.67,16.24 42.16,16.24 44.76,18.83 48.77,18.83 72.78,42.84 72.78,51.54 79.34,58.1 83.7,58.1 88.12,62.52 91.15,62.52 92.16,63.54 92.16,74.81 99.87,82.52 99.87,89 100.8,89.93 100.8,93.95 101.28,94.43 101.28,95.06 104.53,98.32 104.53,98.6 v2(104.35,98.78)
  BOTTOM w0.102: v2(104.35,98.78) 104.54,98.97 104.54,99.51 105.02,99.99 133.71,99.99 134.07,100.34 196.03,100.34 200.92,95.45 200.92,95.15 v2(201.11,94.96)
DMIC_CLK_L: length 4.8
  TOP w0.102: RA40.1 39.48,13.44 39.41,13.44 RA14.1 38.56,14.29 38.02,14.29 v4(37.74,14.57) 37.02,15.29 37.02,15.48 36.73,15.77 UA1.2
DOCK_PWR_SW#: length 8.1
  TOP w0.102: UE2.A63 264.86,45.71 265.49,46.34 ; RPE5.3 264.27,51.38 264.44,51.21 264.44,49.72 264.93,49.22 265.4,49.22 265.74,48.88 265.74,48.06 266.15,47.65 266.15,47 265.49,46.34 ; 265.49,46.34 v1(265.49,46.34)
DPB_HPD: length 158.3
  IN1 w0.102: v2(274.9,69.84) 281.7,76.63 281.82,76.63 284.86,79.67 286.2,79.67 v2(286.73,80.19)
  IN2 w0.102: v2(192.66,82.92) 193.3,83.57 197.32,83.57 198.1,84.35 213.78,84.35 220.02,78.12 229.33,78.12 229.49,78.28 240.1,78.28 244.98,73.41 255.08,73.41 256.23,72.25 272.64,72.25 274.9,69.99 v2(274.9,69.84)
  BOTTOM w0.076: 166.67,76.3 166.67,74.55 166.54,74.42 166.54,73.38 166.25,73.09 UC1.C8
  BOTTOM w0.102: QV501.3 286.97,80.43 v2(286.73,80.19) ; 166.67,76.3 166.67,77.15 167.09,77.57 167.09,81.91 166.63,82.37 166.63,84.57 169.73,87.67 169.73,90.31 172.95,93.52 187.47,93.52 192.24,88.76 192.24,87.45 191.62,86.83 191.62,83.96 v2(192.66,82.92)
DPB_MB_P14: length 3.6
  BOTTOM w0.102: JMDP1.6 v1(288.31,76.05) 287.36,76.05 RV503.2
DPC_HPD: length 90.9
  IN2 w0.102: v2(227.62,77.35) 227.05,77.91 219.93,77.91 213.7,84.15 198.22,84.15 197.43,83.36 193.96,83.36 v2(193.19,82.6)
  BOTTOM w0.076: UC1.A8 166.25,74.42 166.42,74.59 166.42,76.3
  BOTTOM w0.102: v2(193.19,82.6) 193.19,83.02 191.84,84.37 191.84,86.64 192.45,87.25 192.45,88.95 187.68,93.73 172.83,93.73 169.53,90.42 169.53,87.76 166.43,84.66 166.43,82.31 166.16,82.04 166.16,80.54 RC142.2 166.62,77.56 166.42,77.35 166.42,76.3 ; UV7.5 v2(227.62,77.35)
DSWODVREN: length 7.5
  BOTTOM w0.076: RC78.1 170.15,47.76 v1(169.73,47.76) 168.8,47.76 166.78,49.79 166.78,50.57 166.95,50.74 166.95,51.24 UC1.AW7
EC_32KHZ_MEC5085: length 50
  TOP w0.102: v2(246.03,54.81) 245.91,54.81 245.34,54.24 245.34,47.73 v1(245.59,47.47) 245.59,43.64 246.56,42.67 246.56,40.57 246.91,40.22 246.91,38.62 246.54,38.25 246.54,35.67 246.85,35.37 UZ11.2 ; v2(261.62,45.76) 261.83,45.76 262.44,46.36 UE2.B2
  IN2 w0.102: v2(261.62,45.76) 261.44,45.94 261.44,47.32 263.27,49.15 263.27,52.01 262.76,52.51 260.88,52.51 259.95,53.44 259.95,53.76 259.66,54.05 255.99,54.05 255.57,54.47 253.36,54.47 253.06,54.16 246.68,54.16 v2(246.03,54.81)
EDP_BIA_PWM: length 87.4
  TOP w0.102: v2(168.5,88.23) 165.63,91.1 149.86,91.1 148.9,92.05 134.54,92.05 128.25,85.76 125.15,85.76 122.45,83.06 122.45,81.34 120.98,79.87 120.38,79.87 119.59,79.08 113.75,79.08 v1(112.42,80.41) 109.5,83.33 DV1.3
  BOTTOM w0.076: 166.11,76.3 166.11,75.71 166.21,75.61 166.21,74.71 165.95,74.45 165.95,72.93 UC1.B8
  BOTTOM w0.102: v2(168.5,88.23) 168.5,87.01 166.23,84.74 166.23,82.39 165.96,82.13 165.96,79.73 166.11,79.58 166.11,76.3
EDP_COMP: length 5.9
  TOP w0.508: RC133.2 v4(157.11,70.13) 159.39,72.41 v2(159.78,72.41)
  BOTTOM w0.254: v2(159.78,72.41) UC1.D20
EDP_CPU_AUX: length 49.2
  IN2 w0.086: v2(114.65,95.58) 114.42,95.35 114.42,95.03 115.75,93.7 118.98,93.7 119.93,92.76 124.95,92.76 133.2,84.51 133.2,80.97 135.33,78.84 135.33,76.46 137.8,73.99 142.92,73.99 143.51,74.58 143.51,75.62 143.77,75.88 143.96,75.88 v2(144.16,76.09)
  BOTTOM w0.076: UC1.B45 143.53,72.96 144,73.42 144,73.66 144.32,73.98 144.32,74.8 144.76,75.24 144.76,75.68 144.59,75.86 144.39,75.86 v2(144.16,76.09)
  BOTTOM w0.102: v2(114.65,95.58) 114.45,95.38 114.45,95.15 CV2.1
EDP_CPU_AUX#: length 49.1
  IN2 w0.086: v2(114.01,95.58) 114.24,95.35 114.24,94.96 115.67,93.52 118.91,93.52 119.86,92.58 124.88,92.58 133.03,84.43 133.03,80.9 135.15,78.77 135.15,76.39 137.73,73.81 142.99,73.81 143.69,74.51 143.69,75.55 143.85,75.71 143.96,75.71 v2(144.16,75.5)
  BOTTOM w0.076: UC1.A45 143.53,73.42 143.58,73.37 143.71,73.37 143.84,73.49 143.84,73.73 143.7,73.86 143.7,73.98 143.81,74.09 143.92,74.09 144.03,73.98 144.05,73.98 144.13,74.06 144.13,74.88 144.57,75.32 144.57,75.6 144.51,75.67 144.33,75.67 v2(144.16,75.5)
  BOTTOM w0.102: v2(114.01,95.58) 114.01,95.57 114.23,95.35 114.23,95.09 CV1.1
EDP_CPU_AUX#_C: length 4.1
  BOTTOM w0.102: JEDP1.33 114.96,90.95 115.1,91.1 115.1,92.38 v3(114.91,92.58) 114.27,93.21 114.27,93.53 CV1.2
EDP_CPU_AUX_C: length 4.1
  BOTTOM w0.102: CV2.2 114.49,93.54 114.49,93.3 114.86,92.93 114.88,92.93 115.33,92.48 115.33,91.08 115.46,90.95 JEDP1.34
EDP_CPU_HPD: length 87.4
  TOP w0.102: v2(113.08,93.18) 114.13,94.23 120.75,94.23 121.08,94.56 v1(126.6,94.56) 166.4,94.56 171.63,89.33 171.63,89.33 v2(172.78,88.18)
  BOTTOM w0.076: UC1.D6 167.64,71.72 167.94,72.02 168.13,72.02 168.34,72.23 168.34,72.33 168.54,72.52 169.93,72.52 170,72.6 170.47,72.6 170.74,72.87 170.74,73.1
  BOTTOM w0.102: v2(113.08,93.18) 111.46,91.56 JEDP1.26 ; 170.74,73.1 170.74,78.89 171.18,79.34 RC141.2 171.18,80.11 170.13,81.17 170.13,81.98 170.66,82.51 170.66,83.39 170.91,83.64 170.91,84.81 172.06,85.95 172.06,87.45 v2(172.78,88.18)
EDP_CPU_LANE_N0: length 48.7
  IN2 w0.086: v2(116.42,95.54) 116.21,95.33 116.21,95.19 117.04,94.36 119.29,94.36 120.2,93.45 125.17,93.45 133.86,84.76 136.7,84.76 138.39,83.06 138.39,80.84 136.18,78.63 136.18,76.43 138.1,74.51 142.2,74.51 142.48,74.79 142.48,75.01 142.72,75.24 142.91,75.24 143.12,75.46 v2(143.12,75.46)
  BOTTOM w0.076: UC1.C45 143.53,72.36 143.2,72.69 143.2,73.95 143.86,74.61 143.86,75.18 143.65,75.4 143.18,75.4 v2(143.12,75.46)
  BOTTOM w0.102: v2(116.42,95.54) 116.24,95.35 116.24,95.15 CV4.1
EDP_CPU_LANE_N0_C: length 3.8
  BOTTOM w0.102: JEDP1.36 116.46,90.93 116.27,91.12 116.27,93.54 CV4.2
EDP_CPU_LANE_N1: length 48.6
  IN2 w0.086: v2(118.22,95.53) 118.15,95.53 118.02,95.4 118.02,95.13 118.12,95.03 119.7,95.03 120.55,94.18 121.15,94.18 121.23,94.27 121.23,94.8 121.48,95.04 121.83,95.04 122.08,94.8 122.08,94.27 122.16,94.18 122.48,94.18 122.57,94.27 122.57,94.69 122.8,94.92 123.18,94.92 123.41,94.69 123.41,94.27 123.5,94.18 123.82,94.18 123.89,94.26 123.89,94.6 124.08,94.79 124.55,94.79 124.74,94.6 124.74,94.28 124.83,94.18 125.34,94.18 134.1,85.43 137.07,85.43 139.06,83.43 139.06,80.58 137.23,78.76 137.23,78.09 136.83,77.69 136.83,76.79 138.55,75.07 141.62,75.07 v2(142.03,75.47)
  BOTTOM w0.076: UC1.A47 142.3,73.4 142.25,73.4 141.95,73.7 141.57,73.7 141.51,73.76 141.51,73.89 141.64,74.02 142.31,74.02 142.72,74.42 142.72,74.43 142.73,74.45 142.73,74.51 142.75,74.52 142.75,74.53
  BOTTOM w0.102: v2(118.22,95.53) 118.01,95.31 118.01,95.15 CV6.1 ; 142.75,74.53 142.75,75.03 142.54,75.24 142.23,75.24 142.03,75.44 v2(142.03,75.47)
EDP_CPU_LANE_N1_C: length 4.1
  BOTTOM w0.102: CV6.2 118.06,93.55 118.06,93.1 117.31,92.36 117.31,92.1 117.32,92.09 117.32,91.55 117.31,91.54 117.31,91.11 117.46,90.96 JEDP1.38
EDP_CPU_LANE_P0: length 48.6
  IN2 w0.086: v2(143.12,74.87) 143.12,74.9 142.95,75.07 142.79,75.07 142.66,74.94 142.66,74.72 142.27,74.34 138.02,74.34 136,76.36 136,78.7 138.21,80.91 138.21,82.99 136.62,84.58 133.79,84.58 125.1,93.27 120.13,93.27 119.22,94.19 116.97,94.19 116.04,95.11 116.04,95.33 v2(115.84,95.54)
  BOTTOM w0.076: UC1.B46 143.01,72.57 143.01,72.76 142.85,72.92 142.85,73.09 143.01,73.25 143.01,73.38 142.85,73.55 142.85,73.67 143.01,73.84 143.01,74.03 143.67,74.69 143.67,75.1 143.57,75.21 143.39,75.21 143.12,74.94 v2(143.12,74.87)
  BOTTOM w0.102: CV3.1 116.02,95.1 116.02,95.35 v2(115.84,95.54)
EDP_CPU_LANE_P0_C: length 3.8
  BOTTOM w0.102: CV3.2 116.05,93.53 116.05,91.13 115.96,91.04 JEDP1.35
EDP_CPU_LANE_P1: length 48.6
  IN2 w0.086: v2(142.03,74.89) 142.02,74.89 138.48,74.89 136.65,76.72 136.65,77.76 137.06,78.16 137.06,78.83 138.88,80.66 138.88,83.36 136.99,85.25 134.02,85.25 125.27,94.01 124.76,94.01 124.56,94.21 124.56,94.53 124.47,94.62 124.15,94.62 124.07,94.53 124.07,94.18 123.89,94.01 123.43,94.01 123.24,94.2 123.24,94.61 123.11,94.74 122.87,94.74 122.74,94.61 122.74,94.2 122.56,94.01 122.09,94.01 121.9,94.2 121.9,94.72 121.76,94.87 121.55,94.87 121.41,94.72 121.41,94.2 121.22,94.01 120.48,94.01 119.63,94.86 118.04,94.86 117.84,95.06 117.84,95.32 v2(117.64,95.53)
  BOTTOM w0.076: 142.53,74.53 142.53,74.5 142.23,74.21 141.56,74.21 141.32,73.97 141.32,73.68 141.49,73.51 141.87,73.51 142.16,73.21 142.16,73.21 142.41,72.97 UC1.B47
  BOTTOM w0.102: CV5.1 117.79,95.09 117.79,95.38 v2(117.64,95.53) ; v2(142.03,74.89) 142.16,75.02 142.45,75.02 142.53,74.94 142.53,74.53
EDP_CPU_LANE_P1_C: length 4.1
  BOTTOM w0.102: CV5.2 117.84,93.52 117.84,93.19 117.09,92.45 v3(117.09,91.82) 117.09,91.12 116.96,90.98 JEDP1.37
EN: length 10.5
  TOP w0.203: PU100.20 216.38,48.71 215.68,48.02 v2(215.68,47.84) ; v2(220.46,48.18) 220.46,48.43 220.17,48.71 PU100.6
  TOP w0.254: v2(215.68,47.84) 215.61,47.84 214.88,47.1 PC119.1 214.87,46.39 PR113.2
  IN1 w0.254: v2(220.46,48.18) 220.11,47.84 v2(215.68,47.84)
  BOTTOM w0.102: v2(220.46,48.18) v1(220.46,47.62)
EN_+V1.05SP: length 28
  TOP w0.102: PR303.1 206.74,58.67 v1(207.12,58.29)
  TOP w0.254: PR303.1 206.46,59.84 v2(206.1,59.84) ; RZ42.2 RZ41.2 220.73,69.07 220.73,68.1 v2(220.72,68.1)
  IN2 w0.254: v2(220.72,68.1) 208.36,68.1 207.17,66.92 207.17,60.22 206.79,59.84 v2(206.1,59.84)
  BOTTOM w0.254: v2(206.1,59.84) 205.67,59.84 205.51,60.01 PU300.1
EN_INVPWR: length 193.6
  TOP w0.102: v2(107.63,96.25) v1(111.15,96.25) 118.21,96.25 118.22,96.24 194.04,96.24 v2(194.19,96.09) ; UE2.A25 253.08,42.21 253.07,42.2 v2(252.12,42.2) 251.86,42.46 250.17,42.46 RE55.2
  IN1 w0.102: v2(194.19,96.09) 194.76,96.66 201.74,96.66 202.63,95.77 203.39,95.77 207.64,91.52 224.91,91.52 225.36,91.07 229.71,91.07 234.36,86.42 234.36,86.06 237.51,82.91 237.51,80.3 240.34,77.47 240.34,72.16 241.21,71.3 249.69,71.3 v2(250.53,70.46)
  BOTTOM w0.102: v2(107.63,96.25) 107.2,96.68 QV2.2 ; v2(252.12,42.2) 251.73,42.2 250.48,43.45 250.48,56.61 250.8,56.93 250.8,70.19 v2(250.53,70.46)
EN_LCDPWR: length 6.5
  TOP w0.102: RV3.2 100.94,92.21 100.94,90.98 101.21,90.71 UV24.3 102.25,91.16 DV3.1 104.16,92.29 v1(104.2,92.33)
ENVDD_PCH: length 212.9
  TOP w0.102: v2(172.35,85.38) 172.35,87.39 166.37,93.37 120.74,93.37 118.79,91.43 v1(112.13,91.43) 106.28,91.43 104.46,93.25 101.93,93.25 101.6,93.59 DV3.3 ; v2(259.7,54.76) 259.83,54.63 259.83,51.33 260.07,51.09 260.07,49 259.98,48.91 259.98,48.56 259.69,48.26 UE2.A7 ; RC139.2 168.13,77.83 v2(168.13,74.58)
  IN1 w0.102: v2(259.7,54.76) 257.05,57.42 253.69,57.42 253.13,57.97 249.25,57.97 244.92,62.31 241.38,62.31 235.76,67.92 235.76,74.09 232.8,77.05 231.23,77.05 229.63,78.65 217.96,78.65 214.72,75.41 198.05,75.41 193.58,79.88 193.58,80.59 193.38,80.8 193.38,80.81 191.95,82.24 191.95,82.43 191.95,82.6 190.41,84.14 190.41,84.21 190.41,84.72 188.69,86.44 188.49,86.44 188.47,86.45 180.95,86.45 180.15,87.25 176.01,87.25 173.73,84.96 172.77,84.96 v2(172.35,85.38) 172.06,85.38 170.62,83.95 170.62,82.93 170.01,82.32 170.01,77.28 169.06,76.33 169.06,75.51 v2(168.13,74.58)
  BOTTOM w0.076: UC1.C6 167.01,72.91 167.46,73.37 167.46,73.82 168.13,74.49 v2(168.13,74.58)
EXPRESS_DET#: length 2.9
  TOP w0.102: UE3.40 251.94,69.28 250.97,70.24 T97.1
EXPRESS_SMBCLK: length 8.5
  TOP w0.102: RPE3.2 260.85,50.68 v2(261.36,50.16) ; UE2.B4 261.44,46.63 261.41,46.61 261.41,46.2 261.01,45.79 v2(261.01,45.79)
  IN1 w0.102: v2(261.36,50.16) 261.48,50.05 261.48,48.04 261.41,47.98 261.41,46.2 v2(261.01,45.79)
  BOTTOM w0.102: v2(261.01,45.79) 261.01,45.16 v1(261.06,45.11)
EXPRESS_SMBDATA: length 4.4
  TOP w0.102: UE2.A3 v1(261.69,49.19) 261.69,49.26 260.54,50.41 260.54,51.26 260.35,51.45 RPE3.1
F-IMAX: length 4.5
  TOP w0.102: v2(102.85,64.12) 102.7,64.12 v1(102.25,63.66)
  TOP w0.203: v2(102.85,64.12) 103.11,64.12 103.55,64.56 PU500.10
  BOTTOM w0.254: PR508.1 v2(102.85,64.12) 102.66,63.92 102.5,63.92 101.71,63.13 PR503.2
FAN1_PWM: length 245.5
  TOP w0.102: v2(69.19,55.75) 74.11,50.82 74.11,41.53 v4(75.03,40.61) 78.04,37.6 81.47,37.6 v2(83.2,35.88) ; v2(247.81,42.91) 248.3,42.43 248.3,42.23 248.45,42.07 RE48.2 249.15,42.51 249.94,42.51 250.09,42.66 253.1,42.66 253.15,42.71 UE2.A24
  IN1 w0.102: v2(218.37,33.93) 218.88,33.43 221.59,33.43 224.15,35.98 234.88,35.98 236.89,38 240.43,38 241.4,38.96 243.86,38.96 v2(247.81,42.91)
  IN2 w0.102: v2(61.92,85.2) 61.92,84.91 67.51,79.32 67.51,73.49 67.12,73.1 67.12,68.89 68.42,67.59 68.42,67.36 73.02,62.76 73.02,59.57 v2(69.19,55.75)
  BOTTOM w0.102: v2(83.2,35.88) 89.41,29.67 155.2,29.67 155.72,30.19 208.11,30.19 210.51,32.59 217.03,32.59 v2(218.37,33.93) ; JFAN1.2 61.92,86.09 v2(61.92,85.2)
FAN1_TACH: length 252.1
  TOP w0.102: v2(68.65,55.32) 73.91,50.05 73.91,41.1 v4(76.9,38.11) 77.66,37.35 81.09,37.35 v2(82.59,35.85) ; RE51.2 247.14,44.35 247.52,43.97 v2(247.74,43.97) ; v2(255.85,44.89) 255.85,44.74 255.57,44.46 UE2.B22
  IN1 w0.102: v2(255.85,44.89) 255.85,44.74 255.58,44.47 254.47,44.47 253.07,45.87 251.15,45.87 249.25,43.97 v2(247.74,43.97) 247.09,43.97 242.3,39.18 241.33,39.18 240.55,38.4 237.01,38.4 234.79,36.19 224.07,36.19 221.81,33.93 v2(218.96,33.93)
  IN2 w0.102: v2(62.85,85.08) 62.85,84.33 67.71,79.46 67.71,73.41 67.32,73.02 67.32,68.97 68.62,67.67 68.62,67.44 73.22,62.84 73.22,59.11 69.42,55.32 v2(68.65,55.32)
  BOTTOM w0.102: v2(62.85,85.08) 62.85,85.25 JFAN1.3 ; v2(82.59,35.85) 89.02,29.41 155.23,29.41 155.81,29.98 208.19,29.98 210.6,32.39 217.42,32.39 v2(218.96,33.93)
FB_+V1.05SP: length 6.3
  BOTTOM w0.102: v1(210.03,61.48) PR309.2
  BOTTOM w0.254: PU300.4 205.7,61.36 205.86,61.51 PR310.1 206.59,61.44 206.59,60.62 PR307.2 207.26,60.96 208.42,60.96 PR309.2
FFS_INT2: length 193.3
  TOP w0.102: v2(276.17,10.8) v1(275.67,10.3) 275.07,9.7 266.21,9.7 265.42,10.5 252.65,10.5 248.36,14.79 243.86,14.79 242.06,16.59 237.63,16.59 236.07,18.15 236.07,22.37 229.47,28.97 229.47,31.81 228.94,32.35 228.94,33.96 228.25,34.65 228.25,44.12 233.14,49.01 233.14,60.44 231.45,62.13 231.45,73.44 v2(231.66,73.65)
  IN1 w0.102: v2(231.66,73.65) 230.92,74.38 217.65,74.38 215.88,72.62 196.88,72.62 190.74,78.76 190.74,79.48 189.15,81.07 189.15,81.43 186.95,83.63 180.15,83.63 179.41,82.89 176.4,82.89 173.47,79.96 173.47,78.43 173.49,78.42 173.49,70.82 173.47,70.81 173.47,69.88 v2(173.85,69.51)
  BOTTOM w0.076: UC1.G2 170.48,68.94 170.85,68.94 171.42,69.51 v2(173.85,69.51) 174.03,69.33 RC158.2
  BOTTOM w0.102: QN1.2 276.53,10.45 v2(276.17,10.8)
  BOTTOM w0.305: QN1.2 276.53,9.65 276.06,9.18 276.06,6.68 276.49,6.25 277.12,6.25 277.22,6.35 UN1.9
FFS_INT2_Q: length 13.1
  BOTTOM w0.102: JSATA1.19 267.94,5.42 268.17,5.19 270.51,5.19 270.84,5.52 270.84,7.68 RN1.2 273.63,9.69 v1(274.69,9.69) 275.64,9.69 275.88,9.93 QN1.3
FWP#: length 7.9
  TOP w0.102: UE2.B65 262.88,44.96 v2(262.87,44.97) ; v2(266.21,48.2) 266.22,48.19 RE81.2 RE82.2
  IN2 w0.102: v2(266.21,48.2) 266.21,47.36 263.83,44.97 v2(262.87,44.97)
  BOTTOM w0.102: v2(266.21,48.2) v1(266.21,47.67)
GC6_EVENT#_Q: length 18.6
  TOP w0.076: v2(167.24,65.71) 167.77,66.24 167.93,66.24 168.16,66.47 170.22,66.47 171.17,67.42 171.73,67.42 v1(171.82,67.33) 171.89,67.26 171.89,66.75 172.12,66.52 172.91,66.52 173.36,66.97
  TOP w0.102: RPC16.8 182.02,67.43 181.49,66.9 180.91,66.9 180.41,66.41 176.82,66.41 176.55,66.67 175.93,66.67 175.57,67.03 173.42,67.03 173.36,66.97
  BOTTOM w0.076: v2(167.24,65.71) 167.24,65.52 UC1.R6
GFB: length 3.2
  TOP w0.102: v1(108.05,66.95) 108.62,67.52 PR532.2
  TOP w0.203: PU500.23 107.64,68.03 107.81,67.86 PR532.2
GPU_GC6_FB_EN: length 16.2
  TOP w0.076: v2(167.77,67.63) 167.77,68.18 168.3,68.71 168.3,68.96 169.16,69.82 171.6,69.82 v1(171.78,69.64) 173.16,69.64 173.75,69.06 174.79,69.06 175.19,69.46 175.7,69.46
  TOP w0.102: 175.7,69.46 180.57,69.46 180.87,69.16 180.87,69.04 180.98,68.93 RPC3.8
  BOTTOM w0.076: UC1.L6 167.5,67.35 v2(167.77,67.63)
GPU_SMBCLK: length 16.6
  TOP w0.102: RPE3.4 261.85,51.51 261.96,51.4 262.05,51.4 v2(262.38,51.07) ; v2(261.31,39.17) 261.78,38.7 261.78,38.28 261.94,38.12 UE2.B49
  IN1 w0.102: v2(262.38,51.07) 262.38,51.07 262.86,50.59 262.86,47.12 263.51,46.47 263.51,44.69 263.14,44.32 262.06,44.32 261.38,43.63 261.38,40.43 261.12,40.18 261.12,39.36 v2(261.31,39.17)
GPU_SMBDAT: length 16.7
  TOP w0.102: v2(261.77,51.03) 261.35,51.46 RPE3.3 ; v2(261.31,38.54) 261.31,38.3 261.44,38.18 UE2.B48
  IN1 w0.102: v2(261.31,38.54) 260.89,38.96 260.89,40.27 261.15,40.53 261.15,43.73 261.97,44.55 263.04,44.55 263.28,44.79 263.28,46.38 262.63,47.03 262.63,50.44 262.42,50.66 262.15,50.66 v2(261.77,51.03)
H_CATERR#: length 7.2
  BOTTOM w0.076: UC1.K61 133.21,68.11 132.69,68.11 132.48,67.91 132.48,67.63 132.37,67.51 131.86,67.51 131.58,67.8 131.28,67.8 129.9,69.18 v4(129.7,69.18) 129.42,69.18
  BOTTOM w0.102: 129.42,69.18 129.03,69.18 128.8,68.95 127.94,68.95 RC114.2
H_CPU_SVIDALRT#: length 8.1
  BOTTOM w0.102: UC1.L62 132.57,67.08 132.45,66.95 132.45,66.72 132.35,66.62 131.99,66.62 131.95,66.66 131.95,66.78 131.84,66.89 131.66,66.89 131.56,66.79 131.56,66.65 131.43,66.52 130.99,66.52 130.87,66.65 130.87,67.09 130.75,67.21 130.58,67.21 130.46,67.09 130.46,66.62 130.35,66.51 130.19,66.51 130.08,66.62 130.08,67.39 130.01,67.46 129.77,67.46 v1(129.68,67.38) 129.68,66.64 129.54,66.5 129.28,66.5 129.18,66.6 129.18,66.79 129.11,66.86 128.95,66.86 RC207.1
H_CPUPWRGD: length 99.4
  TOP w0.102: v2(76.6,50.49) 75.79,50.49 RC103.1
  IN1 w0.102: v2(131.61,78.64) 131.08,79.16 128.73,79.16 127.72,78.16 125.16,78.16 124.83,78.49 106.37,78.49 101.6,73.71 v2(101.6,73.42)
  IN2 w0.102: v2(101.6,73.42) 100.47,72.29 100.47,63.59 99.78,62.91 99.78,59.68 98.77,58.67 98.77,54.08 95.7,51.02 95.7,49.06 93.83,47.19 92.16,47.19 89.63,44.67 86.71,44.67 85.72,45.66 80.52,45.66 79.26,44.4 76.3,44.4 75.64,45.06 75.64,49.53 v2(76.6,50.49)
  BOTTOM w0.076: UC1.C61 133.8,72.29 133.8,73.03 133.92,73.15 134.27,73.15 134.39,73.27 134.39,73.63 133.8,74.22 133.21,74.22
  BOTTOM w0.102: 133.21,74.22 131.23,76.2 131.23,76.64 131.02,76.85 CC83.1 RC123.1 131.02,78.05 v2(131.61,78.64)
H_PROCHOT#: length 294.5
  TOP w0.102: v2(107.24,78.94) 103.38,75.08 103.38,73.11 PC514.1 PR534.2 ; v2(262.43,35.58) 262.43,35.61 261.69,36.35 UE2.A46
  IN2 w0.102: v2(262.43,35.58) 262.49,35.65 267.13,35.65 267.84,34.94 274.41,34.94 276.08,36.62 276.08,44.5 275.34,45.25 275.34,59.3 274.79,59.86 274.79,66.55 270.83,70.51 254.71,70.51 253.92,71.29 243.78,71.29 239.76,75.31 219.69,75.31 212.89,82.12 v2(203.15,82.12) ; v2(84.66,82.49) 84.96,82.18 v2(84.96,79.5)
  BOTTOM w0.102: 123.71,80.34 124.69,80.34 125.07,79.96 125.07,78.66 127.15,76.58 127.15,73.38 126.88,73.11 126.88,72.67 126.35,72.14 126.35,71.98 124.88,70.5 124.88,70.46 124.88,70.46 RC121.1 RC116.2 CC20.1 ; 123.71,80.34 123.71,81.85 126.36,84.51 129.48,84.51 132.36,87.38 132.36,91.24 137.75,96.63 189.5,96.63 194.42,91.72 201.45,91.72 204.01,89.16 204.01,82.98 v2(203.15,82.12) ; 123.71,80.34 116.86,80.34 115.47,78.94 v2(107.24,78.94) 106.21,79.97 97.22,79.97 96.34,79.1 88,79.1 87.59,79.5 v2(84.96,79.5) ; PR717.1 v2(84.66,82.49)
H_PROCHOT#_R: length 14.8
  IN1 w0.102: v2(128.62,69.39) 128.62,69.95 128.49,70.08 128.23,70.08 128.1,69.95 128.1,69.32 127.98,69.19 127.67,69.19 127.54,69.32 127.54,69.95 127.42,70.08 127.11,70.08 126.98,69.95 126.98,69.32 126.85,69.19 126.6,69.19 126.47,69.32 126.47,69.99 126.35,70.12 126.09,70.12 125.96,69.99 125.96,69.33 125.84,69.2 125.58,69.2 125.46,69.33 v2(125.46,70.21)
  BOTTOM w0.102: v2(128.62,69.39) 128.84,69.61 129.83,69.61 131.42,68.02 131.96,68.02 UC1.K63 ; v2(125.46,70.21) 125.46,70.51 125.58,70.64 125.88,70.64 126.01,70.51 126.01,69.8 RC121.2
H_THERMTRIP#: length 233.2
  TOP w0.102: QE4.3 251.97,33.55 251.83,33.41 v2(251.43,33.41)
  IN2 w0.102: v2(202.24,82.6) 213.09,82.6 219.97,75.72 239.93,75.72 243.94,71.7 254.19,71.7 254.98,70.92 271,70.92 275.19,66.72 275.19,61.65 275.75,61.09 275.75,45.41 276.49,44.67 276.49,36.37 274.65,34.53 267.55,34.53 265.71,32.69 253.76,32.69 253.39,33.06 251.79,33.06 v2(251.43,33.41)
  BOTTOM w0.102: RC161.1 RC25.2 129.3,82.48 129.3,83.74 132.76,87.21 132.76,91.07 137.92,96.23 189.28,96.23 194.2,91.31 201.28,91.31 203.6,88.99 203.6,83.96 v2(202.24,82.6)
H_THERMTRIP#_R: length 11
  BOTTOM w0.076: 129.7,76.3 129.85,76.15 129.85,75.92 131.84,73.94 131.84,73.84 132.57,73.11 132.98,73.11 133.14,72.96 133.14,72.49 133.92,71.71 UC1.D60
  BOTTOM w0.102: RC161.2 128.63,79.69 128.71,79.61 v4(128.71,78.71) 128.71,78.63 129.17,78.17 129.17,76.83 129.7,76.3
H_VCCST_PWRGD: length 104
  TOP w0.102: v1(76.01,53.09) RC102.1 76.41,51.7 v2(76.63,51.7) ; UC8.4 139.26,87.02 CC24.1 RC202.1 140.07,86.63 139.48,86.04 139.48,79.22 139.17,78.91 139.17,77.31 137.3,75.44 v2(134.73,75.44)
  IN1 w0.102: v2(76.63,51.7) 77.18,51.16 82.74,51.16 85.19,53.6 90.59,53.6 94.66,57.68 94.66,69.95 105.74,81.03 114.95,81.03 115.57,81.65 122.88,81.65 124.72,79.81 131.75,79.81 134.21,77.34 134.21,75.96 v2(134.73,75.44)
  BOTTOM w0.076: UC1.B59 134.88,73.05 135.2,73.37 135.2,73.8 134.73,74.27 v2(134.73,75.44)
H_VCCST_PWRGD_XDP: length 4.6
  TOP w0.102: v1(74.53,53) 75.09,52.44 RC103.2 RC102.2 76.01,51.2 JXDP1.39
H_VR_EN: length 58.5
  TOP w0.102: PR536.2 98.88,63.54 97.53,63.54 97.11,63.96 v1(97.11,69.6) v2(98.03,70.51)
  IN1 w0.102: v2(129.45,78.68) 128.39,77.62 124.84,77.62 124.46,78 107.08,78 103.03,73.95 103.03,73.01 100.53,70.51 v2(98.03,70.51)
  IN2 w0.102: v2(129.45,78.68) 129.91,78.22 129.91,76.07 134.26,71.72 134.52,71.72 134.85,71.39 134.85,71.02 134.68,70.85 134.21,70.85 v2(133.81,70.45)
  BOTTOM w0.076: v2(133.81,70.45) 134.11,70.15 UC1.F60
  BOTTOM w0.102: v2(129.45,78.68) 129.45,79.52 RC201.2
H_VR_READY: length 54.4
  TOP w0.102: PR539.2 v2(98.54,66.59)
  IN1 w0.102: v2(132.53,76.52) 131.76,77.28 124.71,77.28 124.34,77.65 107.31,77.65 103.36,73.7 103.36,72.88 99.15,68.66 99.15,67.2 v2(98.54,66.59)
  BOTTOM w0.076: UC1.C59 134.55,72.54 134.55,73.68 133.79,74.45 133.5,74.45 132.53,75.42 132.53,76.3
  BOTTOM w0.102: RC199.2 RC201.1 130.46,80.46 130.46,79.86 130.72,79.6 131.61,79.6 133.06,78.16 133.06,77.05 v2(132.53,76.52) 132.53,76.3 ; v2(98.54,66.59) v1(98.54,67.12)
HDD_A_EQ: length 2.7
  TOP w0.102: RN12.1 RN13.2 267.03,17.06 266.84,17.24 UN2.17
HDD_A_EQ2: length 6.6
  TOP w0.102: RN24.2 270.44,19.29 270.44,18.41 RN25.2 269.54,18.4 267.33,18.4 266.67,17.74 UN2.18
HDD_A_PRE: length 5.6
  TOP w0.102: UN2.9 260.41,17.24 RN9.2 RN8.1 260.36,16.19 260,15.84 258.02,15.84 v1(257.77,16.09)
HDD_B_EQ: length 4
  TOP w0.102: UN2.19 266.75,18.24 267.18,18.67 267.47,18.67 RN16.2 RN14.2 267.7,20.28 v1(268.15,20.73)
HDD_B_EQ2: length 8.2
  TOP w0.102: UN2.13 264.04,14.96 263.99,14.91 263.99,11.67 v1(263.9,11.58) 263.12,10.79 261.86,10.79 RN23.2 260.54,11.27 RN22.2
HDD_B_PRE: length 2.8
  TOP w0.102: RN10.1 RN11.2 260.7,17.74 UN2.8
HDD_DET#: length 185.9
  TOP w0.102: v2(230.39,73.67) 230.67,73.39 v4(230.67,71.82) 230.67,71.21 230.85,71.03 230.85,61.8 232.53,60.11 232.53,49.26 227.05,43.78 227.05,42.47 225.96,41.38 225.96,36.08 228.33,33.7 228.33,32.09 228.86,31.56 228.86,28.71 235.46,22.12 235.46,17.89 237.37,15.98 241.81,15.98 243.61,14.18 248,14.18 252.32,9.86 264.56,9.86 v2(264.8,9.63)
  IN1 w0.102: v2(230.39,73.67) 229.91,74.15 217.71,74.15 215.97,72.41 196.79,72.41 190.54,78.67 190.54,79.4 188.95,80.98 188.95,81.35 186.87,83.43 180.24,83.43 179.49,82.68 176.49,82.68 175.6,81.8 175.6,80.3 173.73,78.43 173.73,70.42 174.25,69.9 174.25,67.17 172.58,65.49 v2(172.58,64.82)
  BOTTOM w0.076: UC1.U1 171.8,64.04 v2(172.58,64.82) 172.97,65.21 173.36,65.21
  BOTTOM w0.102: 173.36,65.21 173.68,64.88 RPC18.6 ; JSATA1.13 264.94,8.83 264.8,8.97 v2(264.8,9.63)
HDD_DEVSLP: length 188.1
  TOP w0.102: v2(265.39,9.63) 264.95,10.06 252.4,10.06 248.09,14.38 243.69,14.38 241.89,16.18 237.46,16.18 235.66,17.98 235.66,22.21 229.07,28.8 229.07,31.65 228.53,32.18 228.53,33.79 226.16,36.16 226.16,41.26 227.38,42.48 227.38,43.82 232.74,49.18 232.74,60.24 231.05,61.92 231.05,73.67 230.51,74.21 v1(230.51,75.3) 230.51,75.33 229.7,76.14 v2(229.46,76.14)
  IN1 w0.102: v2(229.46,76.14) 228.72,75.4 217.23,75.4 215.46,73.63 197.31,73.63 191.78,79.16 191.78,79.88 190.17,81.5 190.17,81.86 187.39,84.64 176.35,84.64 172.04,80.34 172.04,76.8 170.71,75.46 170.71,71.34 171.85,70.19 v2(171.85,68.12)
  BOTTOM w0.076: v2(171.85,68.12) 171.85,68.12 171.38,67.65 171.1,67.65 170.86,67.42 170.61,67.42 170.22,67.04 UC1.L2
  BOTTOM w0.102: JSATA1.11 263.94,9.57 264.41,10.03 264.98,10.03 v2(265.39,9.63) 267.9,9.63 RN5.2
HDD_FALL_INT: length 216.2
  TOP w0.076: 173.36,65.76 v1(172.4,65.76) 170.35,65.76 170.13,65.53 169.51,65.53 v2(169.15,65.9)
  TOP w0.102: v2(276.84,7.47) 276.46,7.47 274.44,9.5 266.11,9.5 265.31,10.29 252.46,10.29 248.17,14.58 243.77,14.58 241.98,16.38 237.54,16.38 235.86,18.06 235.86,22.29 229.27,28.88 229.27,31.73 228.74,32.26 228.74,33.87 226.36,36.25 226.36,41.16 227.58,42.38 227.58,43.73 232.94,49.09 232.94,60.34 231.25,62.03 231.25,77.61 v2(231.02,77.84) ; 173.36,65.76 173.41,65.76 173.81,65.35 174.3,65.35 174.39,65.44 179.36,65.44 179.63,65.7 179.63,65.96 179.74,66.07 RPC9.5
  IN1 w0.102: v2(169.15,65.9) 168.68,66.37 168.68,67.91 168.3,68.29 168.3,70.24 167.17,71.37 167.17,74.79 168.45,76.07 168.45,76.58 168.73,76.86 168.73,79.21 169.4,79.89 169.4,82.63 170,83.23 170,84.22 172.21,86.42 174.3,86.42 175.34,87.46 180.22,87.46 181.04,86.65 188.56,86.65 188.57,86.64 188.77,86.64 190.61,84.8 190.61,84.22 192.15,82.68 192.15,82.33 193.58,80.89 193.58,80.88 193.79,80.68 193.79,79.96 198.14,75.62 214.64,75.62 217.88,78.85 229.74,78.85 230.75,77.84 v2(231.02,77.84)
  BOTTOM w0.076: UC1.N4 168.83,66.21 v2(169.15,65.9)
  BOTTOM w0.305: UN1.11 276.97,7.35 v2(276.84,7.47)
HDMI_CEC: length 10.1
  TOP w0.102: v1(218.23,94.04) 218.23,95.27 v2(218.74,95.78) 219.09,95.78 RV8.2
  IN1 w0.102: v2(218.74,95.78) 218.75,95.78 220.02,97.05 220.02,98.68 219.39,99.31 217.46,99.31 JHDMI1.13
HDMI_CLK_AUX: length 34.5
  TOP w0.102: v2(233.45,88.36) v1(233.45,88.99) 233.45,89.16 232.51,90.11 226.32,90.11 222.56,93.87 222.56,94.39 RV7.1 223.02,96.37 222.31,96.37 219.29,99.39 218.38,99.39 JHDMI1.15
  BOTTOM w0.102: v2(233.45,88.36) 233.18,88.36 233.06,88.23 233.06,87.63 234.24,86.44 234.24,82.9 233.73,82.39 230.86,82.39 230.78,82.31 UV7.48
HDMI_DAT_AUX#: length 30
  TOP w0.102: JHDMI1.16 220.96,95.81 RV9.1 222.2,94.37 v1(222.2,94.03) 222.2,93.8 226.17,89.83 232.42,89.83 232.94,89.31 v2(232.94,88.82)
  BOTTOM w0.102: v2(232.94,88.82) 232.99,88.77 232.99,88.49 232.83,88.32 232.83,87.53 234.01,86.35 234.01,82.99 233.63,82.62 230.86,82.62 230.77,82.71 UV7.47
HDMI_HPD: length 31.4
  TOP w0.102: v2(220.7,88.9) 219.39,87.59 v1(219.39,81.61) 219.39,80.71 220.19,79.91 v2(222.25,79.91)
  BOTTOM w0.102: v2(220.7,88.9) 222.1,90.3 224.24,90.3 226.18,92.24 226.18,94.3 223.91,96.57 221.8,96.57 220.47,97.9 220.47,99.3 JHDMI1.19 ; UV7.17 v2(222.25,79.91)
HDMI_LANE_N0: length 17.8
  BOTTOM w0.102: LV12.1 213.24,92.48 213.55,92.16 213.55,90 v3(214.46,89.1) 215.97,87.58 215.97,85.76 216.88,84.86 216.88,84.84 217.25,84.47 217.27,84.47 221.34,80.4 222.56,80.4 222.65,80.31 UV7.18
HDMI_LANE_N1: length 17.8
  BOTTOM w0.102: LV10.1 215.33,92.48 215.65,92.16 215.65,91.8 215.88,91.57 216.8,91.57 216.9,91.47 216.9,91.11 216.77,90.98 216.13,90.98 216.11,90.97 215.92,90.97 215.62,90.67 215.62,89.14 216.8,87.96 216.8,86.19 v3(219.77,83.22) 221.39,81.6 222.56,81.6 222.66,81.51 UV7.21
HDMI_LANE_N2: length 20.4
  BOTTOM w0.102: UV7.24 222.46,82.71 222.37,82.8 221.39,82.8 219,85.19 219,85.56 219.62,86.19 219.62,86.33 219.41,86.55 219.26,86.55 218.69,85.98 218.18,85.98 217.74,86.42 217.74,87.67 217.97,87.9 218.54,87.9 218.64,88 218.64,88.31 218.54,88.41 217.97,88.41 217.74,88.64 217.74,89.12 217.97,89.35 218.67,89.35 218.77,89.45 218.77,89.76 218.67,89.86 v3(218.34,89.86) 217.97,89.86 217.74,90.08 217.74,90.57 217.97,90.8 218.67,90.8 218.77,90.9 218.77,91.2 218.67,91.3 217.97,91.3 217.74,91.53 217.74,92.08 217.43,92.4 LV6.1
HDMI_LANE_N3: length 20.3
  BOTTOM w0.102: UV7.15 222.46,79.11 222.37,79.2 220.47,79.2 v3(217.82,81.84) 215.15,84.52 215.15,87.24 212.58,89.8 212.56,89.8 212.19,90.18 212.19,90.19 211.44,90.94 211.44,92.13 211.14,92.42 LV3.1
HDMI_LANE_P0: length 17.4
  BOTTOM w0.102: LV12.4 214.09,92.48 213.77,92.16 213.77,90.09 214.41,89.45 214.43,89.45 214.8,89.07 214.8,89.05 216.19,87.67 216.19,85.85 v3(217.22,84.82) 221.43,80.61 222.55,80.61 222.64,80.71 UV7.19
HDMI_LANE_P1: length 17.4
  BOTTOM w0.102: LV10.4 216.18,92.48 215.86,92.16 215.86,91.89 215.97,91.78 216.89,91.78 217.12,91.56 217.12,91.02 216.85,90.75 v3(216.46,90.75) 216.04,90.75 215.83,90.55 215.83,89.23 217.02,88.05 217.02,86.28 219.67,83.63 219.69,83.63 220.12,83.2 220.12,83.18 221.48,81.81 222.56,81.81 222.66,81.91 UV7.22
HDMI_LANE_P2: length 20
  BOTTOM w0.102: UV7.25 222.46,83.11 222.37,83.01 221.48,83.01 219.21,85.28 219.21,85.47 219.84,86.1 219.84,86.42 219.5,86.76 219.16,86.76 218.59,86.19 218.27,86.19 217.96,86.51 217.96,87.58 218.05,87.67 v3(218.37,87.67) 218.61,87.67 218.85,87.91 218.85,88.4 218.62,88.63 218.06,88.63 217.96,88.73 217.96,89.03 218.06,89.13 218.76,89.13 218.98,89.36 218.98,89.85 218.74,90.09 218.05,90.09 217.96,90.17 217.96,90.48 218.06,90.58 218.76,90.58 218.98,90.81 218.98,91.29 218.76,91.52 218.06,91.52 217.96,91.62 217.96,92.09 218.28,92.41 LV6.4
HDMI_LANE_P3: length 20
  BOTTOM w0.102: UV7.16 222.46,79.51 222.37,79.41 220.56,79.41 218.17,81.8 218.17,81.82 217.79,82.19 217.78,82.19 215.36,84.61 215.36,87.32 v3(212.54,90.15) 211.66,91.03 211.66,92.11 211.99,92.45 LV3.4
HOST_ALERT1_R_N: length 12.1
  TOP w0.102: RC179.2 176.72,61.34 v1(176.67,61.39) 176.24,61.82 172.45,61.82 171.68,61.05 169.15,61.05 168.63,60.53 167.53,60.53 v2(167.08,60.98)
  BOTTOM w0.076: v2(167.08,60.98) 167.08,60.86 167.43,60.5 UC1.AD6
HOST_DEBUG_TX: length 59.2
  TOP w0.102: UE2.B44 259.44,38.52 v2(259.43,38.52) ; v2(299.2,35.28) RE73.2 299.5,35.74 299.25,35.74 298.78,36.21 298.78,36.88 298.52,37.13 JDEG1.8
  BOTTOM w0.102: v2(259.43,38.52) 259.89,38.98 259.89,39.37 260.13,39.61 261.57,39.61 261.83,39.34 261.83,38.3 262.07,38.06 v1(263.57,38.06) 264.3,38.06 264.54,37.82 265.87,37.82 266.53,38.48 266.53,40.23 266.76,40.45 266.76,43.13 270.21,46.58 274.62,46.58 278.04,43.17 281.62,43.17 286.3,38.48 298.87,38.48 299.68,37.67 299.68,35.76 v2(299.2,35.28)
I_ADP: length 233.2
  TOP w0.102: v2(257.52,49.81) 257.35,49.63 257.35,49.16 257.12,48.93 257.12,48.34 257.19,48.27 UE2.A12 ; v2(81.07,89.1) v1(81.82,88.35)
  IN1 w0.102: v2(201.71,94.96) 201.71,92.89 205.04,89.56 224.76,89.56 225.36,88.96 228.88,88.96 232.37,85.47 232.37,84.82 233.43,83.76 234.17,83.76 236.19,81.74 236.19,79.68 239.02,76.85 239.02,71.34 241.58,68.78 260.91,68.78 v2(261.57,68.12)
  IN2 w0.102: v2(81.07,89.1) 81.07,90.35 83.54,92.81 88.57,92.81 89.93,94.17 94.61,94.17 101.99,101.55 106.3,101.55 107.61,100.23 130.52,100.23 v2(131.09,100.8)
  BOTTOM w0.102: v2(257.52,49.81) 256.83,49.81 256.25,50.39 256.25,51.62 257,52.38 257,56.52 258.33,57.85 258.33,59.94 261.81,63.41 261.81,67.88 v2(261.57,68.12) ; v2(131.09,100.8) 131.52,101.23 133.53,101.23 133.86,100.9 196.86,100.9 201.71,96.05 v2(201.71,94.96) ; PR716.1 v2(81.07,89.1)
I_BATT: length 232
  TOP w0.102: RE64.2 271.57,42.77 v2(271.57,44.65)
  IN1 w0.102: v2(271.57,44.65) 272.02,45.09 272.02,46.53 264.91,53.63 264.91,53.97 264.04,54.84 264.04,55.16 262.4,56.8 261.95,56.8 256.63,62.12 250.54,62.12 245.05,67.6 241.28,67.6 237.99,70.89 237.99,76.45 235.18,79.26 235.18,79.87 231.7,83.35 231.31,83.35 229.23,85.43 229.23,86.58 228.33,87.48 219.19,87.48 218.84,87.82 203.87,87.82 197.4,94.29 v2(197.4,94.95)
  BOTTOM w0.102: PR718.1 85.1,84.49 85.1,83.97 85.38,83.69 85.38,82.54 86.47,81.44 92.36,81.44 93.1,82.18 v1(110.34,82.18) 114.66,82.18 115.86,83.37 121.43,83.37 124.95,86.89 128.11,86.89 129.74,88.52 129.74,93.76 135,99.02 193.86,99.02 197.4,95.48 v2(197.4,94.95)
I_SYS: length 229.4
  TOP w0.102: v2(265.09,42.51) 264.89,42.71 UE2.A57
  IN1 w0.102: v2(196.8,94.91) 196.8,94.56 204.09,87.27 227.7,87.27 228.28,86.7 228.28,86.09 231.22,83.15 231.61,83.15 234.97,79.78 234.97,79.18 237.79,76.36 237.79,70.81 241.2,67.4 244.97,67.4 250.49,61.87 256.59,61.87 261.87,56.6 262.32,56.6 262.99,55.93 262.99,54.9 264.08,53.81 264.08,53.21 264.38,52.91 265.35,52.91 265.73,52.53 265.73,48.08 266.15,47.67 266.15,46.95 265.73,46.53 265.73,43.83 265.09,43.19 v2(265.09,42.51)
  BOTTOM w0.102: PR720.1 85.16,83.54 85.16,82.47 86.39,81.24 92.5,81.24 93.11,81.85 114.62,81.85 115.94,83.17 121.51,83.17 125.03,86.69 128.25,86.69 129.94,88.38 129.94,93.67 135.09,98.82 193.72,98.82 196.8,95.74 v1(196.8,95.61) v2(196.8,94.91)
ILIM_SEL: length 5
  TOP w0.102: v1(285.53,38.18) 285.54,38.16 287.53,38.16 288.22,38.86 RI13.1 288.59,39.56 288.26,39.89 UI3.4
ILMT_1.05V: length 4.4
  TOP w0.102: v1(205.74,63.64) 206.32,63.64 206.66,63.3 PR306.2
  TOP w0.254: v2(206.1,61.02) 206.66,61.58 PR308.1 PR306.2
  BOTTOM w0.254: v2(206.1,61.02) 205.83,61.02 205.71,60.91 PU300.3
IMON: length 4.6
  TOP w0.203: v2(104.89,63.86) 104.75,64 PU500.13
  BOTTOM w0.102: PR501.1 103.49,61.44 v1(103.32,61.28)
  BOTTOM w0.254: v2(104.89,63.86) 104.89,63.35 PC500.1 104.14,62.61 103.9,62.61 PR501.1
INT_SPK_L+: length 11.7
  TOP w0.203: UA1.42 33.06,12.78 32.95,12.67 v3(32.95,11.39)
  IN1 w0.762: v2(25.9,6.89) 26.17,6.89 28.47,9.19 29.85,9.19 30.39,9.42 30.48,9.44 30.83,9.78 32.49,9.78 33.04,10.34
INT_SPK_L-: length 10
  TOP w0.203: v3(33.49,12.52) 33.46,12.55 UA1.43
  IN1 w0.762: 31.98,11.09 30.34,11.09 29.8,10.55 29.6,10.46 27.94,10.46 27.89,10.41 27.86,10.41 26.27,8.82 v2(24.86,8.82)
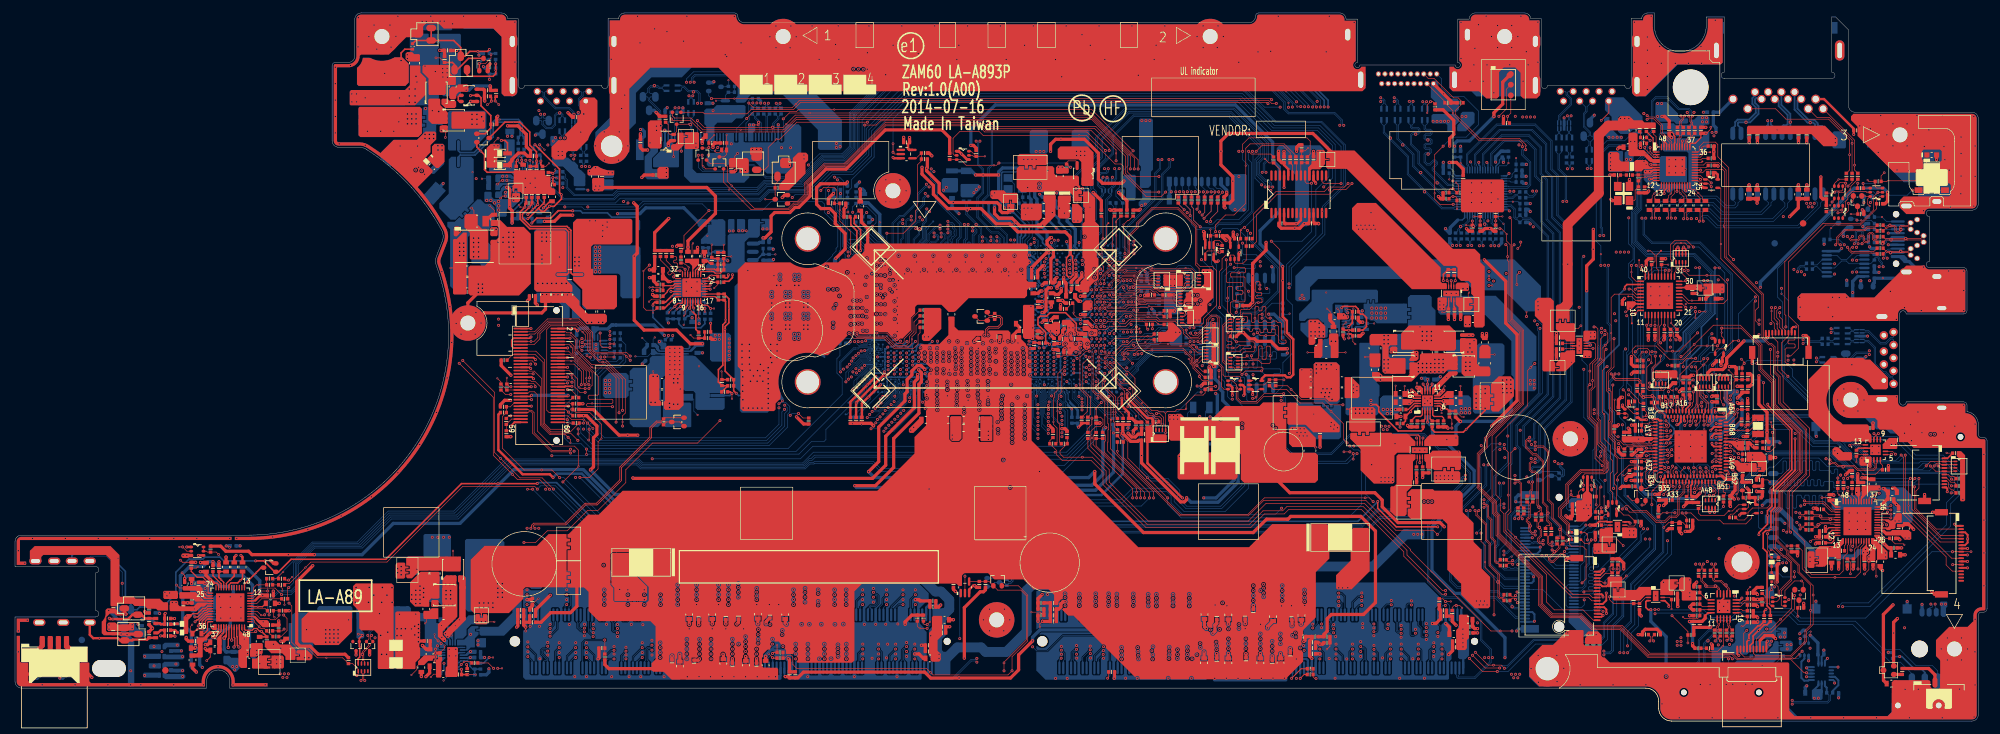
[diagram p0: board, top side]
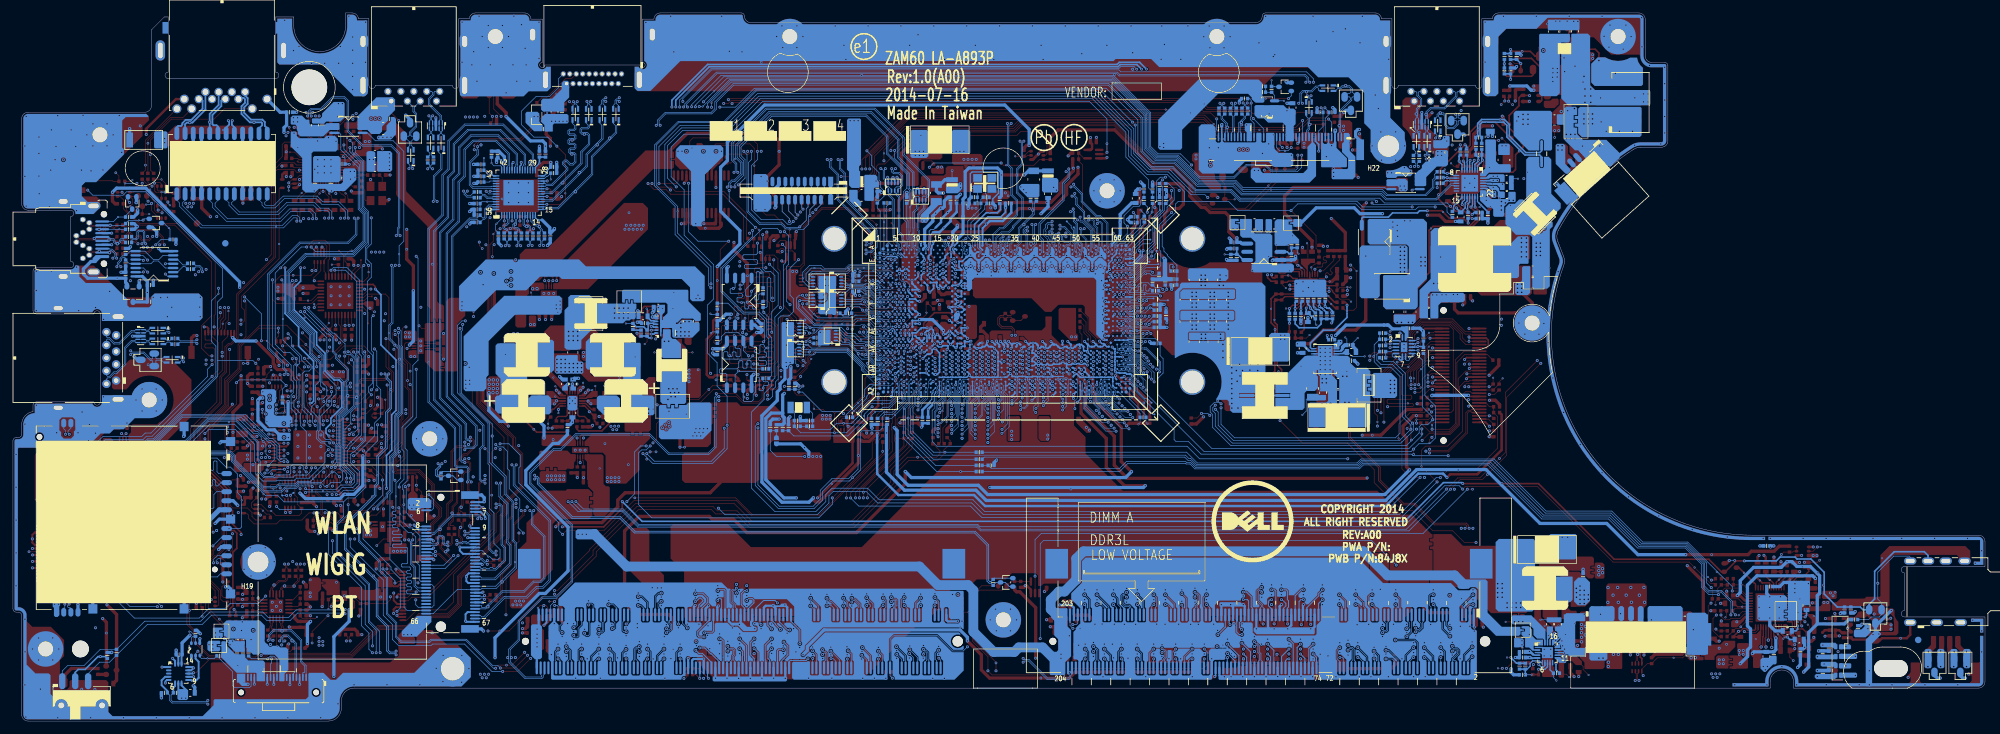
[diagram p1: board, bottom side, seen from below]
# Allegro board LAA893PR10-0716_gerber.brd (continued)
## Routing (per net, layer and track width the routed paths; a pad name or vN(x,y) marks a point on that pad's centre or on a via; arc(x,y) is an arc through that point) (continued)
INT_SPK_R+: length 12.8
  TOP w0.203: UA1.45 34.26,13.07 34.34,12.99 34.34,11.71 v3(34.59,11.45)
  IN2 w0.762: v2(25.89,9.95) 26.65,9.19 29.85,9.19 30.39,9.42 30.83,9.51 30.87,9.51 31.06,9.55 31.74,9.55 32.41,9.42 32.58,9.35 32.89,9.22 33.87,9.22 34.69,10.05
INT_SPK_R-: length 12.4
  TOP w0.203: UA1.44 33.86,12.93 33.97,12.81 33.97,11.58 v3(33.84,11.45)
  IN2 w0.762: 33.49,10.83 33.39,10.73 33.37,10.73 33.27,10.63 32.8,10.63 32.78,10.64 32.59,10.68 32.44,10.83 30.07,10.83 29.78,10.54 29.6,10.46 27.39,10.46 26.12,11.74 v2(25.07,11.74)
INT_SPKR_L+: length 20.5
  IN1 w0.762: v2(20.04,7.06) 19.69,7.06 16.48,10.26 12.3,10.26 9.48,7.44 6.46,7.44 6.06,7.04 4.18,7.04 2.85,8.36 v3(2.85,8.42)
  vias: v3(2.85,10.77)
INT_SPKR_L-: length 19.2
  IN1 w0.762: v2(21.48,8.53) 20.06,8.53 17.05,11.53 11.08,11.53 9.08,9.52 5.93,9.52 v3(4.82,8.42)
  vias: v3(4.76,10.77)
INT_SPKR_R+: length 15.2
  IN2 w0.762: v3(6.86,8.42) 8.29,6.98 9.23,6.98 12.44,10.2 19.85,10.2 v2(20.04,10.01)
  vias: v3(6.86,10.83)
INT_SPKR_R-: length 13.9
  IN2 w0.762: v3(8.82,8.42) 11.92,11.51 v2(21.48,11.51)
  vias: v3(8.76,10.77)
INTRUDER#: length 9
  BOTTOM w0.076: RC9.2 172.07,47.23 v1(171.54,47.76) 171.42,47.88 170.49,47.88 170.22,48.16 169.47,48.16 167.7,49.92 167.7,50.76 167.7,51.92 167.82,52.03 167.82,52.46 UC1.AU6
IO_LDOSEL: length 6.4
  TOP w0.102: v4(283.63,22.77) 283.63,24.6 RR6.2 RR8.1 284.29,25.26 284.29,26.62 284.52,26.85 284.52,27.24 284.52,27.24 UR1.18
IRQ_SERIRQ: length 162
  TOP w0.076: v2(168.42,65.71) 168.05,65.35 167.12,65.35 166.79,65.02 166.79,64.57 167.32,64.03 167.32,63.64 167.56,63.4 167.79,63.4 168.03,63.64 168.03,63.93 168.27,64.17 168.55,64.17 168.97,63.75 171.42,63.75 171.89,64.22 173.36,64.22
  TOP w0.102: UE2.A28 252.8,40.71 252.64,40.55 251.77,40.55 251.72,40.6 247.93,40.6 247.37,41.16 247.37,43.23 246.47,44.13 246.47,46.19 246.66,46.38 246.66,50.94 v4(246.34,51.26) 246.21,51.38 246.21,53.87 247.1,54.76 v2(247.1,59.13) ; 173.36,64.22 173.4,64.22 173.62,64.44 174.8,64.44 174.98,64.62 179.45,64.62 180.88,63.18 180.88,62.78 180.68,62.58 RPC15.2
  IN1 w0.102: v2(247.1,59.13) 247.1,59.77 244.76,62.1 241.29,62.1 235.55,67.84 235.55,74 232.71,76.85 231.14,76.85 229.54,78.45 218.05,78.45 214.81,75.21 197.97,75.21 193.38,79.79 193.38,80.51 193.18,80.71 193.18,80.72 191.74,82.16 191.74,82.52 190.21,84.05 190.21,84.29 190.21,84.63 188.6,86.23 188.4,86.23 188.39,86.25 175.62,86.25 170.46,81.09 170.46,77.44 169.41,76.39 169.41,70.71 169.45,70.66 169.45,67.06 170.15,66.36 170.15,65.75 169.87,65.47 168.66,65.47 v2(168.42,65.71)
  BOTTOM w0.076: UC1.T4 168.83,64.94 168.42,65.36 v2(168.42,65.71)
JTAG_CLK: length 47
  TOP w0.102: RPE7.3 299.07,39.15 299.05,39.13 JDEG1.4 297.5,39.13 v2(297.18,39.46) ; UE2.B56 263.21,40.46 263.14,40.53 262.59,40.53 262.29,40.23 v2(262.29,40.09)
  BOTTOM w0.102: v2(262.29,40.09) 262.29,40.32 262.52,40.55 v1(263.38,40.55) 263.59,40.75 263.59,42.7 264.59,43.7 265.09,43.7 268.79,47.4 278.73,47.4 282.89,43.24 283.78,43.24 287.12,39.9 294.23,39.9 294.46,40.13 296.5,40.13 v2(297.18,39.46)
JTAG_RST#: length 16.1
  TOP w0.102: UE2.B47 260.94,38.2 260.83,38.31 260.83,38.74 v2(260.41,39.16) ; v2(257.63,32.18) 258.34,31.47 CE30.1 RE65.1 257.75,30.69 JTAG1.1 RE63.2 255.55,30.69 v4(254.8,29.93)
  IN1 w0.102: v2(260.41,39.16) 259.86,38.62 259.86,38.26 258.9,37.3 258.9,33.63 257.63,32.36 v2(257.63,32.18)
JTAG_TDI: length 45.8
  TOP w0.102: UE2.A51 265.07,39.71 v2(265.31,39.47) ; RPE7.1 299.07,40.15 299.06,40.13 JDEG1.2 296.01,40.13 v2(295.35,39.47)
  BOTTOM w0.102: v2(265.31,39.47) 264.37,40.41 264.37,42.51 264.89,43.03 265.16,43.03 266.93,44.79 267.31,44.79 v4(269.06,46.54) 269.5,46.99 278.56,46.99 282.8,42.75 282.8,42.61 286.52,38.89 294.76,38.89 v2(295.35,39.47)
JTAG_TDO: length 46
  TOP w0.102: RPE7.4 299.84,38.63 JDEG1.5 296.81,38.63 v2(296,39.45) ; v2(262.88,40.12) 263.19,40.12 263.35,39.96 UE2.B55
  BOTTOM w0.102: v2(296,39.45) 295.56,39.88 294.85,39.88 294.07,39.09 287.64,39.09 283.7,43.03 282.81,43.03 278.65,47.19 269.14,47.19 v4(267.45,45.51) 267.05,45.11 266.89,45.11 265.12,43.34 264.74,43.34 263.95,42.56 263.95,40.65 263.42,40.12 v2(262.88,40.12)
JTAG_TMS: length 43.1
  TOP w0.102: UE2.A53 264.88,40.71 264.93,40.76 v2(265.11,40.76) ; RPE7.2 299.11,39.65 299.1,39.63 JDEG1.3 297.68,39.63 297.43,39.88 297.01,39.88 v2(296.58,39.45)
  BOTTOM w0.102: v2(265.11,40.76) 265.66,41.31 265.66,42.82 v4(266.08,43.25) 266.39,43.56 266.39,43.94 266.88,44.44 267.52,44.44 269.87,46.79 274.71,46.79 278.13,43.37 281.7,43.37 286.39,38.68 295.82,38.68 v2(296.58,39.45)
KB_DET#: length 140.2
  TOP w0.102: JKBTP1.16 244.37,15.6 244.37,15.6 243.91,15.6 242.31,17.2 237.88,17.2 236.67,18.4 236.67,22.66 230.08,29.25 230.08,32.07 229.55,32.6 229.55,34.29 228.86,34.97 228.86,43.87 233.77,48.77 233.77,54.22 v4(234.24,54.7) v2(234.85,55.3)
  IN1 w0.102: v2(234.85,55.3) 230.57,59.58 230.57,65.96 228.91,67.61 228.25,67.61 228,67.87 227.41,67.87 226.77,68.51 218.52,68.51 218.03,68.02 196.63,68.02 193.41,64.79 192.22,64.79 191.17,63.74 191.17,61.78 190.31,60.92 190.31,59.89 190.09,59.68 187.98,59.68 187.81,59.51 187.15,59.51 185.37,57.73 184.27,57.73 182.99,56.45 181.4,56.45 179.97,57.89 175.58,57.89 175.03,57.34 174.62,57.34 v2(174.12,56.83)
  BOTTOM w0.076: UC1.AT3 169.48,53.62 169.78,53.92 169.78,54.4 169.97,54.59 170.32,54.59 170.48,54.75 170.89,54.75 171.14,55 171.72,55 172.69,55.97 173.36,55.97
  BOTTOM w0.102: 173.36,55.97 173.58,55.97 174.12,56.5 v2(174.12,56.83) 174.13,56.83 175.51,58.22 176.72,58.22 177.35,58.85 RPC19.1
LAN_ACTLED_YEL#: length 2.5
  TOP w0.102: QL1.6 281.15,83.11 v1(281.8,83.76) 281.83,83.79 RL14.1
LAN_ACTLED_YEL_R#: length 23.1
  TOP w0.102: RL14.2 283.51,85.21 v4(283.51,87.58) 283.51,89.83 280.27,93.07 273.69,93.07 272.08,94.68 JLOM1.10
LAN_DISABLE#_R: length 28.5
  TOP w0.102: v2(249.79,70.46) v1(249.79,69.42) 249.79,68.72 250.5,68.01 UE3.1 ; RL5.2 251.2,91.05 RL7.2 252.11,89.34 RL9.1 252.11,88.95 v2(251.85,88.68) 251.85,88.55 253.21,87.19 UL1.3
  BOTTOM w0.102: v2(249.79,70.46) 250.29,70.95 250.29,73.25 249.79,73.75 249.79,78.8 250.53,79.54 250.53,86.61 251.85,87.93 v2(251.85,88.68)
LAN_TEST_EN: length 2.2
  TOP w0.102: RL12.1 261.33,85.59 UL1.30
LAN_TX0+: length 3.2
  TOP w0.089: UL1.13 254.43,82.52 253.79,81.88 253.63,81.88 v1(253.33,81.59) 253,81.25 253,80.85 RL21.1
LAN_TX0+L: length 18.9
  TOP w0.089: v2(252.93,77.77) 252.98,77.82 252.98,78.64 RL21.2
  BOTTOM w0.089: TL1.12 265.45,80.59 265.86,80.18 265.86,79.95 265.66,79.74 264.41,79.74 262.97,81.18 257.73,81.18 256.85,80.3 254.35,80.3 253.01,78.95 253.01,77.85 v2(252.93,77.77)
LAN_TX0-: length 3.2
  TOP w0.089: RL22.1 253.79,80.45 253.4,80.85 253.4,81.1 253.61,81.31 253.66,81.35 253.79,81.48 253.95,81.48 254.83,82.36 UL1.14
LAN_TX0-L: length 18.9
  TOP w0.089: RL22.2 253.38,78.62 253.38,77.91 v2(253.51,77.77)
  BOTTOM w0.089: v2(253.51,77.77) 253.4,77.88 253.4,78.79 254.52,79.91 257.02,79.91 257.89,80.78 262.81,80.78 264.25,79.35 265.82,79.35 266.26,79.79 266.26,80.13 266.72,80.59 TL1.11
LAN_TX1+: length 2.8
  TOP w0.089: RL23.1 255.52,80.89 255.52,81.21 255.56,81.25 255.88,81.57 ; v1(255.88,81.57) 255.88,81.57 ; 255.88,81.57 256.01,81.7 256.03,81.72 256.03,82.19 256.03,82.19 UL1.17
LAN_TX1+L: length 21.5
  TOP w0.089: RL23.2 255.51,78.59 255.51,77.91 v2(255.37,77.77)
  BOTTOM w0.089: v2(255.37,77.77) 255.47,77.87 255.47,78.79 255.99,79.31 257.26,79.31 258.14,80.19 262.44,80.19 263.91,78.71 269.76,78.71 270.97,79.92 270.97,80.16 270.53,80.59 TL1.8
LAN_TX1-: length 2.7
  TOP w0.089: UL1.18 256.43,81.56 256.09,81.22 255.92,81.05 255.92,80.79 RL24.1
LAN_TX1-L: length 21.5
  TOP w0.089: RL24.2 255.9,78.67 255.9,77.83 v2(255.96,77.77)
  BOTTOM w0.089: v2(255.96,77.77) 255.86,77.86 255.86,78.63 256.16,78.92 257.43,78.92 258.3,79.79 262.28,79.79 263.75,78.32 269.92,78.32 271.36,79.76 271.36,80.16 271.8,80.59 TL1.7
LAN_TX2+: length 2.8
  TOP w0.089: RL25.1 257.91,80.81 257.91,81.04 v1(257.36,81.59) 257.23,81.72 UL1.20
LAN_TX2+L: length 21.7
  TOP w0.089: v2(257.85,77.68) 257.93,77.76 257.93,78.64 RL25.2
  BOTTOM w0.089: TL1.6 273.07,80.52 273.51,80.08 273.51,79.59 271.59,77.67 263.51,77.67 261.98,79.2 258.72,79.2 258,78.47 258,77.83 v2(257.85,77.68)
LAN_TX2-: length 2.8
  TOP w0.089: RL26.1 258.3,80.88 258.3,81.2 257.62,81.89 257.62,82.2 257.63,82.2 UL1.21
LAN_TX2-L: length 21.7
  TOP w0.089: RL26.2 258.33,78.62 258.33,77.79 v2(258.44,77.68)
  BOTTOM w0.089: v2(258.44,77.68) 258.4,77.72 258.4,78.31 258.89,78.8 261.82,78.8 263.34,77.28 271.75,77.28 273.9,79.43 273.9,80.07 274.34,80.5 TL1.5
LAN_TX3+: length 3.7
  TOP w0.089: UL1.23 258.43,82.81 258.43,82.35 258.97,81.81 259.42,81.81 260.4,80.84 260.4,80.61 260.22,80.44 RL27.1
LAN_TX3+L: length 24.7
  TOP w0.089: RL27.2 260.4,78.66 260.4,77.4 v2(260.3,77.3)
  BOTTOM w0.089: TL1.2 278.15,80.54 278.59,80.11 278.59,79.75 275.5,76.66 263.1,76.66 261.55,78.21 260.79,78.21 260.45,77.86 260.45,77.45 v2(260.3,77.3)
LAN_TX3-: length 3.8
  TOP w0.089: UL1.24 258.83,82.51 259.13,82.21 259.59,82.21 v1(260.13,81.67) 260.79,81 260.79,80.67 261.02,80.44 RL28.1
LAN_TX3-L: length 24.7
  TOP w0.089: RL28.2 260.79,78.61 260.79,77.39 v2(260.89,77.3)
  BOTTOM w0.089: TL1.1 279.42,80.53 278.98,80.09 278.98,79.58 275.66,76.26 262.94,76.26 261.39,77.81 260.96,77.81 260.84,77.7 260.84,77.34 v2(260.89,77.3)
LAN_WAKE#: length 191.5
  TOP w0.102: v2(255.35,41.91) 255.3,41.96 UE2.B27 ; UL1.2 253.19,87.59 252.68,88.1 v2(252.68,88.67) ; RC153.1 171.43,49.78 171.43,51.04 169.57,52.91 v1(169.57,53.47) 169.57,54.11 168.45,55.23 v2(168.45,55.41)
  IN1 w0.102: v2(168.45,55.41) 168.81,55.05 170.05,55.05 170.59,55.59 171.7,55.59 171.99,55.87 174.44,55.87 174.46,55.89 174.47,55.89 175.85,57.28 179.68,57.28 182.64,54.32 183.32,54.32 183.84,53.8 186.27,53.8 186.45,53.97 188.75,53.97 189.25,54.47 197.17,54.47 203.27,48.37 204.86,48.37 210.25,42.98 218.46,42.98 218.93,42.52 225.88,42.52 226.38,43.03 229.05,43.03 229.58,43.56 231.09,43.56 231.76,44.23 231.76,45.01 237.3,50.55 246.56,50.55 247.88,51.87 250.39,51.87 251.41,52.88 256.8,52.88 257.95,51.74 257.95,50.6 258.42,50.12 258.42,48.91 258.68,48.65 258.68,48.04 259.29,47.43 259.29,45.32 256.35,42.38 255.82,42.38 v2(255.35,41.91)
  BOTTOM w0.076: UC1.AN5 167.9,55.41 v2(168.45,55.41)
  BOTTOM w0.102: v2(255.35,41.91) 255.93,42.49 256.12,42.49 256.63,43 257.16,43 257.87,43.71 257.87,44.78 257.62,45.03 257.62,46.97 258.58,47.93 258.58,48.63 258,49.21 258,51.92 257.4,52.52 257.4,55.45 258.73,56.78 258.73,59.77 262.21,63.25 262.21,69.37 259.46,72.12 252.14,72.12 250.2,74.07 250.2,78.54 250.96,79.3 250.96,86.33 252.68,88.05 v2(252.68,88.67)
LANCLK_REQ#: length 159.2
  TOP w0.102: UL1.48 253.93,88.76 v2(253.6,89.09) 253.6,90.37 253.22,90.75 RL4.1
  IN1 w0.102: v2(182.74,65.85) 182.83,65.94 185.39,65.94 191.53,72.08 193.49,72.08 193.76,71.81 216.51,71.81 217.06,72.36 217.55,72.85 228.43,72.85 232.9,68.37 232.9,61.85 239.61,55.14 244.16,55.14 244.57,55.55 247.62,55.55 248.03,55.14 254.78,55.14 255.29,55.65 256.95,55.65 v2(257.81,54.79)
  BOTTOM w0.076: UC1.AD1 171.02,60.53 172.35,60.53 173.16,61.34 173.64,61.34 173.81,61.18 175.32,61.18
  BOTTOM w0.102: 175.32,61.18 180.93,61.18 183.65,63.9 183.65,65.43 183.23,65.85 v2(182.74,65.85) 182.27,65.38 RPC6.6 ; v2(253.6,89.09) 253.6,88.43 v4(251.74,86.56) 251.19,86.01 251.19,79.24 250.43,78.48 250.43,74.12 252.23,72.33 259.58,72.33 262.42,69.49 262.42,63.16 258.94,59.68 258.94,56.69 257.81,55.57 v2(257.81,54.79)
LCD_CBL_DET#: length 93
  TOP w0.076: 175.7,68.92 175.59,68.92 175.27,68.6 173.54,68.6 173.02,69.13 171.52,69.13 171.22,69.43 169.61,69.43 v2(169.08,68.9)
  TOP w0.102: v2(118.73,93.12) 119.64,94.03 v1(122.79,94.03) 166.32,94.03 173.56,86.79 v2(173.56,85.37) ; RPC4.5 175.7,68.92
  IN1 w0.102: v2(169.08,68.9) 168.55,69.43 168.55,70.27 167.68,71.14 167.68,71.66 167.92,71.89 167.92,72.41 167.58,72.75 167.58,74.82 168.65,75.89 168.65,76.5 168.99,76.84 169.61,77.45 169.61,82.49 170.2,83.09 170.2,84.13 172.19,86.12 172.81,86.12 v2(173.56,85.37)
  BOTTOM w0.076: UC1.J3 169.48,68.5 v2(169.08,68.9)
  BOTTOM w0.102: v2(118.73,93.12) 118.73,91.41 118.46,91.14 JEDP1.40
LCD_TST: length 211.3
  TOP w0.102: UE2.A38 257.69,36.74 257.77,36.66 257.77,35.41 256.94,34.58 256.94,32 256.64,31.7 255.66,31.7 254.92,30.95 253.71,30.95 252.11,32.56 250,32.56 249.26,33.3 248.88,33.3 v2(248.37,32.79) ; v2(113.4,95.57) 114.13,94.83 120.08,94.83 v1(120.66,95.41) 121.18,95.94 193.76,95.94 194.19,95.5 v2(194.92,95.5)
  IN1 w0.102: v2(245.65,70.48) 245.24,70.89 241.03,70.89 239.94,71.99 239.94,77.3 237.11,80.13 237.11,82.74 233.96,85.89 233.96,86.25 229.79,90.41 225.44,90.41 224.78,91.07 207.45,91.07 203.16,95.36 202.46,95.36 201.58,96.25 195.67,96.25 v2(194.92,95.5)
  BOTTOM w0.102: v2(245.65,70.48) 245.65,70.47 246.02,70.1 246.02,61.53 246.45,61.1 246.45,59.14 244.92,57.61 244.92,47.77 245.58,47.11 245.58,41.57 246.36,40.78 246.36,35.56 246.87,35.05 246.87,34.65 248.37,33.15 v2(248.37,32.79) ; JEDP1.29 112.96,92.45 113.54,93.03 113.54,93.33 113.4,93.47 v2(113.4,95.57) 113.4,95.96 113.69,96.25 RE20.2
LCD_VCC_TEST_EN: length 215.4
  TOP w0.102: v2(193.62,95.48) 193.43,95.67 121.41,95.67 120.3,94.56 113.76,94.56 113.1,93.9 v1(110.63,93.9) 106.54,93.9 106.3,94.14 DV3.2 ; UE2.A39 258.19,36.7 258.04,36.55 258.04,35.32 257.16,34.44 257.16,31.91 256.72,31.47 255.79,31.47 255.02,30.7 253.61,30.7 252,32.31 249.51,32.31 v2(249.01,32.82)
  IN1 w0.102: v2(193.62,95.48) 194.23,95.48 195.21,96.46 201.66,96.46 202.55,95.57 203.28,95.57 207.57,91.27 224.87,91.27 225.53,90.61 229.88,90.61 234.16,86.33 234.16,85.97 237.31,82.82 237.31,80.21 240.14,77.38 240.14,72.08 241.12,71.09 245.62,71.09 v2(246.24,70.47)
  BOTTOM w0.102: v2(246.24,70.47) 246.24,61.64 246.66,61.23 246.66,59.03 245.12,57.49 245.12,47.85 245.78,47.19 245.78,41.66 246.58,40.86 246.58,35.69 247.08,35.19 247.08,34.75 v2(249.01,32.82)
LED_10_GRN#: length 7.6
  TOP w0.102: v2(283.26,82.72) 283.89,83.36 RL19.1 ; QL2.6 282.45,78.05 283.32,78.93 v2(283.32,80.06)
  IN1 w0.102: v2(283.32,80.06) 283.32,82.66 v2(283.26,82.72)
  BOTTOM w0.102: v1(284.17,79.86) 283.51,79.86 v2(283.32,80.06)
LED_10_GRN_R#: length 13.9
  TOP w0.102: JLOM1.11 278.5,93.3 280.42,93.3 283.89,89.83 v4(283.89,89.34) 283.89,84.7 RL19.2
LED_100_ORG#: length 3.9
  TOP w0.102: QL1.3 282.45,81.08 v1(283.55,82.18) 283.7,82.34 283.7,82.71 RL20.1
LED_100_ORG_R#: length 12.2
  TOP w0.102: RL20.2 284.27,85.21 v4(284.27,85.97) 284.27,89.82 279.42,94.68 JLOM1.13
LED_SATA_DIAG_OUT#: length 55.7
  TOP w0.102: UE3.15 253.94,61.26 253.9,61.21 253.9,58.24 254.94,57.2 v4(256.14,57.2) 257.19,57.2 v2(260.02,60.03) ; DZ4.1 271.16,25.6 271.16,26.13 270.82,26.47 v2(270.82,28.97)
  IN1 w0.102: v2(270.82,28.97) 270.82,38.04 274.18,41.39 274.18,46.26 269.14,51.29 268.11,51.29 265.54,53.87 265.54,55.07 263.2,57.41 262.26,57.41 260.02,59.65 v2(260.02,60.03)
LG_3V:
  vias: v1(221.24,53.12)
LG_5V: length 3.3
  TOP w0.102: v2(216.65,51.61) v1(216.65,52.31)
  IN1 w1.016: 215.88,55.61 215.88,53
  vias: v2(216.58,57) v2(216.59,56.38) v2(217.03,51.16)
LID_CL#: length 76.1
  TOP w0.102: RE26.1 250.68,56.07 249.95,56.81 249.95,57.48 250.47,58 253.62,58 255.66,55.96 257.86,55.96 259.92,58.02 v4(261.49,58.02) v2(263.08,58.02) 263.38,58.32 UZ10.2 ; v2(274.98,19.42) 274.98,17.31 271.43,13.77 270.19,13.77 269.15,12.73 JLED1.7
  IN1 w0.102: v2(263.08,58.02) 263.16,58.02 265.95,55.23 265.95,54.04 268.28,51.7 269.31,51.7 274.61,46.4 274.61,41.25 271.55,38.19 271.55,28.96 271.92,28.59 271.92,22.86 274.43,20.34 274.43,19.96 v2(274.98,19.42)
LID_CL_SIO#: length 18.5
  TOP w0.102: v2(252.77,44.31) 252.86,44.21 UE2.A21 ; CE8.1 RE25.2 RE26.2 251.27,56.08 251.27,56.86 v4(251.47,57.06) 251.48,57.07 v2(252.11,57.07)
  BOTTOM w0.102: v2(252.77,44.31) 252.37,44.7 251.9,44.7 251.5,45.11 251.5,56.14 251.81,56.45 251.81,56.78 v2(252.11,57.07)
LOM_ACTLED_YEL#: length 24.2
  TOP w0.102: v2(280.81,80.26) 281.15,80.6 QL1.1 ; v2(260.47,83.76) 260.24,83.99 UL1.26
  IN1 w0.102: v2(260.47,83.76) 260.47,83.62 262.2,81.89 279.18,81.89 v2(280.81,80.26)
  BOTTOM w0.102: v2(280.81,80.26) 280.81,80.06 v1(280.5,79.76)
LOM_SPD10LED_GRN#: length 28.6
  TOP w0.102: QL2.1 282.45,79.16 v2(282.31,79.02) 280.16,79.02 RL30.2 ; UL1.25 260.06,83.59 260.3,83.35 260.63,83.35 260.87,83.1 UL2.2 261.67,83.1 v2(262.14,82.63)
  IN1 w0.102: v2(282.31,79.02) 282.31,79.41 279.54,82.17 262.6,82.17 v2(262.14,82.63)
  BOTTOM w0.102: v2(262.14,82.63) v1(262.14,82.03)
LOM_SPD100LED_ORG#: length 26.6
  TOP w0.102: UL1.27 260.43,84.39 261.06,83.75 UL2.1 261.59,83.75 v2(262.12,83.22) ; QL1.4 282.45,82.14 282.28,81.97 281.4,81.97 v2(281.21,81.79) 281.07,81.65 RL29.2
  IN1 w0.102: v2(262.12,83.22) 262.87,82.47 280.53,82.47 v2(281.21,81.79)
  BOTTOM w0.102: v2(281.21,81.79) v1(281.8,81.79)
LPC_LAD0: length 154.8
  TOP w0.102: v2(252.97,57.11) 253.49,57.11 v4(253.57,57.04) ; v2(252.59,36.96) 252.02,37.53 252.02,38.54 253.19,39.71 UE2.A30 ; JLPDE1.3 271.56,59.47 272.42,58.61 v2(272.42,57.01)
  IN1 w0.102: v2(252.59,36.96) 252.23,36.6 245.14,36.6 244.72,37.02 241.5,37.02 240.94,36.46 236.95,36.46 235.36,34.87 224.51,34.87 221.36,31.72 214.05,31.72 208.32,37.45 207.2,37.45 201.38,43.27 199.83,44.82 199.83,45.23 199.15,45.91 196.86,45.91 195.52,44.57 173.97,44.57 172.86,45.68 168.82,45.68 167.8,46.7 167.14,46.7 166.5,47.33 166.08,47.33 165.29,48.11 v2(164.89,48.11)
  IN2 w0.102: v2(272.42,57.01) 272.12,56.72 269.35,56.72 268.77,57.3 262.93,57.3 261.92,58.32 254.84,58.32 253.63,57.11 v2(252.97,57.11)
  BOTTOM w0.076: v2(164.89,48.11) 164.89,48.15 164.39,48.66 164.39,48.88 163.37,49.9 163.37,51.47 163.26,51.57 163.26,52.52 UC1.AU14
  BOTTOM w0.102: v2(252.97,57.11) 252.77,57.11 251.7,56.04 251.7,48.56 252.55,47.71 252.55,46.01 253.45,45.11 253.45,42.45 253.71,42.2 253.71,39.53 252.18,38.01 252.18,37.36 v2(252.59,36.96)
LPC_LAD1: length 149.7
  TOP w0.102: v2(254.95,39.21) 254.7,39.46 UE2.B32 ; JLPDE1.4 272.06,60.49 271.87,60.68 271.87,61.53 271.45,61.95 v1(271.45,63.4) v2(271.45,63.93)
  IN1 w0.102: v2(254.95,39.21) 253.03,39.21 251.83,38.01 241.67,38.01 240.69,37.03 236.88,37.03 236.78,36.93 236.78,36.93 235.18,35.33 224.36,35.33 221.39,32.36 213.99,32.36 208.49,37.86 207.36,37.86 201.55,43.68 200.24,44.98 200.24,45.4 198.92,46.72 189.32,46.72 187.57,44.98 174.14,44.98 173.03,46.09 168.93,46.09 167.96,47.06 167.29,47.06 166.56,47.8 166.4,47.8 164.91,49.28 v2(164.89,49.28)
  IN2 w0.102: v2(259.65,63.93) 259.85,64.13 271.24,64.13 v2(271.45,63.93)
  BOTTOM w0.076: UC1.AW12 163.66,51.27 163.95,50.98 163.95,50.01 164.68,49.28 v2(164.89,49.28)
  BOTTOM w0.102: v2(254.95,39.21) 254.54,39.62 254.54,42.52 254.29,42.76 254.29,47.17 253.24,48.22 253.24,52.37 252.87,52.74 252.87,54.38 254.7,56.21 254.7,56.69 255.18,57.17 255.18,59.45 259.65,63.92 v2(259.65,63.93)
LPC_LAD2: length 152.4
  TOP w0.102: UE2.A31 253.3,39.21 252.53,38.44 252.53,37.61 v2(252.59,37.55) ; JLPDE1.5 272.56,60.45 272.32,60.68 v1(272.32,61.44) 272.32,61.75 271.85,62.22 271.85,63.75 v2(272.04,63.94)
  IN1 w0.102: v2(252.59,37.55) 251.84,36.8 245.23,36.8 244.8,37.22 241.42,37.22 240.87,36.68 236.87,36.68 235.27,35.08 224.4,35.08 221.25,31.93 214.13,31.93 208.4,37.65 207.28,37.65 201.46,43.47 200.04,44.9 200.04,45.32 199.22,46.13 196.8,46.13 195.43,44.77 174.05,44.77 172.94,45.88 168.88,45.88 167.88,46.88 167.21,46.88 166.56,47.54 166.25,47.54 165.05,48.74 v2(164.89,48.74)
  IN2 w0.102: v2(259.04,63.96) 259.43,64.35 271.64,64.35 v2(272.04,63.94)
  BOTTOM w0.076: v2(164.89,48.74) 164.85,48.74 163.66,49.92 UC1.AY12
  BOTTOM w0.102: v2(259.04,63.96) 259.04,63.68 255.34,59.98 255.08,59.98 253.43,58.33 253.43,56.97 253.12,56.67 252.61,56.67 251.9,55.96 251.9,48.67 253.65,46.91 253.65,42.54 253.91,42.28 253.91,39.33 252.59,38.01 v2(252.59,37.55)
LPC_LAD3: length 153.2
  TOP w0.102: v2(259.69,63.32) v1(259.69,62.34) ; JLPDE1.6 273.06,60.49 272.71,60.84 272.71,61.91 272.25,62.38 272.25,63.47 v2(272.72,63.94) ; UE2.B33 254.63,38.96 254.88,38.71 255.04,38.71 v2(255.55,39.21)
  IN1 w0.102: v2(255.55,39.21) 255.06,39.7 252.92,39.7 251.43,38.21 241.32,38.21 240.55,37.45 237.01,37.45 235.1,35.53 224.28,35.53 221.31,32.56 214.07,32.56 208.57,38.06 207.45,38.06 201.63,43.88 200.44,45.07 200.44,45.48 198.95,46.98 189.28,46.98 187.48,45.18 174.22,45.18 173.11,46.29 168.99,46.29 168.03,47.25 167.44,47.25 164.87,49.82 v2(164.87,49.83)
  IN2 w0.102: v2(259.69,63.32) 260.27,63.91 270.77,63.91 271.18,63.5 272.27,63.5 v2(272.72,63.94)
  BOTTOM w0.076: v2(164.87,49.83) 164.87,50.26 164.7,50.42 164.7,50.76 164.71,50.76 164.71,51 164.7,51 164.7,51.04 164.41,51.33 UC1.AW11
  BOTTOM w0.102: v2(259.69,63.32) 259.69,63.31 256.23,59.85 255.97,59.85 255.39,59.28 255.39,57.1 254.93,56.64 254.93,56.11 253.1,54.27 253.1,52.83 253.44,52.49 253.44,48.31 254.49,47.25 254.49,42.85 254.74,42.6 254.74,40.01 v2(255.55,39.21)
LPC_LFRAME#: length 150.4
  TOP w0.102: v1(261.22,63.32) v2(260.3,63.32) ; v2(272.7,63.16) 272.7,62.5 273.1,62.1 273.1,60.9 273.56,60.44 JLPDE1.7 ; v2(255.39,40.04) 254.96,40.04 254.88,39.96 UE2.B31
  IN1 w0.102: v2(163.98,51.87) 163.98,51.64 164.72,50.9 164.72,50.56 165.33,49.95 165.33,49.62 167.52,47.43 168.11,47.43 168.65,46.89 173.39,46.89 174.28,46 176.31,46 176.92,45.39 187.4,45.39 189.2,47.19 199.02,47.19 200.64,45.57 200.64,45.15 201.72,44.08 207.53,38.26 208.66,38.26 213.88,33.04 221.5,33.04 224.22,35.76 235.04,35.76 236.92,37.65 240.47,37.65 241.49,38.67 251.48,38.67 252.86,40.04 v2(255.39,40.04)
  IN2 w0.102: v2(260.3,63.32) 260.68,63.7 270.66,63.7 271.21,63.16 v2(272.7,63.16)
  BOTTOM w0.076: UC1.AV12 163.66,52.18 v2(163.98,51.87)
  BOTTOM w0.102: v2(260.3,63.32) 256.24,59.26 256.24,54.24 255.05,53.06 254.21,53.06 253.64,52.49 253.64,48.4 254.72,47.32 254.72,42.91 254.95,42.68 254.95,40.49 v2(255.39,40.04)
M_CLK_DDR0: length 77.1
  IN2 w0.086: v2(149.03,48.8) 148.98,48.75 148.98,48.58 149.06,48.5 149.18,48.5 149.22,48.46 149.41,48.46 149.67,48.21 149.67,48.06 149.66,48.05 149.66,46.55 147.48,44.37 147.48,42.51 147.29,42.32 147.29,38.2 146.74,37.65 146.74,37.5 147.26,36.99 147.26,36.66 146.97,36.37 146.64,36.37 146.11,36.91 145.98,36.91 145.76,36.68 145.76,36.56 146.4,35.92 146.4,35.65 146.07,35.32 145.81,35.32 145.16,35.97 145.04,35.97 144.81,35.74 144.81,35.62 145.46,34.97 145.46,34.7 145.13,34.37 144.86,34.37 144.22,35.02 144.09,35.02 143.87,34.79 143.87,34.67 144.51,34.03 144.51,33.76 144.18,33.43 143.92,33.43 143.3,34.05 143.12,34.05 142.95,33.88 142.95,33.7 143.51,33.14 143.51,32.77 143.25,32.51 142.99,32.51 142.35,33.15 142.22,33.15 142,32.92 142,32.8 142.64,32.16 142.64,31.9 142.27,31.53 142,31.53 141.82,31.7 141.64,31.7 141.48,31.53 141.48,31.35 141.65,31.18 141.65,30.91 132.5,21.75 113.72,21.75 112.26,20.3 111.95,20.3 111.93,20.28 111.84,20.28 111.77,20.21 v2(111.77,19.91)
  BOTTOM w0.076: v2(149.03,48.8) 149.03,48.66 148.84,48.47 148.44,48.47 148.07,48.84 148.07,51.89 UC1.AV37
  BOTTOM w0.102: JDIMM1.101 111.4,17.42 111.61,17.63 111.61,17.97 112.3,18.67 112.3,20.04 112.13,20.22 111.87,20.22 111.77,20.12 v2(111.77,19.91)
M_CLK_DDR1: length 75.3
  IN2 w0.086: v2(148.79,50.55) 148.96,50.72 149.31,50.72 149.5,50.53 149.5,48.84 149.51,48.84 149.92,48.44 149.92,46.19 149.91,46.19 147.93,44.2 147.93,42.43 147.8,42.3 147.8,36.34 132.72,21.26 114.34,21.26 113.56,20.48 113.56,19.97 113.47,19.88 112.52,19.88 112.29,19.65 112.29,19.27 112.52,19.04 113.47,19.04 113.56,18.95 113.56,18.63 113.47,18.54 112.79,18.54 112.56,18.31 112.56,17.93 112.79,17.7 113.47,17.7 113.56,17.61 113.56,12.14 113.38,11.96 113.1,11.96 113.08,11.94 112.96,11.94 112.9,12 v2(112.9,12.28)
  BOTTOM w0.076: UC1.AY36 149.11,50.88 v2(148.79,50.55)
  BOTTOM w0.102: JDIMM1.102 111.7,9.25 111.89,9.44 111.89,10.44 112.15,10.69 112.15,11.66 112.46,11.97 112.7,11.97 112.9,12.18 v2(112.9,12.28)
M_CLK_DDR2: length 89.7
  IN1 w0.086: v2(192.96,19.79) 192.96,20.05 193.02,20.12 193.5,20.12 193.52,20.09 193.52,19.43 193.75,19.2 194.13,19.2 194.36,19.43 194.36,20.97 193.22,22.11 192.86,22.11 192.49,21.74 192.31,21.74 192.06,21.99 192.06,22.17 192.46,22.56 192.46,22.88 192.18,23.15 191.86,23.15 191.44,22.73 191.31,22.73 190.82,23.23 163.69,23.23 163.61,23.31 163.61,23.8 163.38,24.03 162.99,24.03 162.76,23.8 162.76,23.31 162.68,23.23 162.36,23.23 162.27,23.31 162.27,23.84 162.08,24.03 161.62,24.03 161.43,23.84 161.43,23.31 161.34,23.23 161.02,23.23 160.94,23.31 160.94,23.84 160.75,24.03 160.28,24.03 160.09,23.84 160.09,23.31 160.01,23.23 159.69,23.23 159.6,23.31 159.6,23.84 159.41,24.03 158.85,24.03 146.31,36.56 146.31,42.61 146.87,43.16 146.87,47.09 147.24,47.46 147.24,48.82 146.82,49.24 146.82,52.73 147.3,53.21 147.3,55.11 147.4,55.21 147.52,55.21 v2(147.76,54.96)
  BOTTOM w0.076: v2(147.76,54.96) 148.08,55.29 UC1.AN38
  BOTTOM w0.102: v2(192.96,19.79) 192.96,20.04 193.07,20.16 193.45,20.16 193.6,20.02 193.6,18.48 193.13,18.01 193.13,17.63 192.9,17.4 JDIMM2.101
M_CLK_DDR3: length 91.3
  IN1 w0.086: v2(147.76,56.27) 147.76,56.48 147.67,56.57 146.89,56.57 146.8,56.47 146.8,53.43 146.17,52.81 146.17,43.38 145.54,42.75 145.54,36.15 159.13,22.56 190.55,22.56 192.02,21.08 192.02,16.79 194.18,14.63 194.18,13.32 193.75,12.89 193.75,11.32 193.81,11.26 194.12,11.26 194.28,11.42 v2(194.28,11.57)
  BOTTOM w0.076: UC1.AL38 148.08,56.59 v2(147.76,56.27)
  BOTTOM w0.102: JDIMM2.102 193.2,9.25 193.39,9.44 193.39,9.99 193.18,10.21 193.18,10.97 193.43,11.23 194.12,11.23 194.28,11.38 v2(194.28,11.57)
M_CLK_DDR#0: length 77.1
  IN2 w0.086: v2(149.03,48.15) 149.17,48.29 149.34,48.29 149.49,48.14 149.49,46.62 147.31,44.44 147.31,42.58 147.12,42.39 147.12,38.27 146.57,37.73 146.57,37.43 147.08,36.91 147.08,36.73 146.9,36.55 146.72,36.55 146.18,37.09 145.91,37.09 145.58,36.76 145.58,36.49 146.23,35.84 146.23,35.72 146,35.49 145.88,35.49 145.23,36.14 144.97,36.14 144.64,35.81 144.64,35.54 145.28,34.9 145.28,34.78 145.06,34.55 144.93,34.55 144.29,35.2 144.02,35.2 143.69,34.87 143.69,34.6 144.34,33.95 144.34,33.83 144.11,33.6 143.99,33.6 143.37,34.22 143.05,34.22 142.77,33.95 142.77,33.62 143.33,33.07 143.33,32.84 143.18,32.69 143.06,32.69 142.42,33.33 142.15,33.33 141.82,33 141.82,32.73 142.46,32.09 142.46,31.97 142.2,31.7 142.07,31.7 141.9,31.88 141.57,31.88 141.3,31.61 141.3,31.28 141.48,31.1 141.48,30.98 132.42,21.93 113.65,21.93 112.19,20.47 111.91,20.47 111.77,20.61 v2(111.77,20.68)
  BOTTOM w0.076: UC1.AU37 148.31,52.54 148.07,52.3 148.07,52.12 147.9,51.95 147.9,48.78 148.37,48.3 148.86,48.3 149.02,48.15 v2(149.03,48.15)
  BOTTOM w0.102: v2(111.77,20.68) 112.01,20.43 112.22,20.43 112.52,20.13 112.52,18.58 111.82,17.88 111.82,17.68 112,17.5 JDIMM1.103
M_CLK_DDR#1: length 75.3
  IN2 w0.086: v2(112.9,11.52) 112.91,11.52 113.18,11.79 113.45,11.79 113.73,12.07 113.73,17.69 113.54,17.88 112.86,17.88 112.74,18 112.74,18.24 112.86,18.37 113.54,18.37 113.73,18.56 113.73,19.02 113.54,19.21 112.6,19.21 112.47,19.34 112.47,19.58 112.6,19.7 113.54,19.7 113.73,19.89 113.73,20.41 114.41,21.09 132.79,21.09 147.98,36.27 147.98,42.22 148.1,42.35 148.1,44.13 149.99,46.01 149.99,46.01 150.1,46.12 150.1,48.51 149.68,48.93 149.68,50.61 149.38,50.9 149,50.9 148.79,51.11 v2(148.79,51.2)
  BOTTOM w0.076: v2(148.79,51.2) 149.11,51.53 UC1.AW36
  BOTTOM w0.102: JDIMM1.104 112.3,9.25 112.11,9.44 112.11,10.35 112.36,10.6 112.36,11.57 112.55,11.76 112.66,11.76 v2(112.9,11.52)
M_CLK_DDR#2: length 89.8
  IN1 w0.086: v2(192.96,20.55) 192.96,20.42 193.09,20.29 193.57,20.29 193.7,20.16 193.7,19.51 193.82,19.38 194.06,19.38 194.18,19.51 194.18,20.89 193.14,21.93 192.93,21.93 192.56,21.56 192.24,21.56 191.89,21.91 191.89,22.24 192.28,22.63 192.28,22.81 192.11,22.98 191.93,22.98 191.51,22.56 191.24,22.56 190.75,23.05 163.62,23.05 163.43,23.24 163.43,23.72 163.31,23.85 163.07,23.85 162.94,23.72 162.94,23.24 162.75,23.05 162.29,23.05 162.1,23.24 162.1,23.76 162.01,23.85 161.69,23.85 161.6,23.76 161.6,23.24 161.41,23.05 160.95,23.05 160.76,23.24 160.76,23.76 160.67,23.85 160.35,23.85 160.27,23.76 160.27,23.24 160.08,23.05 159.61,23.05 159.42,23.24 159.42,23.76 159.34,23.85 158.78,23.85 146.14,36.49 146.14,42.68 146.7,43.24 146.7,47.16 147.07,47.53 147.07,48.75 146.64,49.17 146.64,52.8 147.13,53.28 147.13,55.19 147.32,55.38 147.52,55.38 147.75,55.62 v2(147.76,55.62)
  BOTTOM w0.076: v2(147.76,55.62) 148.08,55.94 UC1.AM38
  BOTTOM w0.102: JDIMM2.103 193.5,17.5 193.34,17.66 193.34,17.92 193.81,18.39 193.81,20.11 193.54,20.38 193.07,20.38 192.96,20.49 v2(192.96,20.55)
M_CLK_DDR#3: length 91.2
  IN1 w0.086: v2(147.76,56.92) 147.58,56.74 146.82,56.74 146.62,56.54 146.62,53.5 146,52.88 146,43.46 145.36,42.82 145.36,36.08 159.06,22.38 190.47,22.38 191.85,21.01 191.85,16.72 194.01,14.56 194.01,13.39 193.57,12.96 193.57,11.25 193.73,11.09 194.11,11.09 194.28,10.93 v2(194.28,10.81)
  BOTTOM w0.076: UC1.AK38 148.08,57.24 v2(147.76,56.92)
  BOTTOM w0.102: v2(194.28,10.81) 194.28,10.91 194.18,11.01 193.52,11.01 193.39,10.88 193.39,10.3 193.61,10.08 193.61,9.44 193.8,9.25 JDIMM2.104
M_ODT0: length 4.6
  TOP w0.102: RD10.2 v1(117.76,11.73)
  TOP w0.152: RD10.2 117.24,10.62 v2(117.06,10.44)
  BOTTOM w0.152: JDIMM1.116 115.9,9.28 v2(117.06,10.44)
M_ODT1: length 3.2
  TOP w0.102: v1(116.44,10.43) 116.48,10.39 116.48,10.39 v2(117.06,9.81)
  TOP w0.152: RD11.2 117.13,9.74 v2(117.06,9.81)
  BOTTOM w0.152: v2(117.06,9.81) 117.1,9.77 JDIMM1.120
M_ODT2: length 4.7
  TOP w0.152: v2(197.28,6.61) 198.76,8.09 RD12.2
  BOTTOM w0.152: v2(197.28,6.61) 197.4,6.73 JDIMM2.116
M_ODT3: length 3
  TOP w0.152: RD13.2 199.21,7.2 v2(198.61,6.6)
  BOTTOM w0.152: v2(198.61,6.6) 198.6,6.61 JDIMM2.120
MASK_BASE_LEDS#: length 38.5
  TOP w0.102: v2(266.35,58.81) 265.5,58.81 v1(265.49,58.8) 264.25,57.56 263,57.56 262.73,57.29 UZ10.4 ; v2(281.71,78.6) 282.48,78.6 282.86,78.98 282.86,80.33 283.23,80.7 283.23,81.24 283.89,81.9 286.03,81.9 286.16,81.77 QZ7.5
  IN1 w0.102: v2(281.71,78.6) 281.71,78.12 269.17,65.59 v2(268.95,65.59)
  BOTTOM w0.102: v2(268.95,65.59) 266.35,62.99 v2(266.35,58.81)
MASK_SATA_LED#: length 58
  TOP w0.102: QZ3.5 273.78,18.45 v2(274.11,18.78) ; v2(258.19,63.96) 257.64,64.51 UE3.23
  IN1 w0.102: v2(258.19,63.96) 258.19,62.53 260.45,60.27 260.45,59.5 262.34,57.61 263.28,57.61 265.74,55.15 265.74,53.95 268.2,51.5 269.22,51.5 274.41,46.32 274.41,41.33 271.35,38.27 271.35,28.87 271.71,28.5 271.71,22.72 274.11,20.32 v2(274.11,18.78)
  BOTTOM w0.102: v2(258.19,63.96) v1(258.19,64.49)
MCARD_PCIE#_SATA: length 17.1
  TOP w0.102: UE2.B8 259.44,46.78 259.27,46.61 259.27,46.02 258.97,45.73 v2(258.85,45.73) ; RE91.1 257.34,55.32 257.6,55.32 258.38,56.1 v1(259.09,56.1) v2(259.71,56.1)
  BOTTOM w0.102: v2(258.85,45.73) 259.27,46.14 259.27,47.4 260.06,48.18 260.06,53.72 259.65,54.13 258.99,54.13 258.68,54.43 258.68,55.07 v2(259.71,56.1)
MCARD_PCIE#_SATA_R: length 106
  TOP w0.102: v2(255.37,55.03) 255.43,54.97 RE91.2
  IN1 w0.102: v2(255.37,55.03) 255.2,54.86 247.89,54.86 247.42,55.33 244.69,55.33 244.22,54.86 238.74,54.86 232.7,60.91 232.7,68.29 228.35,72.64 217.63,72.64 217.26,72.27 216.59,71.6 193.68,71.6 193.4,71.88 191.62,71.88 185.47,65.74 183.9,65.74 v2(183.17,65.01)
  BOTTOM w0.076: 175.32,61.38 174.8,61.38 174.18,62 172.62,62 171.66,61.04 UC1.AC1
  BOTTOM w0.102: RPC6.7 181.77,64.88 181.9,65.01 v2(183.17,65.01) 183.31,64.87 v1(183.31,64.25) 183.31,63.89 180.8,61.38 175.32,61.38
MCP_TESTLOW1: length 9.8
  BOTTOM w0.076: UC1.C35 149.61,72.48 149.51,72.63 149.47,72.79 149.47,72.97 149.48,73 149.49,73 149.53,73.13 149.53,73.23 149.47,73.4 149.47,73.4 149.41,73.46 149.41,73.46 149.41,73.49 148.9,73.99 148.9,75.06 149.2,75.36 149.2,76.09 148.98,76.3
  BOTTOM w0.102: 148.98,76.3 v3(148.52,76.76) 146.92,78.36 146.92,80.07 RC240.1
MCP_TESTLOW2: length 10.4
  BOTTOM w0.076: UC1.C34 150.22,72.33 150.05,72.5 149.87,72.5 149.67,72.71 149.64,72.81 149.64,72.94 149.66,73 149.67,73.01 149.67,73.01 149.7,73.1 149.7,73.26 149.61,73.5 149.61,73.57 149.11,74.08 149.11,74.98 149.4,75.27 149.4,76.21 149.3,76.3
  BOTTOM w0.102: RC241.1 147.15,80.07 v3(147.15,79.02) 147.15,78.45 149.3,76.3
MCP_TESTLOW3: length 12.5
  TOP w0.102: RC242.1 165.73,47.89 165.73,50.13 164.56,51.29 v1(164.56,52.02) 164.56,56.24 165.53,57.2 v2(166.01,57.2)
  BOTTOM w0.076: UC1.AK8 166.15,57.06 v2(166.01,57.2)
MCP_TESTLOW4: length 10.9
  TOP w0.102: v2(166.03,56.27) 165.01,55.24 165.01,51.26 v1(166.18,50.09) 166.18,47.38 RC243.1
  BOTTOM w0.076: v2(166.03,56.27) 166.17,56.41 UC1.AL8
MDP_AUX#_C: length 16.1
  IN2 w0.086: v2(289.32,71.58) 289.11,71.37 289.11,71.08 288.85,70.81 288.61,70.81 288.47,70.67 288.47,70.48 v2(288.69,70.26)
  BOTTOM w0.102: v2(288.69,70.26) 288.6,70.34 288.6,70.88 288.2,71.28 288.2,71.55 287.82,71.93 287.56,71.93 RV501.2 287.12,72.16 286.62,72.66 UV502.8 284.36,72.66 283.06,71.36 282.2,71.36 281.55,72.01 UV502.6 ; JMDP1.18 289.92,72.45 289.8,72.57 289.8,72.69 289.74,72.76 289.53,72.76 289,72.22 289,71.89 v2(289.32,71.58)
MDP_AUX_C: length 16
  IN2 w0.086: v2(288.07,70.26) 288.29,70.47 288.29,70.74 288.54,70.99 288.77,70.99 288.94,71.15 288.94,71.37 v2(288.73,71.58)
  BOTTOM w0.102: v2(288.73,71.58) 288.78,71.63 288.78,72.31 289.44,72.97 289.77,72.97 289.85,73.05 JMDP1.16 ; UV502.3 281.2,70.06 282.28,71.14 283,71.14 283.43,70.71 UV502.11 286.75,70.71 RV502.2 287.33,71.58 287.47,71.72 287.73,71.72 287.98,71.46 287.98,71.19 288.39,70.79 288.39,70.57 v2(288.07,70.26)
MDP_CA_DET: length 21.2
  IN1 w0.102: v2(284.64,77.47) 283.12,77.47 280.79,75.15 280.79,71.11 v2(281.19,70.71)
  IN2 w0.102: v2(281.19,69.13) v2(281.19,70.71)
  BOTTOM w0.102: v2(281.19,69.13) 280.83,68.76 UV502.1 ; QV502.2 284.45,77.66 v2(284.64,77.47) 284.68,77.43 v1(285.3,77.43) 286.84,77.43 RV504.1 287.62,76.65 JMDP1.4 ; UV502.4 v2(281.19,70.71)
MDP_CA_DET#: length 13.5
  IN2 w0.102: v2(284.59,69.44) v2(284.59,71.25) 284.02,71.82 283.64,71.82 282.69,72.77 v2(282.69,73.65)
  BOTTOM w0.102: v2(282.69,73.65) 281.86,74.47 RV507.2 280.48,76.06 v1(280.65,76.24) 281.43,77.01 QV502.1 ; v2(284.59,71.25) 284.71,71.36 UV502.10 ; v2(284.59,69.44) 284.62,69.41 UV502.13
MDP_HPD: length 5.5
  BOTTOM w0.102: QV501.1 287.35,78.13 RV505.2 v1(288.52,77.94) 289.21,77.25 JMDP1.2
MDP_LANE_N0_C: length 6.2
  TOP w0.102: CV508.1 289.02,76.13 289.23,76.13 289.53,76.43 290.05,76.43 290.07,76.44 290.39,76.44 290.49,76.34 290.49,75.73 290.75,75.48 291.18,75.48 291.45,75.74 v3(291.45,76.01) 291.45,76.35 291.53,76.44 292.56,76.44 JMDP1.5
MDP_LANE_N1_C: length 6.6
  TOP w0.102: JMDP1.11 294.6,74.4 292.46,74.4 292.45,74.39 291.92,74.39 291.91,74.4 v3(289.9,74.4) 289.07,74.4 CV506.1
MDP_LANE_N2_C: length 4.6
  TOP w0.102: CV504.1 289.02,72.57 289.12,72.57 289.26,72.43 v3(289.82,72.43) 291.09,72.43 291.11,72.42 291.68,72.42 291.69,72.43 292.57,72.43 JMDP1.17
MDP_LANE_N3_C: length 4.6
  BOTTOM w0.102: CV502.1 287.7,74.37 287.99,74.37 288.1,74.27 288.1,74.05 288.35,73.8 v3(288.62,73.8) 288.95,73.8 289.2,74.05 289.2,74.27 289.3,74.37 289.75,74.37 289.87,74.25 JMDP1.12
MDP_LANE_P0_C: length 6.2
  TOP w0.102: JMDP1.3 292.56,76.66 291.45,76.66 291.22,76.43 291.22,75.82 291.09,75.69 290.84,75.69 290.71,75.82 290.71,76.43 290.48,76.66 v3(289.74,76.66) 289.45,76.66 289.14,76.35 289.02,76.35 CV507.1
MDP_LANE_P1_C: length 6.6
  TOP w0.102: CV505.1 288.97,74.62 289.61,74.62 289.62,74.63 290.17,74.63 290.18,74.62 v3(292.19,74.62) 294.52,74.62 JMDP1.9
MDP_LANE_P2_C: length 4.6
  TOP w0.102: JMDP1.15 292.54,72.65 v3(291.41,72.65) 290.1,72.65 290.09,72.66 289.56,72.66 289.55,72.65 289.35,72.65 289.21,72.79 289.02,72.79 CV503.1
MDP_LANE_P3_C: length 4.6
  BOTTOM w0.102: JMDP1.10 289.9,74.85 289.63,74.59 289.21,74.59 288.99,74.36 288.99,74.14 288.87,74.03 288.43,74.03 288.31,74.14 288.31,74.36 288.08,74.59 287.65,74.59 CV501.1
ME_FWP: length 157.9
  TOP w0.102: v2(231.34,13.93) v4(229.51,13.93) 228.08,13.93 215.62,26.39 215.62,26.57 208.54,33.65 193.31,33.65 190.59,30.92 175.13,30.92 169.09,36.96 169.09,38.87 165.8,42.17 RC11.1
  IN1 w0.102: v2(231.34,13.93) 231.34,15.66 231.72,16.04 239.09,16.04 241.01,14.12 241.01,12.46 242.24,11.23 249.84,11.23 251.61,12.99 251.61,14.48 253.44,16.31 v2(253.44,16.6)
  BOTTOM w0.102: SW1.3 293.13,7.32 291.35,9.11 289.81,9.11 RC301.1 283.96,14.96 275.47,14.96 274.05,16.38 266.34,16.38 265.52,15.56 261.91,15.56 260.77,16.7 253.54,16.7 v2(253.44,16.6)
ME_FWP_EC: length 75.3
  TOP w0.102: UE2.B46 260.44,38.51 v2(260.42,38.52) ; v4(253.98,17.26) 253.97,17.25 v2(253.41,17.25)
  IN1 w0.102: v2(260.42,38.52) 259.11,37.21 259.11,32.36 254.9,28.16 254.9,25.92 254.02,25.04 254.02,19.2 253.41,18.59 v2(253.41,17.25)
  BOTTOM w0.102: v2(253.41,17.25) 253.48,17.18 260.98,17.18 262.13,16.04 265.32,16.04 266.14,16.87 274.3,16.87 275.73,15.44 284.39,15.44 RC301.2 291.26,11.09 293.77,8.57 296.3,8.57 297.13,7.74 SW1.1
ME_RESET#: length 3.4
  TOP w0.102: v1(184.72,76.02) 184.72,76.02 RC80.1 ; RC80.1 184.58,74.9 UC4.2 ; RC80.1 RC95.2
ME_SUS_PWR_ACK: length 115.7
  TOP w0.102: v2(259.35,51.8) 259.62,51.53 259.62,51.23 259.86,50.99 259.86,49.08 259.76,48.98 259.76,48.74 259.19,48.17 UE2.A8 ; v2(171.04,50.59) 170.42,49.97 v1(170.42,49.08) 170.42,48.16 171.24,47.33 RC79.2
  IN1 w0.076: 173.36,51.21 173.15,51.42 v2(172.29,51.42) 171.87,51.42 v2(171.04,50.59)
  IN1 w0.102: 173.36,51.21 175.36,49.21 179.28,49.21 181.42,51.35 189.77,51.35 190.19,51.76 196.86,51.76 202.35,46.27 202.35,45.89 206.12,42.13 207.77,42.13 209.51,40.39 217.62,40.39 217.82,40.18 230.44,40.18 232.6,42.34 v2(232.6,44.97)
  IN2 w0.102: v2(232.6,44.97) 233.39,45.76 233.71,45.76 237.64,49.7 243.06,49.7 246.33,52.97 251.15,52.97 251.36,53.17 253.04,53.17 253.21,53.01 257.62,53.01 258.82,51.8 v2(259.35,51.8)
  BOTTOM w0.076: v2(172.29,51.42) 171.84,51.87 169.14,51.87 UC1.AV4
MEC_XTAL1: length 5.9
  TOP w0.102: UE2.A61 264.83,44.71 265.06,44.94 v1(266.23,44.94) CE28.1 268.1,44.94 268.45,45.29 269.07,45.29 269.35,45.01 YE1.1
MEC_XTAL2: length 3
  TOP w0.102: RE61.2 CE29.1 268.06,45.82 269.13,46.89 YE1.2
MEC_XTAL2_R: length 3.1
  TOP w0.102: UE2.A62 264.9,45.21 265.24,45.55 265.63,45.55 RE61.1
MEDIACARD_IRQ#: length 173.3
  TOP w0.102: v2(185.13,62.11) 185.13,62.1 184.72,61.7 184.72,60.17 184.41,59.86 RPC5.6 183.81,59.86 183.05,59.1 181.38,59.1 180.55,59.92 180.55,60.53 179.26,61.82 176.68,61.82 176.38,62.13 v1(173.71,62.13) 172.21,62.13 171.59,61.51 170.69,61.51 170.41,61.78 168.87,61.78 168.59,61.51 168.19,61.51 v2(167.75,61.94) ; v2(283.74,26.43) 283.56,26.61 283.56,27.19 283.72,27.34 UR1.16
  IN1 w0.102: v2(185.13,62.11) 185.18,62.11 186.84,63.76 186.84,64.63 191.92,69.71 193.01,69.71 193.99,70.69 216.97,70.69 218.01,71.73 227.35,71.73 231.99,67.09 231.99,60.61 238.76,53.83 242.76,53.83 243.11,54.19 246.11,54.19 246.5,54.58 256,54.58 256.37,54.22 258.54,54.22 v2(259.1,54.77) ; v2(283.74,26.43) 284.11,26.43 284.99,27.3 287.06,27.3 287.73,27.98 287.73,33.1 287.06,33.76 287.06,38.36 279.48,45.94 279.48,50.08 275.3,54.25 273.62,54.25 270.17,57.71 270.17,59.08 v2(269.5,59.74)
  IN2 w0.102: v2(262.23,59.89) 262.6,60.27 268.98,60.27 v2(269.5,59.74)
  BOTTOM w0.076: v2(167.75,61.94) 167.5,61.69 UC1.AB6
  BOTTOM w0.102: v2(259.1,54.77) 260.12,55.79 260.12,56.43 261.71,58.01 261.71,59.37 v2(262.23,59.89)
MEDIACARD_PWREN: length 1.6
  TOP w0.102: UR1.14 282.92,27.33 282.71,27.13 RR15.2
MEDIACARD_RST#: length 19.2
  TOP w0.076: v2(167.8,59.09) 167.8,58.9 v1(167.49,58.58)
  TOP w0.102: RPC5.7 183.88,59.36 183.42,58.9 v2(183.42,58.75)
  IN1 w0.102: v2(167.8,59.09) 168.13,58.75 168.74,58.75 168.83,58.84 170.28,58.84 170.88,58.24 171.91,58.24 172.15,58.48 173.02,58.48 173.14,58.36 174.61,58.36 175.16,58.9 180.68,58.9 181.34,58.24 182.94,58.24 183.42,58.73 v2(183.42,58.75)
  BOTTOM w0.076: v2(167.8,59.09) 167.8,58.89 167.5,58.6 UC1.AG6
MEM_SMBCLK: length 35.5
  TOP w0.102: QC1.6 189.35,53.19 189.22,53.31 186.9,53.31 186.69,53.53 186.69,54.72 186.09,55.32 186.09,62.38 185.68,62.79 184.87,62.79 184.16,62.08 184.16,61.36 182.79,59.99 v2(182.43,59.99)
  IN2 w0.102: v2(182.43,59.99) 182.25,59.99 181.86,59.6 181.77,59.6 180.44,58.27 173.53,58.27 173.2,58.6 172.7,58.6 172.48,58.37 172.48,57.56 172.59,57.44 172.59,55.8 171.8,55.02 v2(171.8,54.62)
  BOTTOM w0.076: UC1.AP2 170.37,54.3 170.65,54.58 171.76,54.58 v2(171.8,54.62)
  BOTTOM w0.102: RPC14.1 182.45,60 v2(182.43,59.99)
MEM_SMBDATA: length 32.3
  TOP w0.102: v2(181.67,59.99) 182.08,59.58 182.71,59.58 184.39,61.26 184.39,61.99 184.96,62.56 185.59,62.56 185.86,62.29 185.86,55.23 186.46,54.63 186.46,51.68 186.82,51.32 QC1.3
  BOTTOM w0.076: 173.68,58.72 172.62,58.72 171.79,57.89 170.93,57.89 UC1.AH1
  BOTTOM w0.102: 173.68,58.72 173.93,58.72 174.77,59.56 175.93,59.56 177.03,60.66 180.18,60.66 180.85,59.99 v2(181.67,59.99) 182.08,60.41 182.59,60.41 182.68,60.5 RPC14.2
MIC1_L: length 4
  TOP w0.203: UA1.19 33.06,21.06 33.37,21.37
  TOP w0.254: 33.37,21.37 34.41,21.37 v1(34.8,21.75) 34.85,21.75 35.15,22.06 CA43.1
MIC1_R: length 3
  TOP w0.203: UA1.20 32.66,21.28 33.21,21.83 v1(33.27,21.83)
  TOP w0.254: v1(33.27,21.83) 33.88,22.44 CA44.1
MMICLK_REQ#: length 186.8
  TOP w0.102: UR1.17 284.12,27.16 v2(283.98,27.02) ; v1(233.58,63.27) 233.57,63.26 v2(233.57,62.56)
  IN1 w0.102: v2(172.02,64.82) 172.02,65.32 173.84,67.13 173.84,69.01 173.27,69.57 173.27,70.93 173.28,70.94 173.28,78.33 173.27,78.35 173.27,80.07 176.34,83.14 179.38,83.14 180.07,83.83 187.04,83.83 189.35,81.52 189.35,81.15 190.94,79.56 190.94,78.84 196.96,72.82 215.8,72.82 217.56,74.59 231.29,74.59 233.33,72.55 233.33,62.79 v2(233.57,62.56) ; v2(283.98,27.02) 284.53,27.57 286.97,27.57 287.53,28.13 287.53,32.99 286.83,33.69 286.83,38.3 279.26,45.88 279.26,50.01 275.25,54.03 273.56,54.03 269.92,57.66 269.92,58.72 269.05,59.6 269.05,61.54 v2(269.51,62.01)
  IN2 w0.102: v2(269.51,62.01) 269.33,62.19 247.79,62.19 247.42,62.56 v2(233.57,62.56)
  BOTTOM w0.076: UC1.U2 170.42,64.32 170.98,64.32 171.1,64.2 171.65,64.2 172.02,64.57 v2(172.02,64.82) 172.64,65.43 173.36,65.43
  BOTTOM w0.102: RPC18.7 176.37,65.38 176.21,65.23 173.68,65.23 173.48,65.43 173.36,65.43
MPCIE_RST#: length 6.5
  BOTTOM w0.076: UC1.V1 170.94,63.29 171.08,63.42 172.18,63.42 173.15,64.39 173.36,64.39
  BOTTOM w0.102: 173.36,64.39 173.58,64.39 173.67,64.48 v1(173.75,64.48) 176.2,64.48 176.29,64.38 RPC18.5
MPHYP_PWR_EN: length 71
  TOP w0.102: QZ10.2 145.2,87.47 144.96,87.72 144.96,90.12 146.01,91.17 148.99,91.17 149.6,90.56 v1(164.44,90.56) 165.58,90.56 170,86.14 170.94,86.14 171.28,85.8 171.28,84.63 174.77,81.14 177.15,81.14 v2(177.81,81.8)
  IN1 w0.102: v2(177.81,81.8) 177.81,81.05 174.62,77.86 174.62,71.16 175.7,70.08 175.7,66.01 173.44,63.75 v2(173.44,63.55)
  BOTTOM w0.076: UC1.Y2 170.43,62.83 170.96,62.83 171.22,63.09 172.99,63.09 v2(173.44,63.55) 173.48,63.59
  BOTTOM w0.102: 173.48,63.59 173.95,64.06 174.77,64.06 175.15,63.68 RC171.1 175.62,62.61 176.47,62.61 RC155.1
MPHYP_PWR_EN#: length 4
  TOP w0.102: RZ16.2 147.75,88.12 QZ10.6 ; RZ16.2 v1(149.87,87.33) ; RZ16.2 148.09,87.33 147.95,87.47 QZ10.5
MSCLK: length 55.9
  TOP w0.102: v2(299.24,37.42) 299.4,37.26 299.72,37.26 RE72.2 299.63,37.83 299.05,37.83 298.75,38.13 JDEG1.6 ; v2(258.59,39.16) 258.65,39.1 258.65,39.1 258.94,38.82 UE2.B43
  BOTTOM w0.102: v2(258.59,39.16) 258.59,38.75 259.31,38.04 v1(259.97,38.04) 261.13,38.04 261.45,37.72 264.27,37.72 264.37,37.62 265.95,37.62 266.74,38.4 266.74,40.14 266.96,40.37 266.96,43.04 270.3,46.38 274.54,46.38 277.96,42.96 281.53,42.96 286.22,38.28 298.39,38.28 v2(299.24,37.42)
MSDATA: length 52.2
  TOP w0.102: JDEG1.7 298.46,37.63 299.16,36.93 299.69,36.93 299.96,36.66 RE75.2 299.26,36.36 v2(299.24,36.37) ; RE86.2 258.54,34.95 v1(258.54,35.66) 258.54,36.21 v2(258.5,36.25) 258.5,36.46 258.69,36.65 UE2.A40
  BOTTOM w0.102: v2(299.24,36.37) 298.98,36.63 285.24,36.63 283.93,37.94 283.93,38.53 282.06,40.4 281.47,40.4 280.51,41.36 271.27,41.36 270.8,40.89 270.8,40.23 265.97,35.41 263.2,35.41 262.62,35.99 260.94,35.99 260.58,36.36 258.6,36.36 v2(258.5,36.25)
NB_LAN_TX0+: length 9.3
  BOTTOM w0.279: TL1.13 265.45,91.67 265.82,92.04 265.82,92.62 266.2,93 267.97,93 269.01,94.05 269.01,94.9 268.48,95.43 268.48,96.32 268.88,96.72 268.88,96.72 JLOM1.1
NB_LAN_TX0-: length 9.2
  BOTTOM w0.279: TL1.14 266.72,91.64 266.24,92.12 266.24,92.45 266.37,92.59 v3(267.5,92.59) 268.14,92.59 269.43,93.88 269.43,95.07 268.89,95.61 268.89,96.15 269.11,96.37 269.71,96.37 JLOM1.2
NB_LAN_TX1+: length 7.1
  IN2 w0.254: v2(270.85,92.84) 270.92,92.91 270.92,93.68 271.46,94.22 271.46,94.89 270.92,95.43 JLOM1.3
  BOTTOM w0.279: TL1.17 270.53,91.82 270.92,92.21 270.92,92.77 v2(270.85,92.84)
NB_LAN_TX1-: length 7.1
  IN2 w0.254: v2(271.46,92.84) 271.36,92.94 271.36,93.5 271.9,94.04 271.9,94.81 273.27,96.18 JLOM1.6
  BOTTOM w0.279: v2(271.46,92.84) 271.33,92.71 271.33,92.24 271.8,91.77 TL1.18
NB_LAN_TX2+: length 7
  BOTTOM w0.279: JLOM1.4 272.31,96.18 272.55,95.94 272.55,95.1 273.93,93.72 273.93,92.31 273.76,92.14 273.29,92.14 273.07,91.92 TL1.19
NB_LAN_TX2-: length 7
  BOTTOM w0.279: JLOM1.5 272.96,97.28 272.96,95.27 274.34,93.89 v3(274.34,92.62) TL1.20
NB_LAN_TX3+: length 8.2
  BOTTOM w0.279: JLOM1.7 275,97.28 275,94.55 277.01,92.54 v3(277.42,92.54) 277.88,92.54 278.15,92.28 TL1.23
NB_LAN_TX3-: length 8.1
  BOTTOM w0.279: JLOM1.8 275.71,96.18 275.45,95.92 275.45,94.69 277.18,92.96 278.06,92.96 278.57,92.45 278.57,92.23 278.78,92.02 279.21,92.02 279.42,91.81 TL1.24
NB_PSID: length 3.2
  TOP w0.254: v3(59.66,102.15) 59.66,103.31 60.24,103.89 PL3.2
  vias: v4(57.12,100.15)
NFC_IRQ: length 18
  TOP w0.102: RC175.1 183.82,53.14 182.24,54.71 182.24,54.95 181.79,55.4 181.79,56.05 180.52,57.33 v1(175.7,57.33) 173.59,57.33 172.97,56.7 v2(172.97,56.67)
  BOTTOM w0.076: UC1.AN3 169.74,54.75 170.25,54.75 170.49,54.99 170.49,55.17 170.55,55.23 170.66,55.34 170.9,55.34 170.91,55.34 171.55,55.34 172.89,56.67 v2(172.97,56.67)
O-USR: length 5.6
  TOP w0.102: v1(101.04,63.17) 101.04,63.21 101.95,64.12 v2(101.96,64.12)
  TOP w0.203: v2(101.96,64.12) 102.43,64.59 103.01,64.59 103.15,64.73 PU500.9
  BOTTOM w0.254: PR509.1 v2(101.96,64.12) 101.7,63.86 101.31,63.86 100.82,63.37 PR504.2
OCP-I: length 7.8
  TOP w0.102: v2(104.25,63.86) 104.25,63.74 v1(104.72,63.27)
  TOP w0.203: PU500.12 104.35,63.96 v2(104.25,63.86)
  TOP w0.254: PR524.2 105.22,60.57 105.22,62.77 v1(104.72,63.27)
  BOTTOM w0.254: PR506.1 104.63,64.43 104.25,64.05 v2(104.25,63.86) 103.5,63.11 PR501.2
PANEL_BKEN_EC: length 178.3
  TOP w0.102: DV2.2 105.57,87.47 v2(105.6,87.5) ; v2(249.43,66.8) 249.73,66.8 250.52,66.01 UE3.5
  IN1 w0.102: v2(198.04,95.76) 198.04,93.95 203.97,88.02 218.93,88.02 219.27,87.68 228.42,87.68 229.46,86.64 229.46,85.52 231.43,83.55 231.78,83.55 235.38,79.95 235.38,79.35 238.2,76.53 238.2,70.98 241.36,67.82 248.42,67.82 v2(249.43,66.8)
  BOTTOM w0.102: v2(105.6,87.5) 105.6,85.61 106.21,85 110.36,85 111.22,85.86 114.09,85.86 116,83.96 121.44,83.96 124.78,87.3 127.95,87.3 129.33,88.69 129.33,93.93 134.84,99.43 194.37,99.43 v1(196.42,97.38) v2(198.04,95.76)
PANEL_BKLEN: length 92.3
  TOP w0.102: DV2.3 107.41,86.21 109.61,86.21 110.07,85.75 110.07,83.48 v1(110.74,82.8) 114.25,79.3 119.5,79.3 120.3,80.1 120.92,80.1 122.25,81.42 122.25,83.15 125.06,85.96 128.17,85.96 134.51,92.3 149.03,92.3 149.97,91.36 166.27,91.36 169.09,88.55 v2(169.09,88.23)
  IN1 w0.102: v2(165.28,74.89) 165.32,74.89 167.71,77.29 167.71,79.63 168.35,80.27 168.35,82.38 167.12,83.61 167.12,85.61 169.09,87.58 v2(169.09,88.23)
  BOTTOM w0.076: v2(165.28,74.89) 165.28,73.56 UC1.A9
PBAT_PRES#: length 361.5
  TOP w0.102: v2(42.34,18.24) 42.77,17.8 42.77,12.17 43.79,11.15 45.35,11.15 46.72,9.78 v1(48.12,9.78) 50.63,9.78 PR2.2 52.17,8.89 53.03,8.03 PRP2.1 53.03,7.25 v2(52.82,7.04) ; UE2.A49 264.7,38.71 264.77,38.65 v2(264.77,38.23)
  IN1 w0.102: v2(52.82,7.04) 53.5,7.72 61.57,7.72 61.73,7.89 64.86,7.89 65.15,7.59 75.23,7.59 75.41,7.77 152.05,7.77 152.63,7.2 156.47,7.2 156.88,7.61 223.25,7.61 228.4,12.76 239.05,12.76 242.59,9.22 250.31,9.22 251.58,10.49 251.58,11.11 252.11,11.63 252.11,14.29 253.95,16.13 253.95,18.77 254.31,19.14 254.31,24.71 261.24,31.64 261.24,32.9 264.01,35.66 264.01,37.46 v2(264.77,38.23)
  IN2 w0.102: v2(42.34,18.24) 43.8,19.7 48.59,19.7 72.22,43.33 72.22,51.87 79.02,58.66 83.44,58.66 88.01,63.24 90.83,63.24 91.6,64.02 91.6,75.05 94.73,78.17 v2(94.73,80.11)
  BOTTOM w0.102: v2(94.73,80.11) 94.52,79.91 83.64,79.91 83.13,79.4 83.13,78.73 PR728.1
PBAT_PRES#_C: length 5.4
  TOP w0.102: v4(53.05,13.44) 53.48,13.44 v2(53.67,13.25)
  TOP w0.254: v2(53.67,13.25) 53.2,12.78 PD2.2 53.2,11.59 53.27,11.52 53.27,9.91 53.03,9.66 PRP2.8
PBAT_SMBCLK: length 247.1
  TOP w0.102: UE2.A56 264.69,42.21 264.77,42.13 265.36,42.13 v1(265.73,41.76) 266.12,41.37 v2(266.33,41.37) 266.42,41.28 RE43.2 ; v2(54.05,6.28) 53.9,6.43 53.9,7.33 54.03,7.46 PRP2.3
  IN1 w0.102: v2(54.05,6.28) 53.9,6.43 53.9,6.72 54.06,6.88 61.76,6.88 62.2,7.31 64.62,7.31 65.05,6.88 75.84,6.88 76.25,7.29 136.71,7.29 136.8,7.2 151.81,7.2 152.29,6.72 156.82,6.72 157.22,7.12 223.73,7.12 228.88,12.28 238.72,12.28 242.32,8.69 250.71,8.69 254.04,12.01 254.04,14.4 255.14,15.5 255.14,18.28 255.75,18.89 255.75,24.33 261.86,30.44 263.23,30.44 264.65,31.86 264.65,34.04 266.34,35.72 266.34,37.64 266.46,37.75 266.46,39.71 266.98,40.23 266.98,40.88 266.67,41.19 266.51,41.19 v2(266.33,41.37)
PBAT_SMBCLK_C: length 9.2
  TOP w0.102: PRP2.6 54.03,9.22 53.9,9.36 53.9,10.64 54.9,11.65 54.9,11.9 PD1.2 54.92,12.67 54.92,13.07 v2(55.1,13.25)
  BOTTOM w0.102: 56.2,16.58 56.2,15.48 55.56,14.84 55.56,14.37 54.92,13.74 54.92,13.43 v2(55.1,13.25)
PBAT_SMBDAT: length 252.3
  TOP w0.102: UE2.B59 262.93,41.96 v2(262.87,41.9) ; v2(53.46,6.28) 53.67,6.48 53.67,7.33 53.53,7.46 PRP2.2 ; RE37.2 266.68,40.39 v2(266.33,40.75)
  IN1 w0.102: v2(53.46,6.28) 53.67,6.48 53.67,6.81 53.97,7.11 61.67,7.11 62.1,7.54 64.72,7.54 65.15,7.11 75.75,7.11 76.15,7.52 136.81,7.52 136.9,7.43 151.9,7.43 152.38,6.95 156.72,6.95 157.13,7.35 223.63,7.35 228.79,12.51 238.82,12.51 242.41,8.91 250.61,8.91 253.81,12.11 253.81,14.49 254.91,15.6 254.91,18.37 255.52,18.98 255.52,24.42 261.77,30.67 263.14,30.67 264.42,31.96 264.42,34.13 266.11,35.82 266.11,37.73 266.23,37.85 266.23,39.81 266.75,40.33 266.75,40.79 266.64,40.89 266.48,40.89 266.34,40.75 v2(266.33,40.75)
  IN2 w0.102: v2(262.87,41.9) 262.18,41.9 261.77,41.49 261.77,40.8 262.01,40.56 263.37,40.56 264.02,41.21 265.87,41.21 v2(266.33,40.75)
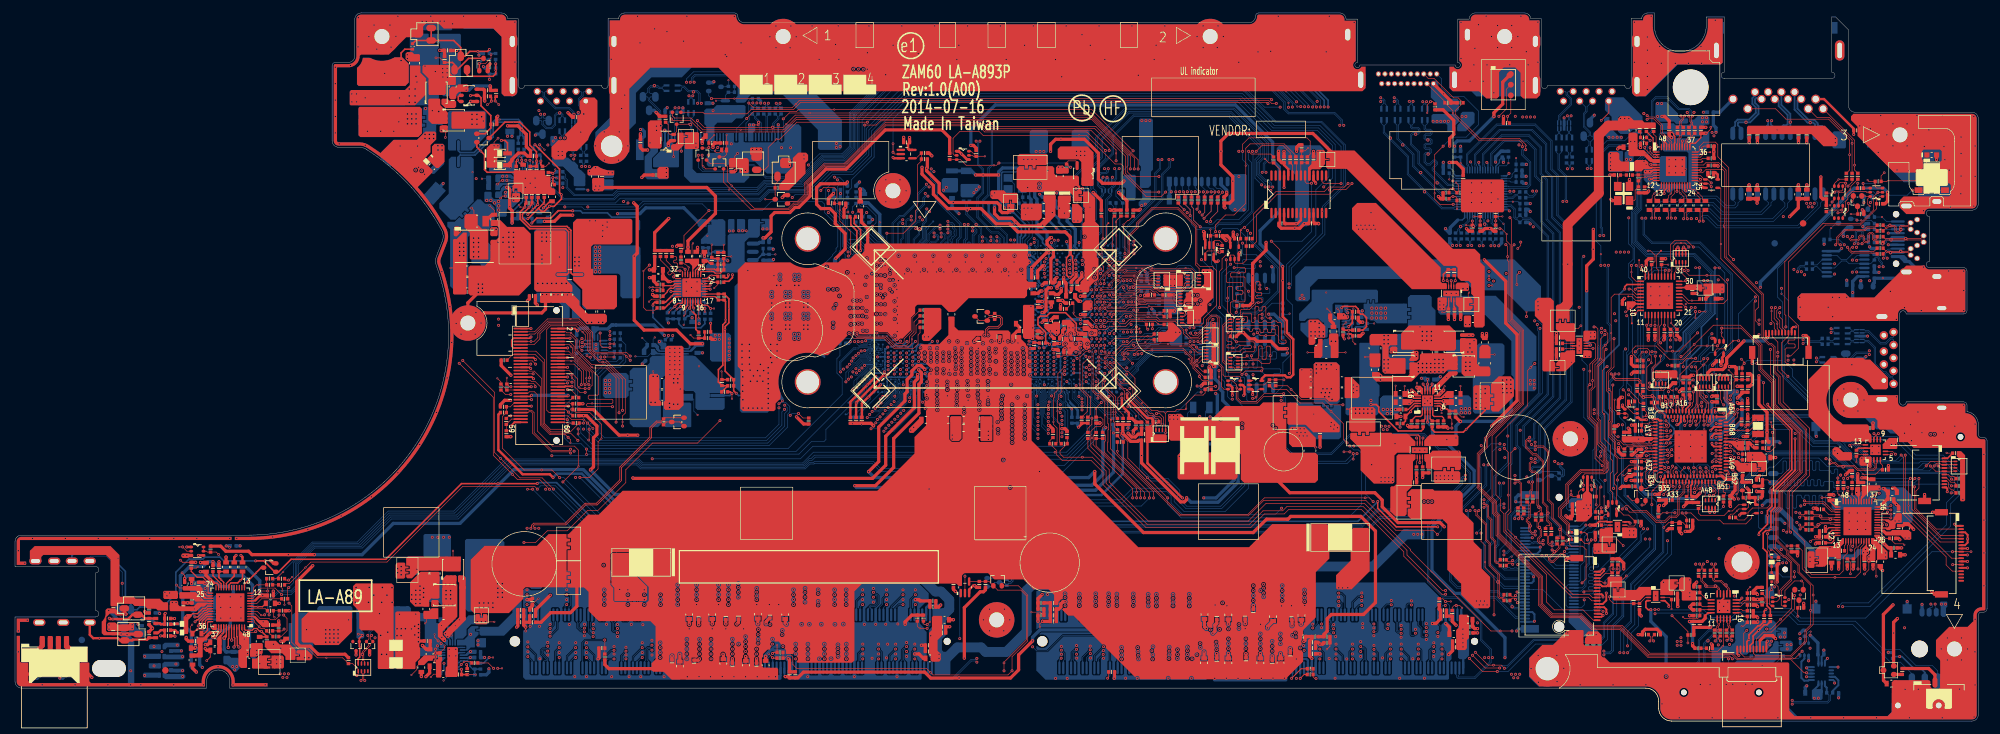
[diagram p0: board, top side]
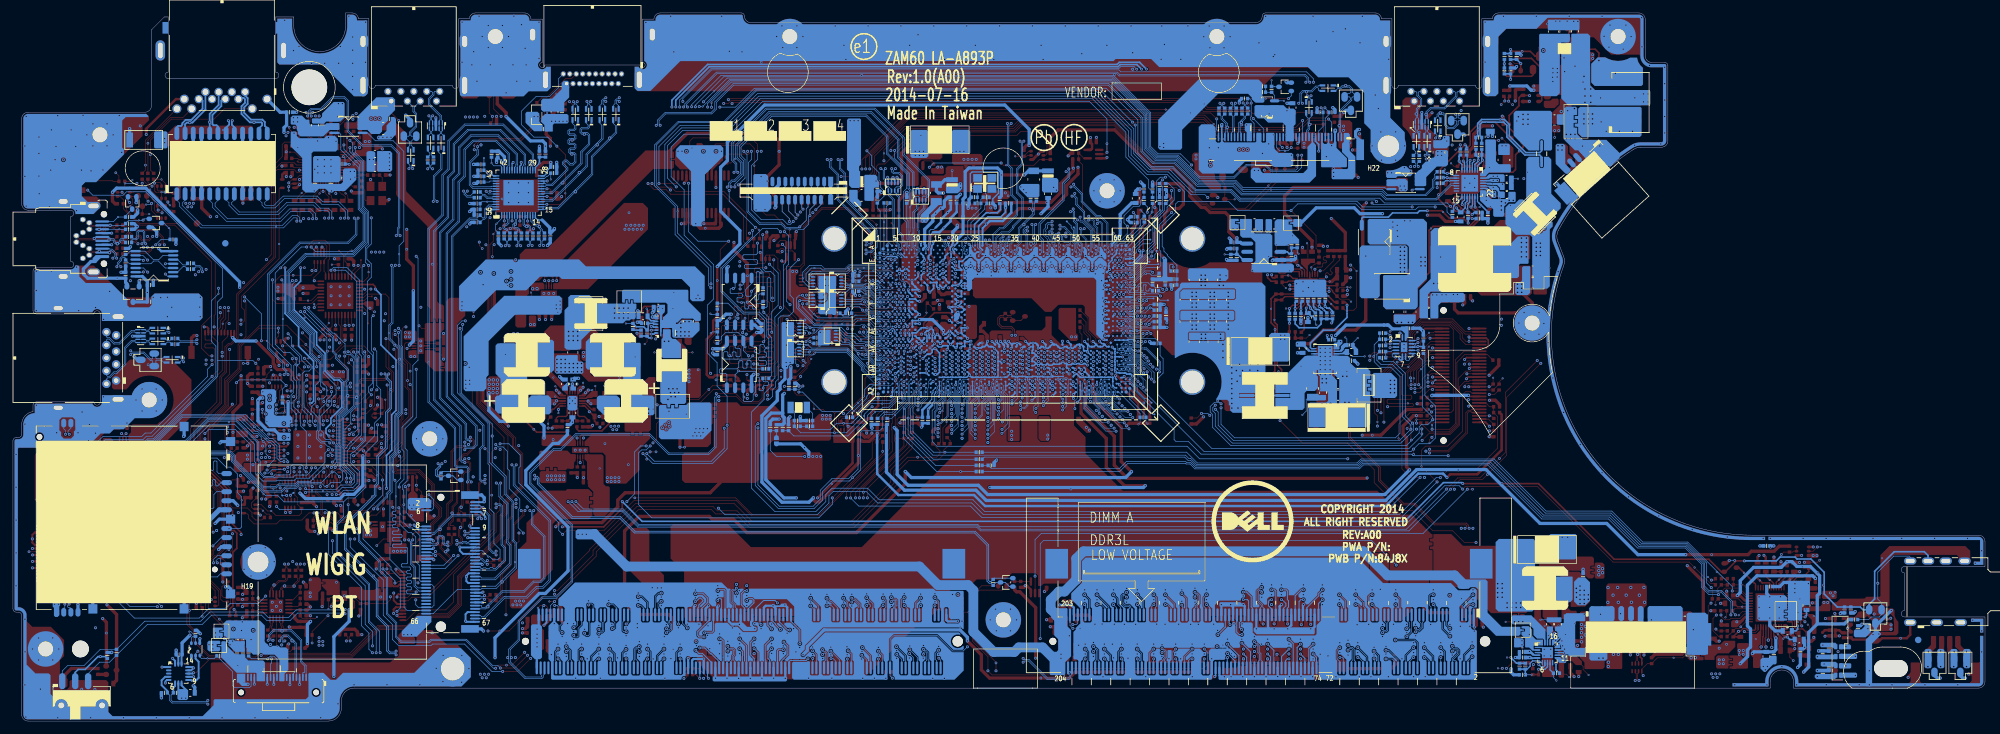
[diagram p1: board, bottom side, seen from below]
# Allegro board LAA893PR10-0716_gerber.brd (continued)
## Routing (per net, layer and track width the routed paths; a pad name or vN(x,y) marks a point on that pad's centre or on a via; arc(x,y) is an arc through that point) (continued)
PBAT_SMBDAT_C: length 9.2
  TOP w0.102: v2(54.52,13.25) 54.7,13.07 54.7,12.69 PD1.3 54.67,11.92 54.67,11.74 53.67,10.74 v3(53.67,10.32) 53.67,9.33 53.53,9.2 PRP2.7
  BOTTOM w0.102: 54.7,16.57 54.7,15.49 55.33,14.85 55.33,14.46 54.7,13.83 54.7,13.43 v2(54.52,13.25)
PBATT+_C: length 1
  TOP w0.508: PC3.1 62.47,12.38 v3(62.34,12.25)
  vias: v3(59.04,14.27) v3(59.03,13.22) v3(59.04,12.09) v3(59.04,10.88) v3(59.03,9.73) v3(59.66,13.22) v3(59.66,9.73) v3(59.69,14.27) v3(59.67,12.09) v3(59.67,10.88) v3(60.32,14.27) v3(61.77,14.67) v3(61.78,13.32) v3(62.35,14.93) v3(62.35,14.3) v3(62.35,13.66) v3(62.34,12.95) v4(59.41,16.52) v4(61.26,14.25) v4(61.92,16.53)
PCH_ALW_ON: length 49.6
  TOP w0.102: v2(254.77,35.03) 254.77,35.08 255.81,36.12 255.81,36.58 255.69,36.7 UE2.A34 ; v2(250.39,57.1) 250.91,57.62 252.24,57.62 252.55,57.31 252.55,56.78 252.85,56.48 v4(252.85,55.4) 252.18,54.72 252.18,51.45 252.54,51.09 254.71,51.09 255.06,51.45 RPE10.4 ; UZ2.3 v2(243.85,57.62)
  IN1 w0.102: v2(250.39,57.1) 250.23,56.93 244.54,56.93 v2(243.85,57.62)
  BOTTOM w0.102: v2(250.39,57.1) 250.25,56.96 250.25,43.39 251.66,41.99 251.67,41.99 252.08,41.58 252.24,41.58 252.55,41.27 252.55,39.95 251.17,38.57 251.17,36.59 252.07,35.69 253.66,35.69 254.32,35.03 v2(254.77,35.03)
PCH_AZ_BITCLK: length 20.8
  BOTTOM w0.076: 166.8,48.37 165.97,49.19 165.97,50.34 165.62,50.69 165.62,51.24 UC1.AW8
  BOTTOM w0.102: RC23.2 162.18,39.54 v1(166.43,43.8) 166.8,44.16 166.8,48.37
PCH_AZ_CODEC_BITCLK: length 133.5
  TOP w0.102: UA1.6 38.69,17.37 RA17.1 39.26,16.8 v2(39.26,16.42)
  BOTTOM w0.102: v2(39.26,16.42) 39.26,18.41 40.81,19.96 42.75,19.96 43.55,20.76 43.55,24.32 46.23,26.99 53.49,26.99 58.05,31.55 68.36,31.55 76.64,39.84 96.14,39.84 96.75,39.22 122,39.22 122.75,39.98 123.36,39.98 123.51,40.13 132.67,40.13 133.72,39.09 153.59,39.09 CC5.1 RC23.1
PCH_AZ_CODEC_RST#: length 131.1
  TOP w0.102: v2(41.2,19.55) 41.19,19.55 40.18,20.56 37.96,20.56 36.77,19.37 UA1.11
  BOTTOM w0.102: RC22.1 133.72,38.59 132.45,39.85 123.58,39.85 123.57,39.87 123.45,39.75 122.85,39.75 122.09,39 96.66,39 96.04,39.61 76.85,39.61 68.48,31.25 58.18,31.25 53.69,26.77 46.32,26.77 43.77,24.22 43.77,20.66 42.66,19.55 v2(41.2,19.55)
PCH_AZ_CODEC_SDIN0: length 144.4
  TOP w0.102: v2(42.3,20.65) 42.3,20.65 42.14,20.49 RA9.1
  BOTTOM w0.076: 166.04,48.37 165.46,48.94 165.46,50.25 165.16,50.55 UC1.AY10
  BOTTOM w0.102: v2(42.3,20.65) 43.04,21.39 43.04,24.45 46.04,27.45 53.08,27.45 57.8,32.16 67.93,32.16 76.06,40.3 96.33,40.3 96.94,39.68 121.81,39.68 122.74,40.61 123.04,40.61 123.54,41.12 162.59,41.12 166.04,44.56 166.04,48.37
PCH_AZ_CODEC_SDOUT: length 132.7
  TOP w0.102: UA1.5 37.45,16.97 v1(38.05,16.37) 38.51,16.37 v2(38.57,16.43)
  BOTTOM w0.102: RC19.1 154.66,40.81 123.67,40.81 123.13,40.27 122.72,40.27 121.9,39.45 96.85,39.45 96.23,40.07 76.44,40.07 68.23,31.86 57.92,31.86 53.29,27.22 46.13,27.22 43.32,24.41 43.32,20.85 42.65,20.19 40.71,20.19 39.02,18.5 39.02,16.89 v2(38.57,16.43)
PCH_AZ_CODEC_SYNC: length 128.9
  TOP w0.102: v2(39.05,20.12) 37.9,20.12 36.75,18.97 UA1.10
  BOTTOM w0.102: RC20.1 123.38,41.57 121.71,39.91 97.04,39.91 96.42,40.53 75.86,40.53 67.81,32.47 57.67,32.47 52.88,27.68 45.94,27.68 39.05,20.79 v2(39.05,20.12)
PCH_AZ_RST#: length 23
  BOTTOM w0.076: 167.12,48.37 166.2,49.28 166.2,51.99 166.31,52.1 166.31,52.47 UC1.AU8
  BOTTOM w0.102: 167.12,48.37 167.12,43.7 162,38.59 v4(158.32,38.59) RC22.2
PCH_AZ_SDIN0_R: length 6.3
  TOP w0.102: UA1.8 37.37,18.17 38.11,18.9 RA9.2 41.64,18.48 v1(41.64,17.98)
PCH_AZ_SDOUT: length 24
  TOP w0.102: RC11.2 165.8,45.27 166.42,45.9 v2(166.42,46.84)
  BOTTOM w0.076: UC1.AU11 164.79,52.49 164.79,52.12 164.87,52.04 164.87,51.37 165.03,51.2 165.32,51.2 165.45,51.07 165.45,50.59 165.72,50.32 165.72,49.07 166.42,48.37 v2(166.42,46.84)
  BOTTOM w0.102: v2(166.42,46.84) 166.42,44.37 162.54,40.49 RC19.2
PCH_AZ_SYNC: length 19
  BOTTOM w0.076: UC1.AV11 164.7,51.92 164.7,51.28 164.87,51.12 164.87,50.57 165.25,50.18 165.25,48.81 165.66,48.41
  BOTTOM w0.102: RC20.2 v4(160.72,41.57) 162.48,41.57 165.66,44.75 165.66,48.41
PCH_BATLOW#: length 16.1
  TOP w0.102: v2(169.22,55.42) 170.29,54.35 170.29,53.02 v1(170.96,52.35) 171.07,52.25 172.08,52.25 172.74,51.59 172.74,50.22 175.44,47.52 175.84,47.52 176.31,47.05 176.87,47.05 177.19,46.74 177.19,45.94 176.98,45.73 176.43,45.73 176.31,45.62 RPC1.8
  BOTTOM w0.076: v2(169.22,55.42) 168.83,55.03 UC1.AN4
PCH_CL_CLK1: length 122.9
  IN2 w0.102: v2(235.96,25.58) 235.96,25.58 232.77,28.77 228.6,28.77 227.35,27.52 221.71,27.52 221.33,27.9 215.43,27.9 215.3,28.03 215.3,28.61 215.17,28.74 214.88,28.74 214.75,28.61 214.75,28.03 214.63,27.9 214.29,27.9 214.19,28.01 214.19,28.8 214.08,28.9 213.78,28.9 213.68,28.8 213.68,28.01 213.58,27.9 213.21,27.9 213.11,28.01 213.11,28.8 213.01,28.9 212.7,28.9 212.6,28.8 212.6,28.01 212.5,27.9 212.2,27.9 212.09,28.01 212.09,28.8 211.99,28.9 211.69,28.9 211.59,28.8 211.59,28.01 211.49,27.9 211.18,27.9 211.08,28.01 211.08,28.8 210.98,28.9 210.67,28.9 210.57,28.8 210.57,28.01 210.47,27.9 210.16,27.9 210.06,28.01 210.06,28.8 209.96,28.9 209.66,28.9 209.55,28.8 209.55,28.01 209.45,27.9 209.15,27.9 209.05,28.01 209.05,28.8 208.95,28.9 208.64,28.9 208.54,28.8 208.54,28.01 208.44,27.9 208.13,27.9 208.03,28.01 208.03,28.8 207.93,28.9 207.62,28.9 207.52,28.8 207.52,28.01 207.42,27.9 207.12,27.9 207.01,28.01 207.01,28.8 206.91,28.9 206.61,28.9 206.51,28.8 206.51,28.01 206.41,27.9 206.1,27.9 206,28.01 206,28.8 205.9,28.9 205.59,28.9 205.49,28.8 205.49,28.01 205.39,27.9 205.08,27.9 204.98,28.01 204.98,28.8 204.88,28.9 204.58,28.9 204.47,28.8 204.47,28.01 204.37,27.9 204.07,27.9 203.97,28.01 203.97,28.8 203.87,28.9 203.56,28.9 203.46,28.8 203.46,28.01 203.36,27.9 203.05,27.9 202.95,28.01 202.95,28.8 202.85,28.9 202.54,28.9 202.44,28.8 202.44,28.01 202.34,27.9 202.04,27.9 201.93,28.01 201.93,28.8 201.83,28.9 201.53,28.9 201.43,28.8 201.43,28.01 201.33,27.9 201.02,27.9 200.92,28.01 200.92,28.8 200.82,28.9 200.51,28.9 200.41,28.8 200.41,28.01 200.31,27.9 200,27.9 199.9,28.01 199.9,28.8 199.8,28.9 199.5,28.9 199.39,28.8 199.39,28.01 199.29,27.9 198.99,27.9 198.89,28.01 198.89,28.8 198.79,28.9 198.48,28.9 198.38,28.8 198.38,28.01 198.28,27.9 197.99,27.9 197.86,28.03 197.86,28.74 197.74,28.87 196.95,28.87 184.45,41.37 184.45,41.75 181.14,45.06 178.86,45.06 177.68,46.24 177.68,48.11 176.73,49.06 175.93,49.06 174.11,50.87 174.11,51.47 173.23,52.36 171.23,52.36 170.84,52.75 170.84,58.32 170.76,58.41 170.76,59 v2(169.85,59.92)
  BOTTOM w0.076: UC1.AF2 169.85,59.83 v2(169.85,59.92)
  BOTTOM w0.102: v2(235.96,25.58) 237.94,23.6 JNGFF1.34
PCH_CL_DATA1: length 122.6
  IN2 w0.102: v2(171.3,60.16) 170.95,59.8 170.95,58.49 171.03,58.41 171.03,53.3 171.15,53.17 173.23,53.17 173.35,53.3 173.35,56.12 173.48,56.25 179.65,56.25 179.78,56.12 179.78,55.7 179.65,55.57 174.11,55.57 173.99,55.45 173.99,55.16 174.11,55.03 175.04,55.03 175.17,54.9 175.17,54.61 175.04,54.48 174.1,54.48 173.97,54.36 173.97,54.05 174.1,53.92 174.65,53.92 174.77,53.8 174.77,53.48 174.65,53.35 174.09,53.35 173.96,53.23 173.96,52.89 174.09,52.77 174.5,52.77 174.62,52.64 174.62,50.91 176.11,49.43 176.87,49.43 178.04,48.26 178.04,46.44 178.97,45.52 181.19,45.52 184.81,41.9 184.81,41.52 197.07,29.26 215.17,29.26 216.17,28.26 221.48,28.26 221.87,27.88 227.2,27.88 228.45,29.12 232.91,29.12 233.11,28.92 233.26,28.92 233.6,29.26 233.78,29.26 233.96,29.08 233.96,28.9 233.62,28.56 233.62,28.42 234.38,27.66 234.52,27.66 235.21,28.34 235.39,28.34 235.57,28.16 235.57,27.98 234.88,27.3 234.88,27.15 235.91,26.12 236.45,26.12 236.57,26.25 236.57,27.85 236.7,27.98 236.99,27.98 237.12,27.85 237.12,25.73 236.99,25.6 v2(236.65,25.6)
  BOTTOM w0.076: UC1.AD2 170.43,59.99 171.14,59.99 v2(171.3,60.16)
  BOTTOM w0.102: v2(236.65,25.6) 238.15,24.1 239.84,24.1 JNGFF1.32
PCH_CL_RST1#: length 124.4
  IN1 w0.102: v2(242.43,54.39) 238.71,54.39 232.34,60.76 232.34,68.12 228.17,72.29 217.78,72.29 217.62,72.13 216.74,71.25 193.53,71.25 193.25,71.53 191.76,71.53 185.62,65.38 184.36,65.38 182.85,63.87 180.73,63.87 179.48,62.61 177.71,62.61 176.37,61.26 175.54,61.26 175.24,60.96 174.86,60.96 174.41,60.51 173.65,60.51 v2(173.3,60.16)
  BOTTOM w0.076: v2(173.3,60.16) 173.29,60.15 173.29,60.03 172.73,59.46 172.2,59.46 171.99,59.25 170.68,59.25 170.55,59.25 170.55,59.25 170.52,59.25 170.36,59.09 169.67,59.09 169.57,59.18 169.1,59.18 168.83,59.45 UC1.AF4
  BOTTOM w0.102: JNGFF1.30 241.54,24.6 241.86,24.92 241.86,28.69 243.04,29.87 243.52,29.87 244.35,30.7 244.35,35.66 244.54,35.85 244.54,36.46 243.84,37.16 243.84,41.88 244.16,42.2 244.16,45.23 242.43,46.96 v2(242.43,54.39)
PCH_DPWROK: length 124.5
  TOP w0.102: v2(206.8,41.36) v4(206.8,40.5) ; v2(255.42,35.02) 255.91,35.51 256.08,35.51 256.69,36.12 UE2.A36
  IN1 w0.102: v2(194.83,45.29) 189.67,45.29 v2(189.62,45.34)
  IN2 w0.102: v2(255.42,35.02) 255.02,34.62 250.8,34.62 250.59,34.84 241.99,34.84 241.32,35.51 233.63,35.51 232.31,36.83 232.31,38.05 231.38,38.98 230.77,38.98 227.57,42.18 218.81,42.18 218.25,42.73 215.99,42.73 215.02,41.77 207.21,41.77 v2(206.8,41.36)
  BOTTOM w0.076: 169.44,48.53 167.87,50.1 167.87,50.69 167.87,51.77 168.12,52.02 UC1.AV5
  BOTTOM w0.102: v2(206.8,41.36) 205.63,40.18 196.8,40.18 194.83,42.16 v2(194.83,45.29) ; v2(189.62,45.34) 189.62,45.34 189.62,36.52 186.32,33.22 181.08,33.22 179.99,34.31 179.99,35.68 178.2,37.48 175.61,37.48 174.15,38.94 174.15,44.99 172.67,46.48 172.67,47.29 171.71,48.25 170.58,48.25 170.3,48.53 169.44,48.53
PCH_GPIO4: length 17.1
  BOTTOM w0.076: UC1.F2 170.13,70.25 170.43,70.55 175.6,70.55 176.13,70.01 179.37,70.01 179.83,70.47
  BOTTOM w0.102: RPC8.8 181.84,67.18 182.69,68.02 v1(182.69,68.45) 182.69,69.4 181.62,70.47 179.83,70.47
PCH_GPIO5: length 16.3
  BOTTOM w0.076: UC1.F3 169.73,69.75 170.27,69.75 170.42,69.9 170.42,70.16 170.65,70.39 175.48,70.39 176.11,69.76 179.27,69.76
  BOTTOM w0.102: RPC8.7 181.66,67.68 182.2,68.22 182.2,69.2 181.35,70.05 v1(180.9,70.05) 179.96,70.05 179.67,69.76 179.27,69.76
PCH_GPIO6: length 13.9
  BOTTOM w0.076: UC1.G4 169.13,69.62 169.63,69.62 169.66,69.59 171.03,69.59 171.35,69.91 v1(174.18,69.91) 175.09,69.91 175.74,69.25 180.1,69.25
  BOTTOM w0.102: 180.1,69.25 180.16,69.19 181.21,69.19 181.46,68.95 181.46,68.78 181.35,68.68 RPC8.5
PCH_GPIO7: length 12.9
  BOTTOM w0.076: UC1.F1 170.91,70.2 175.21,70.2 v1(175.59,69.82) 175.94,69.47 179.92,69.47
  BOTTOM w0.102: RPC8.6 181.47,68.18 181.72,68.43 181.72,69.07 181.24,69.56 180.01,69.56 179.92,69.47
PCH_GPIO9: length 17.5
  TOP w0.102: v2(182.64,55.78) 183.3,56.44 RPC10.7
  IN1 w0.102: v2(182.64,55.78) 181.47,55.78 179.77,57.48 175.77,57.48 174.4,56.11 174.39,56.11 174.36,56.08 172,56.08 171.71,56.36 170.76,56.36 v2(169.81,55.42)
  BOTTOM w0.076: UC1.AM3 169.48,55.75 v2(169.81,55.42)
  BOTTOM w0.102: v2(182.64,55.78) v1(182.27,55.41)
PCH_GPIO10: length 4.4
  BOTTOM w0.076: 173.36,57.7 173.25,57.7 172.35,56.79 172.35,56.64 172.12,56.41 171.3,56.41 170.98,56.09 170.66,56.09 170.49,55.92 170.49,55.91 170.37,55.8 UC1.AM2
  BOTTOM w0.102: T27.1 173.36,57.7
PCH_GPIO14: length 1
  TOP w0.076: T21.1 v2(168.37,58.13)
  BOTTOM w0.076: v2(168.37,58.13) 168.5,58.01 UC1.AH4
PCH_GPIO16: length 13
  BOTTOM w0.076: UC1.Y1 170.89,62.54 171.28,62.93 172.69,62.93 172.85,62.77 174.32,62.77
  BOTTOM w0.102: RPC6.8 181.45,64.38 181.62,64.21 181.62,63.63 v1(180.9,62.9) 180.34,62.34 175.02,62.34 174.6,62.77 174.32,62.77
PCH_GPIO19: length 10.3
  TOP w0.076: 173.3,62.8 173.03,62.8 172.51,63.32 168.85,63.32 v2(168.45,62.92)
  TOP w0.102: RC66.2 177.33,62.8 v1(176.49,62.8) 173.3,62.8
  BOTTOM w0.076: UC1.Y5 168.15,62.62 v2(168.45,62.92)
PCH_GPIO23: length 4.6
  BOTTOM w0.076: UC1.T2 170.37,64.79 170.49,64.91 170.49,64.91 170.66,65.08 170.67,65.08 170.97,65.08 171.06,65.17 171.06,65.17 171.09,65.19 171.35,65.19 172.19,66.03 v1(172.96,66.03) 173.15,66.03 173.36,66.24
  BOTTOM w0.102: 173.36,66.24 173.58,66.46 RC68.2
PCH_GPIO44: length 10.2
  BOTTOM w0.076: UC1.AK4 169.14,57.64 169.59,57.64 169.64,57.59 170.54,57.59 170.62,57.67 171.85,57.67 172.72,58.55 173.02,58.55 173.18,58.39 173.36,58.39
  BOTTOM w0.102: RPC19.4 177.15,60.35 176.04,59.24 175.32,59.24 v1(174.68,58.6) 174.47,58.39 173.36,58.39
PCH_GPIO46: length 16.6
  TOP w0.102: v1(182.14,58.15) 182.24,58.15 v2(182.56,57.84) 182.96,57.44 RPC10.5
  IN1 w0.102: v2(169.81,58.41) 170.49,57.73 173,57.73 173.42,58.15 174.7,58.15 175.24,58.7 180.55,58.7 181.33,57.92 182.47,57.92 v2(182.56,57.84)
  BOTTOM w0.076: UC1.AG3 169.48,58.74 v2(169.81,58.41)
PCH_GPIO49: length 1.1
  TOP w0.076: T22.1 169.49,62.62 v2(169.78,62.91)
  BOTTOM w0.076: UC1.Y3 169.48,62.61 v2(169.78,62.91)
PCH_GPIO52: length 12.1
  TOP w0.076: 173.36,67.56 173.01,67.56 172.46,68.12 v2(172.4,68.12)
  TOP w0.102: 173.36,67.56 v1(175.23,67.56) 175.83,67.56 176.3,67.09 176.74,67.09 176.97,66.86 180.24,66.86 180.68,67.31 180.68,67.61 181,67.93 RPC3.6
  BOTTOM w0.076: UC1.L1 170.78,67.11 171.16,67.49 171.72,67.49 172.35,68.12 v2(172.4,68.12)
PCH_GPIO53: length 9.8
  TOP w0.076: 173.36,66.59 173.03,66.27 171.71,66.27 171.3,66.69 v2(171.3,67.03)
  TOP w0.102: RC140.1 176.89,65.89 176.41,66.37 175.83,66.37 175.5,66.7 v1(173.78,66.7) 173.47,66.7 173.36,66.59
  BOTTOM w0.076: UC1.L4 169.13,66.71 170.37,66.71 170.41,66.74 171.01,66.74 v2(171.3,67.03)
PCH_GPIO57: length 21
  TOP w0.076: v2(172.69,55.32) 172.69,55.34 171.66,56.36 171.29,56.36
  TOP w0.102: 171.29,56.36 171.03,56.62 171.03,56.93 171.74,57.64 172.95,57.64 173.3,58 v1(180.12,58) 181.45,58 182.23,57.21 182.23,55.61 182.47,55.37 182.92,55.37 183.48,55.94 RPC10.8
  BOTTOM w0.076: v2(172.69,55.32) 172.69,54.92 171.94,54.18 170.9,54.18 UC1.AP1
PCH_GPIO59: length 7.7
  TOP w0.102: RC245.1 170.1,47.05 v1(170.1,47.73) 170.1,50.11 168.39,51.82 v2(168.39,52.62)
  BOTTOM w0.076: UC1.AT5 167.88,53.13 v2(168.39,52.62)
PCH_GPIO66: length 7.6
  TOP w0.102: v2(169.03,71.35) 169.59,71.91 v1(169.59,73.76) 169.59,77.78 RC176.2
  BOTTOM w0.076: v2(169.03,71.35) 169.15,71.47 UC1.D3
PCH_GPIO68: length 9
  TOP w0.102: v2(171.52,72.3) 171.52,75.17 171.3,75.4 v1(171.3,76.76) 171.97,77.43 172.14,77.43 RC164.2
  BOTTOM w0.076: v2(171.52,72.3) 171.21,71.98 170.54,71.98 170.35,71.8 170.04,71.8 169.63,72.2 UC1.C3
PCH_GPIO69: length 15
  TOP w0.102: v2(169.82,70.41) 175.35,70.41 v1(175.65,70.1) 175.83,69.92 181.89,69.92 182.38,69.43 182.38,68.6 182.56,68.43 RPC16.6
  BOTTOM w0.076: v2(169.82,70.41) 170.13,70.72 UC1.E2
PCH_GPIO73: length 16.9
  BOTTOM w0.076: UC1.AU4 168.94,52.86 169.27,53.19 169.66,53.19 169.85,53.39 169.85,53.71 170.15,54.02 172.07,54.02 173.36,55.3
  BOTTOM w0.102: RPC7.8 182.92,58.26 182.89,58.24 181.92,58.24 v1(181.89,58.2) 181.36,57.68 175.74,57.68 173.36,55.3
PCH_GPIO76: length 6.8
  BOTTOM w0.076: UC1.P1 171.24,65.54 172.29,66.59 172.93,66.59
  BOTTOM w0.102: 172.93,66.59 173.46,67.13 175.49,67.13 175.6,67.02 176.23,67.02 176.39,67.18 RPC17.5
PCH_GPIO80: length 7.7
  BOTTOM w0.076: 173.36,67.56 173.32,67.56 173.22,67.46 173.1,67.46 v1(173.03,67.53) 172.94,67.62 172.08,67.62 171.68,67.22 171.68,66.9 171.36,66.58 170.55,66.58 170.26,66.29 UC1.N2
  BOTTOM w0.102: RPC17.7 176.39,68.18 175.78,67.56 173.36,67.56
PCH_GPIO85: length 10.7
  TOP w0.076: v2(167.83,66.69) 167.9,66.76 169.67,66.76 170.9,68 170.9,68.19 171.18,68.47 172.63,68.47 v1(172.98,68.12) 173.2,67.89 173.36,67.89
  TOP w0.102: RPC4.8 176.34,67.42 175.87,67.89 173.36,67.89
  BOTTOM w0.076: UC1.N6 167.5,66.36 v2(167.83,66.69)
PCH_GPIO87: length 21.3
  TOP w0.076: v2(166.51,65.66) 166.76,65.91 166.76,66.86 167.37,67.47 167.37,68.06 168.11,68.8 168.11,69.01 169.16,70.06 v1(173.26,70.06)
  TOP w0.102: RPC16.7 182.4,67.93 182.1,68.22 182.1,69.19 181.6,69.69 175.53,69.69 175.16,70.06 v1(173.26,70.06)
  BOTTOM w0.076: UC1.R7 166.85,65.32 v2(166.51,65.66)
PCH_INTVRMEN: length 7.3
  BOTTOM w0.076: RC1.2 168.96,46.79 v1(168.43,47.32) 166.37,49.38 166.37,51.92 UC1.AV7
PCH_JTAG_JTAGX: length 86.4
  TOP w0.102: RC18.1 139.24,61.14 139.24,60.05 138.6,59.42 v1(138.6,59.02) 138.6,58.4 138.03,57.83 136.01,57.83 134.49,59.35 130.09,59.35 v2(129.51,59.94)
  IN1 w0.102: v2(129.51,59.94) 129.04,60.4 128.62,60.4 124.41,56.18 120.76,56.18 118.62,54.04 118.62,49.11 118.51,49.01 118.51,48.9 v2(118.06,48.44)
  BOTTOM w0.076: v2(129.51,59.94) 130.05,59.4 131.97,59.4 UC1.AE63
  BOTTOM w0.102: RC112.2 RC115.2 94.38,58.18 94.38,55.56 93.53,54.71 91.82,54.71 90.4,53.29 90.4,44.51 91.11,43.8 115.97,43.8 118.06,45.88 v2(118.06,48.44)
PCH_JTAG_TCK: length 74.8
  TOP w0.102: JXDP1.55 v2(76.6,47.2) 76.32,47.2 RC119.2 ; v2(87.03,45.17) 87.03,44.41 v4(87.02,44.4)
  IN2 w0.102: v2(87.03,45.17) 86.04,46.16 77.64,46.16 v2(76.6,47.2)
  BOTTOM w0.076: 129.42,59.12 131.07,59.12 131.18,59.23 132.46,59.23 UC1.AE62
  BOTTOM w0.102: 129.42,59.12 128.2,59.12 RC21.1 127.48,56.51 127.01,56.04 127.01,53.81 127.82,53 127.82,50.49 119.48,42.15 89.01,42.15 87.03,44.13 v2(87.03,45.17)
PCH_JTAG_TDI: length 94.2
  TOP w0.102: RC14.1 139.86,60.04 139.56,59.74 139.56,58.34 138.79,57.58 135.87,57.58 134.28,59.17 129.65,59.17 v2(128.89,59.93) ; v4(89.3,45.24) v2(88.47,46.08) 87.92,46.62 86,46.62 85.42,47.2 JXDP1.56
  IN1 w0.102: v2(118.95,48.84) 119.03,48.93 119.03,53.83 120.98,55.78 124.74,55.78 v2(128.89,59.93)
  BOTTOM w0.076: 129.42,60.36 130.41,60.36 130.91,59.86 131.79,59.86 131.95,60.02 131.97,60.02 131.97,60.03 132.33,60.03 132.51,60.21 132.51,60.45 132.68,60.62 133.2,60.62 UC1.AD61
  BOTTOM w0.102: v2(118.95,48.84) 119.33,48.46 119.33,47.95 118.95,47.57 118.95,45.62 116.32,42.99 90.27,42.99 88.29,44.97 88.29,45.9 v2(88.47,46.08) 89.58,47.19 89.58,53.77 91.41,55.6 92.95,55.6 RC99.1 ; v2(128.89,59.93) 129.32,60.36 129.42,60.36
PCH_JTAG_TDO: length 90.7
  TOP w0.102: v4(88.66,43.46) 88.72,43.52 v2(88.72,45.14) ; RC15.1 138.6,62.29 138.6,60.31 137.4,59.1 137.4,58.59 137.18,58.38 136.34,58.38 134.71,60.01 v2(133.15,60.01)
  IN1 w0.102: v2(118.92,48.21) 118.75,48.03 117.84,48.03 117.55,48.32 117.55,54.14 120.41,57 124,57 128.95,61.95 131.21,61.95 v2(133.15,60.01)
  BOTTOM w0.076: UC1.AE61 133.46,59.71 133.19,59.97 v2(133.15,60.01)
  BOTTOM w0.102: v2(118.92,48.21) 118.5,47.79 118.5,45.75 116.15,43.4 90.46,43.4 v2(88.72,45.14) 88.72,45.75 89.99,47.02 89.99,53.54 91.6,55.16 93.34,55.16 93.98,55.79 93.98,56.69 RC118.2 RC98.1
PCH_JTAG_TMS: length 94.3
  TOP w0.102: v2(130.11,59.93) 130.11,59.71 130.29,59.53 134.67,59.53 136.12,58.08 137.73,58.08 138.2,58.56 138.2,59.46 138.93,60.18 138.93,61.72 RC16.1 ; JXDP1.58 85.24,46.7 v2(85.35,46.59) ; v2(118.06,49.06) 118.14,49.06 v4(118.59,49.52)
  IN1 w0.102: v2(130.11,59.93) 129.23,60.81 128.41,60.81 124.19,56.59 120.58,56.59 118.06,54.06 v2(118.06,49.06)
  BOTTOM w0.076: UC1.AD62 132.81,60.27 132.4,59.86 132.04,59.86 132.04,59.86 132.02,59.86 131.72,59.56 130.48,59.56 v2(130.11,59.93)
  BOTTOM w0.102: UC7.9 87.94,56.83 86.95,55.84 86.95,48.6 85.35,47 v2(85.35,46.59) 86.12,45.82 87.11,45.82 87.44,45.49 87.44,44.55 89.41,42.58 116.52,42.58 119.36,45.43 119.36,47.42 119.73,47.79 119.73,48.63 119.11,49.25 118.24,49.25 v2(118.06,49.06)
PCH_JTAG_TRST#: length 68.4
  TOP w0.102: v2(88.31,42.06) v4(88.31,41.24)
  BOTTOM w0.081: 130.54,51.54 131.81,52.8 131.81,52.94 132.06,53.19 132.46,53.19 UC1.AU62
  BOTTOM w0.102: RC109.2 86.55,56.62 86.55,50.34 84.94,48.74 84.94,43.74 85.8,42.89 87.48,42.89 v2(88.31,42.06) 88.68,41.68 120.68,41.68 130.54,51.54 130.54,51.54
PCH_OPI_COMP: length 6.3
  BOTTOM w0.076: RC178.1 v1(165.14,46.98)
  BOTTOM w0.081: UC1.AW15 162.16,51.52
  BOTTOM w0.152: 163.07,49.25 163.07,49.44 162.75,49.76 162.75,50.58 162.56,50.77 162.56,51.12 162.16,51.52
  BOTTOM w0.381: 163.07,49.25 164.21,48.11 RC178.1
PCH_PCIE_RCOMP: length 9.6
  BOTTOM w0.305: UC1.A27 154.91,73.54 154.91,76.21 v4(154.28,76.85)
  BOTTOM w0.381: RC149.2 150.47,78.64 151.78,77.32 153.8,77.32 v4(154.28,76.85)
PCH_PCIE_WAKE#: length 115.8
  TOP w0.076: 169.56,56.24 168.9,56.24 168.48,56.65 167.68,56.65 167.5,56.83 167.5,57.8 v2(167.8,58.1)
  TOP w0.102: 177.76,47.57 177.76,45.88 177.81,45.83 RPC1.5 ; 177.76,47.57 177.52,47.81 176.79,47.81 176.58,48.03 175.65,48.03 173.07,50.61 173.07,53.01 171.98,54.1 171.69,54.1 169.56,56.24 ; 177.76,47.57 178.05,47.87 178.13,47.87 178.14,47.88 179.25,47.88 179.58,48.21 180.89,48.21 180.98,48.3 v1(180.98,48.3) 180.98,49.06 182.32,50.41 183.59,50.41 183.92,50.74 RE274.2 184.17,51.55 184.29,51.55 184.49,51.75 v2(185.53,51.75) ; UE2.A44 260.69,36.24 v2(260.37,35.93)
  IN1 w0.102: v2(185.53,51.75) 185.63,51.85 189.43,51.85 189.82,52.24 197.06,52.24 202.62,46.68 204.02,46.68 209.66,41.05 215.73,41.05 215.91,40.87 230.09,40.87 v2(230.22,40.73)
  IN2 w0.102: v2(260.37,35.93) 258.77,37.53 255.18,37.53 254.26,38.44 244.85,38.44 243.77,37.36 242.05,37.36 241.03,36.34 233.98,36.34 233.14,37.18 233.14,38.4 231.73,39.81 231.14,39.81 v2(230.22,40.73)
  BOTTOM w0.076: UC1.AJ5 168.15,57.73 167.8,58.08 v2(167.8,58.1)
PCH_PLTRST#: length 38.7
  TOP w0.102: 187.81,72.06 187.12,72.06 186.54,71.48 186.54,69.94 186.15,69.56 v2(186.15,63.94) ; 187.81,72.06 188.33,72.06 188.46,71.92 UC5.2 188.46,70.92 188.6,70.79 189.79,70.79 190.27,71.27 RC89.2 190.27,74.6 RC88.2 ; 187.81,72.06 UC5.1
  IN1 w0.102: v2(186.15,63.94) 185.67,63.94 184.23,62.5 181.41,62.5 180.14,61.23 178.31,61.23 176.88,59.79 174.75,59.79 174.29,59.33 168.82,59.33 168.65,59.5 167.57,59.5 v2(167.17,59.11)
  BOTTOM w0.076: UC1.AG7 167.17,58.92 167.17,59.11 v2(167.17,59.11)
PCH_PLTRST#_EC: length 430.6
  TOP w0.102: UZ1.16 201.96,83.43 202.27,83.12 v2(204.92,83.12) ; UC5.4 189.11,74.33 RC304.1 189.38,75.87 v1(189.48,75.97) 189.85,76.34 v2(190.01,76.34) ; JLPDE1.8 274.06,59.54 273.02,58.51 273.02,54.27 273.97,53.32 v2(273.97,53.31) ; UE2.B30 254.7,40.46 254.77,40.54 255.5,40.54 v2(256.03,41.07) ; RC106.1 85.87,51.27 v2(85.37,51.27)
  IN1 w0.102: v2(256.03,41.07) 256.29,41.33 256.93,41.33 259.66,44.06 259.66,44.86 260.6,45.8 260.6,47.73 261.07,48.2 261.07,49.85 260.94,49.98 260.94,54.29 257.26,57.97 256.82,57.97 256.27,58.52 256.27,59.13 255.47,59.93 250.24,59.93 v2(247.18,62.99) ; v2(241.72,63.98) 236.98,68.72 236.98,75.86 234.6,78.23 234.13,78.23 230.61,81.76 230.61,82.6 228.19,85.01 206.82,85.01 204.92,83.12 v2(204.92,83.12)
  IN2 w0.102: v2(281.79,17.73) 281.3,17.25 271.32,17.25 270.46,16.38 268.65,16.38 268.11,15.84 268.11,15.82 267.85,15.57 260.11,15.57 259.8,15.87 257.93,15.87 256.58,17.23 255.17,17.23 254.86,17.55 254.25,18.15 251.81,18.15 251.6,17.94 243.31,17.94 v2(242.5,18.74) ; v2(241.72,63.98) 246.19,63.98 v2(247.18,62.99) ; v2(85.37,51.27) 85.3,51.27 84.67,51.9 84.67,53.24 85.16,53.73 85.89,53.73 86.28,54.13 92.1,54.13 93.65,55.68 93.65,57.05 94.05,57.45 94.05,59.72 95.69,61.36 95.69,73.35 100.61,78.27 103.92,78.27 107.13,81.47 119.6,81.47 v2(120.11,80.96) ; v2(204.92,83.12) 201.72,83.12 200.66,82.05 v2(194.07,82.05) ; v2(256.03,41.07) 256.83,41.07 258.76,43 261.31,43 261.85,42.47 263.15,42.47 264.09,43.41 271.02,43.41 272.49,44.88 273.38,44.88 273.97,45.47 v2(273.97,53.31)
  BOTTOM w0.102: JNGFF1.44 240.01,21.1 239.68,20.77 239.68,17.89 239.98,17.6 JNGFF1.58 242.13,17.6 242.5,17.97 v2(242.5,18.74) ; v2(190.01,76.34) 194.07,80.39 v2(194.07,82.05) ; v2(120.11,80.96) 120.54,81.39 122.68,81.39 126.19,84.91 129.31,84.91 131.95,87.55 131.95,91.41 137.58,97.04 189.67,97.04 194.59,92.13 201.64,92.13 204.92,88.84 v2(204.92,83.12) ; v2(273.97,53.31) 273.97,53.31 283.23,44.05 284.12,44.05 284.65,43.52 290.5,43.52 293.48,40.54 297.79,40.54 300.17,38.15 300.17,35.48 298.48,33.79 298.48,30.35 286.41,18.27 282.33,18.27 v2(281.79,17.73)
PCH_RSMRST#: length 13.2
  TOP w0.102: UE2.A45 261.19,34.95 260.82,34.58 260.82,33.54 RE88.1 260.16,32.16 260.51,31.8 264.12,31.8 264.81,32.49 v1(264.83,32.49) 265.39,32.49 266.35,33.45 UZ6.1
PCH_RSMRST#_Q: length 150.8
  TOP w0.102: v2(172.72,34.52) 172.72,35.93 166.25,42.4 166.25,44.79 167.04,45.58 167.78,45.58 168.12,45.93 168.12,46.64 167.78,46.99 RC91.2 v1(167.07,48.27) 167.07,48.45 v2(167.87,49.26) ; v2(229.07,7.67) 226.77,7.67 v2(224.75,9.69) ; UZ6.4 268.65,32.15 268.34,31.84 268.34,31.34 267.48,30.49 264.03,30.49 263.45,31.08 260.11,31.08 259,32.18 v2(258.23,32.18)
  IN1 w0.102: v2(252.63,28.14) 255.76,31.28 257.32,31.28 v2(258.23,32.18)
  IN2 w0.102: v2(172.72,34.52) 172.72,34.4 174.91,32.21 176.94,32.21 188.11,21.03 188.11,17.97 190.5,15.58 219.44,15.58 219.96,15.06 219.96,14.64 222.07,12.53 222.07,10.75 223.13,9.69 v2(224.75,9.69)
  BOTTOM w0.076: v2(167.87,49.26) 167.53,49.26 166.96,49.83 166.96,50.52 167.1,50.66 167.1,50.67 167.11,50.68 167.11,51.23 UC1.AW6
  BOTTOM w0.102: v2(229.07,7.67) 230.73,7.67 234.97,11.91 239.9,11.91 240.13,11.68 245.17,11.68 246.12,12.64 246.12,14.95 247.52,16.34 247.52,21.83 252.63,26.94 v2(252.63,28.14)
PCH_RTCRST#: length 169.2
  TOP w0.102: v2(299.41,26.19) JAPS1.9 v4(302.27,26.19)
  IN2 w0.102: v2(265.69,19.33) 265.47,19.55 260.44,19.55 259.72,18.83 258.62,18.83 257.64,19.81 255.92,19.81 252.73,23 250.23,23 249.67,22.45 245.65,22.45 244.97,23.12 235.52,23.12 231.9,26.75 229.44,26.75 228.09,25.4 197.48,25.4 182.39,40.49 v2(182.39,40.9) 181.3,42 178.64,42 174.7,45.94 174.7,46.4 172.13,48.97 170.25,48.97 169.4,49.82 168.87,49.82 168.66,50.03 168.66,50.89 v2(167.07,52.48)
  BOTTOM w0.076: UC1.AU7 166.73,52.83 167.07,52.48 v2(167.07,52.48)
  BOTTOM w0.102: v2(265.69,19.33) 266.84,18.19 271.19,18.19 271.96,17.42 274.47,17.42 275.97,15.93 285.98,15.93 296.24,26.19 v2(299.41,26.19) ; CMOS1.2 186.76,43.83 RC8.2 CC4.2 187.72,41.86 186.76,40.9 v2(182.39,40.9)
PCH_RTCX1: length 18.8
  BOTTOM w0.076: 172.84,49.21 172.5,49.55 169.19,49.55 168.52,50.22 168.52,51.17 UC1.AW5
  BOTTOM w0.102: 172.84,49.21 174.14,47.91 174.14,47.05 175.14,46.05 v4(176.38,46.05) 177.47,46.05 178.42,45.1 181.61,45.1 RC4.2 RC7.1
PCH_RTCX1_R: length 3.3
  BOTTOM w0.102: YC1.1 181.18,47.59 CC1.2 RC4.1
PCH_RTCX2: length 22.9
  BOTTOM w0.076: UC1.AY5 168.2,50.14
  BOTTOM w0.102: 168.2,50.14 169.22,49.12 172.21,49.12 173.66,47.67 173.66,46.85 175.93,44.58 v4(177.78,44.58) 182.99,44.58 RC7.2 CC2.2 184,47.91 YC1.2
PCH_SMB_ALERT#: length 9.4
  BOTTOM w0.076: 173.36,57.25 173.04,57.25 172.6,56.82 172.6,56.64 171.46,55.5 170.59,55.5 UC1.AN2
  BOTTOM w0.102: 173.36,57.25 174.25,57.25 175.59,58.58 v1(176.15,58.58) 176.53,58.58 177.29,59.35 RPC19.2
PCH_SPI_CLK: length 63.9
  TOP w0.102: v2(189.71,88.1) 189.71,89.2 190.69,90.18 199.65,90.18 200.15,89.69 200.15,87.68 RZ26.1 ; RC227.2 182.8,79.3 v2(182.65,79.16)
  IN1 w0.102: v2(182.65,79.16) 183.23,79.16 184.16,78.23 v2(184.16,77.25) 184.16,74.44 177.98,68.25 177.98,64.77 176.03,62.83 175.26,62.83 174.63,62.19 174.39,62.19 173.84,61.63 172.79,61.63 v2(172.48,61.32)
  BOTTOM w0.076: v2(172.48,61.32) 171.92,60.76 170.67,60.76 170.51,60.59 169.63,60.59 169.54,60.69 169.4,60.69 169.16,60.92 169.16,61.51 UC1.AA3
  BOTTOM w0.102: v2(189.71,88.1) 189.71,86.8 190.6,85.91 190.6,79.03 189.13,77.56 185.77,77.56 185.05,76.83 184.58,76.83 v2(184.16,77.25) ; v2(182.65,79.16) 182.88,79.39 JSPI1.8
PCH_SPI_CS0#: length 32.1
  TOP w0.102: RC228.2 183.82,78.62 v2(183.45,78.25)
  IN1 w0.102: v2(183.45,78.25) 182.98,78.25 182.23,77.49 182.23,73.84 176.83,68.44 176.83,66.11 174.83,64.1 174.83,63.73 173.31,62.22 171.55,62.22 171.26,62.51 167.56,62.51 v2(167.16,62.91)
  BOTTOM w0.076: v2(167.16,62.91) 167.16,62.72 UC1.Y7
  BOTTOM w0.102: v2(183.45,78.25) 183.88,78.68 JSPI1.10
PCH_SPI_CS1#: length 28.1
  TOP w0.102: v2(180.69,79.06) 179.75,79.99 RC224.2
  IN1 w0.102: v2(171.75,62.58) 172.11,62.94 173.39,62.94 174.29,63.85 174.29,64.28 176.2,66.19 176.2,68.53 181.33,73.66 181.33,77.02 180.69,77.67 v2(180.69,79.06)
  BOTTOM w0.076: UC1.Y4 169.02,62.5 169.4,62.12 170.3,62.12 170.43,62.25 170.9,62.25 171.24,62.58 v2(171.75,62.58)
  BOTTOM w0.102: JSPI1.2 179.88,79.85 180.68,79.06 v2(180.69,79.06)
PCH_SPI_CS2#: length 56.4
  TOP w0.102: v2(185.53,75.68) 185.53,76.72 187.07,78.26 188.38,78.26 190.19,80.07 v1(190.19,85.89) 190.19,88.58 190.87,89.26 196.12,89.26 197.94,87.43 RZ17.1
  IN2 w0.102: v2(169.85,61.42) 169.85,62.43 170.19,62.78 170.19,64.64 170.81,65.26 173.41,65.26 173.71,64.96 175.49,64.96 175.79,65.26 177.2,65.26 177.86,64.6 181.19,64.6 182.03,65.44 183.6,65.44 184.66,64.39 v2(184.66,64.39)
  BOTTOM w0.076: v2(169.85,61.42) 170.13,61.13 UC1.AC2
  BOTTOM w0.102: v2(184.66,64.39) 185.19,64.92 185.19,70.32 184.87,70.64 184.87,75.02 v2(185.53,75.68)
PCH_SPI_CS2#_R: length 2
  TOP w0.102: RZ17.2 198.06,86.22 UZ1.22
PCH_SPI_DIN: length 56.9
  TOP w0.102: RZ30.1 194.04,87.68 191.06,87.68 v2(190.64,88.1) ; v2(183.16,76.43) 182.14,77.44 182.14,79.22 181.78,79.58 RC226.2
  IN1 w0.102: v2(183.16,76.43) 183.16,74.12 177.49,68.45 177.49,64.97 175.85,63.32 175.06,63.32 173.59,61.85 172.33,61.85 171.8,61.33 170.94,61.33 170.31,61.96 v2(168.32,61.96)
  BOTTOM w0.076: UC1.AA4 168.45,61.83 v2(168.32,61.96)
  BOTTOM w0.102: JSPI1.6 181.88,79.49 182.15,79.22 182.15,77.43 v2(183.16,76.43) 183.25,76.34 185.25,76.34 185.94,77.02 189.28,77.02 191.08,78.83 191.08,86.37 190.64,86.82 v2(190.64,88.1)
PCH_SPI_DO: length 56.3
  TOP w0.102: v2(181.59,78.16) 181.59,79.1 180.77,79.92 RC225.2 ; v2(191.81,88.1) 192.69,88.99 195.96,88.99 197.05,87.89 RZ29.1
  IN1 w0.102: v2(181.59,78.16) 181.59,73.56 176.53,68.49 176.53,66.19 174.56,64.22 174.56,63.79 173.35,62.58 v2(172.34,62.58)
  BOTTOM w0.076: v2(172.34,62.58) 171.99,62.23 171.54,62.23 171.46,62.31 171.2,62.31 171.01,62.12 171.01,62.12 170.97,62.08 170.67,62.08 170.66,62.08 170.53,62.08 170.23,61.79 UC1.AA2
  BOTTOM w0.102: JSPI1.4 180.88,79.81 181.59,79.1 v2(181.59,78.16) 181.8,77.95 181.8,76.81 182.59,76.02 183.33,76.02 183.41,76.1 185.33,76.1 186.03,76.8 189.37,76.8 191.31,78.74 191.31,87.6 v2(191.81,88.1)
PCH_SPI_DO2: length 34.2
  TOP w0.102: v2(183.75,77.75) 184.83,78.83 RC229.2
  IN1 w0.102: v2(183.75,77.75) 183.04,77.75 182.52,77.23 182.52,73.81 177.15,68.43 177.15,66.05 175.09,63.99 175.09,63.68 173.45,62.04 172.22,62.04 171.73,61.54 171.09,61.54 170.32,62.32 167.48,62.32 v2(167.1,61.94)
  BOTTOM w0.076: v2(167.1,61.94) 167.5,62.34 UC1.Y6
  BOTTOM w0.102: JSPI1.12 184.88,78.88 v2(183.75,77.75)
PCH_SPI_DO3: length 33.1
  TOP w0.102: RC230.2 185.85,78.78 184.76,77.69 v2(184.76,77.25)
  IN1 w0.102: v2(173.3,60.96) 174.29,60.96 174.66,61.33 175.14,61.33 175.6,61.78 176.39,61.78 179.54,64.94 179.54,66.21 184.03,70.7 184.03,73.49 184.76,74.22 v2(184.76,77.25)
  BOTTOM w0.076: UC1.AF1 170.89,59.44 171.85,59.44 172.09,59.67 172.63,59.67 172.9,59.93 172.9,60.55 v2(173.3,60.96)
  BOTTOM w0.102: v2(184.76,77.25) 184.76,77.69 185.88,78.82 JSPI1.14
PCI_CLK_LPC_0: length 13.5
  TOP w0.102: v2(162.22,54.8) 161.16,53.74 161.16,51.24 160.6,50.69 160.6,50.06 160.47,49.94 v1(160.47,46.27) 160.47,45.87 161.03,45.31 161.03,43.09 RC74.1
  BOTTOM w0.076: v2(162.22,54.8) 162.53,55.11 UC1.AN15
PCI_CLK_LPC_1: length 12.5
  TOP w0.102: RC67.1 161.39,43.18 161.39,45.96 161.1,46.25 v1(161.1,47.92) 161.1,49.61 161.29,49.8 161.29,50.44 161.77,50.93 161.77,53.72 v2(162.21,54.16)
  BOTTOM w0.076: UC1.AP15 162.51,54.45 v2(162.21,54.16)
PCIE_PRX_GLANTX_N3: length 142.3
  TOP w0.102: CL2.2 259.01,92.15 259.01,92.49 258.82,92.68 258.82,93.38 v2(258.64,93.56)
  IN2 w0.086: v2(245.51,75.07) 245.32,75.26 245.32,75.5 240.57,80.25 240.57,80.87 239.25,82.19 238.73,82.19 235.31,85.61 232.33,85.61 230.82,87.12 219.34,87.12 218.76,87.69 184.91,87.69 184.26,88.34 177.8,88.34 176.83,87.37 176.83,87.02 v2(176.65,86.83) ; v2(163.95,70.02) 164.19,70.25 164.37,70.25 164.55,70.43 164.55,71.73 166.09,73.27 171.14,73.27 172.01,72.39 172.79,72.39 v2(172.92,72.26)
  BOTTOM w0.076: UC1.G11 164.37,69.59 v2(163.95,70.02)
  BOTTOM w0.102: v2(258.64,93.56) 258.83,93.75 258.83,94.3 258.59,94.54 257.07,94.54 255.28,96.33 253.59,96.33 253.11,95.85 253.11,91.22 250.79,88.9 246.34,88.9 245.18,87.74 245.18,76.4 245.32,76.26 245.32,75.25 v2(245.51,75.07) ; v2(172.92,72.26) 172.74,72.45 172.04,72.45 171.21,73.28 171.21,75.9 176.11,80.8 176.11,84.73 176.83,85.46 176.83,86.65 v2(176.65,86.83)
PCIE_PRX_GLANTX_N3_C: length 2.7
  TOP w0.102: CL2.1 258.94,90.65 258.94,90.37 258.8,90.24 258.58,90.24 258.11,89.77 258.11,89.36 258.03,89.27 UL1.39
PCIE_PRX_GLANTX_P3: length 142.2
  TOP w0.102: CL1.2 259.23,92.16 259.23,92.58 259.04,92.77 259.04,93.38 v2(259.22,93.56)
  IN2 w0.086: v2(163.95,70.66) 164.19,70.43 164.3,70.43 164.37,70.5 164.37,71.8 166.02,73.44 171.21,73.44 172.08,72.57 172.64,72.57 v2(172.92,72.85) ; v2(244.92,75.07) 245.15,75.29 245.15,75.43 240.4,80.18 240.4,80.8 239.18,82.02 238.66,82.02 235.24,85.43 232.26,85.43 230.75,86.94 219.26,86.94 218.69,87.52 184.84,87.52 184.19,88.16 177.87,88.16 177.01,87.3 177.01,87.05 v2(177.23,86.83)
  BOTTOM w0.076: UC1.F11 163.95,70.66 v2(163.95,70.66)
  BOTTOM w0.102: v2(172.92,72.85) 172.74,72.66 172.13,72.66 171.42,73.37 171.42,75.81 171.91,76.3 172.78,77.17 176.32,80.71 176.32,84.64 177.05,85.37 177.05,86.65 v2(177.23,86.83) ; v2(259.22,93.56) 259.05,93.74 259.05,94.39 258.68,94.75 257.16,94.75 255.37,96.54 253.5,96.54 252.89,95.94 252.89,91.31 250.7,89.12 246.25,89.12 244.97,87.83 244.97,76.31 245.11,76.17 245.11,75.25 v2(244.92,75.07)
PCIE_PRX_GLANTX_P3_C: length 2.8
  TOP w0.102: CL1.1 259.15,90.48 259.15,90.28 258.89,90.02 258.67,90.02 258.33,89.68 258.33,89.37 258.43,89.27 UL1.38
PCIE_PRX_MMITX_N1: length 152.8
  TOP w0.102: CR27.1 276.42,29.92 276.08,29.92 v2(275.87,29.71)
  IN2 w0.086: v2(161.01,69.82) 161.01,70.04 161.12,70.15 161.3,70.15 161.43,70.02 161.43,68.52 161.94,68.01 165.16,68.01 166.25,69.11 166.25,69.93 166.6,70.27 167.94,70.27 168.62,69.58 171.78,69.58 173.61,67.75 180.74,67.75 180.87,67.62 183.93,67.62 187.19,64.37 187.19,63.46 187.5,63.15 187.5,61.47 187.91,61.06 187.91,59.52 187.54,59.15 187.54,55.3 187.74,55.11 187.74,52.5 187.52,52.28 187.52,44.44 199.26,32.7 222.4,32.7 223.78,31.31 227.14,31.31 228.18,32.35 235.33,32.35 237.16,30.51 240.65,30.51 241.44,29.72 246.04,29.72 248.59,27.17 263.59,27.17 265.71,29.29 267.61,29.29 269.32,31 274.21,31 275.28,29.93 275.65,29.93 v2(275.87,29.71)
  BOTTOM w0.076: v2(161.01,69.82) 161.28,69.82 UC1.G17
PCIE_PRX_MMITX_N1_C: length 4.5
  TOP w0.102: CR27.2 278.02,29.91 278.5,29.91 278.58,30 278.61,30 279.13,30.52 280.5,30.52 280.57,30.44 281.07,30.44 281.21,30.31 UR1.8
PCIE_PRX_MMITX_P1: length 152.9
  TOP w0.102: CR26.1 276.44,30.14 275.96,30.14 v2(275.79,30.31)
  IN2 w0.086: v2(275.79,30.31) 275.59,30.11 275.35,30.11 274.28,31.18 269.25,31.18 267.54,29.47 265.64,29.47 263.52,27.34 248.66,27.34 246.11,29.9 241.51,29.9 240.72,30.69 237.23,30.69 235.4,32.52 228.1,32.52 227.07,31.49 223.86,31.49 222.47,32.87 199.33,32.87 187.7,44.51 187.7,52.21 187.91,52.43 187.91,55.18 187.72,55.37 187.72,59.08 188.09,59.45 188.09,61.13 187.68,61.54 187.68,63.22 187.37,63.53 187.37,64.44 184.01,67.8 180.94,67.8 180.81,67.93 173.69,67.93 171.86,69.76 168.69,69.76 168.01,70.44 166.52,70.44 166.08,70 166.08,69.18 165.09,68.19 162.01,68.19 161.6,68.59 161.6,70.09 161.37,70.32 161.16,70.32 161.01,70.47 v2(161.01,70.65)
  BOTTOM w0.076: UC1.F17 161.38,70.24 161.01,70.6 v2(161.01,70.65)
PCIE_PRX_MMITX_P1_C: length 4.4
  TOP w0.102: CR26.2 278.01,30.13 278.41,30.13 v3(278.64,30.36) 279.02,30.73 280.59,30.73 280.66,30.66 281.16,30.66 281.16,30.66 281.21,30.71 UR1.7
PCIE_PRX_WIGIGTX_N5: length 114.5
  IN2 w0.086: v2(224.28,32.56) 224.69,32.97 224.69,33.14 223.48,34.35 199.43,34.35 188.81,44.97 188.81,48.67 189.28,49.14 189.28,52.84 189.02,53.09 189.02,58.17 189.21,58.37 189.21,63.28 188.48,64.02 188.48,64.94 184.49,68.92 181.71,68.92 181.26,69.37 175.3,69.37 173.62,71.05 171.36,71.05 169.93,72.48 168.82,72.48 167.99,71.65 165.88,71.65 165.69,71.46 165.69,71.18 165.38,70.87 165.05,70.87 164.96,70.78 v2(164.96,70.59)
  BOTTOM w0.076: v2(164.96,70.59) 165.31,70.24 UC1.F10
  BOTTOM w0.102: v2(224.28,32.56) 224.41,32.43 224.41,30.48 222.53,28.6 222.53,22.06 223.15,21.44 224.23,21.44 225.73,19.94 229.09,19.94 v3(231.36,17.67) 231.68,17.35 232.56,17.35 232.56,17.35 JNGFF1.59
PCIE_PRX_WIGIGTX_P5: length 114.5
  IN2 w0.086: v2(224.86,32.56) 224.86,33.21 223.55,34.52 199.5,34.52 188.98,45.04 188.98,48.59 189.45,49.06 189.45,52.91 189.2,53.16 189.2,58.1 189.39,58.29 189.39,63.35 188.65,64.09 188.65,65.01 184.56,69.1 181.78,69.1 181.33,69.54 175.37,69.54 173.7,71.22 171.43,71.22 170,72.65 168.75,72.65 167.92,71.83 165.81,71.83 165.52,71.54 165.52,71.26 165.31,71.04 165.12,71.04 v2(164.91,71.25)
  BOTTOM w0.076: v2(164.91,71.25) 164.96,71.25 UC1.E10
  BOTTOM w0.102: JNGFF1.57 233.34,17.85 232.36,17.85 232.32,17.8 232.32,17.64 232.24,17.56 231.79,17.56 231.31,18.04 231.3,18.04 229.18,20.15 225.82,20.15 224.32,21.65 223.24,21.65 222.74,22.15 222.74,28.51 224.21,29.98 224.62,30.39 224.62,32.32 v2(224.86,32.56)
PCIE_PRX_WLANTX_N4: length 114.5
  IN2 w0.086: v2(162.98,70.63) 162.98,70.59 163.18,70.39 163.38,70.39 163.59,70.18 163.59,69.09 163.76,68.91 165,68.91 165.33,69.24 165.33,70.13 166.36,71.16 168.03,71.16 168.24,70.94 170.53,70.94 170.98,70.5 172.31,70.5 173.91,68.9 180.97,68.9 181.43,68.44 184.27,68.44 188.01,64.71 188.01,63.82 188.32,63.51 188.32,61.81 188.73,61.4 188.73,59.18 188.36,58.81 188.36,55.67 188.55,55.47 188.55,52.9 188.7,52.76 188.7,49.22 188.34,48.86 188.34,44.77 199.59,33.52 222.73,33.52 224.13,32.13 226.79,32.13 228.1,33.45 229.97,33.45 v2(230.1,33.57)
  BOTTOM w0.076: UC1.F13 163.35,70.24 162.98,70.6 v2(162.98,70.63)
  BOTTOM w0.102: JNGFF1.35 232.56,23.35 230.13,23.35 228.65,24.83 228.65,26.87 229.11,27.33 229.11,33.29 229.39,33.57 v2(230.1,33.57)
PCIE_PRX_WLANTX_P4: length 114.5
  IN2 w0.086: v2(230.1,32.99) 229.89,33.19 229.89,33.2 229.82,33.27 228.18,33.27 226.86,31.96 224.05,31.96 222.66,33.35 199.52,33.35 188.17,44.7 188.17,48.93 188.52,49.29 188.52,52.68 188.38,52.83 188.38,55.4 188.18,55.59 188.18,58.89 188.55,59.26 188.55,61.33 188.14,61.74 188.14,63.43 187.83,63.74 187.83,64.63 184.2,68.27 181.35,68.27 180.89,68.73 173.83,68.73 172.24,70.32 170.9,70.32 170.46,70.77 168.17,70.77 167.95,70.98 166.43,70.98 165.5,70.05 165.5,69.16 165.07,68.73 163.69,68.73 163.41,69.01 163.41,70.11 163.31,70.21 163.11,70.21 162.99,70.1 v2(162.99,69.95)
  BOTTOM w0.076: UC1.G13 163.42,69.77 163.25,69.95 v2(162.99,69.95)
  BOTTOM w0.102: v2(230.1,32.99) 229.92,33.16 229.92,33.17 229.73,33.36 229.48,33.36 229.32,33.2 229.32,27.24 228.86,26.78 228.86,24.92 230.21,23.57 230.47,23.57 230.65,23.75 230.98,23.75 231.16,23.57 231.58,23.57 231.7,23.68 232.05,23.68 232.17,23.57 232.36,23.57 232.45,23.65 232.45,23.76 232.53,23.85 JNGFF1.33
PCIE_PTX_GLANRX_N3: length 136.6
  TOP w0.102: CL6.1 257.25,92.16 257.25,92.73 257.62,93.1 257.62,93.39 v2(257.43,93.57)
  IN2 w0.086: v2(257.43,93.57) 257.44,93.57 257.84,93.98 257.84,94.31 257.76,94.39 247.39,94.39 244.37,91.36 236.19,91.36 234.76,92.79 222.77,92.79 222.33,93.24 218.99,93.24 218.55,92.79 207.73,92.79 207.27,93.26 157.54,93.26 157.44,93.15 152.46,93.15 152.31,93 152.05,93 151.9,93.15 151.57,93.15 151.41,92.99 151.11,92.99 150.95,93.15 150.8,93.15 150.66,93.01 150.66,92.82 v2(151.07,92.4)
  BOTTOM w0.076: 151.74,76.3 151.74,76.3 152.31,76.3 152.33,76.29 152.33,76.27 153.4,75.2 153.4,73.95 153.27,73.82 153.27,72.63 153.56,72.34 UC1.C29
  BOTTOM w0.102: v2(151.07,92.4) 151.07,85.95 150.54,85.42 150.54,81.32 149.71,80.48 149.71,78.33 151.74,76.3
PCIE_PTX_GLANRX_N3_C: length 2.5
  TOP w0.102: UL1.42 256.83,89.25 256.94,89.37 256.94,90.03 257.26,90.35 257.26,90.55 CL6.2
PCIE_PTX_GLANRX_P3: length 136.6
  TOP w0.102: v2(258.02,93.57) 257.83,93.39 257.83,93.01 257.46,92.65 257.46,92.14 CL5.1
  IN2 w0.086: v2(150.49,92.4) 150.48,92.4 150.48,93.09 150.72,93.33 157.37,93.33 157.47,93.43 207.34,93.43 207.8,92.97 218.47,92.97 218.92,93.42 222.4,93.42 222.85,92.97 234.83,92.97 236.26,91.54 244.3,91.54 247.32,94.56 257.84,94.56 258.02,94.38 v2(258.02,93.57)
  BOTTOM w0.076: UC1.B30 152.93,72.53 152.79,72.67 152.79,72.76 152.88,72.85 152.99,72.85 153.08,72.93 153.08,73.9 153.21,74.03 153.21,75.12 152.22,76.11 151.62,76.11 151.43,76.3
  BOTTOM w0.102: 151.43,76.3 149.49,78.24 149.49,80.57 150.33,81.41 150.33,85.51 150.85,86.04 150.85,92.04 v2(150.49,92.4)
PCIE_PTX_GLANRX_P3_C: length 2.4
  TOP w0.102: UL1.41 257.23,89.27 257.16,89.33 257.16,89.94 257.48,90.26 257.48,90.58 CL5.2
PCIE_PTX_MMIRX_N1: length 163.2
  TOP w0.102: v2(275.79,32.16) 276.03,31.93 276.46,31.93 276.77,32.23 CR25.1
  IN2 w0.086: v2(151.73,74.9) 151.93,74.7 152.13,74.7 153.42,75.98 158.71,75.98 159.35,76.63 163.88,76.63 164.14,76.88 173.1,76.88 174.74,75.24 174.74,73.27 176.51,71.5 182.11,71.5 182.53,71.92 184.48,71.92 190.61,65.79 190.61,64.87 191.67,63.81 191.67,61.63 192.56,60.74 192.56,44.98 201.09,36.45 225.59,36.45 227.79,34.25 230.73,34.25 231.67,33.31 235.52,33.31 237.5,31.33 240.61,31.33 240.74,31.46 250.3,31.46 250.52,31.24 252.66,31.24 253.8,30.11 267.24,30.11 268.95,31.82 275.52,31.82 275.6,31.9 275.68,31.9 275.79,32.02 v2(275.79,32.16)
  BOTTOM w0.076: v2(151.73,74.9) 151.87,74.75 152.16,74.75 152.35,74.56 152.35,73.91 152.14,73.7 arc(152.11,73.67) 152.09,73.63 arc(152.08,73.53) 152.13,73.45 arc(152.22,73.21) 152.14,72.96 arc(152.11,72.86) 152.15,72.76 152.25,72.64 152.59,72.46 152.65,72.39 UC1.C30
PCIE_PTX_MMIRX_N1_C: length 4.4
  TOP w0.102: UR1.5 281.21,31.51 281.13,31.42 280.77,31.42 280.76,31.43 280.23,31.43 280.21,31.42 279.31,31.42 v3(279.04,31.69) 278.82,31.91 278.01,31.91 CR25.2
PCIE_PTX_MMIRX_P1: length 163.1
  TOP w0.102: v2(275.79,31.5) 276,31.71 276.41,31.71 CR24.1
  IN2 w0.086: v2(151.73,74.24) 151.73,74.44 151.81,74.52 152.21,74.52 153.49,75.81 158.78,75.81 159.42,76.45 163.96,76.45 164.21,76.7 173.02,76.7 174.56,75.17 174.56,73.2 176.44,71.32 182.18,71.32 182.6,71.75 184.41,71.75 190.44,65.72 190.44,64.8 191.5,63.74 191.5,61.56 192.38,60.67 192.38,44.91 201.02,36.28 225.52,36.28 227.72,34.08 230.66,34.08 231.6,33.13 235.45,33.13 237.43,31.16 240.68,31.16 240.81,31.29 250.23,31.29 250.44,31.07 252.59,31.07 253.72,29.94 267.31,29.94 269.02,31.65 275.65,31.65 v2(275.79,31.5)
  BOTTOM w0.076: UC1.C31 152.44,72.31 152.34,72.4 152.23,72.4 152.16,72.32 152.1,72.32 152.04,72.38 152.04,72.64 152.02,72.65 arc(151.95,72.85) 152.01,73.05 arc(152.06,73.2) 152,73.34 arc(151.92,73.5) 151.94,73.68 151.89,73.73 151.89,73.82 152.02,73.96 152.11,73.96 152.18,74.03 152.18,74.12 152.12,74.18 152.12,74.32 152.18,74.39 152.18,74.49 152.1,74.57 151.9,74.57 151.87,74.55 151.74,74.55 151.65,74.46 151.65,74.32 v2(151.73,74.24)
PCIE_PTX_MMIRX_P1_C: length 4.4
  TOP w0.102: CR24.2 278.02,31.69 278.71,31.69 279.2,31.21 v3(280.52,31.21) 281.11,31.21 281.21,31.11 UR1.6
PCIE_PTX_WIGIGRX_N5: length 119.2
  TOP w0.102: v2(225.62,32.56) 225.75,32.43 225.75,31.82 227.21,30.36 227.21,27.98 227.8,27.39 227.8,24.01 229.16,22.66 v3(229.16,21.51) 229.16,19.21 229.46,18.91 229.84,18.91 CZ22.1
  IN2 w0.086: v2(157.5,74.02) 157.9,74.42 159.23,74.42 159.92,75.11 164.51,75.11 164.75,75.35 172.43,75.35 173.28,74.5 173.28,72.54 175.8,70.01 184.33,70.01 189.12,65.22 189.12,64.29 190.21,63.2 190.21,58.38 189.81,57.98 189.81,56.23 190.67,55.38 190.67,44.81 200.48,34.99 223.98,34.99 225.91,33.06 225.91,32.84 v2(225.62,32.56)
  BOTTOM w0.076: UC1.C23 157.7,72.25 157.64,72.18 157.36,72.18 157.28,72.27 157.28,72.53 157.33,72.58 157.58,72.58 157.64,72.64 157.64,73.15 158,73.51 158,74.16 157.88,74.28 157.76,74.28 v2(157.5,74.02)
PCIE_PTX_WIGIGRX_N5_C: length 2.7
  TOP w0.102: CZ22.2 231.36,19 231.7,19 v2(231.88,18.82)
  BOTTOM w0.102: v2(231.88,18.82) 232.08,19.02 232.39,19.02 232.57,18.85 JNGFF1.53
PCIE_PTX_WIGIGRX_P5: length 119.3
  TOP w0.102: CZ21.1 230.1,19.25 229.97,19.13 229.55,19.13 229.37,19.3 229.37,21.23 229.38,21.25 229.38,21.78 229.37,21.79 229.37,22.75 228.01,24.1 228.01,27.48 227.43,28.07 227.43,30.45 225.97,31.91 225.97,32.33 226.03,32.39 226.03,32.45 226.14,32.56 v2(226.21,32.56)
  IN2 w0.086: v2(226.21,32.56) 226.08,32.68 226.08,33.13 224.05,35.17 200.56,35.17 190.84,44.88 190.84,55.45 189.99,56.3 189.99,57.91 190.39,58.31 190.39,63.27 189.29,64.36 189.29,65.29 184.4,70.19 175.87,70.19 173.45,72.61 173.45,74.58 172.5,75.52 164.68,75.52 164.44,75.28 159.84,75.28 159.16,74.6 157.5,74.6 v2(157.5,74.61)
  BOTTOM w0.076: v2(157.5,74.61) 157.63,74.47 157.96,74.47 158.19,74.24 158.19,73.43 157.83,73.07 157.83,72.76 157.99,72.61 157.99,71.84 UC1.C22
PCIE_PTX_WIGIGRX_P5_C: length 2.7
  TOP w0.102: CZ21.2 231.33,19.21 231.69,19.21 v2(231.88,19.41)
  BOTTOM w0.102: v2(231.88,19.41) 232.04,19.24 232.41,19.24 232.52,19.35 JNGFF1.51
PCIE_PTX_WLANRX_N4: length 116.8
  TOP w0.102: v2(227.01,33.05) 227.24,33.29 227.39,33.29 227.51,33.17 227.51,31.58 228.04,31.05 228.04,28.32 228.62,27.74 228.62,24.64 228.89,24.37 229.2,24.37 CZ14.1
  IN2 w0.086: v2(227.01,33.05) 226.76,33.3 226.58,33.3 224.24,35.63 200.75,35.63 191.73,44.65 191.73,57.5 190.85,58.37 190.85,63.47 189.78,64.54 189.78,65.47 184.59,70.65 176.15,70.65 173.92,72.88 173.92,74.8 172.66,76.06 164.48,76.06 164.22,75.81 159.69,75.81 159,75.12 154.37,75.12 154.12,74.88 154.12,74.64 154.37,74.39 v2(154.45,74.39)
  BOTTOM w0.076: v2(154.45,74.39) 154.45,74.39 154.45,73.8 153.82,73.16 153.75,73.16 153.56,72.97 UC1.B29
PCIE_PTX_WLANRX_N4_C: length 3.5
  TOP w0.102: v2(231.44,24.24) 231.28,24.41 230.8,24.41 CZ14.2
  BOTTOM w0.102: JNGFF1.29 232.64,24.85 232.55,24.94 232.34,24.94 231.85,24.45 231.65,24.45 v2(231.44,24.24)
PCIE_PTX_WLANRX_P4: length 116.7
  TOP w0.102: v2(227.01,33.64) 227.14,33.5 227.48,33.5 227.72,33.26 227.72,31.67 228.25,31.14 228.25,28.41 228.84,27.83 228.84,24.73 228.98,24.59 229.17,24.59 CZ13.1
  IN2 w0.086: v2(227.01,33.64) 226.85,33.48 226.65,33.48 224.32,35.81 200.82,35.81 191.91,44.72 191.91,57.57 191.03,58.45 191.03,63.54 189.95,64.62 189.95,65.55 184.67,70.83 176.22,70.83 174.09,72.96 174.09,74.87 172.73,76.24 164.41,76.24 164.15,75.98 159.62,75.98 158.93,75.3 154.29,75.3 153.95,74.95 153.95,74.47 v2(153.86,74.39)
  BOTTOM w0.076: v2(153.86,74.39) 154.26,73.99 154.26,73.88 154.12,73.74 153.93,73.74 153.86,73.66 153.86,73.47 153.74,73.35 153.62,73.35 153.56,73.41 UC1.A29
PCIE_PTX_WLANRX_P4_C: length 3.5
  TOP w0.102: v2(231.44,24.83) 231.24,24.62 230.75,24.62 CZ13.2
  BOTTOM w0.102: JNGFF1.27 232.65,25.35 232.46,25.16 232.24,25.16 231.75,24.66 231.61,24.66 v2(231.44,24.83)
PCIE_WAKE#: length 135.6
  TOP w0.102: RE275.1 255.84,58.95 v2(255.81,58.93) ; v2(186.05,54.2) v1(186.05,53.24) 186.05,51.46 185.72,51.13 185,51.13 RE274.1
  IN1 w0.102: v2(230.68,44.08) 229.82,44.08 228.97,43.23 226.29,43.23 225.78,42.72 219.11,42.72 218.65,43.19 210.33,43.19 204.94,48.58 203.35,48.58 197.25,54.67 189.12,54.67 188.65,54.2 v2(186.05,54.2)
  IN2 w0.102: v2(235.25,61.33) 235.28,61.35 240.43,61.35 242.78,59 246.2,59 246.97,59.78 254.96,59.78 v2(255.81,58.93)
  BOTTOM w0.102: JNGFF1.62 239.82,16.6 236.07,20.35 234.68,20.35 JNGFF1.47 232.45,20.35 232.27,20.52 230.06,20.52 226.96,23.62 226.96,27.58 227.42,28.04 227.42,33.99 228.53,35.11 228.53,37.87 230.68,40.02 v2(230.68,44.08) 230.68,45.95 235.46,50.72 235.46,60.27 235.25,60.48 v2(235.25,61.33)
PCIE_WAKE#_R: length 39.5
  TOP w0.102: v2(256.68,58.94) 256.32,59.3 256.32,60.1 RE275.2 255.44,60.98 UE3.18 ; v2(256.51,32.21) v4(255.29,32.21) 254.59,32.21 RE35.2
  IN1 w0.102: v2(256.51,32.21) 256.51,32.46 258.09,34.04 258.09,37.77 259.01,38.7 259.01,40.11 260.23,41.32 260.23,44.47 260.84,45.08 261.58,45.08 262.29,45.8 262.29,46.67 261.77,47.19 261.77,50.33 261.35,50.75 261.35,55.04 257.86,58.53 257.08,58.53 v2(256.68,58.94)
PE_REXT: length 2.5
  TOP w0.102: UR1.4 280.31,31.91 RR2.2
PECI_EC: length 318.3
  TOP w0.102: RE60.2 264.01,33.88 v2(264.01,33.18) ; v2(78.65,27.61) 80.44,27.61 82.26,29.43 85.33,29.43 88.44,32.54 90.05,32.54 94.38,36.87 94.38,38.86 98.51,42.99 105.47,42.99 v2(108.94,46.46) ; v2(74.59,8.15) v1(75.26,8.15)
  IN1 w0.102: v2(249.2,10.57) 248.41,9.78 242.82,9.78 239.28,13.32 227.77,13.32 222.72,8.27 156.45,8.27 156.33,8.38 74.82,8.38 v2(74.59,8.15)
  IN2 w0.102: v2(108.94,46.46) 119.77,46.46 120.36,47.04 120.36,49.33 119.42,50.26 119.42,53.84 121.09,55.51 126.45,55.51 128.58,57.64 132.47,57.64 134.33,59.5 134.33,62.19 134.83,62.7 134.83,63.39 134.24,63.98 133.06,63.98 132.74,64.3 132.74,65.57 v2(133.13,65.96) ; v2(78.65,27.61) 77.05,26.01 77.05,21.41 76.46,20.83 76.46,15.76 74.59,13.88 v2(74.59,8.15)
  BOTTOM w0.076: UC1.N62 132.81,66.29 v2(133.13,65.96)
  BOTTOM w0.102: v2(249.2,10.57) 249.74,11.11 249.74,13.6 250.87,14.73 250.87,20.69 255.97,25.78 255.97,32.28 256.37,32.69 263.52,32.69 v2(264.01,33.18)
PECI_EC_R: length 6.4
  TOP w0.102: RE60.1 264.02,34.8 264.34,35.11 264.34,35.28 264.25,35.37 264.09,35.37 263.97,35.5 263.97,35.8 264.09,35.93 v1(264.5,35.93) 264.84,35.93 264.97,36.05 264.97,36.46 264.84,36.59 263.66,36.59 263.54,36.72 263.54,37.05 263.42,37.17 263.25,37.17 263.13,37.05 263.13,36.72 263.01,36.6 262.81,36.6 262.69,36.73 UE2.A48
PGOOD_3V_5V: length 5
  TOP w0.102: v1(223.86,47.03) 223.53,47.03 222.62,47.94 PR107.2
  TOP w0.203: PR108.2 221.36,48.24 221.15,48.24 220.28,49.11 PU100.7
  TOP w0.254: PR107.2 PR108.2
PLTRST_LAN#: length 110
  TOP w0.102: RC89.1 191.88,74.15 191.88,78.29 195.06,81.47 203.1,81.47 203.79,82.17 205.65,82.17 v2(206.61,83.12) ; v2(265.58,71.36) 264.83,72.11 264.83,85.57 263.14,87.26 263.14,89.15 262.77,89.52 260.98,89.52 260.27,88.81 260.27,88.16 260.1,87.99 UL1.36
  IN1 w0.102: v2(234.63,76.43) 234.63,77 234.24,77.39 233.83,77.39 232.75,78.46 230.74,78.46 229.94,79.26 219.87,79.26 216.01,83.12 v2(206.61,83.12)
  IN2 w0.102: v2(265.58,71.36) 265.54,71.32 255.84,71.32 255.06,72.11 244.86,72.11 239.98,76.99 235.19,76.99 v2(234.63,76.43)
PLTRST_MMI#: length 152.2
  TOP w0.102: v2(206,83.12) 205.45,82.57 203.03,82.57 202.33,81.88 194.85,81.88 191.41,78.43 191.41,74.83 RC88.1 ; UR1.15 283.32,27.29 283.16,27.13 283.16,25.96 282.52,25.32 282.52,23.23 281.95,22.66 277.64,22.66 276.59,23.71 276.59,27.75 274.63,29.7 274.63,35.29 277.29,37.94 277.29,45.3 273.24,49.35 273.24,53.39 272.41,54.22 v2(272.41,56.43)
  IN1 w0.102: v2(206,83.12) 207.41,84.53 228.1,84.53 230.2,82.43 230.2,81.59 233.99,77.8 234.46,77.8 236.57,75.68 236.57,68.43 241.74,63.26 245.36,63.26 250.13,58.48 253.44,58.48 254.1,57.82 v2(255.81,57.82)
  IN2 w0.102: v2(255.81,57.82) 261.67,57.82 262.6,56.9 268.53,56.9 269.17,56.25 272.23,56.25 v2(272.41,56.43)
PM_APWROK: length 78.8
  TOP w0.102: v2(259.37,50.9) 259.37,49.36 259.23,49.22 259.23,48.77 258.69,48.22 UE2.A9 ; RC26.1 194.41,51.29 196.49,51.29 198.6,49.19 202.08,49.19 v4(203.37,47.9) 205.28,45.99 205.28,43.57 v2(205.84,43.01)
  IN2 w0.102: v2(259.37,50.9) 258.98,50.9 257.36,52.51 252.92,52.51 252.74,52.69 252.05,52.69 251.83,52.46 246.51,52.46 243.26,49.21 237.84,49.21 233.91,45.28 233.64,45.28 232.84,44.49 219.53,44.49 219.28,44.74 215.32,44.74 214.02,43.43 206.26,43.43 v2(205.84,43.01)
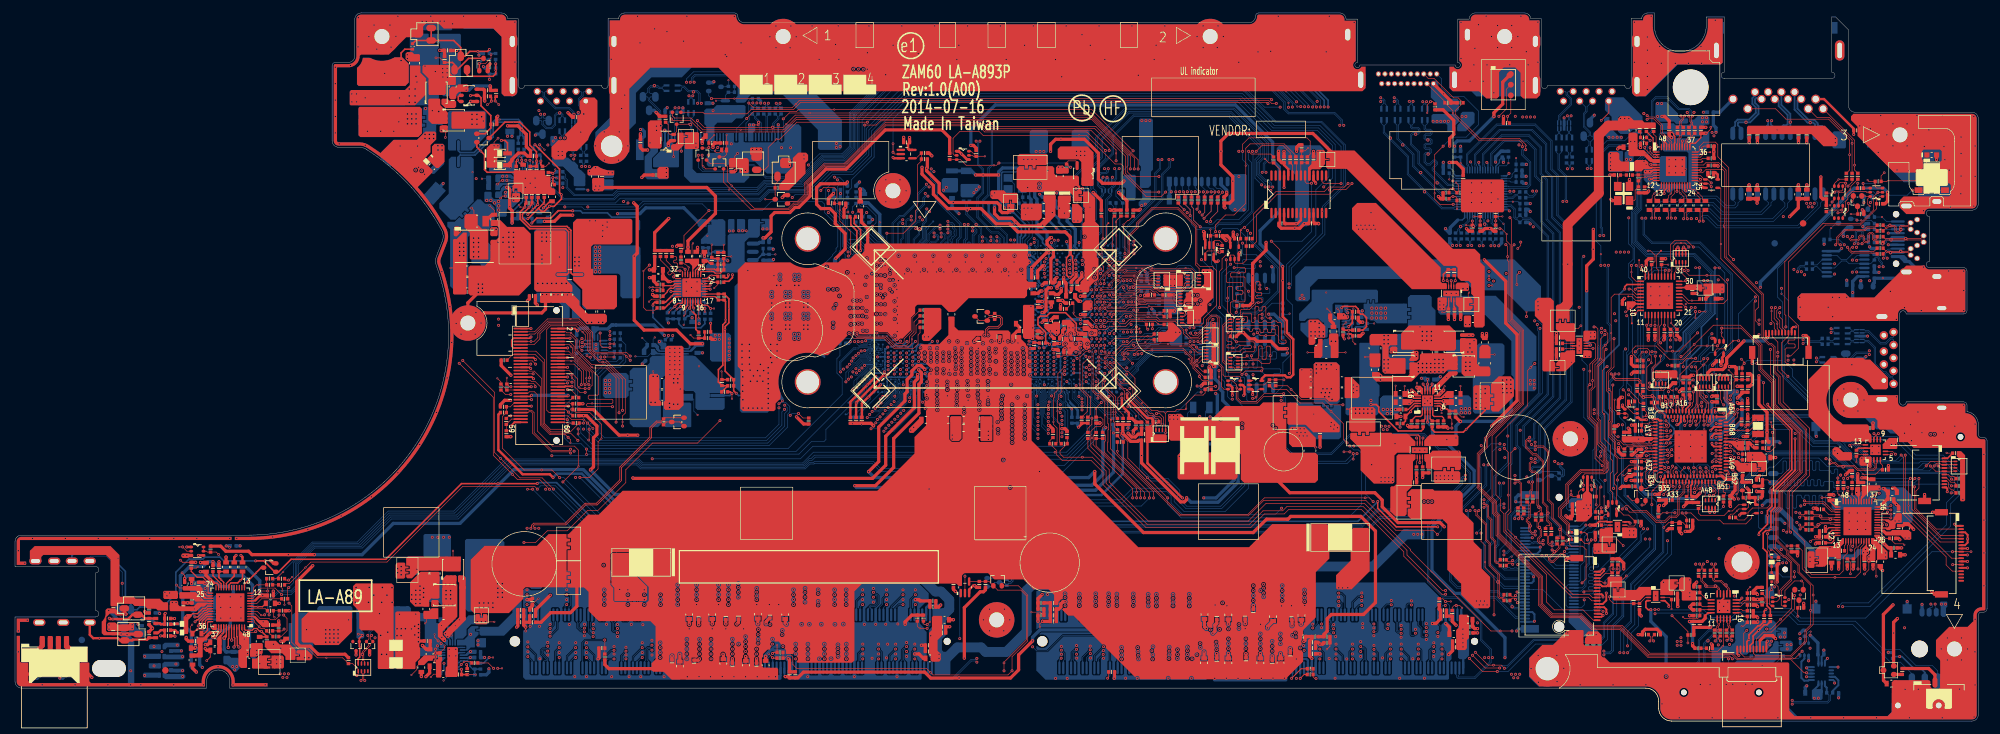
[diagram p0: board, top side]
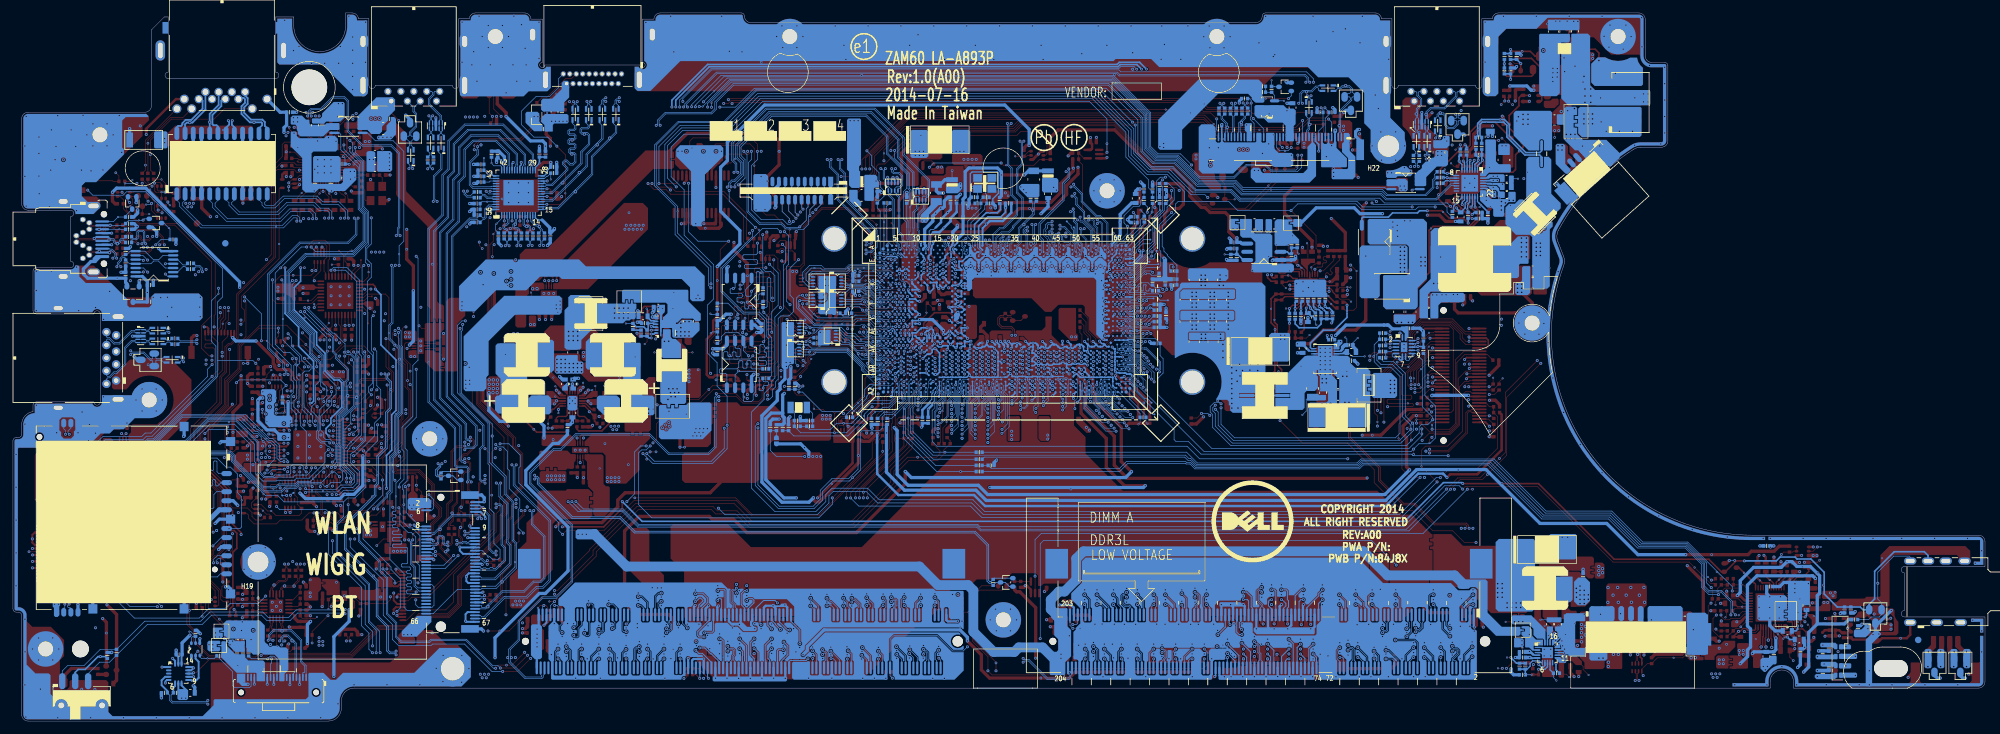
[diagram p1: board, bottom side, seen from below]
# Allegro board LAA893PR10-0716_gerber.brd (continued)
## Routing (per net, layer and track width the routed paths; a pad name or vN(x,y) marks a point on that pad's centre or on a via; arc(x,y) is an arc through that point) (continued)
PM_APWROK_L: length 5.6
  TOP w0.102: UC6.2 193.06,51.98 RC26.2 RC27.2 v4(196.1,52.77)
PM_APWROK_R: length 52.6
  TOP w0.102: UC6.4 192.15,51.33 191.96,51.15 191.96,50.29 v4(191.78,50.1) 191.58,49.9 v2(191.26,49.9)
  IN1 w0.102: v2(167.8,60.99) 168.27,60.53 169.87,60.53 170.11,60.77 172.53,60.77 173.11,61.35 174.09,61.35 174.51,61.77 174.89,61.77 175.46,62.34 176.23,62.34 178.57,64.68 178.57,65.99 183.35,70.76 v2(183.35,71.35) ; v2(191.26,49.9) 191.13,49.77 v2(188.12,49.77)
  BOTTOM w0.076: UC1.AB5 167.8,61.11 v2(167.8,60.99)
  BOTTOM w0.102: v2(188.12,49.77) 187.79,49.77 187.35,50.22 187.35,51.22 186.9,51.66 186.9,52.45 186.5,52.86 186.5,62.24 186.09,62.65 184.78,62.65 184.15,63.28 184.15,65.34 184.67,65.86 184.67,70.03 v2(183.35,71.35)
PM_LANPHY_ENABLE: length 172.6
  TOP w0.076: v2(167.46,56.29) 167.98,55.78 168.65,55.78 168.86,55.57 168.86,55.24 169.2,54.9
  TOP w0.102: RC92.2 176.77,46.61 176.62,46.76 176.27,46.76 175.75,47.28 175.17,47.28 172.34,50.11 172.34,50.71 v1(171.87,51.18) 171.63,51.42 171.36,51.42 169.9,52.88 169.9,54.21 169.2,54.9 ; RL7.1 252.56,89.8 v2(252.69,89.8)
  IN1 w0.102: v2(256.71,51.33) 255.36,52.68 251.57,52.68 250.53,51.64 248.03,51.64 246.72,50.33 237.38,50.33 232.01,44.96 232.01,43.42 229.94,41.35 216.21,41.35 216.02,41.54 209.85,41.54 204.23,47.17 202.82,47.17 197.26,52.72 189.55,52.72 189.16,52.34 182.62,52.34 182.03,52.93 182.03,53.28 179.2,56.11 176.34,56.11 174.93,54.7 174.07,54.7 172.66,53.28 169.3,53.28 168.78,53.81 168.78,53.91 168.56,54.13 168.15,54.13 167.88,54.4 167.88,55.88 v2(167.46,56.29)
  BOTTOM w0.076: v2(167.46,56.29) 167.25,56.08 UC1.AM7
  BOTTOM w0.102: v2(252.69,89.8) 252.27,89.38 252.27,87.99 250.73,86.45 250.73,79.4 250,78.66 250,73.94 252.04,71.89 259.34,71.89 262.01,69.23 262.01,63.33 258.53,59.85 258.53,56.88 257.2,55.55 257.2,51.82 v2(256.71,51.33)
PM_TEST_RST: length 9.2
  TOP w0.102: RC300.2 163.37,64.63 CC100.2 163.64,64.43 163.64,63.21 v1(163.57,63.14) 163.57,62.92 164.04,62.45 166.01,62.45 167.04,61.42 167.92,61.42 v2(168.36,60.98)
  BOTTOM w0.076: v2(168.36,60.98) 168.37,61 UC1.AC4
POA_WAKE#: length 7.5
  TOP w0.102: UE2.B68 263.9,46.46 264.07,46.63 264.26,46.63 265.54,47.92 265.54,48.79 265.31,49.02 264.79,49.02 264.11,49.71 v1(264.11,49.99) 264.11,51.09 263.77,51.43 RPE5.2
POWER_SW#_MB: length 102.3
  TOP w0.102: SW3.4 SW3.2 293.19,82.1 v2(293.19,82.1) ; v4(266.79,55.96) 267.22,55.52 v2(267.22,55.31) 266.89,54.98 CE10.1 266.89,53.7 RE33.2 ; JAPS1.11 299.27,25.19 292.11,32.35 v2(292.11,41.12)
  BOTTOM w0.102: v2(293.19,82.1) 292.41,81.32 287.74,81.32 287.22,81.84 284.24,81.84 272.37,69.98 272.37,65.56 273.15,64.78 273.15,55.78 ; 273.15,55.78 273.15,53.26 282.97,43.44 283.87,43.44 287.2,40.11 291.09,40.11 v2(292.11,41.12) ; 273.15,55.78 267.69,55.78 v2(267.22,55.31)
POWER_SW_IN#: length 12.7
  TOP w0.102: UE2.B67 262.91,45.96 v2(262.88,46) ; CE12.1 265.64,52.43 265.64,50.84 v2(265.07,50.27) ; CE12.1 RE33.1 RE31.2 ; CE12.1 265.95,52.79 265.5,53.24 265.5,53.58 264.83,54.25 264.83,54.27 v1(264.82,54.28)
  IN2 w0.102: v2(265.07,50.27) 264.49,49.68 264.49,47.27 263.22,46 v2(262.88,46)
PROC_OPI_RCOMP: length 4.4
  BOTTOM w0.152: 162.68,48.87 162.68,49.16 162.37,49.47 162.37,50.52 162.16,50.72 UC1.AY15
  BOTTOM w0.381: 162.68,48.87 v4(163.32,48.23) RC187.1
PROCHOT_GATE: length 3.7
  TOP w0.102: UE3.26 257.67,66.01 258.66,65.02 v1(259.14,65.02) 260.12,65.02 RE83.2
PS8339B_DP_CFG0: length 4.5
  BOTTOM w0.102: UV7.44 231.07,83.91 231.35,84.19 231.35,84.56 RV51.2 231.97,86.08 RV52.1 v1(231.97,87.06)
PS8339B_DP_CFG1: length 3.2
  BOTTOM w0.203: v1(223.39,86.27) 223.39,86.25 224.02,85.62 UV7.29
  BOTTOM w0.254: v1(223.39,86.27) 223.39,86.27 RV61.1 222.46,87.22 RV54.2
PS8339B_IN_CA_DET: length 2.5
  TOP w0.102: v2(225.22,77.32) 225.21,77.31 RV68.2 v1(224.24,76.68)
  BOTTOM w0.102: UV7.11 v2(225.22,77.32)
PS8339B_INPUT_EQ: length 3.2
  TOP w0.102: v1(225.41,78.02) RV65.1 v2(226.42,77.33) 226.42,77.3 226.41,77.3 RV58.2
  BOTTOM w0.102: UV7.8 v2(226.42,77.33)
PS8339B_MODE: length 3.5
  BOTTOM w0.102: UV7.53 v1(231.47,80.31) 232.28,80.31 RV63.1 RV57.2
PS8339B_MODE_SW: length 2.8
  BOTTOM w0.102: UV7.45 231,83.51 231.15,83.35 RV510.1 RV511.2
PS8339B_OUT_CA_DET: length 3.3
  BOTTOM w0.102: RV67.2 v1(230.79,86.28) 230.79,86.23 230.43,85.86 229.38,85.86 229.22,85.69 UV7.42
PS8339B_TMDS_DDCBUF: length 3.3
  TOP w0.102: v1(229.84,78.03) 229.83,78.02 RV66.1 v2(228.82,77.34) 228.81,77.34 RV60.2
  BOTTOM w0.102: UV7.2 v2(228.82,77.34)
PS8339B_TMDS_PRE: length 4.1
  TOP w0.102: v1(222.83,79.2) RV64.1 222.83,80.87 222.6,81.11 v2(222.22,81.11) 221.94,81.11 RV56.2
  BOTTOM w0.102: UV7.20 v2(222.22,81.11)
PS8339B_TMDS_RT: length 4.7
  TOP w0.102: RV55.2 221.6,82.1 221.8,82.31 v2(222.22,82.31) 222.83,81.7 RV62.1 223.09,81.95 223.09,82.88 v1(222.69,83.27)
  BOTTOM w0.102: UV7.23 v2(222.22,82.31)
PS_ID: length 251.7
  TOP w0.102: v2(260.3,70.1) v4(259.71,70.1)
  TOP w0.254: v2(255.91,44.07) 255.91,43.88 255.53,43.51 254.38,43.51 UE2.B24
  IN1 w0.254: v2(202.32,94.97) 202.32,92.91 205.35,89.88 224.9,89.88 225.54,89.24 229.03,89.24 233.23,85.04 233.63,85.04 236.47,82.19 236.47,79.81 239.3,76.98 239.3,71.62 241.63,69.29 253.91,69.29 254.94,70.32 260.08,70.32 v2(260.3,70.1)
  IN2 w0.254: v2(130.34,100.8) 129.79,101.35 107.42,101.35 106.59,102.18 101.58,102.18 94.29,94.89 89.63,94.89 88.31,93.58 82.8,93.58 82.14,92.93 78.47,92.93 74.33,97.07 73.19,97.07 72.87,97.38 72.87,98.78 v2(73.31,99.22)
  BOTTOM w0.254: v2(260.3,70.1) 260.3,68.02 261.29,67.03 261.29,63.58 257.82,60.11 257.82,58.18 256.52,56.87 256.52,54.13 255.13,52.74 254.35,52.74 253.92,52.31 253.92,48.53 255.61,46.84 255.61,46.01 256.37,45.24 256.37,44.53 v2(255.91,44.07) ; PR9.2 PR8.1 v2(73.31,99.22) ; v2(130.34,100.8) 131.05,101.51 133.64,101.51 133.97,101.18 197.14,101.18 202.32,96 v2(202.32,94.97)
PS_USBP1_D+: length 20.2
  TOP w0.102: UI3.10 287.76,44.02 287.69,44.09 287.69,44.31 287.84,44.45 v2(287.96,44.45)
  IN2 w0.086: v2(287.96,44.45) 287.75,44.66 287.75,44.91 287.43,45.23 284.04,45.23 280.52,48.76 280.52,54.5 278.98,56.03 278.49,56.03 v2(278.38,56.14)
  BOTTOM w0.102: v2(278.38,56.14) 278.55,55.97 278.71,55.97 279.03,56.29 LI7.1
PS_USBP1_D-: length 20.1
  TOP w0.102: v2(287.27,44.45) 287.47,44.25 287.47,44.11 287.26,43.89 UI3.11
  IN2 w0.086: v2(278.38,55.56) 278.68,55.86 278.91,55.86 280.34,54.42 280.34,48.69 283.97,45.06 287.35,45.06 287.58,44.84 287.58,44.58 287.45,44.45 v2(287.27,44.45)
  BOTTOM w0.102: v2(278.38,55.56) 278.58,55.75 278.72,55.75 279.04,55.44 LI7.4
PWM1: length 10.2
  TOP w0.203: PU500.6 v2(101.36,66.43)
  IN1 w0.254: v2(99.58,58.67) 99.58,62.99 100.25,63.66 100.25,65.32 v2(101.36,66.43)
  BOTTOM w0.102: v2(101.36,66.43) v1(101.36,67.03)
PWR_SRC_ON: length 4.8
  BOTTOM w0.102: v1(108.32,95.91) QV1.3 109.77,96.76 RV5.1 111.17,97.24 CV11.2 RV4.2
REGCTL_PNP10:
  vias: v1(252.08,86.05)
REM_DIODE1_N: length 139.8
  TOP w0.102: v2(255.9,49.47) 255.75,49.62 255.75,49.96 CE24.1
  TOP w0.127: CE24.1 256.31,49.78 256.31,49.06 v2(256.1,48.85) ; QE3.3 150.25,62.99 150.53,62.7 151.06,62.7 CE35.1 151.73,62.7 152.19,62.7 152.56,62.33 152.56,61.32 152,60.76 150.53,60.76 150.23,60.45 150.23,59.82 v2(150.39,59.65) ; UE2.B13 256.94,46.59 v2(256.78,46.43)
  IN1 w0.127: v2(256.1,48.85) 256.1,47.65 256.78,46.97 v2(256.78,46.43) ; v2(150.39,59.65) 150.25,59.79 150.25,59.98 150.4,60.13 151.14,60.13 151.64,59.63 157.37,59.63 158.39,58.61 159.06,58.61 159.28,58.84 159.96,58.84 161.4,57.4 161.4,53.49 161.93,52.96 162.7,52.96 163.28,52.39 163.99,52.39 164.35,52.02 164.35,51.68 167.54,48.5 168.42,48.5 169.09,47.83 173.8,47.83 174.75,46.88 176.93,46.88 177.79,46.01 187.14,46.01 188.94,47.81 199.28,47.81 201.27,45.83 201.27,45.41 201.97,44.7 207.37,39.31 226.21,39.31 226.63,38.89 230.38,38.89 233.54,42.04 233.54,44.32 236.94,47.73 243.87,47.73 v2(244.04,47.56)
  IN2 w0.127: v2(244.04,47.56) 244.18,47.7 245.06,47.7 246.69,49.34 249.56,49.34 250.28,50.06 255.96,50.06 256.19,49.83 256.19,49.59 256.07,49.47 v2(255.9,49.47)
REM_DIODE1_P: length 140.1
  TOP w0.127: v2(256.72,49.4) 256.65,49.47 256.65,49.94 CE24.2 257.01,49.99 257.01,49.68 257.12,49.57 257.12,49.25 256.69,48.82 UE2.A13 ; QE3.1 149,61.93 QE3.2 150.25,62.17 150.53,62.45 151.06,62.45 CE35.2 151.73,62.45 152.08,62.45 152.31,62.23 152.31,61.42 151.9,61.01 150.43,61.01 149.97,60.55 149.97,59.79 v2(149.83,59.65)
  IN1 w0.127: v2(149.83,59.65) 150,59.82 150,60.09 150.3,60.39 151.24,60.39 151.75,59.88 157.48,59.88 158.49,58.86 158.95,58.86 159.18,59.09 160.07,59.09 161.66,57.51 161.66,53.59 162.03,53.22 162.81,53.22 163.38,52.64 164.09,52.64 164.61,52.13 164.61,51.79 167.64,48.75 168.53,48.75 169.2,48.08 173.9,48.08 174.85,47.13 177.04,47.13 177.9,46.27 187.04,46.27 188.84,48.07 199.38,48.07 201.52,45.93 201.52,45.52 202.08,44.96 207.48,39.56 226.31,39.56 226.73,39.14 230.27,39.14 233.28,42.15 233.28,44.43 236.84,47.98 243.87,47.98 v2(244.04,48.15)
  IN2 w0.127: v2(256.72,49.4) 256.6,49.4 256.45,49.55 256.45,49.94 256.07,50.32 250.17,50.32 249.45,49.59 246.59,49.59 244.95,47.95 244.23,47.95 v2(244.04,48.15)
REM_DIODE2_N: length 136.3
  TOP w0.127: v2(256.18,46.45) 256.44,46.71 UE2.B14 ; v2(254.54,48.59) 254.24,48.89 254.24,49.71 254.1,49.85 CE26.1 254.28,50.15 254.54,49.89 254.54,49.22 254.95,48.82 v2(255.09,48.82)
  IN1 w0.127: v2(255.09,48.82) 255.09,47.54 v2(256.18,46.45) ; v2(224.14,38.01) 224.34,37.81 230.35,37.81 233.94,41.4 237.8,41.4 238.89,40.32 238.89,39.97 v2(239.05,39.8)
  IN2 w0.127: v2(254.54,48.59) 254.29,48.84 250.56,48.84 249.56,47.84 247.32,47.84 244.33,44.85 244.33,43.73 241.5,40.89 239.58,40.89 238.91,40.22 238.91,39.94 v2(239.05,39.8)
  BOTTOM w0.127: v2(224.14,38.01) 223.97,37.85 223.73,37.85 223.45,37.57 223.45,36.78 218.27,31.6 210.86,31.6 208.61,29.35 156.05,29.35 153.97,27.27 153.97,21.75 153.8,21.57 153.6,21.57 CE37.2 153.08,22.09 QE5.3 ; QE7.2 236.1,37.28 236.75,37.93 QE7.1 238.12,37.93 CE46.2 238.93,37.78 239.21,37.78 239.42,37.99 239.42,38.86 238.87,39.41 238.87,39.62 v2(239.05,39.8)
REM_DIODE2_P: length 132.8
  TOP w0.102: CE26.2 254.87,50.01 254.87,49.64 255.08,49.44
  TOP w0.127: 255.08,49.44 v2(255.09,49.43) ; CE26.2 255.48,49.68 255.48,48.87 256.19,48.17 UE2.A14
  IN1 w0.127: v2(224.14,37.43) 224.26,37.55 230.45,37.55 234.05,41.15 237.7,41.15 238.63,40.21 238.63,39.98 238.47,39.81 v2(238.47,39.8)
  IN2 w0.127: v2(238.47,39.8) 238.66,39.99 238.66,40.33 239.48,41.15 241.4,41.15 244.08,43.83 244.08,44.96 247.21,48.09 249.45,48.09 250.45,49.1 254.76,49.1 v2(255.09,49.43)
  BOTTOM w0.127: QE7.3 238.39,38.58 CE46.1 238.93,38.03 239.1,38.03 239.16,38.09 239.16,38.79 238.64,39.31 238.64,39.62 v2(238.47,39.8) ; QE5.2 150.75,20.79 151.4,21.44 QE5.1 152.82,21.44 CE37.1 153.6,21.32 153.9,21.32 154.23,21.64 154.23,27.17 156.16,29.1 208.71,29.1 210.96,31.34 218.37,31.34 223.71,36.68 223.71,37.46 223.83,37.59 223.97,37.59 v2(224.14,37.43)
REM_DIODE4_N: length 285.6
  TOP w0.127: v2(247.26,53.68) 247.09,53.51 247.09,53.24 247.37,52.96 250.91,52.96 251.25,52.62 251.25,52.25 RE100.2 ; QE6.3 100.39,46.9 CE39.1 99.88,46.39 99.12,46.39 98.1,45.38 98.1,43.92 93.46,39.27 93.46,37.29 89.85,33.68 88.11,33.68 85.02,30.59 80.13,30.59 79.83,30.29 79.83,29.92 v2(79.72,29.81)
  IN2 w0.127: v2(245.54,10.24) 245.35,10.43 240.98,10.43 239.02,12.38 231.63,12.38 229.21,9.96 229.21,8.84 228.23,7.87 157.46,7.87 156.53,8.8 152.25,8.8 151.37,7.92 77.94,7.92 75.69,10.17 75.69,14.02 77.11,15.45 77.11,20.56 77.68,21.14 77.68,25.4 79.84,27.56 79.84,29.68 v2(79.72,29.81)
  BOTTOM w0.127: v2(247.26,53.68) 247.09,53.5 247.09,52.94 246.5,52.36 246.5,48.42 247.16,47.76 247.16,42.33 248.51,40.99 248.51,36.79 248.9,36.4 248.9,34.95 253.52,30.33 253.52,26.56 248.6,21.63 248.6,16.18 247,14.58 247,10.86 246.56,10.41 245.72,10.41 v2(245.54,10.24)
REM_DIODE4_N_R: length 6.7
  TOP w0.127: UE2.A16 254.14,47.91 253.49,48.56 253.49,48.93 CE27.1 253.48,49.58 253.48,50.04 253.21,50.3 v3(253.01,50.3) 251.54,50.3 251.29,50.55 251.29,50.71 RE100.1
REM_DIODE4_P: length 284.7
  TOP w0.127: v2(80.35,29.81) 80.09,30.07 80.09,30.19 80.24,30.34 85.13,30.34 88.21,33.43 89.95,33.43 93.71,37.19 93.71,39.16 98.36,43.81 98.36,45.27 99.23,46.14 99.88,46.14 CE39.2 100.66,46.25 QE6.1 102.74,46.25 QE6.2 ; RE101.2 251,52.23 251,52.51 250.81,52.7 247.26,52.7 246.83,53.13 246.83,53.52 v2(246.68,53.68)
  IN2 w0.127: v2(80.35,29.81) 80.1,29.55 80.1,27.46 77.94,25.3 77.94,21.03 77.36,20.46 77.36,15.34 75.94,13.92 75.94,10.28 78.04,8.18 151.26,8.18 152.14,9.05 156.63,9.05 157.57,8.12 228.13,8.12 228.95,8.94 228.95,10.06 231.53,12.64 239.13,12.64 241.09,10.68 245.4,10.68 v2(245.54,10.82)
  BOTTOM w0.127: v2(246.68,53.68) 246.83,53.52 246.83,53.05 246.25,52.46 246.25,48.32 246.91,47.66 246.91,42.18 248.26,40.83 248.26,36.69 248.65,36.29 248.65,34.84 253.27,30.23 253.27,26.66 248.35,21.74 248.35,16.28 246.75,14.68 246.75,10.96 246.45,10.67 245.69,10.67 v2(245.54,10.82)
REM_DIODE4_P_R: length 7.3
  TOP w0.127: UE2.B17 254.94,47.32 254.6,47.66 254.04,47.66 253.24,48.46 253.24,48.91 CE27.2 253.22,49.58 253.22,49.93 253.1,50.05 v3(251.65,50.05) 251.43,50.05 251.04,50.44 251.04,50.65 RE101.1
RES_BIAS: length 2.2
  TOP w0.102: RL13.1 252.2,82.61 253.18,83.59 UL1.12
RESET_OUT#: length 257.6
  TOP w0.102: v4(135.68,89.28) v2(135.68,87.95) 135.96,87.67 UC8.2 ; v2(256.21,35.02) 256.09,34.91 RE56.2 ; v2(256.72,38.5) 256.94,38.28 UE2.B39
  IN1 w0.102: v2(256.72,38.5) 255.8,37.58 255.8,35.43 v2(256.21,35.02) ; v2(194.38,45.74) 194.14,45.99 v2(189.63,45.99)
  IN2 w0.102: v2(256.21,35.02) 255.45,34.26 250.66,34.26 250.44,34.48 241.54,34.48 240.8,33.74 237.62,33.74 236.22,35.15 233.32,35.15 232.81,35.67 232.35,35.67 231.21,36.81 231.21,38.03 227.5,41.74 218.75,41.74 218.19,42.3 216.08,42.3 215.15,41.36 v2(207.39,41.36)
  BOTTOM w0.076: 167.71,48.48 166.57,49.61 166.57,50.79 UC1.AY7
  BOTTOM w0.102: 167.71,48.48 168.77,47.41 170.02,47.41 170.41,47.03 170.41,45.29 170.81,44.89 173.56,44.89 173.8,44.65 173.8,38.79 175.47,37.12 178.05,37.12 179.64,35.53 179.64,34.16 180.93,32.87 186.47,32.87 190.04,36.44 190.04,45.58 v2(189.63,45.99) ; v2(135.68,87.95) 135.68,93.1 138.4,95.82 188.9,95.82 193.96,90.75 201.05,90.75 203.03,88.77 203.03,84.16 201.03,82.16 201.03,75.12 196.47,70.56 196.47,65.28 197.39,64.35 197.39,56.88 195.93,55.42 195.93,51.8 194.38,50.25 v2(194.38,45.74) 194.38,42.1 196.66,39.83 205.85,39.83 v2(207.39,41.36)
RING2:
  vias: v1(28.61,18.88)
RING2_R: length 6.2
  IN1 w1.27: 22.4,18.72 21.19,17.51 21.19,16.28 20,15.09 20,14.39 19.38,13.77 19.38,13.75
  vias: v2(14.53,14.87) v2(14.53,14.21) v2(18.11,14.9) v2(18.09,14.29) v2(23.48,19.37) v2(23.89,19.81) v4(23.16,19.91)
RSMRST#: length 6.7
  TOP w0.102: UZ5.3 266.93,34.69 RZ22.2 267.87,33.75 267.87,33.07 267.59,32.8 UZ6.2 266.39,32.8 v1(266.13,32.54) 265.59,32 265.16,32 264.97,31.81 RZ51.2
RUN_ON: length 160.7
  TOP w0.102: UZ9.5 216.69,43.66 v2(216.58,43.77) ; QE2.2 250.08,47.57 248.87,48.78 248.87,50.88 v2(248.52,51.22) ; RZ41.1 221.31,68.73 v2(221.31,68.1) 221.54,67.87 UZ8.5 ; UZ9.3 217.49,43.69 v2(217.57,43.77) ; v2(209.88,33.94) 209.3,34.52 208.65,34.52 v4(208.65,34.52) 193.07,34.52 190.5,31.94 180.11,31.94 171.26,40.79 RE279.2 170.6,43.81 170.6,43.88 RE280.2 ; v2(253.48,56.44) 253.48,55.14 252.98,54.65 252.98,52.88 253.31,52.55 253.46,52.55 253.56,52.45 RPE10.1 253.56,51.86 253.38,51.68 v2(252.59,51.68)
  IN2 w0.102: v2(221.31,68.1) 221.73,67.68 224.36,67.68 227.07,64.97 230.22,64.97 239.54,55.65 243.82,55.65 244.52,56.35 248.78,56.35 249.2,55.93 249.98,55.93 250.44,56.39 253.43,56.39 v2(253.48,56.44) ; v2(252.59,51.68) 248.98,51.68 v2(248.52,51.22) 246.24,51.22 243.53,48.51 238.28,48.51 234.36,44.6 233.99,44.6 232.84,43.45 226.23,43.45 225.61,42.84 219.66,42.84 218.72,43.77 v2(217.57,43.77) v2(216.58,43.77) 215.69,43.77 214.46,42.54 v2(206.89,42.54)
  BOTTOM w0.102: v2(209.88,33.94) 208.67,35.15 208.67,41.63 207.76,42.54 v2(206.89,42.54)
RUN_ON#: length 4.8
  TOP w0.102: QE2.6 249.11,46.92 249.26,47.07 249.26,47.4 249.09,47.57 QE2.5 247.79,47.57 RE68.2 247.2,48.16 v1(247.2,49.69)
RUN_ON_EC: length 115.7
  TOP w0.102: v2(258.85,46.38) 258.94,46.46 UE2.B9 ; RE279.1 v4(170.34,41.71) 170.34,41.42 180.03,31.74 190.58,31.74 192.98,34.13 208.74,34.13 213.37,29.5 219.18,29.5 v2(219.8,28.87)
  IN2 w0.102: v2(258.85,46.38) 258.44,45.97 258.44,45.55 258.03,45.14 256.91,45.14 255.64,46.41 255.64,46.63 255.27,47 254.26,47 253.16,48.11 250.75,48.11 249.86,47.22 247.58,47.22 244.96,44.6 244.96,43.46 241.77,40.27 240.71,40.27 239.68,39.24 237.72,39.24 235.41,41.55 234.16,41.55 232.46,43.25 229.85,43.25 v2(229.47,42.87)
  BOTTOM w0.102: v2(219.8,28.87) 220.39,29.46 220.39,30.64 226.57,36.82 226.57,39.17 226.36,39.37 226.36,41.13 228.1,42.87 v2(229.47,42.87)
RUNPWROK: length 263.6
  TOP w0.102: v2(90.42,60.01) v1(90.42,58.74) 90.42,58.19 90.86,57.75 v2(91.93,57.75) ; QE2.3 250.25,48.22 250.05,48.42 250.05,49.2 RE67.2 250.28,49.54 v2(249.36,50.46) ; v2(87.61,59.16) 87.21,58.76 87.21,57.74 v2(87.61,57.33) ; UE2.B26 255.24,42.46 v2(255.78,43.01)
  IN1 w0.102: v2(249.37,77.81) 244.12,77.81 243.16,78.76 243.16,80.6 239.81,83.95 239.81,84.23 237.14,86.89 237.14,90.92 235.76,92.3 235.76,93.48 235.37,93.88 232.22,93.88 v2(231.85,93.51)
  IN2 w0.102: v2(122.6,85.98) 121.33,84.71 105.85,84.71 102.08,80.94 99.83,80.94 93.25,74.36 93.25,62.39 90.87,60.01 v2(90.42,60.01) 88.46,60.01 v2(87.61,59.16) ; v2(199.87,95) 200.29,95.41 207.29,95.41 208.67,94.03 217.91,94.03 218.81,94.92 230.44,94.92 v2(231.85,93.51) ; v2(255.52,50.94) 249.85,50.94 v2(249.36,50.46)
  BOTTOM w0.102: v2(249.36,50.46) 249.81,50.9 249.81,51.64 249.21,52.23 249.21,56.6 249.98,57.38 249.98,68 249.37,68.6 249.37,70.73 250.06,71.41 250.06,73.09 249.37,73.77 v2(249.37,77.81) ; UC7.1 90.03,59.82 90.22,60.01 v2(90.42,60.01) ; v2(199.87,95) 199.87,95.3 195.34,99.83 134.67,99.83 128.93,94.1 128.93,88.86 127.78,87.71 124.32,87.71 v2(122.6,85.98) ; UC7.13 87.95,58.83 v2(87.61,59.16) ; UC7.4 91.85,57.83 v2(91.93,57.75) ; v2(255.52,50.94) 255.52,50.42 256.31,49.63 256.31,49.21 257.42,48.1 257.42,44.87 257.57,44.73 257.57,43.8 256.97,43.2 255.98,43.2 v2(255.78,43.01) ; UC7.10 v2(87.61,57.33)
S5_1.35V: length 5.2
  TOP w0.102: PR207.2 v1(71.21,7.19)
  TOP w0.254: PR207.2 PC215.1 69,8 v2(68.98,8.01)
  BOTTOM w0.203: PU200.8 67.61,8.4 67.99,8.01 v2(68.98,8.01)
SATA2_PCIE6_L1: length 14
  TOP w0.076: v2(167.67,63.84) 167.67,64.01 v1(167.97,64.3) 168.08,64.41 168.63,64.41 169.03,64.01 171.24,64.01 171.69,64.45 173.3,64.45
  TOP w0.102: RPC9.8 179.99,64.57 179.73,64.83 174.75,64.83 174.59,64.67 173.52,64.67 173.3,64.45
  BOTTOM w0.076: v2(167.67,63.84) 167.5,63.66 UC1.V6
SATA_ACT#: length 187.1
  TOP w0.102: v2(257.44,56.36) 257.6,56.36 v4(259.48,58.24) 262.46,61.21 266.6,61.21 269.73,58.08 269.73,54.39 271.65,52.48 271.65,48.78 275.77,44.66 275.77,38.61 272.68,35.52 272.68,33.03 272.03,32.39 272.03,26.89 273.38,25.54 273.64,25.54 274.57,24.61 274.57,21.74 272.95,20.12 272.95,17.96 273.1,17.8 QZ3.4
  IN1 w0.102: v2(173.14,64.82) 173.14,65.76 175,67.62 175,69.68 173.96,70.72 173.96,78.37 175.8,80.21 175.8,81.71 176.58,82.48 179.75,82.48 180.46,83.2 186.81,83.2 188.74,81.26 188.74,80.9 190.33,79.31 190.33,78.59 196.71,72.21 216.05,72.21 217.79,73.95 229.5,73.95 233.11,70.34 233.11,61.94 239.7,55.35 244.08,55.35 244.74,56.01 248.23,56.01 248.89,55.35 254.67,55.35 255.19,55.87 256.94,55.87 v2(257.44,56.36)
  BOTTOM w0.076: v2(173.14,64.82) 172.07,63.75 169.74,63.75 UC1.U3
SATA_COMP: length 9.7
  BOTTOM w0.127: UC1.C12 163.67,72.96 163.31,73.32 163.31,73.77 163.17,73.91 163.17,75.75 162.91,76.01 162.46,76.01 162.16,76.3
  BOTTOM w0.381: 162.16,76.3 161.33,77.14 161.33,77.61 v4(160.3,78.63) 159.81,79.12 159.81,80.04 RC17.1
SATA_LED: length 14.5
  TOP w0.102: v2(270.69,14.24) 271.33,14.24 v4(272.86,15.76) 274.56,17.46 274.56,19.83 QZ4.3 ; JLED1.3 267.15,13.56 v2(267.62,14.03)
  IN1 w0.102: v2(267.62,14.03) 270.48,14.03 v2(270.69,14.24)
SATA_LED#: length 5.7
  TOP w0.102: QZ3.6 273.51,20.18 275,21.67 v4(276.1,21.67) 276.34,21.42 QZ4.2
SATA_PRX_DTX_N1: length 128.8
  TOP w0.102: CN25.1 260.82,23.57 260.82,24.18 v2(260.92,24.28)
  IN2 w0.086: v2(166.83,68.64) 167.05,68.86 167.28,68.86 167.99,68.15 169.67,68.15 170.38,67.44 172.98,67.44 173.43,66.98 177.51,66.98 178.06,66.43 180.82,66.43 181.37,66.98 183.67,66.98 186.55,64.1 186.55,63.19 186.86,62.88 186.86,55.07 187.09,54.84 187.09,53.76 186.75,53.42 186.75,44.21 198.9,32.05 222.11,32.05 223.5,30.67 227.41,30.67 228.44,31.7 235.06,31.7 236.9,29.87 240.38,29.87 241.17,29.08 245.74,29.08 248.41,26.41 254.12,26.41 257.23,23.29 260.53,23.29 260.84,23.6 260.84,24.21 v2(260.92,24.28)
  BOTTOM w0.076: v2(166.83,68.64) 166.47,68.29 UC1.J8
SATA_PRX_DTX_N1_C: length 4.9
  TOP w0.102: CN25.2 260.74,22.07 260.74,21.74 261.19,21.29 261.22,21.29 261.62,20.89 v3(262.76,20.89) 263.05,20.89 263.42,20.52 263.42,20.29 263.54,20.17 UN2.4
SATA_PRX_DTX_N1_RP: length 2
  TOP w0.102: UN2.12 263.54,15.25 263.4,15.1 263.4,14.77 263.21,14.58 263.21,14.4 CN18.2
SATA_PRX_DTX_N1_RP_C: length 10
  TOP w0.102: v2(263.55,12.39) 263.22,12.72 263.22,12.84 CN18.1
  BOTTOM w0.102: JSATA1.5 260.94,12.04 261.27,12.36 261.27,12.38 261.64,12.76 261.66,12.76 262.21,13.31 262.96,13.31 263.36,12.92 263.36,12.57 263.54,12.39 v2(263.55,12.39)
SATA_PRX_DTX_P1: length 128.8
  TOP w0.102: v2(260.33,24.28) 260.6,24.02 260.6,23.49 260.42,23.32 CN26.1
  IN2 w0.086: v2(166.83,69.23) 167.02,69.03 167.35,69.03 168.06,68.32 169.74,68.32 170.45,67.61 173.05,67.61 173.5,67.16 177.58,67.16 178.13,66.61 180.75,66.61 181.3,67.16 183.74,67.16 186.72,64.17 186.72,63.26 187.03,62.95 187.03,55.15 187.27,54.91 187.27,53.69 186.93,53.35 186.93,44.28 198.98,32.23 222.19,32.23 223.57,30.85 227.34,30.85 228.37,31.88 235.13,31.88 236.97,30.05 240.45,30.05 241.25,29.25 245.81,29.25 248.49,26.58 254.19,26.58 257.3,23.47 260.46,23.47 260.67,23.67 260.67,23.95 v2(260.33,24.28)
  BOTTOM w0.076: v2(166.83,69.23) 166.54,68.94 UC1.H8
SATA_PRX_DTX_P1_C: length 4.9
  TOP w0.102: CN26.2 260.53,22.06 260.53,21.65 v3(261.3,20.88) 261.5,20.68 262.4,20.68 262.42,20.66 262.98,20.66 263.2,20.43 263.2,20.33 263.04,20.17 UN2.5
SATA_PRX_DTX_P1_RP: length 2
  TOP w0.102: CN17.2 262.99,14.42 262.99,14.67 263.18,14.86 263.18,15.09 263.04,15.22 UN2.11
SATA_PRX_DTX_P1_RP_C: length 10
  TOP w0.102: CN17.1 263,12.8 263,12.66 v2(262.74,12.39)
  BOTTOM w0.102: v2(262.74,12.39) 262.93,12.2 263.05,12.2 263.14,12.29 263.14,12.83 262.87,13.09 262.3,13.09 v3(261.62,12.41) 261.16,11.95 261.16,7.59 261.44,7.31 JSATA1.6
SATA_PTX_DRX_N1: length 144.7
  TOP w0.102: v2(262.19,24.28) 262.21,24.28 262.43,24.06 262.43,23.72 262.03,23.32 CN30.1
  IN2 w0.086: v2(161.19,74.36) 161.07,74.36 160.93,74.22 160.93,74.12 160.78,73.96 160.78,72.02 160.47,71.72 160.47,68.6 161.41,67.67 166.23,67.67 166.65,67.26 168.44,67.26 168.66,67.04 170.52,67.04 171.08,66.48 177.27,66.48 178.26,65.49 180.7,65.49 181.72,66.51 183.46,66.51 185.75,64.22 185.75,63.32 186.39,62.68 186.39,54.88 186.63,54.65 186.63,53.96 186.29,53.62 186.29,47.24 185.95,46.9 185.95,44.32 198.68,31.59 221.86,31.59 223.25,30.2 227.6,30.2 228.04,30.64 235.46,30.64 236.74,29.36 240.23,29.36 240.99,28.6 245.52,28.6 248.19,25.93 253.92,25.93 257.03,22.82 261.95,22.82 262.6,23.47 262.6,23.89 262.21,24.28 v2(262.19,24.28)
  BOTTOM w0.076: v2(161.19,74.36) 160.87,74.03 160.87,73.8 160.7,73.63 160.7,73.42 160.79,73.33 161.01,73.33 161.09,73.41 UC1.A17
SATA_PTX_DRX_N1_C: length 4.5
  TOP w0.102: CN30.2 262.37,22.06 262.37,21.82 262.65,21.54 263.59,21.54 264.04,21.08 264.04,21.06 264.46,20.65 264.47,20.65 264.68,20.45 264.68,20.27 264.54,20.13 UN2.2
SATA_PTX_DRX_N1_RP: length 2
  TOP w0.102: UN2.14 264.54,15.25 264.68,15.11 264.68,14.72 264.82,14.58 264.82,14.4 CN20.2
SATA_PTX_DRX_N1_RP_C: length 14.1
  TOP w0.102: v2(264.55,12.49) 264.66,12.49 264.82,12.65 264.82,12.94 264.6,13.16 CN20.1
  BOTTOM w0.102: JSATA1.3 259.94,7.45 259.89,7.51 259.74,7.51 259.66,7.58 259.66,8.51 260.33,9.18 260.33,12.45 261.82,13.93 v3(263.17,13.93) 264.4,13.93 265.05,13.28 265.05,12.82 264.89,12.66 264.89,12.51 264.78,12.39 264.65,12.39 v2(264.55,12.49)
SATA_PTX_DRX_P1: length 144.8
  TOP w0.102: v2(262.77,24.28) 262.65,24.15 262.65,23.58 CN23.1
  IN2 w0.086: v2(160.61,74.36) 160.6,74.35 160.6,72.09 160.3,71.79 160.3,68.53 161.33,67.5 166.16,67.5 166.58,67.08 168.37,67.08 168.58,66.86 170.45,66.86 171.01,66.31 177.2,66.31 178.19,65.32 180.77,65.32 181.79,66.34 183.38,66.34 185.57,64.14 185.57,63.25 186.22,62.6 186.22,54.81 186.45,54.57 186.45,54.03 186.11,53.69 186.11,47.31 185.77,46.97 185.77,44.25 198.61,31.41 221.79,31.41 223.18,30.03 227.68,30.03 228.11,30.46 235.39,30.46 236.67,29.19 240.15,29.19 240.92,28.42 245.45,28.42 248.12,25.76 253.85,25.76 256.96,22.65 262.02,22.65 262.77,23.4 v2(262.77,24.28)
  BOTTOM w0.076: UC1.B17 160.75,72.86 160.79,72.91 160.79,73.06 160.51,73.34 160.51,73.71 160.68,73.88 160.68,74.28 v2(160.61,74.36)
SATA_PTX_DRX_P1_C: length 4.4
  TOP w0.102: UN2.1 265.04,20.13 264.89,20.28 264.89,20.54 v3(264.4,21.03) 263.67,21.75 262.74,21.75 262.58,21.91 262.58,22.07 CN23.2
SATA_PTX_DRX_P1_RP: length 2
  TOP w0.102: CN19.2 265.03,14.42 265.03,14.67 264.9,14.81 264.9,15.11 265.04,15.26 UN2.15
SATA_PTX_DRX_P1_RP_C: length 14.1
  TOP w0.102: CN19.1 265.19,13.16 265.03,13 265.03,12.76 v2(265.3,12.49)
  BOTTOM w0.102: JSATA1.2 259.44,8.6 260.12,9.27 260.12,12.54 261.73,14.15 262.89,14.15 262.9,14.16 263.43,14.16 263.45,14.15 264.49,14.15 265.26,13.37 265.26,12.53 v2(265.3,12.49)
SD/MMCCD#: length 23.1
  TOP w0.102: v2(273.85,27.08) CR35.1 RR11.1 276.18,26.36 276.18,23.53 277.49,22.22 v4(281.24,22.22) 284.4,22.22 285.21,23.04 285.21,26.83 285.72,27.34 UR1.21
  BOTTOM w0.102: JSD1.18 272.56,28.37 v2(273.85,27.08)
SD/MMCCLK: length 28.7
  TOP w0.102: v2(283.19,37.52) 283.49,37.82 CR23.1 RR1.2
  BOTTOM w0.102: v2(283.19,37.52) 283.3,37.62 283.3,38.24 282.15,39.38 280.05,39.38 278.76,40.67 273.22,40.67 271.82,39.27 271.12,39.27 270.05,38.2 270.05,35.32 269.4,34.67 v1(269.4,34.14) 269.4,30.02 269.65,29.77 JSD1.5
SD/MMCCLK_R: length 2.3
  TOP w0.102: UR1.43 284.52,34.35 283.89,34.98 v1(283.89,35.06) RR1.1
SD/MMCCMD: length 30.4
  TOP w0.102: UR1.45 283.72,34.52 283.23,35 v2(283.23,35.55)
  BOTTOM w0.102: v2(283.23,35.55) 281.08,35.55 280.43,34.9 279.93,34.9 279.8,34.77 279.8,33.54 279.67,33.41 279.42,33.41 279.29,33.54 279.29,34.81 279.16,34.94 278.91,34.94 278.78,34.81 278.78,33.53 278.66,33.4 278.4,33.4 278.28,33.53 278.28,34.78 278.15,34.91 277.89,34.91 277.77,34.78 277.77,33.53 277.64,33.4 277.39,33.4 277.26,33.53 277.26,34.81 277.13,34.94 276.71,34.94 276.58,34.81 276.58,34.59 276.45,34.46 276.18,34.46 276.06,34.59 276.06,34.81 275.93,34.94 275.42,34.94 275.3,34.81 275.3,33.04 275.17,32.92 274.88,32.92 274.76,33.04 274.76,34.82 274.63,34.95 274.38,34.95 274.25,34.82 274.25,33.02 274.12,32.89 273.82,32.89 273.7,33.02 273.7,35.04 273.26,35.47 JSD1.2
SD/MMCDAT0: length 33.7
  TOP w0.089: UR1.38 286.52,34.49 286.88,34.85 287.42,34.85 v2(287.55,34.98) ; v2(289.23,30.33) 288.8,30.76 288.28,30.76 288.23,30.71 UR1.30
  IN2 w0.089: v2(273.75,24.47) 273.75,24.9 273.95,25.09 274.24,25.09 275.69,23.65 279.38,23.65 279.82,24.08 287.39,24.08 288.08,24.78 288.08,27.09 289.07,28.08 289.07,30.18 v2(289.23,30.33) 289.23,30.35 289.07,30.5 289.07,31.1 288.49,31.69 288.49,34.33 288.11,34.71 287.82,34.71 v2(287.55,34.98)
  BOTTOM w0.089: v2(273.75,24.47) 273.75,24.99 273.17,25.57 JSD1.7
SD/MMCDAT1: length 32.5
  TOP w0.089: UR1.37 286.91,33.96 286.91,34.32 287.04,34.45 287.42,34.45 287.54,34.34 v2(287.54,34.16) ; UR1.29 288.17,30.31 288.34,30.14 288.58,30.14 288.64,30.2 288.64,30.3 v2(288.59,30.35)
  IN2 w0.089: v2(287.54,34.16) 287.75,34.38 287.97,34.38 288.16,34.19 288.16,31.55 288.74,30.96 288.74,30.5 v2(288.59,30.35) 288.74,30.2 288.74,28.22 287.75,27.23 287.75,24.91 287.25,24.41 279.68,24.41 279.25,23.98 275.83,23.98 274.38,25.42 273.81,25.42 273.42,25.03 273.42,24.73 v2(273.17,24.47)
  BOTTOM w0.089: JSD1.8 272.61,24.17 272.69,24.26 272.69,25.08 272.79,25.18 273.01,25.18 273.36,24.82 273.36,24.66 v2(273.17,24.47)
SD/MMCDAT2: length 2.4
  TOP w0.102: UR1.48 282.52,34.36 v1(281.89,34.99) 281.68,35.19 RR4.1
SD/MMCDAT2_R: length 29
  TOP w0.102: v2(281.68,37.59) 281.68,36.89 RR4.2
  BOTTOM w0.102: JSD1.9 272.94,38.27 273.22,38.55 273.22,40.09 273.35,40.22 273.6,40.22 273.73,40.09 273.73,38.88 273.85,38.76 274.11,38.76 274.23,38.88 274.23,40.09 274.36,40.22 274.62,40.22 274.74,40.09 274.74,38.88 274.87,38.76 275.12,38.76 275.25,38.88 275.25,40.09 275.38,40.22 275.63,40.22 275.76,40.09 275.76,38.88 275.89,38.76 276.14,38.76 276.27,38.88 276.27,40.12 276.39,40.25 276.65,40.25 276.77,40.12 276.77,38.88 276.9,38.76 277.16,38.76 277.28,38.88 277.28,40.14 277.41,40.26 277.66,40.26 277.79,40.14 277.79,38.88 277.92,38.76 278.17,38.76 278.3,38.88 278.3,40.05 278.43,40.17 278.68,40.17 278.81,40.05 278.81,38.88 278.93,38.76 280.49,38.76 280.62,38.63 280.62,38.42 280.74,38.3 281.04,38.3 281.16,38.42 281.16,38.85 281.29,38.98 281.56,38.98 281.68,38.85 v2(281.68,37.59)
SD/MMCDAT3: length 2.2
  TOP w0.102: UR1.47 282.92,34.57 282.57,34.91 RR3.1
SD/MMCDAT3_R: length 27
  TOP w0.102: RR3.2 v2(282.57,37.54)
  BOTTOM w0.102: v2(282.57,37.54) 282.8,37.31 282.8,36.09 282.67,35.96 282.32,35.96 282.19,36.09 282.19,37.07 282.06,37.2 281.8,37.2 281.67,37.07 281.67,36.18 281.54,36.05 281.2,36.05 281.07,36.18 281.07,36.89 280.95,37.02 279.63,37.02 279.52,36.92 279.52,36.48 279.4,36.36 279.14,36.36 279.02,36.48 279.02,37.22 278.89,37.35 278.64,37.35 278.51,37.22 278.51,36.47 278.41,36.37 278.1,36.37 278,36.47 278,37.22 277.87,37.35 277.62,37.35 277.49,37.22 277.49,36.47 277.39,36.37 277.09,36.37 276.98,36.47 276.98,37.22 276.86,37.35 276.6,37.35 276.48,37.22 276.48,36.47 276.37,36.37 276.07,36.37 275.97,36.47 275.97,37.22 275.84,37.35 275.59,37.35 275.46,37.22 275.46,36.47 275.36,36.37 275.05,36.37 274.95,36.47 274.95,37.22 274.83,37.35 274.57,37.35 274.44,37.22 274.44,36.47 274.34,36.37 274.04,36.37 273.94,36.47 273.94,37.22 273.81,37.35 273.56,37.35 273.43,37.22 273.43,36.49 273.3,36.36 273.11,36.36 272.6,36.87 JSD1.1
SD_REXT: length 5
  TOP w0.102: v1(291.97,27.25) 291.82,27.41 290.55,27.41 RR5.1 289.01,28.26 288.16,29.11 UR1.26
SD_UHS2_D0N: length 22.7
  TOP w0.089: UR1.34 287.77,32.31 288.51,32.31 288.92,32.73 289.8,32.73 v2(289.89,32.65)
  IN2 w0.089: v2(296.63,44.35) 296.63,42.27 292.05,37.68 292.05,34.34 292.22,34.16 293.36,34.16 293.68,33.84 293.68,32.97 293.36,32.65 v2(289.89,32.65)
  BOTTOM w0.089: v2(296.63,44.35) 296.63,44.94 296.9,45.21 JSD1.12
SD_UHS2_D0P: length 22.7
  TOP w0.089: v2(289.89,33.31) 289.7,33.12 288.76,33.12 288.34,32.71 UR1.35
  IN2 w0.089: v2(289.89,33.31) 289.89,33.21 290.12,32.98 293.23,32.98 293.35,33.1 293.35,33.71 293.23,33.83 292.08,33.83 291.72,34.2 291.72,37.82 296.3,42.4 296.3,44.09 v2(296.05,44.35)
  BOTTOM w0.089: v2(296.05,44.35) 296.24,44.54 296.24,44.86 295.8,45.29 JSD1.11
SD_UHS2_D1N: length 22.7
  TOP w0.089: UR1.33 289.79,31.91 v2(289.89,32)
  IN2 w0.089: v2(289.89,32) 290.02,31.86 294.18,31.86 294.75,31.29 294.75,20.78 296.73,18.8 296.73,18.28 296.73,18.28 v2(296.73,18.09)
  BOTTOM w0.089: JSD1.15 296.9,17.46 296.73,17.63 v2(296.73,18.09)
SD_UHS2_D1P: length 22.7
  TOP w0.089: v2(289.89,31.41) 289.79,31.51 288.28,31.51 288.27,31.51 UR1.32
  IN2 w0.089: v2(289.89,31.41) 290.01,31.53 294.04,31.53 294.42,31.15 294.42,20.64 296.4,18.66 296.4,18.42 v2(296.07,18.09)
  BOTTOM w0.089: v2(296.07,18.09) 296.34,17.82 296.34,17.69 296.21,17.56 295.93,17.56 295.8,17.43 JSD1.16
SDWP: length 19.5
  TOP w0.102: v2(284.8,23.52) 284.8,26.96 285.32,27.47 UR1.20 ; v2(274.98,22.29) v4(274.98,23.11)
  IN2 w0.102: v2(284.8,23.52) 283.13,21.84 275.42,21.84 v2(274.98,22.29)
  BOTTOM w0.102: JSD1.19 272.68,22.77 273.16,22.29 v2(274.98,22.29)
SIO_EXT_SCI#: length 158.7
  TOP w0.076: v2(167.78,65.7) 168.35,66.27 170.19,66.27 170.41,66.05 v1(170.81,66.05) 173.25,66.05 173.36,66.16
  TOP w0.102: UE2.A33 255.19,36.52 v2(255.38,36.33) ; RC156.1 175.95,65.89 175.5,66.35 173.55,66.35 173.36,66.16
  IN1 w0.102: v2(245.17,60.73) 245.17,60.95 244.55,61.57 241.54,61.57 235.35,67.76 235.35,73.92 232.63,76.64 231.06,76.64 229.51,78.2 218.08,78.2 214.89,75.01 197.88,75.01 193.18,79.71 193.18,80.43 192.97,80.63 192.97,80.64 191.54,82.08 191.54,82.43 190,83.97 190,84.38 190,84.55 188.52,86.03 188.32,86.03 188.3,86.04 175.7,86.04 170.66,81 170.66,77.36 169.61,76.31 169.61,71.13 170.2,70.54 170.2,68.73 169.83,68.36 169.83,67.07 170.38,66.52 170.38,65.63 169.94,65.19 168.27,65.19 167.78,65.68 v2(167.78,65.7)
  IN2 w0.102: v2(255.38,36.33) 255.16,36.55 246.4,36.55 v2(245.72,37.23)
  BOTTOM w0.076: v2(167.78,65.7) 167.78,65.85 UC1.N5
  BOTTOM w0.102: v2(245.72,37.23) 245.92,37.43 245.92,40.65 245.17,41.4 245.17,46.94 244.51,47.6 244.51,57.85 244.76,58.1 244.76,60.32 v2(245.17,60.73)
SIO_EXT_SMI#: length 129.9
  TOP w0.102: v2(260.66,49.3) 260.19,48.83 UE2.A6 ; v2(180.99,60.46) 180.99,59.98 181.63,59.33 182.83,59.33 183.85,60.36 RPC5.5
  IN1 w0.102: v2(230.44,69.21) 230.44,69.52 228.03,71.93 217.93,71.93 216.89,70.89 193.91,70.89 192.93,69.91 191.84,69.91 186.64,64.71 186.64,63.85 185.68,62.89 185.31,62.89 184.01,61.59 181.68,61.59 180.99,60.9 v2(180.99,60.46) 179.83,59.31 174.99,59.31 174.44,58.76 173.44,58.76 173.16,59.04 172.2,59.04 172.13,59.11 v2(168.42,59.11)
  IN2 w0.102: v2(230.44,69.21) 231.01,68.64 262.79,68.64 v2(263.2,68.22)
  BOTTOM w0.076: v2(168.42,59.11) 168.42,59.1 168.15,58.82 UC1.AG5
  BOTTOM w0.102: v2(263.2,68.22) 263.03,68.05 v1(263.03,62.18) 263.03,58.92 260.46,56.35 260.46,55.3 260.94,54.81 260.94,53.16 260.54,52.76 260.54,49.43 v2(260.66,49.3)
SIO_EXT_WAKE#: length 129.6
  TOP w0.102: UE2.B5 260.94,46.46 261,46.41 v2(261.01,46.41)
  IN1 w0.102: v2(181.68,57.07) 181.75,57 182.87,57 184.62,58.75 185.53,58.75 189.77,62.99 189.77,64.32 190.87,65.42 193.43,65.42 196.44,68.43 217.86,68.43 218.35,68.91 227.24,68.91 227.45,68.71 228.1,68.71 228.48,68.33 v2(228.48,68.04)
  IN2 w0.102: v2(228.48,68.04) 228.8,68.36 257.08,68.36 257.77,67.68 263.26,67.68 263.8,68.22 v2(264.64,68.22)
  BOTTOM w0.076: UC1.AU2 170.46,53.19 171.02,53.19 171.1,53.1 172.13,53.1 173.36,54.32
  BOTTOM w0.102: 173.36,54.32 173.4,54.36 173.4,54.76 175.86,57.23 181.52,57.23 v2(181.68,57.07) 182.77,57.07 182.97,57.26 RPC7.6 ; v2(264.64,68.22) 264.64,57.91 261.76,55.03 261.76,52.78 261.36,52.39 261.36,50.8 261.77,50.39 261.77,48.32 261,47.55 v1(261,47.48) 261,46.42 v2(261.01,46.41)
SIO_PWRBTN#: length 266.5
  TOP w0.076: v2(167.02,57.2) 166.67,56.86 166.67,51.16
  TOP w0.102: UE2.B58 262.35,41.46 v2(262.27,41.38) ; v2(175.31,34.51) 175.31,35.28 168.8,41.79 168.8,43.06 168.89,43.15 168.89,45.01 169.01,45.12 169.01,45.91 168.87,46.05 168.87,49.3 167.52,50.65 167.18,50.65 166.67,51.16 ; JXDP1.41 79.27,50.7 79.49,50.91 80.27,50.91 80.71,50.48 80.71,44.85 83.04,42.52 86.45,42.52 87.08,41.88 v1(87.08,39.38) 87.08,39.37 84.69,36.98 v2(84.67,36.98)
  IN1 w0.102: v2(255.37,27.89) 259.65,32.17 259.65,32.93 260.82,34.11 260.82,37.34 261.8,38.32 261.8,39.61 261.86,39.67 261.86,40.97 v2(262.27,41.38)
  IN2 w0.102: v2(175.31,34.51) 175.89,35.09 176.51,35.09 190,21.6 190,18.66 191.42,17.25 220.02,17.25 220.91,16.35 226.63,16.35 228.53,14.45 234.44,14.45 235.69,15.71 239.08,15.71 242.66,12.13 248.69,12.13 v2(249.18,11.63)
  BOTTOM w0.076: UC1.AL7 167.04,57.17 v2(167.02,57.2)
  BOTTOM w0.102: v2(175.31,34.51) 174.05,33.25 156.79,33.25 155.01,31.47 90.18,31.47 v2(84.67,36.98) ; v2(249.18,11.63) 249.18,13.83 250.31,14.96 250.31,20.92 255.37,25.98 v2(255.37,27.89)
SIO_RCIN#: length 149.7
  TOP w0.076: 173.36,63.94 172.12,63.94 171.68,63.5 168.71,63.5 v2(168.4,63.81)
  TOP w0.102: UE2.A27 252.58,41.21 252.4,41.03 v2(252.11,41.03) ; 173.36,63.94 175.02,63.94 v1(175.21,64.13) 179.03,64.13 180.09,63.08 RPC15.1
  IN1 w0.102: v2(248.88,57.54) 247.77,58.65 245.72,58.65 243.91,60.45 241.2,60.45 234.27,67.37 234.27,73.73 232.32,75.68 230.68,75.68 229.74,76.62 217.76,76.62 215.26,74.12 197.51,74.12 192.29,79.34 192.29,80.06 190.65,81.7 190.65,82.06 187.59,85.13 176.15,85.13 171.55,80.53 171.55,76.99 170.42,75.86 170.42,71.23 170.94,70.71 170.94,65.34 169.41,63.81 v2(168.4,63.81)
  BOTTOM w0.076: v2(168.4,63.81) 168.83,63.38 UC1.V4
  BOTTOM w0.102: v2(252.11,41.03) 251.93,41.03 248.88,44.08 248.88,46.08 247.91,47.04 247.91,51.26 248.52,51.87 248.52,57.19 v2(248.88,57.54)
SIO_SLP_A#: length 171.8
  TOP w0.102: v2(191.32,53.57) 191.32,52.74 191.21,52.63 UC6.1 ; UE2.B28 254.95,41.46 255,41.52 255.56,41.52 v2(256.01,41.96) ; v2(292.91,37.53) 292.62,37.24 v1(292.62,33.3) 292.62,32.58 297.51,27.69 JAPS1.6
  IN1 w0.102: v2(229.46,41.99) 229.31,41.83 218.49,41.83 218.02,42.3 209.95,42.3 204.59,47.65 203.02,47.65 197.46,53.21 191.68,53.21 v2(191.32,53.57) 191.13,53.57 190.77,53.21 189.35,53.21 188.97,52.83 182.81,52.83 182.51,53.14 182.51,53.48 179.4,56.59 176.14,56.59 174.73,55.18 173.87,55.18 172.86,54.16 170.33,54.16 170.19,54.31 168.27,54.31 168.06,54.52 168.06,57.05 v2(167.9,57.2)
  IN2 w0.102: v2(229.46,41.99) 229.75,41.7 230.62,41.7 231.54,40.78 232.13,40.78 235.6,37.31 240.63,37.31 241.65,38.33 242.82,38.33 244.43,39.94 247.43,39.94 250.14,42.65 253.59,42.65 253.85,42.39 255.59,42.39 v2(256.01,41.96)
  BOTTOM w0.076: v2(167.9,57.2) 167.73,57.03 167.73,56.88 UC1.AL5
  BOTTOM w0.102: v2(256.01,41.96) 256.55,41.43 256.55,39.97 258.96,37.55 260.93,37.55 261.25,37.24 263.95,37.24 264.08,37.11 266.13,37.11 267.22,38.2 267.22,39.94 267.45,40.17 267.45,42.84 270.5,45.9 274.34,45.9 277.76,42.48 281.33,42.48 286.28,37.53 v2(292.91,37.53)
SIO_SLP_LAN#: length 129.8
  TOP w0.102: v2(245.28,39.49) 244.17,40.61 244.17,45.72 243.08,46.81 243.08,51.74 v2(243.37,52.03) v4(243.37,54.11) 243.37,55.19 244.26,56.08 244.26,58.28 243.98,58.56 243.28,58.56 243.14,58.42 UZ2.5 ; UE2.B37 255.94,38.17 255.88,38.23 255.88,38.9 256.14,39.17 v2(256.14,39.42)
  IN1 w0.102: v2(166.52,58.1) 166.98,57.64 168.32,57.64 168.42,57.54 173.13,57.54 173.54,57.95 174.78,57.95 175.33,58.5 180.45,58.5 181.25,57.7 181.92,57.7 182.19,57.43 182.73,57.43 184.47,59.17 185.37,59.17 189.35,63.16 189.35,64.47 190.71,65.82 193.26,65.82 196.27,68.83 217.7,68.83 218.18,69.32 227.41,69.32 227.62,69.11 228.27,69.11 231,66.39 231,60.2 239.17,52.03 v2(243.37,52.03)
  IN2 w0.102: v2(245.28,39.49) 245.53,39.24 254.2,39.24 254.58,39.62 255.94,39.62 v2(256.14,39.42)
  BOTTOM w0.076: v2(166.52,58.1) 166.52,57.84 166.72,57.64 UC1.AJ7
SIO_SLP_S0#: length 179.6
  TOP w0.102: JAPS1.15 299.38,23.19 298.42,24.15 298.42,25.41 291.86,31.98 291.86,40.75 v2(291.48,41.13)
  IN1 w0.102: v2(192.44,70.37) 192.01,70.37 186.05,64.42 185.47,64.42 183.96,62.9 181.13,62.9 179.86,61.63 178.1,61.63 176.66,60.2 174.61,60.2 174.15,59.74 172.32,59.74 171.91,60.15 v2(171.91,60.15)
  IN2 w0.102: v2(192.44,70.37) 192.92,70.85 192.92,74.2 196.22,77.49 212.23,77.49 219.5,70.22 233.65,70.22 234.1,69.77 243.65,69.77 244.76,70.89 253.29,70.89 254.93,69.24 270.66,69.24 v2(272.98,66.92)
  BOTTOM w0.076: v2(171.91,60.15) 171.54,59.78 170.96,59.78 170.91,59.83 170.66,59.83 170.49,59.66 170.49,59.49 170.25,59.25 169.74,59.25 UC1.AF3
  BOTTOM w0.102: v2(272.98,66.92) v1(272.98,66.08) 274.06,65 274.06,58.66 273.39,57.99 273.39,53.31 283.06,43.64 283.95,43.64 287.29,40.31 290.65,40.31 v2(291.48,41.13)
SIO_SLP_S3#: length 194.7
  TOP w0.081: RE280.1 170.8,44.59 170.8,44.18 171.41,43.57 171.55,43.57 171.96,43.16 171.96,42.86
  TOP w0.102: v2(168.38,53.17) 168.33,53.17 168.01,52.84 168.01,51.78 169.72,50.06 169.72,46.38 169.87,46.23 169.87,45.52 RE280.1 ; JAPS1.2 296.91,29.69 293.76,32.83 293.76,35.57 294.22,36.03 v2(294.22,37.52) ; 171.96,42.86 171.96,40.66 v4(175,37.62) 178.11,34.51 v2(178.13,34.51) ; UE2.A35 256.19,36.34 v2(256.23,36.29)
  IN2 w0.102: v2(252.59,52.26) 252.3,51.97 248.16,51.97 247.62,51.43 246.15,51.43 243.46,48.73 238.21,48.73 234.28,44.8 233.84,44.8 232.69,43.65 226.14,43.65 225.53,43.04 219.74,43.04 218.53,44.25 215.52,44.25 214.22,42.95 206.68,42.95 v2(206.27,42.54)
  BOTTOM w0.076: v2(168.38,53.17) 168.72,53.51 UC1.AT4
  BOTTOM w0.102: v2(178.13,34.51) 178.13,33.5 180.21,31.42 206.03,31.42 208.1,33.49 208.1,41.44 207.62,41.92 206.89,41.92 v2(206.27,42.54) ; v2(252.59,52.26) 253.01,51.84 253.01,48.15 254.06,47.1 254.06,42.71 254.34,42.43 254.34,39.06 253.79,38.52 253.79,37.29 254.16,36.92 255.6,36.92 v2(256.23,36.29) 256.56,36.29 256.94,36.66 260.56,36.66 261.03,36.19 262.71,36.19 262.83,36.07 262.84,36.07 263.29,35.61 265.89,35.61 270.6,40.32 270.6,40.97 271.19,41.56 280.6,41.56 281.55,40.61 282.14,40.61 284.13,38.61 284.13,38.02 285.32,36.84 286.14,36.84 286.15,36.84 293.54,36.84 v2(294.22,37.52)
SIO_SLP_S4#: length 205.8
  TOP w0.076: 166.43,51.07 166.43,57.38 v2(167.15,58.1)
  TOP w0.102: v2(293.6,37.52) 293.11,37.03 293.11,32.77 297.69,28.19 JAPS1.5 ; v2(174.55,34.52) 174.55,35.36 168.32,41.59 168.32,43.14 168.53,43.34 168.53,44.18 RE282.1 168.08,45.4 168.41,45.73 168.41,49.4 167.42,50.39 167.1,50.39 166.43,51.07 ; v2(254.29,37.78) 254.29,36.83 T9.1 252.94,35.48 v2(252.94,33.46) ; UE2.B36 v2(255.44,38.53)
  IN2 w0.102: v2(248,10.58) 246.66,10.58 245.8,11.44 241.28,11.44 239.44,13.28 228.7,13.28 226.32,15.66 220.63,15.66 219.82,16.47 191.22,16.47 189.18,18.52 189.18,21.46 176.97,33.67 175.4,33.67 v2(174.55,34.52)
  BOTTOM w0.076: UC1.AJ6 167.5,57.76 v2(167.15,58.1)
  BOTTOM w0.102: v2(254.29,37.78) 255.03,38.53 v2(255.44,38.53) 257.1,36.87 260.64,36.87 261.05,36.46 263.64,36.46 264.04,36.05 266.04,36.05 270.39,40.4 270.39,41.06 271.1,41.76 280.68,41.76 281.64,40.81 282.23,40.81 284.34,38.7 284.34,38.11 285.4,37.05 293.13,37.05 v2(293.6,37.52) ; v2(248,10.58) 248.1,10.68 248.1,13.91 249.63,15.43 249.63,21.21 254.59,26.17 254.59,30.34 252.94,31.99 v2(252.94,33.46)
SIO_SLP_S5#: length 214.2
  TOP w0.076: v2(167.51,55.06) 167.05,54.61 167.05,53.14
  TOP w0.102: v2(175.96,34.51) 175.96,35.43 169.28,42.11 169.28,44.87 169.35,44.94 T8.1 169.35,49.2 167.46,51.09 167.46,52.73 167.05,53.14 ; JAPS1.4 297.55,28.69 293.53,32.71 v2(293.53,36.22) ; UE2.A18 252.77,45.71 252.51,45.45 v2(251.94,45.45)
  IN2 w0.102: v2(175.96,34.51) 176.42,34.51 189.38,21.54 189.38,18.6 191.31,16.67 219.91,16.67 220.71,15.87 226.43,15.87 228.82,13.48 239.52,13.48 241.36,11.65 245.98,11.65 246.64,10.98 248.19,10.98 v2(248.61,10.57) ; v2(248.4,45.81) 248.82,46.23 251.16,46.23 v2(251.94,45.45)
  BOTTOM w0.076: UC1.AP5 167.79,54.78 v2(167.51,55.06)
  BOTTOM w0.102: 253.64,33.9 262.85,33.9 263.8,34.85 265.7,34.85 271,40.15 271,40.8 271.35,41.16 280.43,41.16 281.38,40.2 281.97,40.2 283.73,38.44 283.73,37.85 285.15,36.43 293.32,36.43 v2(293.53,36.22) ; 253.64,33.9 253.64,31.67 254.8,30.52 254.8,26.09 249.83,21.12 249.83,15.28 248.61,14.06 v2(248.61,10.57) ; 253.64,33.9 253.04,34.49 251.9,34.49 250.23,36.17 250.23,41.51 248.4,43.33 v2(248.4,45.81)
SIO_SLP_SUS#: length 119.6
  TOP w0.102: UE2.B52 263.92,38.46 264.56,37.82 265.82,37.82 266.28,37.36 266.28,35.31 266.08,35.1 v1(266.02,35.1) 266.09,35.04 266.09,34.58 v2(266.32,34.35)
  IN1 w0.102: v2(168.45,54.67) 170.25,54.67 170.58,55 172.37,55 172.44,54.93 172.91,54.93 173.65,55.67 174.52,55.67 174.55,55.69 174.55,55.69 175.94,57.07 179.6,57.07 182.56,54.11 183.19,54.11 183.72,53.59 186.38,53.59 186.54,53.75 188.81,53.75 189.32,54.25 197.1,54.25 203.18,48.17 204.76,48.17 210.15,42.78 218.38,42.78 218.84,42.32 226.31,42.32 v2(226.59,42.6)
  IN2 w0.102: v2(226.59,42.6) 227.66,42.6 230.92,39.33 231.53,39.33 232.66,38.2 232.66,36.98 233.78,35.86 241.23,35.86 242.25,36.88 243.97,36.88 245.05,37.96 253.49,37.96 254.44,37.01 257.12,37.01 257.91,36.22 257.91,35.32 259.15,34.07 262.53,34.07 263.22,34.76 265.9,34.76 v2(266.32,34.35)
  BOTTOM w0.076: UC1.AP4 168.79,54.34 v2(168.45,54.67)
SIO_SLP_WLAN#: length 95.7
  TOP w0.102: v2(227.78,68.3) v1(227.78,68.82) ; v2(251.41,70.46) 252.44,69.43 UE3.39
  IN1 w0.102: v2(227.78,68.3) 227.58,68.3 227.16,68.71 218.44,68.71 217.95,68.22 196.55,68.22 193.54,65.21 190.96,65.21 190,64.26 190,62.92 189.39,62.31 189.39,61.45 187.66,59.71 186.78,59.71 185.62,58.55 184.8,58.55 182.91,56.66 181.51,56.66 180.09,58.09 175.5,58.09 174.95,57.54 173.84,57.54 173.44,57.15 170.71,57.15 169.72,56.16 v2(168.48,56.16)
  IN2 w0.102: v2(227.78,68.3) 229.18,69.7 231.2,69.7 231.94,68.96 249.91,68.96 v2(251.41,70.46)
  BOTTOM w0.076: UC1.AM5 168.03,55.93 168.25,55.93 v2(168.48,56.16)
SKIP#: length 2.9
  TOP w0.203: PU500.7 101.79,66.03 101.47,65.72 v1(101.47,65.72)
  TOP w0.254: PR520.2 100.51,64.76 v1(101.47,65.72)
SKIP#1: length 11.4
  TOP w0.254: v2(98.59,64.3) 98.59,64.5 98.85,64.76 PR520.1
  BOTTOM w0.203: 104.25,57.77 104.07,57.59 PU501.1
  BOTTOM w0.254: v2(98.59,64.3) v1(98.59,63.17) 98.59,62.42 100.56,60.45 102.26,60.45 104.25,58.46 104.25,57.77
SLATE_MODE: length 18.1
  TOP w0.076: v2(168.44,57.06) 168.96,56.54 170.05,56.54 171.39,57.88 172.1,57.88 172.73,58.51 173.23,58.51 173.36,58.38
  TOP w0.102: 173.36,58.38 173.41,58.33 v1(178.19,58.33) 181.41,58.33 182.8,56.94 RPC10.6
  BOTTOM w0.076: v2(168.44,57.06) 168.44,56.9 UC1.AL4
SLEEVE: length 5.5
  IN1 w1.27: 25.38,19.44 25.38,20.41 25.11,20.69 25.11,24.05 25.68,24.62
  vias: v1(27.71,17.33) v2(24.31,18.34) v2(24.89,18.34) v2(25.97,25.59) v2(26.55,25.59)
SLEEVE_R:
  vias: v1(15.92,25.17)
SLEWA: length 4.3
  TOP w0.102: v2(106.6,63.8) v1(106.6,63.28)
  TOP w0.203: v2(106.6,63.8) 106.28,63.8 105.55,64.53 PU500.15
  BOTTOM w0.254: PR500.2 v2(106.6,63.8) 106.6,64.74 PR510.1
SM_RCOMP0: length 9
  TOP w0.381: RC130.1 v4(129.98,49.19) 129.98,49.25 134.14,53.4 v2(134.37,53.4)
  BOTTOM w0.229: v2(134.37,53.4) 134.37,53.4 134.37,52.98 UC1.AU60
SM_RCOMP1: length 6.8
  TOP w0.381: RC131.1 130.87,49.12 v4(131.84,50.1) v2(133.74,52)
  BOTTOM w0.229: v2(133.74,52) 133.93,52.18 UC1.AV60
SM_RCOMP2: length 8.5
  TOP w0.381: RC132.1 129.09,49.36 v4(131.69,51.96) v2(133.03,53.3)
  BOTTOM w0.229: UC1.AU61 133.22,53.11 v2(133.03,53.3)
SMART_DET#: length 3.4
  TOP w0.102: UE3.9 250.69,64.01 249.86,63.18 T32.1
SMB_ADDR: length 2.9
  TOP w0.102: v1(255.47,70.57) RE87.2 254.44,70.57 UE3.35
SML0_SMBCLK: length 210.1
  TOP w0.102: UL1.28 260.81,84.79 261.34,85.32 263.87,85.32 264.2,84.99 264.2,76.91 264.09,76.81 v1(264.09,76.48) 264.2,76.38 264.2,71.69 269.96,65.92 269.96,59.22 271,58.18 271.35,58.18 271.76,57.77 271.76,53.94 272.54,53.17 272.54,49.15 276.65,45.03 276.65,38.23 273.97,35.55 273.97,29.38 v2(273.8,29.21)
  IN2 w0.102: v2(273.8,29.21) 274.01,29.42 274.01,29.65 273.77,29.9 269.37,29.9 268.02,28.54 266.19,28.54 263.84,26.19 263.84,23.11 262.65,21.92 256.68,21.92 253.56,25.04 247.83,25.04 245.86,27.01 241.33,27.01 239.86,28.49 236.38,28.49 235.1,29.76 228.41,29.76 227,28.36 222.31,28.36 221.34,29.32 219.66,29.32 219.24,29.74 197.29,29.74 185.34,41.69 185.34,42.05 181.38,46.01 180.92,46.01 180.06,46.87 180.06,50.27 180.95,51.16 180.95,55.22 183.84,58.11 183.84,58.91 183.56,59.19 182.46,59.19 182.15,58.88 182.15,58.72 v2(182.2,58.67) 182.05,58.52 182.05,58.16 181.44,57.55 173.37,57.55 173.16,57.34 173.16,57.11 v2(173.54,56.73)
  BOTTOM w0.076: 173.36,56.51 173.11,56.26 172.73,56.26 171.63,55.16 170.9,55.16 UC1.AN1
  BOTTOM w0.102: RC33.2 181.58,59.29 v2(182.2,58.67) ; 173.36,56.51 173.54,56.69 v2(173.54,56.73)
SML0_SMBDATA: length 209
  TOP w0.102: UL1.31 260.94,85.99 261.33,86.37 263.24,86.37 264.42,85.19 264.42,71.78 270.19,66.01 270.19,59.31 271.1,58.41 271.45,58.41 271.99,57.86 271.99,54.04 272.77,53.26 272.77,49.24 276.88,45.13 276.88,38.13 274.2,35.45 274.2,29.4 v2(274.39,29.21)
  IN2 w0.102: v2(172.86,58.11) 173.21,57.77 181.35,57.77 181.83,58.25 181.83,58.45 v2(181.59,58.69) 181.64,58.69 182.37,59.42 183.65,59.42 184.07,59 184.07,58.02 181.18,55.12 181.18,51.06 180.29,50.17 180.29,46.96 181.01,46.24 181.47,46.24 185.57,42.14 185.57,41.78 197.38,29.97 219.34,29.97 219.76,29.55 221.43,29.55 222.4,28.59 226.91,28.59 228.31,29.99 235.19,29.99 236.47,28.71 239.96,28.71 241.43,27.24 245.96,27.24 247.93,25.27 253.65,25.27 256.78,22.15 262.56,22.15 263.61,23.2 263.61,26.29 266.1,28.77 267.92,28.77 269.28,30.12 273.86,30.12 274.24,29.74 274.24,29.36 v2(274.39,29.21)
  BOTTOM w0.076: v2(172.86,58.11) 172.63,58.11 171.94,57.42 170.91,57.42 UC1.AK1
  BOTTOM w0.102: RC34.2 181.3,58.4 v2(181.59,58.69)
SML1_SMBCLK: length 123
  TOP w0.102: v2(259.79,45.78) 259.81,45.76 259.82,45.76 260.44,46.37 UE2.B6
  IN1 w0.102: v2(259.79,45.78) 260.12,46.11 260.12,48.08 259.38,48.82 259.38,49.91 258.71,50.58 258.71,51.76 257.1,53.36 250.93,53.36 250.33,52.77 239.11,52.77 231.48,60.4 231.48,66.59 228.06,70.01 217.9,70.01 217.41,69.52 193.54,69.52 193.22,69.2 192.13,69.2 187.39,64.46 187.39,62.19 185.42,60.22 183.93,60.22 183.14,61.01 182.36,61.01 182.18,60.83 v2(182.18,60.82)
  IN2 w0.102: v2(171.79,53.64) 171.44,53.99 171.44,55.02 172.39,55.97 172.39,57.29 172.27,57.4 172.27,58.51 172.63,58.86 173.44,58.86 173.54,58.76 180.24,58.76 181.26,59.78 181.26,60.16 181.5,60.4 181.77,60.4 182.18,60.81 v2(182.18,60.82)
  BOTTOM w0.076: UC1.AU3 169.64,52.86 170.04,53.26 170.29,53.26 170.42,53.39 170.42,53.66 170.59,53.83 171.6,53.83 v2(171.79,53.64)
  BOTTOM w0.102: RPC14.3 182.36,61 v2(182.18,60.82)
SML1_SMBDATA: length 115.9
  TOP w0.102: v2(260.65,48.7) 260.69,48.66 UE2.A5
  IN1 w0.102: v2(260.65,48.7) 259.82,48.7 259.61,48.91 259.61,50.01 258.94,50.68 258.94,51.85 257.2,53.59 250.84,53.59 250.24,53 239.21,53 231.71,60.49 231.71,66.68 228.15,70.24 217.8,70.24 217.32,69.75 193.45,69.75 193.13,69.43 192.04,69.43 187.16,64.55 187.16,62.29 185.32,60.45 184.03,60.45 183.24,61.24 181.98,61.24 v2(181.56,60.82)
  BOTTOM w0.076: UC1.AH3 169.74,57.75 170.25,57.75 170.49,57.99 170.49,58.16 170.66,58.34 170.89,58.34 171.16,58.07 171.72,58.07 172.75,59.09 173.76,59.09 174.58,59.92 174.88,59.92
  BOTTOM w0.102: RPC14.4 182.24,61.5 v2(181.56,60.82) 181.24,60.82 181.16,60.9 176.74,60.9 175.77,59.92 174.88,59.92
SNB_1.05V: length 1.5
  TOP w0.102: PR305.2 v1(199.74,57)
SNUB_1.35V: length 1.6
  TOP w0.102: PC208.1 63.56,15.3 v1(63.36,15.1)
SNUB_3V: length 1.5
  TOP w0.102: PR111.2 v1(228.65,56.68)
SNUB_5V: length 1.6
  TOP w0.102: PR112.2 v1(208.6,56.31)
SPI_CLK32: length 25.2
  TOP w0.102: RPC12.7 192.21,55.73 192.62,55.32 193.85,55.32 193.98,55.45 v4(193.98,56.51) 193.98,57.85 193.85,57.97 193.48,57.97 193.35,57.85 193.35,56.08 193.2,55.93 192.85,55.93 192.72,56.06 192.72,57.89 192.59,58.01 192.26,58.01 192.14,57.89 192.14,56.11 192.01,55.98 191.22,55.98 191.07,56.13 v2(191.07,56.49)
  BOTTOM w0.102: RC61.2 195.29,59.03 195.29,59.42 194.66,60.05 192.64,60.05 192.22,59.63 192.01,59.63 191.88,59.5 UC3.6 191.88,57.3 v2(191.07,56.49)
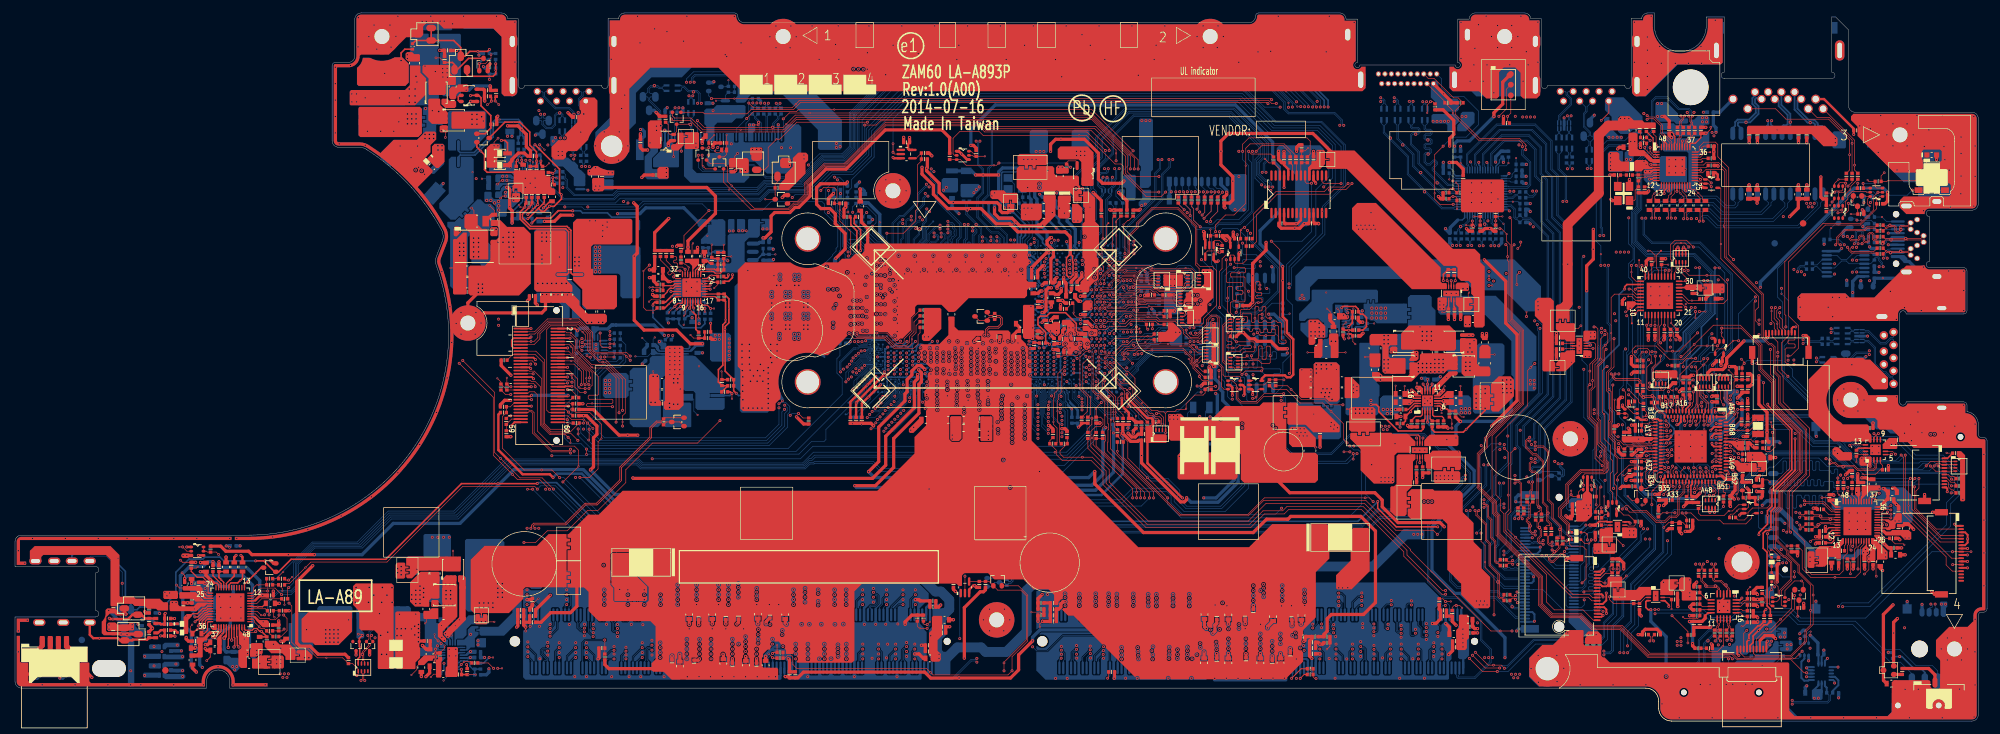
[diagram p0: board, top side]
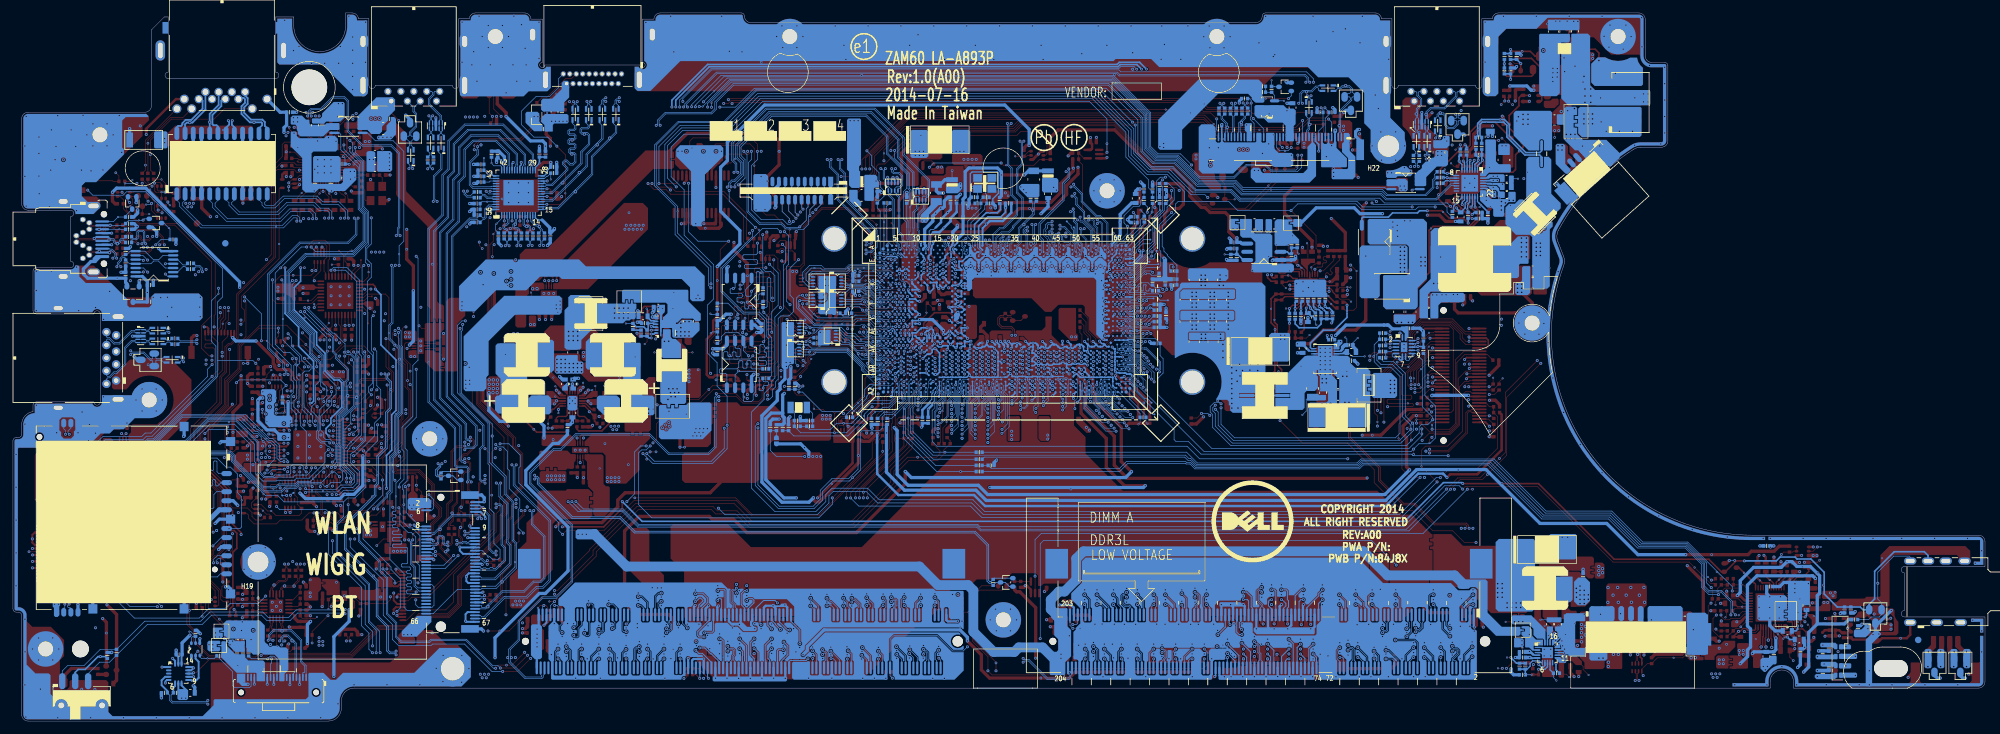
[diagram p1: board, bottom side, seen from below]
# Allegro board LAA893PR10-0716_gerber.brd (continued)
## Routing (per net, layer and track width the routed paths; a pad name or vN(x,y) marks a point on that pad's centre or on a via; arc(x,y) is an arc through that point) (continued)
SPI_CLK64: length 25.2
  TOP w0.102: v2(192.72,62.9) 192.24,62.9 192.11,62.78 192.11,61.76 192.24,61.63 192.69,61.63 192.94,61.87 193.3,61.87 193.55,61.63 194.23,61.63 194.46,61.86 194.89,61.86 195.12,61.63 195.56,61.63 195.69,61.51 195.69,59.04 195.82,58.91 196.3,58.91 196.43,58.79 196.43,58.53 196.3,58.41 195.39,58.41 195.26,58.53 195.26,61.01 195.13,61.14 v4(194.59,61.14) RPC11.6
  BOTTOM w0.102: RC62.2 194.26,64.62 192.72,63.08 v2(192.72,62.9) 193.15,62.47 UC2.6
SPI_CLKTPM: length 2.9
  TOP w0.102: RZ26.2 RZ35.2 198.71,86.22 UZ1.21
SPI_DIN32: length 13.7
  TOP w0.102: v2(189.61,53.61) 190.15,54.15 v4(192.63,54.15) 192.69,54.15 192.85,54.3 192.85,54.58 192.69,54.73 RPC12.5
  BOTTOM w0.102: v2(189.61,53.61) 190.05,54.05 192.66,54.05 193.15,53.56 UC3.2
SPI_DIN64: length 13.7
  TOP w0.102: v2(192.38,67.41) 192.38,67.83 192.25,67.96 191.86,67.96 191.73,67.83 191.73,66.42 191.86,66.29 192.54,66.29 192.67,66.17 192.67,65.91 192.54,65.79 191.86,65.79 191.73,65.66 191.73,65.43 191.86,65.3 192.58,65.3 192.71,65.18 192.71,64.82 192.58,64.69 v4(192.14,64.69) 191.83,64.69 190.79,63.65 189.49,63.65 189.37,63.52 189.37,62.26 189.24,62.14 RPC11.8
  BOTTOM w0.102: v2(192.38,67.41) 192.01,67.41 191.88,67.54 UC2.2
SPI_DINTPM: length 4
  TOP w0.102: v1(193.15,86.94) 193.79,86.31 RZ30.2 194.5,86.28 195.46,85.32 UZ1.26
SPI_DO32: length 13.2
  TOP w0.102: v2(189.67,55.22) 189.66,55.23 RPC12.6
  BOTTOM w0.102: UC3.5 190.61,58.01 190.48,57.89 189.98,57.89 189.85,57.76 189.85,57.49 189.91,57.43 190.07,57.43 190.19,57.3 190.19,57.12 190.07,57 189.85,57 189.7,56.84 189.47,56.84 189.32,57 189.32,58.12 189.19,58.24 188.78,58.24 188.66,58.12 188.66,57.96 188.48,57.78 188.48,57.54 188.66,57.37 188.66,57.15 188.55,57.05 188.43,57.05 188.27,56.9 188.27,56.44 188.43,56.29 v1(188.77,56.29) 189.39,56.29 189.52,56.16 189.52,55.88 189.39,55.75 188.48,55.75 188.33,55.6 188.33,55.14 188.48,54.99 189.52,54.99 189.67,55.14 v2(189.67,55.22)
SPI_DO64: length 15.5
  TOP w0.102: RPC11.7 190.36,61.64 190.48,61.76 190.48,62.43 190.36,62.56 189.76,62.56 189.63,62.69 189.63,62.95 189.76,63.08 190.93,63.08 191.06,62.95 191.06,61.76 191.18,61.63 191.49,61.63 191.62,61.76 v4(191.62,62.29) 191.62,63.97 191.74,64.1 192.08,64.1 192.21,63.97 192.21,63.55 192.34,63.42 192.59,63.42 192.72,63.55 192.72,63.97 192.85,64.1 193.18,64.1 193.3,63.97 193.3,62.52 193.52,62.31 v2(193.96,62.31)
  BOTTOM w0.102: v2(193.96,62.31) 194.17,62.31 194.42,62.05 UC2.5
SPI_DOTPM: length 2.1
  TOP w0.102: UZ1.23 197.41,85.98 RZ29.2
SPI_PCH_CLK: length 42.6
  TOP w0.102: RPC12.2 187.53,55.73 187.28,55.98 187.28,57.09 187.39,57.19 189.31,57.19 189.7,57.58 190.92,57.58 191.07,57.73 191.07,57.96 190.92,58.11 189.23,58.11 188.81,57.7 v4(188.17,57.7) 187.39,57.7 187.28,57.8 187.28,58.1 187.39,58.21 187.9,58.21 188.05,58.35 188.05,58.56 187.9,58.71 187.39,58.71 187.28,58.81 187.28,59.92 v2(187.49,60.12) 187.28,60.32 187.28,60.78 187.64,61.14 RPC11.3 ; RC227.1 182.8,81.62 v2(183.02,81.83)
  IN1 w0.102: v2(183.02,81.83) 183.02,81.66 187.28,77.39 187.28,75.06 187.84,74.5 v2(187.84,70.65)
  BOTTOM w0.102: v2(183.02,81.83) 183.02,81.84 182.38,82.47 JSPI1.7 ; v2(187.84,70.65) 186.5,69.3 186.5,64.29 187.49,63.3 v2(187.49,60.12)
SPI_PCH_CS0#: length 34.5
  TOP w0.102: RC228.1 183.82,81.38 v2(184.25,81.82)
  IN1 w0.102: v2(184.25,81.82) 184.26,81.81 184.26,81.1 187.81,77.55 187.81,75.31 188.33,74.79 188.33,73.35 188.45,73.23 188.64,73.23 188.77,73.35 188.77,74.17 188.9,74.29 189.14,74.29 189.27,74.17 189.27,73.35 189.39,73.23 190.65,73.23 190.78,73.35 190.78,73.79 190.66,73.9 v2(189.7,73.9)
  BOTTOM w0.102: RC35.1 188.83,69.44 189.37,69.98 191.58,69.98 191.73,70.13 191.73,70.43 191.58,70.59 189.82,70.59 189.67,70.74 189.67,71.2 189.82,71.35 191.81,71.35 191.96,71.5 191.96,71.96 191.81,72.11 189.91,72.11 189.7,72.33 v2(189.7,73.9) ; v2(184.25,81.82) 184.25,81.83 183.38,82.69 JSPI1.9
SPI_PCH_CS0#_R: length 15.1
  BOTTOM w0.102: UC2.1 190.61,67.65 191.53,66.74 191.53,65.84 191.37,65.68 190.81,65.68 190.68,65.82 190.68,66.4 v2(190.61,66.46) 189.88,67.2 189.88,69.4 189.73,69.54 189.52,69.54 189.37,69.4 189.37,66.76 190.1,66.03 190.1,65.25 189.95,65.1 189.65,65.1 189.49,65.25 189.49,65.91 189.33,66.07 RC35.2
SPI_PCH_CS1#: length 44.3
  TOP w0.102: v2(179.38,81.84) 179.38,81.39 RC224.1
  IN1 w0.102: v2(179.38,81.84) 181.22,80 183.08,80 186.13,76.94 v2(186.13,75.66)
  BOTTOM w0.102: JSPI1.1 179.38,81.84 179.39,81.84 v2(179.38,81.84) ; v2(186.13,75.66) 186.64,76.17 188.91,76.17 195.09,69.99 195.09,66.51 191.82,63.23 189.39,63.23 188.25,62.09 188.25,59.41 187.94,59.11 RC50.1
SPI_PCH_CS1#_R: length 14.7
  BOTTOM w0.102: UC3.1 194.42,53.57 194.62,53.77 195.45,53.77 195.58,53.9 195.58,54.33 195.45,54.46 192.85,54.46 192.59,54.71 192.59,55.57 192.44,55.73 192.11,55.73 191.96,55.57 191.96,54.69 191.83,54.56 191.45,54.56 191.32,54.69 v2(191.32,55.22) 191.32,55.63 191.2,55.75 190.81,55.75 190.69,55.63 190.69,54.65 190.5,54.46 RC50.2
SPI_PCH_DIN: length 51
  TOP w0.102: RC226.1 181.78,81.84 v2(181.78,81.84) ; RPC12.4 188.34,54.73 188.4,54.67 188.4,54.53 188.53,54.41 189.35,54.41 189.48,54.28 189.48,54.08 189.35,53.95 187.37,53.95 187.25,54.08 187.25,54.91 186.57,55.59 186.57,61.16 187.55,62.14 RPC11.1 187.81,62.81 187.39,63.24 v4(187.39,65.42) 187.39,67.07 187.51,67.2 188.06,67.2 188.18,67.07 188.18,65.18 188.31,65.05 188.67,65.05 188.79,65.18 188.79,65.89 188.89,66 189.62,66 189.75,66.12 189.75,66.48 189.62,66.6 188.89,66.6 188.79,66.71 188.79,67.11 188.89,67.21 189.61,67.21 189.74,67.33 189.74,67.7 189.61,67.83 187.31,67.83 187.18,67.96 v2(187.18,71.32)
  IN1 w0.102: v2(181.78,81.84) 182.72,80.9 183.09,80.9 186.79,77.2 186.79,74.64 186.7,74.55 186.7,73.75 186.8,73.65 187.23,73.65 187.34,73.55 187.34,73.24 187.23,73.14 186.8,73.14 186.7,73.04 186.7,72.73 186.8,72.63 187.23,72.63 187.34,72.53 187.34,72.22 187.23,72.12 186.8,72.12 186.7,72.02 186.7,71.42 186.8,71.32 v2(187.18,71.32)
  BOTTOM w0.102: JSPI1.5 181.38,82.24 v2(181.78,81.84)
SPI_PCH_DO: length 43.8
  TOP w0.102: RC225.1 180.77,81.65 v2(180.58,81.84) ; RPC12.3 187.32,55.23 186.8,55.75 186.8,60.98 187.45,61.64 RPC11.2 188.11,61.64 188.33,61.85 188.33,62.64 187.82,63.14 187.82,64.67 187.97,64.82 189.95,64.82 190.08,64.95 190.08,68.55 189.95,68.68 187.98,68.68 187.86,68.81 187.86,69.19 187.98,69.32 v4(189.13,69.32) 190.03,69.32 190.18,69.47 190.18,69.93 190,70.1 v2(188.4,70.1)
  IN1 w0.102: v2(180.58,81.84) 182.05,80.37 183.19,80.37 186.56,77 186.56,74.82 186.45,74.7 186.45,70.84 187.18,70.1 v2(188.4,70.1)
  BOTTOM w0.102: JSPI1.3 180.38,82.03 v2(180.58,81.84)
SPI_PCH_DO2: length 45.4
  TOP w0.102: v2(185.43,81.82) 185.43,81.62 184.83,81.02 RC229.1 ; RC29.2 188.82,63.31 v2(188.72,63.2)
  IN1 w0.102: v2(188.87,75.2) 188.87,76.81 185.43,80.25 v2(185.43,81.82)
  BOTTOM w0.102: RC55.1 187.51,53.43 187.51,59.31 188.02,59.82 188.02,62.51 v2(188.72,63.2) 188.83,63.32 RC38.1 188.33,63.98 188.2,64.11 188.2,68.4 188.05,68.55 187.79,68.55 187.64,68.4 187.64,65.02 187.49,64.87 187.16,64.87 187,65.02 187,68.88 187.67,69.54 188.5,69.54 188.87,69.91 v2(188.87,75.2) ; JSPI1.11 184.38,82.62 184.71,82.3 185.15,82.3 185.43,82.02 v2(185.43,81.82)
SPI_PCH_DO2_32: length 13.6
  BOTTOM w0.102: RC55.2 188.86,52.6 188.73,52.48 188.11,52.48 187.98,52.35 187.98,52.03 188.11,51.9 188.68,51.9 188.81,51.78 v4(188.81,51.51) 188.81,51.21 188.94,51.08 189.29,51.08 189.42,51.21 189.42,53.06 189.54,53.19 189.86,53.19 189.99,53.06 189.99,50.89 190.36,50.52 190.36,49.67 190.59,49.44 191.75,49.44 191.88,49.57 UC3.3
SPI_PCH_DO2_64: length 13.3
  BOTTOM w0.102: RC38.2 189.15,64.58 189.75,64.58 189.88,64.45 189.88,63.84 190,63.72 190.33,63.72 190.46,63.84 190.46,64.16 190.59,64.29 190.97,64.29 191.09,64.16 191.09,63.86 191.22,63.73 191.53,63.73 191.65,63.86 191.65,64.67 191.78,64.79 192.73,64.79 192.86,64.92 192.86,65.4 192.73,65.53 192.14,65.53 192.01,65.66 192.01,65.99 192.14,66.12 193.79,66.12 193.91,66.24 193.91,66.76 193.79,66.89 v2(193.43,66.89) 193.28,66.89 193.15,67.02 UC2.3
SPI_PCH_DO3: length 46.2
  TOP w0.102: v2(186.61,81.78) 186.61,81.78 185.85,81.02 RC230.1 ; RPC12.1 188.14,56.23 188.55,56.64 189.44,56.64 189.9,57.1 191.4,57.1 191.6,57.3 v4(191.6,57.86) 191.6,58.39 191.35,58.65 v2(188.76,58.65) 188.66,58.65 187.82,59.48 RC31.2 187.8,59.75 188,59.94 188,60.3 188.15,60.45 188.15,60.57 188.08,60.64 RPC11.4
  IN1 w0.102: v2(190.46,75.87) 189.54,75.87 189.11,76.29 189.11,76.89 187.42,78.58 187.42,79.64 186.61,80.45 v2(186.61,81.78)
  BOTTOM w0.102: v2(190.46,75.87) 190.46,74.95 195.34,70.07 195.34,66.41 191.87,62.94 189.57,62.94 188.58,61.95 188.58,58.83 v2(188.76,58.65) ; v2(186.61,81.78) 186.61,82 186.25,82.36 185.73,82.36 185.38,82.71 JSPI1.13
SPI_PCH_DO3_32: length 14.6
  TOP w0.102: v2(190.41,56.48) 190.16,56.23 RPC12.8
  BOTTOM w0.102: UC3.7 193.15,57.77 193.02,57.64 192.49,57.64 192.36,57.52 192.36,56.46 192.49,56.34 192.89,56.34 193.01,56.46 193.01,56.96 193.14,57.09 193.47,57.09 193.6,56.96 193.6,56.46 193.72,56.34 194.14,56.34 194.27,56.46 194.27,56.98 194.4,57.11 194.79,57.11 194.92,56.98 194.92,56.11 194.79,55.98 190.9,55.98 v2(190.41,56.48)
SPI_PCH_DO3_64: length 13
  TOP w0.102: v2(191.99,60.06) 191.99,60.05 192.43,59.61 v4(193.29,59.61) 194.61,59.61 194.74,59.74 194.74,60.5 194.61,60.63 194.32,60.63 194.19,60.5 194.19,60.21 194.07,60.08 193.7,60.08 193.57,60.21 193.57,60.51 193.44,60.64 193.11,60.64 192.99,60.51 192.99,60.21 192.86,60.08 192.52,60.08 192.39,60.21 192.39,60.53 192.26,60.65 191.33,60.65 191.23,60.55 191.23,60.36 191.13,60.26 190.82,60.26 190.72,60.36 190.72,60.55 190.62,60.65 189.65,60.65 189.63,60.64 RPC11.5
  BOTTOM w0.102: UC2.7 191.88,60.16 v2(191.99,60.06)
SPKR: length 217.2
  TOP w0.102: v1(42.81,22.28) 42.33,21.8 v2(42.27,21.8) 41.87,21.8 RA12.2 ; v2(176.76,81.8) 174.52,81.8 171.59,84.73 171.59,87.38 167.04,91.92 150.29,91.92 149.39,92.82 133.72,92.82 133.06,92.16 v2(131.32,92.16) ; v2(172.88,63.55) 173.3,63.13 177.28,63.13 RC180.2
  IN1 w0.102: v2(176.76,81.8) 176.76,81.8 176.76,80.28 174.42,77.95 174.42,71.02 175.48,69.96 175.48,66.08 174.78,65.38 174.32,65.38 172.88,63.94 v2(172.88,63.55)
  IN2 w0.102: v2(42.27,21.8) 43.76,20.31 48.7,20.31 71.99,43.6 71.99,51.98 78.89,58.88 83.34,58.88 87.9,63.44 90.74,63.44 91.4,64.1 91.4,75.13 94.04,77.77 v2(94.04,80.34)
  BOTTOM w0.076: v2(172.88,63.55) 172.59,63.26 171.15,63.26 170.89,63 170.56,63 170.27,63.29 UC1.V2
  BOTTOM w0.102: v2(94.04,80.34) 94.28,80.58 115.1,80.58 116.53,82 122.03,82 125.54,85.52 128.9,85.52 131.32,87.93 v2(131.32,92.16)
SRTCRST#: length 23.6
  IN2 w0.102: v2(167.07,51.87) 168.48,50.46 168.48,49.96 168.8,49.64 169.32,49.64 170.35,48.61 v2(171.98,48.61)
  BOTTOM w0.076: v2(167.07,51.87) 167.14,51.87 UC1.AV6
  BOTTOM w0.102: v2(171.98,48.61) 172.01,48.61 173.15,47.46 173.15,46.68 175.73,44.09 184.08,44.09 CC3.2 184.9,44.91 RC10.2
SUS_ON: length 315.6
  TOP w0.102: v2(225.68,10.63) 227.66,8.65 v4(228.48,8.65) 229.68,8.65 v2(230.16,8.17) ; RPE10.2 254.06,51.84 v2(254.4,51.5) ; RE282.2 RE281.2 167.07,42.56 173.94,35.68 v2(173.94,34.52)
  TOP w0.254: PR207.1 69.87,8.65 v2(69.78,8.74)
  IN1 w0.102: v2(254.4,51.5) 254.4,50.75 254.67,50.48 257.58,50.48 258.22,49.84 258.22,48.82 258.44,48.6 258.44,44.82 256.21,42.58 255.22,42.58 254.85,42.21 254.85,41.06 255.24,40.66 256.19,40.66 257.39,39.47 257.39,38.26 256.84,37.72 256.84,34.28 v2(252.28,29.72)
  IN2 w0.102: v2(230.16,8.17) 229.24,7.24 157.21,7.24 156.27,8.18 153.88,8.18 152.16,6.45 86.04,6.45 85.76,6.73 71.79,6.73 v2(69.78,8.74) ; v2(173.94,34.52) 173.94,34.48 175.21,33.21 176.95,33.21 188.83,21.33 188.83,18.58 191.14,16.27 219.74,16.27 220.7,15.31 220.7,14.87 222.76,12.81 222.76,11.04 223.16,10.63 v2(225.68,10.63)
  BOTTOM w0.102: v2(230.16,8.17) 230.48,8.17 234.75,12.44 240.07,12.44 240.34,12.17 244.82,12.17 245.64,12.99 245.64,15.15 247.04,16.54 247.04,22.09 248.18,23.24 248.18,24.62 251.36,27.79 251.36,28.79 v2(252.28,29.72)
SUS_ON_EC: length 140.1
  TOP w0.102: v2(255.3,44.06) 255.2,43.96 UE2.B23 ; v2(225.23,10.17) 227.2,8.2 v2(229.42,8.2) ; v2(173.33,34.52) v4(173.33,35.38) 173.33,36.01 166.61,42.72 166.61,44.17 RE281.1
  IN1 w0.102: v2(255.3,44.06) 254.61,43.37 254.61,40.98 255.13,40.46 256.11,40.46 257.19,39.38 257.19,38.37 256.64,37.82 256.64,34.59 254.53,32.49 254.4,32.49 v2(251.66,29.74)
  IN2 w0.102: v2(173.33,34.52) 174.93,32.92 176.91,32.92 188.59,21.23 188.59,18.53 191.05,16.06 219.64,16.06 220.44,15.26 220.44,14.84 222.55,12.73 222.55,10.95 223.33,10.17 v2(225.23,10.17)
  BOTTOM w0.102: v2(229.42,8.2) 229.84,8.62 230.65,8.62 234.67,12.65 240.17,12.65 240.45,12.37 244.73,12.37 245.44,13.08 245.44,15.23 246.83,16.63 246.83,22.18 247.98,23.32 247.98,24.7 251.15,27.88 251.15,29.23 v2(251.66,29.74)
SUS_STAT#/LPCPD#: length 8
  TOP w0.102: v2(169.17,58.42) 169.91,59.16 172.01,59.16 172.35,59.5 v1(175.03,59.5) 175.69,59.5 RC82.2
  BOTTOM w0.076: v2(169.17,58.42) 168.83,58.76 UC1.AG4
SUSACK#: length 118
  TOP w0.102: RC81.2 v1(173.67,58.97) 172.67,58.97 171.9,58.2 171.08,58.2 v2(169.81,56.93) ; v2(246.92,51.97) 246.86,51.9 246.86,46.24 246.67,46.05 246.67,44.34 247.67,43.33 248,43.33 248.63,42.71 249.85,42.71 250.01,42.86 252.79,42.86 253.14,43.21 UE2.A23
  IN1 w0.102: v2(246.92,51.97) 246.49,51.54 239.28,51.54 230.77,60.05 230.77,66.33 228.19,68.91 227.54,68.91 227.33,69.12 218.27,69.12 217.78,68.63 196.35,68.63 193.34,65.62 190.79,65.62 189.56,64.39 189.56,63.07 185.45,58.97 184.56,58.97 182.81,57.23 182.1,57.23 181.83,57.49 181.12,57.49 180.32,58.29 175.41,58.29 174.87,57.75 173.66,57.75 173.26,57.35 170.23,57.35 v2(169.81,56.93)
  BOTTOM w0.076: v2(169.81,56.93) 170.13,57.25 UC1.AK2
SUSCLK: length 121.1
  TOP w0.102: v2(245.06,36.19) 244.92,36.05 244.92,33.45 244.28,32.82 RZ56.1 ; RC136.2 v2(175.77,60.67)
  IN1 w0.102: v2(175.77,60.67) 175.82,60.72 176.5,60.72 177.9,62.12 179.66,62.12 180.93,63.39 183.05,63.39 184.56,64.9 185.85,64.9 192,71.04 v2(192.43,71.04)
  IN2 w0.102: v2(242.43,71.87) 241.86,72.44 225.78,72.44 225.03,71.69 218.73,71.69 212.45,77.97 196.02,77.97 192.43,74.38 v2(192.43,71.04)
  BOTTOM w0.102: v2(242.43,71.87) 242.15,71.59 242.15,55.8 242.95,55 242.95,47.12 244.64,45.43 244.64,42 244.32,41.68 244.32,37.38 245.06,36.64 v2(245.06,36.19)
SUSCLK_R: length 9
  TOP w0.102: v2(175.05,60.59) 174.85,60.79 RC136.1
  IN2 w0.102: v2(167.63,60.03) 167.86,60.03 168.21,60.38 170.96,60.38 171.14,60.57 175.03,60.57 v2(175.05,60.59)
  BOTTOM w0.076: v2(167.63,60.03) 167.5,59.89 UC1.AE6
SW1: length 5.1
  IN1 w1.016: 212.04,53.7 212.04,52.79 214.99,49.83
  vias: v2(215.44,49.07) v2(215.87,49.47) v3(211.57,59.61) v3(211.57,58.97) v3(211.57,58.34) v3(211.57,55.86) v3(211.57,55.23) v3(211.57,54.59) v3(212.2,59.61) v3(212.2,58.97) v3(212.2,58.34) v3(212.2,55.86) v3(212.2,55.23) v3(212.2,54.59) v4(211.72,54)
SW2: length 4.4
  IN1 w1.016: 221.83,50.12 224.52,52.81 224.52,53.45
  vias: v2(220.75,49.52) v2(221.08,49.04) v3(224.2,56.43) v3(224.2,55.48) v3(224.2,54.85) v3(224.2,54.21) v3(224.52,57.07) v3(224.84,58.34) v3(224.84,57.7) v3(224.84,56.43) v3(224.84,55.48) v3(224.84,54.85) v3(224.84,54.21) v3(225.15,57.07) v4(225.47,58.83)
SW_1.35V:
  vias: v1(65.9,14.77) v2(65.96,12.94) v2(66.34,12.49) v3(66.35,17.88) v3(66.55,21.12) v3(66.61,20.17) v3(66.61,19.53) v3(66.61,18.9) v3(66.99,17.88) v3(67.18,21.12) v3(67.31,20.17) v3(67.31,19.53) v3(67.31,18.9) v3(67.62,17.88) v3(67.82,21.12)
SW_+V1.05SP: length 1.7
  TOP w0.102: PR305.1 v1(205.61,57)
  vias: v3(203.41,58.74) v3(204.07,58.71)
SW_MDP_AUX#_C: length 2.7
  BOTTOM w0.102: UV502.5 279.3,71.36 278.47,70.54 278,70.54 CV513.1
SW_MDP_AUX_C: length 2.8
  BOTTOM w0.102: UV502.2 279.34,69.41 278.43,70.32 278.19,70.32 CV512.1
SYS_LED_MASK#: length 122
  TOP w0.102: v2(273.66,60.95) 273.66,62.71 273.49,62.88 273.49,71.04 279.41,76.96 285.14,76.96 287.23,79.05 287.23,81.11 v2(287.89,81.77) QZ7.2 ; QL1.5 281.8,83.04 282.02,83.26 282.81,83.26 282.89,83.18 v2(282.89,83.18) 282.89,82.97 282.84,82.92 282.84,81.96 282.65,81.77 281.92,81.77 281.8,81.64 QL1.2 QL2.2 ; UZ10.1 264.03,59.21 263.74,59.5 v2(263.74,60.76) 266.72,60.76 269.5,57.97 269.5,54.25 271.45,52.31 271.45,48.69 275.54,44.61 275.54,38.8 272.48,35.74 272.48,33.15 271.78,32.45 271.78,26.85 273.3,25.34 273.56,25.34 274.37,24.52 274.37,21.9 272.7,20.24 272.7,18.91 272.25,18.45 QZ3.2 ; RE21.2 v2(253.43,61.19) 253.43,61.79 253.44,61.8 UE3.14
  IN2 w0.102: v2(287.89,81.77) 287.89,81.77 286.05,83.6 283.31,83.6 v2(282.89,83.18) ; v2(253.43,61.19) 254,61.76 262.74,61.76 v2(263.74,60.76) 273.47,60.76 v2(273.66,60.95)
  BOTTOM w0.102: v2(263.74,60.76) v1(263.74,60.08)
SYS_PWROK: length 276.5
  TOP w0.102: v2(259.7,46.37) 259.75,46.37 259.94,46.55 UE2.B7 ; JXDP1.47 77.15,49.2 76.55,48.6 CC22.1 RC120.1 75.32,47.1 75.32,42.19 78.69,38.82 v4(81.39,38.82) 82.98,38.82 v2(84.16,37.64)
  IN2 w0.102: v2(173.9,60.15) 173.9,59.78 174.24,59.44 180.22,59.44 180.58,59.8 180.58,60.76 181.12,61.3 182.41,61.3 183.78,59.93 183.83,59.93 184.55,59.2 184.55,57.29 183.06,55.79 183.06,54.75 181.66,53.35 181.66,50.79 180.77,49.9 180.77,47.18 181.2,46.75 181.66,46.75 195.49,32.92 v2(195.73,32.92) 198.19,30.45 221.39,30.45 222.78,29.07 v2(225.88,29.07) ; v2(230.14,42.77) 232.26,42.77 234.02,41.01 235.27,41.01 237.52,38.76 239.99,38.76 241.01,39.79 241.97,39.79 245.44,43.26 245.44,44.4 247.78,46.74 250.07,46.74 250.96,47.62 252.94,47.62 254.09,46.48 254.09,46.25 255.01,45.33 255.99,45.33 256.66,44.65 258.35,44.65 259.28,45.58 259.28,45.95 v2(259.7,46.37)
  BOTTOM w0.076: v2(173.9,60.15) 173.03,59.28 172.5,59.28 172.31,59.09 170.66,59.09 170.66,59.09 170.62,59.09 170.32,58.79 UC1.AG2
  BOTTOM w0.102: v2(84.16,37.64) 84.81,37.64 90.5,31.95 154.81,31.95 156.59,33.73 171.13,33.73 172.92,35.52 177.97,35.52 178.65,34.85 178.65,33.73 180.48,31.9 194.71,31.9 v2(195.73,32.92) ; v2(230.14,42.77) 229.77,42.39 229.03,42.39 228.36,41.72 228.36,39.05 228.05,38.75 228.05,35.95 226.43,34.33 226.43,32.97 226.67,32.73 226.67,29.88 225.88,29.1 v2(225.88,29.07)
SYS_RESET#: length 206.2
  TOP w0.102: v2(228.56,16.43) 228.56,18.6 228.55,18.62 228.55,22.36 227.18,23.74 v1(227.18,24.59) 227.18,27.15 226.55,27.78 v2(226.55,29.08) ; JAPS1.13 v2(299.44,24.19) ; UC4.4 183.93,72.35 184.27,72.69 185.38,72.69 185.72,73.04 186.11,73.04 RC77.2 186.26,72.34 186.01,72.34 185.89,72.47 v2(185.89,72.62)
  IN1 w0.102: v2(182.71,64.53) 181.65,65.59 181.65,66.19 185.09,69.63 185.09,71.82 v2(185.89,72.62)
  IN2 w0.102: v2(228.56,16.43) 229.28,15.71 233.2,15.71 234.44,16.95 239.6,16.95 242.78,13.77 244.75,13.77 245.15,13.37 249.2,13.37 250.48,12.1 250.48,10.58 251.64,9.42 262.25,9.42 264.17,11.34 266.85,11.34 271.75,16.24 288.66,16.24 289.44,17.02 292.35,17.02 293.44,15.93 298.59,15.93 299.73,17.07 299.73,23.9 v2(299.44,24.19) ; v2(226.55,29.08) 226.08,29.55 222.98,29.55 221.59,30.94 198.41,30.94 182.08,47.27 181.47,47.27 181.28,47.46 181.28,49.62 182.14,50.48 182.14,53 183.88,54.74 183.88,55.67 185.74,57.53 185.74,62.4 183.61,64.53 v2(182.71,64.53)
  BOTTOM w0.076: UC1.AC3 169.74,60.75 170.25,60.75 170.49,60.99 170.49,61.16 170.73,61.4 171.58,61.4 172.41,62.23 174.47,62.23 174.84,61.86 175.22,61.86
  BOTTOM w0.102: v2(182.71,64.53) 182.71,64.01 180.57,61.86 175.22,61.86
TDI_IREF: length 9.7
  BOTTOM w0.127: UC1.B12 163.31,73 163.08,73.24 163.08,73.65 162.93,73.8 162.93,75.23 162.58,75.58
  BOTTOM w0.381: RC186.2 158.92,78.68 159.85,77.75 159.85,77.29 v4(160.89,76.26) 161.57,75.58 162.58,75.58
TDI_XDP_R: length 2.6
  BOTTOM w0.102: UC7.5 91.56,57.33 91.76,57.13 RC118.1 RC99.2
TDO_XDP: length 37.4
  TOP w0.102: RC117.2 85.97,47.46 85.84,47.46 v2(85.51,47.78) 85.1,48.2 JXDP1.52
  IN2 w0.102: v2(85.51,47.78) 79.79,47.78 78.62,48.95 78.62,55.18 80.25,56.81 86.88,56.81 88.03,55.66 91.32,55.66 91.97,56.3 91.97,56.87 91.53,57.31 91.53,58.63 v2(91.93,59.04)
  BOTTOM w0.102: UC7.2 91.73,58.83 v2(91.93,59.04) RC115.1 RC98.2 ; v2(85.51,47.78) v1(85.93,48.2)
THERMATRIP2#: length 6.6
  TOP w0.102: UE2.B34 254.06,38.46 253.73,38.14 253.73,37.5 v2(253.19,36.96) 252.2,35.97 QE4.1 251.32,37.18 RE69.2 CE36.1
THERMATRIP3#: length 17.6
  TOP w0.102: v2(263.46,36.05) 263.24,35.84 263.24,34.86 262.73,34.35 RPE6.1 ; UE2.A2 262.19,48.19 262.47,48.48 263.38,48.48 263.65,48.21 v2(264.05,48.21)
  IN1 w0.102: v2(263.46,36.05) 263.46,38 264.06,38.59 264.06,43.12 264.78,43.85 264.78,47.15 264.54,47.4 264.54,47.73 v2(264.05,48.21)
THSEL_STRAP: length 6.1
  TOP w0.102: v2(255.41,41.07) 254.81,41.07 254.7,40.96 UE2.B29 ; RE78.1 v2(252.1,40.11)
  IN2 w0.102: v2(252.1,40.11) 254.45,40.11 v2(255.41,41.07)
  BOTTOM w0.102: v2(255.41,41.07) 255.41,41.19 v1(255.71,41.49)
TMDS_CON_CLK: length 8.6
  IN2 w0.086: v2(211.04,96.39) 211.26,96.17 212,96.17 212.94,97.12 214.96,97.12 215.7,97.86 215.7,98.07 JHDMI1.10
  BOTTOM w0.102: v2(211.04,96.39) 211.23,96.2 211.49,96.2 211.71,95.99 211.71,95.47 211.99,95.18 LV3.3
TMDS_CON_CLK#: length 8.5
  IN2 w0.086: v2(211.04,95.8) 211.24,96 212.08,96 213.02,96.94 215.03,96.94 215.87,97.78 215.87,98.24 JHDMI1.12
  BOTTOM w0.102: v2(211.04,95.8) 211.23,95.99 211.4,95.99 211.49,95.9 211.49,95.5 211.14,95.15 LV3.2
TMDS_CON_N0: length 18.1
  IN2 w0.086: v2(213.14,95.8) 213.33,95.99 213.91,95.99 214.22,96.29 219.49,96.29 220.11,96.92 220.11,98.97 219.69,99.39 214.47,99.39 214.29,99.57 214.29,99.66 JHDMI1.9
  BOTTOM w0.102: LV12.2 213.24,95.12 213.55,95.43 213.55,95.88 213.45,95.99 213.32,95.99 v2(213.14,95.8)
TMDS_CON_N1: length 12.3
  IN2 w0.086: v2(215.46,95.82) 215.76,95.53 215.76,95.42 215.66,95.33 210.86,95.33 210.56,95.62 210.56,96.93 210.92,97.28 212.43,97.28 212.82,97.68 212.82,98.19 JHDMI1.6
  BOTTOM w0.102: LV10.2 215.33,95.01 215.75,95.43 215.75,95.54 v2(215.46,95.82)
TMDS_CON_N2: length 16.5
  IN2 w0.086: JHDMI1.3 211.47,100.07 211.22,99.82 211.22,99.47 210.93,99.18 210.26,99.18 209.92,98.84 209.92,95.29 210.53,94.68 217.35,94.68 217.88,95.21 217.88,95.44 v2(217.55,95.78)
  BOTTOM w0.102: LV6.2 217.43,95.09 217.75,95.41 217.75,95.57 v2(217.55,95.78)
TMDS_CON_P0: length 18.2
  IN2 w0.086: JHDMI1.7 214.11,99.66 214.11,99.5 214.4,99.21 219.62,99.21 219.94,98.9 219.94,96.99 219.42,96.47 214.14,96.47 213.84,96.16 213.36,96.16 v2(213.14,96.39)
  BOTTOM w0.102: v2(213.14,96.39) 213.32,96.2 213.54,96.2 213.77,95.97 213.77,95.45 214.09,95.13 LV12.3
TMDS_CON_P1: length 12.6
  IN2 w0.086: v2(216.05,95.82) 215.94,95.71 215.94,95.35 215.73,95.15 210.78,95.15 210.39,95.55 210.39,97 210.84,97.46 212.36,97.46 212.65,97.75 212.65,98.12 JHDMI1.4
  BOTTOM w0.102: LV10.3 216.18,95 215.96,95.22 215.96,95.74 v2(216.05,95.82)
TMDS_CON_P2: length 16.8
  IN2 w0.086: JHDMI1.1 211.05,99.72 211.05,99.54 210.86,99.35 210.18,99.35 209.74,98.91 209.74,95.21 210.45,94.5 217.42,94.5 218.06,95.14 218.06,95.7 v2(218.13,95.78)
  BOTTOM w0.102: LV6.3 218.28,95.09 217.97,95.4 217.97,95.61 218.13,95.77 v2(218.13,95.78)
TOUCH_PANEL_INTR#: length 119.7
  TOP w0.076: v2(172.29,67.01) 172.66,67.38 173.02,67.38 173.16,67.23 173.36,67.23
  TOP w0.102: RPC3.5 181.12,67.43 180.32,66.64 176.88,66.64 176.63,66.89 176.12,66.89 175.78,67.23 173.36,67.23 ; v2(176.77,84.21) 172.61,84.21 171.88,84.94 171.88,87.55 166.4,93.03 v1(129.6,93.03) 120.74,93.03 118.81,91.1 106.11,91.1 104.35,92.85 101.67,92.85 v2(101.43,93.09)
  IN1 w0.102: v2(172.29,67.01) 172.77,67.49 172.77,68.54 172.23,69.07 172.23,70.12 170.93,71.42 170.93,75.24 172.27,76.58 172.27,80.28 176.2,84.21 v2(176.77,84.21)
  BOTTOM w0.076: v2(172.29,67.01) 172.29,66.82 171.3,65.83 170.66,65.83 170.49,65.66 170.49,65.48 170.25,65.24 169.74,65.24 UC1.P3
  BOTTOM w0.102: JEDP1.5 100.96,92.61 v2(101.43,93.09)
TOUCH_SCREEN_PD#: length 4.4
  TOP w0.102: T96.1 253.69,72.05 253.69,69.99 253.94,69.75 UE3.36
TOUCHPAD_INTR#: length 14.1
  TOP w0.076: 173.36,65.46 170.61,65.46 170.33,65.18 v1(169.17,65.18) 167.62,65.18 v2(167.23,64.78)
  TOP w0.102: 173.36,65.46 173.4,65.46 173.73,65.13 174.38,65.13 174.49,65.23 179.48,65.23 179.82,65.57 RPC9.6
  BOTTOM w0.076: UC1.U7 166.85,64.4 v2(167.23,64.78)
TP_DC_TEST_B2: length 7.2
  BOTTOM w0.102: RC192.2 v1(170.14,77.14) 170.14,73.14 UC1.B2
TP_LAN_JTAG_TCK: length 3
  TOP w0.102: RL2.2 260.97,88.91 v1(260.73,88.68) 260.68,88.62 260.68,87.97 260.29,87.59 UL1.35
TP_LAN_JTAG_TDI: length 1.2
  TOP w0.102: T88.1 260.61,86.39 UL1.32
TP_LAN_JTAG_TDO: length 2.7
  TOP w0.102: UL1.34 260.43,87.19 261.21,87.97 T89.1
TP_LAN_JTAG_TMS: length 2.2
  TOP w0.102: RL1.2 260.75,87.02 260.52,86.79 UL1.33
TPM_PIRQ#: length 104.7
  TOP w0.102: v2(196.94,53.77) 197.08,53.91 197.08,58.94 196.17,59.84 196.17,61.71 195.45,62.43 195.45,72.89 v2(194.14,74.2) ; v2(200.35,83.16) 199.6,83.16 199.36,83.4 UZ1.20 ; v1(181.39,55.99) 181.59,55.78 181.59,55.32 182.04,54.87 182.04,54.57 183.03,53.58 v2(183.03,53.29) 183.03,53.11 183.46,52.68 184.39,52.68 RC247.1
  IN1 w0.102: v2(173.92,65.82) 173.92,66.03 175.22,67.32 175.22,69.87 174.17,70.93 174.17,78.28 176.04,80.16 176.04,81.66 176.64,82.26 179.87,82.26 180.59,82.98 186.74,82.98 188.54,81.18 188.54,80.81 189.46,79.9 189.46,78.6 189.82,78.23 190.4,78.23 194.14,74.49 v2(194.14,74.2) ; v2(196.94,53.77) 196.66,54.05 189.45,54.05 188.91,53.52 186.59,53.52 186.42,53.34 183.08,53.34 v2(183.03,53.29)
  BOTTOM w0.076: 173.36,65.73 172.25,65.73 171.67,65.15 171.67,64.54 171.5,64.38 171.18,64.38 171.07,64.49 169.82,64.49 169.49,64.83 UC1.T3
  BOTTOM w0.102: v2(173.92,65.82) 173.84,65.73 173.36,65.73 ; v2(200.35,83.16) 200.35,75.67 198.89,74.2 v2(194.14,74.2)
TRST#_XDP: length 23.5
  TOP w0.102: JXDP1.54 82.54,47.7 82.17,48.07 82.17,60.55 82.74,61.12 86.73,61.12 v1(87.72,60.13) 88.12,59.73 88.12,59.02 v2(87.63,58.52)
  BOTTOM w0.102: UC7.12 87.82,58.33 v2(87.63,58.52)
UG_3V: length 9
  TOP w0.102: v1(220.93,51.76) 220.77,51.61 v2(220.77,51.16)
  IN1 w1.016: 223.88,59.1 222.82,58.03 222.82,52.98 221.58,51.74
  vias: v2(220.34,50.74) v2(224.68,59.63) v2(225.28,59.63)
UG_5V: length 6
  IN1 w1.016: 215.06,51.54 213.33,53.27 213.33,56.25
  BOTTOM w0.102: v2(215.85,51.18) v1(215.22,51.18)
  vias: v2(212.66,57.1) v2(213.24,57.1) v2(216.28,50.77)
USB3RN1: length 105.9
  IN2 w0.086: v2(159.07,69.22) 158.86,69.01 158.75,69.01 158.61,69.15 158.61,71.11 156.39,73.33 144.71,73.33 144.36,72.97 136.7,72.97 133.91,75.76 133.91,78.26 131.79,80.38 131.79,83.46 127.96,87.3 126.04,87.3 122,91.34 115.79,91.34 113.17,93.96 111.83,93.96 105.49,100.3 103.26,100.3 95.83,92.86 90.55,92.86 89.26,91.56 84.05,91.56 82.59,90.1 82.59,89.4 83.48,88.51 85.63,88.51 85.92,88.21 v2(85.92,87.49)
  BOTTOM w0.076: UC1.G20 159.24,69.22 v2(159.07,69.22)
  BOTTOM w0.102: LI1.1 85.79,88.35 86.1,88.04 86.1,87.67 v2(85.92,87.49)
USB3RN1_D-: length 11.1
  BOTTOM w0.102: LI1.2 85.79,90.77 86.17,91.15 86.17,91.37 86.03,91.51 DI1.9 DI1.1 86.03,93.03 86.17,93.17 86.17,93.53 86.14,93.56 86.14,94.14 85.61,94.67 83.47,94.67 81.6,96.54 81.6,97.2 81.43,97.37 JUSB1.5
USB3RN2: length 191
  IN2 w0.086: v2(280.65,60.66) 280.46,60.46 280.1,60.46 278.03,58.39 278.03,57.87 276.99,56.83 276.99,46.19 277.78,45.4 277.78,41.36 278.31,40.83 278.31,32.43 276.39,30.51 276.39,29.48 275.51,28.6 271.11,28.6 269.83,27.32 269.83,23.34 267.56,21.07 259.61,21.07 259.37,21.31 256.44,21.31 253.33,24.42 247.03,24.42 246.61,24.84 240.36,24.84 240.07,24.54 236.14,24.54 232.52,28.17 228.85,28.17 227.6,26.92 198.06,26.92 183.85,41.12 183.85,41.5 181,44.35 178.61,44.35 177.07,45.88 177.07,47.85 176.55,48.37 175.71,48.37 173.45,50.63 173.45,51.24 172.68,52.02 170.94,52.02 170.62,52.34 170.62,57.68 170.38,57.92 170.38,58.6 170.05,58.94 169.47,58.94 168.76,59.65 166.18,59.65 166.02,59.81 166.02,60 164.98,61.05 164.28,61.05 159.73,65.6 159.73,70.94 159.33,71.33 v2(159.33,71.53)
  BOTTOM w0.076: UC1.E18 160.58,70.87 160.58,70.62 160.52,70.56 160.39,70.56 160.12,70.83 160.12,71.08 159.83,71.37 159.49,71.37 v2(159.33,71.53)
  BOTTOM w0.102: v2(280.65,60.66) 280.79,60.53 280.93,60.53 281.2,60.8 LI6.1
USB3RN2_D-: length 9.2
  BOTTOM w0.102: LI6.2 283.46,60.8 283.82,60.44 284.24,60.44 284.32,60.52 DI4.9 DI4.1 285.78,60.52 285.93,60.38 286.47,60.38 288.33,58.52 289.05,58.52 289.82,59.29 290.18,59.29 290.3,59.41 JUSB3.5
USB3RN4: length 104.9
  IN2 w0.086: v2(178.91,86.84) 178.89,86.84 178.61,87.12 178.61,87.25 178.75,87.39 183.66,87.39 184.32,86.74 218.37,86.74 219.34,85.77 230.44,85.77 231.54,84.66 234.79,84.66 238.25,81.2 238.9,81.2 239.43,80.67 239.43,80.54 239.25,80.35 v2(239.2,80.35) ; v2(172.9,74.21) 172.5,73.8 172.08,73.8 171.71,74.17 165.46,74.17 164.38,73.09 163.46,73.09 162.39,72.02 162.39,70.4 162.27,70.28 162.07,70.28 161.98,70.38 v2(161.98,70.52)
  BOTTOM w0.076: v2(161.98,70.52) 161.98,70.39 162.12,70.25 162.45,70.25 UC1.F15
  BOTTOM w0.102: v2(239.2,80.35) 239.56,80.71 239.56,84.22 238.45,85.34 238.45,87.7 238.17,87.98 LI9.1 ; v2(172.9,74.21) 172.54,73.84 172.27,73.84 172.13,73.98 172.13,75.35 177.39,80.61 177.39,84.48 178.54,85.63 178.54,86.47 v2(178.91,86.84)
USB3RN4_D-: length 9.2
  BOTTOM w0.102: JUSB2.5 239.55,97.37 239.68,97.23 239.68,96.82 240.32,96.18 240.32,95.41 238.53,93.62 238.53,92.97 238.39,92.83 DI6.1 DI6.9 238.39,91.26 238.52,91.13 238.52,90.84 238.17,90.49 LI9.2
USB3RP1: length 105.8
  IN2 w0.086: v2(86.51,87.49) 86.1,87.9 86.1,88.28 85.7,88.68 83.55,88.68 82.76,89.47 82.76,90.03 84.12,91.39 89.33,91.39 90.63,92.69 95.9,92.69 103.34,100.13 105.42,100.13 111.76,93.79 113.1,93.79 115.72,91.17 121.93,91.17 125.97,87.12 127.88,87.12 131.61,83.39 131.61,80.31 133.73,78.19 133.73,75.69 136.63,72.8 144.43,72.8 144.78,73.15 156.32,73.15 158.43,71.04 158.43,69.08 158.68,68.83 158.97,68.83 v2(159.15,68.66)
  BOTTOM w0.076: UC1.H20 159.43,68.94 v2(159.15,68.66)
  BOTTOM w0.102: v2(86.51,87.49) 86.32,87.68 86.32,88 86.64,88.32 LI1.4
USB3RP1_D+: length 11
  BOTTOM w0.102: LI1.3 86.64,90.85 86.39,91.1 86.39,91.39 86.53,91.53 DI1.8 DI1.2 86.53,93.02 86.38,93.17 v3(86.38,93.81) 86.38,94.2 85.7,94.88 83.56,94.88 81.81,96.63 81.81,97.2 81.98,97.37 JUSB1.6
USB3RP2: length 191.1
  IN2 w0.086: v2(280.65,60.08) 280.44,60.29 280.17,60.29 278.2,58.32 278.2,57.8 277.17,56.76 277.17,46.26 277.95,45.47 277.95,41.44 278.49,40.91 278.49,32.36 276.56,30.44 276.56,29.41 275.58,28.42 271.18,28.42 270.01,27.25 270.01,23.27 267.63,20.89 259.54,20.89 259.3,21.13 256.37,21.13 253.25,24.24 246.96,24.24 246.54,24.66 240.43,24.66 240.14,24.37 236.07,24.37 232.44,27.99 228.92,27.99 227.67,26.74 197.98,26.74 183.68,41.05 183.68,41.43 180.93,44.17 178.54,44.17 176.9,45.81 176.9,47.77 176.47,48.2 175.64,48.2 173.28,50.56 173.28,51.17 172.61,51.84 170.87,51.84 170.45,52.26 170.45,57.61 170.21,57.85 170.21,58.53 169.98,58.76 169.4,58.76 168.69,59.47 166.11,59.47 165.85,59.73 165.85,59.93 164.9,60.87 164.21,60.87 159.55,65.53 159.55,70.87 159.42,71 v2(159.08,71)
  BOTTOM w0.076: UC1.F18 160.56,70.27 160.44,70.4 160.32,70.4 159.96,70.76 159.96,71.01 159.76,71.21 159.55,71.21 159.38,71.11 159.28,71 v2(159.08,71)
  BOTTOM w0.102: LI6.4 281.34,59.95 280.98,60.3 280.86,60.3 280.65,60.09 v2(280.65,60.08)
USB3RP2_D+: length 9.3
  BOTTOM w0.102: JUSB3.6 290.3,58.94 290.16,59.08 289.91,59.08 289.14,58.31 288.24,58.31 286.38,60.16 285.93,60.16 285.79,60.02 DI4.2 DI4.8 284.3,60.02 284.1,60.22 283.7,60.22 283.43,59.95 LI6.3
USB3RP4: length 105
  IN2 w0.086: v2(162.02,69.86) 162.02,69.99 162.14,70.1 162.34,70.1 162.57,70.33 162.57,71.94 163.54,72.91 164.45,72.91 165.53,73.99 171.64,73.99 172.01,73.62 172.9,73.62 v2(172.9,73.62) ; v2(178.32,86.84) 178.43,86.95 178.43,87.32 178.67,87.57 183.74,87.57 184.39,86.91 218.44,86.91 219.41,85.94 230.51,85.94 231.61,84.84 234.86,84.84 238.32,81.38 238.98,81.38 239.61,80.75 239.61,80.53 v2(239.79,80.35)
  BOTTOM w0.076: 172.18,73.62 v2(172.9,73.62) ; v2(162.02,69.86) 162.33,69.86 162.47,69.73 UC1.G15
  BOTTOM w0.102: LI9.4 239.02,88.02 238.66,87.66 238.66,85.43 239.78,84.31 239.78,80.36 v2(239.79,80.35) ; 172.18,73.62 171.92,73.89 171.92,75.44 177.18,80.7 177.18,84.57 178.32,85.72 v2(178.32,86.84)
USB3RP4_D+: length 9.2
  BOTTOM w0.102: JUSB2.6 240.05,97.37 239.9,97.22 239.9,96.91 240.54,96.27 240.54,95.32 238.75,93.53 238.75,92.97 238.89,92.83 DI6.2 DI6.8 238.89,91.32 238.71,91.13 238.71,90.84 239.02,90.53 LI9.3
USB3TN1: length 101
  IN2 w0.086: v2(149.49,74.85) 145.02,74.85 143.63,73.47 137.46,73.47 134.69,76.25 134.69,78.57 132.56,80.7 132.56,83.78 128.26,88.08 126.35,88.08 122.32,92.11 119.05,92.11 118.26,92.9 115.4,92.9 108.55,99.76 107.19,99.76 105.88,101.07 102.2,101.07 94.76,93.63 90.22,93.63 88.93,92.34 83.74,92.34 81.76,90.37 81.76,88.84 84.26,86.34 87.62,86.34 87.76,86.21 87.76,85.94 v2(87.58,85.76)
  BOTTOM w0.076: v2(149.49,74.85) 149.6,74.74 150.06,74.74 150.35,74.45 150.35,74.14 150.71,73.78 150.71,72.77 UC1.C33
  BOTTOM w0.102: v2(87.58,85.76) 87.73,85.92 87.73,86.25 CI4.2
USB3TN1_C: length 1.6
  BOTTOM w0.102: CI4.1 87.75,87.8 87.75,88.07 87.44,88.39 LI2.1
USB3TN1_D-: length 8.4
  BOTTOM w0.102: JUSB1.8 87.43,97.37 87.58,97.23 87.58,96.76 87.04,96.23 87.04,95.21 87.67,94.58 87.67,94.32 87.66,94.31 87.66,93.61 87.67,93.6 87.67,93.33 87.53,93.19 DI1.4 DI1.7 87.53,91.54 87.73,91.34 87.73,91.02 87.44,90.73 LI2.2
USB3TN2: length 193.5
  IN2 w0.086: v2(276.32,58.97) 276.53,58.76 276.77,58.76 277.01,58.52 277.01,57.76 276.4,57.15 276.4,45.76 277.19,44.97 277.19,33.21 276.65,32.68 268.55,32.68 266.45,30.58 253.99,30.58 252.86,31.71 250.72,31.71 250.3,32.14 237.36,32.14 235.72,33.78 232.82,33.78 232.28,34.32 231.34,34.32 230.92,34.74 228.4,34.74 224.73,38.41 199.79,38.41 193.03,45.17 193.03,60.94 192.14,61.83 192.14,64.1 191.68,64.56 191.68,65.74 191.08,66.34 191.08,66.58 179.92,77.74 163.5,77.74 162.85,77.09 158.67,77.09 158.03,76.46 151.76,76.46 150.35,75.05 150.35,74.69 150.44,74.6 150.53,74.6 v2(150.8,74.86)
  BOTTOM w0.076: v2(150.8,74.86) 150.8,74.85 150.94,74.71 151.17,74.71 151.37,74.5 151.37,74.03 151.59,73.81 151.59,73.45 151.41,73.27 UC1.B33
  BOTTOM w0.102: CI16.2 278.89,58.79 276.5,58.79 v2(276.32,58.97)
USB3TN2_C: length 1.6
  BOTTOM w0.102: CI16.1 280.53,58.81 280.88,58.81 281.21,59.14 LI5.1
USB3TN2_D-: length 11.9
  BOTTOM w0.102: JUSB3.8 290.3,53.48 290.11,53.29 289.86,53.29 289.14,54 288.76,54 287.53,55.23 287.53,57.77 286.43,58.86 285.89,58.86 285.73,59.02 DI4.4 DI4.7 284.27,59.02 284.09,58.84 283.74,58.84 283.44,59.14 LI5.2
USB3TN4: length 117
  IN2 w0.086: v2(149.11,89.67) 148.9,89.88 148.9,90.16 149.42,90.68 151.29,90.68 152.01,91.4 203.85,91.4 204.48,90.76 232.8,90.76 234.37,89.19 236.9,89.19 240.27,85.82 240.27,85.48 240.19,85.4 v2(239.9,85.4)
  BOTTOM w0.076: 150.28,76.3 150.3,76.29 150.3,76.27 150.91,75.65 152.02,75.65 152.91,74.77 152.91,73.22 152.68,73 152.5,73 152.44,72.93 UC1.B31
  BOTTOM w0.102: v2(149.11,89.67) 148.93,89.49 148.93,86.12 149.67,85.38 149.67,81.65 148.84,80.82 148.84,77.98 150.28,76.54 150.28,76.3 ; CI28.2 240.19,85.87 240.19,85.53 240.06,85.4 v2(239.9,85.4)
USB3TN4_C: length 1.6
  BOTTOM w0.102: CI28.1 240.1,87.56 240.1,87.87 239.78,88.2 LI8.1
USB3TN4_D-: length 12.6
  IN2 w0.086: JUSB2.8 245.48,97.37 245.72,97.13 245.72,96.88 245.01,96.17 245.01,95.53 243.78,94.29 240.31,94.29 240.07,94.05 240.07,93.77 v2(239.89,93.59)
  BOTTOM w0.102: LI8.2 239.78,90.57 240.03,90.82 240.03,91.19 239.89,91.33 DI6.7 DI6.4 239.89,92.8 240.05,92.96 240.05,93.43 v2(239.89,93.59)
USB3TP1: length 100.9
  IN2 w0.086: v2(149.49,74.22) 149.03,74.68 145.09,74.68 143.71,73.29 137.39,73.29 134.51,76.17 134.51,78.5 132.38,80.62 132.38,83.71 128.18,87.91 126.27,87.91 122.24,91.94 118.97,91.94 118.19,92.72 115.33,92.72 108.47,99.58 107.12,99.58 105.81,100.9 102.27,100.9 94.83,93.46 90.29,93.46 89,92.16 83.81,92.16 81.94,90.29 81.94,88.91 84.33,86.52 87.7,86.52 87.93,86.28 87.93,85.95 88.12,85.76 v2(88.16,85.76)
  BOTTOM w0.076: v2(149.49,74.22) 149.49,74.36 149.68,74.55 149.98,74.55 150.16,74.37 150.16,74.06 150.52,73.7 150.52,72.9 150.46,72.84 150.3,72.84 150.19,72.72 150.19,72.61 150.26,72.53 UC1.B34
  BOTTOM w0.102: v2(88.16,85.76) 88.12,85.76 87.94,85.94 87.94,86.19 CI5.2
USB3TP1_C: length 1.6
  BOTTOM w0.102: LI2.4 88.29,88.37 87.97,88.05 87.97,87.81 CI5.1
USB3TP1_D+: length 8.4
  BOTTOM w0.102: JUSB1.9 87.96,97.37 87.79,97.21 87.79,96.67 87.26,96.14 87.26,95.3 87.89,94.67 v3(87.89,93.88) 87.89,93.25 88.03,93.11 DI1.5 DI1.6 88.03,91.5 87.93,91.4 87.93,91.06 88.29,90.7 LI2.3
USB3TP2: length 193.4
  IN2 w0.086: v2(150.8,74.28) 150.65,74.42 150.37,74.42 150.18,74.62 150.18,75.12 151.69,76.63 157.96,76.63 158.6,77.27 162.78,77.27 163.43,77.91 179.99,77.91 191.26,66.65 191.26,66.41 191.86,65.81 191.86,64.63 192.31,64.17 192.31,61.9 193.2,61.01 193.2,45.25 199.86,38.58 224.8,38.58 228.48,34.91 231,34.91 231.42,34.49 232.36,34.49 232.9,33.95 235.79,33.95 237.43,32.31 250.37,32.31 250.79,31.89 252.93,31.89 254.06,30.75 266.38,30.75 268.48,32.85 276.58,32.85 277.01,33.29 277.01,44.9 276.22,45.68 276.22,57.22 276.83,57.83 276.83,58.45 276.7,58.59 276.53,58.59 v2(276.32,58.38)
  BOTTOM w0.076: v2(150.8,74.28) 150.8,74.43 150.88,74.51 150.94,74.51 150.97,74.54 151.1,74.54 151.21,74.44 151.21,74.1 151.16,74.05 151.11,74.05 150.99,73.93 150.99,73.85 151.05,73.79 151.38,73.79 151.43,73.74 151.43,73.51 151.26,73.35 151.12,73.35 151.06,73.42 UC1.A33
  BOTTOM w0.102: CI13.2 278.97,58.57 276.51,58.57 v2(276.32,58.38)
USB3TP2_C: length 1.6
  BOTTOM w0.102: CI13.1 280.51,58.6 280.91,58.6 281.21,58.29 LI5.4
USB3TP2_D+: length 11.9
  BOTTOM w0.102: LI5.3 283.41,58.29 283.74,58.62 284.13,58.62 284.23,58.52 DI4.6 DI4.5 285.74,58.52 285.86,58.65 286.34,58.65 287.31,57.68 287.31,55.14 288.67,53.79 289.05,53.79 289.77,53.07 290.1,53.07 290.3,52.88 JUSB3.9
USB3TP4: length 117
  IN2 w0.086: v2(148.53,89.67) 148.73,89.87 148.73,90.24 149.35,90.85 151.21,90.85 151.94,91.58 203.92,91.58 204.56,90.94 232.87,90.94 234.44,89.37 236.97,89.37 240.44,85.89 240.44,85.62 v2(240.66,85.4)
  BOTTOM w0.076: 150.07,76.3 150.07,76.29 150.08,76.28 150.08,76.22 150.11,76.19 150.83,75.46 151.94,75.46 152.71,74.69 152.71,73.3 152.61,73.19 152.5,73.19 152.41,73.28 152.41,73.48 UC1.A31
  BOTTOM w0.102: 150.07,76.3 150.07,76.45 148.63,77.89 148.63,80.91 149.45,81.74 149.45,85.29 148.71,86.03 148.71,89.49 v2(148.53,89.67) ; v2(240.66,85.4) 240.41,85.66 240.41,86.06 CI27.2
USB3TP4_C: length 1.6
  BOTTOM w0.102: CI27.1 240.32,87.55 240.32,87.82 240.63,88.13 LI8.4
USB3TP4_D+: length 12.7
  IN2 w0.086: JUSB2.9 246.15,97.37 245.89,97.11 245.89,96.8 245.18,96.09 245.18,95.45 243.85,94.12 240.38,94.12 240.25,93.98 240.25,93.82 v2(240.47,93.59)
  BOTTOM w0.102: v2(240.47,93.59) 240.27,93.39 240.27,92.94 240.39,92.81 DI6.5 DI6.6 240.39,91.36 240.25,91.22 240.25,90.87 240.63,90.49 LI8.3
USB_DB_DET#: length 2.2
  TOP w0.102: UE3.7 250.47,65.01 249.82,65.66 T98.1
USB_OC0#: length 201.7
  IN1 w0.102: v2(171.98,56.78) 172.48,56.28 174.27,56.28 175.68,57.68 179.87,57.68 181.33,56.22 183.05,56.22 184.36,57.53 185.45,57.53 187.23,59.31 187.9,59.31 188.06,59.47 190.18,59.47 190.51,59.81 190.51,60.84 191.37,61.7 191.37,63.66 192.31,64.59 193.49,64.59 196.5,67.6 v2(196.88,67.6)
  IN2 w0.102: v2(88.53,82.09) 88.51,82.08 v2(88.51,79.5)
  BOTTOM w0.076: 173.36,58.04 173.34,58.04 172.08,56.78 v2(171.98,56.78) 171.62,57.13 171.02,57.13 170.71,56.82 170.64,56.82 170.49,56.67 170.49,56.49 170.25,56.25 169.74,56.25 UC1.AL3
  BOTTOM w0.102: v2(196.88,67.6) 196.88,70.28 202.03,75.42 v1(202.03,78.83) 202.03,79.58 205.34,82.89 205.34,89.05 201.86,92.53 194.77,92.53 189.85,97.45 137.41,97.45 131.54,91.58 131.54,87.72 129.15,85.32 126.03,85.32 122.51,81.8 116.61,81.8 115.19,80.38 97.05,80.38 96.17,79.5 v2(88.51,79.5) ; RPC19.3 177.16,59.85 176.24,58.93 175.59,58.93 174.7,58.04 173.36,58.04 ; v2(88.53,82.09) 88.37,82.26 UI1.5
USB_OC1#: length 148.1
  TOP w0.102: v2(283.53,42.63) 283.61,42.71 UI3.13 ; v1(228.29,67.36) 228.29,67.36 v2(227.78,67.36)
  IN1 w0.102: v2(283.53,42.63) 279.7,46.46 279.7,50.14 275.39,54.46 273.7,54.46 270.39,57.77 270.39,59.36 270.08,59.68 270.08,62.05 268.54,63.58 268.54,67.22 v2(269.11,67.79) ; v2(183.46,54.95) 183.46,56.04 184.54,57.12 185.62,57.12 187.4,58.9 188.07,58.9 188.23,59.07 190.34,59.07 190.92,59.64 190.92,60.53 192.01,61.62 192.01,63.63 192.56,64.19 193.66,64.19 196.01,66.53 197.8,66.53 198.96,67.7 222.75,67.7 223.2,68.15 226.57,68.15 227.36,67.36 v2(227.78,67.36)
  IN2 w0.102: v2(227.78,67.36) 228.42,67.36 229.19,68.13 256.96,68.13 257.64,67.45 263.32,67.45 263.66,67.79 v2(269.11,67.79)
  BOTTOM w0.076: 173.36,55.01 173.16,54.82 173.16,54.52 171.91,53.28 171.27,53.28 171.04,53.51 UC1.AT1
  BOTTOM w0.102: 173.36,55.01 175.82,57.47 182.07,57.47 182.12,57.43 182.74,57.43 183.07,57.76 RPC7.7 183.56,57.76 183.78,57.54 183.78,55.27 v2(183.46,54.95)
USB_OC2#: length 109.2
  TOP w0.102: v2(182.8,58.69) 182.82,58.66 182.83,58.66 183.14,58.34 183.63,58.34 183.83,58.55 183.83,58.76 183.93,58.86 RPC5.8
  IN1 w0.102: v2(227.78,69.52) 218.1,69.52 217.61,69.04 196.16,69.04 193.16,66.04 190.6,66.04 188.27,63.72 188.27,62.4 185.26,59.38 183.37,59.38 183.09,59.1 183.09,58.98 v2(182.8,58.69) 182.38,59.11 175.08,59.11 174.53,58.56 173.26,58.56 173.13,58.69 v2(171.85,58.69)
  IN2 w0.102: v2(245.07,70.46) 244.1,69.49 233.91,69.49 233.45,69.95 228.21,69.95 v2(227.78,69.52)
  BOTTOM w0.076: v2(171.85,58.69) 171.43,58.27 171.18,58.27 170.96,58.5 170.6,58.5 170.14,58.04 UC1.AH2
  BOTTOM w0.102: v2(245.07,70.46) v1(245.07,72.19) 245.07,73.49 244.35,74.22 244.35,88.09 246,89.74 248.75,89.74 249.97,90.95 UI2.5
USB_OC3#: length 16.4
  BOTTOM w0.076: 173.36,54.01 171.71,52.37 171.12,52.37 170.97,52.52 169.78,52.52 UC1.AV3
  BOTTOM w0.102: 173.36,54.01 173.64,54.3 173.64,54.72 175.92,57 180.71,57 v1(180.88,56.83) 181.1,56.62 182.74,56.62 182.88,56.76 RPC7.5
USB_PWR_EN1#: length 198.9
  TOP w0.102: RPE9.2 257.18,69.64 258.28,68.54 258.28,68.18 v2(258.18,68.09) 258.1,68.01 UE3.30
  IN1 w0.102: v2(258.18,68.09) 258.02,68.25 241.5,68.25 238.6,71.15 238.6,76.7 235.79,79.52 235.79,80.12 231.96,83.94 231.96,85.3 229.14,88.12 219.8,88.12 219.21,88.72 203.92,88.72 198.69,93.95 v2(198.69,95.02)
  BOTTOM w0.102: UI1.4 92.5,82.26 92.77,82.52 114.68,82.52 115.74,83.58 121.35,83.58 124.86,87.1 128.03,87.1 129.54,88.6 129.54,93.84 134.92,99.22 193.96,99.22 v1(198.17,95.02) v2(198.69,95.02)
USB_PWR_EN2#: length 35.9
  TOP w0.102: v2(258.67,73.3) 258.06,73.91 v1(257.44,73.91) 256.7,73.91 256.25,73.46 256.25,71.7 256.68,71.27 RPE9.1 256.68,69.56 256.44,69.32 UE3.31
  BOTTOM w0.102: v2(258.67,73.3) 257.96,72.59 252.25,72.59 250.63,74.21 250.63,78.39 251.39,79.16 251.39,85.65 254.09,88.34 254.09,90.73 254.31,90.95 UI2.4
USB_PWR_SHR_EN#: length 93.5
  TOP w0.102: RPE9.4 258.18,70.04 v2(258.54,69.67) ; v2(290.59,41.26) 290.14,41.71 UI3.6 ; v2(256.68,39.15) 256.23,38.71 256.23,38.3 256.44,38.1 UE2.B38
  IN1 w0.102: v2(290.59,41.26) 290.19,41.66 289.89,41.66 288.29,43.26 283.88,43.26 280.13,47 280.13,50.47 275.44,55.17 v2(274.91,55.17)
  IN2 w0.102: v2(275.09,44.46) 274.9,44.65 274.9,54.69 274.91,54.69 v2(274.91,55.17) 274.49,55.59 274.49,59.04 274.06,59.46 274.06,66.41 271.03,69.44 258.77,69.44 v2(258.54,69.67)
  BOTTOM w0.102: v2(256.68,39.15) v1(258.35,37.48) 258.76,37.07 260.73,37.07 261.13,36.66 263.72,36.66 264.13,36.26 265.96,36.26 268.07,38.37 268.07,42.78 270.34,45.06 274.5,45.06 v2(275.09,44.46)
USB_PWR_SHR_VBUS_EN: length 73.5
  TOP w0.102: v2(289.99,41.25) 289.95,41.21 UI3.5 ; UE3.25 257.64,65.51 258.56,64.59 264.03,64.59 264.64,65.2 264.64,67.6 263.31,68.94 v4(261.45,68.94) 258.68,68.94 v2(257.95,69.67) 257.68,69.94 RPE9.3
  IN1 w0.102: v2(289.99,41.25) 288.21,43.03 283.6,43.03 279.91,46.72 279.91,50.23 275.47,54.66 274.84,54.66 274.5,55 274.5,55.43 v2(274.9,55.83)
  IN2 w0.102: v2(274.9,55.83) 274.9,59.17 274.38,59.69 274.38,66.38 271.12,69.65 259.34,69.65 258.91,70.08 258.35,70.08 v2(257.95,69.67)
USBP0+: length 115.9
  IN2 w0.086: v2(84.27,90.17) 84.45,90.35 84.45,90.56 84.68,90.79 89.59,90.79 90.87,92.07 96.13,92.07 103.58,99.53 105.18,99.53 108.58,96.12 108.58,95.02 111.95,91.66 114.35,91.66 115.43,90.57 121.68,90.57 125.72,86.53 127.64,86.53 130.06,84.11 130.06,82.18 131.02,81.22 131.02,80.06 133.13,77.95 133.13,75.57 136.19,72.5 155.7,72.5 156.65,71.56 156.91,71.56 158.03,70.44 158.03,68.76 158.29,68.5 158.29,63.99 158.56,63.73 159.13,63.73 162.45,60.41 164.52,60.41 165.29,59.64 165.29,58.15 165.21,58.08 165.21,56.72 165.09,56.6 165.09,55.88 165.62,55.36 165.74,55.36 v2(166.02,55.64)
  BOTTOM w0.076: UC1.AM8 166.37,55.64 v2(166.02,55.64)
  BOTTOM w0.102: v2(84.27,90.17) 84.48,90.37 84.48,90.54 84.14,90.87 LI3.1
USBP0-: length 115.9
  IN2 w0.086: v2(166.02,55.01) 165.85,55.18 165.55,55.18 164.92,55.81 164.92,56.67 165.04,56.79 165.04,58.15 165.11,58.23 165.11,59.57 164.44,60.24 162.37,60.24 159.06,63.55 158.48,63.55 158.11,63.92 158.11,68.43 157.86,68.69 157.86,70.36 156.84,71.38 156.57,71.38 155.63,72.33 136.12,72.33 132.95,75.49 132.95,77.88 130.84,79.99 130.84,81.15 129.88,82.11 129.88,84.03 127.56,86.35 125.65,86.35 121.61,90.4 115.36,90.4 114.28,91.48 111.88,91.48 108.41,94.95 108.41,96.05 105.1,99.35 103.65,99.35 96.2,91.9 90.94,91.9 89.66,90.62 86.91,90.62 86.75,90.46 86.41,90.46 86.25,90.62 85.92,90.62 85.76,90.46 85.43,90.46 85.27,90.62 84.76,90.62 84.63,90.49 84.63,90.35 84.81,90.17 v2(84.91,90.17)
  BOTTOM w0.076: UC1.AN8 166.11,55.11 v2(166.02,55.01)
  BOTTOM w0.102: LI3.4 84.99,90.9 84.69,90.6 84.69,90.38 v2(84.91,90.17)
USBP0_D+: length 15
  IN2 w0.086: JUSB1.3 84.46,95.87 84.64,95.68 84.64,94.85 84.24,94.45 81.64,94.45 81.43,94.24 81.43,94.04 v2(81.23,93.83)
  BOTTOM w0.102: LI3.2 84.14,93.16 84.46,93.47 84.46,93.71 84.35,93.82 83.78,93.82 83.55,93.59 83.55,92.16 82.98,91.59 82.07,91.59 81.41,92.25 81.41,92.74 81.31,92.84 DI2.2 80.55,93.03 80.74,93.23 81.31,93.23 81.42,93.33 81.42,93.64 v2(81.23,93.83)
USBP0_D-: length 14.9
  IN2 w0.086: v2(81.81,93.83) 81.61,94.04 81.61,94.17 81.71,94.27 84.31,94.27 84.82,94.78 84.82,95.68 85,95.87 JUSB1.2
  BOTTOM w0.102: v2(81.81,93.83) 81.63,93.66 81.63,93.33 81.74,93.23 82.29,93.23 82.48,93.03 DI2.3 81.72,92.84 81.63,92.75 81.63,92.34 82.16,91.81 82.89,91.81 83.33,92.25 83.33,93.68 83.7,94.05 v3(84.17,94.05) 84.43,94.05 84.67,93.8 84.67,93.47 84.99,93.16 LI3.3
USBP1+: length 155.4
  TOP w0.102: v2(280.46,39.81) 280.47,39.8 280.75,39.8 280.76,39.79 281.21,39.79 281.68,39.32 v3(282.51,39.32) 284.15,39.32 284.69,38.77 287.27,38.77 287.65,39.15 287.65,39.81 287.76,39.92 UI3.3
  IN2 w0.086: v2(167.49,53.86) 167.64,53.86 167.75,53.75 167.75,52.5 170.83,49.42 172.45,49.42 176.09,45.78 176.09,45.53 178.95,42.67 181.33,42.67 182.89,41.11 182.89,40.75 197.76,25.88 227.9,25.88 229.24,27.22 232.12,27.22 235.75,23.6 240.49,23.6 240.79,23.89 245.77,23.89 246.74,22.92 249.38,22.92 249.93,23.47 252.93,23.47 256.05,20.35 258.98,20.35 259.24,20.09 267.99,20.09 270.78,22.88 270.78,26.79 271.63,27.65 275.89,27.65 277.33,29.09 277.33,30.12 279.26,32.04 279.26,39.31 279.82,39.88 280.39,39.88 v2(280.46,39.81)
  BOTTOM w0.076: UC1.AT7 166.91,53.48 166.82,53.57 166.82,53.71 166.94,53.82 167.08,53.82 167.11,53.86 v2(167.49,53.86)
USBP1-: length 155.1
  TOP w0.102: UI3.2 287.26,39.99 287.44,39.81 287.44,39.24 287.18,38.99 284.78,38.99 284.24,39.53 282.8,39.53 282.79,39.55 282.23,39.55 282.22,39.53 281.77,39.53 281.3,40 280.85,40 v2(280.46,40.39)
  IN2 w0.086: v2(167.52,54.45) 167.52,54.34 167.93,53.93 167.93,52.57 170.9,49.59 172.53,49.59 176.26,45.86 176.26,45.61 179.02,42.85 181.4,42.85 183.07,41.18 183.07,40.82 197.83,26.05 227.83,26.05 229.17,27.4 232.2,27.4 235.82,23.77 240.42,23.77 240.72,24.07 245.84,24.07 246.81,23.1 249.31,23.1 249.86,23.65 253,23.65 256.12,20.52 259.05,20.52 259.31,20.27 267.92,20.27 270.6,22.95 270.6,26.87 271.56,27.82 275.82,27.82 277.16,29.16 277.16,30.19 279.08,32.12 279.08,39.38 279.75,40.05 280.12,40.05 v2(280.46,40.39)
  BOTTOM w0.076: UC1.AR7 167.19,54.13 v2(167.52,54.45)
USBP1_R_D+: length 10.8
  IN2 w0.086: v2(286.56,57.26) 286.77,57.05 287.2,57.05 288.02,56.23 288.42,56.23 288.8,56.61 JUSB3.3
  BOTTOM w0.102: LI7.2 281.44,56.29 281.71,56.02 282.55,56.02 282.66,56.13 282.66,56.57 DI5.3 283.17,56.57 283.17,56.07 283.26,55.97 283.42,55.97 284.51,57.06 286.36,57.06 v2(286.56,57.26)
USBP1_R_D-: length 11
  IN2 w0.086: JUSB3.2 288.8,55.73 288.47,56.06 287.94,56.06 287.13,56.87 286.75,56.87 286.56,56.68 v2(286.56,56.67)
  BOTTOM w0.102: LI7.3 281.42,55.44 281.79,55.8 282.58,55.8 282.66,55.73 282.66,55.15 DI5.2 283.17,55.15 283.17,55.66 283.27,55.76 283.51,55.76 284.6,56.84 286.39,56.84 v2(286.56,56.67)
USBP2+: length 88.8
  IN2 w0.086: v2(166.03,54.33) 166.03,54.33 166.03,54.3 166.25,54.08 166.52,54.08 166.53,54.08 166.58,54.08 166.68,53.97 166.68,53.97 166.81,53.84 166.81,53.19 166.35,52.73 166.35,51.98 167.95,50.38 167.95,50.08 170.54,47.49 172.47,47.49 179.66,40.31 181.9,40.31 197.28,24.93 228.3,24.93 229.5,26.13 229.94,26.13 v2(230.09,26.28)
  BOTTOM w0.076: v2(166.03,54.33) 166.03,54.33 166.03,54.33 166.15,54.45 UC1.AP8
  BOTTOM w0.102: v2(230.09,26.28) 230.27,26.1 230.46,26.1 231.04,26.67 231.04,31.81 231.8,32.58 231.8,32.92 232.09,33.21 232.43,33.21 232.57,33.35 JNGFF1.3
USBP2-: length 88.9
  IN2 w0.086: v2(230.09,25.69) 229.82,25.96 229.58,25.96 228.37,24.75 197.21,24.75 181.83,40.13 179.59,40.13 172.4,47.32 170.46,47.32 167.78,50 167.78,50.31 166.18,51.91 166.18,52.8 166.64,53.26 166.64,53.77 166.5,53.9 166.39,53.9 v2(166.06,53.57)
  BOTTOM w0.076: UC1.AR8 166.45,53.84 166.33,53.84 v2(166.06,53.57)
  BOTTOM w0.102: v2(230.09,25.69) 230.28,25.88 230.55,25.88 231.25,26.58 231.25,31.72 232.01,32.49 232.01,32.83 232.18,32.99 232.41,32.99 232.55,32.85 JNGFF1.5
USBP3+: length 237.8
  IN2 w0.076: 165.07,53.59 165.22,53.59 165.54,53.28 v2(165.54,53.24)
  IN2 w0.086: 165.07,53.59 164.95,53.47 164.95,53.36 165.08,53.23 165.08,53.06 164.95,52.92 164.95,52.73 165.08,52.59 165.08,52.4 164.95,52.26 164.95,52.09 166.95,50.09 166.95,49.65 169.97,46.63 172.39,46.63 179.79,39.23 182.08,39.23 197.05,24.25 217.22,24.25 217.68,23.79 234.19,23.79 235.32,22.65 244.7,22.65 245.37,21.97 253.08,21.97 255.75,19.3 257.46,19.3 258.41,18.36 260.17,18.36 260.89,19.08 265.22,19.08 265.45,18.85 265.85,18.85 266.62,19.62 268.23,19.62 271.41,22.8 271.41,24.04 274.54,27.17 276.08,27.17 277.81,28.91 277.81,29.9 279.72,31.81 279.72,38.3 280.93,39.51 280.93,40.61 278.8,42.74 278.8,45.75 277.76,46.79 277.76,56.5 280.58,59.32 280.76,59.32 282.04,60.6 282.04,65.93 285.83,69.71 285.83,74.78 283.97,76.64 257.6,76.64 257.15,77.09 248.1,77.09 243.61,81.59 243.61,82.59 243.38,82.82 243.38,85.02 v2(242.98,85.43)
  BOTTOM w0.076: UC1.AT10 165.3,53.48 v2(165.54,53.24)
  BOTTOM w0.102: LI4.1 242.84,86.25 243.18,85.91 243.18,85.63 v2(242.98,85.43)
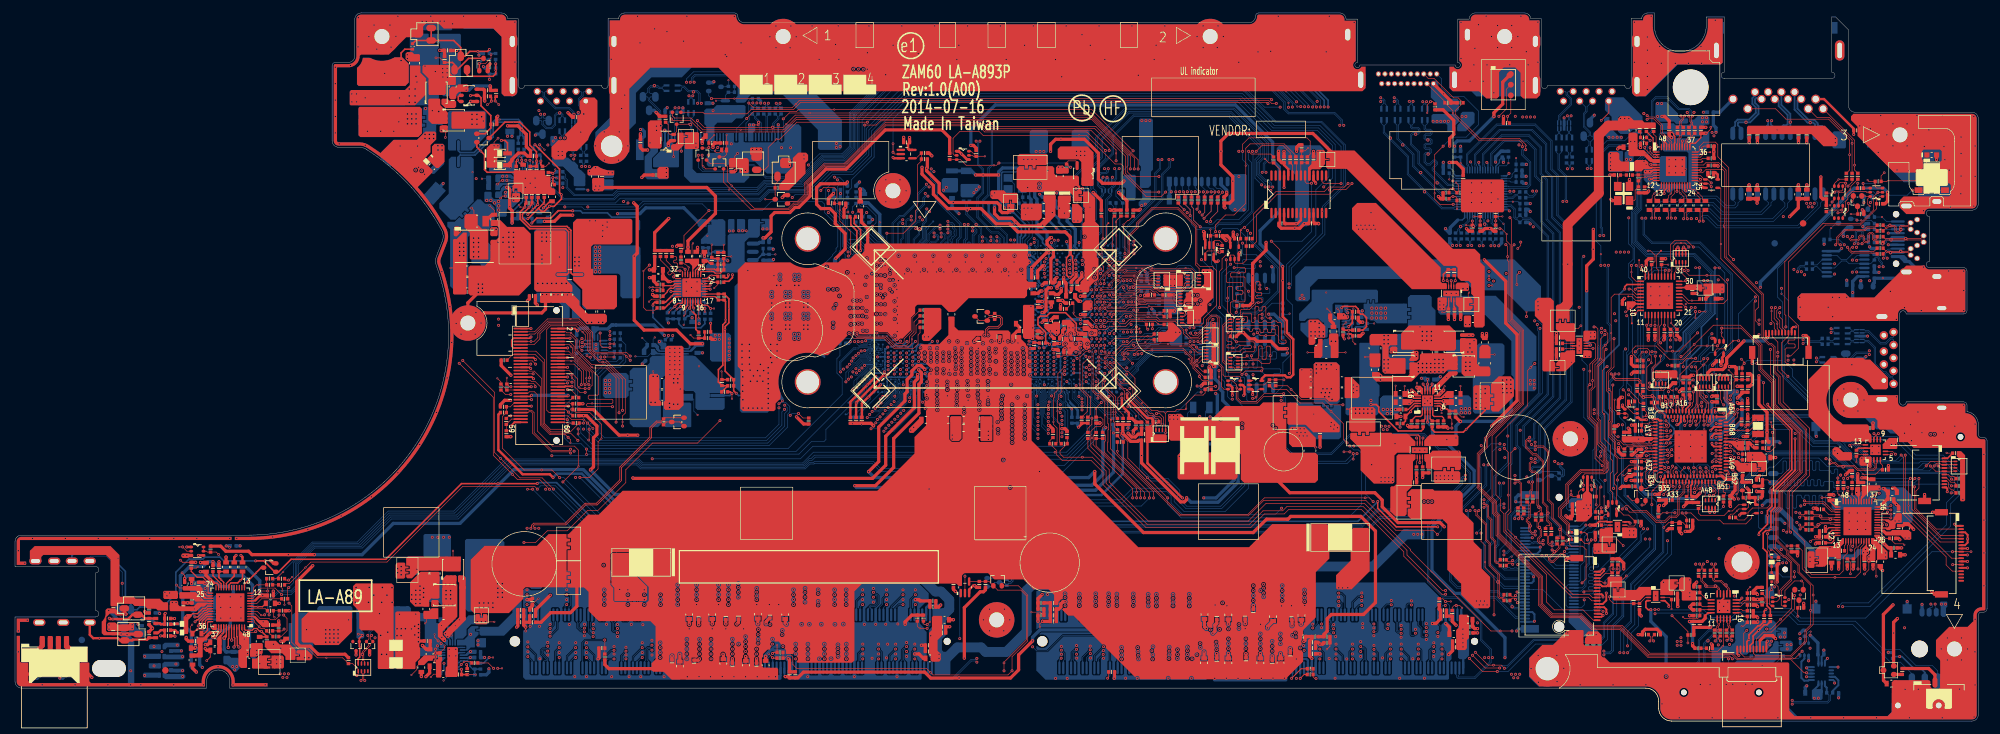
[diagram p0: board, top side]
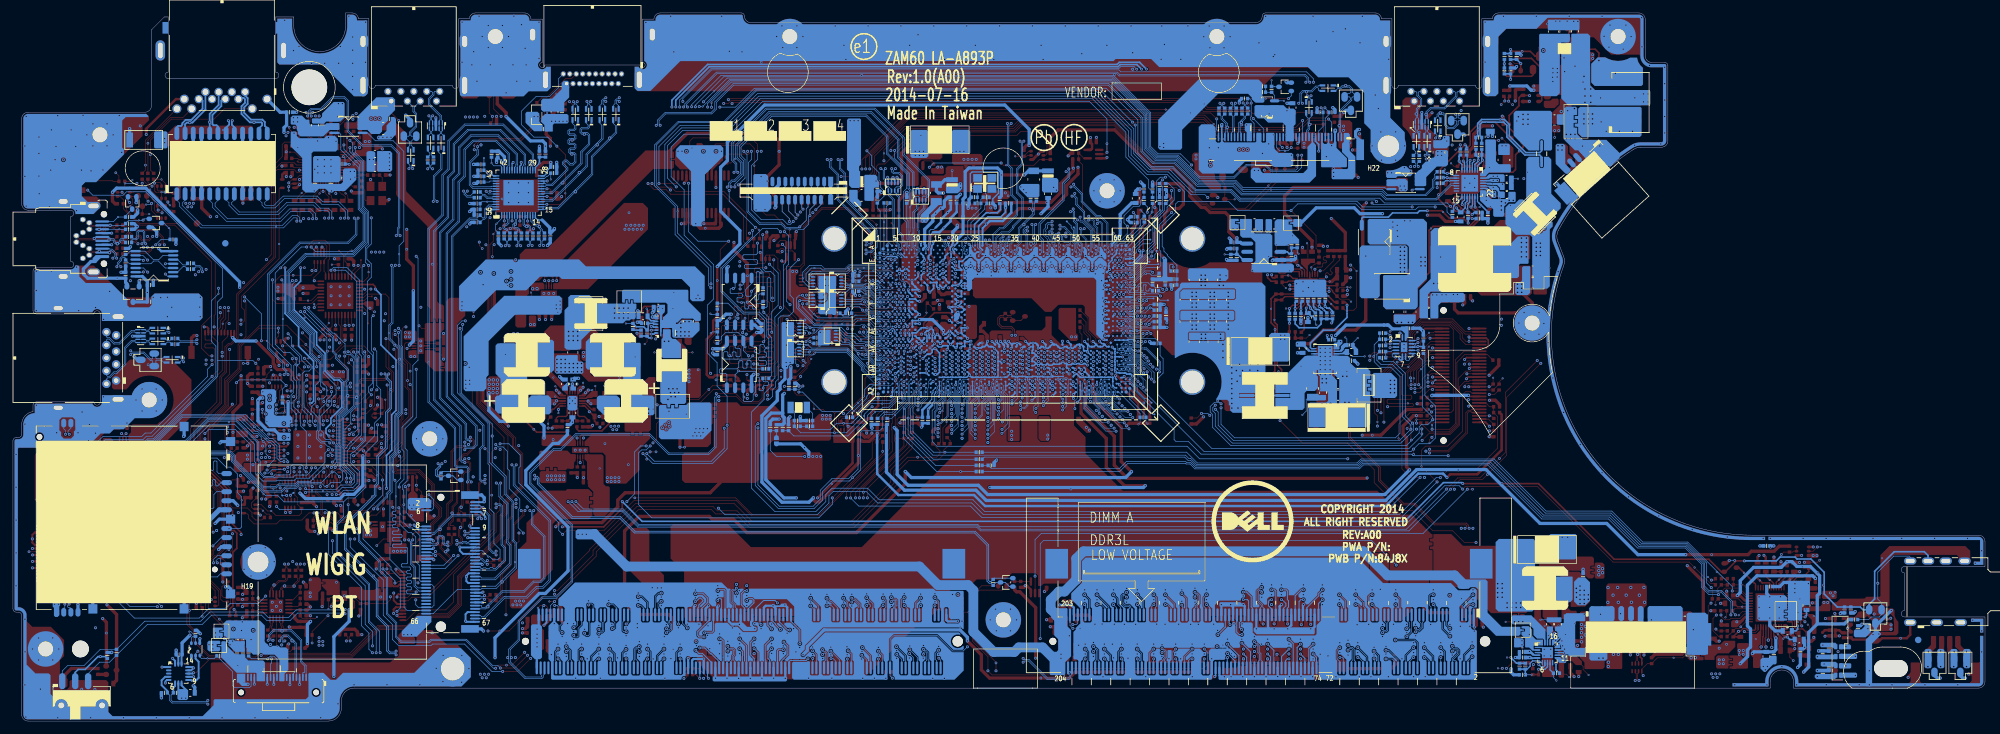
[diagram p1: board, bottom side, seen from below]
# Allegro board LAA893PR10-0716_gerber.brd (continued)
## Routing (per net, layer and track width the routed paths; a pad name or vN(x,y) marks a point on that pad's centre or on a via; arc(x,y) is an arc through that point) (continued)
USBP3-: length 238
  IN2 w0.076: 164.88,53.65 165,53.77 165.43,53.77 v2(165.49,53.83)
  IN2 w0.086: v2(243.56,85.43) 243.56,85.42 243.56,82.89 243.79,82.66 243.79,81.66 248.18,77.27 257.22,77.27 257.67,76.82 284.04,76.82 286,74.85 286,69.64 282.22,65.86 282.22,60.53 280.84,59.15 280.66,59.15 277.94,56.43 277.94,46.86 278.98,45.82 278.98,42.81 281.11,40.68 281.11,39.44 279.9,38.23 279.9,31.74 277.99,29.83 277.99,28.83 276.15,27 274.62,27 271.58,23.97 271.58,22.72 268.31,19.45 266.69,19.45 265.92,18.67 265.38,18.67 265.15,18.9 260.96,18.9 260.24,18.18 258.34,18.18 257.39,19.13 255.68,19.13 253.01,21.8 245.3,21.8 244.62,22.47 235.25,22.47 234.11,23.61 217.61,23.61 217.15,24.08 196.98,24.08 182,39.05 179.72,39.05 172.32,46.46 169.9,46.46 166.78,49.58 166.78,50.02 164.77,52.02 164.77,53.54 164.88,53.65
  BOTTOM w0.076: v2(165.49,53.83) 165.42,53.83 165.13,54.12 UC1.AR10
  BOTTOM w0.102: v2(243.56,85.43) 243.4,85.58 243.4,85.95 243.69,86.24 LI4.4
USBP3_D+: length 9.7
  BOTTOM w0.102: LI4.2 242.84,88.66 243.24,89.05 243.24,89.62 DI3.3 243.17,90.44 243.27,90.54 243.27,90.97 242.36,91.88 242.36,93.97 242.72,94.32 242.72,94.95 241.8,95.87 JUSB2.3
USBP3_D-: length 9.7
  BOTTOM w0.102: JUSB2.2 242.93,95 242.93,94.23 242.58,93.88 242.58,91.97 243.48,91.06 243.48,90.55 243.58,90.44 DI3.2 243.45,89.55 243.45,88.97 243.69,88.73 LI4.3
USBP4+: length 90.4
  IN2 w0.086: v2(162.25,56.08) 162.25,56.07 162.06,55.88 161.93,55.88 161.85,55.96 161.85,57.35 160.37,58.83 158.57,58.83 156.64,60.76 156.64,69.47 155.56,70.54 139.11,70.54 138.67,70.98 135.91,70.98 131.91,74.97 131.91,75.64 130.56,76.99 130.56,78.65 129.59,79.62 129.59,80.78 128.22,82.16 128.22,84.13 127.1,85.24 125.11,85.24 121.07,89.29 114.59,89.29 113.58,90.29 110.14,90.29 106.73,93.71 106.73,95.68 106.24,96.16 105.85,96.16 105.66,95.97 105.66,95.71 v2(105.48,95.53)
  BOTTOM w0.076: UC1.AL15 162.64,56.41 162.31,56.08 v2(162.25,56.08)
  BOTTOM w0.102: v2(105.48,95.53) 105.66,95.71 105.66,96.98 105.34,97.3 v3(104.85,97.3) 104.01,97.3 103.32,97.98 103.14,97.98 103.01,97.85 103.01,97.58 102.88,97.45 LV27.3
USBP4-: length 90.2
  IN2 w0.086: v2(162.25,55.43) 162.25,55.57 162.11,55.7 161.86,55.7 161.67,55.89 161.67,57.28 160.3,58.65 158.5,58.65 156.46,60.68 156.46,69.4 155.49,70.37 139.03,70.37 138.6,70.8 135.83,70.8 131.74,74.9 131.74,75.57 130.38,76.92 130.38,78.57 129.41,79.54 129.41,80.71 128.04,82.08 128.04,84.06 127.03,85.07 125.04,85.07 120.99,89.11 114.52,89.11 113.51,90.12 110.07,90.12 106.55,93.63 106.55,95.6 106.17,95.99 105.92,95.99 105.84,95.9 105.84,95.75 v2(106.06,95.53)
  BOTTOM w0.076: UC1.AM15 162.57,55.76 v2(162.25,55.43)
  BOTTOM w0.102: v2(106.06,95.53) 105.88,95.71 105.88,97.07 105.43,97.51 105.13,97.51 105.11,97.53 104.58,97.53 104.57,97.51 104.1,97.51 103.41,98.2 103.02,98.2 102.92,98.3 LV27.2
USBP4_D+: length 12.7
  BOTTOM w0.102: JEDP1.3 99.96,90.9 99.79,91.06 v3(99.79,92.06) 99.79,94.35 98.07,96.07 98.07,96.35 98.23,96.52 DV4.3 98.44,97.04 98.18,97.04 97.99,97.23 97.99,97.75 98.28,98.04 98.51,98.04 98.52,98.03 99.12,98.03 99.13,98.04 99.26,98.04 99.5,97.8 100.02,97.8 100.38,97.45 LV27.4
USBP4_D-: length 12.7
  BOTTOM w0.102: JEDP1.2 99.45,90.3 99.45,90.94 99.58,91.07 99.58,91.78 99.57,91.8 99.57,92.33 99.58,92.34 99.58,94.26 97.85,95.99 97.85,96.37 97.7,96.52 DV4.2 97.77,97.26 97.77,97.84 98.19,98.26 v3(98.8,98.26) 99.35,98.26 99.59,98.02 100.06,98.02 100.34,98.3 LV27.1
USBP5+: length 89.5
  IN2 w0.086: v2(104.74,96.69) 104.52,96.91 104.52,97.02 104.63,97.13 105.94,97.13 107.24,95.83 107.24,93.98 110.4,90.82 113.81,90.82 114.87,89.76 121.3,89.76 125.35,85.71 127.3,85.71 129.24,83.77 129.24,81.82 130.2,80.86 130.2,79.72 131.03,78.89 131.03,77.23 132.49,75.77 132.49,74.97 136.02,71.44 155.39,71.44 157.07,69.76 157.07,68.1 157.35,67.82 157.35,63.36 158.24,62.47 158.64,62.47 160.4,60.71 160.4,59.55 160.99,58.97 162.28,58.97 163.39,57.86 163.39,57.46 162.75,56.83 162.75,55.7 163.09,55.36 163.43,55.36 163.6,55.2 v2(163.6,55.07)
  BOTTOM w0.076: v2(163.6,55.07) 163.24,55.43 UC1.AN13
  BOTTOM w0.102: v2(104.74,96.69) 104.56,96.52 104.56,96.35 104.89,96.02 LZ1.1
USBP5-: length 89.7
  IN2 w0.086: v2(104.15,96.69) 104.34,96.88 104.34,97.09 104.55,97.3 106.01,97.3 107.41,95.9 107.41,94.06 110.47,90.99 113.88,90.99 114.94,89.93 121.38,89.93 125.42,85.88 127.37,85.88 129.42,83.84 129.42,81.89 130.38,80.93 130.38,79.79 131.2,78.97 131.2,77.3 132.66,75.84 132.66,75.04 136.09,71.62 155.46,71.62 157.25,69.83 157.25,68.17 157.53,67.89 157.53,63.44 158.32,62.65 158.71,62.65 160.58,60.78 160.58,59.63 161.06,59.14 162.36,59.14 163.56,57.94 163.56,57.39 162.93,56.76 162.93,55.77 163.16,55.54 163.42,55.54 163.6,55.71 v2(163.6,55.71)
  BOTTOM w0.076: UC1.AM13 163.21,56.01 163.51,55.71 v2(163.6,55.71)
  BOTTOM w0.102: LZ1.4 104.04,96.02 104.35,96.32 104.35,96.49 v2(104.15,96.69)
USBP5_D+: length 4
  BOTTOM w0.102: LZ1.2 104.89,93.53 104.59,93.23 104.59,92.52 104.61,92.51 104.61,91.97 104.59,91.96 104.59,91.6 104.82,91.38 104.82,91.08 104.96,90.95 JEDP1.13
USBP5_D-: length 4
  BOTTOM w0.102: JEDP1.12 104.45,90.3 104.45,90.93 104.61,91.08 104.61,91.29 104.38,91.51 v3(104.38,92.24) 104.38,93.22 104.04,93.55 LZ1.3
USBRBIAS: length 5.6
  TOP w0.076: v1(165.11,57.33) 164.96,57.33 v2(164.56,56.93)
  TOP w0.102: v2(164.56,56.93) 164.16,56.53 161.95,56.53 161.84,56.42 RC152.1
  BOTTOM w0.076: UC1.AJ11 164.32,57.17 v2(164.56,56.93) 165.01,57.38 UC1.AJ10
USH_DET#: length 119.8
  TOP w0.102: v2(232.68,74.06) 232.68,73.53 v4(232.23,73.08) ; RPC15.4 180.64,61.58 180.98,61.23 183.34,61.23 183.66,61.56 183.66,62.27 185.7,64.3 185.7,69.62 185.04,70.28 183.14,70.28 182.64,70.79 182.64,76.52 179.75,79.4 175.66,79.4 173.34,77.07 173.34,76.36 172.01,75.03 172.01,72.22 v2(171.51,71.73)
  IN1 w0.102: v2(232.68,74.06) 232.39,74.06 231.46,74.99 217.39,74.99 215.63,73.23 197.14,73.23 191.37,79 191.37,79.71 189.76,81.32 189.76,81.68 187.21,84.24 179.9,84.24 179.22,83.56 176.13,83.56 172.68,80.11 172.68,76.08 171.95,75.35 171.95,72.17 v2(171.51,71.73)
  BOTTOM w0.076: v2(171.51,71.73) 171.1,71.32 170.57,71.32 170.37,71.12 169.89,71.12 169.59,70.82 UC1.E3
USH_PWR_STATE#: length 73.9
  TOP w0.102: v2(256.07,16.29) 258.52,13.84 RZ10.2 v4(258.52,12.08) ; v2(250.39,63.02) 250.88,63.51 UE3.10
  IN1 w0.102: v2(256.07,16.29) 256.35,16.57 256.35,23.36 262.29,29.3 264.61,29.3 267.5,32.19 267.5,34.77 268.06,35.33 268.06,36.47 267.78,36.75 267.78,37.93 272.22,42.38 272.22,46.61 265.12,53.72 265.12,54.05 264.25,54.92 264.25,55.24 262.49,57 262.03,57 256.72,62.32 251.09,62.32 v2(250.39,63.02)
USH_SMBCLK: length 34.7
  TOP w0.102: RZ8.2 252.78,13.01 252.78,12.54 v2(252.64,12.39) ; v2(265.48,38.82) 265.28,38.82 264.89,39.21 UE2.A50
  IN1 w0.102: v2(252.64,12.39) 252.83,12.58 252.83,14.33 254.43,15.93 254.43,18.57 254.8,18.94 254.8,24.51 261.64,31.36 262.45,31.36 263.37,32.28 263.37,34.26 264.56,35.45 264.56,37.33 265.25,38.02 265.25,38.31 265.43,38.49 265.43,38.77 v2(265.48,38.82)
USH_SMBDAT: length 37.1
  TOP w0.102: v2(253.22,12.39) 253,12.61 253,13.02 RZ9.2 ; UE2.B53 262.82,38.96 v2(262.8,38.94)
  IN1 w0.102: v2(253.22,12.39) 253.06,12.55 253.06,14.24 254.66,15.84 254.66,18.48 255.03,18.85 255.03,24.42 261.74,31.13 262.54,31.13 263.6,32.18 263.6,34.16 264.79,35.36 264.79,37.24 265.48,37.92 265.48,38.21 265.61,38.35 v2(265.82,38.35)
  BOTTOM w0.102: v2(262.8,38.94) 264.65,38.94 265.24,38.35 v2(265.82,38.35)
VCI_IN2#: length 10.4
  TOP w0.102: RPE5.4 264.77,51.31 264.64,51.18 264.64,49.83 264.79,49.68 v2(265.09,49.68) ; UE2.B63 262.95,43.96 v2(262.86,43.87)
  IN2 w0.102: v2(265.09,49.68) 264.69,49.28 264.69,47.15 262.95,45.41 262.67,45.41 262.46,45.2 262.46,44.27 v2(262.86,43.87)
VCT_LAN_R1: length 2.9
  TOP w0.203: UL1.6 252.88,85.99 v2(252.78,86.09)
  BOTTOM w0.102: v4(253.71,87.29) 253.44,87.02 RL3.2
  BOTTOM w0.254: RL3.2 252.82,86.13 v2(252.78,86.09)
VFB: length 2.3
  TOP w0.203: PU500.24 106.93,68.43 107.4,68.9 v1(107.68,68.9) 108.47,68.9 PR531.2
VGA_ID: length 2.6
  TOP w0.102: RE84.1 255.94,61.47 v1(255.94,61.54) UE3.19
VIDALERT_N: length 34.5
  TOP w0.102: PR528.2 100.63,71.22 102.23,69.62 v2(102.74,69.62) 103.02,69.62 103.15,69.49 PU500.32
  IN2 w0.102: v2(126.44,66.76) 126.44,67.83 124.29,69.98 109.66,69.98 107.35,72.29 105.12,72.29 102.74,69.91 v2(102.74,69.62)
  BOTTOM w0.102: RC207.2 127.48,66.31 126.9,66.31 v2(126.44,66.76) 126.44,66.99 126.68,67.23 RC204.2
VIDSCLK: length 37.9
  TOP w0.102: PR527.2 102.12,71.84 102.26,71.7 102.26,71.4 102.13,71.27 101.89,71.27 101.76,71.15 101.76,70.98 101.89,70.85 102.23,70.85 102.36,70.73 102.36,70.33 102.49,70.21 103.16,70.21 103.5,69.86 v2(103.55,69.86) 103.55,69.08 PU500.31
  IN2 w0.102: v2(103.55,69.86) 105.02,71.34 107.39,71.34 109.31,69.42 124.06,69.42 125.26,68.22 125.26,66.48 126.01,65.73 v2(127.42,65.73)
  BOTTOM w0.102: UC1.N63 132.14,66.31 129.73,66.31 129.49,66.06 127.75,66.06 v2(127.42,65.73)
VIDSOUT: length 42.9
  TOP w0.102: PR529.2 99.74,71.3 101.18,69.86 101.18,69.65 100.89,69.36 100.89,69.18 101.07,69 101.25,69 101.56,69.31 101.74,69.31 101.94,69.11 101.94,68.93 101.78,68.77 v2(101.78,68.69) 102.03,68.43 PU500.1
  IN2 w0.102: v2(127.05,66.76) 127.05,68 124.52,70.54 110.03,70.54 107.72,72.85 104.57,72.85 101.78,70.06 v2(101.78,68.69)
  BOTTOM w0.102: UC1.L63 131.21,67.08 130.52,67.77 129.31,67.77 128.97,67.42 RC208.2 128.23,67.03 127.32,67.03 v2(127.05,66.76)
VR_HOT#: length 2.6
  TOP w0.102: PR534.1 103.29,70.84 103.46,70.66 103.61,70.66 v1(104.11,70.15) 104.11,69.78 103.95,69.61 PU500.30
VREF: length 28.2
  TOP w0.203: PU500.27 105.15,69.71 105.93,70.48 v2(106.21,70.48)
  TOP w0.254: PR521.2 107.38,70.77 106.99,71.17 PC507.1 106.54,70.81 v2(106.21,70.48)
  IN2 w0.254: v2(100.97,59.63) v2(100.97,61.56) 101.17,61.76 101.17,64.59 102.46,65.89 102.46,68.38 103.11,69.02 104.75,69.02 v2(106.21,70.48)
  BOTTOM w0.102: v2(106.21,70.48) 106.06,70.48 v1(105.62,70.05)
  BOTTOM w0.254: PH500.1 100.97,59.46 v2(100.97,59.63) ; PR500.1 106.6,61.43 105.99,60.82 103.18,60.82 102.6,61.41 PR502.1 PR503.1 PR504.1 100.82,61.72 v2(100.97,61.56)
VSET_5085: length 3.2
  TOP w0.102: RE77.1 CE38.1 251.54,45.97 v1(252.42,45.97) 252.66,46.21 UE2.A17
WIGIG_32KHZ: length 15.9
  TOP w0.102: v2(245.12,32.98) 245.12,32.66 245.2,32.59 RZ56.2 244.29,31.43 RZ57.2
  BOTTOM w0.102: JNGFF1.42 241.71,21.6 241.96,21.84 241.96,24.1 242.5,24.65 242.5,28.47 243.19,29.16 243.69,29.16 244.96,30.43 v1(244.96,32.07) 244.96,32.82 v2(245.12,32.98)
WIGIG_32KHZ_R: length 4.3
  TOP w0.102: RZ57.1 245.67,31.9 UZ11.4 246.2,32.32 245.58,32.94 v1(245.58,34.75)
WIGIG_AUX: length 55.6
  TOP w0.102: v2(231.79,37.38) 232,37.17 232.42,37.17 232.82,36.77 232.82,33.29 CV149.1
  BOTTOM w0.102: v2(231.79,37.38) 231.98,37.2 232.27,37.2 232.47,37.4 232.47,42.03 231.95,42.55 231.95,45.76 236.76,50.57 236.76,74.9 234.1,77.57 233.02,77.57 RV514.2 232.08,77.6 231.86,77.6 231.62,77.84 231.62,79.11 231.13,79.6 230.74,79.6 230.65,79.51 UV7.55
WIGIG_AUX#: length 55.9
  TOP w0.102: CV150.1 232.6,33.29 232.6,36.68 232.33,36.96 231.95,36.96 v2(231.79,36.8)
  BOTTOM w0.102: UV7.54 230.63,79.91 230.72,79.81 231.22,79.81 231.84,79.2 231.84,77.93 231.98,77.79 232.13,77.79 232.56,78.22 RV515.2 233.02,77.79 234.19,77.79 236.98,74.99 236.98,50.48 232.17,45.67 232.17,42.64 232.69,42.12 232.69,37.31 232.36,36.98 231.98,36.98 v2(231.79,36.8)
WIGIG_AUX#_C: length 11.1
  TOP w0.102: CV150.2 232.52,31.78 232.52,31.47 v2(232.34,31.29)
  BOTTOM w0.102: JNGFF1.12 239.72,29.1 236.89,31.93 232.72,31.93 232.47,31.67 232.47,31.42 v2(232.34,31.29)
WIGIG_AUX_C: length 11
  TOP w0.102: v2(232.93,31.29) 232.74,31.48 232.74,31.71 233.06,32.04 CV149.2
  BOTTOM w0.102: v2(232.93,31.29) 232.69,31.53 232.69,31.58 232.81,31.71 236.8,31.71 239.63,28.88 239.88,28.88 240.17,28.6 JNGFF1.14
WIGIG_HPD: length 95.9
  IN1 w0.102: v2(247.37,61.9) 245.58,63.69 242.83,63.69 237.38,69.14 237.38,76.19 234.21,79.36 233.96,79.36 232.74,80.58 232.74,81.38 231.47,82.65 231.14,82.65 228.15,85.65 225.74,85.65 v2(224.93,86.46)
  IN2 w0.102: v2(234.83,61.89) 234.85,61.9 v2(247.37,61.9)
  BOTTOM w0.102: JNGFF1.23 232.2,26.35 v1(231.28,25.42) 231.06,25.42 230.58,24.94 229.83,24.94 229.47,25.3 229.47,26.53 230.43,27.48 230.43,32.18 231.07,32.83 231.07,39.51 231.34,39.78 231.34,46.03 236.07,50.76 236.07,61.19 235.37,61.89 v2(234.83,61.89) ; UV7.32 225.22,85.72 225.12,85.82 225.12,86.27 v2(224.93,86.46)
WIGIG_LANE_N0: length 78.5
  TOP w0.102: CV156.1 238.95,28.56 238.95,29.25 238.96,29.26 238.96,29.92 238.95,29.93 238.95,30.18 237.72,31.41 237.72,33.57 237.06,34.23 237.06,41.69 236.2,42.54 234.93,42.54 v2(234.92,42.54)
  BOTTOM w0.102: v2(234.92,42.54) 234.75,42.37 233.61,42.37 233.23,42.74 233.23,45.56 237.8,50.13 237.8,75.45 235.98,77.28 235.98,83.37 235.06,84.29 235.06,88.43 233.66,89.83 230.07,89.83 228.02,87.77 UV7.39
WIGIG_LANE_N0_C: length 8.1
  TOP w0.102: CV156.2 238.97,27.4 238.76,27.19 238.76,26.76 238.26,26.26 238.26,26.24 237.83,25.8 237.8,25.8 237.18,25.18 237.18,25.01 237.45,24.74 237.63,24.74 238.84,25.95 239.27,25.95 239.45,26.13 v2(239.45,26.22)
  BOTTOM w0.102: v2(239.45,26.22) 239.45,26.16 239.72,25.89 239.93,25.89 240.13,26.1 JNGFF1.24
WIGIG_LANE_N1: length 78.5
  TOP w0.102: v2(234.07,43.3) 233.95,43.42 233.77,43.42 233.63,43.28 233.63,42.35 234.63,41.35 235.07,41.35 236.23,40.19 236.23,33.83 236.89,33.17 v3(236.89,32.16) 236.89,31.05 237.41,30.53 CV152.1
  BOTTOM w0.102: UV7.36 226.82,86.01 226.77,86.05 226.77,87.71 229.71,90.65 234.01,90.65 235.89,88.77 235.89,84.7 236.81,83.77 236.81,77.61 238.85,75.58 238.85,49.88 234.87,45.91 234.87,43.67 234.55,43.36 234.12,43.36 v2(234.07,43.3)
WIGIG_LANE_N1_C: length 8
  TOP w0.102: v2(237.54,27.68) 237.52,27.68 237.26,27.42 237.16,27.42 237,27.58 237,28.6 237.27,28.86 CV152.2
  BOTTOM w0.102: v2(237.54,27.68) 237.54,27.56 237.6,27.5 237.71,27.5 237.83,27.38 237.94,27.38 238.11,27.55 238.11,28.46 238.36,28.71 238.9,28.71 239.15,28.46 239.15,27.61 239.37,27.39 239.96,27.39 240.17,27.6 JNGFF1.18
WIGIG_LANE_N2: length 78.5
  TOP w0.102: v2(234.92,39.97) 234.4,39.97 234.21,39.79 234.21,38.9 234.45,38.66 234.92,38.66 235.39,38.19 235.39,33.49 235.89,33 CV147.1
  BOTTOM w0.102: v2(234.92,39.97) 234.99,40.04 235.4,40.04 235.7,40.33 235.7,45.57 239.75,49.62 239.75,75.84 237.64,77.95 237.64,84.11 236.71,85.04 236.71,89.26 234.47,91.5 229.4,91.5 225.52,87.63 225.52,86.1 225.62,86.01 UV7.33
WIGIG_LANE_N2_C: length 7.8
  TOP w0.102: v2(236.16,27.93) 235.92,27.7 235.66,27.7 235.52,27.84 235.52,28.19 235.91,28.58 235.91,29.62 v3(235.58,29.95) 235.42,30.11 235.42,30.62 CV147.2
  BOTTOM w0.102: v2(236.16,27.93) 236.16,27.87 236.04,27.75 235.99,27.75 235.86,27.62 235.4,27.62 235.26,27.76 234.69,27.76 234.55,27.62 234.36,27.62 234.13,27.85 234.13,27.85 233.44,27.85 JNGFF1.17
WIGIG_LANE_N3: length 78.7
  TOP w0.102: CV145.1 234.31,35.03 234.31,35.52 234.51,35.72 v2(234.51,36.98)
  BOTTOM w0.102: UV7.30 224.42,85.96 224.28,86.09 224.28,87.65 228.95,92.33 234.95,92.33 237.54,89.74 237.54,85.38 238.46,84.46 238.46,78.29 240.62,76.13 240.62,49.33 236.54,45.24 236.54,39.47 236.27,39.2 234.67,39.2 234.51,39.04 v2(234.51,36.98)
WIGIG_LANE_N3_C: length 7.9
  TOP w0.102: CV145.2 234.4,33.88 234.16,33.64 234.16,31.46 233.97,31.27 233.88,31.27 233.75,31.14 233.75,30.94 233.88,30.81 233.97,30.81 234.16,30.62 v3(234.16,30.17) 234.16,29.48 234.52,29.12 234.72,29.12 234.93,29.33 v2(234.93,29.35)
  BOTTOM w0.102: v2(234.93,29.35) 234.7,29.12 234.3,29.12 234.07,29.35 233.34,29.35 JNGFF1.11
WIGIG_LANE_P0: length 78.4
  TOP w0.102: v2(234.92,41.95) 235.3,42.33 236.12,42.33 236.84,41.6 236.84,34.14 237.5,33.48 237.5,31.32 238.73,30.09 v3(238.73,29.63) 238.73,28.28 238.64,28.19 238.42,28.19 CV157.1
  BOTTOM w0.102: UV7.40 228.42,85.68 228.23,85.86 228.23,87.68 230.16,89.61 233.58,89.61 234.85,88.34 234.85,84.2 235.76,83.29 235.76,77.19 237.59,75.36 237.59,50.22 233.02,45.65 233.02,42.65 233.52,42.15 234.73,42.15 v2(234.92,41.95)
WIGIG_LANE_P0_C: length 8
  TOP w0.102: CV157.2 238.54,27.16 238.54,26.85 v3(237.87,26.18) 237.65,25.96 236.97,25.27 236.97,24.92 237.36,24.52 237.72,24.52 238.93,25.73 239.31,25.73 v2(239.45,25.59)
  BOTTOM w0.102: v2(239.45,25.59) 239.54,25.68 239.94,25.68 240.02,25.6 JNGFF1.26
WIGIG_LANE_P1: length 78.5
  TOP w0.102: v2(234.07,43.89) 233.82,43.64 233.68,43.64 233.41,43.37 233.41,42.26 234.54,41.13 234.98,41.13 236.01,40.11 236.01,33.74 236.67,33.08 236.67,32.56 236.66,32.55 236.66,31.75 236.67,31.74 236.67,30.96 237.19,30.44 237.19,30.3 237.12,30.23 236.69,30.23 236.52,30.06 CV153.1
  BOTTOM w0.102: v2(234.07,43.89) 234.38,43.57 234.46,43.57 234.66,43.76 234.66,46 238.63,49.97 238.63,75.49 236.6,77.52 236.6,83.68 235.67,84.61 235.67,88.68 233.92,90.44 229.8,90.44 226.98,87.62 226.98,86.14 227.03,86.1 227.03,85.84 227.22,85.66 UV7.37
WIGIG_LANE_P1_C: length 7.9
  TOP w0.102: v2(237.54,27.09) 237.43,27.2 237.07,27.2 236.79,27.49 236.79,28.59 CV153.2
  BOTTOM w0.102: JNGFF1.20 240.12,27.1 240.04,27.18 239.28,27.18 238.94,27.52 238.94,28.37 238.81,28.5 238.45,28.5 238.33,28.37 238.33,27.46 238.03,27.16 237.61,27.16 v2(237.54,27.09)
WIGIG_LANE_P2: length 78.5
  TOP w0.102: v2(234.92,40.56) 234.55,40.19 234.31,40.19 233.99,39.88 233.99,38.81 234.36,38.44 234.83,38.44 235.18,38.1 235.18,33.39 v3(235.49,33.07) 235.67,32.89 235.67,32.52 235.58,32.44 235.43,32.44 CV148.1
  BOTTOM w0.102: v2(234.92,40.56) 235.06,40.42 235.13,40.35 235.22,40.26 235.31,40.26 235.48,40.42 235.48,45.66 239.53,49.71 239.53,75.75 237.42,77.86 237.42,84.02 236.5,84.95 236.5,89.17 234.38,91.29 229.49,91.29 225.74,87.54 225.74,86.19 225.83,86.1 225.83,85.91 226.02,85.72 UV7.34
WIGIG_LANE_P2_C: length 7.8
  TOP w0.102: v2(236.16,27.35) 236.02,27.48 235.57,27.48 235.3,27.75 235.3,28.28 235.7,28.67 235.7,29.51 235.2,30 235.2,30.88 CV148.2
  BOTTOM w0.102: v2(236.16,27.35) 236.1,27.41 235.31,27.41 235.18,27.55 234.78,27.55 234.64,27.41 234.22,27.41 234.17,27.35 JNGFF1.19
WIGIG_LANE_P3: length 78.6
  TOP w0.102: v2(233.93,36.98) 234.29,36.61 234.29,35.81 234.1,35.61 234.1,34.9 233.99,34.79 CV146.1
  BOTTOM w0.102: UV7.31 224.82,85.66 224.63,85.84 224.63,86.05 224.5,86.18 224.5,87.57 229.04,92.11 234.86,92.11 237.32,89.65 237.32,85.29 238.25,84.37 238.25,78.2 240.41,76.04 240.41,49.42 236.32,45.33 236.32,39.56 236.18,39.42 234.58,39.42 234.29,39.13 234.29,37.35 v2(233.93,36.98)
WIGIG_LANE_P3_C: length 8
  TOP w0.102: v2(234.93,28.77) 234.8,28.9 234.43,28.9 233.94,29.39 233.94,29.9 233.93,29.91 233.93,30.44 233.94,30.45 233.94,30.53 233.88,30.59 233.79,30.59 233.53,30.85 233.53,31.23 233.79,31.48 233.88,31.48 233.94,31.55 233.94,33.6 CV146.2
  BOTTOM w0.102: v2(234.93,28.77) 234.8,28.9 234.21,28.9 234.16,28.85 233.34,28.85 JNGFF1.13
WIGIGCLK_REQ#: length 174.3
  TOP w0.076: v2(168.35,64.78) 168.42,64.72 v1(170.63,64.72) 171.17,65.26 173.31,65.26 173.36,65.21
  TOP w0.102: 173.36,65.21 173.64,64.92 174.47,64.92 174.58,65.03 179.6,65.03 179.64,65.07 RPC9.7
  IN1 w0.102: v2(245.17,60.1) 244.75,60.51 244.75,61 244.4,61.35 241.47,61.35 235.14,67.68 235.14,73.84 232.54,76.44 230.97,76.44 229.42,77.99 218.17,77.99 214.98,74.8 197.8,74.8 192.97,79.62 192.97,80.34 192.77,80.54 192.77,80.56 191.34,81.99 191.34,82.35 189.8,83.88 189.8,84.46 188.44,85.83 175.77,85.83 170.86,80.92 170.86,77.27 169.86,76.27 169.86,71.16 170.41,70.61 170.41,68.63 170.05,68.27 170.05,67.26 170.63,66.67 170.63,65.4 170.01,64.78 v2(168.35,64.78)
  BOTTOM w0.076: UC1.U5 168.15,64.58 v2(168.35,64.78)
  BOTTOM w0.102: JNGFF1.60 243.83,17.1 244.31,17.58 244.31,22.81 246.49,25 246.49,35.04 246.16,35.37 246.16,40.7 245.37,41.49 245.37,47.02 244.71,47.68 244.71,57.71 245.17,58.17 v2(245.17,60.1)
WIRELESS_LED#: length 97.3
  TOP w0.102: QZ7.1 288.19,81.12 287.69,80.62 RZ31.2 287.69,79.22 285.16,76.69 279.75,76.69 274.05,70.99 274.05,62.69 275.63,61.11 275.63,57.67 274.42,56.46 v2(274,56.46) ; v2(245.88,57.49) 245.6,57.21 245.6,55.74 244.71,54.85 244.71,46.79 244.98,46.52 244.98,43.24 245.87,42.35 245.87,40.4 246.3,39.97 246.3,38.89 v1(245.96,38.54) 245.66,38.24 242.58,38.24 242.35,38 QZ2.6 242.35,36.52 v2(242.41,36.46) ; UE3.16 254.44,61.34 254.16,61.06 254.16,58.62 v2(254.3,58.48) ; v2(243.57,36.47) 243.57,36.22 243.65,36.14 QZ2.3
  IN1 w0.102: v2(242.41,36.46) 243.56,36.46 v2(243.57,36.47)
  IN2 w0.102: v2(245.88,57.49) 246.59,58.2 254.02,58.2 v2(254.3,58.48) 254.34,58.52 262,58.52 263.02,57.51 268.97,57.51 269.43,57.05 271.56,57.05 271.93,57.42 273.06,57.42 274,56.48 v2(274,56.46)
WLAN_DISBL#: length 43.3
  TOP w0.102: UE3.13 252.94,61.33 v2(252.79,61.19) ; v2(269.52,61.37) 269,61.89 269,63.55 269.43,63.98 269.43,65.68 263.61,71.5 v1(263.61,73.76) 263.61,82.33 263.49,82.45 UL2.4
  IN2 w0.102: v2(252.79,61.19) 253.59,61.99 268.89,61.99 v2(269.52,61.37)
WLAN_LED: length 92
  TOP w0.102: v2(283.87,80.39) 284.08,80.6 QZ9.3 ; JLED1.6 268.65,10.45 269,10.11 274.37,10.11 276.6,12.34 276.6,13.98 277.47,14.85 v4(277.47,17.12) 277.47,21.04 275.52,22.98 275.52,24.05 273.8,25.78 273.8,26.27 272.23,27.83 272.23,32.21 272.88,32.86 272.88,35.44 275.97,38.52 275.97,44.75 271.85,48.86 271.85,52.59 269.96,54.48 269.96,58.23 268.74,59.45 268.74,64.75 v2(268.96,64.97)
  IN1 w0.102: v2(283.87,80.39) 283.87,80 281.34,77.47 281.34,77.45 269.36,65.47 269.36,65.36 v2(268.96,64.97)
WLAN_LED#: length 7.1
  TOP w0.102: v1(240.47,35.62) v2(240.47,35) 240.77,34.7 241.57,34.7 RZ14.1 241.59,35.4 241.98,35.8 QZ2.1
  BOTTOM w0.102: JNGFF1.6 240.05,32.6 239.76,32.89 239.76,34.28 v2(240.47,35)
WLAN_LED_Q#: length 3.1
  TOP w0.102: v1(286.61,79.63) 286.31,79.93 286.31,80.74 QZ7.6 286.02,81.12 285.94,81.2 QZ9.2
WLAN_WIGIG60GHZ_DIS#: length 51.3
  TOP w0.102: RE8.2 v2(254.89,61.21) 254.94,61.26 UE3.17 ; DZ1.1 240.58,28.37 240.04,28.92 240.04,30.39 238.78,31.65 238.78,32.84 239.85,33.91 239.85,36.54 242.02,38.71 245.19,38.71 245.19,38.71 245.36,38.71 245.36,38.71 245.89,39.24 245.89,39.8 245.42,40.27 245.42,41.9 244.57,42.75 244.57,46.11 243.56,47.13 243.56,51.09 244.15,51.69 244.15,55.12 v4(245.01,55.97) 245.01,59.08 v2(245.69,59.77)
  IN2 w0.102: v2(254.89,61.21) 254.26,61.21 253.16,60.11 246.03,60.11 v2(245.69,59.77)
WLAN_WIGIG60GHZ_DIS#_R: length 11.9
  TOP w0.102: DZ1.2 242.59,27.44 v1(243.2,27.44) 243.21,27.44 243.59,27.82 v2(243.59,28.02)
  BOTTOM w0.102: JNGFF1.48 242,20.1 242.77,20.87 242.77,23.71 243.34,24.28 243.34,27.78 v2(243.59,28.02)
WLANCLK_REQ#: length 153
  IN1 w0.102: v2(235.66,60.72) 235.28,60.72 234.18,61.82 234.18,62.81 233.75,63.24 233.75,73.56 232.12,75.2 217.31,75.2 215.54,73.43 197.23,73.43 191.58,79.08 191.58,79.79 189.96,81.4 189.96,81.78 187.3,84.44 179.81,84.44 179.15,83.78 176.06,83.78 172.48,80.19 172.48,76.4 171.15,75.07 171.15,71.58 172.55,70.18 172.55,69.25 173.09,68.72 173.09,67.28 v2(172.84,67.03)
  BOTTOM w0.076: v2(172.84,67.03) 172.48,67.39 172.08,67.39 171.85,67.16 171.85,66.84 171.3,66.29 UC1.N1
  BOTTOM w0.102: RPC17.6 176.34,67.68 175.99,67.33 173.36,67.33 173.06,67.03 v2(172.84,67.03) ; v2(235.66,60.72) 235.66,50.64 231.1,46.08 231.1,40 228.74,37.64 228.74,35.02 227.62,33.9 227.62,27.95 227.16,27.49 227.16,23.85 230.16,20.85 232.19,20.85 JNGFF1.45
XDP_DBRESET#: length 173.2
  TOP w0.102: JXDP1.48 85.72,49.2 85.85,49.07 CC21.1 RC122.2 86.68,47.7 88.83,47.7 90.62,45.91 v1(90.62,43.7) 90.1,43.18 90.1,39 88.78,37.68 v2(87.28,37.68) ; UC4.1 185.23,74.16 185.4,74.33 186.14,74.33 186.53,73.94 RC77.1 186.03,73.53 v2(185.84,73.72)
  BOTTOM w0.102: v2(185.84,73.72) 185.37,73.25 185.37,70.85 185.67,70.55 185.67,63.79 187,62.46 187,53.06 187.49,52.58 187.49,51.82 188.66,50.64 188.66,49.74 190.61,47.79 190.61,36 186.99,32.38 180.68,32.38 179.13,33.93 179.13,35.05 178.17,36 172.67,36 170.88,34.21 156.39,34.21 154.61,32.44 92.52,32.44 v2(87.28,37.68)
XDP_OBS0_R: length 86.2
  TOP w0.102: JXDP1.21 79.93,55.7 v2(80.44,55.19)
  IN2 w0.102: v2(134.43,68.88) 134.43,69.24 133.75,69.91 133.11,69.91 132.53,70.48 132.53,72.26 129.02,75.78 129.02,77.54 127.89,78.67 127.89,79.61 125.93,81.56 124.34,81.56 123.18,82.71 107.17,82.71 103.59,79.13 100.32,79.13 94.88,73.69 94.88,61.69 93.24,60.06 93.24,57.8 92.65,57.21 92.65,56.02 91.61,54.97 86.17,54.97 85.95,55.19 v2(80.44,55.19)
  BOTTOM w0.076: UC1.J60 134.11,68.56 v2(134.43,68.88)
XDP_OBS1_R: length 85.6
  TOP w0.102: JXDP1.23 v2(79.69,55.2)
  IN2 w0.102: v2(133.81,68.95) 133.81,69.21 133.55,69.47 132.97,69.47 132.18,70.26 132.18,72.1 130.68,73.6 130.48,73.6 128.54,75.54 128.54,77.34 127.4,78.47 127.4,79.41 125.73,81.08 124.14,81.08 122.98,82.23 107.31,82.23 103.78,78.7 100.46,78.7 95.28,73.52 95.28,61.52 93.65,59.89 93.65,57.63 93.13,57.12 93.13,55.82 91.88,54.56 85.95,54.56 85.68,54.29 80.6,54.29 v2(79.69,55.2)
  BOTTOM w0.076: UC1.H60 133.81,69.06 v2(133.81,68.95)
XDP_OBS2_R: length 5.6
  BOTTOM w0.076: UC1.H61 133.2,69.62 132.68,69.62 132.48,69.41 132.48,69.24 132.29,69.04 132.28,69.04 132.27,69.04 132.04,69.04 131.81,69.27 131.23,69.27 129.72,70.79 129.6,70.79
  BOTTOM w0.102: T10.1 129.36,71.03 129.6,70.79
XDP_OBS3_R: length 6
  BOTTOM w0.076: 129.6,70.54 131.05,69.09 131.74,69.09 131.82,69.01 131.82,69.01 131.91,68.92 131.92,68.92 131.95,68.88 131.97,68.88 131.97,68.88 132.34,68.88 132.34,68.88 132.35,68.88 132.35,68.88 132.36,68.88 UC1.H62
  BOTTOM w0.102: T11.1 127.82,70.59 129.55,70.59 129.6,70.54
XDP_OBS4_R: length 1.1
  TOP w0.076: T12.1 135.17,68.21 v2(135.17,68.22)
  BOTTOM w0.076: v2(135.17,68.22) 134.81,67.86 UC1.K59
XDP_OBS5_R: length 6
  BOTTOM w0.076: 129.6,71.26 131.4,69.46 132.02,69.46 UC1.H63
  BOTTOM w0.102: T13.1 128,72.44 128.28,72.16 128.28,71.64 128.46,71.46 129.4,71.46 129.6,71.26
XDP_OBS6_R: length 1.1
  TOP w0.076: v2(133.8,67.44) 133.8,67.43 T14.1
  BOTTOM w0.076: v2(133.8,67.44) 134.11,67.74 UC1.K60
XDP_OBS7_R: length 1.4
  TOP w0.076: T15.1 132.92,69.19 v2(133.16,68.95)
  BOTTOM w0.076: UC1.J61 133.46,68.65 v2(133.16,68.95)
XDP_RST#_R: length 2.5
  TOP w0.102: RC106.2 85.88,49.7 JXDP1.46
XTAL24_IN: length 12.5
  BOTTOM w0.102: YC2.3 154.42,83.04 154.42,81.53 RC63.2 154.24,80.66 CC8.2 154.57,79.72 154.57,79.19 156.71,77.05 v1(156.71,76.09) 156.71,74.97 156.07,74.33 UC1.A25
XTAL24_OUT: length 9.6
  BOTTOM w0.102: UC1.B25 156.07,73 156.5,73.43 156.5,74.19 157.19,74.89 157.19,77.29 v1(156.18,78.3) 155.17,79.31 RC65.1 155.17,80.65 RC63.1
XTAL24_OUT_R: length 2.4
  BOTTOM w0.102: RC65.2 155.74,80.4 CC11.2 155.67,81.08 YC2.1
XTALI: length 7.2
  TOP w0.102: YL1.1 250.22,80.48 250.36,80.63 250.36,82.1 CL14.2 RL11.2 251.43,84.09 v1(251.9,84.09) 252.16,84.09 252.26,84.19 252.99,84.19 253.19,84.39 UL1.10
XTALO: length 3.9
  TOP w0.102: RL10.2 250.5,84.44 250.51,84.45 RL11.1 252.85,84.45 253.19,84.79 UL1.9
XTALO_R: length 2.9
  TOP w0.102: RL10.1 CL13.2 247.69,84.03 YL1.3
Z2805: length 2.2
  TOP w0.508: RL18.1 v2(276.88,89.43)
  BOTTOM w0.508: TL1.22 v2(276.88,89.43)
Z2806: length 2.2
  TOP w0.508: RL16.1 v2(269.26,89.45)
  BOTTOM w0.508: TL1.16 v2(269.26,89.45)
Z2807: length 2.2
  TOP w0.508: RL17.1 v2(275.61,89.45)
  BOTTOM w0.508: TL1.21 v2(275.61,89.45)
Z2808: length 2.2
  TOP w0.508: RL15.1 v2(267.99,89.45)
  BOTTOM w0.508: TL1.15 v2(267.99,89.45)
N15115: length 5.5
  TOP w0.102: T16.1 173.67,60.59 169.82,60.59 v2(169.15,59.92)
  BOTTOM w0.076: UC1.AD4 168.83,60.23 v2(169.15,59.92)
N19253: length 6.5
  BOTTOM w0.102: T28.1 128.58,47.43 131.63,50.48 131.63,51.73 132.08,52.17 UC1.AV63
N19255: length 5.3
  BOTTOM w0.081: 131.02,51.54 131.02,51.76 132.09,52.83 UC1.AU63
  BOTTOM w0.102: T29.1 129.42,49.86 129.83,49.86 131.02,51.06 131.02,51.54
N19263: length 4.4
  BOTTOM w0.102: T30.1 130.05,74.45 131.43,73.06 131.43,72.62 131.86,72.19 UC1.C63
N19267: length 5.7
  BOTTOM w0.076: 131.91,72.52 132.41,72.52 UC1.C62
  BOTTOM w0.102: 131.91,72.52 131.76,72.67 131.76,73.18 T31.1
N19275: length 3.2
  BOTTOM w0.102: T33.1 140.65,76.19 140.65,74.47 140.12,73.94 140.12,73.73 UC1.A51
N19277: length 5.2
  BOTTOM w0.102: UC1.B51 140.31,73.27 140.31,73.86 140.85,74.41 140.85,75.91 141.21,76.26 141.21,76.58 T34.1
N19281: length 4.8
  BOTTOM w0.076: UC1.L60 133.79,66.73 132.81,66.73 132.52,66.44 132.52,66.27 132.26,66 T35.1
N21871: length 6
  BOTTOM w0.076: UC1.P60 134.11,65.52 133.8,65.22 133.37,65.22 133.27,65.12 132.05,65.12 131.91,64.99 131.21,64.99 130.81,65.39 129.42,65.39
  BOTTOM w0.102: T74.1 129.34,65.35 129.38,65.39 129.42,65.39
N21873: length 7.8
  BOTTOM w0.076: UC1.P61 133.2,65.28 131.91,65.28 131.81,65.18 131.34,65.18 130.86,65.66 129.35,65.66
  BOTTOM w0.102: 129.35,65.66 128.07,65.66 127.48,65.07 T75.1
N21875: length 1.1
  TOP w0.076: T76.1 135.53,66.4 v2(135.19,66.74)
  BOTTOM w0.076: v2(135.19,66.74) 134.82,66.36 UC1.N59
N21877: length 1.2
  TOP w0.076: v2(133.75,65.96) 134.11,65.6 T77.1
  BOTTOM w0.076: UC1.N61 133.75,66.07 v2(133.75,65.96)
N33048: length 2.2
  TOP w0.127: v1(202.73,11.1) 203.2,11.57 RD21.1
  TOP w0.508: RD21.1 CD36.2
N33050: length 3.1
  TOP w0.102: RD25.1 158.89,16.36 158.42,16.84 v1(157.06,16.84)
  TOP w0.508: RD25.1 CD54.2
N40459: length 2.1
  BOTTOM w0.102: QV2.1 109.79,98.07 109.87,98.15 RV5.2 v1(110.25,99.1)
N43975: length 3.9
  BOTTOM w0.102: RN2.2 276.92,13.11 277.18,12.86 QN1.6 ; RN2.2 QN1.5 ; RN2.2 277.24,13.83 v1(277.49,13.83)
N70745: length 20.3
  TOP w0.102: v1(271.38,46.24) 271.38,45.69 v2(271.59,45.49) 271.98,45.1 271.98,42.34 271.29,41.66 270.65,41.66 270.1,42.2 RE64.1 ; v2(262.88,42.97) 262.88,42.96 UE2.B61
  IN2 w0.102: v2(271.59,45.49) 271.59,46.61 269.92,48.27 267.51,48.27 266.74,47.5 266.74,46.82 262.88,42.97 v2(262.88,42.97)
N70747: length 2.5
  TOP w0.102: v1(248.42,38) 248.74,38 CE34.1 249.83,39.09 RE66.2
N70757: length 6
  TOP w0.102: RE57.1 270.09,43.17 RE58.1 269.15,43.16 268.65,43.16 268.28,43.53 266.39,43.53 266.27,43.65 v1(265.71,43.65) 265.64,43.71 UE2.A59
N73962: length 1.6
  TOP w0.102: UZ9.12 217.49,40.16 217.53,40.11 CZ45.1
N73964: length 1.6
  TOP w0.102: UZ9.10 216.69,40.29 216.58,40.18 CZ46.1
N75571: length 9.5
  TOP w0.102: QZ3.1 272.2,19.1 272.46,19.37 272.46,20.76 271.84,21.39 271.84,22.58 DZ3.2 DZ4.2 271.46,24.19 RZ24.2 272.53,25.55 271.6,26.48 v4(271.37,26.48)
N75595: length 4.2
  TOP w0.102: QZ3.3 271.39,17.8 271.12,18.07 271.12,19.98 v4(271.46,20.32) DZ3.1
N5261056: length 105.2
  TOP w0.102: v2(201.06,6.59) 200.85,6.59 200.6,6.84 RD13.1 RD12.1 ; RD10.1 RD11.1 118.98,9.74 119.35,10.11 119.97,10.11 120.2,9.88 120.2,8.74 120.84,8.11 140.89,8.11 v4(141.45,7.55) 141.86,7.14 153.44,7.14 v2(154.08,7.77) 154.08,9.96 156.5,12.38 156.5,19.48 155.06,20.92 QD1.3
  IN2 w0.102: v2(201.06,6.59) 201.06,6.61 200.63,7.04 157.03,7.04 156.3,7.77 v2(154.08,7.77)
N10757881: length 2.4
  TOP w0.102: v1(80.9,18.94) 80.82,18.94 RD7.1
  TOP w0.508: RD7.1 79.94,17.83 79.54,17.42 CD21.2
N18279753: length 17.8
  TOP w0.254: PD5.3 PD5.2 ; PD5.2 61.93,105.24 PL3.1 ; PD5.2 67.79,105.24 68.88,104.15 PQ2.1 69.52,102.81 70.27,103.56 v4(71.52,103.56) 73.02,103.56 v2(73.31,103.85)
  BOTTOM w0.254: v2(73.31,103.85) PR10.2 PR7.1
N18279759: length 8.4
  TOP w0.254: v2(74.28,101.64) 74.28,100.63 v4(74.29,100.62) 74.29,100.1 73.9,99.71 70.08,99.71 69.85,99.94 PQ2.3
  BOTTOM w0.254: PR9.1 74.27,101.62 v2(74.28,101.64) 74.27,101.65 PR7.2
N18279771: length 5.7
  TOP w0.102: v2(71.74,101.66) 72.69,101.66 73.56,102.53 v4(73.56,103.05)
  TOP w0.254: PQ3.2 71.75,101.65 v2(71.74,101.66)
  BOTTOM w0.254: v2(71.74,101.66) 71.74,101.69 PR12.2 72.39,102.31 PR10.1
N18279775: length 9.3
  TOP w0.102: v4(65.05,102.55) 65.67,102.55 PR11.2
  TOP w0.254: PQ3.1 70.09,102.47 68.34,100.72 PQ2.2 67.92,101.51 67.59,101.84 PR11.2
N18281287: length 2.6
  TOP w0.203: PR104.1 PR101.1 217.88,46.7 PU100.2
N18281336: length 2.6
  TOP w0.203: PR102.2 PR100.2 218.68,46.72 PU100.4
N18281357: length 2.2
  TOP w0.203: PU100.19 216.25,49.11 215.31,48.18 PR114.1
N18281599: length 3
  TOP w0.203: PR105.2 220.77,46.84 220.52,47.1 219.31,47.1 219.08,47.33 PU100.5
N18281901: length 2.8
  TOP w0.203: PU100.1 217.48,47.37 217.22,47.1 216.41,47.1 215.82,46.51 PR106.2
N18284921: length 3.6
  TOP w0.102: PR210.2 70.41,9.18 v1(69.4,9.18) v2(68.96,8.74)
  BOTTOM w0.203: PU200.7 68.01,9.04 68.01,8.58 68.23,8.36 68.58,8.36 v2(68.96,8.74)
N18284982: length 2.6
  TOP w0.102: PR204.1 62.63,8.99 62.1,8.46 62.1,7.98 v1(61.26,7.14)
  vias: v2(64.96,9.91)
N18285023: length 3.2
  BOTTOM w0.102: PR206.2 66.69,6.73 v1(66.23,6.27)
  BOTTOM w0.203: PR206.2 67.21,7.93 PU200.9
N18287240: length 3
  BOTTOM w0.102: PC309.1 206.68,63.63 v1(206.83,63.78)
  BOTTOM w0.254: PU300.5 205.6,61.81 205.69,61.9 206.14,61.9 206.68,62.43 PC309.1
N18287762: length 4.8
  BOTTOM w0.102: v1(117.5,72.16) PC402.1
  BOTTOM w0.254: PR400.2 115.62,73.05 PR401.1 ; PR401.1 115.48,72.17 114.6,71.29 PU400.8 ; PR401.1 115.63,72.16 PC402.1
N18287796: length 4.6
  BOTTOM w0.102: PC403.2 106.28,72.46 v1(106.08,72.26)
  BOTTOM w0.254: PC403.2 PR402.2 PR403.1 107.52,72.26 107.83,72.56 PU400.2
N18289928: length 5.6
  TOP w0.102: PR513.1 99.67,65.24 98.36,65.24 v1(97.98,64.86)
  TOP w0.203: PU500.4 102.06,67.23 101.72,66.9 101.18,66.9 100.82,66.55 100.82,66.39 PR513.1
N18289956: length 5.8
  TOP w0.102: v1(98.07,67.06) 99.67,67.06 PR539.1
  TOP w0.203: PU500.3 101.97,67.63 101.66,67.32 100.33,67.32 PR516.1 PR539.1
N18289962: length 7.4
  TOP w0.102: v1(110.69,71.84) 109.83,71.84 PR535.1
  TOP w0.203: PU500.25 105.95,69.43 106.03,69.51 107.94,69.51 108.19,69.26 109.03,69.26 PC506.1 PR523.1 109.53,71.52 PR535.1
N18289987: length 8.5
  TOP w0.102: PR521.1 v1(107.68,73.68)
  TOP w0.203: PC512.2 108.62,71.39 PR523.2 PC506.2 108.22,69.77 108.09,69.9 105.9,69.9 105.55,69.54 PU500.26
  TOP w0.254: PC512.2 107.83,71.53 PR521.1
N18290013: length 2.6
  TOP w0.102: v1(104.77,73.88) 104.63,73.74 104.63,71.34
N18290066: length 2.2
  TOP w0.102: PH501.2 109.24,54.01 v1(109.18,54.08)
  TOP w0.254: PH501.2 PR515.1
N18290144: length 12.4
  TOP w0.102: v1(105.66,62.27) 105.66,63.6 105.71,63.65 v2(105.71,63.67)
  TOP w0.203: PU500.14 105.15,64.42 105.71,63.86 v2(105.71,63.67)
  IN2 w0.254: v2(105.71,63.67) 105.08,63.04 103.39,63.04 101.63,61.29 v2(101.63,59.62)
  BOTTOM w0.254: PC501.1 v2(105.71,63.67) 105.71,64.74 PR505.1 ; v2(101.63,59.62) 101.63,59.2 PH500.2
N18290240: length 3.5
  TOP w0.102: v2(107.49,63.8) v1(108.02,63.8)
  TOP w0.203: PU500.16 105.95,64.64 106.28,64.31 106.98,64.31 v2(107.49,63.8)
  BOTTOM w0.203: PR511.2 v2(107.49,63.8)
N18290306: length 3.9
  TOP w0.203: PU500.2 101.84,68.03 101.76,67.96 v1(101.27,67.96)
  TOP w0.508: PC505.1 PR519.1 100.35,68.56 100.95,67.96 v1(101.27,67.96)
N18290543: length 2.1
  TOP w0.102: v1(109.52,73.65) PR535.2
  TOP w0.203: PR535.2 PC512.1
N18290557: length 3.1
  TOP w0.203: PU500.8 102.17,65.63 v1(101.04,64.5)
  TOP w0.254: v1(101.04,64.5) 100.41,63.88 PR536.1
N18292461: length 14.6
  TOP w0.102: v2(74.2,95.88) v4(74.76,95.33)
  TOP w0.254: v2(74.2,95.88) 74.2,96.46 PR731.2
  IN1 w0.254: v2(74.2,95.88) 74.11,95.8 74.11,95.54 79.42,90.23 79.42,86.85 v2(79.56,86.72)
  BOTTOM w0.203: PU700.4 79.63,86.65 v2(79.56,86.72)
N18292467: length 12.2
  TOP w0.102: v2(66.51,91.3) v4(66.51,90.25)
  TOP w0.508: v2(73.42,98.21) 73.47,98.16 PC730.2 73.48,97.52 PR731.1
  IN1 w1.016: 69.06,96.75 69.07,96.74 69.07,94.53 66.71,92.16
  BOTTOM w0.508: v2(69.72,97.55) 70.14,97.55 70.8,98.21 v2(73.42,98.21)
  vias: v2(65.87,91.3) v2(69.72,98.19)
N18292492: length 14.7
  TOP w0.102: v2(73.62,95.86) 73.09,95.33 v4(73,95.33)
  TOP w0.254: PR730.2 73.62,96.46 v2(73.62,95.86)
  IN1 w0.254: v2(78.93,86.72) 79.07,86.85 79.07,90.08 73.73,95.41 73.73,95.74 v2(73.62,95.86)
  BOTTOM w0.203: v2(78.93,86.72) 78.93,86.59 79.23,86.29 PU700.3
N18292494: length 1.7
  TOP w0.254: PQ708.1 68.67,95.81 68.5,95.97 68.5,96.53 68.72,96.76 PQ708.2
N18293474: length 1.4
  TOP w0.102: v4(74.65,90.13) 74.03,89.51 v2(74.03,88.96)
  vias: v2(74.62,88.96)
N18293502: length 16.1
  TOP w0.254: PQ711.1 75.73,92.62 78,92.62 79.55,91.07 79.55,89.06 v1(80.02,88.59) 80.58,88.04 PR710.1 80.58,86.65 v2(80.63,86.6) 80.63,85.85 PR711.1 PC711.1
  BOTTOM w0.203: v2(80.63,86.6) 80.43,86.39 PU700.6
N18293543: length 2.4
  BOTTOM w0.203: PR714.2 80.03,87.44 v1(80.03,86.41) PU700.5
N18293549: length 3.8
  TOP w0.102: v1(83.49,85.29) 83.49,85.06 v2(83.11,84.68)
  TOP w0.254: PC719.2 82.97,84.82 v2(83.11,84.68)
  BOTTOM w0.203: PU700.8 82.13,84.36 82.45,84.68 v2(83.11,84.68) 83.49,84.68 PR718.2
N18293551: length 4.7
  TOP w0.102: PC718.2 82.05,85.78 v1(82.51,86.25)
  TOP w0.254: PC718.2 81.26,86.04 v2(81.26,86.6)
  BOTTOM w0.203: PU700.7 80.83,86.07 81.26,86.51 v2(81.26,86.6)
  BOTTOM w0.254: PR716.2 81.26,87.35 v2(81.26,86.6)
N18293561: length 3.9
  TOP w0.102: v2(83.12,84.05) 83.58,84.05 v1(83.69,83.93)
  TOP w0.254: PR788.2 83.12,83.17 v2(83.12,84.05)
  BOTTOM w0.203: PR720.2 v2(83.12,84.05) 83.03,83.96 PU700.9
N18293616: length 2.2
  BOTTOM w0.203: PU700.10 v1(82.74,83.56) 83.33,83.56 83.73,83.16 PR717.2
N18293640: length 4.6
  TOP w0.254: PC703.1 77.45,86.54 v2(77.66,86.74)
  BOTTOM w0.203: v2(77.66,86.74) 77.66,86.63 v1(77.98,86.31) 78.43,85.86 PU700.1
  BOTTOM w0.254: v2(77.66,86.74) 77.76,86.84 PC702.2 77.76,88.41 PR705.1
N18293642: length 5.5
  TOP w0.254: PR729.1 80.78,80.94 v2(80.78,79.87) v1(80.03,79.11) v2(79.25,78.33)
  BOTTOM w0.203: PU700.16 80.43,80.58 80.78,80.23 v2(80.78,79.87)
  BOTTOM w0.254: PR725.2 78.93,78.65 v2(79.25,78.33)
N18293644: length 5
  TOP w0.102: v1(78.1,87.29) 78.31,87.08 v2(78.31,86.72)
  TOP w0.254: v2(78.31,86.72) 78.31,86.25 PC701.2
  BOTTOM w0.203: PU700.2 78.83,86.07 78.31,86.59 v2(78.31,86.72)
  BOTTOM w0.254: PR704.1 78.67,88.41 PC702.1 78.67,87.54 78.31,87.17 v2(78.31,86.72)
N18293674: length 22
  TOP w0.102: v1(78.09,79.48) v2(78.8,79.48)
  TOP w0.254: PR721.3 85.29,69.05 85.56,69.32 85.56,75.66 85.08,76.14 79.54,76.14 78.05,77.62 78.05,78.73 v2(78.8,79.48) 78.8,79.93 PC727.1 78.99,80.12 PC726.2
  BOTTOM w0.203: v2(78.8,79.48) 78.83,79.5 PU700.20
N18293684: length 21.7
  TOP w0.254: PR721.2 86.17,69.05 85.91,69.3 85.91,75.88 v1(85.62,76.17) 85.3,76.49 79.68,76.49 78.41,77.77 78.41,78.38 79.44,79.41 v2(79.44,79.48) 79.89,79.93 PC727.2 79.89,80.97 PC728.1
  BOTTOM w0.203: v2(79.44,79.48) 79.23,79.69 PU700.19
N18293714: length 2.9
  BOTTOM w0.203: PR728.2 82.1,79.02 82.1,79.65 v1(81.8,79.96) 80.83,80.93 PU700.15
N18293785: length 2.6
  BOTTOM w0.203: PU700.18 79.63,80.24 v1(79.94,79.92) 79.94,78.73 PR722.1
N18293918: length 5.6
  TOP w0.254: v2(81.65,79.35) 82.68,80.39 PC729.2
  BOTTOM w0.203: PR723.1 80.32,79.36 80.32,80.11 80.03,80.41 PU700.17
  BOTTOM w0.254: PR723.1 81.65,79.29 v2(81.65,79.35)
N18325201: length 2.1
  TOP w0.508: v2(276.88,82.91) 276.91,82.89 CL16.1
  BOTTOM w0.508: TL1.3 v2(276.88,82.91)
N18325205: length 2.2
  TOP w0.508: CL17.1 275.57,82.87 v2(275.61,82.91)
  BOTTOM w0.508: TL1.4 v2(275.61,82.91)
N18325209: length 2.2
  TOP w0.508: v2(269.26,82.91) 269.21,82.86 CL20.1
  BOTTOM w0.508: TL1.9 v2(269.26,82.91)
N18325213: length 2.2
  TOP w0.508: CL21.1 267.94,82.86 v2(267.99,82.91)
  BOTTOM w0.508: TL1.10 v2(267.99,82.91)
N18490882: length 2.4
  TOP w0.102: UI3.16 284.81,41.21 RI14.2 v1(284.57,40.03)
N18609334: length 5.2
  TOP w0.102: v1(115.95,80.68) QV7.1 117.47,81.44 117.46,81.46 RV6.2 117.46,83.02 117.83,83.39 QV8.2
N18749305: length 3.8
  TOP w0.102: LV1.1 108.83,87.93 108.34,87.93 v1(108.15,88.12) 108.15,88.26 v2(108.59,88.7)
  BOTTOM w0.102: v2(108.59,88.7) 108.96,89.06 JEDP1.21
N19516037: length 2.1
  TOP w0.102: RZ35.1 CZ9.1 199.39,88.18 v1(199.82,88.61)
N19544058: length 2
  BOTTOM w0.102: v1(196.97,63) 196.83,62.86 CC10.2 RC62.1
N19544059: length 2
  BOTTOM w0.102: v1(196.91,59.96) 196.68,60.18 CC9.2 RC61.1
N19684722: length 4.9
  TOP w0.102: v1(252.4,72.73) 252.74,72.73 253.44,72.03 253.44,71.09 RE24.1 252.92,69.9 252.94,69.88 UE3.38
N20106358: length 2.8
  BOTTOM w0.102: v1(221.64,83.76) RV50.1 222.11,84.25 222.27,84.25 222.62,83.91 UV7.27
N20106372: length 3.3
  BOTTOM w0.102: CV60.1 230.17,75.92 230.17,76.76 v1(230.02,76.91) 229.22,77.72 UV7.1
N20173859: length 2.6
  TOP w0.102: v4(275.5,16.2) RZ27.1 275.69,17.69 QZ4.1
N20174013: length 2.3
  TOP w0.102: v1(283.69,78.4) RZ33.1 284.78,78.84 284.73,78.89 QZ9.1
N20249193: length 5.9
  TOP w0.102: CA29.1 27.14,13.8 27.14,14.67 v1(27.38,14.91)
  TOP w0.203: UA1.35 29.74,15.77 29.41,15.44 29.41,14.49 29.17,14.25 28.14,14.25 CA29.1
N20249194: length 2.9
  TOP w0.203: UA1.36 29.89,15.37 29.75,15.24 29.75,14.05 29.23,13.52 CA29.2
N20249196: length 4.1
  TOP w0.203: v2(27.8,16.1) 28.22,16.1 v1(28.89,16.78) 29.23,17.12 29.55,17.12 29.8,17.37 UA1.31
  BOTTOM w0.254: CA25.1 27.58,16.32 v2(27.8,16.1)
N20249200: length 2.3
  TOP w0.102: CA27.1 RA12.1 40.74,22.35 v1(41.45,23.06)
N20249201: length 2.1
  TOP w0.102: v1(41.32,20.12) 41.32,20.48 RA13.1 CA28.1
N20249202: length 3.2
  TOP w0.102: v4(31.47,25.76) 31.09,26.13 RA21.2 29.72,26.13 29.58,26.27 QA2.5 QA2.6
N20249232: length 1.1
  TOP w0.381: DA5.1 24.65,15.04 24.58,14.97 RA25.2
N20249233: length 1.2
  TOP w0.381: RA24.2 24.75,14.06 DA4.1
N20249251: length 17.5
  BOTTOM w0.102: JHP1.5 11.55,25.33 11.72,25.5 14.09,25.5 16.57,23.03 v2(16.57,21.31) 16.57,18.87 15.97,18.27 DA2.2 15.97,16.47 16.36,16.09 17.57,16.09 17.97,15.7 RA1.2
N20360585: length 3.8
  TOP w0.203: v2(28.95,14.71) v1(28.95,15.32) 28.95,15.47 29.66,16.17 UA1.34
  BOTTOM w0.254: CA49.2 29.21,13.94 28.95,14.2 v2(28.95,14.71)
N20364102: length 6.9
  TOP w0.102: CA35.2 28.03,23.64 v1(28.23,23.84)
  TOP w0.203: CA35.2 27.23,23.16 28.15,22.24 29.04,22.24 29.84,21.44 29.84,19.86 29.93,19.77 UA1.25
N20364110: length 3.9
  TOP w0.203: UA1.21 32.26,21.45 31.86,21.84 v1(31.86,21.86)
  TOP w0.254: v1(31.86,21.86) 31.52,22.2 RA44.1 32.6,23.11 CA51.1
N20364112: length 2
  BOTTOM w0.102: v1(31.16,12.75) 30.91,13 v2(30.57,13)
  BOTTOM w0.254: v2(30.57,13) 30.17,12.61 CA52.1
N20364114: length 2.7
  TOP w0.203: UA1.7 36.73,17.77 36.81,17.68 v1(37.52,17.68) 38.23,17.68 CA53.1
N20645594: length 1.3
  BOTTOM w0.254: PR309.1 208.82,60.45 PC304.2
N20818937: length 3.4
  TOP w0.102: PR524.1 104.86,59.22 v1(104.38,59.7)
  TOP w0.254: PR518.2 PR525.1 PR524.1
N20880528: length 1.6
  TOP w0.102: UZ2.10 239.8,58.42 239.79,58.41 CZ23.1
N20923205: length 3.2
  BOTTOM w0.203: PU700.21 78.43,80.33 78.15,80.06
  BOTTOM w0.254: PR799.1 76.82,78.73 v1(77.89,79.8) 78.15,80.06
N20970248: length 3.8
  TOP w0.102: v1(141.37,15.33) 140.97,14.92 v2(140.97,14.92) 140.56,14.92 140.38,15.1 RD15.2
  BOTTOM w0.102: JDIMM1.197 140.2,15.1 140.38,14.92 v2(140.97,14.92)
N20970250: length 4.7
  TOP w0.102: RD16.2 139.43,14.68 139.78,14.34 v1(139.85,14.34) v2(140.95,14.34)
  BOTTOM w0.102: JDIMM1.201 141.4,14.78 v2(140.95,14.34)
N21259653: length 4.3
  TOP w0.102: RD28.1 220.63,18.91 v2(221.05,18.49) v1(221.87,18.49)
  BOTTOM w0.102: v2(221.05,18.49) 221.7,17.84 JDIMM2.197
N21259657: length 3.8
  TOP w0.102: v1(223.63,17.51) 223.27,17.88 v2(222.71,17.88) 222.4,17.88 222.1,17.58 RD27.1
  BOTTOM w0.102: v2(222.71,17.88) 222.9,17.69 JDIMM2.201
N21562439: length 1.6
  TOP w0.102: UZ2.12 239.57,57.62 239.48,57.53 CZ42.1
N21786800: length 3
  TOP w0.102: v1(255.99,17.32) CN4.1 255.67,19.12 UN3.6
N21822883: length 7.4
  BOTTOM w0.254: RC2.2 290.45,9.97 v2(291.25,9.97) 291.6,9.97 293.58,7.99 294.66,7.99 295.13,7.52 SW1.2
N21866204: length 2
  TOP w0.102: v1(40.1,16.04) 39.91,16.23 RA17.2 CA33.1
N22016638: length 1.4
  TOP w0.203: CZ41.1 222.45,64.06 222.34,64.17 UZ8.12
N22016651: length 2.6
  TOP w0.102: v1(220.55,63.21) 220.97,63.21 CZ64.1
  TOP w0.203: UZ8.10 221.54,64.13 221.5,64.08 CZ64.1
N22018128: length 1.4
  TOP w0.102: CZ37.1 245.14,30.3 UZ3.6
N22050202: length 3
  TOP w0.203: RA45.1 30.59,22.48 31.86,21.21 UA1.22
N23163402: length 4.1
  TOP w0.102: v1(249.23,34.76) 249.92,34.07 QE4.2 250.67,35.98 RE70.2

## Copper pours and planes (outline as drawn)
1.5VSP on BOTTOM (solid shape): 109.78,77.26 109.78,73.71 109.58,73.51 107.68,73.51 107.39,73.81 106.03,73.81 105.99,73.85 105.99,74.49 107.04,75.54 107.04,76.75 107.62,76.75 107.62,77.26 107.04,77.26 107.04,77.52 107.11,77.58 109.46,77.58
1.35V_B+ on TOP (solid shape): 68.89,23.28 68.77,23.15 65.91,23.15 65.78,23.28 62.54,23.28 61.33,22.06 60.65,22.06 60.44,22.27 60.44,22.68 60.99,22.68 60.99,23.23 60.44,23.23 60.44,23.48 60.99,23.48 60.99,24.03 60.44,24.03 60.44,25.17 60.7,25.44 68.89,25.44
+0.9V_LAN on TOP (solid shape): 254.17,85.26 254.17,85.14 254.11,85.07 253.22,85.07 252.78,84.63 251.85,84.63 251.72,84.75 251.72,85.09 251.86,85.23 252.99,85.23 253.08,85.33 254.11,85.33
+0.9V_LAN on TOP (solid shape): 247.92,87.71 247.92,86.83 248.23,86.53 248.9,86.53 248.91,86.52 249.04,86.5 249.18,86.52 249.19,86.53 249.36,86.53 249.44,86.44 249.44,85.09 249.33,84.97 249.27,84.97 249.25,85 247.86,85 247.84,84.97 246.33,84.97 246.19,85.12 246.19,87.73 246.44,87.99 247.64,87.99
+0.9V_LAN on BOTTOM (solid shape): 247.52,88.15 247.66,88.12 247.8,88.15 247.81,88.15 248.37,88.15 248.47,88.05 248.47,85.19 248.47,85.19 248.47,85.08 248.32,84.94 246.45,84.94 246.14,85.25 246.14,87.83 246.45,88.15 247.51,88.15
+0.9V_LAN on BOTTOM (solid shape): 261.83,91.09 261.83,88.86 260.05,87.08 260.05,82.23 259.56,81.73 258.05,81.73 257.48,82.3 256.44,82.3 255.89,81.75 255.32,81.75 255.1,81.97 253.42,81.97 251.69,83.7 251.69,85.19 251.97,85.47 253.49,85.47 253.75,85.21 253.75,83.38 254.06,83.07 258.37,83.07 258.6,83.3 258.6,87.79 258.32,88.07 254.86,88.07 254.54,88.38 254.54,90.04 255.01,90.51 256.29,90.51 256.66,90.13 260.52,90.13 260.88,90.49 260.88,91 261.03,91.16 261.75,91.16
+0.9V_LAN on IN1 (solid shape): 247.62,87.9 247.62,86.9 248.23,86.29 252.04,86.29 252.84,85.49 252.85,85.49 252.88,85.46 252.88,84.86 252.68,84.66 247.08,84.66 246.78,84.96 246.3,84.96 246,85.25 246,87.96 246.2,88.16 247.36,88.16
+0.675V_DDR_VTT on TOP (solid shape): 224.69,16.22 224.69,12.85 224.36,12.51 224.36,11.24 224.09,10.98 222.89,10.98 222.71,11.16 222.71,14.07 223.12,14.49 223.12,16.34 223.25,16.46 224.45,16.46
+0.675V_DDR_VTT on TOP (solid shape): 143.31,16.12 143.31,13.25 142.57,12.51 142.57,10.87 143.05,10.4 143.05,9.44 142.79,9.18 141.7,9.18 141.47,9.41 141.47,10.25 141.25,10.47 141.25,13.64 141.68,14.08 141.68,16.07 141.89,16.28 143.15,16.28
+0.675V_DDR_VTT on BOTTOM (solid shape): 224.7,14.73 224.7,10.16 224.11,9.57 223.25,9.57 223,9.82 223,14.64 223.33,14.97 224.47,14.97
+0.675V_DDR_VTT on BOTTOM (solid shape): 217.8,29.36 217.8,28.36 217.53,28.09 214.46,28.09 214.31,28.24 214.31,29.46 214.51,29.67 217.5,29.67
+0.675V_DDR_VTT on BOTTOM (solid shape): 81.51,21.54 81.51,20.71 81.24,20.44 79.79,20.44 79.53,20.7 78.68,20.7 78.29,20.32 78.29,15.92 75.56,13.18 72.01,13.18 71.77,13.42 71.77,13.96 71.23,13.96 71.23,14.16 71.79,14.16 71.79,14.58 74.68,14.58 76.86,16.76 76.86,21.61 77.16,21.9 81.15,21.9
+0.675V_DDR_VTT on BOTTOM (solid shape): 144.31,17.22 144.31,15.99 143.84,15.52 143.84,13.26 143.23,12.65 143.23,10.97 143.5,10.71 144.18,10.71 144.55,10.34 144.55,7.27 144.39,7.12 142.27,7.12 142.15,7.24 142.15,9.08 141.22,10.01 141.22,14.08 141.8,14.66 141.8,17.38 141.88,17.45 144.07,17.45
+0.675V_DDR_VTT on IN1 (solid shape): 218.56,28.15 218.56,27.16 218.01,26.6 217.4,26.6 215.76,28.24 215.76,28.99 215.99,29.22 217.5,29.22
+0.675V_DDR_VTT on IN1 (solid shape): 224.96,16.43 224.96,15.39 224.66,15.08 224.66,11.84 224.66,11.83 224.66,11.35 224.45,11.14 223.43,11.14 223.08,11.49 223.08,16.35 223.44,16.71 224.68,16.71
+0.675V_P on BOTTOM (solid shape): 71.63,14.6 71.63,14.33 71.62,14.32 71.08,14.32 71.08,13.82 71.61,13.82 71.64,13.8 71.64,13.34 71.04,12.75 71.04,11.41 70.47,11.41 69.94,10.88 68.78,10.88 68.72,10.94 68.72,11.03 68.78,11.09 69.66,11.09 69.74,11.18 69.74,11.61 69.67,11.69 68.37,11.69 68.31,11.75 68.31,12.53 68.37,12.59 69.39,12.59 69.97,13.18 69.97,14.13 70.52,14.68 71.55,14.68
+1.2V_LDO on TOP (solid shape): 288.29,36.34 288.29,35.79 288.18,35.68 286.76,35.68 285.42,34.34 285.42,33.56 285.37,33.51 285.26,33.51 285.21,33.56 285.21,34.69 285.38,34.86 285.38,34.95 285.38,34.95 285.38,36.25 285.49,36.37 285.98,36.37 286.08,36.46 288.17,36.46
+1.2V_LDO on TOP (solid shape): 291.58,32.01 291.58,30.77 291.47,30.65 290.8,30.65 290.61,30.47 290.61,29.9 290.41,29.7 289.93,29.7 289.73,29.51 289.28,29.51 289.05,29.74 288.19,29.74 288.13,29.79 287.36,29.79 287.32,29.83 287.32,29.97 287.37,30.02 288.19,30.02 288.24,29.97 288.27,29.96 288.65,29.96 288.65,29.97 289.39,29.97 289.58,30.16 289.58,30.52 289.33,30.78 289.2,30.78 288.97,31.01 287.37,31.01 287.32,31.06 287.32,31.13 287.4,31.21 289.58,31.21 289.76,31.03 290.07,31.03 290.31,31.27 290.31,31.5 290.54,31.73 290.54,31.91 290.8,32.18 291.41,32.18
+1.2V_LDO on BOTTOM (solid shape): outline of 290 points within 280.72,30.54 293.26,36.14
+1.2V_LDO on IN2 (solid shape): 282.18,34.15 282.18,28.16 281.56,27.53 280.07,27.53 279.74,27.86 279.74,28.9 280.45,28.9 280.45,28.85 280.46,28.79 280.47,28.74 280.5,28.7 280.53,28.65 280.56,28.61 280.6,28.58 280.65,28.55 280.7,28.53 280.75,28.52 280.81,28.52 280.86,28.52 280.91,28.53 280.96,28.55 281.01,28.58 281.05,28.61 281.08,28.65 281.11,28.7 281.14,28.74 281.15,28.79 281.16,28.85 281.16,28.9 281.15,28.95 281.14,29 281.11,29.05 281.08,29.1 281.05,29.14 281.01,29.17 280.96,29.2 280.91,29.21 280.86,29.23 280.81,29.23 280.75,29.23 280.7,29.21 280.65,29.2 280.6,29.17 280.56,29.14 280.53,29.1 280.5,29.05 280.47,29 280.46,28.95 280.45,28.9 279.74,28.9 279.74,29.27 280.35,29.88 280.35,34.06 280.78,34.49 281.84,34.49
+1.05V_M on TOP (solid shape): 201.01,43.79 201.01,42.57 200.81,42.37 197.41,42.37 196.87,42.9 196.87,45.17 197.2,45.5 199.3,45.5
+1.05V_M on TOP (solid shape): 143.16,63.67 143.16,60.65 141.28,58.78 140.4,58.78 140.14,59.03 140.14,59.66 140.46,59.98 140.46,63.81 140.55,63.89 142.94,63.89
+1.05V_M on TOP (solid shape): 166.68,87.92 166.68,82.88 166.54,82.74 165.01,82.74 164.97,82.74 164.8,82.91 164.8,86.4 164.36,86.84 161.45,86.84 161.13,87.16 161.13,88.46 161.53,88.86 165.75,88.86
+1.05V_M on TOP (solid shape): 220.32,70.11 220.32,67.96 220.55,67.73 221.19,67.73 221.25,67.67 221.25,66.83 221.19,66.78 215.87,66.78 206.61,76.03 206.61,79.32 207.41,80.12 210.31,80.12
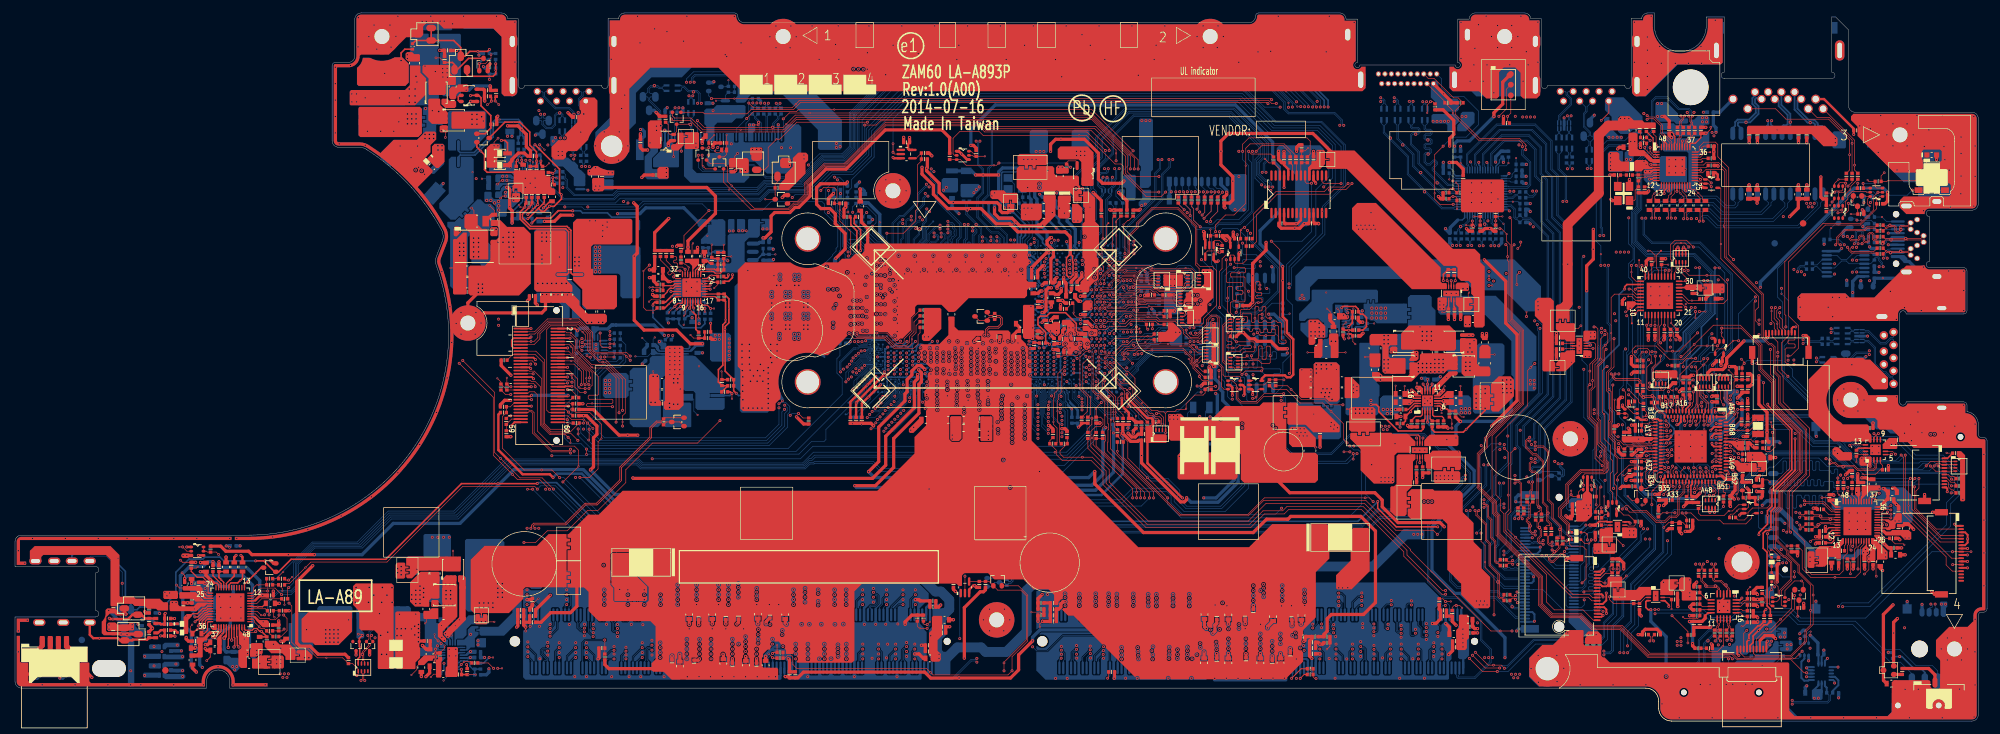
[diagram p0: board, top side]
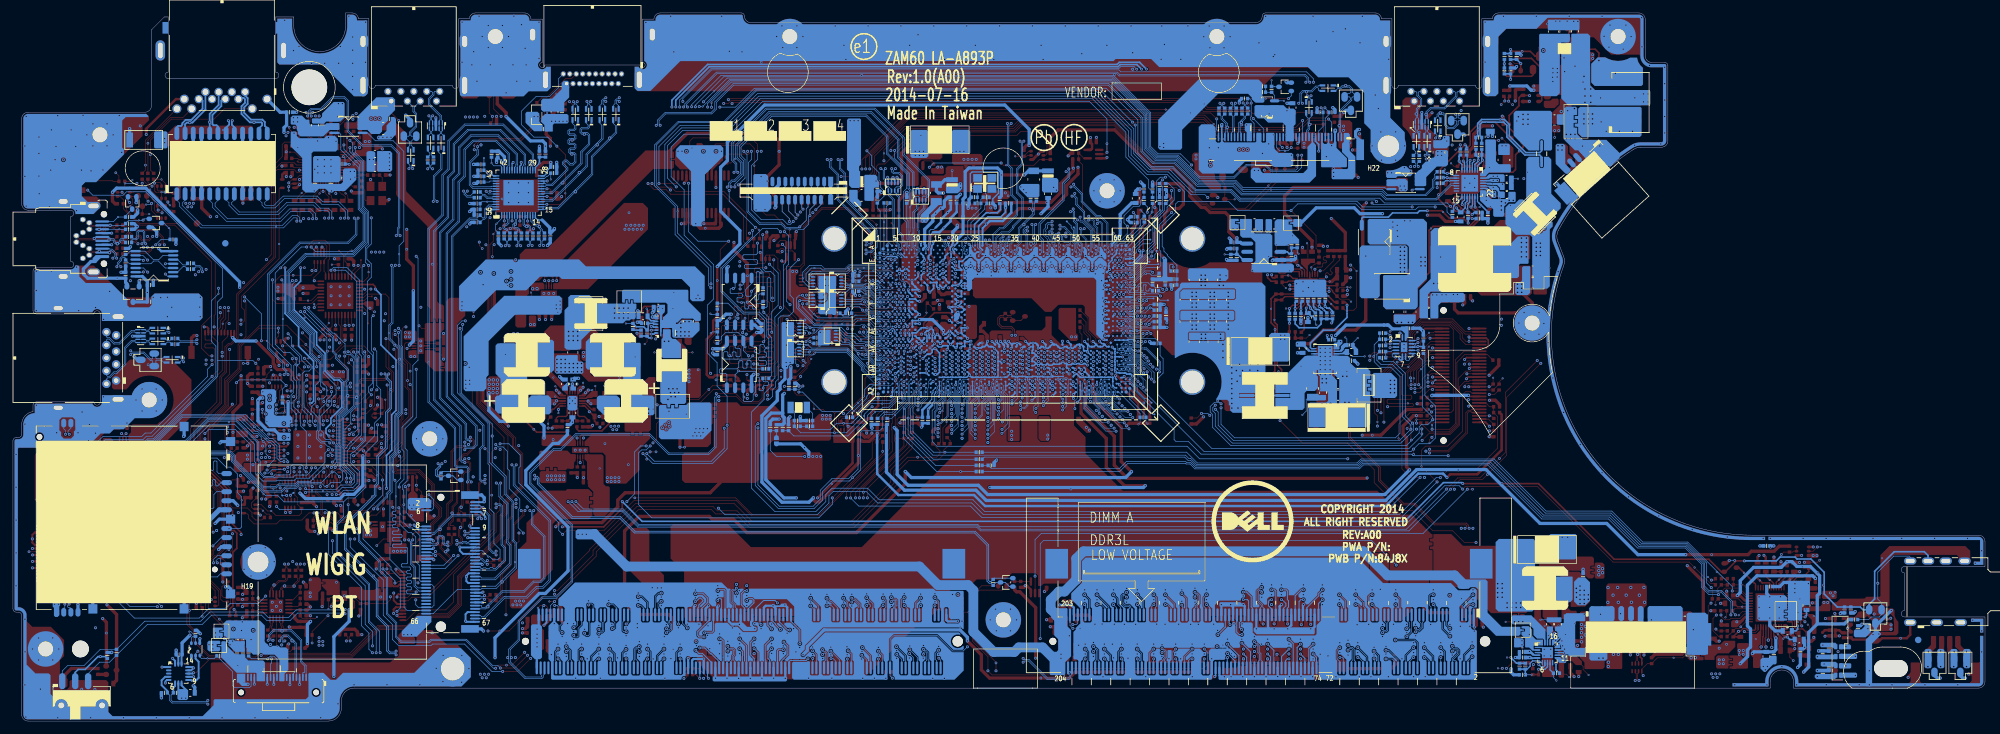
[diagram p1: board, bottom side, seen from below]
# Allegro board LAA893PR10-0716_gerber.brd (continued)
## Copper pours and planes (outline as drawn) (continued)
+1.05V_M on TOP (solid shape): 163.75,61.34 163.75,60.28 163.76,60.27 163.76,60.24 163.99,60.01 163.99,59.68 163.88,59.56 163.6,59.56 163.48,59.68 163.48,60.02 163.29,60.21 163.01,60.21 162.82,60.02 162.82,59.59 162.39,59.59 162.29,59.69 162.29,60.03 162.54,60.27 162.56,60.27 162.56,61.04 162.55,61.04 162.55,61.12 162.43,61.25 161.86,61.25 161.76,61.34 161.76,61.9 161.92,62.06 163.03,62.06
+1.05V_M on BOTTOM (solid shape): 166.05,91.19 166.05,87.3 165.83,87.08 163.56,87.08 163.28,87.36 163.28,91.16 163.54,91.41 165.82,91.41
+1.05V_M on BOTTOM (solid shape): outline of 144 points within 196.79,43.57 204.93,49.28
+1.05V_M on IN1 (solid shape): outline of 2801 points within 139.98,58.89 210.85,93.04
+1.05V_M on IN2 (solid shape): outline of 512 points within 194.28,43.55 210.57,76.94
+1.05V_M on GND: 198.6,43.56 197.1,45.06 197.1,54.91 198.42,56.23 198.42,58.28 197.91,58.79 197.91,63.58 198.42,64.09 198.42,70.02 205.7,77.3 210.71,77.3 211.1,76.92 211.1,75.28 210.47,74.65 206.19,74.65 201.17,69.62 201.17,63.71 199.6,62.14 199.6,59.34 200.52,58.43 200.52,55.53 199.17,54.18 199.17,46.4 199.97,45.6 199.97,43.92 199.61,43.56
+1.05V_MODPHY on TOP (solid shape): outline of 192 points within 154.79,80.33 164.89,85.83
+1.05V_MODPHY_PCH on TOP (solid shape): outline of 228 points within 163.82,66.27 167.51,81.89
+1.05V_MP on TOP (solid shape): 204.7,54.98 204.7,49.78 204.31,49.39 203.06,49.39 202.53,49.91 200.77,49.91 200.67,50.01 200.67,55.18 200.96,55.47 204.21,55.47
+1.05V_MP on BOTTOM (solid shape): 204.71,54.98 204.71,49.38 204.36,49.04 203.63,49.04 203.63,48.49 203.18,48.49 203.18,49.04 202.43,49.04 202.43,48.49 201.98,48.49 201.98,49.04 200.98,49.04 200.72,49.29 200.72,55.22 200.97,55.47 204.21,55.47
+1.05V_RUN on TOP (solid shape): 153.18,81.69 154.79,81.69 155.02,81.46 155.02,80.28 154.83,80.09 154.06,80.09 154.06,80.61 153.63,80.61 153.63,80.09 152.52,80.09 151.91,80.7 151.01,80.7 150.72,80.99 150.72,81.88 150.92,82.08 152.79,82.08
+1.05V_RUN on TOP (solid shape): 159.63,87.49 159.63,86.26 159.33,85.96 158.16,85.96 157.76,85.96 157.75,85.95 157.72,85.95 157.72,85.58 157.72,85.58 157.72,85.43 157.24,85.43 157.24,85.95 156.54,85.95 156.54,85.43 156.04,85.43 156.04,85.95 155.11,85.95 154.91,86.15 154.91,87.37 155.23,87.7 159.42,87.7
+1.05V_RUN on TOP (solid shape): outline of 234 points within 178.2,36.83 201.36,49.29
+1.05V_RUN on BOTTOM (solid shape): 145.73,83.85 145.73,81.99 145.46,81.72 143.42,81.72 143.19,81.95 143.19,83.71 143.46,83.97 145.61,83.97
+1.05V_RUN on BOTTOM (solid shape): 159.04,82.78 160.48,82.78 160.57,82.7 160.57,81.82 160.56,81.82 160.56,81.75 160.42,81.61 158.75,81.61 158.04,82.32 158.04,83.2 158.14,83.3 158.52,83.3
+1.5V_RUN on BOTTOM (solid shape): 106.9,77.55 106.9,77.12 107.43,77.12 107.43,76.89 106.9,76.89 106.9,76.49 106.83,76.42 105.67,76.42 105.5,76.59 105.5,77.45 105.7,77.65 106.81,77.65
+1.05V_RUN on BOTTOM (solid shape): 175.85,92.95 175.85,85.27 175.55,84.97 175.55,82.84 175.15,82.44 174.01,82.44 173.84,82.61 173.84,84.99 173.98,85.13 173.98,85.77 173.7,86.05 173.7,93 173.87,93.18 175.63,93.18
+1.05V_RUN on IN1 (solid shape): 146.02,83.08 146.02,82.1 145.76,81.84 143.33,81.84 142.69,82.47 142.69,82.84 143.18,83.32 145.78,83.32
+1.05V_RUN on IN1 (solid shape): 132.89,82.28 132.89,81.33 132.26,80.7 126.41,80.7 126.13,80.97 126.13,81.83 126.35,82.04 129.69,82.04 130.17,82.52 132.65,82.52
+1.05V_RUN on IN1 (solid shape): outline of 707 points within 150.21,66.01 176.29,96.99
+1.05V_RUN on VCC: 168.62,44.63 165.03,48.21 165.03,50.12 164.65,50.5 164.65,50.88 163.15,52.38 163.15,55.2 162.65,55.7 161.01,55.7 160.83,55.88 160.83,57.43 159.41,58.85 157.65,58.85 157.65,72.05 165.55,72.05 166.8,70.81 166.81,66.38 165.54,65.24 165.54,63.65 166.54,62.65 170.92,62.65 171.12,62.45 171.12,53.28 174.57,49.83 179.27,49.83 179.88,49.22 179.88,44.63
+1.5V_RUN_AUDIO on TOP (solid shape): 32.36,14.9 32.36,13.59 32.34,13.56 31.94,13.16 31.94,10.45 31.87,10.39 31.26,10.39 31.25,10.4 31.25,12.91 32.15,13.81 32.15,14.9 32.22,14.97 32.3,14.97
+1.05V_RUN_UZ8 on TOP (solid shape): 221.18,65.5 221.25,65.43 221.25,64.32 221.08,64.15 221.08,63.59 220.98,63.5 219.94,63.5 219.81,63.62 219.81,65.39 219.92,65.5 221.14,65.5
+1.05V_RUN_UZ8 on TOP (solid shape): 198.41,48.75 201.68,48.75 204.72,45.7 204.72,44.8 204.58,44.65 200.62,44.65 199.46,45.81 196.82,45.81 196.6,46.02 196.6,46.88 196.08,46.88 196.08,47.37 196.6,47.37 196.6,48.08 196.08,48.08 196.08,48.57 196.6,48.57 196.6,49.19 196.66,49.25 197.91,49.25
+1.05V_RUN_UZ8 on BOTTOM (solid shape): 235.1,59.49 235.1,55.73 235.06,55.65 234.97,55.64 234.49,55.3 234.97,54.97 235.06,54.95 235.1,54.87 235.1,51.31 234.81,51.01 232.01,51.01 231.58,51.44 231.58,53.18 231.23,53.53 231.23,58.76 227.17,62.81 226.91,62.81 226.89,62.83 220.29,62.83 219.94,63.18 219.94,65.41 220.29,65.76 228.83,65.76
+1.05V_RUN_UZ8 on IN1 (solid shape): outline of 515 points within 210.72,42.94 235.52,54.39
+1.05V_RUN_UZ8 on IN2 (solid shape): 211.42,46.4 213.17,46.4 213.46,46.12 213.46,44.09 213.23,43.87 202.97,43.87 202.66,44.17 202.66,46.47 202.89,46.7 211.12,46.7
+1.05V_VCCST on TOP (solid shape): 157.51,64.23 157.51,59.01 157.42,58.91 157.07,58.91 156.91,59.07 156.04,59.07 155.76,59.35 155.76,64.21 155.91,64.36 157.38,64.36
+1.05V_VCCST on TOP (solid shape): 153.94,79.97 153.95,79.95 154.38,79.95 154.44,79.89 154.44,78.84 154.28,78.68 153.5,78.68 153.32,78.86 153.32,79.92 153.36,79.95 153.74,79.95 153.75,79.97 153.75,80.49 153.94,80.49
+1.05V_VCCST on BOTTOM (solid shape): 127.13,71.71 127.13,71.49 127.07,71.43 127.07,68.82 127.25,68.64 127.26,68.64 127.3,68.59 128.89,68.59 128.94,68.55 128.94,68.2 128.74,68 125.56,68 125.51,68.06 125.51,68.6 125.56,68.65 126.24,68.65 126.38,68.79 126.38,71.47 126.74,71.83 127.01,71.83
+1.5V_VIN on BOTTOM (solid shape): 115.15,77.6 115.15,77.16 115.15,77.16 115.71,77.16 115.71,76.97 115.17,76.97 115.15,76.96 115.15,76.52 115.11,76.48 115.11,75.1 114.79,74.78 113.47,74.78 112.75,74.06 112.75,71.12 113.34,70.53 113.34,69.73 112.98,69.37 110.97,69.37 110.96,69.37 110.85,69.39 110.75,69.37 110.74,69.37 110.33,69.37 110.32,69.37 110.22,69.39 110.12,69.37 110.11,69.37 107.12,69.37 106.79,69.71 106.79,70.45 107.09,70.75 110.49,70.75 110.68,70.95 110.68,71.48 110.45,71.72 110.2,71.72 110.12,71.79 110.12,75.06 110.46,75.4 112.82,75.4 113.3,75.87 113.3,77.55 113.39,77.65 115.1,77.65
+1.8V_RUN_CARD on TOP (solid shape): 289.39,26.2 289.39,25.11 289.25,24.98 287.82,24.98 287.74,25.06 287.74,26.56 286.81,27.48 286.81,28.24 286.88,28.3 287.28,28.3
+1.8V_RUN_CARD on BOTTOM (solid shape): 298.61,18.41 298.61,17.69 298.41,17.49 298.41,16.3 298.22,16.1 297.85,16.1 297.58,16.37 297.58,17.74 297.45,17.86 297.45,18.35 297.59,18.48 298.53,18.48
+1.8V_RUN_CARD on IN2 (solid shape): 298.61,18.36 298.61,17.38 298.5,17.28 297.57,17.28 297.4,17.45 297.4,18.36 297.58,18.54 298.42,18.54
+1.8V_RUN_CARD on IN2 (solid shape): 289.89,26 289.89,24.47 289.71,24.28 289.09,24.28 288.9,24.48 288.9,24.48 288.73,24.65 288.73,26.12 288.92,26.31 289.58,26.31
+1.35V_MEM on TOP (solid shape): outline of 15175 points within 85.37,6.4 203.12,62.53
+1.35V_MEM on BOTTOM (solid shape): 113.02,14.33 113.02,13.87 112.57,13.42 103.71,13.42 103.57,13.56 103.57,14.35 103.72,14.5 112.85,14.5
+1.35V_MEM on BOTTOM (solid shape): 118.45,6.94 118.45,6.51 118.31,6.37 103.72,6.37 103.61,6.48 103.61,6.99 103.7,7.08 104.03,7.08 104.04,7.09 118.31,7.09
+1.35V_MEM on BOTTOM (solid shape): 196.62,6.77 196.62,6.28 196.47,6.12 185.29,6.12 185.12,6.3 185.12,6.75 185.26,6.89 185.55,6.89 185.56,6.89 196.51,6.89
+1.35V_MEM on BOTTOM (solid shape): 118.31,18.26 118.31,17.79 118.22,17.7 114.52,17.7 114.38,17.83 114.38,18.08 114.49,18.19 114.86,18.19 115.07,18.39 118.18,18.39
+1.35V_MEM on BOTTOM (solid shape): 193.67,15.16 193.67,14.89 193.54,14.76 193.48,14.75 192.69,14.75 191.83,13.89 190,13.89 189.81,14.09 189.81,14.44 189.96,14.58 191.31,14.58 191.94,15.21 193.61,15.21
+1.35V_MEM on BOTTOM (solid shape): 186.23,17.91 186.9,17.91 187.03,18.04 187.43,18.04 187.51,17.96 187.51,17.73 187.4,17.61 187.35,17.61 187.29,17.56 187.08,17.56 187,17.64 185.31,17.64 185.19,17.76 185.19,18.12 185.24,18.17 185.96,18.17
+1.35V_MEN_P on TOP (solid shape): 85.24,28.89 85.24,28.24 85.25,28.21 85.76,28.21 85.76,27.76 85.25,27.76 85.24,27.74 85.24,27.04 85.25,27.01 85.76,27.01 85.76,26.56 85.25,26.56 85.24,26.54 85.24,23.03 85.25,23.01 85.76,23.01 85.76,22.56 85.25,22.56 85.24,22.53 85.24,21.83 85.25,21.81 85.76,21.81 85.76,21.36 85.25,21.36 85.24,21.33 85.24,20.72 85.21,20.69 78.87,20.69 78.55,20.37 78.55,18.91 76.32,16.69 72.7,16.69 72.19,16.69 72.16,16.69 72.16,16.16 71.98,16.16 71.98,16.69 71.98,16.69 71.44,16.69 70.93,16.69 70.42,17.2 70.42,24.96 72.56,27.1 78.64,27.1 78.65,27.1 80.65,27.1 82.47,28.92 85.21,28.92
+1.35V_MEN_P on BOTTOM (solid shape): 75.63,27.66 75.63,17.37 75.18,16.93 69.97,16.93 69.53,17.37 69.53,27.91 69.78,28.17 75.12,28.17
+1.35V_MEN_P on BOTTOM (solid shape): 71.27,9.54 69.91,9.54 69.85,9.61 68.81,9.61 68.75,9.61 68.71,9.65 68.71,9.83 68.77,9.89 69.97,9.89 70.19,10.1 71.27,10.1
+3.3V_ALW on TOP (solid shape): 99.94,92.8 99.94,88.75 99.74,88.55 98.12,88.55 97.79,88.89 97.79,92.51 98.17,92.89 99.85,92.89
+3.3V_ALW on TOP (solid shape): 223.06,44.07 223.06,42.74 222.85,42.52 217.87,42.52 217.78,42.6 217.78,43.45 218.63,44.3 222.83,44.3
+3.3V_ALW on TOP (solid shape): 244.35,60.2 244.35,59.15 244.19,58.98 243.36,58.98 243.1,58.72 242.42,58.72 242.36,58.78 242.36,60.21 242.52,60.38 244.17,60.38
+3.3V_ALW on TOP (solid shape): 224.69,67.56 224.69,66.66 224.52,66.49 223.49,66.49 223.21,66.77 222.71,66.77 222.64,66.83 222.64,67.57 222.88,67.81 224.44,67.81
+3.3V_ALW on TOP (solid shape): 243.67,57.11 243.67,56.28 243.53,56.14 242.32,56.14 242.24,56.22 242.24,56.6 242.28,56.65 242.3,56.65 242.3,56.67 242.36,56.72 242.36,57.26 242.43,57.33 243.45,57.33
+3.3V_ALW on TOP (solid shape): 250.66,29.69 250.66,28.47 250.47,28.28 248.47,28.28 248.33,28.42 248.33,28.61 248.33,28.62 248.33,29.84 248.42,29.93 250.42,29.93
+3.3V_ALW on TOP (solid shape): 231.64,52.77 231.64,50.21 229.28,47.85 228.33,47.85 228.08,48.11 228.08,48.75 228.59,48.75 228.59,49.45 228.08,49.45 228.08,49.95 228.59,49.95 228.59,50.65 228.08,50.65 228.08,52.12 229.27,53.31 231.1,53.31
+3.3V_ALW on TOP (solid shape): 264.2,67.46 264.2,66.33 264,66.14 262.64,66.14 262.29,65.8 261.05,65.8 260.9,65.94 260.9,66.75 261.44,66.75 261.44,67.18 261.44,67.19 260.9,67.19 260.9,67.6 260.97,67.67 263.99,67.67
+3.3V_ALW on TOP (solid shape): 301.37,41.11 301.37,34.15 301.18,33.97 300.73,33.97 300.58,34.12 300.58,40.45 300.06,40.97 300.06,41.67 300.13,41.74 300.73,41.74
+3.3V_ALW on TOP (solid shape): 270.62,40.97 270.62,38.89 270.26,38.53 269.32,38.53 269.31,38.53 269.31,38.79 269.84,38.79 269.85,38.82 269.85,39.25 269.84,39.25 269.31,39.25 269.31,39.81 269.01,40.11 267.64,40.11 267.56,40.19 267.56,41.49 267.7,41.63 269.96,41.63
+3.3V_ALW on BOTTOM (solid shape): 205.25,64.16 205.25,63.29 204.75,62.78 204.75,61.61 204.49,61.61 204.49,62.76 204.01,63.24 204.01,64.37 205.04,64.37
+3.3V_ALW on IN1 (solid shape): 230.76,53.76 230.76,52.58 230.66,52.49 229.68,52.49 229.55,52.62 229.55,53.68 229.85,53.99 230.53,53.99
+3.3V_ALW on IN1 (solid shape): 249.66,73.22 249.66,71.8 249.36,71.5 245.65,71.5 245.47,71.68 245.47,73.38 245.66,73.57 249.31,73.57
+3.3V_ALW on IN1 (solid shape): 235.3,93.36 235.3,90.96 235.01,90.66 233.62,90.66 233.25,90.66 232.53,91.38 232.53,93.5 232.69,93.66 235.01,93.66
+3.3V_ALW on IN1 (solid shape): 226.26,66.32 226.26,65.94 225.79,65.46 225.42,65.46 224.75,66.14 223.41,66.14 223.07,66.47 222.82,66.47 222.81,66.47 222.71,66.49 222.6,66.47 222.59,66.47 222.12,66.47 222,66.6 222,67.16 222.08,67.25 223.15,67.25 223.47,67.57 225.02,67.57
+3.3V_ALW on VCC: 248.31,27.22 246.43,29.11 246.43,36.77 251,41.34 251,48.92 250.22,49.7 229.9,49.7 229.41,50.19 229.41,56 229.73,56.31 231.1,57.68 234.33,57.68 238.66,62.02 245.52,62.02 246.43,62.93 246.43,74.62 246.91,75.1 259.4,75.1 267.76,66.74 267.76,55.44 271.45,51.76 271.45,38.42 270.32,37.29 270.32,31.32 266.22,27.22
+3.3V_ALW on VCC: 82.01,92.44 88.94,92.44 91.54,95.05 94.89,95.05 94.89,107.58 111.26,107.58 111.92,107.14 112.7,106.98 190.7,106.98 191.44,107.13 192.08,107.53 206.43,107.53 206.43,102.44 206.45,100.45 208.44,100.43 221.96,100.43 223.95,100.45 223.97,102.44 223.97,107.53 224.7,107.53 225.7,108.48 233.25,108.48 234.25,107.58 234.83,107.58 234.83,98.3 235.1,97.44 235.81,96.88 235.81,93.01 232.53,93.01 231.25,91.73 197.71,91.73 195.15,94.3 188.09,94.3 184.05,98.34 182.89,98.34 182.89,99.5 179.22,103.17 123.65,103.17 122.48,102 122.48,98.19 115.26,90.98 101.8,90.98 100.27,89.45 94.94,89.45 91.76,86.28 91.1,86.28 91.1,86.28 90.89,86.28 90.88,86.28 82.84,86.28 82.84,87.86 81.98,88.72 81.98,92.41
+3.3V_ALW_PCH on TOP (solid shape): 180.24,60.38 180.24,59.87 179.01,58.64 176.74,58.64 176.67,58.7 176.67,60.1 176.75,60.18 177.8,60.18 178.16,60.54 178.16,61.54 178.26,61.65 178.97,61.65
+3.3V_ALW_PCH on TOP (solid shape): 161.49,61.56 161.49,60 161.05,59.56 160.87,59.56 160.36,60.07 159.99,60.07 159.99,60.07 159.78,60.07 159.06,60.8 159.06,61.31 159.16,61.41 160.21,61.41 160.54,61.75 161.3,61.75
+3.3V_ALW_PCH on TOP (solid shape): 237.8,64.93 238.03,55.38 238.03,54.78 238.57,54.78 238.57,54.57 238,54.57 238,54.12 237.95,54.06 236.21,54.06 236.04,54.23 236.04,61.47 234.86,62.65 234.86,64.97 235.35,65.46 237.28,65.46
+3.3V_ALW_PCH on TOP (solid shape): 185.59,61.56 185.59,55.22 185.66,55.16 185.66,54.65 185.6,54.59 185.09,54.59 184.97,54.71 184.97,54.87 184.92,54.92 184.92,54.95 184.7,55.17 184.39,55.17 184.39,55.62 184.5,55.73 184.75,55.73 184.9,55.87 184.9,60.1 184.9,60.1 184.9,61.45 184.9,61.56 185.02,61.68 185.47,61.68
+3.3V_ALW_PCH on BOTTOM (solid shape): 179.04,60.46 180.07,60.46 180.38,60.15 180.38,58.17 180.3,58.09 178.67,58.09 178.4,58.36 178.4,60.38 178.5,60.48 179.01,60.48
+3.3V_ALW_PCH on BOTTOM (solid shape): 185.99,61.55 185.99,54.71 185.76,54.49 185,54.49 184.92,54.57 184.92,54.95 184.7,55.17 184.66,55.17 184.65,55.18 184.19,55.18 184.04,55.34 184.04,61.57 184.17,61.7 185.84,61.7
+3.3V_ALW_PCH on BOTTOM (solid shape): outline of 313 points within 197.84,63.35 235.81,71.39
+3.3V_ALW_PCH on IN1 (solid shape): 161.21,60.49 161.21,60.21 161.55,59.87 161.55,59.68 162.17,59.06 162.47,59.06 162.76,58.78 162.76,58.15 162.55,57.95 162.03,57.95 161.73,58.24 161.74,58.27 161.67,58.6 161.34,58.67 161.16,58.67 160.38,59.45 160.38,59.68 160.38,59.68 160.38,59.87 160.2,60.05 159.9,60.05 159.77,60.19 159.77,60.58 159.9,60.72 160.98,60.72
+3.3V_ALW_PCH on IN1 (solid shape): outline of 249 points within 184.22,54.61 200.14,66.14
+3.3V_ALW_PCH on IN2 (solid shape): outline of 1208 points within 163.85,59.87 185.31,64.48
+3.3V_ALW_PCH_UZ2 on TOP (solid shape): 241.09,57.26 241.09,55.57 239.6,54.08 238.22,54.08 238.16,54.14 238.16,54.42 238.72,54.42 238.72,54.91 238.16,54.91 238.16,55.36 238.78,55.98 238.78,56.86 238.96,57.03 239.5,57.03 239.8,57.33 241.02,57.33
+3.3V_ALW_UE2 on TOP (solid shape): 265.48,43.35 267.13,43.35 267.19,43.29 267.19,41.89 267.13,41.83 266.27,41.83 265.54,42.56 265.53,42.56 265.4,42.68 265.34,42.77 265.26,42.83 265.15,42.93 264.94,42.93 264.81,43.06 264.08,43.06 264.03,43.11 264.03,43.29 264.09,43.35 265.48,43.35
+3.3V_ALW_UE2 on TOP (solid shape): 251.83,43.92 253.08,43.92 253.13,43.88 253.74,43.88 253.85,43.77 253.85,43.65 253.76,43.56 253.19,43.56 252.93,43.31 252.01,43.31 251.76,43.06 248.59,43.06 248.28,43.36 248.28,43.97 248.36,44.04 251.71,44.04
+3.3V_ALW_UE2 on TOP (solid shape): 265.48,40.34 266.24,40.34 266.66,39.92 269.01,39.92 269.16,39.77 269.16,39.13 269.72,39.13 269.72,38.92 269.18,38.92 269.18,38.56 269.16,38.53 266.38,38.53 266,38.91 266,39.33 265.4,39.92 265.01,39.92 264.88,40.05 264.13,40.05 264.03,40.15 264.03,40.27 264.13,40.37 265.45,40.37
+3.3V_ALW_UE2 on BOTTOM (solid shape): outline of 260 points within 261.53,45.44 266.44,51.32
+3.3V_ALW_UE3 on TOP (solid shape): 250.58,64.64 251.65,64.64 251.75,64.54 251.75,64.46 251.67,64.39 250.5,64.39 249.71,63.59 249.17,63.59 249.04,63.72 249.04,64.83 249.13,64.92 250.3,64.92
+3.3V_ALW_UE3 on TOP (solid shape): 260.75,67.49 260.75,67.06 261.31,67.06 261.31,66.88 260.75,66.88 260.75,66.47 260.69,66.41 260.34,66.41 260.09,66.65 258.23,66.65 257.97,66.9 256.73,66.9 256.65,66.98 256.65,67.08 256.73,67.16 257.92,67.16 258.29,67.53 260.72,67.53
+3.3V_ALWP on TOP (solid shape): 227.94,51.72 227.94,50.55 227.95,50.55 227.95,50.53 228.46,50.53 228.46,50.08 227.95,50.08 227.95,50.05 227.94,50.05 227.94,49.35 227.95,49.35 227.95,49.33 228.46,49.33 228.46,48.88 227.95,48.88 227.95,48.85 227.94,48.85 227.94,48.2 227.86,48.11 225.54,48.11 225.35,48.31 225.35,51.67 225.6,51.92 227.74,51.92
+3.3V_ALWP on BOTTOM (solid shape): 230.17,58.08 230.17,53.71 229.41,52.94 229.41,50.59 229.66,50.34 229.97,50.34 230.26,50.05 230.26,48.06 229.75,47.54 225.6,47.54 225.28,47.86 225.28,53.26 225.92,53.89 225.92,58.08 226.23,58.4 229.85,58.4
+3.3V_CAM on TOP (solid shape): 113.4,86.79 113.4,84.91 113.22,84.74 112.04,84.74 111.94,84.84 111.94,85.32 111.68,85.58 110.44,85.58 110.31,85.71 110.31,86.84 110.54,87.07 113.12,87.07
+3.3V_CAM on BOTTOM (solid shape): 104.08,90.91 104.08,89.41 104.71,88.78 104.71,85.38 105.36,84.73 111.57,84.73 111.91,85.08 111.91,85.27 112.21,85.57 113.09,85.57 113.47,85.19 113.47,84.05 112.84,83.41 112.84,83.4 112.68,83.25 104.38,83.25 103.38,84.25 103.38,89.08 103.82,89.52 103.82,90.91 103.86,90.95 104.04,90.95
+3.3V_HDD on TOP (solid shape): 259.06,21.97 259.06,21.27 258.98,21.19 258.98,20.36 259.17,20.18 259.67,20.18 259.8,20.05 259.8,18.77 259.66,18.63 257.69,18.63 257.57,18.76 257.57,19.9 257.12,20.34 257.12,21.26 256.58,21.26 256.58,21.44 257.12,21.44 257.12,21.88 257.48,22.24 258.8,22.24
+3.3V_HDD on BOTTOM (solid shape): outline of 182 points within 262.19,6.16 272.73,15.57
+3.3V_HDD on IN1 (solid shape): outline of 428 points within 258.35,14.91 269.99,20.15
+3.3V_LAN on TOP (solid shape): 240.23,64.15 240.23,61.76 240.17,61.69 239.84,61.69 239.84,62.22 239.34,62.22 239.34,61.69 239.04,61.69 239.04,62.22 238.54,62.22 238.54,61.69 238.17,61.69 238.11,61.75 238.11,64.17 238.36,64.42 239.97,64.42
+3.3V_LAN on TOP (solid shape): 250.14,92.91 251.47,92.91 251.79,92.58 253.45,92.58 253.55,92.49 253.55,91.73 253.39,91.58 250.54,91.58 250.54,91.59 249.4,91.59 249.14,91.34 247.82,91.34 247.7,91.45 247.7,93.16 248.08,93.55 249.5,93.55
+3.3V_LAN on IN1 (solid shape): 250.62,92.7 250.62,92.46 249.51,91.35 249.24,91.35 247.78,92.82 247.78,93.34 248.42,93.98 249.34,93.98
+3.3V_LAN on IN1 (solid shape): 263.09,91.31 263.09,89.08 262.89,88.88 260.68,88.88 260.56,89 260.56,90.41 260.69,90.54 261.44,90.54 261.68,90.78 261.68,91.29 261.87,91.48 262.93,91.48
+3.3V_LAN on IN2 (solid shape): 263.13,91.38 263.13,91.36 263.18,91.31 263.18,87.4 264.34,86.25 264.34,83.95 264.08,83.69 262.51,83.69 262.23,83.97 262.23,84.37 261.52,85.07 261.52,85.44 261.12,85.84 262.82,85.84 262.82,85.79 262.83,85.73 262.85,85.68 262.87,85.63 262.9,85.59 262.94,85.55 262.98,85.52 263.02,85.49 263.07,85.47 263.13,85.46 263.18,85.46 263.23,85.46 263.28,85.47 263.33,85.49 263.38,85.52 263.42,85.55 263.46,85.59 263.49,85.63 263.51,85.68 263.53,85.73 263.54,85.79 263.54,85.84 263.53,85.89 263.51,85.94 263.49,85.99 263.46,86.04 263.42,86.07 263.38,86.11 263.33,86.13 263.28,86.15 263.23,86.17 263.18,86.17 263.13,86.17 263.07,86.15 263.02,86.13 262.98,86.11 262.94,86.07 262.9,86.04 262.87,85.99 262.85,85.94 262.83,85.89 262.82,85.84 261.12,85.84 261.1,85.86 261.1,90.19 261.69,90.79 261.69,91.27 261.9,91.48 263.03,91.48
+3.3V_LAN_OUT on TOP (solid shape): 250.75,90.74 250.75,88.53 250.98,88.3 251.72,88.3 253.12,86.89 254.09,86.89 254.19,86.79 254.19,86.36 254.11,86.28 253.08,86.28 252.91,86.42 252.69,86.44 252.67,86.43 251.75,87.35 249.55,87.35 249.32,87.58 249.32,90.77 249.55,90.99 250.5,90.99
+3.3V_LAN_OUT on IN2 (solid shape): outline of 280 points within 248.94,80.44 261.32,90.12
+3.3V_LAN_UZ2 on TOP (solid shape): 239.7,62.07 239.7,61.56 239.72,61.54 240.94,61.54 241.1,61.38 241.1,58.78 241.02,58.7 239.79,58.7 239.48,59 238.86,59 238.68,59.18 238.68,60.02 238.11,60.59 238.11,61.24 238.11,61.48 238.16,61.54 238.64,61.54 238.67,61.56 238.67,62.04 238.72,62.08 238.87,62.08 238.9,62.05 238.9,61.56 238.93,61.54 239.46,61.54 239.47,61.55 239.47,62.08 239.48,62.09 239.68,62.09
+3.3V_M on TOP (solid shape): 221.81,73.42 221.82,73.41 221.89,73.29 222.01,73.21 222.02,73.21 222.2,73.03 225.56,73.03 226.43,72.16 226.43,70.97 227.12,70.28 227.12,61.15 226.83,60.85 225.65,60.85 225.44,61.07 225.44,64.11 225.44,64.31 225.41,64.34 224.88,64.34 224.88,64.49 225.38,64.49 225.41,64.52 225.41,65.68 225.02,66.07 225.02,67.68 224.64,68.06 223.45,68.06 222.93,68.58 222.93,70.08 222.61,70.39 220.77,70.39 215.77,75.39 215.77,75.4 205.78,85.38 202.83,85.38 202.6,85.62 202.6,86.62 203.13,86.62 203.13,87.06 202.6,87.06 202.6,87.95 202.89,88.24 207,88.24
+3.3V_M_TPM on TOP (solid shape): 202.45,88.11 202.45,86.93 203.01,86.93 203.01,86.75 202.45,86.75 202.45,86.11 201.66,85.32 200.39,85.32 200.21,85.14 200.21,83.67 200.09,83.54 199.93,83.54 199.81,83.67 199.81,85.6 200.37,86.16 200.37,86.54 200.47,86.64 201,86.64 201.1,86.74 201.1,88.13 201.3,88.32 202.24,88.32
+3.3V_M_TPM on BOTTOM (solid shape): outline of 173 points within 194.97,76.5 202.26,89.05
+3.3V_M_UZ8 on TOP (solid shape): 225.26,65.13 225.26,64.64 224.72,64.64 224.72,64.2 225.26,64.2 225.26,63.84 224.88,63.47 223.09,63.47 223.09,63.97 222.64,64.42 222.64,65.43 222.71,65.5 224.88,65.5
+3.3V_MMI on TOP (solid shape): 285.15,36.13 285.15,34.91 285.04,34.79 285.04,33.57 284.97,33.51 284.87,33.51 284.81,33.57 284.81,34.59 284.35,35.05 284.35,36.1 284.49,36.24 285.04,36.24
+3.3V_MMI on TOP (solid shape): 286.62,28.24 286.62,27.41 287.5,26.53 287.5,24.9 287.28,24.68 286.86,24.68 286.7,24.51 286.34,24.51 286.25,24.59 286.25,25.48 286.68,25.9 286.68,26.76 286.42,27.03 286.42,28.24 286.47,28.3 286.57,28.3
+3.3V_MMI on TOP (solid shape): 289.19,29.32 289.83,29.32 290.03,29.51 290.03,29.51 290.08,29.56 292.65,29.56 293.05,29.16 293.05,28.18 292.91,28.04 292.03,28.04 291.39,28.68 289.09,28.68 288.31,29.46 287.62,29.46 287.57,29.41 287.37,29.41 287.32,29.46 287.32,29.56 287.37,29.61 288.9,29.61
+3.3V_MMI on TOP (solid shape): 282.62,28.24 282.62,27.46 282.16,26.99 282.16,25.19 282.09,25.12 281.45,25.12 281.19,25.38 280.27,25.38 280.1,25.2 280.1,24.29 279.71,23.91 279.71,23.91 279.67,23.87 278.23,23.87 278.23,24.22 278.76,24.22 278.76,24.73 278.23,24.73 278.23,25.02 278.76,25.02 278.76,25.53 278.23,25.53 278.23,26.46 278.84,27.08 280.98,27.08 281.51,27.6 281.71,27.6 282.42,28.31 282.56,28.31
+3.3V_MMI on IN1 (solid shape): outline of 451 points within 279.55,22.8 292.98,37.05
+3.3V_RUN on TOP (solid shape): 166.53,64.88 166.53,63.71 166.29,63.48 165.12,63.48 164.99,63.6 164.99,64.61 165.44,65.07 166.34,65.07
+3.3V_RUN on TOP (solid shape): 225.02,62.58 225.02,61.05 224.86,60.89 224.03,60.89 223.89,61.04 223.89,62.56 224.04,62.72 224.89,62.72
+3.3V_RUN on TOP (solid shape): 115.49,88.56 115.49,86.98 115.17,86.66 114.03,86.66 113.78,86.91 113.78,87.49 113.59,87.68 113.59,88.56 113.74,88.71 115.34,88.71
+3.3V_RUN on TOP (solid shape): 180.46,69 180.46,67.35 180.35,67.23 179.61,67.23 179.51,67.13 178.33,67.13 178.22,67.23 177.58,67.23 177.45,67.36 177.45,68.99 177.53,69.06 180.4,69.06
+3.3V_RUN on TOP (solid shape): 45.01,10.96 45.17,10.96 45.97,10.16 45.97,9.74 45.62,9.39 43.59,9.39 43.48,9.5 43.48,9.95 44.05,9.95 44.05,10.46 43.48,10.46 43.48,10.82 43.63,10.97 45,10.97
+3.3V_RUN on TOP (solid shape): 252.86,20.6 252.86,19.53 252.76,19.43 251.91,19.43 251.13,18.64 247.09,18.64 246.9,18.84 246.9,20.54 247.49,20.54 247.49,20.01 247.93,20.01 247.93,20.54 248.64,20.54 248.9,20.28 250.5,20.28 250.98,20.76 252.7,20.76
+3.3V_RUN on TOP (solid shape): 122.56,87.57 122.56,86.7 122.17,86.31 122.17,84.67 119.59,82.09 118.22,82.09 118.09,82.22 118.09,82.97 118.98,83.86 118.98,84.51 120.2,85.72 120.2,87.07 121.03,87.91 122.22,87.91
+3.3V_RUN on TOP (solid shape): 278.1,26.07 278.1,25.4 278.63,25.4 278.63,25.15 278.1,25.15 278.1,24.6 278.63,24.6 278.63,24.35 278.1,24.35 278.1,23.84 277.94,23.68 277.17,23.68 276.99,23.86 276.99,26.08 277.18,26.27 277.9,26.27
+3.3V_RUN on TOP (solid shape): 221.16,38.66 221.18,38.66 221.18,38.65 221.89,38.65 221.89,38.66 221.91,38.66 221.91,39.17 222.36,39.17 222.36,38.66 222.38,38.66 222.38,38.65 223.13,38.65 223.35,38.43 223.35,37.05 223.1,36.8 219.42,36.8 219.22,37 219.22,38.51 219.36,38.65 220.69,38.65 220.69,38.66 220.71,38.66 220.71,39.17 221.16,39.17
+3.3V_RUN on TOP (solid shape): outline of 214 points within 180.59,61.44 185.2,69.91
+3.3V_RUN on BOTTOM (solid shape): 279.34,4.75 279.34,3.46 279.12,3.25 277.89,3.25 277.68,3.46 277.68,4.76 277.86,4.95 279.14,4.95
+3.3V_RUN on BOTTOM (solid shape): 90.28,60.94 90.28,60.55 89.66,59.94 89.66,58.85 89.59,58.78 89.46,58.78 89.39,58.85 89.39,59.1 89.07,59.42 89.07,61.03 89.08,61.04 90.19,61.04
+3.3V_RUN on BOTTOM (solid shape): 116.75,77.45 116.75,76.07 116.54,75.86 115.44,75.86 115.31,75.98 115.31,76.81 115.88,76.81 115.88,77.32 115.31,77.32 115.31,77.57 115.32,77.57 115.41,77.67 116.53,77.67
+3.3V_RUN on BOTTOM (solid shape): 273.86,14.33 273.86,12.94 273.67,12.75 272.59,12.75 272.32,13.01 272.32,13.67 272.86,13.67 272.86,14.11 272.85,14.11 272.32,14.11 272.32,14.38 272.4,14.46 273.73,14.46
+3.3V_RUN on BOTTOM (solid shape): 180.27,68.75 180.27,65.31 180.2,65.24 179.59,65.24 179.37,65.46 179.37,65.65 179.12,66.25 178.86,65.65 178.86,65.08 179.42,64.52 180.2,64.52 180.31,64.42 180.31,63.14 180.14,62.97 180.14,62.97 180.06,62.89 177.6,62.89 177.55,62.94 177.55,68.72 177.64,68.81 180.21,68.81
+3.3V_RUN on IN2 (solid shape): outline of 200 points within 161.43,63.57 166.56,67.1
+3.3V_RUN on IN2 (solid shape): outline of 211 points within 272.43,2.54 282.16,14.01
+3.3V_RUN on VCC: outline of 179 points within 43.75,9.44 287.21,97.84 ; 1 cut-out
+3.3V_RUN_AUDIO on TOP (solid shape): 39.27,19.69 39.27,19.15 39.22,19.11 37.86,19.11 37.21,18.46 35.91,18.46 35.86,18.51 35.86,18.64 35.91,18.69 36.85,18.69 37.92,19.75 39.2,19.75
+3.3V_RUN_AUDIO on TOP (solid shape): 37.79,15.62 38.99,15.62 39.24,15.37 39.24,14.62 39.11,14.49 38.29,14.49 37.26,15.52 37.26,15.59 36.78,16.07 35.91,16.07 35.86,16.12 35.86,16.23 35.91,16.28 37.13,16.28
+3.3V_RUN_AUDIO on TOP (solid shape): 40.89,11.85 42.51,11.85 43.35,11 43.35,10.31 43.9,10.31 43.9,10.08 43.35,10.08 43.35,9.55 43.26,9.45 41.84,9.45 41.78,9.51 41.78,9.99 41.3,10.47 39.6,10.47 38.59,11.48 38.59,12.31 38.71,12.43 40.31,12.43
+3.3V_RUN_CARD on TOP (solid shape): 286.22,28.24 286.22,27 286.54,26.68 286.54,26 286.13,25.59 286.13,25.5 286.12,25.49 286.12,24.81 286.04,24.72 285.56,24.72 285.46,24.83 285.46,26.69 286.01,27.25 286.01,28.24 286.06,28.3 286.17,28.3
+3.3V_RUN_CARD on BOTTOM (solid shape): 286.51,26.4 286.51,25.93 286.31,25.73 284.61,25.73 284.47,25.87 284.47,26.36 284.71,26.6 286.31,26.6
+3.3V_RUN_UN3 on TOP (solid shape): 256.99,21.83 256.99,21.57 256.45,21.57 256.45,21.13 256.99,21.13 256.99,20.84 256.28,20.13 256.28,19.52 256.23,19.47 254.33,19.47 254.24,19.56 254.24,21.46 254.71,21.93 256.89,21.93
+3.3V_RUN_UZ9 on TOP (solid shape): 223.44,41.61 223.44,39 223.23,38.79 222.49,38.79 222.49,39.3 221.78,39.3 221.78,38.79 221.29,38.79 221.29,39.3 220.58,39.3 220.58,38.79 219.33,38.79 219.08,39.03 218.18,39.03 218.03,39.19 218.03,40 217.79,40.24 217.79,41.18 217.88,41.27 218.51,41.27 219.07,41.83 223.22,41.83
+3.3V_TP on TOP (solid shape): 248.37,22.24 248.37,20.83 248.24,20.7 247.81,20.7 247.8,20.7 247.8,20.14 247.62,20.14 247.62,20.67 247.62,20.7 246.2,20.7 246.08,20.82 246.08,22.14 246.3,22.35 248.26,22.35
+3.3V_TSP on TOP (solid shape): 119.94,86.81 119.94,85.77 119.68,85.51 118.5,85.51 118.26,85.75 118.26,86.8 118.54,87.08 119.67,87.08
+3.3V_TSP on TOP (solid shape): 101.03,85.48 101.03,84.03 100.86,83.86 99.52,83.86 99.26,84.13 99.26,85.4 99.55,85.69 100.82,85.69
+3.3V_TSP on BOTTOM (solid shape): 99.08,90.89 99.08,89.57 99.36,89.29 99.36,87.99 98.43,87.05 98.43,85.51 98.59,85.35 100.75,85.35 100.96,85.14 100.96,83.93 100.8,83.77 97.7,83.77 97.29,84.18 97.29,87.3 98.16,88.17 98.16,90.74 98.37,90.96 99.01,90.96
+3.3V_TSP on IN1 (solid shape): 120.04,87.67 120.04,85.83 119.8,85.58 111.2,85.58 109.3,83.69 100.65,83.69 100.3,84.03 100.3,86.11 100.58,86.38 107.74,86.38 109.25,87.89 119.82,87.89
+3.3V_WLAN on TOP (solid shape): 245.2,13.29 245.2,12.01 245.12,11.93 242.72,11.93 242.62,12.03 242.62,12.84 242.82,13.04 242.82,13.58 243.13,13.88 244.61,13.88
+3.3V_WLAN on TOP (solid shape): 246.11,26.93 246.62,26.93 246.62,27.5 247.21,27.5 247.34,27.38 247.34,26.03 247.15,25.84 244.03,25.84 243.9,25.97 243.9,27.35 244.05,27.5 246.11,27.5
+3.3V_WLAN on TOP (solid shape): 243.22,37.92 243.22,35.51 243.7,35.03 243.7,34.31 243.7,34.31 243.7,31.7 242.86,30.86 242.44,30.86 242.43,30.85 241.37,30.85 241.24,30.98 241.24,33.95 241.42,34.14 242.06,34.14 242.24,34.31 242.24,35.08 242.77,35.61 242.77,36.11 242.77,36.11 242.77,37.44 242.77,37.44 242.77,37.94 242.85,38.02 243.12,38.02
+3.3V_WLAN on BOTTOM (solid shape): 243.76,34.24 243.76,32.91 243.42,32.56 242.04,32.56 241.67,32.94 240.2,32.94 240.09,33.04 240.09,34.09 240.5,34.5 243.5,34.5
+3.3V_WLAN on BOTTOM (solid shape): 241.94,16.26 242.31,16.26 244.66,13.91 244.66,13.18 244.52,13.04 242.35,13.04 240.08,15.31 240.08,16.15 240.2,16.27 241.93,16.27
+3.3V_WLAN on IN1 (solid shape): 244.92,17.65 244.92,13.54 244.49,13.11 242.68,13.11 242.29,13.5 242.29,17.6 242.54,17.85 244.71,17.85
+3.3V_WLAN on IN1 (solid shape): 243.85,33.47 243.85,31.96 242.36,30.47 242.36,29.51 242.58,29.29 242.58,27.81 243.19,27.21 245.72,27.21 246.27,26.66 246.27,25.52 245.16,24.41 241.9,24.41 240.3,26.01 240.3,28.02 239.87,28.46 239.87,31.44 239.92,31.49 239.97,31.55 242.19,33.76 243.57,33.76
+3.3V_WLAN_UZ3 on TOP (solid shape): 246.94,29.85 246.94,27.72 246.89,27.67 246.47,27.67 246.45,27.66 246.45,27.12 246.44,27.1 246.29,27.1 246.28,27.12 246.28,27.67 244.94,27.67 244.84,27.77 244.84,29.6 244.99,29.76 245.59,29.76 245.77,29.93 246.85,29.93
+3V5V_PWR_SRC on TOP (solid shape): 222.68,60.19 222.68,57.51 222.42,57.26 218.75,57.26 218.58,57.43 214.32,57.43 214.21,57.54 214.21,59.97 215.43,61.19 221.68,61.19
+3V5V_PWR_SRC on BOTTOM (solid shape): 218.94,65.53 218.94,64.12 219.52,63.54 219.52,57.76 219.2,57.44 217.17,57.44 216.91,57.7 216.91,58.9 215.25,60.57 215.25,62.06 215.79,62.06 215.79,62.81 215.25,62.81 215.25,63.26 215.79,63.26 215.79,64.01 215.25,64.01 215.25,65.48 215.65,65.88 218.58,65.88
+5V_ALW on TOP (solid shape): 286.88,40.81 286.88,39.26 286.83,39.2 286.51,39.2 286.26,39.46 285.25,39.46 285.01,39.7 285.01,40.66 285.25,40.91 286.79,40.91
+5V_ALW on TOP (solid shape): 290.88,43.63 290.88,42.19 290.76,42.07 288.68,42.07 288.61,42.14 288.61,42.8 289.61,43.8 290.71,43.8
+5V_ALW on TOP (solid shape): 91.04,83.95 91.04,82.15 90.8,81.9 89.45,81.9 89.2,82.15 89.2,83.87 89.33,83.99 91,83.99
+5V_ALW on TOP (solid shape): 207.4,44.08 208.15,44.08 208.15,44.6 208.6,44.6 208.6,44.08 209.35,44.08 209.35,44.6 212.7,44.6 212.88,44.42 215.23,44.42 216.39,43.26 216.39,42.58 216.35,42.53 215.79,42.53 215.68,42.43 215.68,41.64 215.54,41.5 213.6,41.5 213.18,41.07 213.18,36.96 212.92,36.71 209.99,36.71 209.44,37.26 207.92,38.78 207.92,42.05 206.33,43.64 206.33,44.4 206.52,44.6 207.4,44.6
+5V_ALW on BOTTOM (solid shape): 90.83,83.76 92.36,83.76 92.49,83.62 92.49,82.84 92.38,82.72 90.79,82.72 90.6,82.53 90.6,82.05 90.44,81.9 89.45,81.9 89.2,82.15 89.2,83.48 89.58,83.87 90.73,83.87
+5V_ALW on BOTTOM (solid shape): 261.83,93.33 261.83,92.37 261.69,92.22 261.12,92.22 260.88,91.98 260.88,91.35 260.71,91.19 260.71,90.79 260.33,90.41 256.78,90.41 255.77,91.42 254.4,91.42 254.3,91.52 254.3,92.33 254.42,92.45 256.31,92.45 256.56,92.2 258.7,92.2 258.94,92.44 258.94,92.91 259.03,93 259.46,93 260.1,93.64 261.53,93.64
+5V_ALW on IN1 (solid shape): outline of 273 points within 40.41,5.36 233.18,7.71
+5V_ALW on IN2 (solid shape): outline of 173 points within 40.41,5.36 233.18,7.73
+5V_ALW on VCC: outline of 180 points within 1.02,1.02 303.73,95.58 ; 2 cut-outs
+5V_ALWP on TOP (solid shape): 210.24,48.23 210.24,44.92 210.05,44.73 209.23,44.73 209.23,44.2 208.73,44.2 208.73,44.73 208.03,44.73 208.03,44.2 207.53,44.2 207.53,44.73 206.5,44.73 206.17,45.06 206.17,48.28 206.44,48.55 209.91,48.55
+5V_ALWP on BOTTOM (solid shape): 210.87,58.37 210.87,54.34 210.44,53.91 210.44,52.33 210.87,51.9 210.87,50.27 210.74,50.15 210.74,47.61 210.42,47.29 205.85,47.29 205.6,47.54 205.6,50.01 205.93,50.34 207.43,50.34 207.73,50.65 207.73,58.36 207.86,58.49 210.74,58.49
+5V_HDD on BOTTOM (solid shape): 272.55,12.23 272.55,11.77 272.57,11.75 273.11,11.75 273.11,11.57 272.55,11.57 272.55,10.5 272.59,10.46 272.59,9.87 270.18,7.47 267.23,7.47 267.07,7.32 267.07,6.25 266.98,6.16 265.89,6.16 265.8,6.25 265.8,8.89 265.81,8.9 265.81,9.09 266.1,9.38 268.41,9.38 268.85,9.82 268.85,10.22 268.96,10.33 270.37,10.33 271.64,11.6 271.64,11.92 271.84,12.13 271.84,12.28 271.92,12.36 272.43,12.36
+5V_RUN on TOP (solid shape): 66.38,88.98 66.38,86.47 65.43,85.52 65.07,85.52 63.71,86.88 63.71,87.01 64.43,87.73 64.43,88.85 64.84,89.26 66.1,89.26
+5V_RUN on TOP (solid shape): 41.56,9.91 41.56,8.3 41.38,8.13 39.64,8.13 39.64,8.59 39.63,8.6 39.09,8.6 39.09,8.85 39.61,8.85 39.61,8.87 39.62,8.87 39.62,9.38 39.61,9.38 39.61,9.4 39.09,9.4 39.09,9.65 39.61,9.65 39.61,9.67 39.62,9.67 39.62,10.14 41.32,10.14
+5V_RUN on TOP (solid shape): outline of 137 points within 215.21,17.43 227.97,35.86
+5V_RUN on BOTTOM (solid shape): 225.55,93.99 225.55,92.53 224.21,91.2 222.97,91.2 222.87,91.3 222.87,92.14 223.4,92.67 223.4,93.93 223.69,94.22 225.33,94.22
+5V_RUN on BOTTOM (solid shape): 106.51,58.54 106.51,58 106.37,57.86 105.34,57.86 104.56,57.09 103.33,57.09 103.27,57.14 103.27,57.23 103.34,57.3 104.21,57.3 104.95,58.03 104.95,58.64 105.01,58.7 106.35,58.7
+5V_RUN on BOTTOM (solid shape): 66.33,89.05 66.33,86.15 64.8,84.62 64.48,84.62 64.05,85.05 64.05,85.34 64.86,86.16 64.86,88.98 65.15,89.27 66.12,89.27
+5V_RUN on BOTTOM (solid shape): 274.7,12.19 274.7,11.05 274.43,10.78 272.91,10.78 272.72,10.97 272.7,10.98 272.7,11.42 273.27,11.42 273.27,11.9 272.7,11.9 272.7,12.29 272.84,12.43 274.46,12.43
+5V_RUN on IN1 (solid shape): outline of 155 points within 215.68,91.75 226.89,96.22
+5V_RUN on IN1 (solid shape): outline of 254 points within 240.14,78.16 253.86,89.86
+5V_RUN on IN1 (solid shape): outline of 1291 points within 64.9,79.5 99.15,97.27
+5V_RUN on IN1 (solid shape): outline of 1896 points within 256.53,7.77 280.73,81.62
+5V_RUN on IN2 (solid shape): 66.53,89.03 66.53,87.53 66.7,87.36 68.31,87.36 68.67,87.01 68.67,85.15 68.39,84.87 65.31,84.87 64.75,85.43 64.75,89.07 64.91,89.23 66.33,89.23
+5V_RUN on IN2 (solid shape): outline of 169 points within 34.14,8.45 41.64,16.34
+5V_RUN on IN2 (solid shape): outline of 295 points within 275.99,77.89 286.29,82.35
+5V_RUN on IN2 (solid shape): outline of 354 points within 225.51,10.35 258.06,20.72
+5V_RUN on IN2 (solid shape): outline of 734 points within 75.92,61.24 90.09,88.21
+5V_RUN_AUDIO on TOP (solid shape): 39.48,9.78 38.96,9.78 38.96,9.27 39.48,9.27 39.48,8.98 38.96,8.98 38.96,8.47 39.48,8.47 39.48,8.14 39.44,8.1 36.75,8.1 36.62,8.22 36.62,9.63 37.26,9.63 37.77,10.14 39.48,10.14
+5V_RUN_PVDD on TOP (solid shape): 32.76,14.91 32.76,13.15 32.76,12.99 32.6,12.83 32.6,12.65 32.54,12.59 32.15,12.59 32.07,12.67 32.07,12.98 32.55,13.46 32.55,14.9 32.62,14.97 32.7,14.97
+5V_RUN_PVDD on TOP (solid shape): 34.77,14.9 34.77,13.99 35.28,13.48 35.34,13.48 35.35,13.47 35.97,13.47 36.18,13.27 36.18,10.18 35.85,9.84 35.85,8.33 35.75,8.23 34.92,8.23 34.92,8.23 34.86,8.23 34.67,8.42 34.67,8.45 34.61,8.5 34.61,8.52 34.57,8.61 34.51,8.69 34.51,10.93 34.66,11.08 34.67,11.08 34.97,11.48 34.63,11.84 34.58,11.84 34.58,13.07 34.55,13.09 34.55,14.91 34.62,14.97 34.71,14.97
+5V_RUN_UZ9 on TOP (solid shape): 216.4,41.18 216.4,40.48 216.04,40.11 216.04,37.32 215.87,37.16 215.87,36.27 215.08,35.47 215.08,34.68 215.59,34.68 215.59,34.18 215.08,34.18 215.08,33.48 215.59,33.48 215.59,32.98 215.08,32.98 215.08,31.98 214.78,31.69 213.27,31.69 212.51,32.44 212.51,36.11 212.73,36.32 213.12,36.32 213.48,36.69 213.48,40.99 213.75,41.26 216.33,41.26
+5V_USB_CHG_PWR on TOP (solid shape): 285.87,55.9 286.67,55.9 289.44,53.14 289.44,51.56 289.16,51.28 287.23,51.28 286.9,51.61 286.9,51.62 285.53,52.93 283.7,53.41 283.58,53.41 283.55,53.41 281.81,52.9 280.5,51.63 280.5,51.62 279.94,49.64 280.51,47.66 281.2,46.84 282.08,46.25 282.09,46.25 282.46,45.88 286.26,45.88 286.51,45.63 286.51,44.63 286.88,44.26 286.88,43.11 286.82,43.06 286.6,43.06 286.44,43.22 281.06,43.22 277.16,47.12 277.16,52.82 280.5,56.16 285.62,56.16
+GND_CHASSIS on TOP (solid shape): 281.65,90.12 281.65,89.14 281.39,88.88 279.46,88.88 277.58,90.76 267.78,90.76 267.65,90.9 267.65,91.7 267.65,91.7 267.65,91.87 267.85,92.07 279.7,92.07
+GND_CHASSIS on BOTTOM (solid shape): 282.92,91.05 282.92,88.7 282.78,88.56 281.04,88.56 280.87,88.72 280.87,90.99 281.08,91.2 282.76,91.2
+V1.05S_APLLOPI on BOTTOM (solid shape): 173.18,84.36 173.18,80.57 173.06,80.45 171.78,80.45 171.71,80.53 171.71,82.33 171.51,82.53 170.99,82.53 170.9,82.61 170.9,83.35 171.16,83.61 171.16,84.17 171.45,84.47 173.07,84.47
+V1.05S_APLLOPI on BOTTOM (solid shape): 159.33,62.93 159.33,62.59 159.33,62.58 159.29,62.42 159.33,62.27 159.33,62.26 159.33,61.94 159.19,61.79 159.02,61.79 158.93,61.91 158.8,61.97 158.79,61.97 158.51,62.25 158.51,62.58 158.39,62.7 158.39,63 158.48,63.15 158.48,63.33 158.47,63.36 158.56,63.45 158.81,63.45
+V1.05SP_B+ on BOTTOM (solid shape): 210.62,66.51 210.62,64.79 210.52,64.69 210.18,64.69 210.18,65.21 209.63,65.21 209.63,64.69 209.38,64.69 209.38,65.21 208.83,65.21 208.83,64.69 203.86,64.69 203.6,64.43 203.6,63.08 204.16,62.53 204.16,61.63 204.14,61.61 202.05,61.61 201.41,62.25 199.7,62.25 199.32,61.87 198.57,61.87 198.45,62 198.45,63.01 200.37,64.92 200.37,66.57 200.5,66.7 210.43,66.7
+VCC_CORE on TOP (solid shape): outline of 4311 points within 111.68,47.92 157.83,73.85
+VCC_CORE on BOTTOM (solid shape): outline of 142 points within 111.19,47.67 125.22,67.83
+VCC_CORE on BOTTOM (solid shape): outline of 1280 points within 135.7,58.9 158.25,71.66
+VCC_CORE on IN1 (solid shape): outline of 3133 points within 112.05,47.94 155.18,72.29
+VCC_CORE on IN2 (solid shape): outline of 500 points within 135.19,58.37 156.06,69.82
+VCC_CORE on IN2 (solid shape): outline of 894 points within 112.07,48.08 125.03,68.91
+VCC_PWR_SRC on TOP (solid shape): 99.55,53.39 99.55,49.7 99.88,49.37 99.88,48.87 99.76,48.74 98.23,48.74 97.96,49.01 97.96,52.69 97.97,52.69 97.97,53.43 98.23,53.7 99.25,53.7
+VCC_PWR_SRC on BOTTOM (solid shape): 100.67,56.51 100.67,53.68 99.81,52.81 99.81,45.89 99.36,45.45 95.55,45.45 94.98,46.02 94.98,50.97 95.52,50.97 95.52,51.68 94.98,51.68 94.98,52.17 95.52,52.17 95.52,52.88 94.98,52.88 94.98,54.11 95.51,54.64 97.31,54.64 98.09,55.42 98.09,56.12 98.47,56.5 99.74,56.5 99.76,56.52 100.66,56.52
+VDDA_AVDD1 on TOP (solid shape): 29,20.52 29,19.67 29.57,19.1 30.59,19.1 30.65,19.03 30.65,18.92 30.6,18.87 29.23,18.87 27.93,20.17 26.03,20.17 25.89,20.31 25.89,20.73 26.03,20.87 28.65,20.87
+VDDA_PVDD on TOP (solid shape): 31.56,14.91 31.56,14.03 31.04,13.51 30.39,13.51 29.72,12.85 29.72,12.59 29.62,12.49 29.61,12.49 29.56,12.43 29.28,12.43 29.02,12.17 29.02,9.96 28.88,9.82 26.98,9.82 26.98,10.45 28.06,10.45 28.25,10.64 28.25,11.85 28.06,12.04 28.06,12.75 28.27,12.95 29.26,12.95 29.26,13.12 30.06,13.92 31.14,13.92 31.35,14.12 31.35,14.9 31.41,14.97 31.5,14.97
GND on TOP (solid shape): 94.97,25.94 94.97,23.11 94.82,22.96 92.15,22.96 92.15,25.79 92.35,26 94.92,26
GND on TOP (solid shape): 146.28,47.05 146.28,43.7 145.86,43.28 144.84,43.28 144.51,43.61 144.51,46.97 144.69,47.16 146.17,47.16
GND on TOP (solid shape): 151.04,46.98 151.04,43.41 150.92,43.28 149.32,43.28 149.17,43.43 149.17,47.03 149.28,47.14 150.89,47.14
GND on TOP (solid shape): 230.12,83.51 230.12,78.87 229.93,78.67 223.67,78.67 223.43,78.91 223.43,83.63 223.56,83.76 229.88,83.76
GND on TOP (solid shape): 256.89,54.09 256.89,53.08 256.8,52.99 253.53,52.99 253.43,53.09 253.43,54.15 253.54,54.26 256.72,54.26
GND on TOP (solid shape): 61.71,103.12 62.44,103.12 62.57,102.99 62.57,102.11 62.44,101.98 60.78,101.98 60.35,102.4 60.35,103.22 60.58,103.45 61.38,103.45
GND on TOP (solid shape): 78.04,81.51 78.04,80.49 77.76,80.21 76.97,80.21 76.82,80.37 76.82,81.56 76.9,81.64 77.91,81.64
GND on TOP (solid shape): 158.65,79.95 158.65,77.79 158.27,77.41 155.72,77.41 155.43,77.7 155.43,79.79 155.66,80.02 158.59,80.02
GND on TOP (solid shape): 162.32,85.52 162.74,85.52 162.84,85.42 162.84,84.8 162.69,84.64 160.99,84.64 160.86,84.77 160.86,85.61 161.15,85.9 161.94,85.9
GND on TOP (solid shape): 200.53,54.42 200.53,50.08 200.43,49.98 198.76,49.98 198.43,50.3 198.43,54.04 198.44,54.4 198.6,54.57 200.38,54.57
GND on TOP (solid shape): 207.76,51.96 207.76,50.2 207.5,49.94 205.57,49.94 205.46,50.04 205.46,53.12 205.53,53.18 206.54,53.18
GND on TOP (solid shape): 103.32,57.78 103.32,48.84 102.59,48.11 100.52,48.11 100.26,48.36 100.26,49.38 100.44,49.55 100.44,57.68 100.77,58.01 103.09,58.01
GND on TOP (solid shape): 164.95,79.31 164.95,77.36 164.61,77.02 163.52,77.02 163.36,77.18 163.36,79.93 163.42,79.98 164.27,79.98
GND on TOP (solid shape): 282.51,41.59 283.72,41.59 283.88,41.43 283.88,40.54 283.61,40.27 281.84,40.27 280.85,41.26 280.85,42.02 281.18,42.35 281.75,42.35
GND on TOP (solid shape): 52.07,16.83 52.07,13.82 50,11.75 46.34,11.75 45.94,12.15 44.49,12.15 44.29,12.36 44.29,15.8 45.45,16.96 51.93,16.96
GND on TOP (solid shape): 105.95,68.42 105.95,65.67 105.91,65.63 103.44,65.63 103.43,65.64 103.16,65.64 103.15,65.65 103.15,68.41 103.17,68.43 105.93,68.43
GND on TOP (solid shape): 140.4,47.03 140.4,46.12 138.83,44.55 138.3,44.55 138.14,44.71 138.14,45.2 139.73,46.79 139.73,47.02 139.78,47.07 140.35,47.07
GND on TOP (solid shape): 209.34,29.59 209.34,23.17 206.55,20.37 204.32,20.37 204.15,20.54 204.15,22.57 206.4,24.82 206.4,29.46 206.8,29.87 209.06,29.87
GND on TOP (solid shape): 68.43,11.29 68.43,6.97 68.28,6.81 66.63,6.81 66.55,6.9 66.55,8.29 66.8,8.55 66.8,11.37 66.87,11.44 68.27,11.44
GND on TOP (solid shape): 38.28,11.94 38.28,10.49 38.15,10.37 37.75,10.37 37.32,9.95 36.36,9.95 36.32,9.98 36.32,11.03 36.45,11.16 36.45,11.94 36.57,12.06 38.15,12.06
GND on TOP (solid shape): 202.49,61.05 202.49,59.42 202.36,59.29 201.09,59.29 200.96,59.16 200.96,58.47 200.68,58.18 200.03,58.18 199.88,58.33 199.88,61.98 200.01,62.1 201.43,62.1
GND on TOP (solid shape): 65.59,22.96 65.59,19.09 65.47,18.96 64.32,18.96 64.01,18.64 64.01,17.69 61.8,17.69 61.04,18.45 61.04,21.45 62.68,23.09 65.47,23.09
GND on TOP (solid shape): 86.09,66.12 86.09,66.11 87.23,64.97 87.23,64.29 88.53,62.99 91.2,62.99 91.47,62.71 91.47,61.78 91.04,61.36 88.37,61.36 85.03,64.69 81.21,64.69 81.14,64.76 81.14,66.02 81.33,66.21 85.99,66.21
GND on TOP (solid shape): 222.93,56.43 222.93,54.42 222.83,54.32 221.39,54.32 220.84,53.77 217.09,53.77 215.82,52.5 210.36,52.5 209.72,53.13 209.72,53.96 210.81,53.96 211.38,53.39 215.25,53.39 215.49,53.63 215.49,55.33 215.61,55.45 216.66,55.45 217.09,55.88 217.09,56.62 217.34,56.88 222.49,56.88
GND on TOP (solid shape): 90.01,85.83 90.46,85.56 90.95,85.35 91.76,85.16 92.61,85.16 92.61,84.5 92.48,84.37 88.64,84.37 88.45,84.56 88.45,85.19 88.6,85.34 88.96,85.34 89.46,85.83
GND on TOP (solid shape): 76.05,76.42 78.63,76.42 79.72,75.33 79.72,67.65 77.87,65.8 70.37,65.8 70.04,66.13 70.04,66.25 70.04,66.26 70.04,70.14 70.33,70.44 71.43,70.44 72.63,70.44 73.47,71.28 73.47,74.26 73.64,74.43 74.37,74.43 74.75,74.81 74.75,76.3 74.49,76.56 73.6,76.56 73.52,76.64 73.52,77.36 73.65,77.49 74.97,77.49
GND on TOP (solid shape): 16.12,16.78 17.27,16.78 17.42,16.62 17.42,16.45 17.29,16.32 16.86,16.32 16.86,16.32 15.65,16.32 15.33,16.63 14.67,16.63 14.12,16.08 14.12,15.31 14.06,15.25 14.06,13.96 14.25,13.78 15.58,13.78 16.43,13.78 16.5,13.71 17.6,13.71 17.79,13.53 17.79,13.19 17.7,13.1 17.32,13.1 17.27,13.11 17.2,13.11 17.12,13.19 16.16,13.19 16.09,13.26 13.72,13.26 13.39,13.59 13.39,15.36 13.59,15.56 13.8,15.88 13.89,16.11 13.98,16.41 13.98,17.15 14.25,17.43 15.47,17.43
GND on TOP (solid shape): 188.92,41.07 188.92,37.68 188.58,37.34 179.88,37.34 179.65,37.57 179.65,40.93 182.04,40.93 182.04,40.87 182.05,40.82 182.06,40.77 182.09,40.72 182.12,40.68 182.15,40.64 182.19,40.61 182.24,40.58 182.29,40.56 182.34,40.55 182.39,40.54 182.45,40.55 182.5,40.56 182.55,40.58 182.6,40.61 182.64,40.64 182.67,40.68 182.7,40.72 182.73,40.77 182.74,40.82 182.75,40.87 182.75,40.93 182.74,40.98 182.73,41.03 182.7,41.08 182.67,41.12 182.64,41.16 182.6,41.2 182.55,41.22 182.5,41.24 182.45,41.25 182.39,41.26 182.34,41.25 182.29,41.24 182.24,41.22 182.19,41.2 182.15,41.16 182.12,41.12 182.09,41.08 182.06,41.03 182.05,40.98 182.04,40.93 179.65,40.93 179.65,41.12 180.09,41.56 188.43,41.56
GND on TOP (solid shape): 295.11,70.44 295.38,70.01 295.85,69.85 298.54,69.85 301.15,69.85 301.32,69.77 301.4,69.6 301.4,63.45 301.32,63.28 301.15,63.2 298.24,63.2 298.24,63.21 297.57,63.21 297.57,63.2 292.46,63.2 291.66,63.7 291,63.03 291,62.95 291,61.86 275.92,61.86 275.44,62.34 275.44,65.54 276.05,66.15 282.86,66.15 283.49,65.52 287.35,65.52 292.27,70.44
GND on TOP (solid shape): 284.12,93.92 284.23,93.9 284.35,93.9 302.4,93.9 302.79,93.79 303.06,93.49 303.12,93.33 303.15,93.16 303.15,92.5 303.14,92.5 303.14,80.62 303.15,80.62 303.15,80 302.93,79.47 302.4,79.25 301.29,79.25 301.29,79.26 295.85,79.26 295.28,79 295.1,78.4 292.27,78.4 291.26,79.41 291.26,80.54 291.85,81.13 298.89,81.13 299.15,81.38 299.15,82.91 298.89,83.16 295.84,83.16 295.72,83.29 295.72,84.68 297.75,86.72 297.75,88.11 297.49,88.37 294.95,88.37 294.7,88.11 294.7,86.84 294.81,86.73 294.81,85.48 294.14,84.81 290.38,84.81 284.72,90.47 284.72,91.92 283.72,92.92 283.72,93.53
GND on TOP (solid shape): 233.25,109.25 233.75,109.05 234,108.57 234.02,108.34 235.59,108.34 235.59,98.3 235.62,98.1 235.7,97.92 235.7,96.8 235.18,96.28 233.06,96.28 232.65,96.68 232.65,100.24 231.83,101.07 230.06,101.07 229.34,100.35 229.34,96.59 229.02,96.27 227.36,96.27 226.24,97.38 222.18,97.38 221.68,97.89 221.68,101.19 222.35,101.19 223.41,100.99 223.21,102.05 223.21,108.29 224.94,108.29 224.95,108.54 225.19,109.04 225.7,109.25
GND on TOP (solid shape): 253.09,107.5 257.35,103.25 261.61,107.5 261.61,108.62 263.89,108.62 263.89,101.83 263.6,101.53 256.85,101.53 251.92,96.6 250.43,96.6 250.01,97.03 250.01,108.34 251.58,108.34 251.6,108.57 251.85,109.05 252.34,109.25 253.09,109.25
GND on TOP (solid shape): outline of 108 points within 56.38,82.41 65.1,91.15
GND on TOP (solid shape): outline of 106 points within 92.15,18.57 97.7,26
GND on TOP (solid shape): 0.76,9.21 0.93,9.04 1.99,9.04 2.07,8.96 2.07,6.2 2.41,5.86 9.78,5.86 10.04,6.12 10.04,8.93 10.17,9.06 11.41,9.06 11.48,9 11.48,6.15 11.76,5.86 28.84,5.86 28.84,6.1 31.4,8.66 33.96,6.1 33.96,5.86 39.03,5.86 39.03,5.36 34.17,5.36 33.45,5.35 33.45,6.1 31.4,8.15 29.35,6.1 29.35,5.35 28.56,5.35 1.87,5.36 1,5.35 0.47,5.57 0.25,6.1 0.25,6.85 0.26,6.85 0.26,13.18 0.76,13.18
GND on TOP (solid shape): outline of 269 points within 89.67,86.72 208.72,109.25
GND on TOP (solid shape): 54.69,109.25 75.15,109.25 75.65,109.05 75.9,108.57 75.92,108.34 77.49,108.34 77.49,98.3 77.51,98.17 77.54,98.04 77.38,97.88 77.38,97.03 76.97,96.62 75.6,96.62 75.18,97.04 75.18,105.8 73.9,107.09 66.25,107.09 65.48,107.86 63.52,107.86 63.08,107.42 63.08,106.13 62.69,105.74 60.46,105.74 57.77,103.05 53.46,103.05 53.26,102.85 52.75,101.6 51.5,101.09 49.76,101.09 49.76,89.73 49.83,89.56 50,89.49 53.2,89.49 53.98,89.38 54.69,89.06 61.46,83.42 66.59,76.25 66.92,75.12 66.74,73.95 65.82,71.57 65.74,71.14 65.81,70.7 65.94,70.34 66.07,69.98 66.07,69.97 66.34,69.14 61.56,40.9 36,27.99 33.97,27.99 33.97,28.49 36,28.49 61.08,41.09 65.94,68.73 65.71,69.48 65.59,69.82 65.46,70.17 65.34,70.52 65.23,71.14 65.35,71.75 66.27,74.13 66.41,75.08 66.15,76.01 61.09,83.07 54.41,88.63 53.83,88.9 53.2,88.99 50,88.99 49.47,89.21 49.25,89.73 49.25,101.35 49.33,101.52 49.5,101.6 51.5,101.6 52.39,101.96 52.75,102.85 52.75,108.5 52.97,109.03 53.5,109.25 54.68,109.25
GND on TOP (solid shape): outline of 653 points within 234,0.25 304.5,52.44
GND on BOTTOM (solid shape): 67.37,28.68 67.37,25.5 66.86,24.99 63.37,24.99 63.12,25.24 63.12,28.75 63.31,28.93 67.12,28.93
GND on BOTTOM (solid shape): 67.57,108.36 67.57,106.96 67.42,106.82 62.81,106.82 62.66,106.97 62.66,108.31 62.82,108.47 67.46,108.47
GND on BOTTOM (solid shape): 72.75,11.41 71.48,11.41 71.29,11.6 71.29,12.62 71.48,12.81 72.75,12.81
GND on BOTTOM (solid shape): 110.65,59.64 110.65,55.87 110.36,55.58 107.69,55.58 107.39,55.88 107.39,59.85 107.57,60.03 110.26,60.03
GND on BOTTOM (solid shape): 124.35,63.3 124.35,62.09 124.2,61.94 116.19,61.94 115.99,62.14 115.99,63.25 116.21,63.47 124.18,63.47
GND on BOTTOM (solid shape): 214.52,50.02 214.52,48.4 213.41,47.29 211.5,47.29 210.94,47.85 210.94,49.85 211.44,50.34 214.2,50.34
GND on BOTTOM (solid shape): 219.06,50.02 219.06,48.24 218.87,48.05 217.73,48.05 217.53,48.24 217.53,50.08 217.73,50.27 218.8,50.27
GND on BOTTOM (solid shape): 225.03,49.96 225.03,47.54 224.9,47.42 221.9,47.42 221.57,47.74 221.57,49.91 222.03,50.37 224.61,50.37
GND on BOTTOM (solid shape): 250.12,87.9 250.12,85.1 249.94,84.92 248.89,84.92 248.75,85.06 248.75,87.89 248.97,88.11 249.91,88.11
GND on BOTTOM (solid shape): 258.37,87.17 258.37,83.38 258.31,83.32 254.42,83.32 254.1,83.64 254.1,87.06 254.42,87.38 258.16,87.38
GND on BOTTOM (solid shape): 111.19,77.52 111.19,75.67 111.06,75.54 110.3,75.54 110.17,75.67 110.17,77.48 110.31,77.61 111.09,77.61
GND on BOTTOM (solid shape): 123.05,59.95 123.05,59.09 122.86,58.9 117.69,58.9 117.5,59.09 117.5,59.98 117.6,60.09 122.91,60.09
GND on BOTTOM (solid shape): 123.19,69.77 123.19,68.35 122.89,68.06 117.32,68.06 116.92,68.46 116.92,69.67 117.27,70.02 122.93,70.02
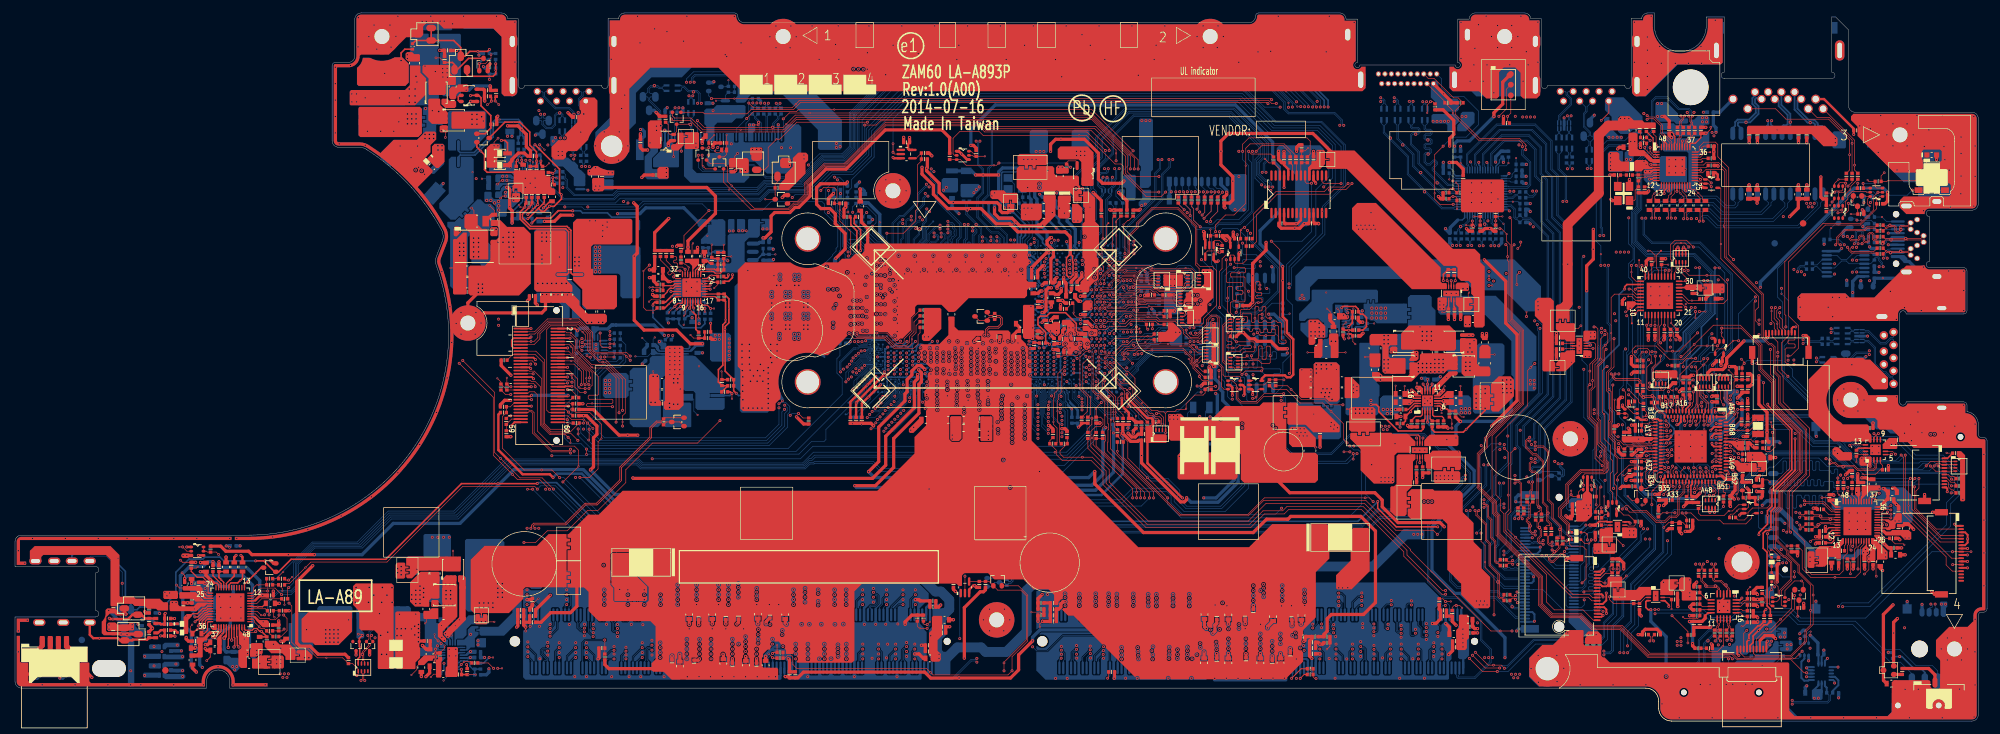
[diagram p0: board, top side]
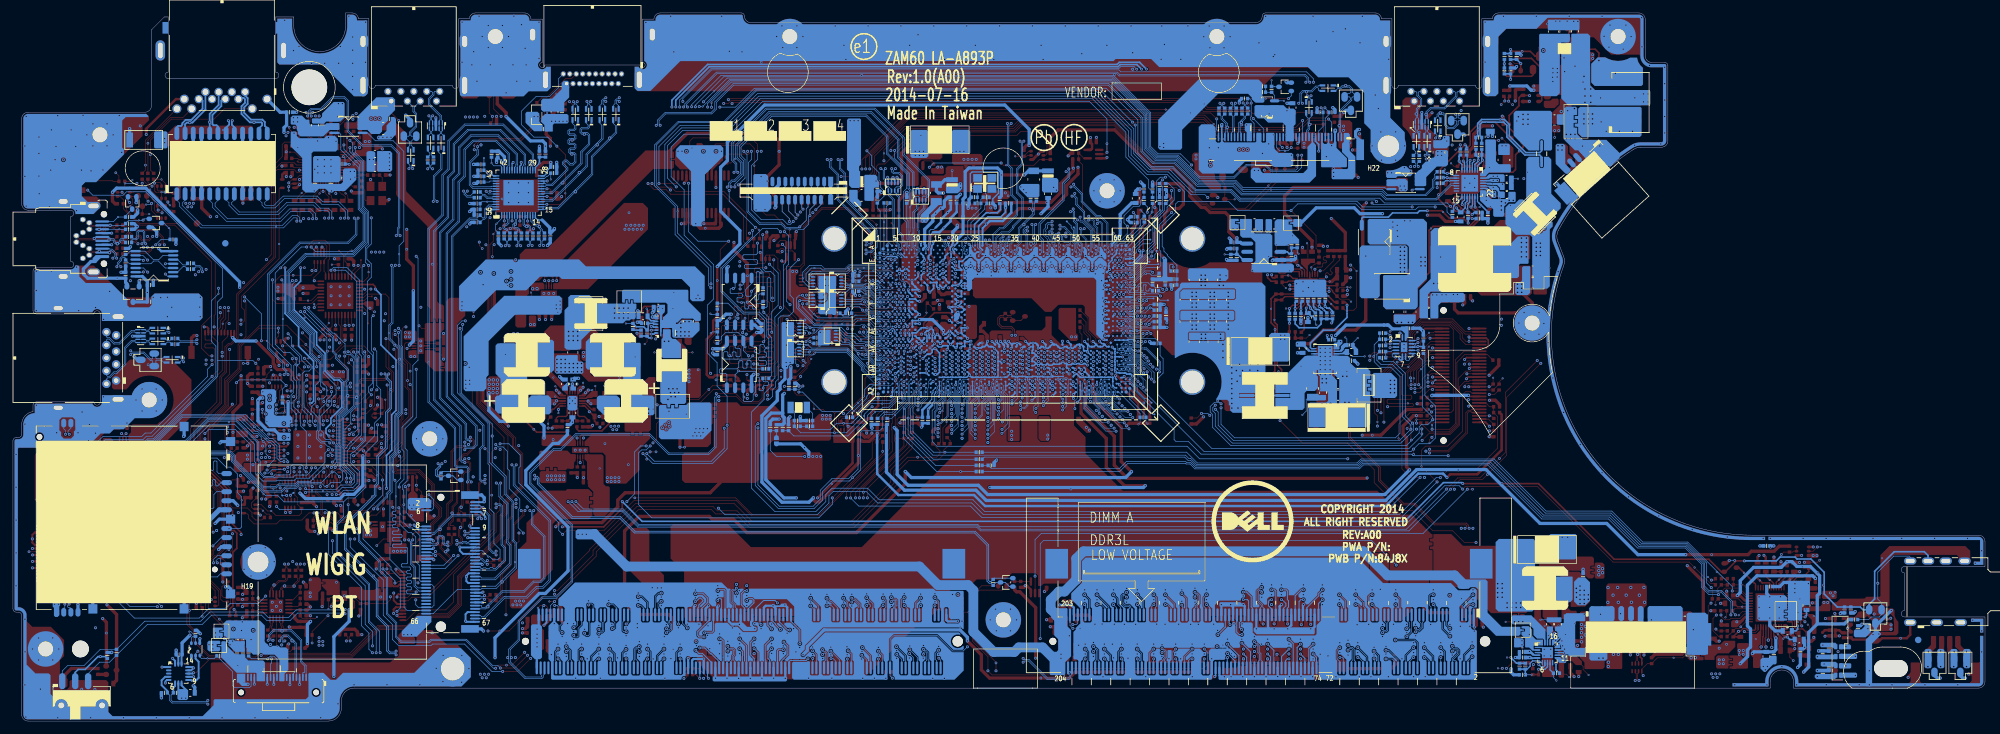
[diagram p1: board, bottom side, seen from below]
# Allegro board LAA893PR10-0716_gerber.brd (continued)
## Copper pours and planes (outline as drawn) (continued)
GND on BOTTOM (solid shape): 149.25,82.7 149.25,82.27 147.95,80.98 146.33,80.98 146.12,81.19 146.12,82.94 146.24,83.06 148.89,83.06
GND on BOTTOM (solid shape): 159.64,91.21 159.64,88.02 159.34,87.72 157.2,87.72 157.19,87.72 156.96,87.72 156.8,87.89 156.8,91.12 157.12,91.44 159.41,91.44
GND on BOTTOM (solid shape): 24.47,8.1 26.02,8.1 26.17,7.95 26.17,7.67 26.02,7.52 23.94,7.52 23.76,7.7 23.76,8.08 23.86,8.18 24.39,8.18
GND on BOTTOM (solid shape): 25.94,11.02 25.94,10.69 25.84,10.59 24.42,10.59 24.37,10.54 23.89,10.54 23.81,10.62 23.81,11.1 23.84,11.12 25.84,11.12
GND on BOTTOM (solid shape): 52.13,17.55 52.13,13.87 50.02,11.77 46.98,11.77 46.71,12.04 46.71,17.48 47.01,17.78 51.9,17.78
GND on BOTTOM (solid shape): 63.5,21.56 63.5,18.47 62.93,17.9 61.75,17.9 61.05,18.6 61.05,21.46 61.78,22.2 62.86,22.2
GND on BOTTOM (solid shape): 71.54,70.13 71.54,68.12 71.8,67.86 72.39,67.86 72.62,67.63 72.62,66.18 72.3,65.86 70.65,65.86 70.27,66.24 70.27,70.25 70.36,70.34 71.34,70.34
GND on BOTTOM (solid shape): 106.75,68.07 106.75,65.63 106.66,65.54 101.68,65.54 101.63,65.6 101.63,66.1 101.79,66.27 101.79,66.27 101.79,68.05 102.03,68.29 106.54,68.29
GND on BOTTOM (solid shape): 112.82,77.49 112.82,75.76 112.63,75.57 111.76,75.57 111.57,75.76 111.57,77.52 111.67,77.62 112.69,77.62
GND on BOTTOM (solid shape): 175.5,82.09 175.5,80.45 174.56,79.5 174.03,79.5 174,79.53 173.83,79.53 173.64,79.72 173.64,80.24 174.2,80.79 174.2,82.02 174.33,82.15 175.44,82.15
GND on BOTTOM (solid shape): 190.33,84.41 190.33,79.09 190,78.76 188.1,78.76 187.55,79.32 187.55,81.22 188.07,81.74 188.07,84.28 188.37,84.58 190.16,84.58
GND on BOTTOM (solid shape): 91.36,62.8 91.36,61.7 91.04,61.37 88.33,61.37 87.98,61.72 87.98,62.8 87.98,62.81 88.03,62.86 91.3,62.86
GND on BOTTOM (solid shape): 124.35,66.35 124.35,65.41 124.19,65.25 116.07,65.25 115.88,65.45 115.88,66.62 116.02,66.77 123.93,66.77
GND on BOTTOM (solid shape): 246.38,92.75 247.01,92.11 247.01,91.29 247.77,90.53 248.28,90.53 248.47,90.33 248.47,90.08 248.31,89.92 246.35,89.92 245.55,90.72 245.55,93.13 245.81,93.38 246.38,93.38
GND on BOTTOM (solid shape): 83.79,90.34 83.79,90.06 84.07,89.78 85.21,89.78 85.25,89.74 85.25,88.74 85.07,88.56 83.2,88.56 82.73,89.04 82.73,90.35 82.85,90.48 83.65,90.48
GND on BOTTOM (solid shape): 18.43,12.59 18.43,5.5 18.31,5.38 17.55,5.38 17.44,5.49 17.44,12.01 16.12,13.32 16.12,13.59 16.38,13.84 17.18,13.84
GND on BOTTOM (solid shape): 85.72,65.93 85.72,62.4 85.57,62.25 84.59,62.25 84.47,62.38 84.47,64.28 83.99,64.75 80.67,64.75 80.36,65.06 80.36,65.95 80.64,66.23 85.42,66.23
GND on BOTTOM (solid shape): 271.67,12.47 271.67,12.25 271.43,12 271.43,11.7 270.43,10.71 268.92,10.71 268.92,12.36 270.38,12.36 270.62,12.59 271.54,12.59
GND on BOTTOM (solid shape): 223.12,93.27 223.12,92.67 222.62,92.16 222.62,91.24 222.53,91.15 221.37,91.15 221.32,91.2 221.32,92.18 221.1,92.39 219.08,92.39 218.89,92.58 218.89,93.64 219.12,93.87 222.52,93.87
GND on BOTTOM (solid shape): 33.41,9.79 34.16,9.79 34.16,9.79 34.42,9.79 34.71,9.5 34.71,8.14 34.16,7.59 33.91,7.59 32.74,8.76 32.38,8.76 32.19,8.96 32.19,9.98 32.31,10.1 33.11,10.1
GND on BOTTOM (solid shape): 256.98,93.95 256.98,93.48 257.3,93.17 258.48,93.17 258.55,93.1 258.55,92.54 258.39,92.38 256.67,92.38 256.35,92.69 254.14,92.69 253.49,93.35 253.49,95.52 253.71,95.74 255.19,95.74
GND on BOTTOM (solid shape): 220.91,56.3 220.91,53.89 220.75,53.72 216.79,53.72 216.6,53.91 216.6,55.4 216.8,55.6 217.29,55.6 217.48,55.79 217.48,56.52 217.55,56.59 220.62,56.59
GND on BOTTOM (solid shape): 201.99,61.41 204.75,61.41 204.75,59.48 204.52,59.48 204.52,60.78 202.87,60.78 202.87,59.48 202.68,59.29 199.76,59.29 198.64,60.41 198.64,61.49 198.75,61.6 199.41,61.6 199.83,62.03 201.38,62.03
GND on BOTTOM (solid shape): 35.18,19.34 35.18,15.79 34.99,15.6 34.92,15.6 34.86,15.53 30.64,15.53 30.58,15.59 30.58,15.88 31.11,15.88 31.11,16.43 30.58,16.43 30.58,16.68 31.11,16.68 31.11,17.23 30.58,17.23 30.58,19.11 30.93,19.47 35.05,19.47
GND on BOTTOM (solid shape): 65.36,11.86 65.52,11.71 65.52,11.54 65.49,11.52 65.49,11.23 65.62,11.1 66.44,11.1 66.51,11.03 66.51,10.94 66.44,10.87 64.84,10.87 64.73,10.98 64.73,11.21 65.02,11.5 65.02,11.73 65.16,11.86
GND on BOTTOM (solid shape): 162.91,79.83 164.48,78.26 164.48,77.27 164.27,77.06 163.61,77.06 163.15,77.52 163.15,77.96 163.15,78.34 161.62,79.87 161.38,79.87 161.38,80.65 161.33,80.7 161.31,80.81 161.41,80.87 162.91,80.87
GND on BOTTOM (solid shape): 103.07,58.01 103.07,53.6 102.79,53.32 102.79,51.1 102.66,50.97 101.77,50.97 101.52,50.72 101.52,49.52 101.79,49.25 104.33,49.25 104.5,49.07 104.5,45.53 104.42,45.45 100.57,45.45 100.12,45.89 100.12,52.69 100.86,53.42 100.86,58.01 100.87,58.02 103.06,58.02
GND on BOTTOM (solid shape): 90.06,85.81 90.49,85.55 90.95,85.35 91.65,85.18 92.36,85.14 92.39,85.15 92.54,84.99 92.54,84.18 92.37,84.01 91.03,84.01 90.79,84.25 88.76,84.25 88.53,84.48 88.53,85.17 88.62,85.27 88.88,85.27 89.43,85.82 90.05,85.82
GND on BOTTOM (solid shape): 78.02,82 78.02,80.5 76.92,79.39 76.26,79.39 76,79.13 76,78.17 75.81,77.98 74.49,77.98 74.29,78.18 74.29,79.57 73.62,80.24 72.65,80.24 72.52,80.37 72.52,81.73 72.64,81.85 73.54,81.85 73.66,81.72 73.66,81.05 73.99,80.72 76.29,80.72 76.9,81.34 76.9,81.77 77.19,82.06 77.96,82.06
GND on BOTTOM (solid shape): 100.71,91.51 100.71,91.01 100.64,90.95 100.64,90.94 100.58,90.88 100.58,89.67 100.65,89.61 100.65,89.42 100.8,89.26 101.16,89.26 101.33,89.43 101.33,90.9 101.38,90.95 101.53,90.95 101.58,90.89 101.58,89.43 101.77,89.25 102.12,89.25 102.32,89.45 102.32,90.91 102.37,90.95 102.55,90.95 102.6,90.9 102.6,85.73 102.5,85.63 98.72,85.63 98.61,85.74 98.61,87.05 100.21,88.64 100.21,89.57 100.32,89.67 100.32,90.88 100.11,91.08 100.11,91.47 100.27,91.63 100.59,91.63
GND on BOTTOM (solid shape): 65.08,94.65 65.08,94.04 65.29,93.84 66.09,93.84 66.16,93.76 66.16,92.36 66.04,92.23 65.17,92.23 65.08,92.14 65.08,91.28 65.08,91.27 65.08,89.95 63.38,88.25 62.84,88.25 60.53,85.64 59.6,84.61 58.18,85.89 56.49,87.28 56.38,87.38 56.38,87.76 58.5,89.87 62.15,89.87 63.01,90.74 63.01,91.76 63.56,91.76 63.56,92.51 63.01,92.51 63.01,92.96 63.56,92.96 63.56,93.71 63.01,93.71 63.01,94.8 63.22,95.01 64.73,95.01
GND on BOTTOM (solid shape): 196.73,15.4 196.8,15.43 196.88,15.4 197,15.32 197.14,15.3 197.17,15.31 198.71,13.76 198.71,13.29 198.63,13.21 198.24,13.21 198.21,13.25 198.18,13.28 198.14,13.35 198.16,13.42 198.14,13.88 197.69,13.94 196.76,13.94 196.7,14 196.7,15.38
GND on BOTTOM (solid shape): 97.24,11.07 97.3,10.98 97.3,10.2 97.24,10.11 97.13,10.12 96.78,10.15 96.57,9.86 96.57,9.84 96.09,9.36 96.07,9.36 95.96,9.33 95.88,9.26 95.8,9.23 95.73,9.26 95.7,9.28 95.68,9.3 95.68,9.85 96.83,11.01 96.86,11 97,11 97.13,11.06
GND on BOTTOM (solid shape): 87.88,11.02 87.94,11.12 88.05,11.1 88.2,11.01 88.37,11 88.39,11.01 89.32,10.08 89.32,9.3 89.3,9.28 89.28,9.26 89.2,9.23 89.13,9.26 89.1,9.29 89.07,9.31 88.65,9.73 88.65,9.76 88.47,10.14 88.05,10.08 87.94,10.06 87.88,10.16
GND on BOTTOM (solid shape): 87.88,11.02 87.94,11.12 88.05,11.09 88.2,11.01 88.37,11 88.39,11.01 89.32,10.08 89.32,9.3 89.28,9.26 89.2,9.23 89.13,9.26 89.1,9.29 89.07,9.31 88.65,9.74 88.65,9.76 88.47,10.14 88.05,10.09 87.94,10.06 87.88,10.16
GND on BOTTOM (solid shape): 192.62,20.44 192.67,20.34 192.75,20.26 192.79,20.2 192.78,20.12 192.78,20.1 192.76,20.08 192.85,19.45 193.29,19.91 193.29,19.92 193.29,19.98 193.38,19.98 193.42,19.94 193.42,18.55 192.95,18.08 192.95,17.97 192.87,17.89 192.44,17.89 192.4,17.93 192.4,19.76 191.86,20.3 191.84,20.41 191.93,20.47 192.61,20.47
GND on BOTTOM (solid shape): 233.25,109.25 233.75,109.05 234,108.57 234.02,108.34 235.59,108.34 235.59,98.3 235.61,98.13 235.67,97.98 235.67,96.82 235.45,96.6 225.82,96.6 225.03,97.39 222.15,97.39 221.63,97.92 221.63,101.19 222.35,101.19 223.41,100.99 223.21,102.05 223.21,108.29 224.94,108.29 224.95,108.54 225.19,109.04 225.7,109.25
GND on BOTTOM (solid shape): 295.11,70.44 295.38,70.01 295.85,69.85 298.14,69.85 301.15,69.85 301.32,69.77 301.4,69.6 301.4,63.45 301.32,63.28 301.15,63.2 298.14,63.2 298.14,63.21 297.08,63.21 297.08,63.2 292.46,63.2 291.62,63.69 291,62.95 291,61.87 275.91,61.87 275.45,62.33 275.45,65.55 276.03,66.13 280.6,66.13 280.6,66.13 282.85,66.13 283.34,65.64 283.34,64.35 283.71,63.97 286.76,63.97 287.07,64.29 287.07,65.24 289.58,67.74 293.49,67.74 294.49,68.74 294.49,70.29 294.64,70.44
GND on BOTTOM (solid shape): 253.09,107.5 257.35,103.25 261.61,107.5 261.61,108.62 263.89,108.62 263.89,101.83 263.58,101.52 256.96,101.52 254.46,99.02 252.04,96.6 250.42,96.6 250.01,97.01 250.01,108.34 251.58,108.34 251.6,108.57 251.85,109.05 252.34,109.25 253.09,109.25
GND on BOTTOM (solid shape): outline of 121 points within 283.83,78.4 303.15,93.91
GND on BOTTOM (solid shape): 136.74,73.34 136.79,73.31 136.83,73.2 136.83,73.16 136.77,73 136.77,72.76 136.82,72.56 136.85,72.52 136.85,72.19 137,72.04 137.17,72.04 137.31,71.94 137.48,71.94 137.51,71.95 137.7,71.76 137.71,71.75 137.79,71.65 137.91,71.6 138.11,71.65 138.23,71.82 138.23,71.84 138.36,71.97 138.4,71.95 138.58,71.93 138.74,72.04 138.8,72.18 138.77,72.33 138.77,72.34 138.77,72.73 138.77,72.74 138.8,72.83 138.79,72.92 139.15,73.28 139.31,73.28 139.33,73.2 139.33,73.16 139.27,73 139.27,72.76 139.33,72.56 139.35,72.54 139.35,72.43 139.26,72.35 139.26,72.07 139.27,72.06 139.27,71.86 139.21,71.8 139.17,71.79 139.12,71.78 138.91,71.78 138.17,71.04 138.17,70.76 138.12,70.71 137.83,70.71 137.74,70.8 137.74,71.02 136.98,71.78 136.79,71.78 136.7,71.8 136.61,71.78 136.45,71.78 136.04,71.37 135.93,71.37 135.77,71.53 135.77,72.2 136.27,72.7 136.27,72.76 136.29,72.82 136.29,72.88 136.29,72.91 136.51,73.13 136.51,73.18 136.67,73.34
GND on BOTTOM (solid shape): 0.76,5.86 28.84,5.86 28.84,6.1 31.4,8.66 33.96,6.1 33.96,5.86 39.03,5.86 39.03,5.36 34.17,5.36 33.45,5.35 33.45,6.1 31.4,8.15 29.35,6.1 29.35,5.35 28.56,5.35 1.4,5.36 1,5.35 0.79,5.39 0.34,5.75 0.25,6.1 0.25,6.28 0.26,6.28 0.26,13.18 0.76,13.18
GND on BOTTOM (solid shape): 111.2,109.25 111.37,109.17 111.81,108.11 112.7,107.75 190.7,107.75 191.59,108.11 192.03,109.17 192.2,109.25 204.7,109.25 205.22,109.04 205.45,108.54 205.46,108.3 207.2,108.3 207.2,105.32 207.19,105.32 207.19,102.05 206.99,100.99 208.05,101.19 208.67,101.19 208.67,97.85 208.25,97.43 206.26,97.43 206.23,97.43 204.28,99.39 204.26,99.39 201.6,102.05 134.67,102.05 134.35,102.37 128.85,102.37 127.6,101.12 104.63,101.12 103.05,99.54 98.36,99.54 95.94,97.12 95.94,92.44 94.94,91.43 94.94,88.06 93.57,86.69 90.89,86.69 89.66,87.92 89.66,91.06 91.91,93.3 91.91,108.34 93.48,108.34 93.5,108.57 93.75,109.05 94.24,109.25 102.68,109.25
GND on BOTTOM (solid shape): outline of 224 points within 106.89,84.65 121.51,92.47
GND on BOTTOM (solid shape): outline of 331 points within 157.82,6.39 169.02,13.08
GND on BOTTOM (solid shape): outline of 482 points within 233.99,0.25 304.5,52.44
GND on BOTTOM (solid shape): outline of 514 points within 157.82,6.39 184.35,13.72
GND on BOTTOM (solid shape): outline of 82 points within 33.97,27.99 77.54,109.25
GND on BOTTOM (solid shape): outline of 270 points within 139.68,70.7 157.59,73.36
GND on BOTTOM (solid shape): outline of 3773 points within 157.82,6.39 221.99,21.43
GND on BOTTOM (solid shape): outline of 4165 points within 78.52,6.39 141.21,25.29
GND on IN1 (solid shape): 52.04,17.16 52.04,13.82 49.98,11.75 44.56,11.75 44.29,12.03 44.29,15.8 45.45,16.96 45.5,16.96 45.91,17.37 51.83,17.37
GND on IN1 (solid shape): 103.31,57.76 103.31,47.22 102.93,46.84 100.14,46.84 99.88,47.09 99.88,48.62 100.64,49.38 100.64,57.76 100.9,58.01 103.06,58.01
GND on IN1 (solid shape): 77.76,75.61 77.76,67.87 75.89,66.01 71.34,66.01 71.06,66.28 71.06,70.7 71.57,71.21 73.03,71.21 73.21,71.39 73.21,74.49 73.77,75.05 74.94,75.05 75.94,76.05 77.32,76.05
GND on IN1 (solid shape): 295.11,70.44 295.38,70.01 295.85,69.85 297.12,69.85 301.15,69.85 301.32,69.77 301.4,69.6 301.4,63.45 301.32,63.28 301.15,63.2 292.46,63.2 291.62,63.69 291,62.95 291,61.86 275.92,61.86 275.44,62.34 275.44,65.54 276.04,66.14 282.85,66.14 283.48,65.51 287.08,65.51 292.01,70.44
GND on IN1 (solid shape): 233.25,109.25 233.75,109.05 234,108.57 234.02,108.34 235.59,108.34 235.59,98.3 235.61,98.14 235.66,97.99 235.66,96.94 235.33,96.6 232.56,96.6 231.69,97.47 222.06,97.47 221.64,97.88 221.64,101.19 222.35,101.19 223.41,100.99 223.21,102.05 223.21,108.29 224.94,108.29 224.95,108.54 225.19,109.04 225.7,109.25
GND on IN1 (solid shape): 253.09,107.5 257.35,103.25 261.61,107.5 261.61,108.62 263.89,108.62 263.89,100.56 263.52,100.26 263.4,99.8 262.23,99.8 260.57,101.46 256.96,101.46 252.12,96.62 250.37,96.62 250.01,96.99 250.01,108.34 251.58,108.34 251.6,108.57 251.85,109.05 252.34,109.25 253.09,109.25
GND on IN1 (solid shape): 0.76,6.18 1.08,5.86 28.84,5.86 28.84,6.1 31.4,8.66 33.96,6.1 33.96,5.86 39.03,5.86 39.03,5.36 34.17,5.36 33.45,5.35 33.45,6.1 31.4,8.15 29.35,6.1 29.35,5.35 28.56,5.35 1.84,5.36 1,5.35 0.82,5.38 0.65,5.44 0.36,5.72 0.25,6.1 0.25,6.32 0.26,6.32 0.26,13.18 0.76,13.18
GND on IN1 (solid shape): outline of 166 points within 283.65,78.39 303.15,93.92
GND on IN1 (solid shape): 111.2,109.25 111.37,109.17 111.81,108.11 112.7,107.75 190.7,107.75 191.59,108.11 192.03,109.17 192.2,109.25 204.7,109.25 205.22,109.04 205.45,108.54 205.46,108.3 207.2,108.3 207.2,103.74 207.19,103.74 207.19,102.05 206.99,100.99 208.05,101.19 208.66,101.19 208.66,98.01 208.23,97.58 208.13,97.58 208.12,97.6 207.64,97.6 203.89,101.35 130.57,101.35 130.57,101.36 112.93,101.36 111.17,103.12 101.71,103.12 101.51,102.92 101.47,102.92 94.89,96.35 94.89,96.3 94.14,95.56 94.14,91.44 95.12,90.46 95.12,87.64 93.44,85.96 90.92,85.96 89.25,87.64 89.25,90.44 90.28,91.47 90.28,95.71 91.82,97.26 91.82,97.96 91.88,98.13 91.91,98.3 91.91,108.34 93.48,108.34 93.5,108.57 93.75,109.05 94.24,109.25 104.18,109.25
GND on IN1 (solid shape): outline of 426 points within 233.7,0.25 304.5,50.39
GND on IN1 (solid shape): 54.69,109.25 75.15,109.25 75.65,109.05 75.9,108.57 75.92,108.34 77.49,108.34 77.49,98.3 77.51,98.14 77.57,97.98 77.57,97.15 77.06,96.64 75.57,96.64 75.24,96.96 75.24,105.75 73.95,107.05 61.28,107.05 57.52,103.29 53.7,103.29 53.26,102.85 52.75,101.6 51.5,101.09 49.76,101.09 49.76,89.73 49.83,89.56 50,89.49 53.2,89.49 53.98,89.38 54.69,89.06 61.46,83.42 66.59,76.25 66.92,75.12 66.74,73.95 65.82,71.57 65.74,71.14 65.81,70.7 65.94,70.34 66.07,69.98 66.07,69.95 66.32,69.21 66.5,68.6 66.67,67.99 72.44,62.23 72.44,59.66 67.3,54.52 67.3,54.35 56.46,35.46 36,27.99 33.97,27.99 33.97,28.49 36,28.49 61.06,41.07 65.95,68.67 65.78,69.25 65.46,70.18 65.28,70.71 65.24,71.24 65.35,71.75 66.27,74.13 66.41,75.08 66.15,76.01 61.09,83.07 54.41,88.63 53.83,88.9 53.2,88.99 50,88.99 49.47,89.21 49.25,89.73 49.25,101.35 49.33,101.52 49.5,101.6 51.5,101.6 52.39,101.96 52.75,102.85 52.75,108.5 52.97,109.03 53.5,109.25 54.68,109.25
GND on IN2 (solid shape): 52.04,16.85 52.04,13.81 49.99,11.75 44.56,11.75 44.29,12.03 44.29,15.8 45.45,16.96 51.93,16.96
GND on IN2 (solid shape): 23.18,10.94 23.18,5.6 23,5.42 22.43,5.42 22.26,5.59 22.26,10.95 22.41,11.1 23.03,11.1
GND on IN2 (solid shape): 103.31,57.76 103.31,48.16 103.06,47.91 100.11,47.91 99.88,48.13 99.88,48.62 100.64,49.38 100.64,57.76 100.9,58.01 103.06,58.01
GND on IN2 (solid shape): 77.78,75.52 77.78,67.89 75.89,66.01 71.34,66.01 71.06,66.28 71.06,70.7 71.57,71.21 73.03,71.21 73.21,71.39 73.21,74.49 73.77,75.05 74.94,75.05 75.94,76.05 77.26,76.05
GND on IN2 (solid shape): 295.11,70.44 295.38,70.01 295.85,69.85 299.01,69.85 301.15,69.85 301.32,69.77 301.4,69.6 301.4,63.45 301.32,63.28 301.15,63.2 299.01,63.2 299.01,63.21 297.02,63.21 297.02,63.2 292.46,63.2 291.62,63.69 291,62.95 291,61.86 287.56,61.86 287.08,62.34 287.08,65.25 292.27,70.44
GND on IN2 (solid shape): 233.25,109.25 233.75,109.05 234,108.57 234.02,108.34 235.59,108.34 235.59,98.3 235.61,98.14 235.66,97.99 235.66,96.94 235.33,96.6 232.46,96.6 231.48,97.58 222.01,97.58 221.64,97.94 221.64,101.19 222.35,101.19 223.41,100.99 223.21,102.05 223.21,108.29 224.94,108.29 224.95,108.54 225.19,109.04 225.7,109.25
GND on IN2 (solid shape): 253.09,107.5 257.35,103.25 261.61,107.5 261.61,108.62 263.89,108.62 263.89,100.56 263.52,100.26 263.4,99.8 262.23,99.8 260.57,101.46 256.96,101.46 252.12,96.62 250.37,96.62 250.01,96.99 250.01,108.34 251.58,108.34 251.6,108.57 251.85,109.05 252.34,109.25 253.09,109.25
GND on IN2 (solid shape): 0.76,6.3 1.2,5.86 28.84,5.86 28.84,6.1 31.4,8.66 33.96,6.1 33.96,5.86 39.03,5.86 39.03,5.36 34.17,5.36 33.45,5.35 33.45,6.1 31.4,8.15 29.35,6.1 29.35,5.35 28.56,5.35 1.52,5.36 1,5.35 0.81,5.38 0.63,5.45 0.35,5.73 0.25,6.1 0.25,6.26 0.26,6.26 0.26,13.18 0.76,13.18
GND on IN2 (solid shape): outline of 160 points within 283.65,78.4 303.15,93.93
GND on IN2 (solid shape): 111.2,109.25 111.37,109.17 111.81,108.11 112.7,107.75 190.7,107.75 191.59,108.11 192.03,109.17 192.2,109.25 204.7,109.25 205.22,109.04 205.45,108.54 205.46,108.3 207.2,108.3 207.2,104.02 207.19,104.02 207.19,102.05 206.99,100.99 208.05,101.19 208.66,101.19 208.66,97.77 208.29,97.41 207.87,97.41 205.54,99.73 135.53,99.73 133.42,101.84 108.29,101.84 107.21,102.92 101.15,102.92 94.79,96.55 92.41,96.55 92.1,96.86 92.1,97.36 91.82,97.63 91.82,97.96 91.88,98.13 91.91,98.3 91.91,108.34 93.48,108.34 93.5,108.57 93.75,109.05 94.24,109.25 102.33,109.25
GND on IN2 (solid shape): outline of 193 points within 16.09,13.01 22.68,16.9
GND on IN2 (solid shape): outline of 368 points within 233.7,0.25 304.5,50.39
GND on IN2 (solid shape): 54.69,109.25 75.15,109.25 75.65,109.05 75.9,108.57 75.92,108.34 77.49,108.34 77.49,98.3 77.51,98.14 77.57,97.98 77.57,97.15 77.06,96.64 75.59,96.64 75.24,96.99 75.24,104.82 75.22,104.84 75.22,105.78 73.99,107.01 73.98,107.01 73.88,107.11 61.31,107.11 57.49,103.3 53.7,103.3 53.26,102.86 53.26,102.85 52.75,101.6 51.5,101.09 49.76,101.09 49.76,89.73 49.83,89.56 50,89.49 53.2,89.49 53.98,89.38 54.69,89.06 61.46,83.42 66.59,76.25 66.92,75.12 66.74,73.95 65.82,71.57 65.74,71.14 65.81,70.7 65.94,70.34 66.14,69.78 66.43,68.84 66.7,67.89 72.3,62.29 72.3,59.52 67.3,54.52 67.3,54.35 56.46,35.46 36,27.99 33.97,27.99 33.97,28.49 36,28.49 61.09,41.11 65.93,68.77 65.76,69.29 65.46,70.17 65.34,70.52 65.23,71.14 65.35,71.75 66.27,74.13 66.41,75.08 66.15,76.01 61.09,83.07 54.41,88.63 53.83,88.9 53.2,88.99 50,88.99 49.47,89.21 49.25,89.73 49.25,101.35 49.33,101.52 49.5,101.6 51.5,101.6 52.39,101.96 52.75,102.85 52.75,108.5 52.97,109.03 53.5,109.25 54.68,109.25
GND on IN2 (solid shape): outline of 846 points within 56.38,84.31 81.47,108.48
GND on VCC: 279.06,22.96 278.66,23.36 278.66,26.36 276.59,28.42 275.63,28.42 275.4,28.65 275.4,34.48 275.72,34.8 278.88,34.8 279.65,35.57 279.65,38.59 283.93,38.59 284.46,38.06 287.62,38.06 289.31,36.37 290.51,36.37 290.95,35.92 290.95,23.66 290.25,22.96
GND on VCC: 160.59,8.94 158.82,10.71 143.96,10.71 142.36,9.12 119.17,9.12 118.84,9.44 52.51,9.44 52.51,17.03 64.34,17.03 64.34,20.49 66.46,22.62 67.98,22.62 73.39,28.03 77.83,28.03 78.56,28.76 78.56,30.43 79.02,30.89 84.68,30.89 87.83,34.04 89.69,34.04 93.16,37.51 93.16,39.67 97.7,44.2 97.7,45.65 100.29,48.24 100.29,57.62 100.81,58.14 103.24,58.14 103.82,58.72 103.82,62.76 110.79,62.76 110.79,68.9 113.94,72.05 117.64,72.06 118.68,72.06 120.43,70.31 124.04,70.31 125.79,72.05 125.78,72.05 157.15,72.05 157.15,58.34 159.2,58.34 160.32,57.22 160.32,55.67 160.8,55.19 162.44,55.19 162.65,54.99 162.65,52.17 164.14,50.67 164.14,50.29 164.53,49.91 164.53,48 168.41,44.12 199.2,44.12 222.42,20.9 222.42,10.24 221.13,8.94
GND on VCC: 122.98,98.34 122.98,101.79 123.86,102.66 179.01,102.66 182.38,99.29 182.38,98.34
GND on VCC: 262.17,11.4 261.9,11.67 261.9,15.6 258.47,15.6 258.47,23.34 260.27,25.15 263.4,25.15 263.4,22.67 265.84,20.22 269.22,20.22 269.55,19.88 269.55,15.57 268.81,14.83 266.88,14.83 266.38,14.33 266.38,12.65 265.13,11.4
GND on VCC: 246.1,79.6 246.1,93.01 236.32,93.01 236.32,96.78 236.95,96.91 237.48,97.28 248.12,97.28 249.79,96.88 250.77,98.3 250.77,107.58 251.35,107.58 252.33,108.47 252.33,108.47 252.33,107.5 257.35,102.48 262.37,107.5 262.37,107.86 263.13,107.86 263.13,100.98 262.75,100.44 262.63,99.8 262.21,99.8 261.68,99.27 261.68,96.09 260.6,96.09 259.85,95.34 259.85,89.36 258.53,88.04 258.53,86.95 258.95,86.54 260.36,86.54 260.83,86.06 260.83,82.6 260.35,82.6 258.87,84.09 254.37,84.09 249.89,79.6
GND on VCC: outline of 164 points within 50.02,58.32 94.38,108.48 ; 2 cut-outs
GND on GND: outline of 189 points within 0.26,0.26 304.49,109.25 ; 1 cut-out
GNDA on TOP (solid shape): 2.14,15.34 0.76,15.34 0.76,13.69 0.26,13.69 0.26,15.84 2.14,15.84
GNDA on TOP (solid shape): 1.39,28.49 33.46,28.49 33.46,27.99 1.27,27.99 1.27,27.99 0.76,27.99 0.76,24.66 1.71,24.66 1.71,24.15 0.26,24.15 0.26,27.03 0.25,27.03 0.25,27.75 0.35,28.12 0.63,28.4 0.81,28.47 1,28.5 1.39,28.5
GNDA on BOTTOM (solid shape): 2.14,15.34 0.76,15.34 0.76,13.69 0.26,13.69 0.26,15.84 2.14,15.84
GNDA on BOTTOM (solid shape): 30.17,21.68 30.33,21.68 30.45,21.56 30.45,17.1 30.98,17.1 30.98,16.81 30.45,16.81 30.45,16.3 30.98,16.3 30.98,16.01 30.45,16.01 30.45,15.56 28.38,15.56 28.27,15.67 28.27,17.55 27.91,17.91 27.22,17.91 27.05,18.07 27.05,21.6 27.15,21.69 30.16,21.69
GNDA on BOTTOM (solid shape): 1.37,28.49 33.46,28.49 33.46,27.99 0.76,27.99 0.76,24.66 1.71,24.66 1.71,24.15 0.26,24.15 0.26,27.2 0.25,27.2 0.25,27.75 0.29,27.98 0.39,28.18 0.46,28.26 0.53,28.33 0.59,28.38 0.79,28.47 1,28.5 1.37,28.5
GNDA on IN1 (solid shape): 2.14,15.34 0.76,15.34 0.76,13.69 0.26,13.69 0.26,15.84 2.14,15.84
GNDA on IN1 (solid shape): 1.36,28.49 33.46,28.49 33.46,27.99 0.76,27.99 0.76,24.66 1.83,24.66 1.83,24.15 0.26,24.15 0.26,27.32 0.25,27.32 0.25,27.75 0.31,28.03 0.47,28.27 0.56,28.35 0.67,28.42 0.83,28.48 1,28.5 1.36,28.5
GNDA on IN2 (solid shape): 2.14,15.34 0.76,15.34 0.76,13.69 0.26,13.69 0.26,15.84 2.14,15.84
GNDA on IN2 (solid shape): 1.18,28.49 33.46,28.49 33.46,27.99 0.76,27.99 0.76,24.66 1.83,24.66 1.83,24.15 0.26,24.15 0.26,27.39 0.25,27.39 0.25,27.75 0.26,27.81 0.27,27.88 0.3,28.02 0.37,28.15 0.41,28.2 0.64,28.4 0.94,28.49 1,28.5 1.18,28.5
GNDA on VCC: 27.98,10.96 26.33,12.61 10.14,12.61 9.06,13.69 1.02,13.69 1.02,15.08 12.45,15.08 13.87,16.05 13.47,17.73 13.47,22.27 13.87,23.94 12.45,24.92 1.02,24.92 1.02,27.73 33.46,27.73 33.46,26.28 33.84,25.9 33.84,22.81 33.21,22.18 33.21,20.27 33.1,20.17 31.07,20.17 30.67,19.76 30.67,15.36 31.07,14.96 32.15,14.96 32.19,14.92 32.19,13.6 31.62,13.03 31.62,12.53 31.11,12.02 31.11,11.19 30.88,10.96
GNDA on GND: 27.98,10.96 26.33,12.61 10.14,12.61 9.06,13.69 0.26,13.69 0.26,15.84 12.45,15.84 13.19,16.47 12.71,17.31 12.71,22.69 13.19,23.53 12.45,24.15 0.26,24.15 0.26,27.75 0.47,28.28 1,28.49 33.46,28.49 33.46,26.28 33.84,25.9 33.84,22.81 33.21,22.18 33.21,20.27 33.1,20.17 31.07,20.17 30.67,19.76 30.67,15.36 31.07,14.96 32.15,14.96 32.19,14.92 32.19,13.6 31.62,13.03 31.62,12.53 31.11,12.02 31.11,11.19 30.88,10.96
GNDA_CHG on TOP (solid shape): 81.91,85.07 81.91,84.47 82.14,84.24 82.66,84.24 82.74,84.15 82.74,82.7 83.04,82.4 83.25,82.4 83.5,82.14 83.5,81.51 83.34,81.35 82.37,81.35 82.2,81.52 78.41,81.52 78.1,81.83 77.66,81.83 77.66,82.4 77.15,82.4 77.15,81.83 76.9,81.83 76.9,82.74 77.05,82.89 77.05,85.05 77.19,85.18 81.8,85.18
VDD_1.35V on TOP (solid shape): 66.02,9.85 66.02,9.32 65.9,9.19 65.9,6.83 65.78,6.72 65.17,6.72 65.05,6.84 65.05,8.83 64.7,9.17 64.7,9.37 64.86,9.52 65.24,9.52 65.36,9.64 65.36,9.89 65.39,9.92 65.96,9.92
VDD_1.35V on BOTTOM (solid shape): 66.51,9.83 66.51,9.74 65.77,9 64.81,9 64.7,9.11 64.7,9.41 64.84,9.54 65.32,9.54 65.68,9.89 66.45,9.89
+BL_PWR_SRC on BOTTOM (solid shape): 112.89,95.05 112.89,93.69 112.39,93.19 111.44,93.19 110.78,92.53 108.54,92.53 108.09,92.07 108.09,89.72 108.01,89.64 106.89,89.64 106.82,89.72 106.82,92.02 106.53,92.31 106.53,94.43 106.81,94.72 107.88,94.72 108.41,95.24 112.69,95.24
+DC_IN on TOP (solid shape): 65.97,101.46 67.06,101.46 67.26,101.26 67.26,100.2 67.64,99.82 67.99,99.82 68.13,99.69 68.13,98.48 68.01,98.36 66.75,98.36 66.59,98.2 66.59,97.01 66.41,96.82 64.02,96.82 63.9,96.94 63.9,99.37 62.95,100.32 62.95,101.3 63.12,101.47 65.97,101.47
+DC_IN on BOTTOM (solid shape): 68.9,106.12 68.9,96.99 68.53,96.62 66.18,96.62 65.69,97.11 65.69,103.33 65.72,103.33 65.77,103.35 65.82,103.37 65.87,103.4 65.91,103.44 65.95,103.48 65.98,103.52 66,103.57 66.02,103.63 66.03,103.68 66.03,103.72 67.89,103.72 67.89,103.67 67.9,103.62 67.92,103.56 67.94,103.52 67.97,103.47 68,103.43 68.05,103.4 68.09,103.37 68.14,103.35 68.19,103.34 68.25,103.34 68.3,103.34 68.35,103.35 68.4,103.37 68.45,103.4 68.49,103.43 68.53,103.47 68.56,103.52 68.58,103.56 68.6,103.62 68.6,103.67 68.6,103.72 68.6,103.77 68.58,103.83 68.56,103.87 68.53,103.92 68.49,103.96 68.45,103.99 68.4,104.02 68.35,104.04 68.3,104.05 68.25,104.05 68.19,104.05 68.14,104.04 68.09,104.02 68.05,103.99 68,103.96 67.97,103.92 67.94,103.87 67.92,103.83 67.9,103.77 67.89,103.72 66.03,103.72 66.03,103.74 66.02,103.79 66,103.84 65.98,103.89 65.95,103.94 65.91,103.98 65.87,104.02 65.82,104.04 65.77,104.07 65.72,104.08 65.69,104.09 65.69,104.69 65.46,104.92 64.35,104.92 64.15,105.13 64.15,106.15 64.28,106.28 68.75,106.28
+DC_IN_SS on TOP (solid shape): 65.72,96.13 65.72,95.26 66.88,94.1 66.88,92.46 66.76,92.34 64.42,92.34 63.86,92.91 63.86,96.07 64.04,96.25 65.59,96.25
+DCIN on BOTTOM (solid shape): 77.23,89.84 77.23,85.47 78.03,84.67 78.03,84.32 77.96,84.26 77.19,84.26 76.63,84.82 73.42,84.82 73.26,84.98 73.26,85.97 73.42,86.12 75.13,86.12 75.57,86.56 75.57,89.77 75.73,89.93 77.14,89.93
+DCIN_JACK on TOP (solid shape): 62.65,101.27 62.65,100.25 63.52,99.38 63.52,96.93 61.81,95.21 51.88,95.21 51.72,95.36 51.72,97.37 51.94,97.59 60.27,97.59 61.01,98.33 61.01,101.3 61.1,101.39 62.53,101.39
+DCIN_JACK on BOTTOM (solid shape): 63.94,106.19 63.94,104.99 64.24,104.69 65.34,104.69 65.5,104.53 65.5,104.06 65.26,103.71 65.5,103.35 65.5,96.28 64.7,95.49 64.69,95.49 64.42,95.21 51.86,95.21 51.72,95.35 51.72,97.37 51.94,97.59 60.27,97.59 61.01,98.33 61.01,105.95 61.36,106.29 63.84,106.29
+DCPRRTC on TOP (solid shape): 166.33,60.62 166.63,60.62 166.65,60.64 167.12,60.64 167.31,60.44 167.31,60.19 167.3,60.15 167.28,60.1 167.27,60.05 167.27,60 167.28,59.95 167.3,59.9 167.31,59.86 167.31,59.63 167.19,59.5 167.12,59.5 165.98,59.5 165.86,59.61 165.86,60.05 166.06,60.05 166.06,60 166.06,59.95 166.08,59.9 166.1,59.86 166.13,59.82 166.17,59.78 166.21,59.75 166.25,59.73 166.3,59.72 166.35,59.71 166.4,59.71 166.45,59.72 166.5,59.73 166.54,59.75 166.58,59.78 166.62,59.82 166.65,59.86 166.67,59.9 166.68,59.95 166.69,60 166.69,60.05 166.68,60.1 166.67,60.15 166.65,60.19 166.62,60.23 166.58,60.27 166.54,60.3 166.5,60.32 166.45,60.34 166.4,60.34 166.35,60.34 166.3,60.34 166.25,60.32 166.21,60.3 166.17,60.27 166.13,60.23 166.1,60.19 166.08,60.15 166.06,60.1 166.06,60.05 165.86,60.05 165.86,60.19 165.76,60.29 165.12,60.29 164.97,60.44 164.97,61.01 165.07,61.12 165.83,61.12
+EDP_VDD on TOP (solid shape): 103.35,90.91 103.35,90.52 103.88,90.52 103.88,90.29 103.35,90.29 103.35,89.05 102.52,88.22 101.64,88.22 101.38,88.48 101.38,88.97 101.63,89.22 102.04,89.22 102.35,89.52 102.35,90.93 102.42,91.01 103.25,91.01
+LCDVDD on TOP (solid shape): 105.7,90.91 105.7,88.62 105.52,88.45 103.62,88.45 103.49,88.58 103.49,90.16 104.01,90.16 104.01,90.65 103.48,90.65 103.48,90.94 103.6,91.07 105.53,91.07
+LCDVDD on BOTTOM (solid shape): 114.4,92.3 114.4,91.34 114.09,91.03 114.09,89.74 114.01,89.65 113.36,89.65 113.31,89.7 113.31,90.94 113.28,90.97 113.28,92.35 113.38,92.45 114.25,92.45
+LCDVDD on IN1 (solid shape): 114.87,92.18 114.87,90.53 114.11,89.76 107.72,89.76 106.32,88.37 104.58,88.37 104.33,88.62 104.33,89.35 105.84,89.35 105.84,89.3 105.85,89.25 105.86,89.2 105.89,89.15 105.92,89.1 105.95,89.06 105.99,89.03 106.04,89 106.09,88.99 106.14,88.97 106.19,88.97 106.25,88.97 106.3,88.99 106.35,89 106.39,89.03 106.44,89.06 106.47,89.1 106.5,89.15 106.53,89.2 106.54,89.25 106.55,89.3 106.55,89.35 106.54,89.41 106.53,89.46 106.5,89.5 106.47,89.55 106.44,89.59 106.39,89.62 106.35,89.65 106.3,89.67 106.25,89.68 106.19,89.68 106.14,89.68 106.09,89.67 106.04,89.65 105.99,89.62 105.95,89.59 105.92,89.55 105.89,89.5 105.86,89.46 105.85,89.41 105.84,89.35 104.33,89.35 104.33,90.54 106.22,92.43 114.61,92.43
+MIC1_VREF_OUT on TOP (solid shape): 27.33,16.42 27.33,16.19 26.77,15.63 26.77,13.6 26.65,13.48 26.16,13.48 26.04,13.59 26.04,16.06 26.54,16.56 27.19,16.56
+PBATT on TOP (solid shape): 58.51,20.99 58.51,8.2 58.37,8.05 56.22,8.05 56.06,8.22 56.06,13.47 55.51,14.02 53.49,14.02 53.19,14.33 53.19,17 52.25,17.94 52.25,20.88 52.66,21.29 58.21,21.29
+PBATT on BOTTOM (solid shape): 96.66,73.16 96.66,65.71 96.33,65.38 93.87,65.38 93.52,65.73 93.52,68.9 93.24,69.18 89.44,69.18 89.22,69.4 89.22,73.28 89.49,73.55 96.27,73.55
+PBATT on IN1 (solid shape): 57.66,24.9 57.66,21.97 58.61,21.02 58.61,8.3 58.37,8.06 56.19,8.06 56.06,8.2 56.06,13.49 55.51,14.03 53.45,14.03 53.17,14.32 53.17,17.06 52.07,18.16 50.38,18.16 49.83,18.72 49.83,25.03 50.31,25.51 57.05,25.51
+PBATT on IN1 (solid shape): outline of 1497 points within 68.12,44.81 93.62,73.57
+PBATT on IN2 (solid shape): 58.61,16.74 58.61,8.23 58.4,8.03 56.22,8.03 56.06,8.19 56.06,13.43 55.44,14.05 55.44,16.73 55.69,16.99 58.35,16.99
+PCH_ASATA3PLL on TOP (solid shape): 163.15,81.19 163.15,80.35 163,80.2 163,77.95 162.75,77.7 161.48,77.7 161.14,78.03 161.14,81.08 161.32,81.25 161.37,81.27 163.07,81.27
+PCH_AUSB3PLL on TOP (solid shape): 160.82,81.28 160.82,79.83 160.8,79.81 160.8,78.16 158.81,76.17 158.04,76.17 157.93,76.29 157.93,76.86 158.04,76.98 158.35,76.98 159.19,77.83 159.19,80.11 158.94,80.37 158.94,81.19 159.06,81.32 160.78,81.32
+PCH_RTC_VCCSUS3_3 on IN1 (solid shape): outline of 458 points within 163.32,52.68 166.63,58.85
+PCH_VCCDSW on TOP (solid shape): 165.1,60.13 165.64,60.13 165.71,60.06 165.71,59.63 165.64,59.56 164.6,59.56 164.59,59.56 164.25,59.56 164.12,59.69 164.12,60.14 164.22,60.24 164.98,60.24
+PCH_VCCDSW3_3 on TOP (solid shape): 175.92,45.71 175.92,44.56 176.12,44.36 177.82,44.36 177.98,44.2 177.98,43.11 177.89,43.01 174.8,43.01 174.69,43.13 174.69,45.55 174.74,45.6 175.2,45.6 175.42,45.82 175.8,45.82
+PCH_VCCDSW3_3 on TOP (solid shape): 164.98,59.26 165.7,59.26 166.17,58.79 166.17,57.76 165.99,57.58 165.9,57.58 165.73,57.41 165.42,57.41 165.03,57.8 165.03,57.98 165.05,58.01 165.06,58.06 165.06,58.09 165.06,58.37 165.42,58.37 165.42,58.32 165.43,58.27 165.44,58.22 165.47,58.17 165.5,58.13 165.53,58.1 165.57,58.07 165.62,58.05 165.66,58.03 165.71,58.02 165.76,58.02 165.81,58.03 165.86,58.05 165.9,58.07 165.94,58.1 165.98,58.13 166.01,58.17 166.03,58.22 166.05,58.27 166.06,58.32 166.06,58.37 166.05,58.42 166.03,58.46 166.01,58.51 165.98,58.55 165.94,58.58 165.9,58.61 165.86,58.64 165.81,58.65 165.76,58.66 165.71,58.66 165.66,58.65 165.62,58.64 165.57,58.61 165.53,58.58 165.5,58.55 165.47,58.51 165.44,58.46 165.43,58.42 165.42,58.37 165.06,58.37 165.06,58.56 164.86,58.76 164.86,58.76 164.8,58.81 163.95,58.81 163.92,58.85 163.92,59.33 164,59.42 164.82,59.42
+PCH_VCCDSW3_3 on IN2 (solid shape): outline of 480 points within 165.36,54.11 169.62,58.19
+PWR_SRC on TOP (solid shape): 60.31,24.36 60.31,23.9 60.83,23.9 60.83,23.61 60.31,23.61 60.31,23.1 60.83,23.1 60.83,22.81 60.31,22.81 60.31,22.23 60.11,22.02 58.99,22.02 58.8,22.21 58.8,24.18 58.99,24.37 59,24.37 59.13,24.51 60.16,24.51
+PWR_SRC on TOP (solid shape): 85.24,75.6 85.24,69.41 83.87,69.41 83.51,69.05 83.87,68.69 85.24,68.69 85.24,68.21 86.12,67.32 86.12,66.4 80.59,66.4 80.23,66.76 80.23,75.59 80.52,75.88 84.95,75.88
+PWR_SRC on BOTTOM (solid shape): 85.67,75.67 85.67,68.38 87.4,66.65 87.4,62.39 87.26,62.26 86.15,62.26 86.06,62.35 86.06,65.98 85.65,66.4 80.59,66.4 80.23,66.76 80.23,75.77 80.69,76.24 85.1,76.24
+PWR_SRC on BOTTOM (solid shape): 94.84,53.43 94.84,52.75 95.39,52.75 95.39,52.3 94.84,52.3 94.84,51.55 95.39,51.55 95.39,51.1 94.84,51.1 94.84,50.32 94.48,49.96 91.17,49.96 90.84,50.29 90.84,52.9 91.76,53.83 94.45,53.83
+PWR_SRC on BOTTOM (solid shape): 127.77,92.96 127.77,88.62 127.47,88.32 124.35,88.32 124.06,88.61 124.06,91.43 118.51,96.99 113.88,96.99 113.31,96.42 113.31,96.17 112.8,95.66 111.51,95.66 111.35,95.82 111.35,96.37 111.66,96.68 111.66,98.61 112.24,99.2 121.54,99.2
+PWR_SRC on BOTTOM (solid shape): 209.26,64.55 209.76,64.55 209.76,65.09 210.06,65.09 210.06,64.55 215.07,64.55 215.11,64.51 215.11,63.89 215.63,63.89 215.63,63.39 215.11,63.39 215.11,62.69 215.63,62.69 215.63,62.19 215.11,62.19 215.11,61.56 215.05,61.51 210.45,61.51 210.02,61.94 209.45,61.94 209.25,62.13 208.72,62.13 208.52,62.33 208.52,63.21 208.58,63.28 208.58,63.59 208.4,63.77 208.4,64.46 208.49,64.55 208.96,64.55 208.96,65.09 209.26,65.09
+PWR_SRC on VCC: 55.56,22.2 55.56,27.94 73.62,46 73.62,54.4 76.53,57.31 76.53,60.49 80.2,64.16 80.2,68.31 81.15,69.26 81.15,76.77 84.75,80.37 93.51,80.37 99.23,86.08 122.98,86.08 128.06,91.16 159.3,91.16 161.08,92.94 182.71,92.94 186.38,89.27 187.41,89.27 187.63,89.05 187.63,87.37 188.47,86.52 189.99,86.52 190.46,86.99 190.46,88.83 190.88,89.26 193.03,89.26 195.63,86.66 195.63,81.86 201.6,75.89 201.6,68.27 202.89,66.97 212.03,66.97 212.77,66.23 212.77,62.13 211.14,60.5 197.64,60.5 193.72,64.41 193.72,75.02 190.05,78.69 190.05,79.84 186.98,82.91 181.52,82.91 178.91,85.52 165.8,85.52 160.22,79.93 106.11,79.93 95.44,69.25 95.44,46.6 90.99,42.15 90.99,38.37 88.79,36.17 86.48,36.17 83.74,33.43 73.53,33.43 67.71,27.61 61.22,27.61 60.26,26.65 60.26,22.52 59.94,22.2
+PWR_SRC_AC on BOTTOM (solid shape): 68.16,85.85 68.51,85.5 68.87,85.85 68.87,87.22 68.91,87.26 70.49,87.26 70.89,86.86 70.89,80.34 69.87,79.31 70.24,78.93 69.92,78.62 69.55,78.99 69.02,78.46 69.39,78.08 69.07,77.77 68.7,78.14 68.07,77.51 67.34,77.51 65.56,79.29 65.56,80.08 67.02,81.54 67.02,86.85 67.43,87.26 68.16,87.26
+RTC_CELL on TOP (solid shape): 162.82,59.1 162.91,59.01 162.91,58.69 163.6,58.69 163.63,58.68 163.65,58.68 163.73,58.68 163.73,58.6 163.71,58.59 163.89,58.04 164.2,58.52 164.2,58.62 164.29,58.68 164.73,58.68 164.93,58.47 164.93,58.09 164.89,58 164.79,57.99 164.37,57.77 164.65,57.38 164.67,57.38 164.72,57.33 164.65,57.26 164.19,57.26 163.97,57.37 163.74,57.28 163.72,57.26 163.7,57.26 163.43,57 163.43,56.82 163.31,56.69 162.71,56.69 162.63,56.77 162.63,57.72 162.45,57.9 162.43,57.99 162.48,58.06 162.65,58.42 162.33,58.66 162.03,58.4 162.22,58.06 162.25,58.04 162.25,57.96 162.1,57.96 162.09,57.95 161.89,57.95 161.8,58.05 161.8,58.22 161.8,58.52 161.8,58.6 162.06,58.86 162.06,59.35 162.14,59.44 162.82,59.44
+RTC_CELL_VBAT on BOTTOM (solid shape): 263.92,44.31 263.92,43.46 263.79,43.33 261.93,43.33 261.83,43.43 261.83,43.87 262.5,43.87 262.5,43.82 262.52,43.76 262.53,43.71 262.56,43.67 262.59,43.63 262.63,43.59 262.68,43.56 262.73,43.54 262.78,43.52 262.83,43.51 262.88,43.51 262.94,43.52 262.99,43.54 263.03,43.56 263.08,43.59 263.12,43.63 263.15,43.67 263.18,43.71 263.2,43.76 263.21,43.82 263.21,43.87 263.21,43.92 263.2,43.97 263.18,44.02 263.15,44.07 263.12,44.11 263.08,44.15 263.03,44.18 262.99,44.2 262.94,44.22 262.88,44.23 262.83,44.23 262.78,44.22 262.73,44.2 262.68,44.18 262.63,44.15 262.59,44.11 262.56,44.07 262.53,44.02 262.52,43.97 262.5,43.92 262.5,43.87 261.83,43.87 261.83,44.47 261.95,44.59 263.63,44.59
+SD_IO_LDO on TOP (solid shape): 288.21,28.75 288.21,28.53 288.53,28.21 288.53,27.92 288.45,27.85 288.02,27.85 287.32,28.55 287.32,28.75 287.38,28.81 288.15,28.81
+SDC_IN on TOP (solid shape): 72.67,94.07 72.67,91.78 72.46,91.58 67.56,91.58 67.46,91.68 67.46,94.11 67.6,94.25 72.49,94.25
+SDC_IN on BOTTOM (solid shape): 72.84,94.03 72.84,90.55 70.52,88.23 68.87,88.23 68.87,89.61 68.51,89.97 68.16,89.61 68.16,88.23 67.09,88.23 66.9,88.41 66.9,94.12 67.15,94.37 72.51,94.37
+USB_LEFT_PWR on TOP (solid shape): 90.02,95.95 90.02,92.03 89.69,91.71 88.99,90.87 88.56,89.87 86.83,88.14 85.47,88.14 85.16,87.83 85.16,87.21 84.79,86.83 83.34,86.83 83.13,87.04 83.13,87.05 82.89,87.3 82.89,88.77 83.95,89.84 84.13,89.84 84.16,89.83 84.35,89.82 84.52,89.91 84.59,89.94 84.66,89.91 85.22,89.99 85.01,90.51 84.94,90.58 84.97,90.68 86.92,92.63 86.92,93.67 86.97,93.73 87.2,93.73 87.43,93.96 87.43,94.4 87.23,94.6 87.23,95.85 87.82,96.43 89.53,96.43
+USB_LEFT_PWR on BOTTOM (solid shape): 84.96,88.08 84.96,87.36 85.21,87.12 85.5,87.12 85.69,86.93 85.74,86.93 86.14,86.53 86.42,86.53 87.02,85.94 87.02,85.53 87.34,85.2 87.46,85.2 88.14,84.53 88.14,82.85 88.01,82.71 86.48,82.71 86.34,82.85 86.34,84.1 84.7,85.75 83.29,85.75 82.98,86.06 82.98,88.11 83.18,88.3 84.74,88.3
+USB_RIGHT_PWR on BOTTOM (solid shape): outline of 119 points within 245.7,90.78 251.51,96.46
+V_DDR_REF on BOTTOM (solid shape): 71.32,10.98 71.32,10.48 71.21,10.38 70.2,10.38 69.9,10.08 68.77,10.08 68.71,10.14 68.71,10.23 68.78,10.29 69.54,10.29 70.28,11.03 71.26,11.03
+VCHGR on TOP (solid shape): 95.39,77.43 95.39,74.03 95.06,73.7 89.38,73.7 89.03,73.36 89.03,69.25 89.33,68.95 92.89,68.95 93.02,68.82 93.02,64.12 92.58,63.67 88.37,63.67 87.66,64.38 87.66,66.75 86.23,68.18 86.23,68.69 87.63,68.69 87.98,69.05 87.63,69.41 86.23,69.41 86.23,77.08 86.81,77.66 95.16,77.66
+VCHGR on BOTTOM (solid shape): 95.39,77.43 95.39,74.03 95.06,73.7 89.38,73.7 89.03,73.36 89.03,69.25 89.33,68.95 92.89,68.95 93.02,68.82 93.02,64.12 92.58,63.67 88.05,63.67 87.66,64.06 87.66,66.99 86.23,68.42 86.23,77.1 86.79,77.66 95.16,77.66
+VDISPLAY_VCC on BOTTOM (solid shape): 292.44,71.58 292.44,71.09 292.21,70.87 291.91,70.87 291.18,71.59 290,71.59 289.87,71.72 289.87,71.92 289.99,72.03 291.98,72.03
+VHDMI_VCC on BOTTOM (solid shape): 219.96,98.65 219.96,97.7 221.42,96.24 222.86,96.24 223.12,95.97 223.12,94.55 222.81,94.23 219.66,94.23 219.54,94.35 219.54,95.68 218.79,96.44 218.79,98.75 219.04,99 219.61,99
+VLDOIN_1.35V on TOP (solid shape): 71.82,15.98 72.32,15.98 72.32,16.55 72.9,16.55 73.02,16.42 73.02,15.15 72.83,14.96 71.24,14.96 71.12,15.09 71.12,16.42 71.24,16.55 71.82,16.55
+VLDOIN_1.35V on BOTTOM (solid shape): 73.15,16.17 73.15,15.15 72.96,14.96 70.48,14.96 69.78,14.26 69.78,13.31 69.21,12.74 68.31,12.74 68.12,12.54 68.12,11.74 68.07,11.69 67.96,11.69 67.91,11.74 67.91,12.66 67.91,12.66 67.91,14.16 70.1,16.36 72.96,16.36
-DCIN_JACK on TOP (solid shape): 62.88,94.66 62.88,90.86 62.33,90.31 53.36,90.31 53.07,90.6 53.07,94.8 53.25,94.98 62.56,94.98
-DCIN_JACK on BOTTOM (solid shape): 62.88,94.67 62.88,93.59 62.89,93.57 63.41,93.57 63.41,93.09 62.88,93.09 62.88,92.38 63.41,92.38 63.41,91.91 62.86,91.91 62.86,90.89 62.29,90.32 53.33,90.32 53.07,90.58 53.07,94.79 53.25,94.98 62.57,94.98
BOOT_1.35V on BOTTOM (solid shape): 67.71,14.57 67.71,11.75 67.66,11.7 67.56,11.7 67.51,11.75 67.51,12.67 67.23,12.95 67.23,13.37 66.76,13.84 66.76,14.58 66.81,14.63 67.66,14.63
BOOT_1.35V_C on BOTTOM (solid shape): 67.73,15.99 67.73,15.34 67.65,15.26 65.52,15.26 65.44,15.34 65.44,15.98 65.5,16.04 67.68,16.04
BQ24770_REGN on BOTTOM (solid shape): 78.02,82.8 78.02,82.71 77.96,82.65 77.15,82.65 77.1,82.6 76.79,82.6 76.32,82.13 75.62,82.13 75.61,82.12 75.6,82.12 75.29,81.82 75.29,81.08 75.1,80.89 74.27,80.89 74.21,80.95 74.21,81.77 74.34,81.89 74.91,81.89 75.06,82.04 75.06,82.34 75.5,82.78 76.49,82.78 76.52,82.8 77,82.8 77.06,82.87 77.96,82.87
BST_3V on TOP (solid shape): 222.3,50.03 222.22,49.96 220.65,49.96 220.49,49.8 219.33,49.8 219.26,49.87 219.26,49.96 219.33,50.02 220.27,50.02 221.28,51.04 222.3,51.04
BST_5V on TOP (solid shape): 216.3,50.02 217.23,50.02 217.29,49.96 217.29,49.85 217.24,49.8 216.07,49.8 215.92,49.96 215.26,49.96 215.08,50.13 214.42,50.13 214.42,51.04 215.29,51.04
BST_+V1.05SP on TOP (solid shape): 205.76,62.73 206.05,62.73 206.16,62.62 206.16,62.38 205.87,62.09 204.38,62.09 204.3,62.17 204.3,63.03 204.35,63.08 205.41,63.08
BST_+V1.05SP on BOTTOM (solid shape): 205.73,62.74 206.03,62.74 206.17,62.6 206.17,62.34 206.06,62.23 205.65,62.23 205.55,62.12 205.07,62.12 204.99,62.21 204.99,62.8 205.2,63.01 205.46,63.01
CHAGER_SRC on TOP (solid shape): 69.8,75.45 69.8,66.13 69.63,65.96 69.53,65.96 69.53,65.96 67.85,65.96 67.69,66.12 67.69,74.4 67.79,74.51 68.23,74.51 69.22,75.5 69.75,75.5
CHAGER_SRC on BOTTOM (solid shape): outline of 119 points within 66.79,66.86 74.11,80.67
CHG_BTS on BOTTOM (solid shape): 78.02,83.2 78.02,83.12 77.96,83.06 77.05,83.06 76.92,82.93 76.46,82.93 76.44,82.91 75.41,82.91 74.94,82.43 74.94,82.17 74.89,82.12 74.28,82.12 74.23,82.18 74.23,83.07 74.38,83.23 74.47,83.23 76.31,83.23 76.34,83.26 77.96,83.26
CHG_BTS_C on BOTTOM (solid shape): 73.57,84.27 73.57,82.21 73.49,82.12 72.88,82.12 72.82,82.18 72.82,84.28 72.9,84.36 73.48,84.36
CHG_LGATE on TOP (solid shape): 74.6,76.18 74.6,75.14 74.44,74.98 73.61,74.98 73.45,75.14 73.45,76.23 73.59,76.38 74.41,76.38
CHG_LGATE on BOTTOM (solid shape): 78.02,82.41 78.02,82.3 77.96,82.24 77.17,82.24 76.74,81.82 76.74,81.48 76.16,80.9 75.68,80.9 75.51,81.08 75.51,81.84 75.67,82 76.41,82 76.88,82.47 76.95,82.47 77.96,82.47
CHG_LGATE on IN2 (solid shape): 75.21,76.7 75.21,76.47 74.32,75.58 73.77,75.58 73.43,75.92 73.43,76.18 74.51,77.26 74.65,77.26
CHG_LGATE on IN2 (solid shape): 76.26,81.75 76.26,80.09 76.08,79.91 75.36,79.91 75.18,80.09 75.18,81.75 75.44,82.02 75.99,82.02
CHG_SW on TOP (solid shape): 71.5,78.24 71.5,76.77 72.16,76.11 72.8,76.11 73.14,75.77 73.14,71.47 73.07,71.4 70.41,71.4 70.27,71.54 70.27,75.51 69.45,76.34 69.45,78.11 69.72,78.39 71.35,78.39
CHG_SW on BOTTOM (solid shape): 73.6,73.52 75.85,73.52 75.95,73.43 75.95,68.78 75.67,68.51 72.27,68.51 72.01,68.77 72.01,70.53 71.83,70.71 70.64,70.71 70.51,70.83 70.51,74.82 70.66,74.97 72.16,74.97
CHG_SW on BOTTOM (solid shape): 77.13,84.07 77.96,84.07 78.02,84.01 78.02,83.91 77.96,83.84 76.64,83.84 76.49,83.99 75.17,83.99 74.95,83.77 74.95,83.42 74.91,83.38 74.29,83.38 74.23,83.44 74.23,84.4 74.39,84.56 76.64,84.56
CHG_SW on IN1 (solid shape): 71.92,75.63 71.92,74.55 71.77,74.4 70.76,74.4 70.6,74.56 70.6,75.56 70.85,75.8 71.74,75.8
CHG_SW on IN1 (solid shape): 76.25,84.61 76.25,84.18 76.06,83.99 75.06,83.99 74.95,83.88 74.95,83.56 74.83,83.44 73.9,83.44 73.72,83.62 73.72,84.43 73.99,84.7 76.15,84.7
CHG_UGATE on TOP (solid shape): 68.94,76.1 68.94,75.65 68.27,74.97 67.97,74.97 67.79,75.15 67.79,76.24 68.05,76.51 68.54,76.51
CHG_UGATE on BOTTOM (solid shape): 76.57,83.72 77.1,83.72 77.15,83.67 77.96,83.67 78.02,83.61 78.02,83.51 77.97,83.46 77.14,83.46 77.1,83.41 76.31,83.41 76.26,83.36 75.23,83.36 75.1,83.48 75.1,83.74 75.23,83.87 76.42,83.87
CHG_UGATE on IN2 (solid shape): 69.6,77.22 69.6,77.13 69.06,76.59 69.06,75.67 68.89,75.51 67.97,75.51 67.89,75.59 67.89,76.93 68.79,77.83 68.99,77.83
CHG_UGATE on IN2 (solid shape): 76.25,83.74 76.25,83.36 76.12,83.23 75.87,83.23 75.5,82.85 74.05,82.85 73.71,83.19 73.71,83.62 73.95,83.87 76.12,83.87
CORE_BOOT on BOTTOM (solid shape): 99.54,57.95 99.54,57.53 99.77,57.3 100.59,57.3 100.66,57.23 100.66,57.14 100.6,57.09 99.42,57.09 99.06,57.44 99.06,57.59 98.84,57.81 98.39,57.81 98.35,57.86 98.35,58.41 98.37,58.44 99.05,58.44
CORE_BOOT_C on BOTTOM (solid shape): 97.96,58.42 97.96,57.83 97.56,57.43 97.55,57.42 97.55,56.65 97.52,56.62 96.88,56.62 96.87,56.64 96.87,57.49 97.41,58.04 97.41,58.42 97.45,58.46 97.93,58.46
CORE_BOOT_R on BOTTOM (solid shape): 98.92,57.36 99.33,56.95 99.68,56.95 99.74,56.89 100.6,56.89 100.66,56.83 100.66,56.74 100.6,56.69 98.98,56.69 98.92,56.62 98.28,56.62 98.28,57.51 98.92,57.51
CORE_SNUB on BOTTOM (solid shape): 104.76,49.58 101.96,49.58 101.84,49.7 101.84,50.4 102.85,50.4 103.04,50.59 104.76,50.59
CORE_SW on BOTTOM (solid shape): 104.89,56.45 105.11,56.45 109.67,51.89 109.67,50.72 107.34,50.72 107.34,49.96 109.67,49.96 109.67,48.39 109.39,48.11 105.46,48.11 105.14,48.43 105.14,50.72 104.82,51.04 103.55,51.04 103.09,51.5 103.09,53.25 103.26,53.42 103.26,56.52 104.81,56.52
DH_1.35V on TOP (solid shape): 67.62,14.07 67.62,13.63 67.31,13.31 67.31,13.12 67.05,12.86 66.8,12.86 66.23,13.44 66.23,13.63 67.05,14.45 67.24,14.45
DH_1.35V on TOP (solid shape): 69.66,22.2 69.66,20.53 69.52,20.39 68.78,20.39 68.64,20.53 68.64,21.37 68.47,21.55 68.47,22.41 68.58,22.52 68.6,22.53 69.32,22.53
DH_1.35V on BOTTOM (solid shape): 67.1,13.25 67.1,12.87 67.32,12.66 67.32,11.75 67.26,11.69 67.16,11.69 67.11,11.74 67.11,12.51 66.9,12.72 66.81,12.72 66.28,13.25 66.28,13.64 66.39,13.74 66.61,13.74
DL_1.35V on TOP (solid shape): 65.47,18.58 65.47,17.75 65.34,17.63 64.45,17.63 64.32,17.75 64.32,18.58 64.45,18.71 65.34,18.71
DL_1.35V on BOTTOM (solid shape): 66.33,11.86 66.33,11.64 66.51,11.45 66.51,11.34 66.45,11.28 65.68,11.28 65.62,11.34 65.62,11.45 65.65,11.48 65.65,11.77 65.06,12.36 65.06,12.51 65.17,12.63 65.56,12.63
DL_1.35V on IN2 (solid shape): 65.47,18.01 65.47,16.87 65.21,16.61 65.21,13.09 66.19,12.12 66.19,11.87 65.98,11.66 65.75,11.66 65.53,11.88 65.5,11.91 64.07,13.34 64.07,16.99 64.2,17.12 64.2,17.88 64.45,18.14 65.34,18.14
INT_SPK_L+ on BOTTOM (solid shape): 23.48,7.29 26.1,7.29 26.32,7.06 26.32,6.76 26.05,6.48 23.2,6.48 22.84,6.83 22.84,7.39 22.87,7.42 23.35,7.42
INT_SPK_L+ on IN1 (solid shape): 32.91,11.66 33.19,11.66 33.4,11.45 33.4,10.12 32.98,9.7 32.78,9.7 32.37,10.12 32.37,10.23 32.66,10.52 32.66,11.47 32.85,11.66
INT_SPK_L- on BOTTOM (solid shape): 25.4,9.02 25.4,8.61 25.19,8.41 23.42,8.41 23.26,8.25 22.83,8.25 22.78,8.31 22.78,8.89 23.06,9.17 25.25,9.17
INT_SPK_L- on IN1 (solid shape): 33.72,12.67 33.72,12.24 33.46,11.98 32.82,11.98 32.4,11.56 32.4,10.96 32.29,10.86 31.73,10.86 31.53,11.06 31.53,11.93 32.02,12.42 32.51,12.42 32.89,12.8 33.59,12.8
INT_SPK_R+ on BOTTOM (solid shape): 26.17,10.13 26.17,9.75 25.97,9.55 22.87,9.55 22.79,9.63 22.79,10.26 22.82,10.29 26.02,10.29
INT_SPK_R+ on IN2 (solid shape): 35.22,11.53 35.22,9.94 34.8,9.52 34.37,9.52 34.08,9.81 34.08,9.99 34.29,10.19 34.29,11.6 34.42,11.72 35.02,11.72
INT_SPK_R- on BOTTOM (solid shape): 25.46,11.96 25.46,11.56 25.31,11.4 23.53,11.4 23.33,11.2 22.9,11.2 22.84,11.25 22.84,11.84 23.12,12.12 25.31,12.12
INT_SPK_R- on IN2 (solid shape): 34.13,11.56 34.13,10.75 33.81,10.43 33.53,10.43 33.13,10.84 33.13,11 33.36,11.23 33.36,11.54 33.54,11.72 33.97,11.72
INT_SPKR_L+ on TOP (solid shape): 4.59,13.07 4.59,11.52 3.54,10.46 2.7,10.46 2.58,10.59 2.58,11.02 2.7,11.15 3.21,11.15 3.8,11.74 3.8,13.06 3.9,13.16 4.51,13.16
INT_SPKR_L+ on BOTTOM (solid shape): 3.36,10.96 3.36,8.42 3.11,8.17 2.47,8.17 2.22,8.42 2.22,10.96 2.41,11.15 3.17,11.15
INT_SPKR_L+ on BOTTOM (solid shape): 22.46,7.44 22.46,6.78 22.39,6.71 19.92,6.71 19.77,6.86 19.77,7.33 19.94,7.49 22.41,7.49
INT_SPKR_L- on TOP (solid shape): 5.84,13.06 5.84,10.7 5.59,10.45 4.63,10.45 4.51,10.58 4.51,10.87 4.66,11.02 4.89,11.02 5.05,11.19 5.05,13.06 5.14,13.16 5.74,13.16
INT_SPKR_L- on BOTTOM (solid shape): 22.46,8.81 22.46,8.2 22.39,8.13 20.81,8.13 20.66,8.28 20.66,8.82 20.79,8.94 22.34,8.94
INT_SPKR_L- on BOTTOM (solid shape): 5.33,10.96 5.33,8.36 5.14,8.17 4.51,8.17 4.25,8.42 4.25,10.96 4.44,11.15 5.14,11.15
INT_SPKR_R+ on TOP (solid shape): 7.1,13.06 7.1,11.15 7.24,11.01 7.24,10.64 7.05,10.45 6.6,10.45 6.31,10.74 6.31,13.08 6.39,13.16 7,13.16
INT_SPKR_R+ on BOTTOM (solid shape): 7.36,10.96 7.36,8.42 7.11,8.17 6.47,8.17 6.28,8.36 6.28,10.96 6.47,11.15 7.17,11.15
INT_SPKR_R+ on BOTTOM (solid shape): 22.46,10.26 22.46,9.73 22.34,9.6 19.9,9.6 19.77,9.73 19.77,10.31 19.87,10.41 22.31,10.41
INT_SPKR_R- on TOP (solid shape): 8.35,13.06 8.35,11.79 9.14,10.99 9.14,10.64 8.95,10.45 8.47,10.45 7.55,11.36 7.55,13.06 7.66,13.16 8.25,13.16
INT_SPKR_R- on BOTTOM (solid shape): 22.46,11.71 22.46,11.23 22.32,11.1 20.84,11.1 20.71,11.23 20.71,11.68 20.89,11.87 22.31,11.87
INT_SPKR_R- on BOTTOM (solid shape): 9.33,10.96 9.33,8.36 9.14,8.17 8.44,8.17 8.25,8.36 8.25,10.96 8.44,11.15 9.14,11.15
LG_3V on TOP (solid shape): 222.94,53.95 222.94,53.65 222.68,53.39 222.04,53.39 219.15,50.49 219.04,50.49 218.98,50.55 218.98,51.45 221.58,54.06 222.83,54.06
LG_5V on TOP (solid shape): 217.18,51.86 217.59,51.45 217.59,50.55 217.54,50.5 217.37,50.5 216.92,50.95 216.91,50.95 216.4,51.46 216.4,51.76 216.51,51.86 217.15,51.86
LG_5V on TOP (solid shape): 216.9,57.07 216.9,56.01 216.59,55.7 215.58,55.7 215.49,55.79 215.49,56.01 215.7,56.22 215.7,56.93 216.02,57.25 216.72,57.25
LG_5V on IN1 (solid shape): 216.9,57.07 216.9,56.2 216.39,55.69 216.39,55.54 216.33,55.48 215.44,55.48 215.38,55.54 215.38,56.67 215.96,57.25 216.72,57.25
LG_5V on IN1 (solid shape): 216.38,52.51 217.28,51.61 217.28,51.04 217.15,50.91 216.96,50.91 215.36,52.51 215.36,53.31 215.38,53.32 216.38,53.32
NB_PSID on TOP (solid shape): 60.85,101.64 60.85,98.75 60.32,98.22 53.08,98.22 52.84,98.46 52.84,101.02 53.44,101.67 53.74,102.5 53.75,102.54 54.91,102.54 54.92,102.54 56.8,102.09 58.65,102.64 59.85,102.64
NB_PSID on BOTTOM (solid shape): 60.86,101.63 60.86,98.75 60.32,98.22 53.08,98.22 52.85,98.45 52.85,101.03 53.45,101.7 53.75,102.55 53.76,102.59 54.82,102.59 54.83,102.59 56.75,102.09 58.65,102.64 59.85,102.64
Net_6 on BOTTOM (solid shape): 64.86,16.51 64.86,11.65 64.82,11.61 64.59,11.61 64.59,11.61 64.44,11.61 64.4,11.56 64.4,10.14 64.27,10.01 61.87,10.01 61.75,10.14 61.75,11.25 61.81,11.32 63.19,11.32 63.32,11.46 63.32,15.25 63.14,15.43 61.87,15.43 61.78,15.52 61.78,16.58 61.9,16.69 63.83,16.69 64.68,16.69
Net_7 on BOTTOM (solid shape): 46.11,16.54 46.11,15.55 46.11,15.55 46.11,10.34 46.01,10.24 43.14,10.24 42.98,10.39 42.98,16.52 43.22,16.76 45.88,16.76
PBAT_PRES#_C on BOTTOM (solid shape): 53.65,17.5 53.65,13.94 53.96,13.63 53.96,12.95 53.77,12.76 52.91,12.76 52.77,12.9 52.77,14.51 52.77,17.52 53.02,17.77 53.38,17.77
PBAT_SMBCLK_C on BOTTOM (solid shape): 56.62,17.51 56.62,15.72 56.39,15.49 56.01,15.49 55.77,15.73 55.77,17.5 56.03,17.77 56.37,17.77
PBAT_SMBDAT_C on BOTTOM (solid shape): 55.12,17.51 55.12,15.69 54.91,15.49 54.49,15.49 54.26,15.72 54.26,17.49 54.53,17.77 54.86,17.77
PBATT+_C on TOP (solid shape): 62.61,16.77 62.61,12.07 62.49,11.95 62.49,11.48 62.61,11.36 62.61,9.78 61.89,9.07 61.89,8.12 61.8,8.04 59.08,8.04 58.91,8.2 58.91,8.2 58.76,8.36 58.76,16.74 58.98,16.96 62.42,16.96
PBATT+_C on BOTTOM (solid shape): 61.15,17.48 61.15,9.61 60.88,9.35 58.62,9.35 58.36,9.6 58.36,14.54 57.27,15.63 57.27,17.51 57.53,17.77 60.86,17.77
